<?xml version="1.0" encoding="utf-8" standalone="no"?>
<device schemaVersion="1.1">
  <name>STM32G471VET7</name>
  <version>1.0</version>
  <description>STM32G471CCT6,STM32G471CCU3,STM32G471CCU6,STM32G471CCU7,STM32G471CET3,STM32G471CET6,STM32G471CET7,STM32G471CEU3,STM32G471CEU6,STM32G471CEU7,STM32G471MCT6,STM32G471MET3,STM32G471MET6,STM32G471MET7,STM32G471MEY6,STM32G471QCT6,STM32G471QET6,STM32G471RCT6,STM32G471RET3,STM32G471RET6,STM32G471RET7,STM32G471VCH6,STM32G471VCI6,STM32G471VCT6,STM32G471VEH3,STM32G471VEH6,STM32G471VEH7,STM32G471VEI3,STM32G471VEI6,STM32G471VEI7,STM32G471VET3,STM32G471VET6,STM32G471VET7</description>
  <addressUnitBits>8</addressUnitBits>
  <width>32</width>
  <size>0x20</size>
  <resetValue>0</resetValue>
  <resetMask>0xFFFFFFFF</resetMask>
  <peripherals>
    <peripheral>
      <name>TIM2</name>
      <baseAddress>0x40000000</baseAddress>
      <registers>
        <register>
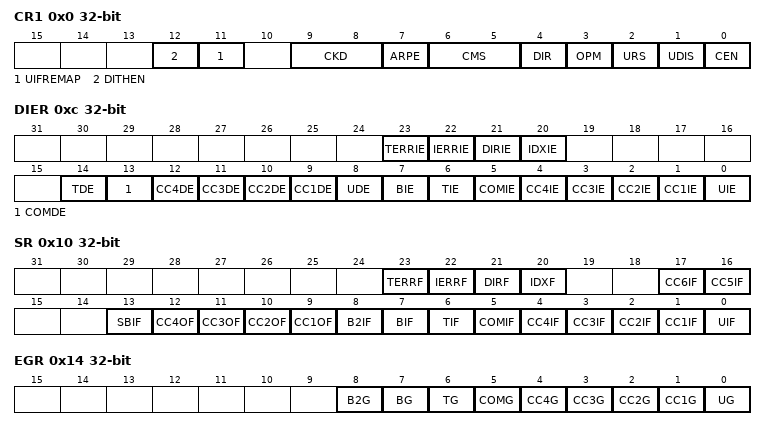
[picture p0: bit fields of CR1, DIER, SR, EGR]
          <name>CR1</name>
          <addressOffset>0x0</addressOffset>
          <size>0x20</size>
          <fields>
            <field>
              <name>CEN</name>
              <bitOffset>0</bitOffset>
              <bitWidth>1</bitWidth>
            </field>
            <field>
              <name>UDIS</name>
              <bitOffset>1</bitOffset>
              <bitWidth>1</bitWidth>
            </field>
            <field>
              <name>URS</name>
              <bitOffset>2</bitOffset>
              <bitWidth>1</bitWidth>
            </field>
            <field>
              <name>OPM</name>
              <bitOffset>3</bitOffset>
              <bitWidth>1</bitWidth>
            </field>
            <field>
              <name>DIR</name>
              <bitOffset>4</bitOffset>
              <bitWidth>1</bitWidth>
            </field>
            <field>
              <name>CMS</name>
              <bitOffset>5</bitOffset>
              <bitWidth>2</bitWidth>
            </field>
            <field>
              <name>ARPE</name>
              <bitOffset>7</bitOffset>
              <bitWidth>1</bitWidth>
            </field>
            <field>
              <name>CKD</name>
              <bitOffset>8</bitOffset>
              <bitWidth>2</bitWidth>
            </field>
            <field>
              <name>UIFREMAP</name>
              <bitOffset>11</bitOffset>
              <bitWidth>1</bitWidth>
            </field>
            <field>
              <name>DITHEN</name>
              <bitOffset>12</bitOffset>
              <bitWidth>1</bitWidth>
            </field>
          </fields>
        </register>
        <register>
          <name>CR2</name>
          <addressOffset>0x4</addressOffset>
          <size>0x20</size>
          <fields>
            <field>
              <name>CCPC</name>
              <bitOffset>0</bitOffset>
              <bitWidth>1</bitWidth>
            </field>
            <field>
              <name>CCUS</name>
              <bitOffset>2</bitOffset>
              <bitWidth>1</bitWidth>
            </field>
            <field>
              <name>CCDS</name>
              <bitOffset>3</bitOffset>
              <bitWidth>1</bitWidth>
            </field>
            <field>
              <name>MMS</name>
              <bitOffset>4</bitOffset>
              <bitWidth>22</bitWidth>
            </field>
            <field>
              <name>TI1S</name>
              <bitOffset>7</bitOffset>
              <bitWidth>1</bitWidth>
            </field>
            <field>
              <name>OIS1</name>
              <bitOffset>8</bitOffset>
              <bitWidth>1</bitWidth>
            </field>
            <field>
              <name>OIS1N</name>
              <bitOffset>9</bitOffset>
              <bitWidth>1</bitWidth>
            </field>
            <field>
              <name>OIS2</name>
              <bitOffset>10</bitOffset>
              <bitWidth>1</bitWidth>
            </field>
            <field>
              <name>OIS2N</name>
              <bitOffset>11</bitOffset>
              <bitWidth>1</bitWidth>
            </field>
            <field>
              <name>OIS3</name>
              <bitOffset>12</bitOffset>
              <bitWidth>1</bitWidth>
            </field>
            <field>
              <name>OIS3N</name>
              <bitOffset>13</bitOffset>
              <bitWidth>1</bitWidth>
            </field>
            <field>
              <name>OIS4</name>
              <bitOffset>14</bitOffset>
              <bitWidth>1</bitWidth>
            </field>
            <field>
              <name>OIS4N</name>
              <bitOffset>15</bitOffset>
              <bitWidth>1</bitWidth>
            </field>
            <field>
              <name>OIS5</name>
              <bitOffset>16</bitOffset>
              <bitWidth>1</bitWidth>
            </field>
            <field>
              <name>OIS6</name>
              <bitOffset>18</bitOffset>
              <bitWidth>1</bitWidth>
            </field>
            <field>
              <name>MMS2</name>
              <bitOffset>20</bitOffset>
              <bitWidth>4</bitWidth>
            </field>
          </fields>
        </register>
        <register>
          <name>SMCR</name>
          <addressOffset>0x8</addressOffset>
          <size>0x20</size>
          <fields>
            <field>
              <name>SMS</name>
              <bitOffset>0</bitOffset>
              <bitWidth>17</bitWidth>
            </field>
            <field>
              <name>OCCS</name>
              <bitOffset>3</bitOffset>
              <bitWidth>1</bitWidth>
            </field>
            <field>
              <name>TS</name>
              <bitOffset>4</bitOffset>
              <bitWidth>18</bitWidth>
            </field>
            <field>
              <name>MSM</name>
              <bitOffset>7</bitOffset>
              <bitWidth>1</bitWidth>
            </field>
            <field>
              <name>ETF</name>
              <bitOffset>8</bitOffset>
              <bitWidth>4</bitWidth>
            </field>
            <field>
              <name>ETPS</name>
              <bitOffset>12</bitOffset>
              <bitWidth>2</bitWidth>
            </field>
            <field>
              <name>ECE</name>
              <bitOffset>14</bitOffset>
              <bitWidth>1</bitWidth>
            </field>
            <field>
              <name>ETP</name>
              <bitOffset>15</bitOffset>
              <bitWidth>1</bitWidth>
            </field>
            <field>
              <name>SMSPE</name>
              <bitOffset>24</bitOffset>
              <bitWidth>1</bitWidth>
            </field>
            <field>
              <name>SMSPS</name>
              <bitOffset>25</bitOffset>
              <bitWidth>1</bitWidth>
            </field>
          </fields>
        </register>
        <register>
          <name>DIER</name>
          <addressOffset>0xc</addressOffset>
          <size>0x20</size>
          <fields>
            <field>
              <name>UIE</name>
              <bitOffset>0</bitOffset>
              <bitWidth>1</bitWidth>
            </field>
            <field>
              <name>CC1IE</name>
              <bitOffset>1</bitOffset>
              <bitWidth>1</bitWidth>
            </field>
            <field>
              <name>CC2IE</name>
              <bitOffset>2</bitOffset>
              <bitWidth>1</bitWidth>
            </field>
            <field>
              <name>CC3IE</name>
              <bitOffset>3</bitOffset>
              <bitWidth>1</bitWidth>
            </field>
            <field>
              <name>CC4IE</name>
              <bitOffset>4</bitOffset>
              <bitWidth>1</bitWidth>
            </field>
            <field>
              <name>COMIE</name>
              <bitOffset>5</bitOffset>
              <bitWidth>1</bitWidth>
            </field>
            <field>
              <name>TIE</name>
              <bitOffset>6</bitOffset>
              <bitWidth>1</bitWidth>
            </field>
            <field>
              <name>BIE</name>
              <bitOffset>7</bitOffset>
              <bitWidth>1</bitWidth>
            </field>
            <field>
              <name>UDE</name>
              <bitOffset>8</bitOffset>
              <bitWidth>1</bitWidth>
            </field>
            <field>
              <name>CC1DE</name>
              <bitOffset>9</bitOffset>
              <bitWidth>1</bitWidth>
            </field>
            <field>
              <name>CC2DE</name>
              <bitOffset>10</bitOffset>
              <bitWidth>1</bitWidth>
            </field>
            <field>
              <name>CC3DE</name>
              <bitOffset>11</bitOffset>
              <bitWidth>1</bitWidth>
            </field>
            <field>
              <name>CC4DE</name>
              <bitOffset>12</bitOffset>
              <bitWidth>1</bitWidth>
            </field>
            <field>
              <name>COMDE</name>
              <bitOffset>13</bitOffset>
              <bitWidth>1</bitWidth>
            </field>
            <field>
              <name>TDE</name>
              <bitOffset>14</bitOffset>
              <bitWidth>1</bitWidth>
            </field>
            <field>
              <name>IDXIE</name>
              <bitOffset>20</bitOffset>
              <bitWidth>1</bitWidth>
            </field>
            <field>
              <name>DIRIE</name>
              <bitOffset>21</bitOffset>
              <bitWidth>1</bitWidth>
            </field>
            <field>
              <name>IERRIE</name>
              <bitOffset>22</bitOffset>
              <bitWidth>1</bitWidth>
            </field>
            <field>
              <name>TERRIE</name>
              <bitOffset>23</bitOffset>
              <bitWidth>1</bitWidth>
            </field>
          </fields>
        </register>
        <register>
          <name>SR</name>
          <addressOffset>0x10</addressOffset>
          <size>0x20</size>
          <fields>
            <field>
              <name>UIF</name>
              <bitOffset>0</bitOffset>
              <bitWidth>1</bitWidth>
            </field>
            <field>
              <name>CC1IF</name>
              <bitOffset>1</bitOffset>
              <bitWidth>1</bitWidth>
            </field>
            <field>
              <name>CC2IF</name>
              <bitOffset>2</bitOffset>
              <bitWidth>1</bitWidth>
            </field>
            <field>
              <name>CC3IF</name>
              <bitOffset>3</bitOffset>
              <bitWidth>1</bitWidth>
            </field>
            <field>
              <name>CC4IF</name>
              <bitOffset>4</bitOffset>
              <bitWidth>1</bitWidth>
            </field>
            <field>
              <name>COMIF</name>
              <bitOffset>5</bitOffset>
              <bitWidth>1</bitWidth>
            </field>
            <field>
              <name>TIF</name>
              <bitOffset>6</bitOffset>
              <bitWidth>1</bitWidth>
            </field>
            <field>
              <name>BIF</name>
              <bitOffset>7</bitOffset>
              <bitWidth>1</bitWidth>
            </field>
            <field>
              <name>B2IF</name>
              <bitOffset>8</bitOffset>
              <bitWidth>1</bitWidth>
            </field>
            <field>
              <name>CC1OF</name>
              <bitOffset>9</bitOffset>
              <bitWidth>1</bitWidth>
            </field>
            <field>
              <name>CC2OF</name>
              <bitOffset>10</bitOffset>
              <bitWidth>1</bitWidth>
            </field>
            <field>
              <name>CC3OF</name>
              <bitOffset>11</bitOffset>
              <bitWidth>1</bitWidth>
            </field>
            <field>
              <name>CC4OF</name>
              <bitOffset>12</bitOffset>
              <bitWidth>1</bitWidth>
            </field>
            <field>
              <name>SBIF</name>
              <bitOffset>13</bitOffset>
              <bitWidth>1</bitWidth>
            </field>
            <field>
              <name>CC5IF</name>
              <bitOffset>16</bitOffset>
              <bitWidth>1</bitWidth>
            </field>
            <field>
              <name>CC6IF</name>
              <bitOffset>17</bitOffset>
              <bitWidth>1</bitWidth>
            </field>
            <field>
              <name>IDXF</name>
              <bitOffset>20</bitOffset>
              <bitWidth>1</bitWidth>
            </field>
            <field>
              <name>DIRF</name>
              <bitOffset>21</bitOffset>
              <bitWidth>1</bitWidth>
            </field>
            <field>
              <name>IERRF</name>
              <bitOffset>22</bitOffset>
              <bitWidth>1</bitWidth>
            </field>
            <field>
              <name>TERRF</name>
              <bitOffset>23</bitOffset>
              <bitWidth>1</bitWidth>
            </field>
          </fields>
        </register>
        <register>
          <name>EGR</name>
          <addressOffset>0x14</addressOffset>
          <size>0x20</size>
          <fields>
            <field>
              <name>UG</name>
              <bitOffset>0</bitOffset>
              <bitWidth>1</bitWidth>
            </field>
            <field>
              <name>CC1G</name>
              <bitOffset>1</bitOffset>
              <bitWidth>1</bitWidth>
            </field>
            <field>
              <name>CC2G</name>
              <bitOffset>2</bitOffset>
              <bitWidth>1</bitWidth>
            </field>
            <field>
              <name>CC3G</name>
              <bitOffset>3</bitOffset>
              <bitWidth>1</bitWidth>
            </field>
            <field>
              <name>CC4G</name>
              <bitOffset>4</bitOffset>
              <bitWidth>1</bitWidth>
            </field>
            <field>
              <name>COMG</name>
              <bitOffset>5</bitOffset>
              <bitWidth>1</bitWidth>
            </field>
            <field>
              <name>TG</name>
              <bitOffset>6</bitOffset>
              <bitWidth>1</bitWidth>
            </field>
            <field>
              <name>BG</name>
              <bitOffset>7</bitOffset>
              <bitWidth>1</bitWidth>
            </field>
            <field>
              <name>B2G</name>
              <bitOffset>8</bitOffset>
              <bitWidth>1</bitWidth>
            </field>
          </fields>
        </register>
        <register>
          <name>CCMR1</name>
          <addressOffset>0x18</addressOffset>
          <size>0x20</size>
          <fields>
            <field>
              <name>CC1S</name>
              <bitOffset>0</bitOffset>
              <bitWidth>2</bitWidth>
            </field>
            <field>
              <name>OC1FE</name>
              <bitOffset>2</bitOffset>
              <bitWidth>1</bitWidth>
            </field>
            <field>
              <name>OC1PE</name>
              <bitOffset>3</bitOffset>
              <bitWidth>1</bitWidth>
            </field>
            <field>
              <name>OC1M</name>
              <bitOffset>4</bitOffset>
              <bitWidth>13</bitWidth>
            </field>
            <field>
              <name>OC1CE</name>
              <bitOffset>7</bitOffset>
              <bitWidth>1</bitWidth>
            </field>
            <field>
              <name>CC2S</name>
              <bitOffset>8</bitOffset>
              <bitWidth>2</bitWidth>
            </field>
            <field>
              <name>OC2FE</name>
              <bitOffset>10</bitOffset>
              <bitWidth>1</bitWidth>
            </field>
            <field>
              <name>OC2PE</name>
              <bitOffset>11</bitOffset>
              <bitWidth>1</bitWidth>
            </field>
            <field>
              <name>OC2M</name>
              <bitOffset>12</bitOffset>
              <bitWidth>13</bitWidth>
            </field>
            <field>
              <name>OC2CE</name>
              <bitOffset>15</bitOffset>
              <bitWidth>1</bitWidth>
            </field>
          </fields>
        </register>
        <register>
          <name>CCMR2</name>
          <addressOffset>0x1c</addressOffset>
          <size>0x20</size>
          <fields>
            <field>
              <name>CC3S</name>
              <bitOffset>0</bitOffset>
              <bitWidth>2</bitWidth>
            </field>
            <field>
              <name>OC3FE</name>
              <bitOffset>2</bitOffset>
              <bitWidth>1</bitWidth>
            </field>
            <field>
              <name>OC3PE</name>
              <bitOffset>3</bitOffset>
              <bitWidth>1</bitWidth>
            </field>
            <field>
              <name>OC3M</name>
              <bitOffset>4</bitOffset>
              <bitWidth>13</bitWidth>
            </field>
            <field>
              <name>OC3CE</name>
              <bitOffset>7</bitOffset>
              <bitWidth>1</bitWidth>
            </field>
            <field>
              <name>CC4S</name>
              <bitOffset>8</bitOffset>
              <bitWidth>2</bitWidth>
            </field>
            <field>
              <name>OC4FE</name>
              <bitOffset>10</bitOffset>
              <bitWidth>1</bitWidth>
            </field>
            <field>
              <name>OC4PE</name>
              <bitOffset>11</bitOffset>
              <bitWidth>1</bitWidth>
            </field>
            <field>
              <name>OC4M</name>
              <bitOffset>12</bitOffset>
              <bitWidth>13</bitWidth>
            </field>
            <field>
              <name>OC4CE</name>
              <bitOffset>15</bitOffset>
              <bitWidth>1</bitWidth>
            </field>
          </fields>
        </register>
        <register>
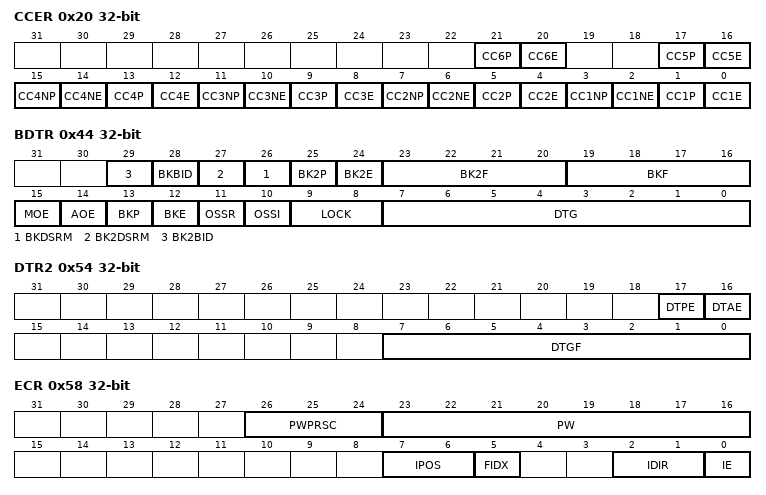
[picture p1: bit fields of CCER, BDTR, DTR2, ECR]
          <name>CCER</name>
          <addressOffset>0x20</addressOffset>
          <size>0x20</size>
          <fields>
            <field>
              <name>CC1E</name>
              <bitOffset>0</bitOffset>
              <bitWidth>1</bitWidth>
            </field>
            <field>
              <name>CC1P</name>
              <bitOffset>1</bitOffset>
              <bitWidth>1</bitWidth>
            </field>
            <field>
              <name>CC1NE</name>
              <bitOffset>2</bitOffset>
              <bitWidth>1</bitWidth>
            </field>
            <field>
              <name>CC1NP</name>
              <bitOffset>3</bitOffset>
              <bitWidth>1</bitWidth>
            </field>
            <field>
              <name>CC2E</name>
              <bitOffset>4</bitOffset>
              <bitWidth>1</bitWidth>
            </field>
            <field>
              <name>CC2P</name>
              <bitOffset>5</bitOffset>
              <bitWidth>1</bitWidth>
            </field>
            <field>
              <name>CC2NE</name>
              <bitOffset>6</bitOffset>
              <bitWidth>1</bitWidth>
            </field>
            <field>
              <name>CC2NP</name>
              <bitOffset>7</bitOffset>
              <bitWidth>1</bitWidth>
            </field>
            <field>
              <name>CC3E</name>
              <bitOffset>8</bitOffset>
              <bitWidth>1</bitWidth>
            </field>
            <field>
              <name>CC3P</name>
              <bitOffset>9</bitOffset>
              <bitWidth>1</bitWidth>
            </field>
            <field>
              <name>CC3NE</name>
              <bitOffset>10</bitOffset>
              <bitWidth>1</bitWidth>
            </field>
            <field>
              <name>CC3NP</name>
              <bitOffset>11</bitOffset>
              <bitWidth>1</bitWidth>
            </field>
            <field>
              <name>CC4E</name>
              <bitOffset>12</bitOffset>
              <bitWidth>1</bitWidth>
            </field>
            <field>
              <name>CC4P</name>
              <bitOffset>13</bitOffset>
              <bitWidth>1</bitWidth>
            </field>
            <field>
              <name>CC4NE</name>
              <bitOffset>14</bitOffset>
              <bitWidth>1</bitWidth>
            </field>
            <field>
              <name>CC4NP</name>
              <bitOffset>15</bitOffset>
              <bitWidth>1</bitWidth>
            </field>
            <field>
              <name>CC5E</name>
              <bitOffset>16</bitOffset>
              <bitWidth>1</bitWidth>
            </field>
            <field>
              <name>CC5P</name>
              <bitOffset>17</bitOffset>
              <bitWidth>1</bitWidth>
            </field>
            <field>
              <name>CC6E</name>
              <bitOffset>20</bitOffset>
              <bitWidth>1</bitWidth>
            </field>
            <field>
              <name>CC6P</name>
              <bitOffset>21</bitOffset>
              <bitWidth>1</bitWidth>
            </field>
          </fields>
        </register>
        <register>
          <name>CNT</name>
          <addressOffset>0x24</addressOffset>
          <size>0x20</size>
          <fields>
            <field>
              <name>CNT</name>
              <bitOffset>0</bitOffset>
              <bitWidth>32</bitWidth>
            </field>
            <field>
              <name>UIFCPY</name>
              <bitOffset>31</bitOffset>
              <bitWidth>1</bitWidth>
            </field>
          </fields>
        </register>
        <register>
          <name>PSC</name>
          <addressOffset>0x28</addressOffset>
          <size>0x20</size>
          <fields>
            <field>
              <name>PSC</name>
              <bitOffset>0</bitOffset>
              <bitWidth>16</bitWidth>
            </field>
          </fields>
        </register>
        <register>
          <name>ARR</name>
          <addressOffset>0x2c</addressOffset>
          <size>0x20</size>
          <fields>
            <field>
              <name>ARR</name>
              <bitOffset>0</bitOffset>
              <bitWidth>32</bitWidth>
            </field>
          </fields>
        </register>
        <register>
          <name>RCR</name>
          <addressOffset>0x30</addressOffset>
          <size>0x20</size>
          <fields>
            <field>
              <name>REP</name>
              <bitOffset>0</bitOffset>
              <bitWidth>16</bitWidth>
            </field>
          </fields>
        </register>
        <register>
          <name>CCR1</name>
          <addressOffset>0x34</addressOffset>
          <size>0x20</size>
          <fields>
            <field>
              <name>CCR1</name>
              <bitOffset>0</bitOffset>
              <bitWidth>16</bitWidth>
            </field>
          </fields>
        </register>
        <register>
          <name>CCR2</name>
          <addressOffset>0x38</addressOffset>
          <size>0x20</size>
          <fields>
            <field>
              <name>CCR2</name>
              <bitOffset>0</bitOffset>
              <bitWidth>16</bitWidth>
            </field>
          </fields>
        </register>
        <register>
          <name>CCR3</name>
          <addressOffset>0x3c</addressOffset>
          <size>0x20</size>
          <fields>
            <field>
              <name>CCR3</name>
              <bitOffset>0</bitOffset>
              <bitWidth>16</bitWidth>
            </field>
          </fields>
        </register>
        <register>
          <name>CCR4</name>
          <addressOffset>0x40</addressOffset>
          <size>0x20</size>
          <fields>
            <field>
              <name>CCR4</name>
              <bitOffset>0</bitOffset>
              <bitWidth>16</bitWidth>
            </field>
          </fields>
        </register>
        <register>
          <name>BDTR</name>
          <addressOffset>0x44</addressOffset>
          <size>0x20</size>
          <fields>
            <field>
              <name>DTG</name>
              <bitOffset>0</bitOffset>
              <bitWidth>8</bitWidth>
            </field>
            <field>
              <name>LOCK</name>
              <bitOffset>8</bitOffset>
              <bitWidth>2</bitWidth>
            </field>
            <field>
              <name>OSSI</name>
              <bitOffset>10</bitOffset>
              <bitWidth>1</bitWidth>
            </field>
            <field>
              <name>OSSR</name>
              <bitOffset>11</bitOffset>
              <bitWidth>1</bitWidth>
            </field>
            <field>
              <name>BKE</name>
              <bitOffset>12</bitOffset>
              <bitWidth>1</bitWidth>
            </field>
            <field>
              <name>BKP</name>
              <bitOffset>13</bitOffset>
              <bitWidth>1</bitWidth>
            </field>
            <field>
              <name>AOE</name>
              <bitOffset>14</bitOffset>
              <bitWidth>1</bitWidth>
            </field>
            <field>
              <name>MOE</name>
              <bitOffset>15</bitOffset>
              <bitWidth>1</bitWidth>
            </field>
            <field>
              <name>BKF</name>
              <bitOffset>16</bitOffset>
              <bitWidth>4</bitWidth>
            </field>
            <field>
              <name>BK2F</name>
              <bitOffset>20</bitOffset>
              <bitWidth>4</bitWidth>
            </field>
            <field>
              <name>BK2E</name>
              <bitOffset>24</bitOffset>
              <bitWidth>1</bitWidth>
            </field>
            <field>
              <name>BK2P</name>
              <bitOffset>25</bitOffset>
              <bitWidth>1</bitWidth>
            </field>
            <field>
              <name>BKDSRM</name>
              <bitOffset>26</bitOffset>
              <bitWidth>1</bitWidth>
            </field>
            <field>
              <name>BK2DSRM</name>
              <bitOffset>27</bitOffset>
              <bitWidth>1</bitWidth>
            </field>
            <field>
              <name>BKBID</name>
              <bitOffset>28</bitOffset>
              <bitWidth>1</bitWidth>
            </field>
            <field>
              <name>BK2BID</name>
              <bitOffset>29</bitOffset>
              <bitWidth>1</bitWidth>
            </field>
          </fields>
        </register>
        <register>
          <name>CCR5</name>
          <addressOffset>0x48</addressOffset>
          <size>0x20</size>
          <fields>
            <field>
              <name>CCR5</name>
              <bitOffset>0</bitOffset>
              <bitWidth>32</bitWidth>
            </field>
            <field>
              <name>GC5C1</name>
              <bitOffset>29</bitOffset>
              <bitWidth>1</bitWidth>
            </field>
            <field>
              <name>GC5C2</name>
              <bitOffset>30</bitOffset>
              <bitWidth>1</bitWidth>
            </field>
            <field>
              <name>GC5C3</name>
              <bitOffset>31</bitOffset>
              <bitWidth>1</bitWidth>
            </field>
          </fields>
        </register>
        <register>
          <name>CCR6</name>
          <addressOffset>0x4c</addressOffset>
          <size>0x20</size>
          <fields>
            <field>
              <name>CCR6</name>
              <bitOffset>0</bitOffset>
              <bitWidth>16</bitWidth>
            </field>
          </fields>
        </register>
        <register>
          <name>CCMR3</name>
          <addressOffset>0x50</addressOffset>
          <size>0x20</size>
          <fields>
            <field>
              <name>OC5FE</name>
              <bitOffset>2</bitOffset>
              <bitWidth>1</bitWidth>
            </field>
            <field>
              <name>OC5PE</name>
              <bitOffset>3</bitOffset>
              <bitWidth>1</bitWidth>
            </field>
            <field>
              <name>OC5M</name>
              <bitOffset>4</bitOffset>
              <bitWidth>13</bitWidth>
            </field>
            <field>
              <name>OC5CE</name>
              <bitOffset>7</bitOffset>
              <bitWidth>1</bitWidth>
            </field>
            <field>
              <name>OC6FE</name>
              <bitOffset>10</bitOffset>
              <bitWidth>1</bitWidth>
            </field>
            <field>
              <name>OC6PE</name>
              <bitOffset>11</bitOffset>
              <bitWidth>1</bitWidth>
            </field>
            <field>
              <name>OC6M</name>
              <bitOffset>12</bitOffset>
              <bitWidth>13</bitWidth>
            </field>
            <field>
              <name>OC6CE</name>
              <bitOffset>15</bitOffset>
              <bitWidth>1</bitWidth>
            </field>
          </fields>
        </register>
        <register>
          <name>DTR2</name>
          <addressOffset>0x54</addressOffset>
          <size>0x20</size>
          <fields>
            <field>
              <name>DTGF</name>
              <bitOffset>0</bitOffset>
              <bitWidth>8</bitWidth>
            </field>
            <field>
              <name>DTAE</name>
              <bitOffset>16</bitOffset>
              <bitWidth>1</bitWidth>
            </field>
            <field>
              <name>DTPE</name>
              <bitOffset>17</bitOffset>
              <bitWidth>1</bitWidth>
            </field>
          </fields>
        </register>
        <register>
          <name>ECR</name>
          <addressOffset>0x58</addressOffset>
          <size>0x20</size>
          <fields>
            <field>
              <name>IE</name>
              <bitOffset>0</bitOffset>
              <bitWidth>1</bitWidth>
            </field>
            <field>
              <name>IDIR</name>
              <bitOffset>1</bitOffset>
              <bitWidth>2</bitWidth>
            </field>
            <field>
              <name>FIDX</name>
              <bitOffset>5</bitOffset>
              <bitWidth>1</bitWidth>
            </field>
            <field>
              <name>IPOS</name>
              <bitOffset>6</bitOffset>
              <bitWidth>2</bitWidth>
            </field>
            <field>
              <name>PW</name>
              <bitOffset>16</bitOffset>
              <bitWidth>8</bitWidth>
            </field>
            <field>
              <name>PWPRSC</name>
              <bitOffset>24</bitOffset>
              <bitWidth>3</bitWidth>
            </field>
          </fields>
        </register>
        <register>
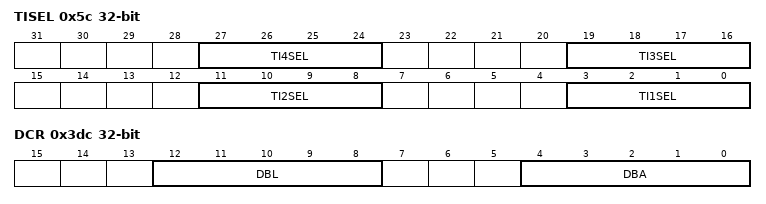
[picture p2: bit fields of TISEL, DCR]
          <name>TISEL</name>
          <addressOffset>0x5c</addressOffset>
          <size>0x20</size>
          <fields>
            <field>
              <name>TI1SEL</name>
              <bitOffset>0</bitOffset>
              <bitWidth>4</bitWidth>
            </field>
            <field>
              <name>TI2SEL</name>
              <bitOffset>8</bitOffset>
              <bitWidth>4</bitWidth>
            </field>
            <field>
              <name>TI3SEL</name>
              <bitOffset>16</bitOffset>
              <bitWidth>4</bitWidth>
            </field>
            <field>
              <name>TI4SEL</name>
              <bitOffset>24</bitOffset>
              <bitWidth>4</bitWidth>
            </field>
          </fields>
        </register>
        <register>
          <name>AF1</name>
          <addressOffset>0x60</addressOffset>
          <size>0x20</size>
        </register>
        <register>
          <name>AF2</name>
          <addressOffset>0x64</addressOffset>
          <size>0x20</size>
        </register>
        <register>
          <name>OR</name>
          <addressOffset>0x68</addressOffset>
          <size>0x20</size>
          <fields>
            <field>
              <name>HSE32EN</name>
              <bitOffset>0</bitOffset>
              <bitWidth>1</bitWidth>
            </field>
          </fields>
        </register>
        <register>
          <name>DCR</name>
          <addressOffset>0x3dc</addressOffset>
          <size>0x20</size>
          <fields>
            <field>
              <name>DBA</name>
              <bitOffset>0</bitOffset>
              <bitWidth>5</bitWidth>
            </field>
            <field>
              <name>DBL</name>
              <bitOffset>8</bitOffset>
              <bitWidth>5</bitWidth>
            </field>
          </fields>
        </register>
        <register>
          <name>DMAR</name>
          <addressOffset>0x3e0</addressOffset>
          <size>0x20</size>
          <fields>
            <field>
              <name>DMAB</name>
              <bitOffset>0</bitOffset>
              <bitWidth>32</bitWidth>
            </field>
          </fields>
        </register>
      </registers>
    </peripheral>
    <peripheral>
      <name>TIM3</name>
      <baseAddress>0x40000400</baseAddress>
      <registers>
        <register>
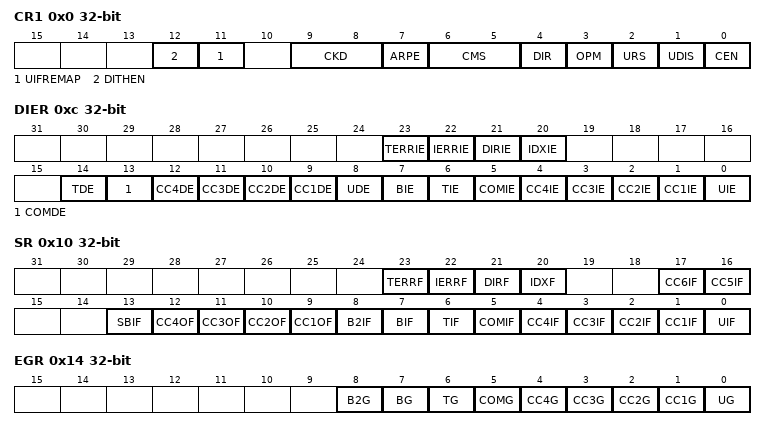
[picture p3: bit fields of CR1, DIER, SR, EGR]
          <name>CR1</name>
          <addressOffset>0x0</addressOffset>
          <size>0x20</size>
          <fields>
            <field>
              <name>CEN</name>
              <bitOffset>0</bitOffset>
              <bitWidth>1</bitWidth>
            </field>
            <field>
              <name>UDIS</name>
              <bitOffset>1</bitOffset>
              <bitWidth>1</bitWidth>
            </field>
            <field>
              <name>URS</name>
              <bitOffset>2</bitOffset>
              <bitWidth>1</bitWidth>
            </field>
            <field>
              <name>OPM</name>
              <bitOffset>3</bitOffset>
              <bitWidth>1</bitWidth>
            </field>
            <field>
              <name>DIR</name>
              <bitOffset>4</bitOffset>
              <bitWidth>1</bitWidth>
            </field>
            <field>
              <name>CMS</name>
              <bitOffset>5</bitOffset>
              <bitWidth>2</bitWidth>
            </field>
            <field>
              <name>ARPE</name>
              <bitOffset>7</bitOffset>
              <bitWidth>1</bitWidth>
            </field>
            <field>
              <name>CKD</name>
              <bitOffset>8</bitOffset>
              <bitWidth>2</bitWidth>
            </field>
            <field>
              <name>UIFREMAP</name>
              <bitOffset>11</bitOffset>
              <bitWidth>1</bitWidth>
            </field>
            <field>
              <name>DITHEN</name>
              <bitOffset>12</bitOffset>
              <bitWidth>1</bitWidth>
            </field>
          </fields>
        </register>
        <register>
          <name>CR2</name>
          <addressOffset>0x4</addressOffset>
          <size>0x20</size>
          <fields>
            <field>
              <name>CCPC</name>
              <bitOffset>0</bitOffset>
              <bitWidth>1</bitWidth>
            </field>
            <field>
              <name>CCUS</name>
              <bitOffset>2</bitOffset>
              <bitWidth>1</bitWidth>
            </field>
            <field>
              <name>CCDS</name>
              <bitOffset>3</bitOffset>
              <bitWidth>1</bitWidth>
            </field>
            <field>
              <name>MMS</name>
              <bitOffset>4</bitOffset>
              <bitWidth>22</bitWidth>
            </field>
            <field>
              <name>TI1S</name>
              <bitOffset>7</bitOffset>
              <bitWidth>1</bitWidth>
            </field>
            <field>
              <name>OIS1</name>
              <bitOffset>8</bitOffset>
              <bitWidth>1</bitWidth>
            </field>
            <field>
              <name>OIS1N</name>
              <bitOffset>9</bitOffset>
              <bitWidth>1</bitWidth>
            </field>
            <field>
              <name>OIS2</name>
              <bitOffset>10</bitOffset>
              <bitWidth>1</bitWidth>
            </field>
            <field>
              <name>OIS2N</name>
              <bitOffset>11</bitOffset>
              <bitWidth>1</bitWidth>
            </field>
            <field>
              <name>OIS3</name>
              <bitOffset>12</bitOffset>
              <bitWidth>1</bitWidth>
            </field>
            <field>
              <name>OIS3N</name>
              <bitOffset>13</bitOffset>
              <bitWidth>1</bitWidth>
            </field>
            <field>
              <name>OIS4</name>
              <bitOffset>14</bitOffset>
              <bitWidth>1</bitWidth>
            </field>
            <field>
              <name>OIS4N</name>
              <bitOffset>15</bitOffset>
              <bitWidth>1</bitWidth>
            </field>
            <field>
              <name>OIS5</name>
              <bitOffset>16</bitOffset>
              <bitWidth>1</bitWidth>
            </field>
            <field>
              <name>OIS6</name>
              <bitOffset>18</bitOffset>
              <bitWidth>1</bitWidth>
            </field>
            <field>
              <name>MMS2</name>
              <bitOffset>20</bitOffset>
              <bitWidth>4</bitWidth>
            </field>
          </fields>
        </register>
        <register>
          <name>SMCR</name>
          <addressOffset>0x8</addressOffset>
          <size>0x20</size>
          <fields>
            <field>
              <name>SMS</name>
              <bitOffset>0</bitOffset>
              <bitWidth>17</bitWidth>
            </field>
            <field>
              <name>OCCS</name>
              <bitOffset>3</bitOffset>
              <bitWidth>1</bitWidth>
            </field>
            <field>
              <name>TS</name>
              <bitOffset>4</bitOffset>
              <bitWidth>18</bitWidth>
            </field>
            <field>
              <name>MSM</name>
              <bitOffset>7</bitOffset>
              <bitWidth>1</bitWidth>
            </field>
            <field>
              <name>ETF</name>
              <bitOffset>8</bitOffset>
              <bitWidth>4</bitWidth>
            </field>
            <field>
              <name>ETPS</name>
              <bitOffset>12</bitOffset>
              <bitWidth>2</bitWidth>
            </field>
            <field>
              <name>ECE</name>
              <bitOffset>14</bitOffset>
              <bitWidth>1</bitWidth>
            </field>
            <field>
              <name>ETP</name>
              <bitOffset>15</bitOffset>
              <bitWidth>1</bitWidth>
            </field>
            <field>
              <name>SMSPE</name>
              <bitOffset>24</bitOffset>
              <bitWidth>1</bitWidth>
            </field>
            <field>
              <name>SMSPS</name>
              <bitOffset>25</bitOffset>
              <bitWidth>1</bitWidth>
            </field>
          </fields>
        </register>
        <register>
          <name>DIER</name>
          <addressOffset>0xc</addressOffset>
          <size>0x20</size>
          <fields>
            <field>
              <name>UIE</name>
              <bitOffset>0</bitOffset>
              <bitWidth>1</bitWidth>
            </field>
            <field>
              <name>CC1IE</name>
              <bitOffset>1</bitOffset>
              <bitWidth>1</bitWidth>
            </field>
            <field>
              <name>CC2IE</name>
              <bitOffset>2</bitOffset>
              <bitWidth>1</bitWidth>
            </field>
            <field>
              <name>CC3IE</name>
              <bitOffset>3</bitOffset>
              <bitWidth>1</bitWidth>
            </field>
            <field>
              <name>CC4IE</name>
              <bitOffset>4</bitOffset>
              <bitWidth>1</bitWidth>
            </field>
            <field>
              <name>COMIE</name>
              <bitOffset>5</bitOffset>
              <bitWidth>1</bitWidth>
            </field>
            <field>
              <name>TIE</name>
              <bitOffset>6</bitOffset>
              <bitWidth>1</bitWidth>
            </field>
            <field>
              <name>BIE</name>
              <bitOffset>7</bitOffset>
              <bitWidth>1</bitWidth>
            </field>
            <field>
              <name>UDE</name>
              <bitOffset>8</bitOffset>
              <bitWidth>1</bitWidth>
            </field>
            <field>
              <name>CC1DE</name>
              <bitOffset>9</bitOffset>
              <bitWidth>1</bitWidth>
            </field>
            <field>
              <name>CC2DE</name>
              <bitOffset>10</bitOffset>
              <bitWidth>1</bitWidth>
            </field>
            <field>
              <name>CC3DE</name>
              <bitOffset>11</bitOffset>
              <bitWidth>1</bitWidth>
            </field>
            <field>
              <name>CC4DE</name>
              <bitOffset>12</bitOffset>
              <bitWidth>1</bitWidth>
            </field>
            <field>
              <name>COMDE</name>
              <bitOffset>13</bitOffset>
              <bitWidth>1</bitWidth>
            </field>
            <field>
              <name>TDE</name>
              <bitOffset>14</bitOffset>
              <bitWidth>1</bitWidth>
            </field>
            <field>
              <name>IDXIE</name>
              <bitOffset>20</bitOffset>
              <bitWidth>1</bitWidth>
            </field>
            <field>
              <name>DIRIE</name>
              <bitOffset>21</bitOffset>
              <bitWidth>1</bitWidth>
            </field>
            <field>
              <name>IERRIE</name>
              <bitOffset>22</bitOffset>
              <bitWidth>1</bitWidth>
            </field>
            <field>
              <name>TERRIE</name>
              <bitOffset>23</bitOffset>
              <bitWidth>1</bitWidth>
            </field>
          </fields>
        </register>
        <register>
          <name>SR</name>
          <addressOffset>0x10</addressOffset>
          <size>0x20</size>
          <fields>
            <field>
              <name>UIF</name>
              <bitOffset>0</bitOffset>
              <bitWidth>1</bitWidth>
            </field>
            <field>
              <name>CC1IF</name>
              <bitOffset>1</bitOffset>
              <bitWidth>1</bitWidth>
            </field>
            <field>
              <name>CC2IF</name>
              <bitOffset>2</bitOffset>
              <bitWidth>1</bitWidth>
            </field>
            <field>
              <name>CC3IF</name>
              <bitOffset>3</bitOffset>
              <bitWidth>1</bitWidth>
            </field>
            <field>
              <name>CC4IF</name>
              <bitOffset>4</bitOffset>
              <bitWidth>1</bitWidth>
            </field>
            <field>
              <name>COMIF</name>
              <bitOffset>5</bitOffset>
              <bitWidth>1</bitWidth>
            </field>
            <field>
              <name>TIF</name>
              <bitOffset>6</bitOffset>
              <bitWidth>1</bitWidth>
            </field>
            <field>
              <name>BIF</name>
              <bitOffset>7</bitOffset>
              <bitWidth>1</bitWidth>
            </field>
            <field>
              <name>B2IF</name>
              <bitOffset>8</bitOffset>
              <bitWidth>1</bitWidth>
            </field>
            <field>
              <name>CC1OF</name>
              <bitOffset>9</bitOffset>
              <bitWidth>1</bitWidth>
            </field>
            <field>
              <name>CC2OF</name>
              <bitOffset>10</bitOffset>
              <bitWidth>1</bitWidth>
            </field>
            <field>
              <name>CC3OF</name>
              <bitOffset>11</bitOffset>
              <bitWidth>1</bitWidth>
            </field>
            <field>
              <name>CC4OF</name>
              <bitOffset>12</bitOffset>
              <bitWidth>1</bitWidth>
            </field>
            <field>
              <name>SBIF</name>
              <bitOffset>13</bitOffset>
              <bitWidth>1</bitWidth>
            </field>
            <field>
              <name>CC5IF</name>
              <bitOffset>16</bitOffset>
              <bitWidth>1</bitWidth>
            </field>
            <field>
              <name>CC6IF</name>
              <bitOffset>17</bitOffset>
              <bitWidth>1</bitWidth>
            </field>
            <field>
              <name>IDXF</name>
              <bitOffset>20</bitOffset>
              <bitWidth>1</bitWidth>
            </field>
            <field>
              <name>DIRF</name>
              <bitOffset>21</bitOffset>
              <bitWidth>1</bitWidth>
            </field>
            <field>
              <name>IERRF</name>
              <bitOffset>22</bitOffset>
              <bitWidth>1</bitWidth>
            </field>
            <field>
              <name>TERRF</name>
              <bitOffset>23</bitOffset>
              <bitWidth>1</bitWidth>
            </field>
          </fields>
        </register>
        <register>
          <name>EGR</name>
          <addressOffset>0x14</addressOffset>
          <size>0x20</size>
          <fields>
            <field>
              <name>UG</name>
              <bitOffset>0</bitOffset>
              <bitWidth>1</bitWidth>
            </field>
            <field>
              <name>CC1G</name>
              <bitOffset>1</bitOffset>
              <bitWidth>1</bitWidth>
            </field>
            <field>
              <name>CC2G</name>
              <bitOffset>2</bitOffset>
              <bitWidth>1</bitWidth>
            </field>
            <field>
              <name>CC3G</name>
              <bitOffset>3</bitOffset>
              <bitWidth>1</bitWidth>
            </field>
            <field>
              <name>CC4G</name>
              <bitOffset>4</bitOffset>
              <bitWidth>1</bitWidth>
            </field>
            <field>
              <name>COMG</name>
              <bitOffset>5</bitOffset>
              <bitWidth>1</bitWidth>
            </field>
            <field>
              <name>TG</name>
              <bitOffset>6</bitOffset>
              <bitWidth>1</bitWidth>
            </field>
            <field>
              <name>BG</name>
              <bitOffset>7</bitOffset>
              <bitWidth>1</bitWidth>
            </field>
            <field>
              <name>B2G</name>
              <bitOffset>8</bitOffset>
              <bitWidth>1</bitWidth>
            </field>
          </fields>
        </register>
        <register>
          <name>CCMR1</name>
          <addressOffset>0x18</addressOffset>
          <size>0x20</size>
          <fields>
            <field>
              <name>CC1S</name>
              <bitOffset>0</bitOffset>
              <bitWidth>2</bitWidth>
            </field>
            <field>
              <name>OC1FE</name>
              <bitOffset>2</bitOffset>
              <bitWidth>1</bitWidth>
            </field>
            <field>
              <name>OC1PE</name>
              <bitOffset>3</bitOffset>
              <bitWidth>1</bitWidth>
            </field>
            <field>
              <name>OC1M</name>
              <bitOffset>4</bitOffset>
              <bitWidth>13</bitWidth>
            </field>
            <field>
              <name>OC1CE</name>
              <bitOffset>7</bitOffset>
              <bitWidth>1</bitWidth>
            </field>
            <field>
              <name>CC2S</name>
              <bitOffset>8</bitOffset>
              <bitWidth>2</bitWidth>
            </field>
            <field>
              <name>OC2FE</name>
              <bitOffset>10</bitOffset>
              <bitWidth>1</bitWidth>
            </field>
            <field>
              <name>OC2PE</name>
              <bitOffset>11</bitOffset>
              <bitWidth>1</bitWidth>
            </field>
            <field>
              <name>OC2M</name>
              <bitOffset>12</bitOffset>
              <bitWidth>13</bitWidth>
            </field>
            <field>
              <name>OC2CE</name>
              <bitOffset>15</bitOffset>
              <bitWidth>1</bitWidth>
            </field>
          </fields>
        </register>
        <register>
          <name>CCMR2</name>
          <addressOffset>0x1c</addressOffset>
          <size>0x20</size>
          <fields>
            <field>
              <name>CC3S</name>
              <bitOffset>0</bitOffset>
              <bitWidth>2</bitWidth>
            </field>
            <field>
              <name>OC3FE</name>
              <bitOffset>2</bitOffset>
              <bitWidth>1</bitWidth>
            </field>
            <field>
              <name>OC3PE</name>
              <bitOffset>3</bitOffset>
              <bitWidth>1</bitWidth>
            </field>
            <field>
              <name>OC3M</name>
              <bitOffset>4</bitOffset>
              <bitWidth>13</bitWidth>
            </field>
            <field>
              <name>OC3CE</name>
              <bitOffset>7</bitOffset>
              <bitWidth>1</bitWidth>
            </field>
            <field>
              <name>CC4S</name>
              <bitOffset>8</bitOffset>
              <bitWidth>2</bitWidth>
            </field>
            <field>
              <name>OC4FE</name>
              <bitOffset>10</bitOffset>
              <bitWidth>1</bitWidth>
            </field>
            <field>
              <name>OC4PE</name>
              <bitOffset>11</bitOffset>
              <bitWidth>1</bitWidth>
            </field>
            <field>
              <name>OC4M</name>
              <bitOffset>12</bitOffset>
              <bitWidth>13</bitWidth>
            </field>
            <field>
              <name>OC4CE</name>
              <bitOffset>15</bitOffset>
              <bitWidth>1</bitWidth>
            </field>
          </fields>
        </register>
        <register>
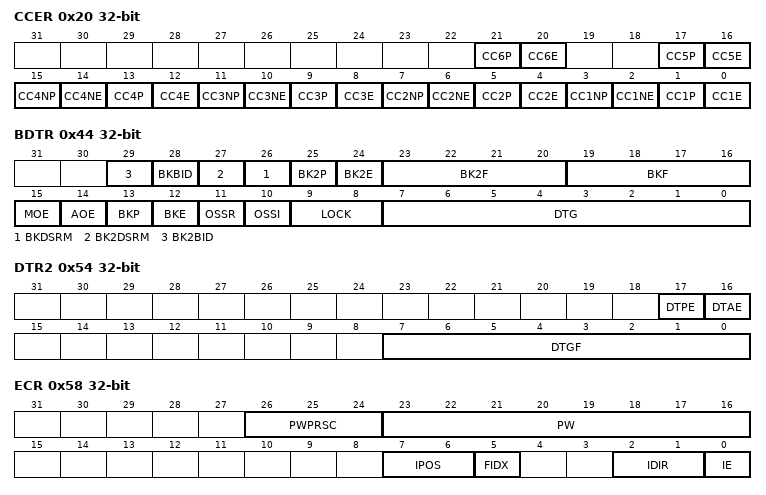
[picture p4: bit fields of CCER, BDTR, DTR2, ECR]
          <name>CCER</name>
          <addressOffset>0x20</addressOffset>
          <size>0x20</size>
          <fields>
            <field>
              <name>CC1E</name>
              <bitOffset>0</bitOffset>
              <bitWidth>1</bitWidth>
            </field>
            <field>
              <name>CC1P</name>
              <bitOffset>1</bitOffset>
              <bitWidth>1</bitWidth>
            </field>
            <field>
              <name>CC1NE</name>
              <bitOffset>2</bitOffset>
              <bitWidth>1</bitWidth>
            </field>
            <field>
              <name>CC1NP</name>
              <bitOffset>3</bitOffset>
              <bitWidth>1</bitWidth>
            </field>
            <field>
              <name>CC2E</name>
              <bitOffset>4</bitOffset>
              <bitWidth>1</bitWidth>
            </field>
            <field>
              <name>CC2P</name>
              <bitOffset>5</bitOffset>
              <bitWidth>1</bitWidth>
            </field>
            <field>
              <name>CC2NE</name>
              <bitOffset>6</bitOffset>
              <bitWidth>1</bitWidth>
            </field>
            <field>
              <name>CC2NP</name>
              <bitOffset>7</bitOffset>
              <bitWidth>1</bitWidth>
            </field>
            <field>
              <name>CC3E</name>
              <bitOffset>8</bitOffset>
              <bitWidth>1</bitWidth>
            </field>
            <field>
              <name>CC3P</name>
              <bitOffset>9</bitOffset>
              <bitWidth>1</bitWidth>
            </field>
            <field>
              <name>CC3NE</name>
              <bitOffset>10</bitOffset>
              <bitWidth>1</bitWidth>
            </field>
            <field>
              <name>CC3NP</name>
              <bitOffset>11</bitOffset>
              <bitWidth>1</bitWidth>
            </field>
            <field>
              <name>CC4E</name>
              <bitOffset>12</bitOffset>
              <bitWidth>1</bitWidth>
            </field>
            <field>
              <name>CC4P</name>
              <bitOffset>13</bitOffset>
              <bitWidth>1</bitWidth>
            </field>
            <field>
              <name>CC4NE</name>
              <bitOffset>14</bitOffset>
              <bitWidth>1</bitWidth>
            </field>
            <field>
              <name>CC4NP</name>
              <bitOffset>15</bitOffset>
              <bitWidth>1</bitWidth>
            </field>
            <field>
              <name>CC5E</name>
              <bitOffset>16</bitOffset>
              <bitWidth>1</bitWidth>
            </field>
            <field>
              <name>CC5P</name>
              <bitOffset>17</bitOffset>
              <bitWidth>1</bitWidth>
            </field>
            <field>
              <name>CC6E</name>
              <bitOffset>20</bitOffset>
              <bitWidth>1</bitWidth>
            </field>
            <field>
              <name>CC6P</name>
              <bitOffset>21</bitOffset>
              <bitWidth>1</bitWidth>
            </field>
          </fields>
        </register>
        <register>
          <name>CNT</name>
          <addressOffset>0x24</addressOffset>
          <size>0x20</size>
          <fields>
            <field>
              <name>CNT</name>
              <bitOffset>0</bitOffset>
              <bitWidth>32</bitWidth>
            </field>
            <field>
              <name>UIFCPY</name>
              <bitOffset>31</bitOffset>
              <bitWidth>1</bitWidth>
            </field>
          </fields>
        </register>
        <register>
          <name>PSC</name>
          <addressOffset>0x28</addressOffset>
          <size>0x20</size>
          <fields>
            <field>
              <name>PSC</name>
              <bitOffset>0</bitOffset>
              <bitWidth>16</bitWidth>
            </field>
          </fields>
        </register>
        <register>
          <name>ARR</name>
          <addressOffset>0x2c</addressOffset>
          <size>0x20</size>
          <fields>
            <field>
              <name>ARR</name>
              <bitOffset>0</bitOffset>
              <bitWidth>32</bitWidth>
            </field>
          </fields>
        </register>
        <register>
          <name>RCR</name>
          <addressOffset>0x30</addressOffset>
          <size>0x20</size>
          <fields>
            <field>
              <name>REP</name>
              <bitOffset>0</bitOffset>
              <bitWidth>16</bitWidth>
            </field>
          </fields>
        </register>
        <register>
          <name>CCR1</name>
          <addressOffset>0x34</addressOffset>
          <size>0x20</size>
          <fields>
            <field>
              <name>CCR1</name>
              <bitOffset>0</bitOffset>
              <bitWidth>16</bitWidth>
            </field>
          </fields>
        </register>
        <register>
          <name>CCR2</name>
          <addressOffset>0x38</addressOffset>
          <size>0x20</size>
          <fields>
            <field>
              <name>CCR2</name>
              <bitOffset>0</bitOffset>
              <bitWidth>16</bitWidth>
            </field>
          </fields>
        </register>
        <register>
          <name>CCR3</name>
          <addressOffset>0x3c</addressOffset>
          <size>0x20</size>
          <fields>
            <field>
              <name>CCR3</name>
              <bitOffset>0</bitOffset>
              <bitWidth>16</bitWidth>
            </field>
          </fields>
        </register>
        <register>
          <name>CCR4</name>
          <addressOffset>0x40</addressOffset>
          <size>0x20</size>
          <fields>
            <field>
              <name>CCR4</name>
              <bitOffset>0</bitOffset>
              <bitWidth>16</bitWidth>
            </field>
          </fields>
        </register>
        <register>
          <name>BDTR</name>
          <addressOffset>0x44</addressOffset>
          <size>0x20</size>
          <fields>
            <field>
              <name>DTG</name>
              <bitOffset>0</bitOffset>
              <bitWidth>8</bitWidth>
            </field>
            <field>
              <name>LOCK</name>
              <bitOffset>8</bitOffset>
              <bitWidth>2</bitWidth>
            </field>
            <field>
              <name>OSSI</name>
              <bitOffset>10</bitOffset>
              <bitWidth>1</bitWidth>
            </field>
            <field>
              <name>OSSR</name>
              <bitOffset>11</bitOffset>
              <bitWidth>1</bitWidth>
            </field>
            <field>
              <name>BKE</name>
              <bitOffset>12</bitOffset>
              <bitWidth>1</bitWidth>
            </field>
            <field>
              <name>BKP</name>
              <bitOffset>13</bitOffset>
              <bitWidth>1</bitWidth>
            </field>
            <field>
              <name>AOE</name>
              <bitOffset>14</bitOffset>
              <bitWidth>1</bitWidth>
            </field>
            <field>
              <name>MOE</name>
              <bitOffset>15</bitOffset>
              <bitWidth>1</bitWidth>
            </field>
            <field>
              <name>BKF</name>
              <bitOffset>16</bitOffset>
              <bitWidth>4</bitWidth>
            </field>
            <field>
              <name>BK2F</name>
              <bitOffset>20</bitOffset>
              <bitWidth>4</bitWidth>
            </field>
            <field>
              <name>BK2E</name>
              <bitOffset>24</bitOffset>
              <bitWidth>1</bitWidth>
            </field>
            <field>
              <name>BK2P</name>
              <bitOffset>25</bitOffset>
              <bitWidth>1</bitWidth>
            </field>
            <field>
              <name>BKDSRM</name>
              <bitOffset>26</bitOffset>
              <bitWidth>1</bitWidth>
            </field>
            <field>
              <name>BK2DSRM</name>
              <bitOffset>27</bitOffset>
              <bitWidth>1</bitWidth>
            </field>
            <field>
              <name>BKBID</name>
              <bitOffset>28</bitOffset>
              <bitWidth>1</bitWidth>
            </field>
            <field>
              <name>BK2BID</name>
              <bitOffset>29</bitOffset>
              <bitWidth>1</bitWidth>
            </field>
          </fields>
        </register>
        <register>
          <name>CCR5</name>
          <addressOffset>0x48</addressOffset>
          <size>0x20</size>
          <fields>
            <field>
              <name>CCR5</name>
              <bitOffset>0</bitOffset>
              <bitWidth>32</bitWidth>
            </field>
            <field>
              <name>GC5C1</name>
              <bitOffset>29</bitOffset>
              <bitWidth>1</bitWidth>
            </field>
            <field>
              <name>GC5C2</name>
              <bitOffset>30</bitOffset>
              <bitWidth>1</bitWidth>
            </field>
            <field>
              <name>GC5C3</name>
              <bitOffset>31</bitOffset>
              <bitWidth>1</bitWidth>
            </field>
          </fields>
        </register>
        <register>
          <name>CCR6</name>
          <addressOffset>0x4c</addressOffset>
          <size>0x20</size>
          <fields>
            <field>
              <name>CCR6</name>
              <bitOffset>0</bitOffset>
              <bitWidth>16</bitWidth>
            </field>
          </fields>
        </register>
        <register>
          <name>CCMR3</name>
          <addressOffset>0x50</addressOffset>
          <size>0x20</size>
          <fields>
            <field>
              <name>OC5FE</name>
              <bitOffset>2</bitOffset>
              <bitWidth>1</bitWidth>
            </field>
            <field>
              <name>OC5PE</name>
              <bitOffset>3</bitOffset>
              <bitWidth>1</bitWidth>
            </field>
            <field>
              <name>OC5M</name>
              <bitOffset>4</bitOffset>
              <bitWidth>13</bitWidth>
            </field>
            <field>
              <name>OC5CE</name>
              <bitOffset>7</bitOffset>
              <bitWidth>1</bitWidth>
            </field>
            <field>
              <name>OC6FE</name>
              <bitOffset>10</bitOffset>
              <bitWidth>1</bitWidth>
            </field>
            <field>
              <name>OC6PE</name>
              <bitOffset>11</bitOffset>
              <bitWidth>1</bitWidth>
            </field>
            <field>
              <name>OC6M</name>
              <bitOffset>12</bitOffset>
              <bitWidth>13</bitWidth>
            </field>
            <field>
              <name>OC6CE</name>
              <bitOffset>15</bitOffset>
              <bitWidth>1</bitWidth>
            </field>
          </fields>
        </register>
        <register>
          <name>DTR2</name>
          <addressOffset>0x54</addressOffset>
          <size>0x20</size>
          <fields>
            <field>
              <name>DTGF</name>
              <bitOffset>0</bitOffset>
              <bitWidth>8</bitWidth>
            </field>
            <field>
              <name>DTAE</name>
              <bitOffset>16</bitOffset>
              <bitWidth>1</bitWidth>
            </field>
            <field>
              <name>DTPE</name>
              <bitOffset>17</bitOffset>
              <bitWidth>1</bitWidth>
            </field>
          </fields>
        </register>
        <register>
          <name>ECR</name>
          <addressOffset>0x58</addressOffset>
          <size>0x20</size>
          <fields>
            <field>
              <name>IE</name>
              <bitOffset>0</bitOffset>
              <bitWidth>1</bitWidth>
            </field>
            <field>
              <name>IDIR</name>
              <bitOffset>1</bitOffset>
              <bitWidth>2</bitWidth>
            </field>
            <field>
              <name>FIDX</name>
              <bitOffset>5</bitOffset>
              <bitWidth>1</bitWidth>
            </field>
            <field>
              <name>IPOS</name>
              <bitOffset>6</bitOffset>
              <bitWidth>2</bitWidth>
            </field>
            <field>
              <name>PW</name>
              <bitOffset>16</bitOffset>
              <bitWidth>8</bitWidth>
            </field>
            <field>
              <name>PWPRSC</name>
              <bitOffset>24</bitOffset>
              <bitWidth>3</bitWidth>
            </field>
          </fields>
        </register>
        <register>
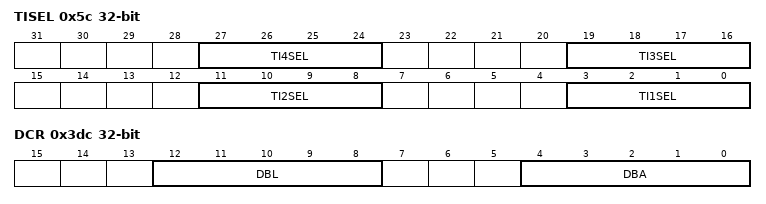
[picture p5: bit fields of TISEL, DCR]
          <name>TISEL</name>
          <addressOffset>0x5c</addressOffset>
          <size>0x20</size>
          <fields>
            <field>
              <name>TI1SEL</name>
              <bitOffset>0</bitOffset>
              <bitWidth>4</bitWidth>
            </field>
            <field>
              <name>TI2SEL</name>
              <bitOffset>8</bitOffset>
              <bitWidth>4</bitWidth>
            </field>
            <field>
              <name>TI3SEL</name>
              <bitOffset>16</bitOffset>
              <bitWidth>4</bitWidth>
            </field>
            <field>
              <name>TI4SEL</name>
              <bitOffset>24</bitOffset>
              <bitWidth>4</bitWidth>
            </field>
          </fields>
        </register>
        <register>
          <name>AF1</name>
          <addressOffset>0x60</addressOffset>
          <size>0x20</size>
        </register>
        <register>
          <name>AF2</name>
          <addressOffset>0x64</addressOffset>
          <size>0x20</size>
        </register>
        <register>
          <name>OR</name>
          <addressOffset>0x68</addressOffset>
          <size>0x20</size>
          <fields>
            <field>
              <name>HSE32EN</name>
              <bitOffset>0</bitOffset>
              <bitWidth>1</bitWidth>
            </field>
          </fields>
        </register>
        <register>
          <name>DCR</name>
          <addressOffset>0x3dc</addressOffset>
          <size>0x20</size>
          <fields>
            <field>
              <name>DBA</name>
              <bitOffset>0</bitOffset>
              <bitWidth>5</bitWidth>
            </field>
            <field>
              <name>DBL</name>
              <bitOffset>8</bitOffset>
              <bitWidth>5</bitWidth>
            </field>
          </fields>
        </register>
        <register>
          <name>DMAR</name>
          <addressOffset>0x3e0</addressOffset>
          <size>0x20</size>
          <fields>
            <field>
              <name>DMAB</name>
              <bitOffset>0</bitOffset>
              <bitWidth>32</bitWidth>
            </field>
          </fields>
        </register>
      </registers>
    </peripheral>
    <peripheral>
      <name>TIM4</name>
      <baseAddress>0x40000800</baseAddress>
      <registers>
        <register>
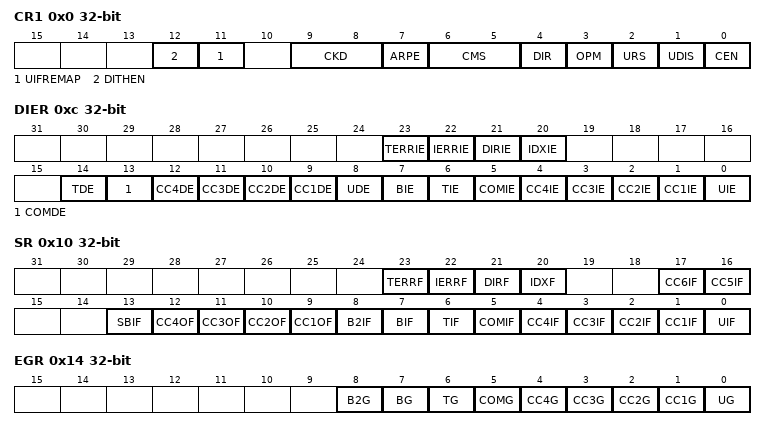
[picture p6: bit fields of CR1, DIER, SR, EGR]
          <name>CR1</name>
          <addressOffset>0x0</addressOffset>
          <size>0x20</size>
          <fields>
            <field>
              <name>CEN</name>
              <bitOffset>0</bitOffset>
              <bitWidth>1</bitWidth>
            </field>
            <field>
              <name>UDIS</name>
              <bitOffset>1</bitOffset>
              <bitWidth>1</bitWidth>
            </field>
            <field>
              <name>URS</name>
              <bitOffset>2</bitOffset>
              <bitWidth>1</bitWidth>
            </field>
            <field>
              <name>OPM</name>
              <bitOffset>3</bitOffset>
              <bitWidth>1</bitWidth>
            </field>
            <field>
              <name>DIR</name>
              <bitOffset>4</bitOffset>
              <bitWidth>1</bitWidth>
            </field>
            <field>
              <name>CMS</name>
              <bitOffset>5</bitOffset>
              <bitWidth>2</bitWidth>
            </field>
            <field>
              <name>ARPE</name>
              <bitOffset>7</bitOffset>
              <bitWidth>1</bitWidth>
            </field>
            <field>
              <name>CKD</name>
              <bitOffset>8</bitOffset>
              <bitWidth>2</bitWidth>
            </field>
            <field>
              <name>UIFREMAP</name>
              <bitOffset>11</bitOffset>
              <bitWidth>1</bitWidth>
            </field>
            <field>
              <name>DITHEN</name>
              <bitOffset>12</bitOffset>
              <bitWidth>1</bitWidth>
            </field>
          </fields>
        </register>
        <register>
          <name>CR2</name>
          <addressOffset>0x4</addressOffset>
          <size>0x20</size>
          <fields>
            <field>
              <name>CCPC</name>
              <bitOffset>0</bitOffset>
              <bitWidth>1</bitWidth>
            </field>
            <field>
              <name>CCUS</name>
              <bitOffset>2</bitOffset>
              <bitWidth>1</bitWidth>
            </field>
            <field>
              <name>CCDS</name>
              <bitOffset>3</bitOffset>
              <bitWidth>1</bitWidth>
            </field>
            <field>
              <name>MMS</name>
              <bitOffset>4</bitOffset>
              <bitWidth>22</bitWidth>
            </field>
            <field>
              <name>TI1S</name>
              <bitOffset>7</bitOffset>
              <bitWidth>1</bitWidth>
            </field>
            <field>
              <name>OIS1</name>
              <bitOffset>8</bitOffset>
              <bitWidth>1</bitWidth>
            </field>
            <field>
              <name>OIS1N</name>
              <bitOffset>9</bitOffset>
              <bitWidth>1</bitWidth>
            </field>
            <field>
              <name>OIS2</name>
              <bitOffset>10</bitOffset>
              <bitWidth>1</bitWidth>
            </field>
            <field>
              <name>OIS2N</name>
              <bitOffset>11</bitOffset>
              <bitWidth>1</bitWidth>
            </field>
            <field>
              <name>OIS3</name>
              <bitOffset>12</bitOffset>
              <bitWidth>1</bitWidth>
            </field>
            <field>
              <name>OIS3N</name>
              <bitOffset>13</bitOffset>
              <bitWidth>1</bitWidth>
            </field>
            <field>
              <name>OIS4</name>
              <bitOffset>14</bitOffset>
              <bitWidth>1</bitWidth>
            </field>
            <field>
              <name>OIS4N</name>
              <bitOffset>15</bitOffset>
              <bitWidth>1</bitWidth>
            </field>
            <field>
              <name>OIS5</name>
              <bitOffset>16</bitOffset>
              <bitWidth>1</bitWidth>
            </field>
            <field>
              <name>OIS6</name>
              <bitOffset>18</bitOffset>
              <bitWidth>1</bitWidth>
            </field>
            <field>
              <name>MMS2</name>
              <bitOffset>20</bitOffset>
              <bitWidth>4</bitWidth>
            </field>
          </fields>
        </register>
        <register>
          <name>SMCR</name>
          <addressOffset>0x8</addressOffset>
          <size>0x20</size>
          <fields>
            <field>
              <name>SMS</name>
              <bitOffset>0</bitOffset>
              <bitWidth>17</bitWidth>
            </field>
            <field>
              <name>OCCS</name>
              <bitOffset>3</bitOffset>
              <bitWidth>1</bitWidth>
            </field>
            <field>
              <name>TS</name>
              <bitOffset>4</bitOffset>
              <bitWidth>18</bitWidth>
            </field>
            <field>
              <name>MSM</name>
              <bitOffset>7</bitOffset>
              <bitWidth>1</bitWidth>
            </field>
            <field>
              <name>ETF</name>
              <bitOffset>8</bitOffset>
              <bitWidth>4</bitWidth>
            </field>
            <field>
              <name>ETPS</name>
              <bitOffset>12</bitOffset>
              <bitWidth>2</bitWidth>
            </field>
            <field>
              <name>ECE</name>
              <bitOffset>14</bitOffset>
              <bitWidth>1</bitWidth>
            </field>
            <field>
              <name>ETP</name>
              <bitOffset>15</bitOffset>
              <bitWidth>1</bitWidth>
            </field>
            <field>
              <name>SMSPE</name>
              <bitOffset>24</bitOffset>
              <bitWidth>1</bitWidth>
            </field>
            <field>
              <name>SMSPS</name>
              <bitOffset>25</bitOffset>
              <bitWidth>1</bitWidth>
            </field>
          </fields>
        </register>
        <register>
          <name>DIER</name>
          <addressOffset>0xc</addressOffset>
          <size>0x20</size>
          <fields>
            <field>
              <name>UIE</name>
              <bitOffset>0</bitOffset>
              <bitWidth>1</bitWidth>
            </field>
            <field>
              <name>CC1IE</name>
              <bitOffset>1</bitOffset>
              <bitWidth>1</bitWidth>
            </field>
            <field>
              <name>CC2IE</name>
              <bitOffset>2</bitOffset>
              <bitWidth>1</bitWidth>
            </field>
            <field>
              <name>CC3IE</name>
              <bitOffset>3</bitOffset>
              <bitWidth>1</bitWidth>
            </field>
            <field>
              <name>CC4IE</name>
              <bitOffset>4</bitOffset>
              <bitWidth>1</bitWidth>
            </field>
            <field>
              <name>COMIE</name>
              <bitOffset>5</bitOffset>
              <bitWidth>1</bitWidth>
            </field>
            <field>
              <name>TIE</name>
              <bitOffset>6</bitOffset>
              <bitWidth>1</bitWidth>
            </field>
            <field>
              <name>BIE</name>
              <bitOffset>7</bitOffset>
              <bitWidth>1</bitWidth>
            </field>
            <field>
              <name>UDE</name>
              <bitOffset>8</bitOffset>
              <bitWidth>1</bitWidth>
            </field>
            <field>
              <name>CC1DE</name>
              <bitOffset>9</bitOffset>
              <bitWidth>1</bitWidth>
            </field>
            <field>
              <name>CC2DE</name>
              <bitOffset>10</bitOffset>
              <bitWidth>1</bitWidth>
            </field>
            <field>
              <name>CC3DE</name>
              <bitOffset>11</bitOffset>
              <bitWidth>1</bitWidth>
            </field>
            <field>
              <name>CC4DE</name>
              <bitOffset>12</bitOffset>
              <bitWidth>1</bitWidth>
            </field>
            <field>
              <name>COMDE</name>
              <bitOffset>13</bitOffset>
              <bitWidth>1</bitWidth>
            </field>
            <field>
              <name>TDE</name>
              <bitOffset>14</bitOffset>
              <bitWidth>1</bitWidth>
            </field>
            <field>
              <name>IDXIE</name>
              <bitOffset>20</bitOffset>
              <bitWidth>1</bitWidth>
            </field>
            <field>
              <name>DIRIE</name>
              <bitOffset>21</bitOffset>
              <bitWidth>1</bitWidth>
            </field>
            <field>
              <name>IERRIE</name>
              <bitOffset>22</bitOffset>
              <bitWidth>1</bitWidth>
            </field>
            <field>
              <name>TERRIE</name>
              <bitOffset>23</bitOffset>
              <bitWidth>1</bitWidth>
            </field>
          </fields>
        </register>
        <register>
          <name>SR</name>
          <addressOffset>0x10</addressOffset>
          <size>0x20</size>
          <fields>
            <field>
              <name>UIF</name>
              <bitOffset>0</bitOffset>
              <bitWidth>1</bitWidth>
            </field>
            <field>
              <name>CC1IF</name>
              <bitOffset>1</bitOffset>
              <bitWidth>1</bitWidth>
            </field>
            <field>
              <name>CC2IF</name>
              <bitOffset>2</bitOffset>
              <bitWidth>1</bitWidth>
            </field>
            <field>
              <name>CC3IF</name>
              <bitOffset>3</bitOffset>
              <bitWidth>1</bitWidth>
            </field>
            <field>
              <name>CC4IF</name>
              <bitOffset>4</bitOffset>
              <bitWidth>1</bitWidth>
            </field>
            <field>
              <name>COMIF</name>
              <bitOffset>5</bitOffset>
              <bitWidth>1</bitWidth>
            </field>
            <field>
              <name>TIF</name>
              <bitOffset>6</bitOffset>
              <bitWidth>1</bitWidth>
            </field>
            <field>
              <name>BIF</name>
              <bitOffset>7</bitOffset>
              <bitWidth>1</bitWidth>
            </field>
            <field>
              <name>B2IF</name>
              <bitOffset>8</bitOffset>
              <bitWidth>1</bitWidth>
            </field>
            <field>
              <name>CC1OF</name>
              <bitOffset>9</bitOffset>
              <bitWidth>1</bitWidth>
            </field>
            <field>
              <name>CC2OF</name>
              <bitOffset>10</bitOffset>
              <bitWidth>1</bitWidth>
            </field>
            <field>
              <name>CC3OF</name>
              <bitOffset>11</bitOffset>
              <bitWidth>1</bitWidth>
            </field>
            <field>
              <name>CC4OF</name>
              <bitOffset>12</bitOffset>
              <bitWidth>1</bitWidth>
            </field>
            <field>
              <name>SBIF</name>
              <bitOffset>13</bitOffset>
              <bitWidth>1</bitWidth>
            </field>
            <field>
              <name>CC5IF</name>
              <bitOffset>16</bitOffset>
              <bitWidth>1</bitWidth>
            </field>
            <field>
              <name>CC6IF</name>
              <bitOffset>17</bitOffset>
              <bitWidth>1</bitWidth>
            </field>
            <field>
              <name>IDXF</name>
              <bitOffset>20</bitOffset>
              <bitWidth>1</bitWidth>
            </field>
            <field>
              <name>DIRF</name>
              <bitOffset>21</bitOffset>
              <bitWidth>1</bitWidth>
            </field>
            <field>
              <name>IERRF</name>
              <bitOffset>22</bitOffset>
              <bitWidth>1</bitWidth>
            </field>
            <field>
              <name>TERRF</name>
              <bitOffset>23</bitOffset>
              <bitWidth>1</bitWidth>
            </field>
          </fields>
        </register>
        <register>
          <name>EGR</name>
          <addressOffset>0x14</addressOffset>
          <size>0x20</size>
          <fields>
            <field>
              <name>UG</name>
              <bitOffset>0</bitOffset>
              <bitWidth>1</bitWidth>
            </field>
            <field>
              <name>CC1G</name>
              <bitOffset>1</bitOffset>
              <bitWidth>1</bitWidth>
            </field>
            <field>
              <name>CC2G</name>
              <bitOffset>2</bitOffset>
              <bitWidth>1</bitWidth>
            </field>
            <field>
              <name>CC3G</name>
              <bitOffset>3</bitOffset>
              <bitWidth>1</bitWidth>
            </field>
            <field>
              <name>CC4G</name>
              <bitOffset>4</bitOffset>
              <bitWidth>1</bitWidth>
            </field>
            <field>
              <name>COMG</name>
              <bitOffset>5</bitOffset>
              <bitWidth>1</bitWidth>
            </field>
            <field>
              <name>TG</name>
              <bitOffset>6</bitOffset>
              <bitWidth>1</bitWidth>
            </field>
            <field>
              <name>BG</name>
              <bitOffset>7</bitOffset>
              <bitWidth>1</bitWidth>
            </field>
            <field>
              <name>B2G</name>
              <bitOffset>8</bitOffset>
              <bitWidth>1</bitWidth>
            </field>
          </fields>
        </register>
        <register>
          <name>CCMR1</name>
          <addressOffset>0x18</addressOffset>
          <size>0x20</size>
          <fields>
            <field>
              <name>CC1S</name>
              <bitOffset>0</bitOffset>
              <bitWidth>2</bitWidth>
            </field>
            <field>
              <name>OC1FE</name>
              <bitOffset>2</bitOffset>
              <bitWidth>1</bitWidth>
            </field>
            <field>
              <name>OC1PE</name>
              <bitOffset>3</bitOffset>
              <bitWidth>1</bitWidth>
            </field>
            <field>
              <name>OC1M</name>
              <bitOffset>4</bitOffset>
              <bitWidth>13</bitWidth>
            </field>
            <field>
              <name>OC1CE</name>
              <bitOffset>7</bitOffset>
              <bitWidth>1</bitWidth>
            </field>
            <field>
              <name>CC2S</name>
              <bitOffset>8</bitOffset>
              <bitWidth>2</bitWidth>
            </field>
            <field>
              <name>OC2FE</name>
              <bitOffset>10</bitOffset>
              <bitWidth>1</bitWidth>
            </field>
            <field>
              <name>OC2PE</name>
              <bitOffset>11</bitOffset>
              <bitWidth>1</bitWidth>
            </field>
            <field>
              <name>OC2M</name>
              <bitOffset>12</bitOffset>
              <bitWidth>13</bitWidth>
            </field>
            <field>
              <name>OC2CE</name>
              <bitOffset>15</bitOffset>
              <bitWidth>1</bitWidth>
            </field>
          </fields>
        </register>
        <register>
          <name>CCMR2</name>
          <addressOffset>0x1c</addressOffset>
          <size>0x20</size>
          <fields>
            <field>
              <name>CC3S</name>
              <bitOffset>0</bitOffset>
              <bitWidth>2</bitWidth>
            </field>
            <field>
              <name>OC3FE</name>
              <bitOffset>2</bitOffset>
              <bitWidth>1</bitWidth>
            </field>
            <field>
              <name>OC3PE</name>
              <bitOffset>3</bitOffset>
              <bitWidth>1</bitWidth>
            </field>
            <field>
              <name>OC3M</name>
              <bitOffset>4</bitOffset>
              <bitWidth>13</bitWidth>
            </field>
            <field>
              <name>OC3CE</name>
              <bitOffset>7</bitOffset>
              <bitWidth>1</bitWidth>
            </field>
            <field>
              <name>CC4S</name>
              <bitOffset>8</bitOffset>
              <bitWidth>2</bitWidth>
            </field>
            <field>
              <name>OC4FE</name>
              <bitOffset>10</bitOffset>
              <bitWidth>1</bitWidth>
            </field>
            <field>
              <name>OC4PE</name>
              <bitOffset>11</bitOffset>
              <bitWidth>1</bitWidth>
            </field>
            <field>
              <name>OC4M</name>
              <bitOffset>12</bitOffset>
              <bitWidth>13</bitWidth>
            </field>
            <field>
              <name>OC4CE</name>
              <bitOffset>15</bitOffset>
              <bitWidth>1</bitWidth>
            </field>
          </fields>
        </register>
        <register>
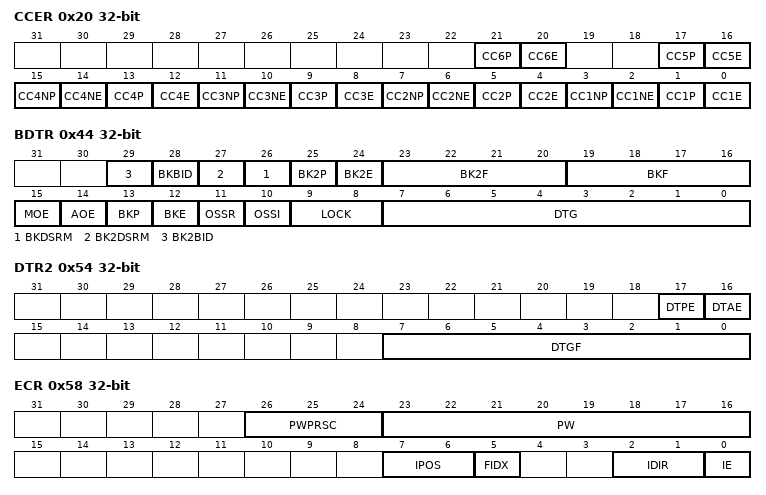
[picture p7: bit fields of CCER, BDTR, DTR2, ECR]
          <name>CCER</name>
          <addressOffset>0x20</addressOffset>
          <size>0x20</size>
          <fields>
            <field>
              <name>CC1E</name>
              <bitOffset>0</bitOffset>
              <bitWidth>1</bitWidth>
            </field>
            <field>
              <name>CC1P</name>
              <bitOffset>1</bitOffset>
              <bitWidth>1</bitWidth>
            </field>
            <field>
              <name>CC1NE</name>
              <bitOffset>2</bitOffset>
              <bitWidth>1</bitWidth>
            </field>
            <field>
              <name>CC1NP</name>
              <bitOffset>3</bitOffset>
              <bitWidth>1</bitWidth>
            </field>
            <field>
              <name>CC2E</name>
              <bitOffset>4</bitOffset>
              <bitWidth>1</bitWidth>
            </field>
            <field>
              <name>CC2P</name>
              <bitOffset>5</bitOffset>
              <bitWidth>1</bitWidth>
            </field>
            <field>
              <name>CC2NE</name>
              <bitOffset>6</bitOffset>
              <bitWidth>1</bitWidth>
            </field>
            <field>
              <name>CC2NP</name>
              <bitOffset>7</bitOffset>
              <bitWidth>1</bitWidth>
            </field>
            <field>
              <name>CC3E</name>
              <bitOffset>8</bitOffset>
              <bitWidth>1</bitWidth>
            </field>
            <field>
              <name>CC3P</name>
              <bitOffset>9</bitOffset>
              <bitWidth>1</bitWidth>
            </field>
            <field>
              <name>CC3NE</name>
              <bitOffset>10</bitOffset>
              <bitWidth>1</bitWidth>
            </field>
            <field>
              <name>CC3NP</name>
              <bitOffset>11</bitOffset>
              <bitWidth>1</bitWidth>
            </field>
            <field>
              <name>CC4E</name>
              <bitOffset>12</bitOffset>
              <bitWidth>1</bitWidth>
            </field>
            <field>
              <name>CC4P</name>
              <bitOffset>13</bitOffset>
              <bitWidth>1</bitWidth>
            </field>
            <field>
              <name>CC4NE</name>
              <bitOffset>14</bitOffset>
              <bitWidth>1</bitWidth>
            </field>
            <field>
              <name>CC4NP</name>
              <bitOffset>15</bitOffset>
              <bitWidth>1</bitWidth>
            </field>
            <field>
              <name>CC5E</name>
              <bitOffset>16</bitOffset>
              <bitWidth>1</bitWidth>
            </field>
            <field>
              <name>CC5P</name>
              <bitOffset>17</bitOffset>
              <bitWidth>1</bitWidth>
            </field>
            <field>
              <name>CC6E</name>
              <bitOffset>20</bitOffset>
              <bitWidth>1</bitWidth>
            </field>
            <field>
              <name>CC6P</name>
              <bitOffset>21</bitOffset>
              <bitWidth>1</bitWidth>
            </field>
          </fields>
        </register>
        <register>
          <name>CNT</name>
          <addressOffset>0x24</addressOffset>
          <size>0x20</size>
          <fields>
            <field>
              <name>CNT</name>
              <bitOffset>0</bitOffset>
              <bitWidth>32</bitWidth>
            </field>
            <field>
              <name>UIFCPY</name>
              <bitOffset>31</bitOffset>
              <bitWidth>1</bitWidth>
            </field>
          </fields>
        </register>
        <register>
          <name>PSC</name>
          <addressOffset>0x28</addressOffset>
          <size>0x20</size>
          <fields>
            <field>
              <name>PSC</name>
              <bitOffset>0</bitOffset>
              <bitWidth>16</bitWidth>
            </field>
          </fields>
        </register>
        <register>
          <name>ARR</name>
          <addressOffset>0x2c</addressOffset>
          <size>0x20</size>
          <fields>
            <field>
              <name>ARR</name>
              <bitOffset>0</bitOffset>
              <bitWidth>32</bitWidth>
            </field>
          </fields>
        </register>
        <register>
          <name>RCR</name>
          <addressOffset>0x30</addressOffset>
          <size>0x20</size>
          <fields>
            <field>
              <name>REP</name>
              <bitOffset>0</bitOffset>
              <bitWidth>16</bitWidth>
            </field>
          </fields>
        </register>
        <register>
          <name>CCR1</name>
          <addressOffset>0x34</addressOffset>
          <size>0x20</size>
          <fields>
            <field>
              <name>CCR1</name>
              <bitOffset>0</bitOffset>
              <bitWidth>16</bitWidth>
            </field>
          </fields>
        </register>
        <register>
          <name>CCR2</name>
          <addressOffset>0x38</addressOffset>
          <size>0x20</size>
          <fields>
            <field>
              <name>CCR2</name>
              <bitOffset>0</bitOffset>
              <bitWidth>16</bitWidth>
            </field>
          </fields>
        </register>
        <register>
          <name>CCR3</name>
          <addressOffset>0x3c</addressOffset>
          <size>0x20</size>
          <fields>
            <field>
              <name>CCR3</name>
              <bitOffset>0</bitOffset>
              <bitWidth>16</bitWidth>
            </field>
          </fields>
        </register>
        <register>
          <name>CCR4</name>
          <addressOffset>0x40</addressOffset>
          <size>0x20</size>
          <fields>
            <field>
              <name>CCR4</name>
              <bitOffset>0</bitOffset>
              <bitWidth>16</bitWidth>
            </field>
          </fields>
        </register>
        <register>
          <name>BDTR</name>
          <addressOffset>0x44</addressOffset>
          <size>0x20</size>
          <fields>
            <field>
              <name>DTG</name>
              <bitOffset>0</bitOffset>
              <bitWidth>8</bitWidth>
            </field>
            <field>
              <name>LOCK</name>
              <bitOffset>8</bitOffset>
              <bitWidth>2</bitWidth>
            </field>
            <field>
              <name>OSSI</name>
              <bitOffset>10</bitOffset>
              <bitWidth>1</bitWidth>
            </field>
            <field>
              <name>OSSR</name>
              <bitOffset>11</bitOffset>
              <bitWidth>1</bitWidth>
            </field>
            <field>
              <name>BKE</name>
              <bitOffset>12</bitOffset>
              <bitWidth>1</bitWidth>
            </field>
            <field>
              <name>BKP</name>
              <bitOffset>13</bitOffset>
              <bitWidth>1</bitWidth>
            </field>
            <field>
              <name>AOE</name>
              <bitOffset>14</bitOffset>
              <bitWidth>1</bitWidth>
            </field>
            <field>
              <name>MOE</name>
              <bitOffset>15</bitOffset>
              <bitWidth>1</bitWidth>
            </field>
            <field>
              <name>BKF</name>
              <bitOffset>16</bitOffset>
              <bitWidth>4</bitWidth>
            </field>
            <field>
              <name>BK2F</name>
              <bitOffset>20</bitOffset>
              <bitWidth>4</bitWidth>
            </field>
            <field>
              <name>BK2E</name>
              <bitOffset>24</bitOffset>
              <bitWidth>1</bitWidth>
            </field>
            <field>
              <name>BK2P</name>
              <bitOffset>25</bitOffset>
              <bitWidth>1</bitWidth>
            </field>
            <field>
              <name>BKDSRM</name>
              <bitOffset>26</bitOffset>
              <bitWidth>1</bitWidth>
            </field>
            <field>
              <name>BK2DSRM</name>
              <bitOffset>27</bitOffset>
              <bitWidth>1</bitWidth>
            </field>
            <field>
              <name>BKBID</name>
              <bitOffset>28</bitOffset>
              <bitWidth>1</bitWidth>
            </field>
            <field>
              <name>BK2BID</name>
              <bitOffset>29</bitOffset>
              <bitWidth>1</bitWidth>
            </field>
          </fields>
        </register>
        <register>
          <name>CCR5</name>
          <addressOffset>0x48</addressOffset>
          <size>0x20</size>
          <fields>
            <field>
              <name>CCR5</name>
              <bitOffset>0</bitOffset>
              <bitWidth>32</bitWidth>
            </field>
            <field>
              <name>GC5C1</name>
              <bitOffset>29</bitOffset>
              <bitWidth>1</bitWidth>
            </field>
            <field>
              <name>GC5C2</name>
              <bitOffset>30</bitOffset>
              <bitWidth>1</bitWidth>
            </field>
            <field>
              <name>GC5C3</name>
              <bitOffset>31</bitOffset>
              <bitWidth>1</bitWidth>
            </field>
          </fields>
        </register>
        <register>
          <name>CCR6</name>
          <addressOffset>0x4c</addressOffset>
          <size>0x20</size>
          <fields>
            <field>
              <name>CCR6</name>
              <bitOffset>0</bitOffset>
              <bitWidth>16</bitWidth>
            </field>
          </fields>
        </register>
        <register>
          <name>CCMR3</name>
          <addressOffset>0x50</addressOffset>
          <size>0x20</size>
          <fields>
            <field>
              <name>OC5FE</name>
              <bitOffset>2</bitOffset>
              <bitWidth>1</bitWidth>
            </field>
            <field>
              <name>OC5PE</name>
              <bitOffset>3</bitOffset>
              <bitWidth>1</bitWidth>
            </field>
            <field>
              <name>OC5M</name>
              <bitOffset>4</bitOffset>
              <bitWidth>13</bitWidth>
            </field>
            <field>
              <name>OC5CE</name>
              <bitOffset>7</bitOffset>
              <bitWidth>1</bitWidth>
            </field>
            <field>
              <name>OC6FE</name>
              <bitOffset>10</bitOffset>
              <bitWidth>1</bitWidth>
            </field>
            <field>
              <name>OC6PE</name>
              <bitOffset>11</bitOffset>
              <bitWidth>1</bitWidth>
            </field>
            <field>
              <name>OC6M</name>
              <bitOffset>12</bitOffset>
              <bitWidth>13</bitWidth>
            </field>
            <field>
              <name>OC6CE</name>
              <bitOffset>15</bitOffset>
              <bitWidth>1</bitWidth>
            </field>
          </fields>
        </register>
        <register>
          <name>DTR2</name>
          <addressOffset>0x54</addressOffset>
          <size>0x20</size>
          <fields>
            <field>
              <name>DTGF</name>
              <bitOffset>0</bitOffset>
              <bitWidth>8</bitWidth>
            </field>
            <field>
              <name>DTAE</name>
              <bitOffset>16</bitOffset>
              <bitWidth>1</bitWidth>
            </field>
            <field>
              <name>DTPE</name>
              <bitOffset>17</bitOffset>
              <bitWidth>1</bitWidth>
            </field>
          </fields>
        </register>
        <register>
          <name>ECR</name>
          <addressOffset>0x58</addressOffset>
          <size>0x20</size>
          <fields>
            <field>
              <name>IE</name>
              <bitOffset>0</bitOffset>
              <bitWidth>1</bitWidth>
            </field>
            <field>
              <name>IDIR</name>
              <bitOffset>1</bitOffset>
              <bitWidth>2</bitWidth>
            </field>
            <field>
              <name>FIDX</name>
              <bitOffset>5</bitOffset>
              <bitWidth>1</bitWidth>
            </field>
            <field>
              <name>IPOS</name>
              <bitOffset>6</bitOffset>
              <bitWidth>2</bitWidth>
            </field>
            <field>
              <name>PW</name>
              <bitOffset>16</bitOffset>
              <bitWidth>8</bitWidth>
            </field>
            <field>
              <name>PWPRSC</name>
              <bitOffset>24</bitOffset>
              <bitWidth>3</bitWidth>
            </field>
          </fields>
        </register>
        <register>
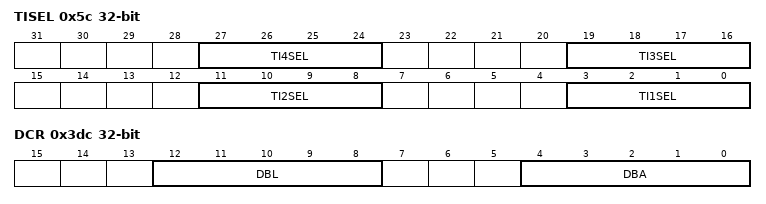
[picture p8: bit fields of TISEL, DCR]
          <name>TISEL</name>
          <addressOffset>0x5c</addressOffset>
          <size>0x20</size>
          <fields>
            <field>
              <name>TI1SEL</name>
              <bitOffset>0</bitOffset>
              <bitWidth>4</bitWidth>
            </field>
            <field>
              <name>TI2SEL</name>
              <bitOffset>8</bitOffset>
              <bitWidth>4</bitWidth>
            </field>
            <field>
              <name>TI3SEL</name>
              <bitOffset>16</bitOffset>
              <bitWidth>4</bitWidth>
            </field>
            <field>
              <name>TI4SEL</name>
              <bitOffset>24</bitOffset>
              <bitWidth>4</bitWidth>
            </field>
          </fields>
        </register>
        <register>
          <name>AF1</name>
          <addressOffset>0x60</addressOffset>
          <size>0x20</size>
        </register>
        <register>
          <name>AF2</name>
          <addressOffset>0x64</addressOffset>
          <size>0x20</size>
        </register>
        <register>
          <name>OR</name>
          <addressOffset>0x68</addressOffset>
          <size>0x20</size>
          <fields>
            <field>
              <name>HSE32EN</name>
              <bitOffset>0</bitOffset>
              <bitWidth>1</bitWidth>
            </field>
          </fields>
        </register>
        <register>
          <name>DCR</name>
          <addressOffset>0x3dc</addressOffset>
          <size>0x20</size>
          <fields>
            <field>
              <name>DBA</name>
              <bitOffset>0</bitOffset>
              <bitWidth>5</bitWidth>
            </field>
            <field>
              <name>DBL</name>
              <bitOffset>8</bitOffset>
              <bitWidth>5</bitWidth>
            </field>
          </fields>
        </register>
        <register>
          <name>DMAR</name>
          <addressOffset>0x3e0</addressOffset>
          <size>0x20</size>
          <fields>
            <field>
              <name>DMAB</name>
              <bitOffset>0</bitOffset>
              <bitWidth>32</bitWidth>
            </field>
          </fields>
        </register>
      </registers>
    </peripheral>
    <peripheral>
      <name>TIM6</name>
      <baseAddress>0x40001000</baseAddress>
      <registers>
        <register>
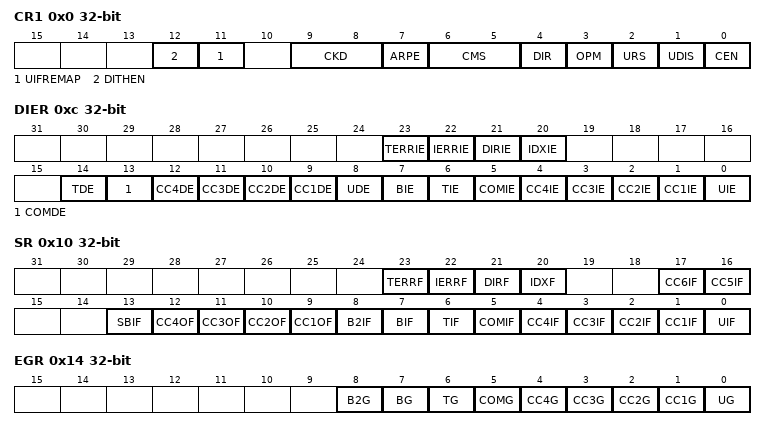
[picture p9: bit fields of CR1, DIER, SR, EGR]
          <name>CR1</name>
          <addressOffset>0x0</addressOffset>
          <size>0x20</size>
          <fields>
            <field>
              <name>CEN</name>
              <bitOffset>0</bitOffset>
              <bitWidth>1</bitWidth>
            </field>
            <field>
              <name>UDIS</name>
              <bitOffset>1</bitOffset>
              <bitWidth>1</bitWidth>
            </field>
            <field>
              <name>URS</name>
              <bitOffset>2</bitOffset>
              <bitWidth>1</bitWidth>
            </field>
            <field>
              <name>OPM</name>
              <bitOffset>3</bitOffset>
              <bitWidth>1</bitWidth>
            </field>
            <field>
              <name>DIR</name>
              <bitOffset>4</bitOffset>
              <bitWidth>1</bitWidth>
            </field>
            <field>
              <name>CMS</name>
              <bitOffset>5</bitOffset>
              <bitWidth>2</bitWidth>
            </field>
            <field>
              <name>ARPE</name>
              <bitOffset>7</bitOffset>
              <bitWidth>1</bitWidth>
            </field>
            <field>
              <name>CKD</name>
              <bitOffset>8</bitOffset>
              <bitWidth>2</bitWidth>
            </field>
            <field>
              <name>UIFREMAP</name>
              <bitOffset>11</bitOffset>
              <bitWidth>1</bitWidth>
            </field>
            <field>
              <name>DITHEN</name>
              <bitOffset>12</bitOffset>
              <bitWidth>1</bitWidth>
            </field>
          </fields>
        </register>
        <register>
          <name>CR2</name>
          <addressOffset>0x4</addressOffset>
          <size>0x20</size>
          <fields>
            <field>
              <name>CCPC</name>
              <bitOffset>0</bitOffset>
              <bitWidth>1</bitWidth>
            </field>
            <field>
              <name>CCUS</name>
              <bitOffset>2</bitOffset>
              <bitWidth>1</bitWidth>
            </field>
            <field>
              <name>CCDS</name>
              <bitOffset>3</bitOffset>
              <bitWidth>1</bitWidth>
            </field>
            <field>
              <name>MMS</name>
              <bitOffset>4</bitOffset>
              <bitWidth>22</bitWidth>
            </field>
            <field>
              <name>TI1S</name>
              <bitOffset>7</bitOffset>
              <bitWidth>1</bitWidth>
            </field>
            <field>
              <name>OIS1</name>
              <bitOffset>8</bitOffset>
              <bitWidth>1</bitWidth>
            </field>
            <field>
              <name>OIS1N</name>
              <bitOffset>9</bitOffset>
              <bitWidth>1</bitWidth>
            </field>
            <field>
              <name>OIS2</name>
              <bitOffset>10</bitOffset>
              <bitWidth>1</bitWidth>
            </field>
            <field>
              <name>OIS2N</name>
              <bitOffset>11</bitOffset>
              <bitWidth>1</bitWidth>
            </field>
            <field>
              <name>OIS3</name>
              <bitOffset>12</bitOffset>
              <bitWidth>1</bitWidth>
            </field>
            <field>
              <name>OIS3N</name>
              <bitOffset>13</bitOffset>
              <bitWidth>1</bitWidth>
            </field>
            <field>
              <name>OIS4</name>
              <bitOffset>14</bitOffset>
              <bitWidth>1</bitWidth>
            </field>
            <field>
              <name>OIS4N</name>
              <bitOffset>15</bitOffset>
              <bitWidth>1</bitWidth>
            </field>
            <field>
              <name>OIS5</name>
              <bitOffset>16</bitOffset>
              <bitWidth>1</bitWidth>
            </field>
            <field>
              <name>OIS6</name>
              <bitOffset>18</bitOffset>
              <bitWidth>1</bitWidth>
            </field>
            <field>
              <name>MMS2</name>
              <bitOffset>20</bitOffset>
              <bitWidth>4</bitWidth>
            </field>
          </fields>
        </register>
        <register>
          <name>SMCR</name>
          <addressOffset>0x8</addressOffset>
          <size>0x20</size>
          <fields>
            <field>
              <name>SMS</name>
              <bitOffset>0</bitOffset>
              <bitWidth>17</bitWidth>
            </field>
            <field>
              <name>OCCS</name>
              <bitOffset>3</bitOffset>
              <bitWidth>1</bitWidth>
            </field>
            <field>
              <name>TS</name>
              <bitOffset>4</bitOffset>
              <bitWidth>18</bitWidth>
            </field>
            <field>
              <name>MSM</name>
              <bitOffset>7</bitOffset>
              <bitWidth>1</bitWidth>
            </field>
            <field>
              <name>ETF</name>
              <bitOffset>8</bitOffset>
              <bitWidth>4</bitWidth>
            </field>
            <field>
              <name>ETPS</name>
              <bitOffset>12</bitOffset>
              <bitWidth>2</bitWidth>
            </field>
            <field>
              <name>ECE</name>
              <bitOffset>14</bitOffset>
              <bitWidth>1</bitWidth>
            </field>
            <field>
              <name>ETP</name>
              <bitOffset>15</bitOffset>
              <bitWidth>1</bitWidth>
            </field>
            <field>
              <name>SMSPE</name>
              <bitOffset>24</bitOffset>
              <bitWidth>1</bitWidth>
            </field>
            <field>
              <name>SMSPS</name>
              <bitOffset>25</bitOffset>
              <bitWidth>1</bitWidth>
            </field>
          </fields>
        </register>
        <register>
          <name>DIER</name>
          <addressOffset>0xc</addressOffset>
          <size>0x20</size>
          <fields>
            <field>
              <name>UIE</name>
              <bitOffset>0</bitOffset>
              <bitWidth>1</bitWidth>
            </field>
            <field>
              <name>CC1IE</name>
              <bitOffset>1</bitOffset>
              <bitWidth>1</bitWidth>
            </field>
            <field>
              <name>CC2IE</name>
              <bitOffset>2</bitOffset>
              <bitWidth>1</bitWidth>
            </field>
            <field>
              <name>CC3IE</name>
              <bitOffset>3</bitOffset>
              <bitWidth>1</bitWidth>
            </field>
            <field>
              <name>CC4IE</name>
              <bitOffset>4</bitOffset>
              <bitWidth>1</bitWidth>
            </field>
            <field>
              <name>COMIE</name>
              <bitOffset>5</bitOffset>
              <bitWidth>1</bitWidth>
            </field>
            <field>
              <name>TIE</name>
              <bitOffset>6</bitOffset>
              <bitWidth>1</bitWidth>
            </field>
            <field>
              <name>BIE</name>
              <bitOffset>7</bitOffset>
              <bitWidth>1</bitWidth>
            </field>
            <field>
              <name>UDE</name>
              <bitOffset>8</bitOffset>
              <bitWidth>1</bitWidth>
            </field>
            <field>
              <name>CC1DE</name>
              <bitOffset>9</bitOffset>
              <bitWidth>1</bitWidth>
            </field>
            <field>
              <name>CC2DE</name>
              <bitOffset>10</bitOffset>
              <bitWidth>1</bitWidth>
            </field>
            <field>
              <name>CC3DE</name>
              <bitOffset>11</bitOffset>
              <bitWidth>1</bitWidth>
            </field>
            <field>
              <name>CC4DE</name>
              <bitOffset>12</bitOffset>
              <bitWidth>1</bitWidth>
            </field>
            <field>
              <name>COMDE</name>
              <bitOffset>13</bitOffset>
              <bitWidth>1</bitWidth>
            </field>
            <field>
              <name>TDE</name>
              <bitOffset>14</bitOffset>
              <bitWidth>1</bitWidth>
            </field>
            <field>
              <name>IDXIE</name>
              <bitOffset>20</bitOffset>
              <bitWidth>1</bitWidth>
            </field>
            <field>
              <name>DIRIE</name>
              <bitOffset>21</bitOffset>
              <bitWidth>1</bitWidth>
            </field>
            <field>
              <name>IERRIE</name>
              <bitOffset>22</bitOffset>
              <bitWidth>1</bitWidth>
            </field>
            <field>
              <name>TERRIE</name>
              <bitOffset>23</bitOffset>
              <bitWidth>1</bitWidth>
            </field>
          </fields>
        </register>
        <register>
          <name>SR</name>
          <addressOffset>0x10</addressOffset>
          <size>0x20</size>
          <fields>
            <field>
              <name>UIF</name>
              <bitOffset>0</bitOffset>
              <bitWidth>1</bitWidth>
            </field>
            <field>
              <name>CC1IF</name>
              <bitOffset>1</bitOffset>
              <bitWidth>1</bitWidth>
            </field>
            <field>
              <name>CC2IF</name>
              <bitOffset>2</bitOffset>
              <bitWidth>1</bitWidth>
            </field>
            <field>
              <name>CC3IF</name>
              <bitOffset>3</bitOffset>
              <bitWidth>1</bitWidth>
            </field>
            <field>
              <name>CC4IF</name>
              <bitOffset>4</bitOffset>
              <bitWidth>1</bitWidth>
            </field>
            <field>
              <name>COMIF</name>
              <bitOffset>5</bitOffset>
              <bitWidth>1</bitWidth>
            </field>
            <field>
              <name>TIF</name>
              <bitOffset>6</bitOffset>
              <bitWidth>1</bitWidth>
            </field>
            <field>
              <name>BIF</name>
              <bitOffset>7</bitOffset>
              <bitWidth>1</bitWidth>
            </field>
            <field>
              <name>B2IF</name>
              <bitOffset>8</bitOffset>
              <bitWidth>1</bitWidth>
            </field>
            <field>
              <name>CC1OF</name>
              <bitOffset>9</bitOffset>
              <bitWidth>1</bitWidth>
            </field>
            <field>
              <name>CC2OF</name>
              <bitOffset>10</bitOffset>
              <bitWidth>1</bitWidth>
            </field>
            <field>
              <name>CC3OF</name>
              <bitOffset>11</bitOffset>
              <bitWidth>1</bitWidth>
            </field>
            <field>
              <name>CC4OF</name>
              <bitOffset>12</bitOffset>
              <bitWidth>1</bitWidth>
            </field>
            <field>
              <name>SBIF</name>
              <bitOffset>13</bitOffset>
              <bitWidth>1</bitWidth>
            </field>
            <field>
              <name>CC5IF</name>
              <bitOffset>16</bitOffset>
              <bitWidth>1</bitWidth>
            </field>
            <field>
              <name>CC6IF</name>
              <bitOffset>17</bitOffset>
              <bitWidth>1</bitWidth>
            </field>
            <field>
              <name>IDXF</name>
              <bitOffset>20</bitOffset>
              <bitWidth>1</bitWidth>
            </field>
            <field>
              <name>DIRF</name>
              <bitOffset>21</bitOffset>
              <bitWidth>1</bitWidth>
            </field>
            <field>
              <name>IERRF</name>
              <bitOffset>22</bitOffset>
              <bitWidth>1</bitWidth>
            </field>
            <field>
              <name>TERRF</name>
              <bitOffset>23</bitOffset>
              <bitWidth>1</bitWidth>
            </field>
          </fields>
        </register>
        <register>
          <name>EGR</name>
          <addressOffset>0x14</addressOffset>
          <size>0x20</size>
          <fields>
            <field>
              <name>UG</name>
              <bitOffset>0</bitOffset>
              <bitWidth>1</bitWidth>
            </field>
            <field>
              <name>CC1G</name>
              <bitOffset>1</bitOffset>
              <bitWidth>1</bitWidth>
            </field>
            <field>
              <name>CC2G</name>
              <bitOffset>2</bitOffset>
              <bitWidth>1</bitWidth>
            </field>
            <field>
              <name>CC3G</name>
              <bitOffset>3</bitOffset>
              <bitWidth>1</bitWidth>
            </field>
            <field>
              <name>CC4G</name>
              <bitOffset>4</bitOffset>
              <bitWidth>1</bitWidth>
            </field>
            <field>
              <name>COMG</name>
              <bitOffset>5</bitOffset>
              <bitWidth>1</bitWidth>
            </field>
            <field>
              <name>TG</name>
              <bitOffset>6</bitOffset>
              <bitWidth>1</bitWidth>
            </field>
            <field>
              <name>BG</name>
              <bitOffset>7</bitOffset>
              <bitWidth>1</bitWidth>
            </field>
            <field>
              <name>B2G</name>
              <bitOffset>8</bitOffset>
              <bitWidth>1</bitWidth>
            </field>
          </fields>
        </register>
        <register>
          <name>CCMR1</name>
          <addressOffset>0x18</addressOffset>
          <size>0x20</size>
          <fields>
            <field>
              <name>CC1S</name>
              <bitOffset>0</bitOffset>
              <bitWidth>2</bitWidth>
            </field>
            <field>
              <name>OC1FE</name>
              <bitOffset>2</bitOffset>
              <bitWidth>1</bitWidth>
            </field>
            <field>
              <name>OC1PE</name>
              <bitOffset>3</bitOffset>
              <bitWidth>1</bitWidth>
            </field>
            <field>
              <name>OC1M</name>
              <bitOffset>4</bitOffset>
              <bitWidth>13</bitWidth>
            </field>
            <field>
              <name>OC1CE</name>
              <bitOffset>7</bitOffset>
              <bitWidth>1</bitWidth>
            </field>
            <field>
              <name>CC2S</name>
              <bitOffset>8</bitOffset>
              <bitWidth>2</bitWidth>
            </field>
            <field>
              <name>OC2FE</name>
              <bitOffset>10</bitOffset>
              <bitWidth>1</bitWidth>
            </field>
            <field>
              <name>OC2PE</name>
              <bitOffset>11</bitOffset>
              <bitWidth>1</bitWidth>
            </field>
            <field>
              <name>OC2M</name>
              <bitOffset>12</bitOffset>
              <bitWidth>13</bitWidth>
            </field>
            <field>
              <name>OC2CE</name>
              <bitOffset>15</bitOffset>
              <bitWidth>1</bitWidth>
            </field>
          </fields>
        </register>
        <register>
          <name>CCMR2</name>
          <addressOffset>0x1c</addressOffset>
          <size>0x20</size>
          <fields>
            <field>
              <name>CC3S</name>
              <bitOffset>0</bitOffset>
              <bitWidth>2</bitWidth>
            </field>
            <field>
              <name>OC3FE</name>
              <bitOffset>2</bitOffset>
              <bitWidth>1</bitWidth>
            </field>
            <field>
              <name>OC3PE</name>
              <bitOffset>3</bitOffset>
              <bitWidth>1</bitWidth>
            </field>
            <field>
              <name>OC3M</name>
              <bitOffset>4</bitOffset>
              <bitWidth>13</bitWidth>
            </field>
            <field>
              <name>OC3CE</name>
              <bitOffset>7</bitOffset>
              <bitWidth>1</bitWidth>
            </field>
            <field>
              <name>CC4S</name>
              <bitOffset>8</bitOffset>
              <bitWidth>2</bitWidth>
            </field>
            <field>
              <name>OC4FE</name>
              <bitOffset>10</bitOffset>
              <bitWidth>1</bitWidth>
            </field>
            <field>
              <name>OC4PE</name>
              <bitOffset>11</bitOffset>
              <bitWidth>1</bitWidth>
            </field>
            <field>
              <name>OC4M</name>
              <bitOffset>12</bitOffset>
              <bitWidth>13</bitWidth>
            </field>
            <field>
              <name>OC4CE</name>
              <bitOffset>15</bitOffset>
              <bitWidth>1</bitWidth>
            </field>
          </fields>
        </register>
        <register>
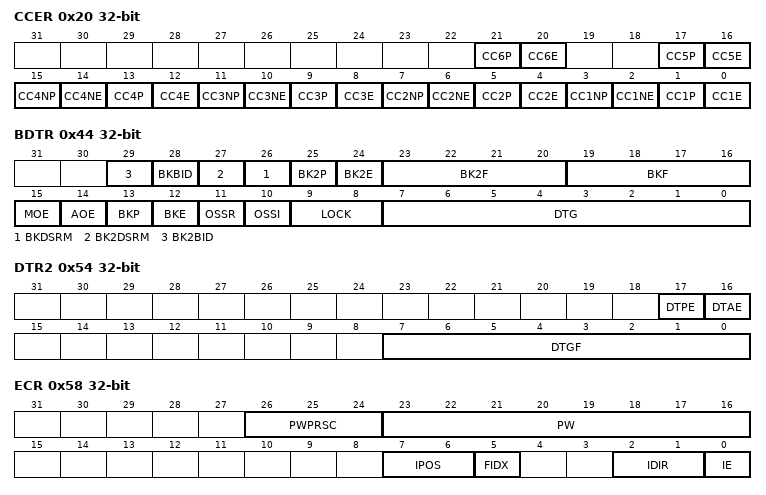
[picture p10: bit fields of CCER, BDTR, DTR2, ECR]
          <name>CCER</name>
          <addressOffset>0x20</addressOffset>
          <size>0x20</size>
          <fields>
            <field>
              <name>CC1E</name>
              <bitOffset>0</bitOffset>
              <bitWidth>1</bitWidth>
            </field>
            <field>
              <name>CC1P</name>
              <bitOffset>1</bitOffset>
              <bitWidth>1</bitWidth>
            </field>
            <field>
              <name>CC1NE</name>
              <bitOffset>2</bitOffset>
              <bitWidth>1</bitWidth>
            </field>
            <field>
              <name>CC1NP</name>
              <bitOffset>3</bitOffset>
              <bitWidth>1</bitWidth>
            </field>
            <field>
              <name>CC2E</name>
              <bitOffset>4</bitOffset>
              <bitWidth>1</bitWidth>
            </field>
            <field>
              <name>CC2P</name>
              <bitOffset>5</bitOffset>
              <bitWidth>1</bitWidth>
            </field>
            <field>
              <name>CC2NE</name>
              <bitOffset>6</bitOffset>
              <bitWidth>1</bitWidth>
            </field>
            <field>
              <name>CC2NP</name>
              <bitOffset>7</bitOffset>
              <bitWidth>1</bitWidth>
            </field>
            <field>
              <name>CC3E</name>
              <bitOffset>8</bitOffset>
              <bitWidth>1</bitWidth>
            </field>
            <field>
              <name>CC3P</name>
              <bitOffset>9</bitOffset>
              <bitWidth>1</bitWidth>
            </field>
            <field>
              <name>CC3NE</name>
              <bitOffset>10</bitOffset>
              <bitWidth>1</bitWidth>
            </field>
            <field>
              <name>CC3NP</name>
              <bitOffset>11</bitOffset>
              <bitWidth>1</bitWidth>
            </field>
            <field>
              <name>CC4E</name>
              <bitOffset>12</bitOffset>
              <bitWidth>1</bitWidth>
            </field>
            <field>
              <name>CC4P</name>
              <bitOffset>13</bitOffset>
              <bitWidth>1</bitWidth>
            </field>
            <field>
              <name>CC4NE</name>
              <bitOffset>14</bitOffset>
              <bitWidth>1</bitWidth>
            </field>
            <field>
              <name>CC4NP</name>
              <bitOffset>15</bitOffset>
              <bitWidth>1</bitWidth>
            </field>
            <field>
              <name>CC5E</name>
              <bitOffset>16</bitOffset>
              <bitWidth>1</bitWidth>
            </field>
            <field>
              <name>CC5P</name>
              <bitOffset>17</bitOffset>
              <bitWidth>1</bitWidth>
            </field>
            <field>
              <name>CC6E</name>
              <bitOffset>20</bitOffset>
              <bitWidth>1</bitWidth>
            </field>
            <field>
              <name>CC6P</name>
              <bitOffset>21</bitOffset>
              <bitWidth>1</bitWidth>
            </field>
          </fields>
        </register>
        <register>
          <name>CNT</name>
          <addressOffset>0x24</addressOffset>
          <size>0x20</size>
          <fields>
            <field>
              <name>CNT</name>
              <bitOffset>0</bitOffset>
              <bitWidth>32</bitWidth>
            </field>
            <field>
              <name>UIFCPY</name>
              <bitOffset>31</bitOffset>
              <bitWidth>1</bitWidth>
            </field>
          </fields>
        </register>
        <register>
          <name>PSC</name>
          <addressOffset>0x28</addressOffset>
          <size>0x20</size>
          <fields>
            <field>
              <name>PSC</name>
              <bitOffset>0</bitOffset>
              <bitWidth>16</bitWidth>
            </field>
          </fields>
        </register>
        <register>
          <name>ARR</name>
          <addressOffset>0x2c</addressOffset>
          <size>0x20</size>
          <fields>
            <field>
              <name>ARR</name>
              <bitOffset>0</bitOffset>
              <bitWidth>32</bitWidth>
            </field>
          </fields>
        </register>
        <register>
          <name>RCR</name>
          <addressOffset>0x30</addressOffset>
          <size>0x20</size>
          <fields>
            <field>
              <name>REP</name>
              <bitOffset>0</bitOffset>
              <bitWidth>16</bitWidth>
            </field>
          </fields>
        </register>
        <register>
          <name>CCR1</name>
          <addressOffset>0x34</addressOffset>
          <size>0x20</size>
          <fields>
            <field>
              <name>CCR1</name>
              <bitOffset>0</bitOffset>
              <bitWidth>16</bitWidth>
            </field>
          </fields>
        </register>
        <register>
          <name>CCR2</name>
          <addressOffset>0x38</addressOffset>
          <size>0x20</size>
          <fields>
            <field>
              <name>CCR2</name>
              <bitOffset>0</bitOffset>
              <bitWidth>16</bitWidth>
            </field>
          </fields>
        </register>
        <register>
          <name>CCR3</name>
          <addressOffset>0x3c</addressOffset>
          <size>0x20</size>
          <fields>
            <field>
              <name>CCR3</name>
              <bitOffset>0</bitOffset>
              <bitWidth>16</bitWidth>
            </field>
          </fields>
        </register>
        <register>
          <name>CCR4</name>
          <addressOffset>0x40</addressOffset>
          <size>0x20</size>
          <fields>
            <field>
              <name>CCR4</name>
              <bitOffset>0</bitOffset>
              <bitWidth>16</bitWidth>
            </field>
          </fields>
        </register>
        <register>
          <name>BDTR</name>
          <addressOffset>0x44</addressOffset>
          <size>0x20</size>
          <fields>
            <field>
              <name>DTG</name>
              <bitOffset>0</bitOffset>
              <bitWidth>8</bitWidth>
            </field>
            <field>
              <name>LOCK</name>
              <bitOffset>8</bitOffset>
              <bitWidth>2</bitWidth>
            </field>
            <field>
              <name>OSSI</name>
              <bitOffset>10</bitOffset>
              <bitWidth>1</bitWidth>
            </field>
            <field>
              <name>OSSR</name>
              <bitOffset>11</bitOffset>
              <bitWidth>1</bitWidth>
            </field>
            <field>
              <name>BKE</name>
              <bitOffset>12</bitOffset>
              <bitWidth>1</bitWidth>
            </field>
            <field>
              <name>BKP</name>
              <bitOffset>13</bitOffset>
              <bitWidth>1</bitWidth>
            </field>
            <field>
              <name>AOE</name>
              <bitOffset>14</bitOffset>
              <bitWidth>1</bitWidth>
            </field>
            <field>
              <name>MOE</name>
              <bitOffset>15</bitOffset>
              <bitWidth>1</bitWidth>
            </field>
            <field>
              <name>BKF</name>
              <bitOffset>16</bitOffset>
              <bitWidth>4</bitWidth>
            </field>
            <field>
              <name>BK2F</name>
              <bitOffset>20</bitOffset>
              <bitWidth>4</bitWidth>
            </field>
            <field>
              <name>BK2E</name>
              <bitOffset>24</bitOffset>
              <bitWidth>1</bitWidth>
            </field>
            <field>
              <name>BK2P</name>
              <bitOffset>25</bitOffset>
              <bitWidth>1</bitWidth>
            </field>
            <field>
              <name>BKDSRM</name>
              <bitOffset>26</bitOffset>
              <bitWidth>1</bitWidth>
            </field>
            <field>
              <name>BK2DSRM</name>
              <bitOffset>27</bitOffset>
              <bitWidth>1</bitWidth>
            </field>
            <field>
              <name>BKBID</name>
              <bitOffset>28</bitOffset>
              <bitWidth>1</bitWidth>
            </field>
            <field>
              <name>BK2BID</name>
              <bitOffset>29</bitOffset>
              <bitWidth>1</bitWidth>
            </field>
          </fields>
        </register>
        <register>
          <name>CCR5</name>
          <addressOffset>0x48</addressOffset>
          <size>0x20</size>
          <fields>
            <field>
              <name>CCR5</name>
              <bitOffset>0</bitOffset>
              <bitWidth>32</bitWidth>
            </field>
            <field>
              <name>GC5C1</name>
              <bitOffset>29</bitOffset>
              <bitWidth>1</bitWidth>
            </field>
            <field>
              <name>GC5C2</name>
              <bitOffset>30</bitOffset>
              <bitWidth>1</bitWidth>
            </field>
            <field>
              <name>GC5C3</name>
              <bitOffset>31</bitOffset>
              <bitWidth>1</bitWidth>
            </field>
          </fields>
        </register>
        <register>
          <name>CCR6</name>
          <addressOffset>0x4c</addressOffset>
          <size>0x20</size>
          <fields>
            <field>
              <name>CCR6</name>
              <bitOffset>0</bitOffset>
              <bitWidth>16</bitWidth>
            </field>
          </fields>
        </register>
        <register>
          <name>CCMR3</name>
          <addressOffset>0x50</addressOffset>
          <size>0x20</size>
          <fields>
            <field>
              <name>OC5FE</name>
              <bitOffset>2</bitOffset>
              <bitWidth>1</bitWidth>
            </field>
            <field>
              <name>OC5PE</name>
              <bitOffset>3</bitOffset>
              <bitWidth>1</bitWidth>
            </field>
            <field>
              <name>OC5M</name>
              <bitOffset>4</bitOffset>
              <bitWidth>13</bitWidth>
            </field>
            <field>
              <name>OC5CE</name>
              <bitOffset>7</bitOffset>
              <bitWidth>1</bitWidth>
            </field>
            <field>
              <name>OC6FE</name>
              <bitOffset>10</bitOffset>
              <bitWidth>1</bitWidth>
            </field>
            <field>
              <name>OC6PE</name>
              <bitOffset>11</bitOffset>
              <bitWidth>1</bitWidth>
            </field>
            <field>
              <name>OC6M</name>
              <bitOffset>12</bitOffset>
              <bitWidth>13</bitWidth>
            </field>
            <field>
              <name>OC6CE</name>
              <bitOffset>15</bitOffset>
              <bitWidth>1</bitWidth>
            </field>
          </fields>
        </register>
        <register>
          <name>DTR2</name>
          <addressOffset>0x54</addressOffset>
          <size>0x20</size>
          <fields>
            <field>
              <name>DTGF</name>
              <bitOffset>0</bitOffset>
              <bitWidth>8</bitWidth>
            </field>
            <field>
              <name>DTAE</name>
              <bitOffset>16</bitOffset>
              <bitWidth>1</bitWidth>
            </field>
            <field>
              <name>DTPE</name>
              <bitOffset>17</bitOffset>
              <bitWidth>1</bitWidth>
            </field>
          </fields>
        </register>
        <register>
          <name>ECR</name>
          <addressOffset>0x58</addressOffset>
          <size>0x20</size>
          <fields>
            <field>
              <name>IE</name>
              <bitOffset>0</bitOffset>
              <bitWidth>1</bitWidth>
            </field>
            <field>
              <name>IDIR</name>
              <bitOffset>1</bitOffset>
              <bitWidth>2</bitWidth>
            </field>
            <field>
              <name>FIDX</name>
              <bitOffset>5</bitOffset>
              <bitWidth>1</bitWidth>
            </field>
            <field>
              <name>IPOS</name>
              <bitOffset>6</bitOffset>
              <bitWidth>2</bitWidth>
            </field>
            <field>
              <name>PW</name>
              <bitOffset>16</bitOffset>
              <bitWidth>8</bitWidth>
            </field>
            <field>
              <name>PWPRSC</name>
              <bitOffset>24</bitOffset>
              <bitWidth>3</bitWidth>
            </field>
          </fields>
        </register>
        <register>
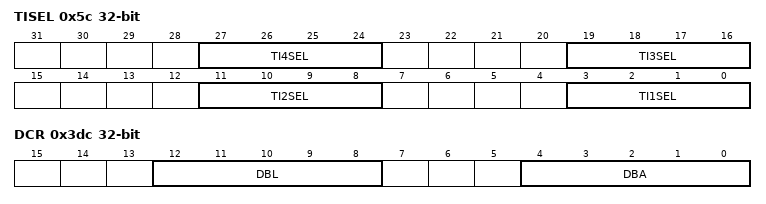
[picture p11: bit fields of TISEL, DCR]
          <name>TISEL</name>
          <addressOffset>0x5c</addressOffset>
          <size>0x20</size>
          <fields>
            <field>
              <name>TI1SEL</name>
              <bitOffset>0</bitOffset>
              <bitWidth>4</bitWidth>
            </field>
            <field>
              <name>TI2SEL</name>
              <bitOffset>8</bitOffset>
              <bitWidth>4</bitWidth>
            </field>
            <field>
              <name>TI3SEL</name>
              <bitOffset>16</bitOffset>
              <bitWidth>4</bitWidth>
            </field>
            <field>
              <name>TI4SEL</name>
              <bitOffset>24</bitOffset>
              <bitWidth>4</bitWidth>
            </field>
          </fields>
        </register>
        <register>
          <name>AF1</name>
          <addressOffset>0x60</addressOffset>
          <size>0x20</size>
        </register>
        <register>
          <name>AF2</name>
          <addressOffset>0x64</addressOffset>
          <size>0x20</size>
        </register>
        <register>
          <name>OR</name>
          <addressOffset>0x68</addressOffset>
          <size>0x20</size>
          <fields>
            <field>
              <name>HSE32EN</name>
              <bitOffset>0</bitOffset>
              <bitWidth>1</bitWidth>
            </field>
          </fields>
        </register>
        <register>
          <name>DCR</name>
          <addressOffset>0x3dc</addressOffset>
          <size>0x20</size>
          <fields>
            <field>
              <name>DBA</name>
              <bitOffset>0</bitOffset>
              <bitWidth>5</bitWidth>
            </field>
            <field>
              <name>DBL</name>
              <bitOffset>8</bitOffset>
              <bitWidth>5</bitWidth>
            </field>
          </fields>
        </register>
        <register>
          <name>DMAR</name>
          <addressOffset>0x3e0</addressOffset>
          <size>0x20</size>
          <fields>
            <field>
              <name>DMAB</name>
              <bitOffset>0</bitOffset>
              <bitWidth>32</bitWidth>
            </field>
          </fields>
        </register>
      </registers>
    </peripheral>
    <peripheral>
      <name>TIM7</name>
      <baseAddress>0x40001400</baseAddress>
      <registers>
        <register>
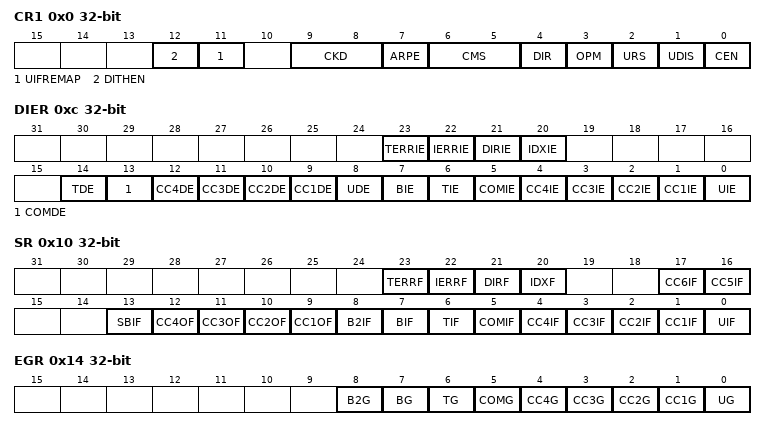
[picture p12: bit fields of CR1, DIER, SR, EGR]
          <name>CR1</name>
          <addressOffset>0x0</addressOffset>
          <size>0x20</size>
          <fields>
            <field>
              <name>CEN</name>
              <bitOffset>0</bitOffset>
              <bitWidth>1</bitWidth>
            </field>
            <field>
              <name>UDIS</name>
              <bitOffset>1</bitOffset>
              <bitWidth>1</bitWidth>
            </field>
            <field>
              <name>URS</name>
              <bitOffset>2</bitOffset>
              <bitWidth>1</bitWidth>
            </field>
            <field>
              <name>OPM</name>
              <bitOffset>3</bitOffset>
              <bitWidth>1</bitWidth>
            </field>
            <field>
              <name>DIR</name>
              <bitOffset>4</bitOffset>
              <bitWidth>1</bitWidth>
            </field>
            <field>
              <name>CMS</name>
              <bitOffset>5</bitOffset>
              <bitWidth>2</bitWidth>
            </field>
            <field>
              <name>ARPE</name>
              <bitOffset>7</bitOffset>
              <bitWidth>1</bitWidth>
            </field>
            <field>
              <name>CKD</name>
              <bitOffset>8</bitOffset>
              <bitWidth>2</bitWidth>
            </field>
            <field>
              <name>UIFREMAP</name>
              <bitOffset>11</bitOffset>
              <bitWidth>1</bitWidth>
            </field>
            <field>
              <name>DITHEN</name>
              <bitOffset>12</bitOffset>
              <bitWidth>1</bitWidth>
            </field>
          </fields>
        </register>
        <register>
          <name>CR2</name>
          <addressOffset>0x4</addressOffset>
          <size>0x20</size>
          <fields>
            <field>
              <name>CCPC</name>
              <bitOffset>0</bitOffset>
              <bitWidth>1</bitWidth>
            </field>
            <field>
              <name>CCUS</name>
              <bitOffset>2</bitOffset>
              <bitWidth>1</bitWidth>
            </field>
            <field>
              <name>CCDS</name>
              <bitOffset>3</bitOffset>
              <bitWidth>1</bitWidth>
            </field>
            <field>
              <name>MMS</name>
              <bitOffset>4</bitOffset>
              <bitWidth>22</bitWidth>
            </field>
            <field>
              <name>TI1S</name>
              <bitOffset>7</bitOffset>
              <bitWidth>1</bitWidth>
            </field>
            <field>
              <name>OIS1</name>
              <bitOffset>8</bitOffset>
              <bitWidth>1</bitWidth>
            </field>
            <field>
              <name>OIS1N</name>
              <bitOffset>9</bitOffset>
              <bitWidth>1</bitWidth>
            </field>
            <field>
              <name>OIS2</name>
              <bitOffset>10</bitOffset>
              <bitWidth>1</bitWidth>
            </field>
            <field>
              <name>OIS2N</name>
              <bitOffset>11</bitOffset>
              <bitWidth>1</bitWidth>
            </field>
            <field>
              <name>OIS3</name>
              <bitOffset>12</bitOffset>
              <bitWidth>1</bitWidth>
            </field>
            <field>
              <name>OIS3N</name>
              <bitOffset>13</bitOffset>
              <bitWidth>1</bitWidth>
            </field>
            <field>
              <name>OIS4</name>
              <bitOffset>14</bitOffset>
              <bitWidth>1</bitWidth>
            </field>
            <field>
              <name>OIS4N</name>
              <bitOffset>15</bitOffset>
              <bitWidth>1</bitWidth>
            </field>
            <field>
              <name>OIS5</name>
              <bitOffset>16</bitOffset>
              <bitWidth>1</bitWidth>
            </field>
            <field>
              <name>OIS6</name>
              <bitOffset>18</bitOffset>
              <bitWidth>1</bitWidth>
            </field>
            <field>
              <name>MMS2</name>
              <bitOffset>20</bitOffset>
              <bitWidth>4</bitWidth>
            </field>
          </fields>
        </register>
        <register>
          <name>SMCR</name>
          <addressOffset>0x8</addressOffset>
          <size>0x20</size>
          <fields>
            <field>
              <name>SMS</name>
              <bitOffset>0</bitOffset>
              <bitWidth>17</bitWidth>
            </field>
            <field>
              <name>OCCS</name>
              <bitOffset>3</bitOffset>
              <bitWidth>1</bitWidth>
            </field>
            <field>
              <name>TS</name>
              <bitOffset>4</bitOffset>
              <bitWidth>18</bitWidth>
            </field>
            <field>
              <name>MSM</name>
              <bitOffset>7</bitOffset>
              <bitWidth>1</bitWidth>
            </field>
            <field>
              <name>ETF</name>
              <bitOffset>8</bitOffset>
              <bitWidth>4</bitWidth>
            </field>
            <field>
              <name>ETPS</name>
              <bitOffset>12</bitOffset>
              <bitWidth>2</bitWidth>
            </field>
            <field>
              <name>ECE</name>
              <bitOffset>14</bitOffset>
              <bitWidth>1</bitWidth>
            </field>
            <field>
              <name>ETP</name>
              <bitOffset>15</bitOffset>
              <bitWidth>1</bitWidth>
            </field>
            <field>
              <name>SMSPE</name>
              <bitOffset>24</bitOffset>
              <bitWidth>1</bitWidth>
            </field>
            <field>
              <name>SMSPS</name>
              <bitOffset>25</bitOffset>
              <bitWidth>1</bitWidth>
            </field>
          </fields>
        </register>
        <register>
          <name>DIER</name>
          <addressOffset>0xc</addressOffset>
          <size>0x20</size>
          <fields>
            <field>
              <name>UIE</name>
              <bitOffset>0</bitOffset>
              <bitWidth>1</bitWidth>
            </field>
            <field>
              <name>CC1IE</name>
              <bitOffset>1</bitOffset>
              <bitWidth>1</bitWidth>
            </field>
            <field>
              <name>CC2IE</name>
              <bitOffset>2</bitOffset>
              <bitWidth>1</bitWidth>
            </field>
            <field>
              <name>CC3IE</name>
              <bitOffset>3</bitOffset>
              <bitWidth>1</bitWidth>
            </field>
            <field>
              <name>CC4IE</name>
              <bitOffset>4</bitOffset>
              <bitWidth>1</bitWidth>
            </field>
            <field>
              <name>COMIE</name>
              <bitOffset>5</bitOffset>
              <bitWidth>1</bitWidth>
            </field>
            <field>
              <name>TIE</name>
              <bitOffset>6</bitOffset>
              <bitWidth>1</bitWidth>
            </field>
            <field>
              <name>BIE</name>
              <bitOffset>7</bitOffset>
              <bitWidth>1</bitWidth>
            </field>
            <field>
              <name>UDE</name>
              <bitOffset>8</bitOffset>
              <bitWidth>1</bitWidth>
            </field>
            <field>
              <name>CC1DE</name>
              <bitOffset>9</bitOffset>
              <bitWidth>1</bitWidth>
            </field>
            <field>
              <name>CC2DE</name>
              <bitOffset>10</bitOffset>
              <bitWidth>1</bitWidth>
            </field>
            <field>
              <name>CC3DE</name>
              <bitOffset>11</bitOffset>
              <bitWidth>1</bitWidth>
            </field>
            <field>
              <name>CC4DE</name>
              <bitOffset>12</bitOffset>
              <bitWidth>1</bitWidth>
            </field>
            <field>
              <name>COMDE</name>
              <bitOffset>13</bitOffset>
              <bitWidth>1</bitWidth>
            </field>
            <field>
              <name>TDE</name>
              <bitOffset>14</bitOffset>
              <bitWidth>1</bitWidth>
            </field>
            <field>
              <name>IDXIE</name>
              <bitOffset>20</bitOffset>
              <bitWidth>1</bitWidth>
            </field>
            <field>
              <name>DIRIE</name>
              <bitOffset>21</bitOffset>
              <bitWidth>1</bitWidth>
            </field>
            <field>
              <name>IERRIE</name>
              <bitOffset>22</bitOffset>
              <bitWidth>1</bitWidth>
            </field>
            <field>
              <name>TERRIE</name>
              <bitOffset>23</bitOffset>
              <bitWidth>1</bitWidth>
            </field>
          </fields>
        </register>
        <register>
          <name>SR</name>
          <addressOffset>0x10</addressOffset>
          <size>0x20</size>
          <fields>
            <field>
              <name>UIF</name>
              <bitOffset>0</bitOffset>
              <bitWidth>1</bitWidth>
            </field>
            <field>
              <name>CC1IF</name>
              <bitOffset>1</bitOffset>
              <bitWidth>1</bitWidth>
            </field>
            <field>
              <name>CC2IF</name>
              <bitOffset>2</bitOffset>
              <bitWidth>1</bitWidth>
            </field>
            <field>
              <name>CC3IF</name>
              <bitOffset>3</bitOffset>
              <bitWidth>1</bitWidth>
            </field>
            <field>
              <name>CC4IF</name>
              <bitOffset>4</bitOffset>
              <bitWidth>1</bitWidth>
            </field>
            <field>
              <name>COMIF</name>
              <bitOffset>5</bitOffset>
              <bitWidth>1</bitWidth>
            </field>
            <field>
              <name>TIF</name>
              <bitOffset>6</bitOffset>
              <bitWidth>1</bitWidth>
            </field>
            <field>
              <name>BIF</name>
              <bitOffset>7</bitOffset>
              <bitWidth>1</bitWidth>
            </field>
            <field>
              <name>B2IF</name>
              <bitOffset>8</bitOffset>
              <bitWidth>1</bitWidth>
            </field>
            <field>
              <name>CC1OF</name>
              <bitOffset>9</bitOffset>
              <bitWidth>1</bitWidth>
            </field>
            <field>
              <name>CC2OF</name>
              <bitOffset>10</bitOffset>
              <bitWidth>1</bitWidth>
            </field>
            <field>
              <name>CC3OF</name>
              <bitOffset>11</bitOffset>
              <bitWidth>1</bitWidth>
            </field>
            <field>
              <name>CC4OF</name>
              <bitOffset>12</bitOffset>
              <bitWidth>1</bitWidth>
            </field>
            <field>
              <name>SBIF</name>
              <bitOffset>13</bitOffset>
              <bitWidth>1</bitWidth>
            </field>
            <field>
              <name>CC5IF</name>
              <bitOffset>16</bitOffset>
              <bitWidth>1</bitWidth>
            </field>
            <field>
              <name>CC6IF</name>
              <bitOffset>17</bitOffset>
              <bitWidth>1</bitWidth>
            </field>
            <field>
              <name>IDXF</name>
              <bitOffset>20</bitOffset>
              <bitWidth>1</bitWidth>
            </field>
            <field>
              <name>DIRF</name>
              <bitOffset>21</bitOffset>
              <bitWidth>1</bitWidth>
            </field>
            <field>
              <name>IERRF</name>
              <bitOffset>22</bitOffset>
              <bitWidth>1</bitWidth>
            </field>
            <field>
              <name>TERRF</name>
              <bitOffset>23</bitOffset>
              <bitWidth>1</bitWidth>
            </field>
          </fields>
        </register>
        <register>
          <name>EGR</name>
          <addressOffset>0x14</addressOffset>
          <size>0x20</size>
          <fields>
            <field>
              <name>UG</name>
              <bitOffset>0</bitOffset>
              <bitWidth>1</bitWidth>
            </field>
            <field>
              <name>CC1G</name>
              <bitOffset>1</bitOffset>
              <bitWidth>1</bitWidth>
            </field>
            <field>
              <name>CC2G</name>
              <bitOffset>2</bitOffset>
              <bitWidth>1</bitWidth>
            </field>
            <field>
              <name>CC3G</name>
              <bitOffset>3</bitOffset>
              <bitWidth>1</bitWidth>
            </field>
            <field>
              <name>CC4G</name>
              <bitOffset>4</bitOffset>
              <bitWidth>1</bitWidth>
            </field>
            <field>
              <name>COMG</name>
              <bitOffset>5</bitOffset>
              <bitWidth>1</bitWidth>
            </field>
            <field>
              <name>TG</name>
              <bitOffset>6</bitOffset>
              <bitWidth>1</bitWidth>
            </field>
            <field>
              <name>BG</name>
              <bitOffset>7</bitOffset>
              <bitWidth>1</bitWidth>
            </field>
            <field>
              <name>B2G</name>
              <bitOffset>8</bitOffset>
              <bitWidth>1</bitWidth>
            </field>
          </fields>
        </register>
        <register>
          <name>CCMR1</name>
          <addressOffset>0x18</addressOffset>
          <size>0x20</size>
          <fields>
            <field>
              <name>CC1S</name>
              <bitOffset>0</bitOffset>
              <bitWidth>2</bitWidth>
            </field>
            <field>
              <name>OC1FE</name>
              <bitOffset>2</bitOffset>
              <bitWidth>1</bitWidth>
            </field>
            <field>
              <name>OC1PE</name>
              <bitOffset>3</bitOffset>
              <bitWidth>1</bitWidth>
            </field>
            <field>
              <name>OC1M</name>
              <bitOffset>4</bitOffset>
              <bitWidth>13</bitWidth>
            </field>
            <field>
              <name>OC1CE</name>
              <bitOffset>7</bitOffset>
              <bitWidth>1</bitWidth>
            </field>
            <field>
              <name>CC2S</name>
              <bitOffset>8</bitOffset>
              <bitWidth>2</bitWidth>
            </field>
            <field>
              <name>OC2FE</name>
              <bitOffset>10</bitOffset>
              <bitWidth>1</bitWidth>
            </field>
            <field>
              <name>OC2PE</name>
              <bitOffset>11</bitOffset>
              <bitWidth>1</bitWidth>
            </field>
            <field>
              <name>OC2M</name>
              <bitOffset>12</bitOffset>
              <bitWidth>13</bitWidth>
            </field>
            <field>
              <name>OC2CE</name>
              <bitOffset>15</bitOffset>
              <bitWidth>1</bitWidth>
            </field>
          </fields>
        </register>
        <register>
          <name>CCMR2</name>
          <addressOffset>0x1c</addressOffset>
          <size>0x20</size>
          <fields>
            <field>
              <name>CC3S</name>
              <bitOffset>0</bitOffset>
              <bitWidth>2</bitWidth>
            </field>
            <field>
              <name>OC3FE</name>
              <bitOffset>2</bitOffset>
              <bitWidth>1</bitWidth>
            </field>
            <field>
              <name>OC3PE</name>
              <bitOffset>3</bitOffset>
              <bitWidth>1</bitWidth>
            </field>
            <field>
              <name>OC3M</name>
              <bitOffset>4</bitOffset>
              <bitWidth>13</bitWidth>
            </field>
            <field>
              <name>OC3CE</name>
              <bitOffset>7</bitOffset>
              <bitWidth>1</bitWidth>
            </field>
            <field>
              <name>CC4S</name>
              <bitOffset>8</bitOffset>
              <bitWidth>2</bitWidth>
            </field>
            <field>
              <name>OC4FE</name>
              <bitOffset>10</bitOffset>
              <bitWidth>1</bitWidth>
            </field>
            <field>
              <name>OC4PE</name>
              <bitOffset>11</bitOffset>
              <bitWidth>1</bitWidth>
            </field>
            <field>
              <name>OC4M</name>
              <bitOffset>12</bitOffset>
              <bitWidth>13</bitWidth>
            </field>
            <field>
              <name>OC4CE</name>
              <bitOffset>15</bitOffset>
              <bitWidth>1</bitWidth>
            </field>
          </fields>
        </register>
        <register>
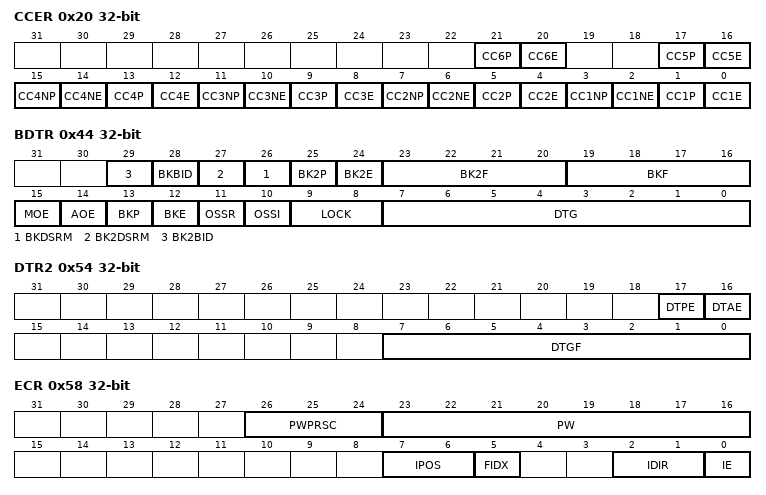
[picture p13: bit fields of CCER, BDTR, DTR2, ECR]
          <name>CCER</name>
          <addressOffset>0x20</addressOffset>
          <size>0x20</size>
          <fields>
            <field>
              <name>CC1E</name>
              <bitOffset>0</bitOffset>
              <bitWidth>1</bitWidth>
            </field>
            <field>
              <name>CC1P</name>
              <bitOffset>1</bitOffset>
              <bitWidth>1</bitWidth>
            </field>
            <field>
              <name>CC1NE</name>
              <bitOffset>2</bitOffset>
              <bitWidth>1</bitWidth>
            </field>
            <field>
              <name>CC1NP</name>
              <bitOffset>3</bitOffset>
              <bitWidth>1</bitWidth>
            </field>
            <field>
              <name>CC2E</name>
              <bitOffset>4</bitOffset>
              <bitWidth>1</bitWidth>
            </field>
            <field>
              <name>CC2P</name>
              <bitOffset>5</bitOffset>
              <bitWidth>1</bitWidth>
            </field>
            <field>
              <name>CC2NE</name>
              <bitOffset>6</bitOffset>
              <bitWidth>1</bitWidth>
            </field>
            <field>
              <name>CC2NP</name>
              <bitOffset>7</bitOffset>
              <bitWidth>1</bitWidth>
            </field>
            <field>
              <name>CC3E</name>
              <bitOffset>8</bitOffset>
              <bitWidth>1</bitWidth>
            </field>
            <field>
              <name>CC3P</name>
              <bitOffset>9</bitOffset>
              <bitWidth>1</bitWidth>
            </field>
            <field>
              <name>CC3NE</name>
              <bitOffset>10</bitOffset>
              <bitWidth>1</bitWidth>
            </field>
            <field>
              <name>CC3NP</name>
              <bitOffset>11</bitOffset>
              <bitWidth>1</bitWidth>
            </field>
            <field>
              <name>CC4E</name>
              <bitOffset>12</bitOffset>
              <bitWidth>1</bitWidth>
            </field>
            <field>
              <name>CC4P</name>
              <bitOffset>13</bitOffset>
              <bitWidth>1</bitWidth>
            </field>
            <field>
              <name>CC4NE</name>
              <bitOffset>14</bitOffset>
              <bitWidth>1</bitWidth>
            </field>
            <field>
              <name>CC4NP</name>
              <bitOffset>15</bitOffset>
              <bitWidth>1</bitWidth>
            </field>
            <field>
              <name>CC5E</name>
              <bitOffset>16</bitOffset>
              <bitWidth>1</bitWidth>
            </field>
            <field>
              <name>CC5P</name>
              <bitOffset>17</bitOffset>
              <bitWidth>1</bitWidth>
            </field>
            <field>
              <name>CC6E</name>
              <bitOffset>20</bitOffset>
              <bitWidth>1</bitWidth>
            </field>
            <field>
              <name>CC6P</name>
              <bitOffset>21</bitOffset>
              <bitWidth>1</bitWidth>
            </field>
          </fields>
        </register>
        <register>
          <name>CNT</name>
          <addressOffset>0x24</addressOffset>
          <size>0x20</size>
          <fields>
            <field>
              <name>CNT</name>
              <bitOffset>0</bitOffset>
              <bitWidth>32</bitWidth>
            </field>
            <field>
              <name>UIFCPY</name>
              <bitOffset>31</bitOffset>
              <bitWidth>1</bitWidth>
            </field>
          </fields>
        </register>
        <register>
          <name>PSC</name>
          <addressOffset>0x28</addressOffset>
          <size>0x20</size>
          <fields>
            <field>
              <name>PSC</name>
              <bitOffset>0</bitOffset>
              <bitWidth>16</bitWidth>
            </field>
          </fields>
        </register>
        <register>
          <name>ARR</name>
          <addressOffset>0x2c</addressOffset>
          <size>0x20</size>
          <fields>
            <field>
              <name>ARR</name>
              <bitOffset>0</bitOffset>
              <bitWidth>32</bitWidth>
            </field>
          </fields>
        </register>
        <register>
          <name>RCR</name>
          <addressOffset>0x30</addressOffset>
          <size>0x20</size>
          <fields>
            <field>
              <name>REP</name>
              <bitOffset>0</bitOffset>
              <bitWidth>16</bitWidth>
            </field>
          </fields>
        </register>
        <register>
          <name>CCR1</name>
          <addressOffset>0x34</addressOffset>
          <size>0x20</size>
          <fields>
            <field>
              <name>CCR1</name>
              <bitOffset>0</bitOffset>
              <bitWidth>16</bitWidth>
            </field>
          </fields>
        </register>
        <register>
          <name>CCR2</name>
          <addressOffset>0x38</addressOffset>
          <size>0x20</size>
          <fields>
            <field>
              <name>CCR2</name>
              <bitOffset>0</bitOffset>
              <bitWidth>16</bitWidth>
            </field>
          </fields>
        </register>
        <register>
          <name>CCR3</name>
          <addressOffset>0x3c</addressOffset>
          <size>0x20</size>
          <fields>
            <field>
              <name>CCR3</name>
              <bitOffset>0</bitOffset>
              <bitWidth>16</bitWidth>
            </field>
          </fields>
        </register>
        <register>
          <name>CCR4</name>
          <addressOffset>0x40</addressOffset>
          <size>0x20</size>
          <fields>
            <field>
              <name>CCR4</name>
              <bitOffset>0</bitOffset>
              <bitWidth>16</bitWidth>
            </field>
          </fields>
        </register>
        <register>
          <name>BDTR</name>
          <addressOffset>0x44</addressOffset>
          <size>0x20</size>
          <fields>
            <field>
              <name>DTG</name>
              <bitOffset>0</bitOffset>
              <bitWidth>8</bitWidth>
            </field>
            <field>
              <name>LOCK</name>
              <bitOffset>8</bitOffset>
              <bitWidth>2</bitWidth>
            </field>
            <field>
              <name>OSSI</name>
              <bitOffset>10</bitOffset>
              <bitWidth>1</bitWidth>
            </field>
            <field>
              <name>OSSR</name>
              <bitOffset>11</bitOffset>
              <bitWidth>1</bitWidth>
            </field>
            <field>
              <name>BKE</name>
              <bitOffset>12</bitOffset>
              <bitWidth>1</bitWidth>
            </field>
            <field>
              <name>BKP</name>
              <bitOffset>13</bitOffset>
              <bitWidth>1</bitWidth>
            </field>
            <field>
              <name>AOE</name>
              <bitOffset>14</bitOffset>
              <bitWidth>1</bitWidth>
            </field>
            <field>
              <name>MOE</name>
              <bitOffset>15</bitOffset>
              <bitWidth>1</bitWidth>
            </field>
            <field>
              <name>BKF</name>
              <bitOffset>16</bitOffset>
              <bitWidth>4</bitWidth>
            </field>
            <field>
              <name>BK2F</name>
              <bitOffset>20</bitOffset>
              <bitWidth>4</bitWidth>
            </field>
            <field>
              <name>BK2E</name>
              <bitOffset>24</bitOffset>
              <bitWidth>1</bitWidth>
            </field>
            <field>
              <name>BK2P</name>
              <bitOffset>25</bitOffset>
              <bitWidth>1</bitWidth>
            </field>
            <field>
              <name>BKDSRM</name>
              <bitOffset>26</bitOffset>
              <bitWidth>1</bitWidth>
            </field>
            <field>
              <name>BK2DSRM</name>
              <bitOffset>27</bitOffset>
              <bitWidth>1</bitWidth>
            </field>
            <field>
              <name>BKBID</name>
              <bitOffset>28</bitOffset>
              <bitWidth>1</bitWidth>
            </field>
            <field>
              <name>BK2BID</name>
              <bitOffset>29</bitOffset>
              <bitWidth>1</bitWidth>
            </field>
          </fields>
        </register>
        <register>
          <name>CCR5</name>
          <addressOffset>0x48</addressOffset>
          <size>0x20</size>
          <fields>
            <field>
              <name>CCR5</name>
              <bitOffset>0</bitOffset>
              <bitWidth>32</bitWidth>
            </field>
            <field>
              <name>GC5C1</name>
              <bitOffset>29</bitOffset>
              <bitWidth>1</bitWidth>
            </field>
            <field>
              <name>GC5C2</name>
              <bitOffset>30</bitOffset>
              <bitWidth>1</bitWidth>
            </field>
            <field>
              <name>GC5C3</name>
              <bitOffset>31</bitOffset>
              <bitWidth>1</bitWidth>
            </field>
          </fields>
        </register>
        <register>
          <name>CCR6</name>
          <addressOffset>0x4c</addressOffset>
          <size>0x20</size>
          <fields>
            <field>
              <name>CCR6</name>
              <bitOffset>0</bitOffset>
              <bitWidth>16</bitWidth>
            </field>
          </fields>
        </register>
        <register>
          <name>CCMR3</name>
          <addressOffset>0x50</addressOffset>
          <size>0x20</size>
          <fields>
            <field>
              <name>OC5FE</name>
              <bitOffset>2</bitOffset>
              <bitWidth>1</bitWidth>
            </field>
            <field>
              <name>OC5PE</name>
              <bitOffset>3</bitOffset>
              <bitWidth>1</bitWidth>
            </field>
            <field>
              <name>OC5M</name>
              <bitOffset>4</bitOffset>
              <bitWidth>13</bitWidth>
            </field>
            <field>
              <name>OC5CE</name>
              <bitOffset>7</bitOffset>
              <bitWidth>1</bitWidth>
            </field>
            <field>
              <name>OC6FE</name>
              <bitOffset>10</bitOffset>
              <bitWidth>1</bitWidth>
            </field>
            <field>
              <name>OC6PE</name>
              <bitOffset>11</bitOffset>
              <bitWidth>1</bitWidth>
            </field>
            <field>
              <name>OC6M</name>
              <bitOffset>12</bitOffset>
              <bitWidth>13</bitWidth>
            </field>
            <field>
              <name>OC6CE</name>
              <bitOffset>15</bitOffset>
              <bitWidth>1</bitWidth>
            </field>
          </fields>
        </register>
        <register>
          <name>DTR2</name>
          <addressOffset>0x54</addressOffset>
          <size>0x20</size>
          <fields>
            <field>
              <name>DTGF</name>
              <bitOffset>0</bitOffset>
              <bitWidth>8</bitWidth>
            </field>
            <field>
              <name>DTAE</name>
              <bitOffset>16</bitOffset>
              <bitWidth>1</bitWidth>
            </field>
            <field>
              <name>DTPE</name>
              <bitOffset>17</bitOffset>
              <bitWidth>1</bitWidth>
            </field>
          </fields>
        </register>
        <register>
          <name>ECR</name>
          <addressOffset>0x58</addressOffset>
          <size>0x20</size>
          <fields>
            <field>
              <name>IE</name>
              <bitOffset>0</bitOffset>
              <bitWidth>1</bitWidth>
            </field>
            <field>
              <name>IDIR</name>
              <bitOffset>1</bitOffset>
              <bitWidth>2</bitWidth>
            </field>
            <field>
              <name>FIDX</name>
              <bitOffset>5</bitOffset>
              <bitWidth>1</bitWidth>
            </field>
            <field>
              <name>IPOS</name>
              <bitOffset>6</bitOffset>
              <bitWidth>2</bitWidth>
            </field>
            <field>
              <name>PW</name>
              <bitOffset>16</bitOffset>
              <bitWidth>8</bitWidth>
            </field>
            <field>
              <name>PWPRSC</name>
              <bitOffset>24</bitOffset>
              <bitWidth>3</bitWidth>
            </field>
          </fields>
        </register>
        <register>
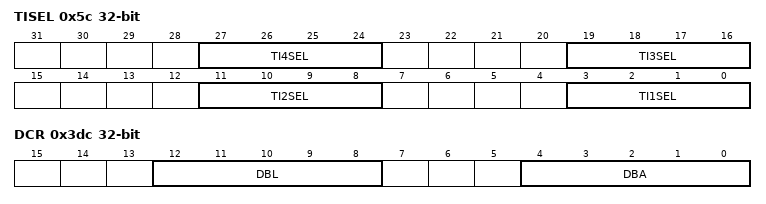
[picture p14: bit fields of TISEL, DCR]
          <name>TISEL</name>
          <addressOffset>0x5c</addressOffset>
          <size>0x20</size>
          <fields>
            <field>
              <name>TI1SEL</name>
              <bitOffset>0</bitOffset>
              <bitWidth>4</bitWidth>
            </field>
            <field>
              <name>TI2SEL</name>
              <bitOffset>8</bitOffset>
              <bitWidth>4</bitWidth>
            </field>
            <field>
              <name>TI3SEL</name>
              <bitOffset>16</bitOffset>
              <bitWidth>4</bitWidth>
            </field>
            <field>
              <name>TI4SEL</name>
              <bitOffset>24</bitOffset>
              <bitWidth>4</bitWidth>
            </field>
          </fields>
        </register>
        <register>
          <name>AF1</name>
          <addressOffset>0x60</addressOffset>
          <size>0x20</size>
        </register>
        <register>
          <name>AF2</name>
          <addressOffset>0x64</addressOffset>
          <size>0x20</size>
        </register>
        <register>
          <name>OR</name>
          <addressOffset>0x68</addressOffset>
          <size>0x20</size>
          <fields>
            <field>
              <name>HSE32EN</name>
              <bitOffset>0</bitOffset>
              <bitWidth>1</bitWidth>
            </field>
          </fields>
        </register>
        <register>
          <name>DCR</name>
          <addressOffset>0x3dc</addressOffset>
          <size>0x20</size>
          <fields>
            <field>
              <name>DBA</name>
              <bitOffset>0</bitOffset>
              <bitWidth>5</bitWidth>
            </field>
            <field>
              <name>DBL</name>
              <bitOffset>8</bitOffset>
              <bitWidth>5</bitWidth>
            </field>
          </fields>
        </register>
        <register>
          <name>DMAR</name>
          <addressOffset>0x3e0</addressOffset>
          <size>0x20</size>
          <fields>
            <field>
              <name>DMAB</name>
              <bitOffset>0</bitOffset>
              <bitWidth>32</bitWidth>
            </field>
          </fields>
        </register>
      </registers>
    </peripheral>
    <peripheral>
      <name>CRS</name>
      <baseAddress>0x40002000</baseAddress>
      <registers>
        <register>
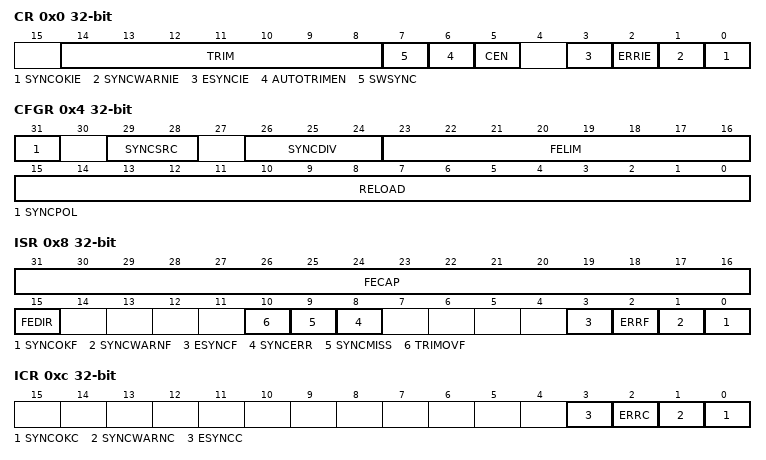
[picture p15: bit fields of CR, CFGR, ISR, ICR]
          <name>CR</name>
          <addressOffset>0x0</addressOffset>
          <size>0x20</size>
          <fields>
            <field>
              <name>SYNCOKIE</name>
              <bitOffset>0</bitOffset>
              <bitWidth>1</bitWidth>
            </field>
            <field>
              <name>SYNCWARNIE</name>
              <bitOffset>1</bitOffset>
              <bitWidth>1</bitWidth>
            </field>
            <field>
              <name>ERRIE</name>
              <bitOffset>2</bitOffset>
              <bitWidth>1</bitWidth>
            </field>
            <field>
              <name>ESYNCIE</name>
              <bitOffset>3</bitOffset>
              <bitWidth>1</bitWidth>
            </field>
            <field>
              <name>CEN</name>
              <bitOffset>5</bitOffset>
              <bitWidth>1</bitWidth>
            </field>
            <field>
              <name>AUTOTRIMEN</name>
              <bitOffset>6</bitOffset>
              <bitWidth>1</bitWidth>
            </field>
            <field>
              <name>SWSYNC</name>
              <bitOffset>7</bitOffset>
              <bitWidth>1</bitWidth>
            </field>
            <field>
              <name>TRIM</name>
              <bitOffset>8</bitOffset>
              <bitWidth>7</bitWidth>
            </field>
          </fields>
        </register>
        <register>
          <name>CFGR</name>
          <addressOffset>0x4</addressOffset>
          <size>0x20</size>
          <fields>
            <field>
              <name>RELOAD</name>
              <bitOffset>0</bitOffset>
              <bitWidth>16</bitWidth>
            </field>
            <field>
              <name>FELIM</name>
              <bitOffset>16</bitOffset>
              <bitWidth>8</bitWidth>
            </field>
            <field>
              <name>SYNCDIV</name>
              <bitOffset>24</bitOffset>
              <bitWidth>3</bitWidth>
            </field>
            <field>
              <name>SYNCSRC</name>
              <bitOffset>28</bitOffset>
              <bitWidth>2</bitWidth>
            </field>
            <field>
              <name>SYNCPOL</name>
              <bitOffset>31</bitOffset>
              <bitWidth>1</bitWidth>
            </field>
          </fields>
        </register>
        <register>
          <name>ISR</name>
          <addressOffset>0x8</addressOffset>
          <size>0x20</size>
          <fields>
            <field>
              <name>SYNCOKF</name>
              <bitOffset>0</bitOffset>
              <bitWidth>1</bitWidth>
            </field>
            <field>
              <name>SYNCWARNF</name>
              <bitOffset>1</bitOffset>
              <bitWidth>1</bitWidth>
            </field>
            <field>
              <name>ERRF</name>
              <bitOffset>2</bitOffset>
              <bitWidth>1</bitWidth>
            </field>
            <field>
              <name>ESYNCF</name>
              <bitOffset>3</bitOffset>
              <bitWidth>1</bitWidth>
            </field>
            <field>
              <name>SYNCERR</name>
              <bitOffset>8</bitOffset>
              <bitWidth>1</bitWidth>
            </field>
            <field>
              <name>SYNCMISS</name>
              <bitOffset>9</bitOffset>
              <bitWidth>1</bitWidth>
            </field>
            <field>
              <name>TRIMOVF</name>
              <bitOffset>10</bitOffset>
              <bitWidth>1</bitWidth>
            </field>
            <field>
              <name>FEDIR</name>
              <bitOffset>15</bitOffset>
              <bitWidth>1</bitWidth>
            </field>
            <field>
              <name>FECAP</name>
              <bitOffset>16</bitOffset>
              <bitWidth>16</bitWidth>
            </field>
          </fields>
        </register>
        <register>
          <name>ICR</name>
          <addressOffset>0xc</addressOffset>
          <size>0x20</size>
          <fields>
            <field>
              <name>SYNCOKC</name>
              <bitOffset>0</bitOffset>
              <bitWidth>1</bitWidth>
            </field>
            <field>
              <name>SYNCWARNC</name>
              <bitOffset>1</bitOffset>
              <bitWidth>1</bitWidth>
            </field>
            <field>
              <name>ERRC</name>
              <bitOffset>2</bitOffset>
              <bitWidth>1</bitWidth>
            </field>
            <field>
              <name>ESYNCC</name>
              <bitOffset>3</bitOffset>
              <bitWidth>1</bitWidth>
            </field>
          </fields>
        </register>
      </registers>
    </peripheral>
    <peripheral>
      <name>TAMP</name>
      <baseAddress>0x40002400</baseAddress>
      <registers>
        <register>
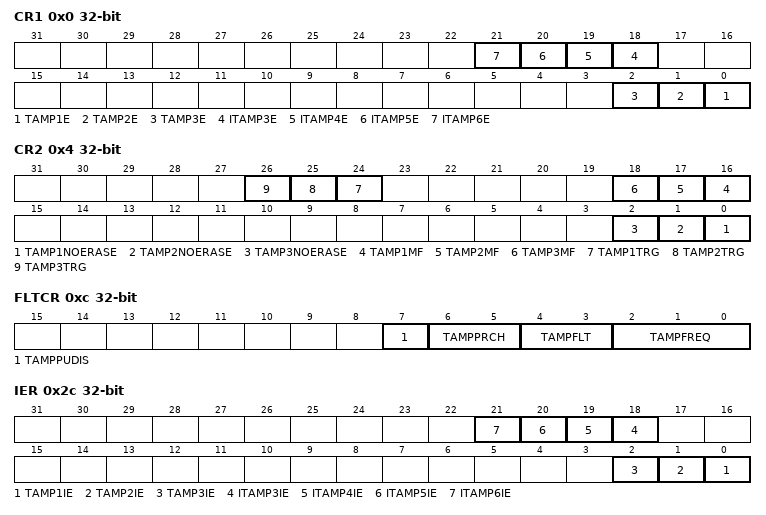
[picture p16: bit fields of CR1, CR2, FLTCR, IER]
          <name>CR1</name>
          <addressOffset>0x0</addressOffset>
          <size>0x20</size>
          <fields>
            <field>
              <name>TAMP1E</name>
              <bitOffset>0</bitOffset>
              <bitWidth>1</bitWidth>
            </field>
            <field>
              <name>TAMP2E</name>
              <bitOffset>1</bitOffset>
              <bitWidth>1</bitWidth>
            </field>
            <field>
              <name>TAMP3E</name>
              <bitOffset>2</bitOffset>
              <bitWidth>1</bitWidth>
            </field>
            <field>
              <name>ITAMP3E</name>
              <bitOffset>18</bitOffset>
              <bitWidth>1</bitWidth>
            </field>
            <field>
              <name>ITAMP4E</name>
              <bitOffset>19</bitOffset>
              <bitWidth>1</bitWidth>
            </field>
            <field>
              <name>ITAMP5E</name>
              <bitOffset>20</bitOffset>
              <bitWidth>1</bitWidth>
            </field>
            <field>
              <name>ITAMP6E</name>
              <bitOffset>21</bitOffset>
              <bitWidth>1</bitWidth>
            </field>
          </fields>
        </register>
        <register>
          <name>CR2</name>
          <addressOffset>0x4</addressOffset>
          <size>0x20</size>
          <fields>
            <field>
              <name>TAMP1NOERASE</name>
              <bitOffset>0</bitOffset>
              <bitWidth>1</bitWidth>
            </field>
            <field>
              <name>TAMP2NOERASE</name>
              <bitOffset>1</bitOffset>
              <bitWidth>1</bitWidth>
            </field>
            <field>
              <name>TAMP3NOERASE</name>
              <bitOffset>2</bitOffset>
              <bitWidth>1</bitWidth>
            </field>
            <field>
              <name>TAMP1MF</name>
              <bitOffset>16</bitOffset>
              <bitWidth>1</bitWidth>
            </field>
            <field>
              <name>TAMP2MF</name>
              <bitOffset>17</bitOffset>
              <bitWidth>1</bitWidth>
            </field>
            <field>
              <name>TAMP3MF</name>
              <bitOffset>18</bitOffset>
              <bitWidth>1</bitWidth>
            </field>
            <field>
              <name>TAMP1TRG</name>
              <bitOffset>24</bitOffset>
              <bitWidth>1</bitWidth>
            </field>
            <field>
              <name>TAMP2TRG</name>
              <bitOffset>25</bitOffset>
              <bitWidth>1</bitWidth>
            </field>
            <field>
              <name>TAMP3TRG</name>
              <bitOffset>26</bitOffset>
              <bitWidth>1</bitWidth>
            </field>
          </fields>
        </register>
        <register>
          <name>FLTCR</name>
          <addressOffset>0xc</addressOffset>
          <size>0x20</size>
          <fields>
            <field>
              <name>TAMPFREQ</name>
              <bitOffset>0</bitOffset>
              <bitWidth>3</bitWidth>
            </field>
            <field>
              <name>TAMPFLT</name>
              <bitOffset>3</bitOffset>
              <bitWidth>2</bitWidth>
            </field>
            <field>
              <name>TAMPPRCH</name>
              <bitOffset>5</bitOffset>
              <bitWidth>2</bitWidth>
            </field>
            <field>
              <name>TAMPPUDIS</name>
              <bitOffset>7</bitOffset>
              <bitWidth>1</bitWidth>
            </field>
          </fields>
        </register>
        <register>
          <name>IER</name>
          <addressOffset>0x2c</addressOffset>
          <size>0x20</size>
          <fields>
            <field>
              <name>TAMP1IE</name>
              <bitOffset>0</bitOffset>
              <bitWidth>1</bitWidth>
            </field>
            <field>
              <name>TAMP2IE</name>
              <bitOffset>1</bitOffset>
              <bitWidth>1</bitWidth>
            </field>
            <field>
              <name>TAMP3IE</name>
              <bitOffset>2</bitOffset>
              <bitWidth>1</bitWidth>
            </field>
            <field>
              <name>ITAMP3IE</name>
              <bitOffset>18</bitOffset>
              <bitWidth>1</bitWidth>
            </field>
            <field>
              <name>ITAMP4IE</name>
              <bitOffset>19</bitOffset>
              <bitWidth>1</bitWidth>
            </field>
            <field>
              <name>ITAMP5IE</name>
              <bitOffset>20</bitOffset>
              <bitWidth>1</bitWidth>
            </field>
            <field>
              <name>ITAMP6IE</name>
              <bitOffset>21</bitOffset>
              <bitWidth>1</bitWidth>
            </field>
          </fields>
        </register>
        <register>
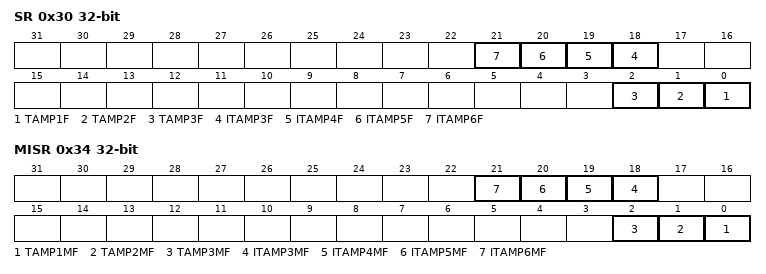
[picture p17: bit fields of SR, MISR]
          <name>SR</name>
          <addressOffset>0x30</addressOffset>
          <size>0x20</size>
          <fields>
            <field>
              <name>TAMP1F</name>
              <bitOffset>0</bitOffset>
              <bitWidth>1</bitWidth>
            </field>
            <field>
              <name>TAMP2F</name>
              <bitOffset>1</bitOffset>
              <bitWidth>1</bitWidth>
            </field>
            <field>
              <name>TAMP3F</name>
              <bitOffset>2</bitOffset>
              <bitWidth>1</bitWidth>
            </field>
            <field>
              <name>ITAMP3F</name>
              <bitOffset>18</bitOffset>
              <bitWidth>1</bitWidth>
            </field>
            <field>
              <name>ITAMP4F</name>
              <bitOffset>19</bitOffset>
              <bitWidth>1</bitWidth>
            </field>
            <field>
              <name>ITAMP5F</name>
              <bitOffset>20</bitOffset>
              <bitWidth>1</bitWidth>
            </field>
            <field>
              <name>ITAMP6F</name>
              <bitOffset>21</bitOffset>
              <bitWidth>1</bitWidth>
            </field>
          </fields>
        </register>
        <register>
          <name>MISR</name>
          <addressOffset>0x34</addressOffset>
          <size>0x20</size>
          <fields>
            <field>
              <name>TAMP1MF</name>
              <bitOffset>0</bitOffset>
              <bitWidth>1</bitWidth>
            </field>
            <field>
              <name>TAMP2MF</name>
              <bitOffset>1</bitOffset>
              <bitWidth>1</bitWidth>
            </field>
            <field>
              <name>TAMP3MF</name>
              <bitOffset>2</bitOffset>
              <bitWidth>1</bitWidth>
            </field>
            <field>
              <name>ITAMP3MF</name>
              <bitOffset>18</bitOffset>
              <bitWidth>1</bitWidth>
            </field>
            <field>
              <name>ITAMP4MF</name>
              <bitOffset>19</bitOffset>
              <bitWidth>1</bitWidth>
            </field>
            <field>
              <name>ITAMP5MF</name>
              <bitOffset>20</bitOffset>
              <bitWidth>1</bitWidth>
            </field>
            <field>
              <name>ITAMP6MF</name>
              <bitOffset>21</bitOffset>
              <bitWidth>1</bitWidth>
            </field>
          </fields>
        </register>
        <register>
          <name>SCR</name>
          <addressOffset>0x3c</addressOffset>
          <size>0x20</size>
          <fields>
            <field>
              <name>CTAMP1F</name>
              <bitOffset>0</bitOffset>
              <bitWidth>1</bitWidth>
            </field>
            <field>
              <name>CTAMP2F</name>
              <bitOffset>1</bitOffset>
              <bitWidth>1</bitWidth>
            </field>
            <field>
              <name>CTAMP3F</name>
              <bitOffset>2</bitOffset>
              <bitWidth>1</bitWidth>
            </field>
            <field>
              <name>CITAMP3F</name>
              <bitOffset>18</bitOffset>
              <bitWidth>1</bitWidth>
            </field>
            <field>
              <name>CITAMP4F</name>
              <bitOffset>19</bitOffset>
              <bitWidth>1</bitWidth>
            </field>
            <field>
              <name>CITAMP5F</name>
              <bitOffset>20</bitOffset>
              <bitWidth>1</bitWidth>
            </field>
            <field>
              <name>CITAMP6F</name>
              <bitOffset>21</bitOffset>
              <bitWidth>1</bitWidth>
            </field>
          </fields>
        </register>
        <register>
          <name>BKP0R</name>
          <addressOffset>0x100</addressOffset>
          <size>0x20</size>
        </register>
        <register>
          <name>BKP1R</name>
          <addressOffset>0x104</addressOffset>
          <size>0x20</size>
        </register>
        <register>
          <name>BKP2R</name>
          <addressOffset>0x108</addressOffset>
          <size>0x20</size>
        </register>
        <register>
          <name>BKP3R</name>
          <addressOffset>0x10c</addressOffset>
          <size>0x20</size>
        </register>
        <register>
          <name>BKP4R</name>
          <addressOffset>0x110</addressOffset>
          <size>0x20</size>
        </register>
        <register>
          <name>BKP5R</name>
          <addressOffset>0x114</addressOffset>
          <size>0x20</size>
        </register>
        <register>
          <name>BKP6R</name>
          <addressOffset>0x118</addressOffset>
          <size>0x20</size>
        </register>
        <register>
          <name>BKP7R</name>
          <addressOffset>0x11c</addressOffset>
          <size>0x20</size>
        </register>
        <register>
          <name>BKP8R</name>
          <addressOffset>0x120</addressOffset>
          <size>0x20</size>
        </register>
        <register>
          <name>BKP9R</name>
          <addressOffset>0x124</addressOffset>
          <size>0x20</size>
        </register>
        <register>
          <name>BKP10R</name>
          <addressOffset>0x128</addressOffset>
          <size>0x20</size>
        </register>
        <register>
          <name>BKP11R</name>
          <addressOffset>0x12c</addressOffset>
          <size>0x20</size>
        </register>
        <register>
          <name>BKP12R</name>
          <addressOffset>0x130</addressOffset>
          <size>0x20</size>
        </register>
        <register>
          <name>BKP13R</name>
          <addressOffset>0x134</addressOffset>
          <size>0x20</size>
        </register>
        <register>
          <name>BKP14R</name>
          <addressOffset>0x138</addressOffset>
          <size>0x20</size>
        </register>
        <register>
          <name>BKP15R</name>
          <addressOffset>0x13c</addressOffset>
          <size>0x20</size>
        </register>
        <register>
          <name>BKP16R</name>
          <addressOffset>0x140</addressOffset>
          <size>0x20</size>
        </register>
        <register>
          <name>BKP17R</name>
          <addressOffset>0x144</addressOffset>
          <size>0x20</size>
        </register>
        <register>
          <name>BKP18R</name>
          <addressOffset>0x148</addressOffset>
          <size>0x20</size>
        </register>
        <register>
          <name>BKP19R</name>
          <addressOffset>0x14c</addressOffset>
          <size>0x20</size>
        </register>
        <register>
          <name>BKP20R</name>
          <addressOffset>0x150</addressOffset>
          <size>0x20</size>
        </register>
        <register>
          <name>BKP21R</name>
          <addressOffset>0x154</addressOffset>
          <size>0x20</size>
        </register>
        <register>
          <name>BKP22R</name>
          <addressOffset>0x158</addressOffset>
          <size>0x20</size>
        </register>
        <register>
          <name>BKP23R</name>
          <addressOffset>0x15c</addressOffset>
          <size>0x20</size>
        </register>
        <register>
          <name>BKP24R</name>
          <addressOffset>0x160</addressOffset>
          <size>0x20</size>
        </register>
        <register>
          <name>BKP25R</name>
          <addressOffset>0x164</addressOffset>
          <size>0x20</size>
        </register>
        <register>
          <name>BKP26R</name>
          <addressOffset>0x168</addressOffset>
          <size>0x20</size>
        </register>
        <register>
          <name>BKP27R</name>
          <addressOffset>0x16c</addressOffset>
          <size>0x20</size>
        </register>
        <register>
          <name>BKP28R</name>
          <addressOffset>0x170</addressOffset>
          <size>0x20</size>
        </register>
        <register>
          <name>BKP29R</name>
          <addressOffset>0x174</addressOffset>
          <size>0x20</size>
        </register>
        <register>
          <name>BKP30R</name>
          <addressOffset>0x178</addressOffset>
          <size>0x20</size>
        </register>
        <register>
          <name>BKP31R</name>
          <addressOffset>0x17c</addressOffset>
          <size>0x20</size>
        </register>
      </registers>
    </peripheral>
    <peripheral>
      <name>RTC</name>
      <baseAddress>0x40002800</baseAddress>
      <registers>
        <register>
          <name>TR</name>
          <addressOffset>0x0</addressOffset>
          <size>0x20</size>
          <fields>
            <field>
              <name>SU</name>
              <bitOffset>0</bitOffset>
              <bitWidth>4</bitWidth>
            </field>
            <field>
              <name>ST</name>
              <bitOffset>4</bitOffset>
              <bitWidth>3</bitWidth>
            </field>
            <field>
              <name>MNU</name>
              <bitOffset>8</bitOffset>
              <bitWidth>4</bitWidth>
            </field>
            <field>
              <name>MNT</name>
              <bitOffset>12</bitOffset>
              <bitWidth>3</bitWidth>
            </field>
            <field>
              <name>HU</name>
              <bitOffset>16</bitOffset>
              <bitWidth>4</bitWidth>
            </field>
            <field>
              <name>HT</name>
              <bitOffset>20</bitOffset>
              <bitWidth>2</bitWidth>
            </field>
            <field>
              <name>PM</name>
              <bitOffset>22</bitOffset>
              <bitWidth>1</bitWidth>
            </field>
          </fields>
        </register>
        <register>
          <name>DR</name>
          <addressOffset>0x4</addressOffset>
          <size>0x20</size>
          <fields>
            <field>
              <name>DU</name>
              <bitOffset>0</bitOffset>
              <bitWidth>4</bitWidth>
            </field>
            <field>
              <name>DT</name>
              <bitOffset>4</bitOffset>
              <bitWidth>2</bitWidth>
            </field>
            <field>
              <name>MU</name>
              <bitOffset>8</bitOffset>
              <bitWidth>4</bitWidth>
            </field>
            <field>
              <name>MT</name>
              <bitOffset>12</bitOffset>
              <bitWidth>1</bitWidth>
            </field>
            <field>
              <name>WDU</name>
              <bitOffset>13</bitOffset>
              <bitWidth>3</bitWidth>
            </field>
            <field>
              <name>YU</name>
              <bitOffset>16</bitOffset>
              <bitWidth>4</bitWidth>
            </field>
            <field>
              <name>YT</name>
              <bitOffset>20</bitOffset>
              <bitWidth>4</bitWidth>
            </field>
          </fields>
        </register>
        <register>
          <name>SSR</name>
          <addressOffset>0x8</addressOffset>
          <size>0x20</size>
          <fields>
            <field>
              <name>SS</name>
              <bitOffset>0</bitOffset>
              <bitWidth>16</bitWidth>
            </field>
          </fields>
        </register>
        <register>
          <name>ICSR</name>
          <addressOffset>0xc</addressOffset>
          <size>0x20</size>
          <fields>
            <field>
              <name>ALRAWF</name>
              <bitOffset>0</bitOffset>
              <bitWidth>1</bitWidth>
            </field>
            <field>
              <name>ALRBWF</name>
              <bitOffset>1</bitOffset>
              <bitWidth>1</bitWidth>
            </field>
            <field>
              <name>WUTWF</name>
              <bitOffset>2</bitOffset>
              <bitWidth>1</bitWidth>
            </field>
            <field>
              <name>SHPF</name>
              <bitOffset>3</bitOffset>
              <bitWidth>1</bitWidth>
            </field>
            <field>
              <name>INITS</name>
              <bitOffset>4</bitOffset>
              <bitWidth>1</bitWidth>
            </field>
            <field>
              <name>RSF</name>
              <bitOffset>5</bitOffset>
              <bitWidth>1</bitWidth>
            </field>
            <field>
              <name>INITF</name>
              <bitOffset>6</bitOffset>
              <bitWidth>1</bitWidth>
            </field>
            <field>
              <name>INIT</name>
              <bitOffset>7</bitOffset>
              <bitWidth>1</bitWidth>
            </field>
            <field>
              <name>RECALPF</name>
              <bitOffset>16</bitOffset>
              <bitWidth>1</bitWidth>
            </field>
          </fields>
        </register>
        <register>
          <name>PRER</name>
          <addressOffset>0x10</addressOffset>
          <size>0x20</size>
          <fields>
            <field>
              <name>PREDIV_S</name>
              <bitOffset>0</bitOffset>
              <bitWidth>15</bitWidth>
            </field>
            <field>
              <name>PREDIV_A</name>
              <bitOffset>16</bitOffset>
              <bitWidth>7</bitWidth>
            </field>
          </fields>
        </register>
        <register>
          <name>WUTR</name>
          <addressOffset>0x14</addressOffset>
          <size>0x20</size>
          <fields>
            <field>
              <name>WUT</name>
              <bitOffset>0</bitOffset>
              <bitWidth>16</bitWidth>
            </field>
          </fields>
        </register>
        <register>
          <name>CR</name>
          <addressOffset>0x18</addressOffset>
          <size>0x20</size>
          <fields>
            <field>
              <name>WUCKSEL</name>
              <bitOffset>0</bitOffset>
              <bitWidth>3</bitWidth>
            </field>
            <field>
              <name>TSEDGE</name>
              <bitOffset>3</bitOffset>
              <bitWidth>1</bitWidth>
            </field>
            <field>
              <name>REFCKON</name>
              <bitOffset>4</bitOffset>
              <bitWidth>1</bitWidth>
            </field>
            <field>
              <name>BYPSHAD</name>
              <bitOffset>5</bitOffset>
              <bitWidth>1</bitWidth>
            </field>
            <field>
              <name>FMT</name>
              <bitOffset>6</bitOffset>
              <bitWidth>1</bitWidth>
            </field>
            <field>
              <name>ALRAE</name>
              <bitOffset>8</bitOffset>
              <bitWidth>1</bitWidth>
            </field>
            <field>
              <name>ALRBE</name>
              <bitOffset>9</bitOffset>
              <bitWidth>1</bitWidth>
            </field>
            <field>
              <name>WUTE</name>
              <bitOffset>10</bitOffset>
              <bitWidth>1</bitWidth>
            </field>
            <field>
              <name>TSE</name>
              <bitOffset>11</bitOffset>
              <bitWidth>1</bitWidth>
            </field>
            <field>
              <name>ALRAIE</name>
              <bitOffset>12</bitOffset>
              <bitWidth>1</bitWidth>
            </field>
            <field>
              <name>ALRBIE</name>
              <bitOffset>13</bitOffset>
              <bitWidth>1</bitWidth>
            </field>
            <field>
              <name>WUTIE</name>
              <bitOffset>14</bitOffset>
              <bitWidth>1</bitWidth>
            </field>
            <field>
              <name>TSIE</name>
              <bitOffset>15</bitOffset>
              <bitWidth>1</bitWidth>
            </field>
            <field>
              <name>ADD1H</name>
              <bitOffset>16</bitOffset>
              <bitWidth>1</bitWidth>
            </field>
            <field>
              <name>SUB1H</name>
              <bitOffset>17</bitOffset>
              <bitWidth>1</bitWidth>
            </field>
            <field>
              <name>BKP</name>
              <bitOffset>18</bitOffset>
              <bitWidth>1</bitWidth>
            </field>
            <field>
              <name>COSEL</name>
              <bitOffset>19</bitOffset>
              <bitWidth>1</bitWidth>
            </field>
            <field>
              <name>POL</name>
              <bitOffset>20</bitOffset>
              <bitWidth>1</bitWidth>
            </field>
            <field>
              <name>OSEL</name>
              <bitOffset>21</bitOffset>
              <bitWidth>2</bitWidth>
            </field>
            <field>
              <name>COE</name>
              <bitOffset>23</bitOffset>
              <bitWidth>1</bitWidth>
            </field>
            <field>
              <name>ITSE</name>
              <bitOffset>24</bitOffset>
              <bitWidth>1</bitWidth>
            </field>
            <field>
              <name>TAMPTS</name>
              <bitOffset>25</bitOffset>
              <bitWidth>1</bitWidth>
            </field>
            <field>
              <name>TAMPOE</name>
              <bitOffset>26</bitOffset>
              <bitWidth>1</bitWidth>
            </field>
            <field>
              <name>TAMPALRM_PU</name>
              <bitOffset>29</bitOffset>
              <bitWidth>1</bitWidth>
            </field>
            <field>
              <name>TAMPALRM_TYPE</name>
              <bitOffset>30</bitOffset>
              <bitWidth>1</bitWidth>
            </field>
            <field>
              <name>OUT2EN</name>
              <bitOffset>31</bitOffset>
              <bitWidth>1</bitWidth>
            </field>
          </fields>
        </register>
        <register>
          <name>WPR</name>
          <addressOffset>0x24</addressOffset>
          <size>0x20</size>
          <fields>
            <field>
              <name>KEY</name>
              <bitOffset>0</bitOffset>
              <bitWidth>8</bitWidth>
            </field>
          </fields>
        </register>
        <register>
          <name>CALR</name>
          <addressOffset>0x28</addressOffset>
          <size>0x20</size>
          <fields>
            <field>
              <name>CALM</name>
              <bitOffset>0</bitOffset>
              <bitWidth>9</bitWidth>
            </field>
            <field>
              <name>CALW16</name>
              <bitOffset>13</bitOffset>
              <bitWidth>1</bitWidth>
            </field>
            <field>
              <name>CALW8</name>
              <bitOffset>14</bitOffset>
              <bitWidth>1</bitWidth>
            </field>
            <field>
              <name>CALP</name>
              <bitOffset>15</bitOffset>
              <bitWidth>1</bitWidth>
            </field>
          </fields>
        </register>
        <register>
          <name>SHIFTR</name>
          <addressOffset>0x2c</addressOffset>
          <size>0x20</size>
          <fields>
            <field>
              <name>SUBFS</name>
              <bitOffset>0</bitOffset>
              <bitWidth>15</bitWidth>
            </field>
            <field>
              <name>ADD1S</name>
              <bitOffset>31</bitOffset>
              <bitWidth>1</bitWidth>
            </field>
          </fields>
        </register>
        <register>
          <name>TSTR</name>
          <addressOffset>0x30</addressOffset>
          <size>0x20</size>
          <fields>
            <field>
              <name>SU</name>
              <bitOffset>0</bitOffset>
              <bitWidth>4</bitWidth>
            </field>
            <field>
              <name>ST</name>
              <bitOffset>4</bitOffset>
              <bitWidth>3</bitWidth>
            </field>
            <field>
              <name>MNU</name>
              <bitOffset>8</bitOffset>
              <bitWidth>4</bitWidth>
            </field>
            <field>
              <name>MNT</name>
              <bitOffset>12</bitOffset>
              <bitWidth>3</bitWidth>
            </field>
            <field>
              <name>HU</name>
              <bitOffset>16</bitOffset>
              <bitWidth>4</bitWidth>
            </field>
            <field>
              <name>HT</name>
              <bitOffset>20</bitOffset>
              <bitWidth>2</bitWidth>
            </field>
            <field>
              <name>PM</name>
              <bitOffset>22</bitOffset>
              <bitWidth>1</bitWidth>
            </field>
          </fields>
        </register>
        <register>
          <name>TSDR</name>
          <addressOffset>0x34</addressOffset>
          <size>0x20</size>
          <fields>
            <field>
              <name>DU</name>
              <bitOffset>0</bitOffset>
              <bitWidth>4</bitWidth>
            </field>
            <field>
              <name>DT</name>
              <bitOffset>4</bitOffset>
              <bitWidth>2</bitWidth>
            </field>
            <field>
              <name>MU</name>
              <bitOffset>8</bitOffset>
              <bitWidth>4</bitWidth>
            </field>
            <field>
              <name>MT</name>
              <bitOffset>12</bitOffset>
              <bitWidth>1</bitWidth>
            </field>
            <field>
              <name>WDU</name>
              <bitOffset>13</bitOffset>
              <bitWidth>3</bitWidth>
            </field>
          </fields>
        </register>
        <register>
          <name>TSSSR</name>
          <addressOffset>0x38</addressOffset>
          <size>0x20</size>
          <fields>
            <field>
              <name>SS</name>
              <bitOffset>0</bitOffset>
              <bitWidth>16</bitWidth>
            </field>
          </fields>
        </register>
        <register>
          <name>ALRMAR</name>
          <addressOffset>0x40</addressOffset>
          <size>0x20</size>
          <fields>
            <field>
              <name>SU</name>
              <bitOffset>0</bitOffset>
              <bitWidth>4</bitWidth>
            </field>
            <field>
              <name>ST</name>
              <bitOffset>4</bitOffset>
              <bitWidth>3</bitWidth>
            </field>
            <field>
              <name>MSK1</name>
              <bitOffset>7</bitOffset>
              <bitWidth>1</bitWidth>
            </field>
            <field>
              <name>MNU</name>
              <bitOffset>8</bitOffset>
              <bitWidth>4</bitWidth>
            </field>
            <field>
              <name>MNT</name>
              <bitOffset>12</bitOffset>
              <bitWidth>3</bitWidth>
            </field>
            <field>
              <name>MSK2</name>
              <bitOffset>15</bitOffset>
              <bitWidth>1</bitWidth>
            </field>
            <field>
              <name>HU</name>
              <bitOffset>16</bitOffset>
              <bitWidth>4</bitWidth>
            </field>
            <field>
              <name>HT</name>
              <bitOffset>20</bitOffset>
              <bitWidth>2</bitWidth>
            </field>
            <field>
              <name>PM</name>
              <bitOffset>22</bitOffset>
              <bitWidth>1</bitWidth>
            </field>
            <field>
              <name>MSK3</name>
              <bitOffset>23</bitOffset>
              <bitWidth>1</bitWidth>
            </field>
            <field>
              <name>DU</name>
              <bitOffset>24</bitOffset>
              <bitWidth>4</bitWidth>
            </field>
            <field>
              <name>DT</name>
              <bitOffset>28</bitOffset>
              <bitWidth>2</bitWidth>
            </field>
            <field>
              <name>WDSEL</name>
              <bitOffset>30</bitOffset>
              <bitWidth>1</bitWidth>
            </field>
            <field>
              <name>MSK4</name>
              <bitOffset>31</bitOffset>
              <bitWidth>1</bitWidth>
            </field>
          </fields>
        </register>
        <register>
          <name>ALRMASSR</name>
          <addressOffset>0x44</addressOffset>
          <size>0x20</size>
          <fields>
            <field>
              <name>SS</name>
              <bitOffset>0</bitOffset>
              <bitWidth>15</bitWidth>
            </field>
            <field>
              <name>MASKSS</name>
              <bitOffset>24</bitOffset>
              <bitWidth>4</bitWidth>
            </field>
          </fields>
        </register>
        <register>
          <name>ALRMBR</name>
          <addressOffset>0x48</addressOffset>
          <size>0x20</size>
          <fields>
            <field>
              <name>SU</name>
              <bitOffset>0</bitOffset>
              <bitWidth>4</bitWidth>
            </field>
            <field>
              <name>ST</name>
              <bitOffset>4</bitOffset>
              <bitWidth>3</bitWidth>
            </field>
            <field>
              <name>MSK1</name>
              <bitOffset>7</bitOffset>
              <bitWidth>1</bitWidth>
            </field>
            <field>
              <name>MNU</name>
              <bitOffset>8</bitOffset>
              <bitWidth>4</bitWidth>
            </field>
            <field>
              <name>MNT</name>
              <bitOffset>12</bitOffset>
              <bitWidth>3</bitWidth>
            </field>
            <field>
              <name>MSK2</name>
              <bitOffset>15</bitOffset>
              <bitWidth>1</bitWidth>
            </field>
            <field>
              <name>HU</name>
              <bitOffset>16</bitOffset>
              <bitWidth>4</bitWidth>
            </field>
            <field>
              <name>HT</name>
              <bitOffset>20</bitOffset>
              <bitWidth>2</bitWidth>
            </field>
            <field>
              <name>PM</name>
              <bitOffset>22</bitOffset>
              <bitWidth>1</bitWidth>
            </field>
            <field>
              <name>MSK3</name>
              <bitOffset>23</bitOffset>
              <bitWidth>1</bitWidth>
            </field>
            <field>
              <name>DU</name>
              <bitOffset>24</bitOffset>
              <bitWidth>4</bitWidth>
            </field>
            <field>
              <name>DT</name>
              <bitOffset>28</bitOffset>
              <bitWidth>2</bitWidth>
            </field>
            <field>
              <name>WDSEL</name>
              <bitOffset>30</bitOffset>
              <bitWidth>1</bitWidth>
            </field>
            <field>
              <name>MSK4</name>
              <bitOffset>31</bitOffset>
              <bitWidth>1</bitWidth>
            </field>
          </fields>
        </register>
        <register>
          <name>ALRMBSSR</name>
          <addressOffset>0x4c</addressOffset>
          <size>0x20</size>
          <fields>
            <field>
              <name>SS</name>
              <bitOffset>0</bitOffset>
              <bitWidth>15</bitWidth>
            </field>
            <field>
              <name>MASKSS</name>
              <bitOffset>24</bitOffset>
              <bitWidth>4</bitWidth>
            </field>
          </fields>
        </register>
        <register>
          <name>SR</name>
          <addressOffset>0x50</addressOffset>
          <size>0x20</size>
          <fields>
            <field>
              <name>ALRAF</name>
              <bitOffset>0</bitOffset>
              <bitWidth>1</bitWidth>
            </field>
            <field>
              <name>ALRBF</name>
              <bitOffset>1</bitOffset>
              <bitWidth>1</bitWidth>
            </field>
            <field>
              <name>WUTF</name>
              <bitOffset>2</bitOffset>
              <bitWidth>1</bitWidth>
            </field>
            <field>
              <name>TSF</name>
              <bitOffset>3</bitOffset>
              <bitWidth>1</bitWidth>
            </field>
            <field>
              <name>TSOVF</name>
              <bitOffset>4</bitOffset>
              <bitWidth>1</bitWidth>
            </field>
            <field>
              <name>ITSF</name>
              <bitOffset>5</bitOffset>
              <bitWidth>1</bitWidth>
            </field>
          </fields>
        </register>
        <register>
          <name>MISR</name>
          <addressOffset>0x54</addressOffset>
          <size>0x20</size>
          <fields>
            <field>
              <name>ALRAMF</name>
              <bitOffset>0</bitOffset>
              <bitWidth>1</bitWidth>
            </field>
            <field>
              <name>ALRBMF</name>
              <bitOffset>1</bitOffset>
              <bitWidth>1</bitWidth>
            </field>
            <field>
              <name>WUTMF</name>
              <bitOffset>2</bitOffset>
              <bitWidth>1</bitWidth>
            </field>
            <field>
              <name>TSMF</name>
              <bitOffset>3</bitOffset>
              <bitWidth>1</bitWidth>
            </field>
            <field>
              <name>TSOVMF</name>
              <bitOffset>4</bitOffset>
              <bitWidth>1</bitWidth>
            </field>
            <field>
              <name>ITSMF</name>
              <bitOffset>5</bitOffset>
              <bitWidth>1</bitWidth>
            </field>
          </fields>
        </register>
        <register>
          <name>SCR</name>
          <addressOffset>0x5c</addressOffset>
          <size>0x20</size>
          <fields>
            <field>
              <name>CALRAF</name>
              <bitOffset>0</bitOffset>
              <bitWidth>1</bitWidth>
            </field>
            <field>
              <name>CALRBF</name>
              <bitOffset>1</bitOffset>
              <bitWidth>1</bitWidth>
            </field>
            <field>
              <name>CWUTF</name>
              <bitOffset>2</bitOffset>
              <bitWidth>1</bitWidth>
            </field>
            <field>
              <name>CTSF</name>
              <bitOffset>3</bitOffset>
              <bitWidth>1</bitWidth>
            </field>
            <field>
              <name>CTSOVF</name>
              <bitOffset>4</bitOffset>
              <bitWidth>1</bitWidth>
            </field>
            <field>
              <name>CITSF</name>
              <bitOffset>5</bitOffset>
              <bitWidth>1</bitWidth>
            </field>
          </fields>
        </register>
      </registers>
    </peripheral>
    <peripheral>
      <name>WWDG</name>
      <baseAddress>0x40002c00</baseAddress>
      <registers>
        <register>
          <name>CR</name>
          <addressOffset>0x0</addressOffset>
          <size>0x20</size>
          <fields>
            <field>
              <name>T</name>
              <bitOffset>0</bitOffset>
              <bitWidth>7</bitWidth>
            </field>
            <field>
              <name>WDGA</name>
              <bitOffset>7</bitOffset>
              <bitWidth>1</bitWidth>
            </field>
          </fields>
        </register>
        <register>
          <name>CFR</name>
          <addressOffset>0x4</addressOffset>
          <size>0x20</size>
          <fields>
            <field>
              <name>W</name>
              <bitOffset>0</bitOffset>
              <bitWidth>7</bitWidth>
            </field>
            <field>
              <name>EWI</name>
              <bitOffset>9</bitOffset>
              <bitWidth>1</bitWidth>
            </field>
            <field>
              <name>WDGTB</name>
              <bitOffset>11</bitOffset>
              <bitWidth>3</bitWidth>
            </field>
          </fields>
        </register>
        <register>
          <name>SR</name>
          <addressOffset>0x8</addressOffset>
          <size>0x20</size>
          <fields>
            <field>
              <name>EWIF</name>
              <bitOffset>0</bitOffset>
              <bitWidth>1</bitWidth>
            </field>
          </fields>
        </register>
      </registers>
    </peripheral>
    <peripheral>
      <name>IWDG</name>
      <baseAddress>0x40003000</baseAddress>
      <registers>
        <register>
          <name>KR</name>
          <addressOffset>0x0</addressOffset>
          <size>0x20</size>
          <fields>
            <field>
              <name>KEY</name>
              <bitOffset>0</bitOffset>
              <bitWidth>16</bitWidth>
            </field>
          </fields>
        </register>
        <register>
          <name>PR</name>
          <addressOffset>0x4</addressOffset>
          <size>0x20</size>
          <fields>
            <field>
              <name>PR</name>
              <bitOffset>0</bitOffset>
              <bitWidth>3</bitWidth>
            </field>
          </fields>
        </register>
        <register>
          <name>RLR</name>
          <addressOffset>0x8</addressOffset>
          <size>0x20</size>
          <fields>
            <field>
              <name>RL</name>
              <bitOffset>0</bitOffset>
              <bitWidth>12</bitWidth>
            </field>
          </fields>
        </register>
        <register>
          <name>SR</name>
          <addressOffset>0xc</addressOffset>
          <size>0x20</size>
          <fields>
            <field>
              <name>PVU</name>
              <bitOffset>0</bitOffset>
              <bitWidth>1</bitWidth>
            </field>
            <field>
              <name>RVU</name>
              <bitOffset>1</bitOffset>
              <bitWidth>1</bitWidth>
            </field>
            <field>
              <name>WVU</name>
              <bitOffset>2</bitOffset>
              <bitWidth>1</bitWidth>
            </field>
          </fields>
        </register>
        <register>
          <name>WINR</name>
          <addressOffset>0x10</addressOffset>
          <size>0x20</size>
          <fields>
            <field>
              <name>WIN</name>
              <bitOffset>0</bitOffset>
              <bitWidth>12</bitWidth>
            </field>
          </fields>
        </register>
      </registers>
    </peripheral>
    <peripheral>
      <name>SPI2</name>
      <baseAddress>0x40003800</baseAddress>
      <registers>
        <register>
          <name>CR1</name>
          <addressOffset>0x0</addressOffset>
          <size>0x20</size>
          <fields>
            <field>
              <name>CPHA</name>
              <bitOffset>0</bitOffset>
              <bitWidth>1</bitWidth>
            </field>
            <field>
              <name>CPOL</name>
              <bitOffset>1</bitOffset>
              <bitWidth>1</bitWidth>
            </field>
            <field>
              <name>MSTR</name>
              <bitOffset>2</bitOffset>
              <bitWidth>1</bitWidth>
            </field>
            <field>
              <name>BR</name>
              <bitOffset>3</bitOffset>
              <bitWidth>3</bitWidth>
            </field>
            <field>
              <name>SPE</name>
              <bitOffset>6</bitOffset>
              <bitWidth>1</bitWidth>
            </field>
            <field>
              <name>LSBFIRST</name>
              <bitOffset>7</bitOffset>
              <bitWidth>1</bitWidth>
            </field>
            <field>
              <name>SSI</name>
              <bitOffset>8</bitOffset>
              <bitWidth>1</bitWidth>
            </field>
            <field>
              <name>SSM</name>
              <bitOffset>9</bitOffset>
              <bitWidth>1</bitWidth>
            </field>
            <field>
              <name>RXONLY</name>
              <bitOffset>10</bitOffset>
              <bitWidth>1</bitWidth>
            </field>
            <field>
              <name>CRCL</name>
              <bitOffset>11</bitOffset>
              <bitWidth>1</bitWidth>
            </field>
            <field>
              <name>CRCNEXT</name>
              <bitOffset>12</bitOffset>
              <bitWidth>1</bitWidth>
            </field>
            <field>
              <name>CRCEN</name>
              <bitOffset>13</bitOffset>
              <bitWidth>1</bitWidth>
            </field>
            <field>
              <name>BIDIOE</name>
              <bitOffset>14</bitOffset>
              <bitWidth>1</bitWidth>
            </field>
            <field>
              <name>BIDIMODE</name>
              <bitOffset>15</bitOffset>
              <bitWidth>1</bitWidth>
            </field>
          </fields>
        </register>
        <register>
          <name>CR2</name>
          <addressOffset>0x4</addressOffset>
          <size>0x20</size>
          <fields>
            <field>
              <name>RXDMAEN</name>
              <bitOffset>0</bitOffset>
              <bitWidth>1</bitWidth>
            </field>
            <field>
              <name>TXDMAEN</name>
              <bitOffset>1</bitOffset>
              <bitWidth>1</bitWidth>
            </field>
            <field>
              <name>SSOE</name>
              <bitOffset>2</bitOffset>
              <bitWidth>1</bitWidth>
            </field>
            <field>
              <name>NSSP</name>
              <bitOffset>3</bitOffset>
              <bitWidth>1</bitWidth>
            </field>
            <field>
              <name>FRF</name>
              <bitOffset>4</bitOffset>
              <bitWidth>1</bitWidth>
            </field>
            <field>
              <name>ERRIE</name>
              <bitOffset>5</bitOffset>
              <bitWidth>1</bitWidth>
            </field>
            <field>
              <name>RXNEIE</name>
              <bitOffset>6</bitOffset>
              <bitWidth>1</bitWidth>
            </field>
            <field>
              <name>TXEIE</name>
              <bitOffset>7</bitOffset>
              <bitWidth>1</bitWidth>
            </field>
            <field>
              <name>DS</name>
              <bitOffset>8</bitOffset>
              <bitWidth>4</bitWidth>
            </field>
            <field>
              <name>FRXTH</name>
              <bitOffset>12</bitOffset>
              <bitWidth>1</bitWidth>
            </field>
            <field>
              <name>LDMARX</name>
              <bitOffset>13</bitOffset>
              <bitWidth>1</bitWidth>
            </field>
            <field>
              <name>LDMATX</name>
              <bitOffset>14</bitOffset>
              <bitWidth>1</bitWidth>
            </field>
          </fields>
        </register>
        <register>
          <name>SR</name>
          <addressOffset>0x8</addressOffset>
          <size>0x20</size>
          <fields>
            <field>
              <name>RXNE</name>
              <bitOffset>0</bitOffset>
              <bitWidth>1</bitWidth>
            </field>
            <field>
              <name>TXE</name>
              <bitOffset>1</bitOffset>
              <bitWidth>1</bitWidth>
            </field>
            <field>
              <name>CHSIDE</name>
              <bitOffset>2</bitOffset>
              <bitWidth>1</bitWidth>
            </field>
            <field>
              <name>UDR</name>
              <bitOffset>3</bitOffset>
              <bitWidth>1</bitWidth>
            </field>
            <field>
              <name>CRCERR</name>
              <bitOffset>4</bitOffset>
              <bitWidth>1</bitWidth>
            </field>
            <field>
              <name>MODF</name>
              <bitOffset>5</bitOffset>
              <bitWidth>1</bitWidth>
            </field>
            <field>
              <name>OVR</name>
              <bitOffset>6</bitOffset>
              <bitWidth>1</bitWidth>
            </field>
            <field>
              <name>BSY</name>
              <bitOffset>7</bitOffset>
              <bitWidth>1</bitWidth>
            </field>
            <field>
              <name>FRE</name>
              <bitOffset>8</bitOffset>
              <bitWidth>1</bitWidth>
            </field>
            <field>
              <name>FRLVL</name>
              <bitOffset>9</bitOffset>
              <bitWidth>2</bitWidth>
            </field>
            <field>
              <name>FTLVL</name>
              <bitOffset>11</bitOffset>
              <bitWidth>2</bitWidth>
            </field>
          </fields>
        </register>
        <register>
          <name>DR</name>
          <addressOffset>0xc</addressOffset>
          <size>0x20</size>
          <fields>
            <field>
              <name>DR</name>
              <bitOffset>0</bitOffset>
              <bitWidth>16</bitWidth>
            </field>
          </fields>
        </register>
        <register>
          <name>CRCPR</name>
          <addressOffset>0x10</addressOffset>
          <size>0x20</size>
          <fields>
            <field>
              <name>CRCPOLY</name>
              <bitOffset>0</bitOffset>
              <bitWidth>16</bitWidth>
            </field>
          </fields>
        </register>
        <register>
          <name>RXCRCR</name>
          <addressOffset>0x14</addressOffset>
          <size>0x20</size>
          <fields>
            <field>
              <name>RXCRC</name>
              <bitOffset>0</bitOffset>
              <bitWidth>16</bitWidth>
            </field>
          </fields>
        </register>
        <register>
          <name>TXCRCR</name>
          <addressOffset>0x18</addressOffset>
          <size>0x20</size>
          <fields>
            <field>
              <name>TXCRC</name>
              <bitOffset>0</bitOffset>
              <bitWidth>16</bitWidth>
            </field>
          </fields>
        </register>
        <register>
          <name>I2SCFGR</name>
          <addressOffset>0x1c</addressOffset>
          <size>0x20</size>
          <fields>
            <field>
              <name>CHLEN</name>
              <bitOffset>0</bitOffset>
              <bitWidth>1</bitWidth>
            </field>
            <field>
              <name>DATLEN</name>
              <bitOffset>1</bitOffset>
              <bitWidth>2</bitWidth>
            </field>
            <field>
              <name>CKPOL</name>
              <bitOffset>3</bitOffset>
              <bitWidth>1</bitWidth>
            </field>
            <field>
              <name>I2SSTD</name>
              <bitOffset>4</bitOffset>
              <bitWidth>2</bitWidth>
            </field>
            <field>
              <name>PCMSYNC</name>
              <bitOffset>7</bitOffset>
              <bitWidth>1</bitWidth>
            </field>
            <field>
              <name>I2SCFG</name>
              <bitOffset>8</bitOffset>
              <bitWidth>2</bitWidth>
            </field>
            <field>
              <name>I2SE</name>
              <bitOffset>10</bitOffset>
              <bitWidth>1</bitWidth>
            </field>
            <field>
              <name>I2SMOD</name>
              <bitOffset>11</bitOffset>
              <bitWidth>1</bitWidth>
            </field>
            <field>
              <name>ASTRTEN</name>
              <bitOffset>12</bitOffset>
              <bitWidth>1</bitWidth>
            </field>
          </fields>
        </register>
        <register>
          <name>I2SPR</name>
          <addressOffset>0x20</addressOffset>
          <size>0x20</size>
          <fields>
            <field>
              <name>I2SDIV</name>
              <bitOffset>0</bitOffset>
              <bitWidth>8</bitWidth>
            </field>
            <field>
              <name>ODD</name>
              <bitOffset>8</bitOffset>
              <bitWidth>1</bitWidth>
            </field>
            <field>
              <name>MCKOE</name>
              <bitOffset>9</bitOffset>
              <bitWidth>1</bitWidth>
            </field>
          </fields>
        </register>
      </registers>
    </peripheral>
    <peripheral>
      <name>SPI3</name>
      <baseAddress>0x40003c00</baseAddress>
      <registers>
        <register>
          <name>CR1</name>
          <addressOffset>0x0</addressOffset>
          <size>0x20</size>
          <fields>
            <field>
              <name>CPHA</name>
              <bitOffset>0</bitOffset>
              <bitWidth>1</bitWidth>
            </field>
            <field>
              <name>CPOL</name>
              <bitOffset>1</bitOffset>
              <bitWidth>1</bitWidth>
            </field>
            <field>
              <name>MSTR</name>
              <bitOffset>2</bitOffset>
              <bitWidth>1</bitWidth>
            </field>
            <field>
              <name>BR</name>
              <bitOffset>3</bitOffset>
              <bitWidth>3</bitWidth>
            </field>
            <field>
              <name>SPE</name>
              <bitOffset>6</bitOffset>
              <bitWidth>1</bitWidth>
            </field>
            <field>
              <name>LSBFIRST</name>
              <bitOffset>7</bitOffset>
              <bitWidth>1</bitWidth>
            </field>
            <field>
              <name>SSI</name>
              <bitOffset>8</bitOffset>
              <bitWidth>1</bitWidth>
            </field>
            <field>
              <name>SSM</name>
              <bitOffset>9</bitOffset>
              <bitWidth>1</bitWidth>
            </field>
            <field>
              <name>RXONLY</name>
              <bitOffset>10</bitOffset>
              <bitWidth>1</bitWidth>
            </field>
            <field>
              <name>CRCL</name>
              <bitOffset>11</bitOffset>
              <bitWidth>1</bitWidth>
            </field>
            <field>
              <name>CRCNEXT</name>
              <bitOffset>12</bitOffset>
              <bitWidth>1</bitWidth>
            </field>
            <field>
              <name>CRCEN</name>
              <bitOffset>13</bitOffset>
              <bitWidth>1</bitWidth>
            </field>
            <field>
              <name>BIDIOE</name>
              <bitOffset>14</bitOffset>
              <bitWidth>1</bitWidth>
            </field>
            <field>
              <name>BIDIMODE</name>
              <bitOffset>15</bitOffset>
              <bitWidth>1</bitWidth>
            </field>
          </fields>
        </register>
        <register>
          <name>CR2</name>
          <addressOffset>0x4</addressOffset>
          <size>0x20</size>
          <fields>
            <field>
              <name>RXDMAEN</name>
              <bitOffset>0</bitOffset>
              <bitWidth>1</bitWidth>
            </field>
            <field>
              <name>TXDMAEN</name>
              <bitOffset>1</bitOffset>
              <bitWidth>1</bitWidth>
            </field>
            <field>
              <name>SSOE</name>
              <bitOffset>2</bitOffset>
              <bitWidth>1</bitWidth>
            </field>
            <field>
              <name>NSSP</name>
              <bitOffset>3</bitOffset>
              <bitWidth>1</bitWidth>
            </field>
            <field>
              <name>FRF</name>
              <bitOffset>4</bitOffset>
              <bitWidth>1</bitWidth>
            </field>
            <field>
              <name>ERRIE</name>
              <bitOffset>5</bitOffset>
              <bitWidth>1</bitWidth>
            </field>
            <field>
              <name>RXNEIE</name>
              <bitOffset>6</bitOffset>
              <bitWidth>1</bitWidth>
            </field>
            <field>
              <name>TXEIE</name>
              <bitOffset>7</bitOffset>
              <bitWidth>1</bitWidth>
            </field>
            <field>
              <name>DS</name>
              <bitOffset>8</bitOffset>
              <bitWidth>4</bitWidth>
            </field>
            <field>
              <name>FRXTH</name>
              <bitOffset>12</bitOffset>
              <bitWidth>1</bitWidth>
            </field>
            <field>
              <name>LDMARX</name>
              <bitOffset>13</bitOffset>
              <bitWidth>1</bitWidth>
            </field>
            <field>
              <name>LDMATX</name>
              <bitOffset>14</bitOffset>
              <bitWidth>1</bitWidth>
            </field>
          </fields>
        </register>
        <register>
          <name>SR</name>
          <addressOffset>0x8</addressOffset>
          <size>0x20</size>
          <fields>
            <field>
              <name>RXNE</name>
              <bitOffset>0</bitOffset>
              <bitWidth>1</bitWidth>
            </field>
            <field>
              <name>TXE</name>
              <bitOffset>1</bitOffset>
              <bitWidth>1</bitWidth>
            </field>
            <field>
              <name>CHSIDE</name>
              <bitOffset>2</bitOffset>
              <bitWidth>1</bitWidth>
            </field>
            <field>
              <name>UDR</name>
              <bitOffset>3</bitOffset>
              <bitWidth>1</bitWidth>
            </field>
            <field>
              <name>CRCERR</name>
              <bitOffset>4</bitOffset>
              <bitWidth>1</bitWidth>
            </field>
            <field>
              <name>MODF</name>
              <bitOffset>5</bitOffset>
              <bitWidth>1</bitWidth>
            </field>
            <field>
              <name>OVR</name>
              <bitOffset>6</bitOffset>
              <bitWidth>1</bitWidth>
            </field>
            <field>
              <name>BSY</name>
              <bitOffset>7</bitOffset>
              <bitWidth>1</bitWidth>
            </field>
            <field>
              <name>FRE</name>
              <bitOffset>8</bitOffset>
              <bitWidth>1</bitWidth>
            </field>
            <field>
              <name>FRLVL</name>
              <bitOffset>9</bitOffset>
              <bitWidth>2</bitWidth>
            </field>
            <field>
              <name>FTLVL</name>
              <bitOffset>11</bitOffset>
              <bitWidth>2</bitWidth>
            </field>
          </fields>
        </register>
        <register>
          <name>DR</name>
          <addressOffset>0xc</addressOffset>
          <size>0x20</size>
          <fields>
            <field>
              <name>DR</name>
              <bitOffset>0</bitOffset>
              <bitWidth>16</bitWidth>
            </field>
          </fields>
        </register>
        <register>
          <name>CRCPR</name>
          <addressOffset>0x10</addressOffset>
          <size>0x20</size>
          <fields>
            <field>
              <name>CRCPOLY</name>
              <bitOffset>0</bitOffset>
              <bitWidth>16</bitWidth>
            </field>
          </fields>
        </register>
        <register>
          <name>RXCRCR</name>
          <addressOffset>0x14</addressOffset>
          <size>0x20</size>
          <fields>
            <field>
              <name>RXCRC</name>
              <bitOffset>0</bitOffset>
              <bitWidth>16</bitWidth>
            </field>
          </fields>
        </register>
        <register>
          <name>TXCRCR</name>
          <addressOffset>0x18</addressOffset>
          <size>0x20</size>
          <fields>
            <field>
              <name>TXCRC</name>
              <bitOffset>0</bitOffset>
              <bitWidth>16</bitWidth>
            </field>
          </fields>
        </register>
        <register>
          <name>I2SCFGR</name>
          <addressOffset>0x1c</addressOffset>
          <size>0x20</size>
          <fields>
            <field>
              <name>CHLEN</name>
              <bitOffset>0</bitOffset>
              <bitWidth>1</bitWidth>
            </field>
            <field>
              <name>DATLEN</name>
              <bitOffset>1</bitOffset>
              <bitWidth>2</bitWidth>
            </field>
            <field>
              <name>CKPOL</name>
              <bitOffset>3</bitOffset>
              <bitWidth>1</bitWidth>
            </field>
            <field>
              <name>I2SSTD</name>
              <bitOffset>4</bitOffset>
              <bitWidth>2</bitWidth>
            </field>
            <field>
              <name>PCMSYNC</name>
              <bitOffset>7</bitOffset>
              <bitWidth>1</bitWidth>
            </field>
            <field>
              <name>I2SCFG</name>
              <bitOffset>8</bitOffset>
              <bitWidth>2</bitWidth>
            </field>
            <field>
              <name>I2SE</name>
              <bitOffset>10</bitOffset>
              <bitWidth>1</bitWidth>
            </field>
            <field>
              <name>I2SMOD</name>
              <bitOffset>11</bitOffset>
              <bitWidth>1</bitWidth>
            </field>
            <field>
              <name>ASTRTEN</name>
              <bitOffset>12</bitOffset>
              <bitWidth>1</bitWidth>
            </field>
          </fields>
        </register>
        <register>
          <name>I2SPR</name>
          <addressOffset>0x20</addressOffset>
          <size>0x20</size>
          <fields>
            <field>
              <name>I2SDIV</name>
              <bitOffset>0</bitOffset>
              <bitWidth>8</bitWidth>
            </field>
            <field>
              <name>ODD</name>
              <bitOffset>8</bitOffset>
              <bitWidth>1</bitWidth>
            </field>
            <field>
              <name>MCKOE</name>
              <bitOffset>9</bitOffset>
              <bitWidth>1</bitWidth>
            </field>
          </fields>
        </register>
      </registers>
    </peripheral>
    <peripheral>
      <name>USART2</name>
      <baseAddress>0x40004400</baseAddress>
      <registers>
        <register>
          <name>CR1</name>
          <addressOffset>0x0</addressOffset>
          <size>0x20</size>
          <fields>
            <field>
              <name>UE</name>
              <bitOffset>0</bitOffset>
              <bitWidth>1</bitWidth>
            </field>
            <field>
              <name>UESM</name>
              <bitOffset>1</bitOffset>
              <bitWidth>1</bitWidth>
            </field>
            <field>
              <name>RE</name>
              <bitOffset>2</bitOffset>
              <bitWidth>1</bitWidth>
            </field>
            <field>
              <name>TE</name>
              <bitOffset>3</bitOffset>
              <bitWidth>1</bitWidth>
            </field>
            <field>
              <name>IDLEIE</name>
              <bitOffset>4</bitOffset>
              <bitWidth>1</bitWidth>
            </field>
            <field>
              <name>RXNEIE_RXFNEIE</name>
              <bitOffset>5</bitOffset>
              <bitWidth>1</bitWidth>
            </field>
            <field>
              <name>TCIE</name>
              <bitOffset>6</bitOffset>
              <bitWidth>1</bitWidth>
            </field>
            <field>
              <name>TXEIE_TXFNFIE</name>
              <bitOffset>7</bitOffset>
              <bitWidth>1</bitWidth>
            </field>
            <field>
              <name>PEIE</name>
              <bitOffset>8</bitOffset>
              <bitWidth>1</bitWidth>
            </field>
            <field>
              <name>PS</name>
              <bitOffset>9</bitOffset>
              <bitWidth>1</bitWidth>
            </field>
            <field>
              <name>PCE</name>
              <bitOffset>10</bitOffset>
              <bitWidth>1</bitWidth>
            </field>
            <field>
              <name>WAKE</name>
              <bitOffset>11</bitOffset>
              <bitWidth>1</bitWidth>
            </field>
            <field>
              <name>M0</name>
              <bitOffset>12</bitOffset>
              <bitWidth>1</bitWidth>
            </field>
            <field>
              <name>MME</name>
              <bitOffset>13</bitOffset>
              <bitWidth>1</bitWidth>
            </field>
            <field>
              <name>CMIE</name>
              <bitOffset>14</bitOffset>
              <bitWidth>1</bitWidth>
            </field>
            <field>
              <name>OVER8</name>
              <bitOffset>15</bitOffset>
              <bitWidth>1</bitWidth>
            </field>
            <field>
              <name>DEDT</name>
              <bitOffset>16</bitOffset>
              <bitWidth>5</bitWidth>
            </field>
            <field>
              <name>DEAT</name>
              <bitOffset>21</bitOffset>
              <bitWidth>5</bitWidth>
            </field>
            <field>
              <name>RTOIE</name>
              <bitOffset>26</bitOffset>
              <bitWidth>1</bitWidth>
            </field>
            <field>
              <name>EOBIE</name>
              <bitOffset>27</bitOffset>
              <bitWidth>1</bitWidth>
            </field>
            <field>
              <name>M1</name>
              <bitOffset>28</bitOffset>
              <bitWidth>1</bitWidth>
            </field>
            <field>
              <name>FIFOEN</name>
              <bitOffset>29</bitOffset>
              <bitWidth>1</bitWidth>
            </field>
            <field>
              <name>TXFEIE</name>
              <bitOffset>30</bitOffset>
              <bitWidth>1</bitWidth>
            </field>
            <field>
              <name>RXFFIE</name>
              <bitOffset>31</bitOffset>
              <bitWidth>1</bitWidth>
            </field>
          </fields>
        </register>
        <register>
          <name>CR2</name>
          <addressOffset>0x4</addressOffset>
          <size>0x20</size>
          <fields>
            <field>
              <name>SLVEN</name>
              <bitOffset>0</bitOffset>
              <bitWidth>1</bitWidth>
            </field>
            <field>
              <name>DIS_NSS</name>
              <bitOffset>3</bitOffset>
              <bitWidth>1</bitWidth>
            </field>
            <field>
              <name>ADDM7</name>
              <bitOffset>4</bitOffset>
              <bitWidth>1</bitWidth>
            </field>
            <field>
              <name>LBDL</name>
              <bitOffset>5</bitOffset>
              <bitWidth>1</bitWidth>
            </field>
            <field>
              <name>LBDIE</name>
              <bitOffset>6</bitOffset>
              <bitWidth>1</bitWidth>
            </field>
            <field>
              <name>LBCL</name>
              <bitOffset>8</bitOffset>
              <bitWidth>1</bitWidth>
            </field>
            <field>
              <name>CPHA</name>
              <bitOffset>9</bitOffset>
              <bitWidth>1</bitWidth>
            </field>
            <field>
              <name>CPOL</name>
              <bitOffset>10</bitOffset>
              <bitWidth>1</bitWidth>
            </field>
            <field>
              <name>CLKEN</name>
              <bitOffset>11</bitOffset>
              <bitWidth>1</bitWidth>
            </field>
            <field>
              <name>STOP</name>
              <bitOffset>12</bitOffset>
              <bitWidth>2</bitWidth>
            </field>
            <field>
              <name>LINEN</name>
              <bitOffset>14</bitOffset>
              <bitWidth>1</bitWidth>
            </field>
            <field>
              <name>SWAP</name>
              <bitOffset>15</bitOffset>
              <bitWidth>1</bitWidth>
            </field>
            <field>
              <name>RXINV</name>
              <bitOffset>16</bitOffset>
              <bitWidth>1</bitWidth>
            </field>
            <field>
              <name>TXINV</name>
              <bitOffset>17</bitOffset>
              <bitWidth>1</bitWidth>
            </field>
            <field>
              <name>DATAINV</name>
              <bitOffset>18</bitOffset>
              <bitWidth>1</bitWidth>
            </field>
            <field>
              <name>MSBFIRST</name>
              <bitOffset>19</bitOffset>
              <bitWidth>1</bitWidth>
            </field>
            <field>
              <name>ABREN</name>
              <bitOffset>20</bitOffset>
              <bitWidth>1</bitWidth>
            </field>
            <field>
              <name>ABRMODE</name>
              <bitOffset>21</bitOffset>
              <bitWidth>2</bitWidth>
            </field>
            <field>
              <name>RTOEN</name>
              <bitOffset>23</bitOffset>
              <bitWidth>1</bitWidth>
            </field>
            <field>
              <name>ADD</name>
              <bitOffset>24</bitOffset>
              <bitWidth>8</bitWidth>
            </field>
          </fields>
        </register>
        <register>
          <name>CR3</name>
          <addressOffset>0x8</addressOffset>
          <size>0x20</size>
          <fields>
            <field>
              <name>EIE</name>
              <bitOffset>0</bitOffset>
              <bitWidth>1</bitWidth>
            </field>
            <field>
              <name>IREN</name>
              <bitOffset>1</bitOffset>
              <bitWidth>1</bitWidth>
            </field>
            <field>
              <name>IRLP</name>
              <bitOffset>2</bitOffset>
              <bitWidth>1</bitWidth>
            </field>
            <field>
              <name>HDSEL</name>
              <bitOffset>3</bitOffset>
              <bitWidth>1</bitWidth>
            </field>
            <field>
              <name>NACK</name>
              <bitOffset>4</bitOffset>
              <bitWidth>1</bitWidth>
            </field>
            <field>
              <name>SCEN</name>
              <bitOffset>5</bitOffset>
              <bitWidth>1</bitWidth>
            </field>
            <field>
              <name>DMAR</name>
              <bitOffset>6</bitOffset>
              <bitWidth>1</bitWidth>
            </field>
            <field>
              <name>DMAT</name>
              <bitOffset>7</bitOffset>
              <bitWidth>1</bitWidth>
            </field>
            <field>
              <name>RTSE</name>
              <bitOffset>8</bitOffset>
              <bitWidth>1</bitWidth>
            </field>
            <field>
              <name>CTSE</name>
              <bitOffset>9</bitOffset>
              <bitWidth>1</bitWidth>
            </field>
            <field>
              <name>CTSIE</name>
              <bitOffset>10</bitOffset>
              <bitWidth>1</bitWidth>
            </field>
            <field>
              <name>ONEBIT</name>
              <bitOffset>11</bitOffset>
              <bitWidth>1</bitWidth>
            </field>
            <field>
              <name>OVRDIS</name>
              <bitOffset>12</bitOffset>
              <bitWidth>1</bitWidth>
            </field>
            <field>
              <name>DDRE</name>
              <bitOffset>13</bitOffset>
              <bitWidth>1</bitWidth>
            </field>
            <field>
              <name>DEM</name>
              <bitOffset>14</bitOffset>
              <bitWidth>1</bitWidth>
            </field>
            <field>
              <name>DEP</name>
              <bitOffset>15</bitOffset>
              <bitWidth>1</bitWidth>
            </field>
            <field>
              <name>SCARCNT</name>
              <bitOffset>17</bitOffset>
              <bitWidth>3</bitWidth>
            </field>
            <field>
              <name>WUS</name>
              <bitOffset>20</bitOffset>
              <bitWidth>2</bitWidth>
            </field>
            <field>
              <name>WUFIE</name>
              <bitOffset>22</bitOffset>
              <bitWidth>1</bitWidth>
            </field>
            <field>
              <name>TXFTIE</name>
              <bitOffset>23</bitOffset>
              <bitWidth>1</bitWidth>
            </field>
            <field>
              <name>TCBGTIE</name>
              <bitOffset>24</bitOffset>
              <bitWidth>1</bitWidth>
            </field>
            <field>
              <name>RXFTCFG</name>
              <bitOffset>25</bitOffset>
              <bitWidth>3</bitWidth>
            </field>
            <field>
              <name>RXFTIE</name>
              <bitOffset>28</bitOffset>
              <bitWidth>1</bitWidth>
            </field>
            <field>
              <name>TXFTCFG</name>
              <bitOffset>29</bitOffset>
              <bitWidth>3</bitWidth>
            </field>
          </fields>
        </register>
        <register>
          <name>BRR</name>
          <addressOffset>0xc</addressOffset>
          <size>0x20</size>
          <fields>
            <field>
              <name>LPUART</name>
              <bitOffset>0</bitOffset>
              <bitWidth>20</bitWidth>
            </field>
          </fields>
        </register>
        <register>
          <name>GTPR</name>
          <addressOffset>0x10</addressOffset>
          <size>0x20</size>
          <fields>
            <field>
              <name>PSC</name>
              <bitOffset>0</bitOffset>
              <bitWidth>8</bitWidth>
            </field>
            <field>
              <name>GT</name>
              <bitOffset>8</bitOffset>
              <bitWidth>8</bitWidth>
            </field>
          </fields>
        </register>
        <register>
          <name>RTOR</name>
          <addressOffset>0x14</addressOffset>
          <size>0x20</size>
          <fields>
            <field>
              <name>RTO</name>
              <bitOffset>0</bitOffset>
              <bitWidth>24</bitWidth>
            </field>
            <field>
              <name>BLEN</name>
              <bitOffset>24</bitOffset>
              <bitWidth>8</bitWidth>
            </field>
          </fields>
        </register>
        <register>
          <name>RQR</name>
          <addressOffset>0x18</addressOffset>
          <size>0x20</size>
          <fields>
            <field>
              <name>ABRRQ</name>
              <bitOffset>0</bitOffset>
              <bitWidth>1</bitWidth>
            </field>
            <field>
              <name>SBKRQ</name>
              <bitOffset>1</bitOffset>
              <bitWidth>1</bitWidth>
            </field>
            <field>
              <name>MMRQ</name>
              <bitOffset>2</bitOffset>
              <bitWidth>1</bitWidth>
            </field>
            <field>
              <name>RXFRQ</name>
              <bitOffset>3</bitOffset>
              <bitWidth>1</bitWidth>
            </field>
            <field>
              <name>TXFRQ</name>
              <bitOffset>4</bitOffset>
              <bitWidth>1</bitWidth>
            </field>
          </fields>
        </register>
        <register>
          <name>ISR</name>
          <addressOffset>0x1c</addressOffset>
          <size>0x20</size>
          <fields>
            <field>
              <name>PE</name>
              <bitOffset>0</bitOffset>
              <bitWidth>1</bitWidth>
            </field>
            <field>
              <name>FE</name>
              <bitOffset>1</bitOffset>
              <bitWidth>1</bitWidth>
            </field>
            <field>
              <name>NE</name>
              <bitOffset>2</bitOffset>
              <bitWidth>1</bitWidth>
            </field>
            <field>
              <name>ORE</name>
              <bitOffset>3</bitOffset>
              <bitWidth>1</bitWidth>
            </field>
            <field>
              <name>IDLE</name>
              <bitOffset>4</bitOffset>
              <bitWidth>1</bitWidth>
            </field>
            <field>
              <name>RXNE_RXFNE</name>
              <bitOffset>5</bitOffset>
              <bitWidth>1</bitWidth>
            </field>
            <field>
              <name>TC</name>
              <bitOffset>6</bitOffset>
              <bitWidth>1</bitWidth>
            </field>
            <field>
              <name>TXE_TXFNF</name>
              <bitOffset>7</bitOffset>
              <bitWidth>1</bitWidth>
            </field>
            <field>
              <name>LBDF</name>
              <bitOffset>8</bitOffset>
              <bitWidth>1</bitWidth>
            </field>
            <field>
              <name>CTSIF</name>
              <bitOffset>9</bitOffset>
              <bitWidth>1</bitWidth>
            </field>
            <field>
              <name>CTS</name>
              <bitOffset>10</bitOffset>
              <bitWidth>1</bitWidth>
            </field>
            <field>
              <name>RTOF</name>
              <bitOffset>11</bitOffset>
              <bitWidth>1</bitWidth>
            </field>
            <field>
              <name>EOBF</name>
              <bitOffset>12</bitOffset>
              <bitWidth>1</bitWidth>
            </field>
            <field>
              <name>UDR</name>
              <bitOffset>13</bitOffset>
              <bitWidth>1</bitWidth>
            </field>
            <field>
              <name>ABRE</name>
              <bitOffset>14</bitOffset>
              <bitWidth>1</bitWidth>
            </field>
            <field>
              <name>ABRF</name>
              <bitOffset>15</bitOffset>
              <bitWidth>1</bitWidth>
            </field>
            <field>
              <name>BUSY</name>
              <bitOffset>16</bitOffset>
              <bitWidth>1</bitWidth>
            </field>
            <field>
              <name>CMF</name>
              <bitOffset>17</bitOffset>
              <bitWidth>1</bitWidth>
            </field>
            <field>
              <name>SBKF</name>
              <bitOffset>18</bitOffset>
              <bitWidth>1</bitWidth>
            </field>
            <field>
              <name>RWU</name>
              <bitOffset>19</bitOffset>
              <bitWidth>1</bitWidth>
            </field>
            <field>
              <name>WUF</name>
              <bitOffset>20</bitOffset>
              <bitWidth>1</bitWidth>
            </field>
            <field>
              <name>TEACK</name>
              <bitOffset>21</bitOffset>
              <bitWidth>1</bitWidth>
            </field>
            <field>
              <name>REACK</name>
              <bitOffset>22</bitOffset>
              <bitWidth>1</bitWidth>
            </field>
            <field>
              <name>TXFE</name>
              <bitOffset>23</bitOffset>
              <bitWidth>1</bitWidth>
            </field>
            <field>
              <name>RXFF</name>
              <bitOffset>24</bitOffset>
              <bitWidth>1</bitWidth>
            </field>
            <field>
              <name>TCBGT</name>
              <bitOffset>25</bitOffset>
              <bitWidth>1</bitWidth>
            </field>
            <field>
              <name>RXFT</name>
              <bitOffset>26</bitOffset>
              <bitWidth>1</bitWidth>
            </field>
            <field>
              <name>TXFT</name>
              <bitOffset>27</bitOffset>
              <bitWidth>1</bitWidth>
            </field>
          </fields>
        </register>
        <register>
          <name>ICR</name>
          <addressOffset>0x20</addressOffset>
          <size>0x20</size>
          <fields>
            <field>
              <name>PECF</name>
              <bitOffset>0</bitOffset>
              <bitWidth>1</bitWidth>
            </field>
            <field>
              <name>FECF</name>
              <bitOffset>1</bitOffset>
              <bitWidth>1</bitWidth>
            </field>
            <field>
              <name>NECF</name>
              <bitOffset>2</bitOffset>
              <bitWidth>1</bitWidth>
            </field>
            <field>
              <name>ORECF</name>
              <bitOffset>3</bitOffset>
              <bitWidth>1</bitWidth>
            </field>
            <field>
              <name>IDLECF</name>
              <bitOffset>4</bitOffset>
              <bitWidth>1</bitWidth>
            </field>
            <field>
              <name>TXFECF</name>
              <bitOffset>5</bitOffset>
              <bitWidth>1</bitWidth>
            </field>
            <field>
              <name>TCCF</name>
              <bitOffset>6</bitOffset>
              <bitWidth>1</bitWidth>
            </field>
            <field>
              <name>TCBGTCF</name>
              <bitOffset>7</bitOffset>
              <bitWidth>1</bitWidth>
            </field>
            <field>
              <name>LBDCF</name>
              <bitOffset>8</bitOffset>
              <bitWidth>1</bitWidth>
            </field>
            <field>
              <name>CTSCF</name>
              <bitOffset>9</bitOffset>
              <bitWidth>1</bitWidth>
            </field>
            <field>
              <name>RTOCF</name>
              <bitOffset>11</bitOffset>
              <bitWidth>1</bitWidth>
            </field>
            <field>
              <name>EOBCF</name>
              <bitOffset>12</bitOffset>
              <bitWidth>1</bitWidth>
            </field>
            <field>
              <name>UDRCF</name>
              <bitOffset>13</bitOffset>
              <bitWidth>1</bitWidth>
            </field>
            <field>
              <name>CMCF</name>
              <bitOffset>17</bitOffset>
              <bitWidth>1</bitWidth>
            </field>
            <field>
              <name>WUCF</name>
              <bitOffset>20</bitOffset>
              <bitWidth>1</bitWidth>
            </field>
          </fields>
        </register>
        <register>
          <name>RDR</name>
          <addressOffset>0x24</addressOffset>
          <size>0x20</size>
          <fields>
            <field>
              <name>RDR</name>
              <bitOffset>0</bitOffset>
              <bitWidth>9</bitWidth>
            </field>
          </fields>
        </register>
        <register>
          <name>TDR</name>
          <addressOffset>0x28</addressOffset>
          <size>0x20</size>
          <fields>
            <field>
              <name>TDR</name>
              <bitOffset>0</bitOffset>
              <bitWidth>9</bitWidth>
            </field>
          </fields>
        </register>
        <register>
          <name>PRESC</name>
          <addressOffset>0x2c</addressOffset>
          <size>0x20</size>
          <fields>
            <field>
              <name>PRESCALER</name>
              <bitOffset>0</bitOffset>
              <bitWidth>4</bitWidth>
            </field>
          </fields>
        </register>
      </registers>
    </peripheral>
    <peripheral>
      <name>USART3</name>
      <baseAddress>0x40004800</baseAddress>
      <registers>
        <register>
          <name>CR1</name>
          <addressOffset>0x0</addressOffset>
          <size>0x20</size>
          <fields>
            <field>
              <name>UE</name>
              <bitOffset>0</bitOffset>
              <bitWidth>1</bitWidth>
            </field>
            <field>
              <name>UESM</name>
              <bitOffset>1</bitOffset>
              <bitWidth>1</bitWidth>
            </field>
            <field>
              <name>RE</name>
              <bitOffset>2</bitOffset>
              <bitWidth>1</bitWidth>
            </field>
            <field>
              <name>TE</name>
              <bitOffset>3</bitOffset>
              <bitWidth>1</bitWidth>
            </field>
            <field>
              <name>IDLEIE</name>
              <bitOffset>4</bitOffset>
              <bitWidth>1</bitWidth>
            </field>
            <field>
              <name>RXNEIE_RXFNEIE</name>
              <bitOffset>5</bitOffset>
              <bitWidth>1</bitWidth>
            </field>
            <field>
              <name>TCIE</name>
              <bitOffset>6</bitOffset>
              <bitWidth>1</bitWidth>
            </field>
            <field>
              <name>TXEIE_TXFNFIE</name>
              <bitOffset>7</bitOffset>
              <bitWidth>1</bitWidth>
            </field>
            <field>
              <name>PEIE</name>
              <bitOffset>8</bitOffset>
              <bitWidth>1</bitWidth>
            </field>
            <field>
              <name>PS</name>
              <bitOffset>9</bitOffset>
              <bitWidth>1</bitWidth>
            </field>
            <field>
              <name>PCE</name>
              <bitOffset>10</bitOffset>
              <bitWidth>1</bitWidth>
            </field>
            <field>
              <name>WAKE</name>
              <bitOffset>11</bitOffset>
              <bitWidth>1</bitWidth>
            </field>
            <field>
              <name>M0</name>
              <bitOffset>12</bitOffset>
              <bitWidth>1</bitWidth>
            </field>
            <field>
              <name>MME</name>
              <bitOffset>13</bitOffset>
              <bitWidth>1</bitWidth>
            </field>
            <field>
              <name>CMIE</name>
              <bitOffset>14</bitOffset>
              <bitWidth>1</bitWidth>
            </field>
            <field>
              <name>OVER8</name>
              <bitOffset>15</bitOffset>
              <bitWidth>1</bitWidth>
            </field>
            <field>
              <name>DEDT</name>
              <bitOffset>16</bitOffset>
              <bitWidth>5</bitWidth>
            </field>
            <field>
              <name>DEAT</name>
              <bitOffset>21</bitOffset>
              <bitWidth>5</bitWidth>
            </field>
            <field>
              <name>RTOIE</name>
              <bitOffset>26</bitOffset>
              <bitWidth>1</bitWidth>
            </field>
            <field>
              <name>EOBIE</name>
              <bitOffset>27</bitOffset>
              <bitWidth>1</bitWidth>
            </field>
            <field>
              <name>M1</name>
              <bitOffset>28</bitOffset>
              <bitWidth>1</bitWidth>
            </field>
            <field>
              <name>FIFOEN</name>
              <bitOffset>29</bitOffset>
              <bitWidth>1</bitWidth>
            </field>
            <field>
              <name>TXFEIE</name>
              <bitOffset>30</bitOffset>
              <bitWidth>1</bitWidth>
            </field>
            <field>
              <name>RXFFIE</name>
              <bitOffset>31</bitOffset>
              <bitWidth>1</bitWidth>
            </field>
          </fields>
        </register>
        <register>
          <name>CR2</name>
          <addressOffset>0x4</addressOffset>
          <size>0x20</size>
          <fields>
            <field>
              <name>SLVEN</name>
              <bitOffset>0</bitOffset>
              <bitWidth>1</bitWidth>
            </field>
            <field>
              <name>DIS_NSS</name>
              <bitOffset>3</bitOffset>
              <bitWidth>1</bitWidth>
            </field>
            <field>
              <name>ADDM7</name>
              <bitOffset>4</bitOffset>
              <bitWidth>1</bitWidth>
            </field>
            <field>
              <name>LBDL</name>
              <bitOffset>5</bitOffset>
              <bitWidth>1</bitWidth>
            </field>
            <field>
              <name>LBDIE</name>
              <bitOffset>6</bitOffset>
              <bitWidth>1</bitWidth>
            </field>
            <field>
              <name>LBCL</name>
              <bitOffset>8</bitOffset>
              <bitWidth>1</bitWidth>
            </field>
            <field>
              <name>CPHA</name>
              <bitOffset>9</bitOffset>
              <bitWidth>1</bitWidth>
            </field>
            <field>
              <name>CPOL</name>
              <bitOffset>10</bitOffset>
              <bitWidth>1</bitWidth>
            </field>
            <field>
              <name>CLKEN</name>
              <bitOffset>11</bitOffset>
              <bitWidth>1</bitWidth>
            </field>
            <field>
              <name>STOP</name>
              <bitOffset>12</bitOffset>
              <bitWidth>2</bitWidth>
            </field>
            <field>
              <name>LINEN</name>
              <bitOffset>14</bitOffset>
              <bitWidth>1</bitWidth>
            </field>
            <field>
              <name>SWAP</name>
              <bitOffset>15</bitOffset>
              <bitWidth>1</bitWidth>
            </field>
            <field>
              <name>RXINV</name>
              <bitOffset>16</bitOffset>
              <bitWidth>1</bitWidth>
            </field>
            <field>
              <name>TXINV</name>
              <bitOffset>17</bitOffset>
              <bitWidth>1</bitWidth>
            </field>
            <field>
              <name>DATAINV</name>
              <bitOffset>18</bitOffset>
              <bitWidth>1</bitWidth>
            </field>
            <field>
              <name>MSBFIRST</name>
              <bitOffset>19</bitOffset>
              <bitWidth>1</bitWidth>
            </field>
            <field>
              <name>ABREN</name>
              <bitOffset>20</bitOffset>
              <bitWidth>1</bitWidth>
            </field>
            <field>
              <name>ABRMODE</name>
              <bitOffset>21</bitOffset>
              <bitWidth>2</bitWidth>
            </field>
            <field>
              <name>RTOEN</name>
              <bitOffset>23</bitOffset>
              <bitWidth>1</bitWidth>
            </field>
            <field>
              <name>ADD</name>
              <bitOffset>24</bitOffset>
              <bitWidth>8</bitWidth>
            </field>
          </fields>
        </register>
        <register>
          <name>CR3</name>
          <addressOffset>0x8</addressOffset>
          <size>0x20</size>
          <fields>
            <field>
              <name>EIE</name>
              <bitOffset>0</bitOffset>
              <bitWidth>1</bitWidth>
            </field>
            <field>
              <name>IREN</name>
              <bitOffset>1</bitOffset>
              <bitWidth>1</bitWidth>
            </field>
            <field>
              <name>IRLP</name>
              <bitOffset>2</bitOffset>
              <bitWidth>1</bitWidth>
            </field>
            <field>
              <name>HDSEL</name>
              <bitOffset>3</bitOffset>
              <bitWidth>1</bitWidth>
            </field>
            <field>
              <name>NACK</name>
              <bitOffset>4</bitOffset>
              <bitWidth>1</bitWidth>
            </field>
            <field>
              <name>SCEN</name>
              <bitOffset>5</bitOffset>
              <bitWidth>1</bitWidth>
            </field>
            <field>
              <name>DMAR</name>
              <bitOffset>6</bitOffset>
              <bitWidth>1</bitWidth>
            </field>
            <field>
              <name>DMAT</name>
              <bitOffset>7</bitOffset>
              <bitWidth>1</bitWidth>
            </field>
            <field>
              <name>RTSE</name>
              <bitOffset>8</bitOffset>
              <bitWidth>1</bitWidth>
            </field>
            <field>
              <name>CTSE</name>
              <bitOffset>9</bitOffset>
              <bitWidth>1</bitWidth>
            </field>
            <field>
              <name>CTSIE</name>
              <bitOffset>10</bitOffset>
              <bitWidth>1</bitWidth>
            </field>
            <field>
              <name>ONEBIT</name>
              <bitOffset>11</bitOffset>
              <bitWidth>1</bitWidth>
            </field>
            <field>
              <name>OVRDIS</name>
              <bitOffset>12</bitOffset>
              <bitWidth>1</bitWidth>
            </field>
            <field>
              <name>DDRE</name>
              <bitOffset>13</bitOffset>
              <bitWidth>1</bitWidth>
            </field>
            <field>
              <name>DEM</name>
              <bitOffset>14</bitOffset>
              <bitWidth>1</bitWidth>
            </field>
            <field>
              <name>DEP</name>
              <bitOffset>15</bitOffset>
              <bitWidth>1</bitWidth>
            </field>
            <field>
              <name>SCARCNT</name>
              <bitOffset>17</bitOffset>
              <bitWidth>3</bitWidth>
            </field>
            <field>
              <name>WUS</name>
              <bitOffset>20</bitOffset>
              <bitWidth>2</bitWidth>
            </field>
            <field>
              <name>WUFIE</name>
              <bitOffset>22</bitOffset>
              <bitWidth>1</bitWidth>
            </field>
            <field>
              <name>TXFTIE</name>
              <bitOffset>23</bitOffset>
              <bitWidth>1</bitWidth>
            </field>
            <field>
              <name>TCBGTIE</name>
              <bitOffset>24</bitOffset>
              <bitWidth>1</bitWidth>
            </field>
            <field>
              <name>RXFTCFG</name>
              <bitOffset>25</bitOffset>
              <bitWidth>3</bitWidth>
            </field>
            <field>
              <name>RXFTIE</name>
              <bitOffset>28</bitOffset>
              <bitWidth>1</bitWidth>
            </field>
            <field>
              <name>TXFTCFG</name>
              <bitOffset>29</bitOffset>
              <bitWidth>3</bitWidth>
            </field>
          </fields>
        </register>
        <register>
          <name>BRR</name>
          <addressOffset>0xc</addressOffset>
          <size>0x20</size>
          <fields>
            <field>
              <name>LPUART</name>
              <bitOffset>0</bitOffset>
              <bitWidth>20</bitWidth>
            </field>
          </fields>
        </register>
        <register>
          <name>GTPR</name>
          <addressOffset>0x10</addressOffset>
          <size>0x20</size>
          <fields>
            <field>
              <name>PSC</name>
              <bitOffset>0</bitOffset>
              <bitWidth>8</bitWidth>
            </field>
            <field>
              <name>GT</name>
              <bitOffset>8</bitOffset>
              <bitWidth>8</bitWidth>
            </field>
          </fields>
        </register>
        <register>
          <name>RTOR</name>
          <addressOffset>0x14</addressOffset>
          <size>0x20</size>
          <fields>
            <field>
              <name>RTO</name>
              <bitOffset>0</bitOffset>
              <bitWidth>24</bitWidth>
            </field>
            <field>
              <name>BLEN</name>
              <bitOffset>24</bitOffset>
              <bitWidth>8</bitWidth>
            </field>
          </fields>
        </register>
        <register>
          <name>RQR</name>
          <addressOffset>0x18</addressOffset>
          <size>0x20</size>
          <fields>
            <field>
              <name>ABRRQ</name>
              <bitOffset>0</bitOffset>
              <bitWidth>1</bitWidth>
            </field>
            <field>
              <name>SBKRQ</name>
              <bitOffset>1</bitOffset>
              <bitWidth>1</bitWidth>
            </field>
            <field>
              <name>MMRQ</name>
              <bitOffset>2</bitOffset>
              <bitWidth>1</bitWidth>
            </field>
            <field>
              <name>RXFRQ</name>
              <bitOffset>3</bitOffset>
              <bitWidth>1</bitWidth>
            </field>
            <field>
              <name>TXFRQ</name>
              <bitOffset>4</bitOffset>
              <bitWidth>1</bitWidth>
            </field>
          </fields>
        </register>
        <register>
          <name>ISR</name>
          <addressOffset>0x1c</addressOffset>
          <size>0x20</size>
          <fields>
            <field>
              <name>PE</name>
              <bitOffset>0</bitOffset>
              <bitWidth>1</bitWidth>
            </field>
            <field>
              <name>FE</name>
              <bitOffset>1</bitOffset>
              <bitWidth>1</bitWidth>
            </field>
            <field>
              <name>NE</name>
              <bitOffset>2</bitOffset>
              <bitWidth>1</bitWidth>
            </field>
            <field>
              <name>ORE</name>
              <bitOffset>3</bitOffset>
              <bitWidth>1</bitWidth>
            </field>
            <field>
              <name>IDLE</name>
              <bitOffset>4</bitOffset>
              <bitWidth>1</bitWidth>
            </field>
            <field>
              <name>RXNE_RXFNE</name>
              <bitOffset>5</bitOffset>
              <bitWidth>1</bitWidth>
            </field>
            <field>
              <name>TC</name>
              <bitOffset>6</bitOffset>
              <bitWidth>1</bitWidth>
            </field>
            <field>
              <name>TXE_TXFNF</name>
              <bitOffset>7</bitOffset>
              <bitWidth>1</bitWidth>
            </field>
            <field>
              <name>LBDF</name>
              <bitOffset>8</bitOffset>
              <bitWidth>1</bitWidth>
            </field>
            <field>
              <name>CTSIF</name>
              <bitOffset>9</bitOffset>
              <bitWidth>1</bitWidth>
            </field>
            <field>
              <name>CTS</name>
              <bitOffset>10</bitOffset>
              <bitWidth>1</bitWidth>
            </field>
            <field>
              <name>RTOF</name>
              <bitOffset>11</bitOffset>
              <bitWidth>1</bitWidth>
            </field>
            <field>
              <name>EOBF</name>
              <bitOffset>12</bitOffset>
              <bitWidth>1</bitWidth>
            </field>
            <field>
              <name>UDR</name>
              <bitOffset>13</bitOffset>
              <bitWidth>1</bitWidth>
            </field>
            <field>
              <name>ABRE</name>
              <bitOffset>14</bitOffset>
              <bitWidth>1</bitWidth>
            </field>
            <field>
              <name>ABRF</name>
              <bitOffset>15</bitOffset>
              <bitWidth>1</bitWidth>
            </field>
            <field>
              <name>BUSY</name>
              <bitOffset>16</bitOffset>
              <bitWidth>1</bitWidth>
            </field>
            <field>
              <name>CMF</name>
              <bitOffset>17</bitOffset>
              <bitWidth>1</bitWidth>
            </field>
            <field>
              <name>SBKF</name>
              <bitOffset>18</bitOffset>
              <bitWidth>1</bitWidth>
            </field>
            <field>
              <name>RWU</name>
              <bitOffset>19</bitOffset>
              <bitWidth>1</bitWidth>
            </field>
            <field>
              <name>WUF</name>
              <bitOffset>20</bitOffset>
              <bitWidth>1</bitWidth>
            </field>
            <field>
              <name>TEACK</name>
              <bitOffset>21</bitOffset>
              <bitWidth>1</bitWidth>
            </field>
            <field>
              <name>REACK</name>
              <bitOffset>22</bitOffset>
              <bitWidth>1</bitWidth>
            </field>
            <field>
              <name>TXFE</name>
              <bitOffset>23</bitOffset>
              <bitWidth>1</bitWidth>
            </field>
            <field>
              <name>RXFF</name>
              <bitOffset>24</bitOffset>
              <bitWidth>1</bitWidth>
            </field>
            <field>
              <name>TCBGT</name>
              <bitOffset>25</bitOffset>
              <bitWidth>1</bitWidth>
            </field>
            <field>
              <name>RXFT</name>
              <bitOffset>26</bitOffset>
              <bitWidth>1</bitWidth>
            </field>
            <field>
              <name>TXFT</name>
              <bitOffset>27</bitOffset>
              <bitWidth>1</bitWidth>
            </field>
          </fields>
        </register>
        <register>
          <name>ICR</name>
          <addressOffset>0x20</addressOffset>
          <size>0x20</size>
          <fields>
            <field>
              <name>PECF</name>
              <bitOffset>0</bitOffset>
              <bitWidth>1</bitWidth>
            </field>
            <field>
              <name>FECF</name>
              <bitOffset>1</bitOffset>
              <bitWidth>1</bitWidth>
            </field>
            <field>
              <name>NECF</name>
              <bitOffset>2</bitOffset>
              <bitWidth>1</bitWidth>
            </field>
            <field>
              <name>ORECF</name>
              <bitOffset>3</bitOffset>
              <bitWidth>1</bitWidth>
            </field>
            <field>
              <name>IDLECF</name>
              <bitOffset>4</bitOffset>
              <bitWidth>1</bitWidth>
            </field>
            <field>
              <name>TXFECF</name>
              <bitOffset>5</bitOffset>
              <bitWidth>1</bitWidth>
            </field>
            <field>
              <name>TCCF</name>
              <bitOffset>6</bitOffset>
              <bitWidth>1</bitWidth>
            </field>
            <field>
              <name>TCBGTCF</name>
              <bitOffset>7</bitOffset>
              <bitWidth>1</bitWidth>
            </field>
            <field>
              <name>LBDCF</name>
              <bitOffset>8</bitOffset>
              <bitWidth>1</bitWidth>
            </field>
            <field>
              <name>CTSCF</name>
              <bitOffset>9</bitOffset>
              <bitWidth>1</bitWidth>
            </field>
            <field>
              <name>RTOCF</name>
              <bitOffset>11</bitOffset>
              <bitWidth>1</bitWidth>
            </field>
            <field>
              <name>EOBCF</name>
              <bitOffset>12</bitOffset>
              <bitWidth>1</bitWidth>
            </field>
            <field>
              <name>UDRCF</name>
              <bitOffset>13</bitOffset>
              <bitWidth>1</bitWidth>
            </field>
            <field>
              <name>CMCF</name>
              <bitOffset>17</bitOffset>
              <bitWidth>1</bitWidth>
            </field>
            <field>
              <name>WUCF</name>
              <bitOffset>20</bitOffset>
              <bitWidth>1</bitWidth>
            </field>
          </fields>
        </register>
        <register>
          <name>RDR</name>
          <addressOffset>0x24</addressOffset>
          <size>0x20</size>
          <fields>
            <field>
              <name>RDR</name>
              <bitOffset>0</bitOffset>
              <bitWidth>9</bitWidth>
            </field>
          </fields>
        </register>
        <register>
          <name>TDR</name>
          <addressOffset>0x28</addressOffset>
          <size>0x20</size>
          <fields>
            <field>
              <name>TDR</name>
              <bitOffset>0</bitOffset>
              <bitWidth>9</bitWidth>
            </field>
          </fields>
        </register>
        <register>
          <name>PRESC</name>
          <addressOffset>0x2c</addressOffset>
          <size>0x20</size>
          <fields>
            <field>
              <name>PRESCALER</name>
              <bitOffset>0</bitOffset>
              <bitWidth>4</bitWidth>
            </field>
          </fields>
        </register>
      </registers>
    </peripheral>
    <peripheral>
      <name>UART4</name>
      <baseAddress>0x40004c00</baseAddress>
      <registers>
        <register>
          <name>CR1</name>
          <addressOffset>0x0</addressOffset>
          <size>0x20</size>
          <fields>
            <field>
              <name>UE</name>
              <bitOffset>0</bitOffset>
              <bitWidth>1</bitWidth>
            </field>
            <field>
              <name>UESM</name>
              <bitOffset>1</bitOffset>
              <bitWidth>1</bitWidth>
            </field>
            <field>
              <name>RE</name>
              <bitOffset>2</bitOffset>
              <bitWidth>1</bitWidth>
            </field>
            <field>
              <name>TE</name>
              <bitOffset>3</bitOffset>
              <bitWidth>1</bitWidth>
            </field>
            <field>
              <name>IDLEIE</name>
              <bitOffset>4</bitOffset>
              <bitWidth>1</bitWidth>
            </field>
            <field>
              <name>RXNEIE_RXFNEIE</name>
              <bitOffset>5</bitOffset>
              <bitWidth>1</bitWidth>
            </field>
            <field>
              <name>TCIE</name>
              <bitOffset>6</bitOffset>
              <bitWidth>1</bitWidth>
            </field>
            <field>
              <name>TXEIE_TXFNFIE</name>
              <bitOffset>7</bitOffset>
              <bitWidth>1</bitWidth>
            </field>
            <field>
              <name>PEIE</name>
              <bitOffset>8</bitOffset>
              <bitWidth>1</bitWidth>
            </field>
            <field>
              <name>PS</name>
              <bitOffset>9</bitOffset>
              <bitWidth>1</bitWidth>
            </field>
            <field>
              <name>PCE</name>
              <bitOffset>10</bitOffset>
              <bitWidth>1</bitWidth>
            </field>
            <field>
              <name>WAKE</name>
              <bitOffset>11</bitOffset>
              <bitWidth>1</bitWidth>
            </field>
            <field>
              <name>M0</name>
              <bitOffset>12</bitOffset>
              <bitWidth>1</bitWidth>
            </field>
            <field>
              <name>MME</name>
              <bitOffset>13</bitOffset>
              <bitWidth>1</bitWidth>
            </field>
            <field>
              <name>CMIE</name>
              <bitOffset>14</bitOffset>
              <bitWidth>1</bitWidth>
            </field>
            <field>
              <name>OVER8</name>
              <bitOffset>15</bitOffset>
              <bitWidth>1</bitWidth>
            </field>
            <field>
              <name>DEDT</name>
              <bitOffset>16</bitOffset>
              <bitWidth>5</bitWidth>
            </field>
            <field>
              <name>DEAT</name>
              <bitOffset>21</bitOffset>
              <bitWidth>5</bitWidth>
            </field>
            <field>
              <name>RTOIE</name>
              <bitOffset>26</bitOffset>
              <bitWidth>1</bitWidth>
            </field>
            <field>
              <name>EOBIE</name>
              <bitOffset>27</bitOffset>
              <bitWidth>1</bitWidth>
            </field>
            <field>
              <name>M1</name>
              <bitOffset>28</bitOffset>
              <bitWidth>1</bitWidth>
            </field>
            <field>
              <name>FIFOEN</name>
              <bitOffset>29</bitOffset>
              <bitWidth>1</bitWidth>
            </field>
            <field>
              <name>TXFEIE</name>
              <bitOffset>30</bitOffset>
              <bitWidth>1</bitWidth>
            </field>
            <field>
              <name>RXFFIE</name>
              <bitOffset>31</bitOffset>
              <bitWidth>1</bitWidth>
            </field>
          </fields>
        </register>
        <register>
          <name>CR2</name>
          <addressOffset>0x4</addressOffset>
          <size>0x20</size>
          <fields>
            <field>
              <name>SLVEN</name>
              <bitOffset>0</bitOffset>
              <bitWidth>1</bitWidth>
            </field>
            <field>
              <name>DIS_NSS</name>
              <bitOffset>3</bitOffset>
              <bitWidth>1</bitWidth>
            </field>
            <field>
              <name>ADDM7</name>
              <bitOffset>4</bitOffset>
              <bitWidth>1</bitWidth>
            </field>
            <field>
              <name>LBDL</name>
              <bitOffset>5</bitOffset>
              <bitWidth>1</bitWidth>
            </field>
            <field>
              <name>LBDIE</name>
              <bitOffset>6</bitOffset>
              <bitWidth>1</bitWidth>
            </field>
            <field>
              <name>LBCL</name>
              <bitOffset>8</bitOffset>
              <bitWidth>1</bitWidth>
            </field>
            <field>
              <name>CPHA</name>
              <bitOffset>9</bitOffset>
              <bitWidth>1</bitWidth>
            </field>
            <field>
              <name>CPOL</name>
              <bitOffset>10</bitOffset>
              <bitWidth>1</bitWidth>
            </field>
            <field>
              <name>CLKEN</name>
              <bitOffset>11</bitOffset>
              <bitWidth>1</bitWidth>
            </field>
            <field>
              <name>STOP</name>
              <bitOffset>12</bitOffset>
              <bitWidth>2</bitWidth>
            </field>
            <field>
              <name>LINEN</name>
              <bitOffset>14</bitOffset>
              <bitWidth>1</bitWidth>
            </field>
            <field>
              <name>SWAP</name>
              <bitOffset>15</bitOffset>
              <bitWidth>1</bitWidth>
            </field>
            <field>
              <name>RXINV</name>
              <bitOffset>16</bitOffset>
              <bitWidth>1</bitWidth>
            </field>
            <field>
              <name>TXINV</name>
              <bitOffset>17</bitOffset>
              <bitWidth>1</bitWidth>
            </field>
            <field>
              <name>DATAINV</name>
              <bitOffset>18</bitOffset>
              <bitWidth>1</bitWidth>
            </field>
            <field>
              <name>MSBFIRST</name>
              <bitOffset>19</bitOffset>
              <bitWidth>1</bitWidth>
            </field>
            <field>
              <name>ABREN</name>
              <bitOffset>20</bitOffset>
              <bitWidth>1</bitWidth>
            </field>
            <field>
              <name>ABRMODE</name>
              <bitOffset>21</bitOffset>
              <bitWidth>2</bitWidth>
            </field>
            <field>
              <name>RTOEN</name>
              <bitOffset>23</bitOffset>
              <bitWidth>1</bitWidth>
            </field>
            <field>
              <name>ADD</name>
              <bitOffset>24</bitOffset>
              <bitWidth>8</bitWidth>
            </field>
          </fields>
        </register>
        <register>
          <name>CR3</name>
          <addressOffset>0x8</addressOffset>
          <size>0x20</size>
          <fields>
            <field>
              <name>EIE</name>
              <bitOffset>0</bitOffset>
              <bitWidth>1</bitWidth>
            </field>
            <field>
              <name>IREN</name>
              <bitOffset>1</bitOffset>
              <bitWidth>1</bitWidth>
            </field>
            <field>
              <name>IRLP</name>
              <bitOffset>2</bitOffset>
              <bitWidth>1</bitWidth>
            </field>
            <field>
              <name>HDSEL</name>
              <bitOffset>3</bitOffset>
              <bitWidth>1</bitWidth>
            </field>
            <field>
              <name>NACK</name>
              <bitOffset>4</bitOffset>
              <bitWidth>1</bitWidth>
            </field>
            <field>
              <name>SCEN</name>
              <bitOffset>5</bitOffset>
              <bitWidth>1</bitWidth>
            </field>
            <field>
              <name>DMAR</name>
              <bitOffset>6</bitOffset>
              <bitWidth>1</bitWidth>
            </field>
            <field>
              <name>DMAT</name>
              <bitOffset>7</bitOffset>
              <bitWidth>1</bitWidth>
            </field>
            <field>
              <name>RTSE</name>
              <bitOffset>8</bitOffset>
              <bitWidth>1</bitWidth>
            </field>
            <field>
              <name>CTSE</name>
              <bitOffset>9</bitOffset>
              <bitWidth>1</bitWidth>
            </field>
            <field>
              <name>CTSIE</name>
              <bitOffset>10</bitOffset>
              <bitWidth>1</bitWidth>
            </field>
            <field>
              <name>ONEBIT</name>
              <bitOffset>11</bitOffset>
              <bitWidth>1</bitWidth>
            </field>
            <field>
              <name>OVRDIS</name>
              <bitOffset>12</bitOffset>
              <bitWidth>1</bitWidth>
            </field>
            <field>
              <name>DDRE</name>
              <bitOffset>13</bitOffset>
              <bitWidth>1</bitWidth>
            </field>
            <field>
              <name>DEM</name>
              <bitOffset>14</bitOffset>
              <bitWidth>1</bitWidth>
            </field>
            <field>
              <name>DEP</name>
              <bitOffset>15</bitOffset>
              <bitWidth>1</bitWidth>
            </field>
            <field>
              <name>SCARCNT</name>
              <bitOffset>17</bitOffset>
              <bitWidth>3</bitWidth>
            </field>
            <field>
              <name>WUS</name>
              <bitOffset>20</bitOffset>
              <bitWidth>2</bitWidth>
            </field>
            <field>
              <name>WUFIE</name>
              <bitOffset>22</bitOffset>
              <bitWidth>1</bitWidth>
            </field>
            <field>
              <name>TXFTIE</name>
              <bitOffset>23</bitOffset>
              <bitWidth>1</bitWidth>
            </field>
            <field>
              <name>TCBGTIE</name>
              <bitOffset>24</bitOffset>
              <bitWidth>1</bitWidth>
            </field>
            <field>
              <name>RXFTCFG</name>
              <bitOffset>25</bitOffset>
              <bitWidth>3</bitWidth>
            </field>
            <field>
              <name>RXFTIE</name>
              <bitOffset>28</bitOffset>
              <bitWidth>1</bitWidth>
            </field>
            <field>
              <name>TXFTCFG</name>
              <bitOffset>29</bitOffset>
              <bitWidth>3</bitWidth>
            </field>
          </fields>
        </register>
        <register>
          <name>BRR</name>
          <addressOffset>0xc</addressOffset>
          <size>0x20</size>
          <fields>
            <field>
              <name>LPUART</name>
              <bitOffset>0</bitOffset>
              <bitWidth>20</bitWidth>
            </field>
          </fields>
        </register>
        <register>
          <name>GTPR</name>
          <addressOffset>0x10</addressOffset>
          <size>0x20</size>
          <fields>
            <field>
              <name>PSC</name>
              <bitOffset>0</bitOffset>
              <bitWidth>8</bitWidth>
            </field>
            <field>
              <name>GT</name>
              <bitOffset>8</bitOffset>
              <bitWidth>8</bitWidth>
            </field>
          </fields>
        </register>
        <register>
          <name>RTOR</name>
          <addressOffset>0x14</addressOffset>
          <size>0x20</size>
          <fields>
            <field>
              <name>RTO</name>
              <bitOffset>0</bitOffset>
              <bitWidth>24</bitWidth>
            </field>
            <field>
              <name>BLEN</name>
              <bitOffset>24</bitOffset>
              <bitWidth>8</bitWidth>
            </field>
          </fields>
        </register>
        <register>
          <name>RQR</name>
          <addressOffset>0x18</addressOffset>
          <size>0x20</size>
          <fields>
            <field>
              <name>ABRRQ</name>
              <bitOffset>0</bitOffset>
              <bitWidth>1</bitWidth>
            </field>
            <field>
              <name>SBKRQ</name>
              <bitOffset>1</bitOffset>
              <bitWidth>1</bitWidth>
            </field>
            <field>
              <name>MMRQ</name>
              <bitOffset>2</bitOffset>
              <bitWidth>1</bitWidth>
            </field>
            <field>
              <name>RXFRQ</name>
              <bitOffset>3</bitOffset>
              <bitWidth>1</bitWidth>
            </field>
            <field>
              <name>TXFRQ</name>
              <bitOffset>4</bitOffset>
              <bitWidth>1</bitWidth>
            </field>
          </fields>
        </register>
        <register>
          <name>ISR</name>
          <addressOffset>0x1c</addressOffset>
          <size>0x20</size>
          <fields>
            <field>
              <name>PE</name>
              <bitOffset>0</bitOffset>
              <bitWidth>1</bitWidth>
            </field>
            <field>
              <name>FE</name>
              <bitOffset>1</bitOffset>
              <bitWidth>1</bitWidth>
            </field>
            <field>
              <name>NE</name>
              <bitOffset>2</bitOffset>
              <bitWidth>1</bitWidth>
            </field>
            <field>
              <name>ORE</name>
              <bitOffset>3</bitOffset>
              <bitWidth>1</bitWidth>
            </field>
            <field>
              <name>IDLE</name>
              <bitOffset>4</bitOffset>
              <bitWidth>1</bitWidth>
            </field>
            <field>
              <name>RXNE_RXFNE</name>
              <bitOffset>5</bitOffset>
              <bitWidth>1</bitWidth>
            </field>
            <field>
              <name>TC</name>
              <bitOffset>6</bitOffset>
              <bitWidth>1</bitWidth>
            </field>
            <field>
              <name>TXE_TXFNF</name>
              <bitOffset>7</bitOffset>
              <bitWidth>1</bitWidth>
            </field>
            <field>
              <name>LBDF</name>
              <bitOffset>8</bitOffset>
              <bitWidth>1</bitWidth>
            </field>
            <field>
              <name>CTSIF</name>
              <bitOffset>9</bitOffset>
              <bitWidth>1</bitWidth>
            </field>
            <field>
              <name>CTS</name>
              <bitOffset>10</bitOffset>
              <bitWidth>1</bitWidth>
            </field>
            <field>
              <name>RTOF</name>
              <bitOffset>11</bitOffset>
              <bitWidth>1</bitWidth>
            </field>
            <field>
              <name>EOBF</name>
              <bitOffset>12</bitOffset>
              <bitWidth>1</bitWidth>
            </field>
            <field>
              <name>UDR</name>
              <bitOffset>13</bitOffset>
              <bitWidth>1</bitWidth>
            </field>
            <field>
              <name>ABRE</name>
              <bitOffset>14</bitOffset>
              <bitWidth>1</bitWidth>
            </field>
            <field>
              <name>ABRF</name>
              <bitOffset>15</bitOffset>
              <bitWidth>1</bitWidth>
            </field>
            <field>
              <name>BUSY</name>
              <bitOffset>16</bitOffset>
              <bitWidth>1</bitWidth>
            </field>
            <field>
              <name>CMF</name>
              <bitOffset>17</bitOffset>
              <bitWidth>1</bitWidth>
            </field>
            <field>
              <name>SBKF</name>
              <bitOffset>18</bitOffset>
              <bitWidth>1</bitWidth>
            </field>
            <field>
              <name>RWU</name>
              <bitOffset>19</bitOffset>
              <bitWidth>1</bitWidth>
            </field>
            <field>
              <name>WUF</name>
              <bitOffset>20</bitOffset>
              <bitWidth>1</bitWidth>
            </field>
            <field>
              <name>TEACK</name>
              <bitOffset>21</bitOffset>
              <bitWidth>1</bitWidth>
            </field>
            <field>
              <name>REACK</name>
              <bitOffset>22</bitOffset>
              <bitWidth>1</bitWidth>
            </field>
            <field>
              <name>TXFE</name>
              <bitOffset>23</bitOffset>
              <bitWidth>1</bitWidth>
            </field>
            <field>
              <name>RXFF</name>
              <bitOffset>24</bitOffset>
              <bitWidth>1</bitWidth>
            </field>
            <field>
              <name>TCBGT</name>
              <bitOffset>25</bitOffset>
              <bitWidth>1</bitWidth>
            </field>
            <field>
              <name>RXFT</name>
              <bitOffset>26</bitOffset>
              <bitWidth>1</bitWidth>
            </field>
            <field>
              <name>TXFT</name>
              <bitOffset>27</bitOffset>
              <bitWidth>1</bitWidth>
            </field>
          </fields>
        </register>
        <register>
          <name>ICR</name>
          <addressOffset>0x20</addressOffset>
          <size>0x20</size>
          <fields>
            <field>
              <name>PECF</name>
              <bitOffset>0</bitOffset>
              <bitWidth>1</bitWidth>
            </field>
            <field>
              <name>FECF</name>
              <bitOffset>1</bitOffset>
              <bitWidth>1</bitWidth>
            </field>
            <field>
              <name>NECF</name>
              <bitOffset>2</bitOffset>
              <bitWidth>1</bitWidth>
            </field>
            <field>
              <name>ORECF</name>
              <bitOffset>3</bitOffset>
              <bitWidth>1</bitWidth>
            </field>
            <field>
              <name>IDLECF</name>
              <bitOffset>4</bitOffset>
              <bitWidth>1</bitWidth>
            </field>
            <field>
              <name>TXFECF</name>
              <bitOffset>5</bitOffset>
              <bitWidth>1</bitWidth>
            </field>
            <field>
              <name>TCCF</name>
              <bitOffset>6</bitOffset>
              <bitWidth>1</bitWidth>
            </field>
            <field>
              <name>TCBGTCF</name>
              <bitOffset>7</bitOffset>
              <bitWidth>1</bitWidth>
            </field>
            <field>
              <name>LBDCF</name>
              <bitOffset>8</bitOffset>
              <bitWidth>1</bitWidth>
            </field>
            <field>
              <name>CTSCF</name>
              <bitOffset>9</bitOffset>
              <bitWidth>1</bitWidth>
            </field>
            <field>
              <name>RTOCF</name>
              <bitOffset>11</bitOffset>
              <bitWidth>1</bitWidth>
            </field>
            <field>
              <name>EOBCF</name>
              <bitOffset>12</bitOffset>
              <bitWidth>1</bitWidth>
            </field>
            <field>
              <name>UDRCF</name>
              <bitOffset>13</bitOffset>
              <bitWidth>1</bitWidth>
            </field>
            <field>
              <name>CMCF</name>
              <bitOffset>17</bitOffset>
              <bitWidth>1</bitWidth>
            </field>
            <field>
              <name>WUCF</name>
              <bitOffset>20</bitOffset>
              <bitWidth>1</bitWidth>
            </field>
          </fields>
        </register>
        <register>
          <name>RDR</name>
          <addressOffset>0x24</addressOffset>
          <size>0x20</size>
          <fields>
            <field>
              <name>RDR</name>
              <bitOffset>0</bitOffset>
              <bitWidth>9</bitWidth>
            </field>
          </fields>
        </register>
        <register>
          <name>TDR</name>
          <addressOffset>0x28</addressOffset>
          <size>0x20</size>
          <fields>
            <field>
              <name>TDR</name>
              <bitOffset>0</bitOffset>
              <bitWidth>9</bitWidth>
            </field>
          </fields>
        </register>
        <register>
          <name>PRESC</name>
          <addressOffset>0x2c</addressOffset>
          <size>0x20</size>
          <fields>
            <field>
              <name>PRESCALER</name>
              <bitOffset>0</bitOffset>
              <bitWidth>4</bitWidth>
            </field>
          </fields>
        </register>
      </registers>
    </peripheral>
    <peripheral>
      <name>UART5</name>
      <baseAddress>0x40005000</baseAddress>
      <registers>
        <register>
          <name>CR1</name>
          <addressOffset>0x0</addressOffset>
          <size>0x20</size>
          <fields>
            <field>
              <name>UE</name>
              <bitOffset>0</bitOffset>
              <bitWidth>1</bitWidth>
            </field>
            <field>
              <name>UESM</name>
              <bitOffset>1</bitOffset>
              <bitWidth>1</bitWidth>
            </field>
            <field>
              <name>RE</name>
              <bitOffset>2</bitOffset>
              <bitWidth>1</bitWidth>
            </field>
            <field>
              <name>TE</name>
              <bitOffset>3</bitOffset>
              <bitWidth>1</bitWidth>
            </field>
            <field>
              <name>IDLEIE</name>
              <bitOffset>4</bitOffset>
              <bitWidth>1</bitWidth>
            </field>
            <field>
              <name>RXNEIE_RXFNEIE</name>
              <bitOffset>5</bitOffset>
              <bitWidth>1</bitWidth>
            </field>
            <field>
              <name>TCIE</name>
              <bitOffset>6</bitOffset>
              <bitWidth>1</bitWidth>
            </field>
            <field>
              <name>TXEIE_TXFNFIE</name>
              <bitOffset>7</bitOffset>
              <bitWidth>1</bitWidth>
            </field>
            <field>
              <name>PEIE</name>
              <bitOffset>8</bitOffset>
              <bitWidth>1</bitWidth>
            </field>
            <field>
              <name>PS</name>
              <bitOffset>9</bitOffset>
              <bitWidth>1</bitWidth>
            </field>
            <field>
              <name>PCE</name>
              <bitOffset>10</bitOffset>
              <bitWidth>1</bitWidth>
            </field>
            <field>
              <name>WAKE</name>
              <bitOffset>11</bitOffset>
              <bitWidth>1</bitWidth>
            </field>
            <field>
              <name>M0</name>
              <bitOffset>12</bitOffset>
              <bitWidth>1</bitWidth>
            </field>
            <field>
              <name>MME</name>
              <bitOffset>13</bitOffset>
              <bitWidth>1</bitWidth>
            </field>
            <field>
              <name>CMIE</name>
              <bitOffset>14</bitOffset>
              <bitWidth>1</bitWidth>
            </field>
            <field>
              <name>OVER8</name>
              <bitOffset>15</bitOffset>
              <bitWidth>1</bitWidth>
            </field>
            <field>
              <name>DEDT</name>
              <bitOffset>16</bitOffset>
              <bitWidth>5</bitWidth>
            </field>
            <field>
              <name>DEAT</name>
              <bitOffset>21</bitOffset>
              <bitWidth>5</bitWidth>
            </field>
            <field>
              <name>RTOIE</name>
              <bitOffset>26</bitOffset>
              <bitWidth>1</bitWidth>
            </field>
            <field>
              <name>EOBIE</name>
              <bitOffset>27</bitOffset>
              <bitWidth>1</bitWidth>
            </field>
            <field>
              <name>M1</name>
              <bitOffset>28</bitOffset>
              <bitWidth>1</bitWidth>
            </field>
            <field>
              <name>FIFOEN</name>
              <bitOffset>29</bitOffset>
              <bitWidth>1</bitWidth>
            </field>
            <field>
              <name>TXFEIE</name>
              <bitOffset>30</bitOffset>
              <bitWidth>1</bitWidth>
            </field>
            <field>
              <name>RXFFIE</name>
              <bitOffset>31</bitOffset>
              <bitWidth>1</bitWidth>
            </field>
          </fields>
        </register>
        <register>
          <name>CR2</name>
          <addressOffset>0x4</addressOffset>
          <size>0x20</size>
          <fields>
            <field>
              <name>SLVEN</name>
              <bitOffset>0</bitOffset>
              <bitWidth>1</bitWidth>
            </field>
            <field>
              <name>DIS_NSS</name>
              <bitOffset>3</bitOffset>
              <bitWidth>1</bitWidth>
            </field>
            <field>
              <name>ADDM7</name>
              <bitOffset>4</bitOffset>
              <bitWidth>1</bitWidth>
            </field>
            <field>
              <name>LBDL</name>
              <bitOffset>5</bitOffset>
              <bitWidth>1</bitWidth>
            </field>
            <field>
              <name>LBDIE</name>
              <bitOffset>6</bitOffset>
              <bitWidth>1</bitWidth>
            </field>
            <field>
              <name>LBCL</name>
              <bitOffset>8</bitOffset>
              <bitWidth>1</bitWidth>
            </field>
            <field>
              <name>CPHA</name>
              <bitOffset>9</bitOffset>
              <bitWidth>1</bitWidth>
            </field>
            <field>
              <name>CPOL</name>
              <bitOffset>10</bitOffset>
              <bitWidth>1</bitWidth>
            </field>
            <field>
              <name>CLKEN</name>
              <bitOffset>11</bitOffset>
              <bitWidth>1</bitWidth>
            </field>
            <field>
              <name>STOP</name>
              <bitOffset>12</bitOffset>
              <bitWidth>2</bitWidth>
            </field>
            <field>
              <name>LINEN</name>
              <bitOffset>14</bitOffset>
              <bitWidth>1</bitWidth>
            </field>
            <field>
              <name>SWAP</name>
              <bitOffset>15</bitOffset>
              <bitWidth>1</bitWidth>
            </field>
            <field>
              <name>RXINV</name>
              <bitOffset>16</bitOffset>
              <bitWidth>1</bitWidth>
            </field>
            <field>
              <name>TXINV</name>
              <bitOffset>17</bitOffset>
              <bitWidth>1</bitWidth>
            </field>
            <field>
              <name>DATAINV</name>
              <bitOffset>18</bitOffset>
              <bitWidth>1</bitWidth>
            </field>
            <field>
              <name>MSBFIRST</name>
              <bitOffset>19</bitOffset>
              <bitWidth>1</bitWidth>
            </field>
            <field>
              <name>ABREN</name>
              <bitOffset>20</bitOffset>
              <bitWidth>1</bitWidth>
            </field>
            <field>
              <name>ABRMODE</name>
              <bitOffset>21</bitOffset>
              <bitWidth>2</bitWidth>
            </field>
            <field>
              <name>RTOEN</name>
              <bitOffset>23</bitOffset>
              <bitWidth>1</bitWidth>
            </field>
            <field>
              <name>ADD</name>
              <bitOffset>24</bitOffset>
              <bitWidth>8</bitWidth>
            </field>
          </fields>
        </register>
        <register>
          <name>CR3</name>
          <addressOffset>0x8</addressOffset>
          <size>0x20</size>
          <fields>
            <field>
              <name>EIE</name>
              <bitOffset>0</bitOffset>
              <bitWidth>1</bitWidth>
            </field>
            <field>
              <name>IREN</name>
              <bitOffset>1</bitOffset>
              <bitWidth>1</bitWidth>
            </field>
            <field>
              <name>IRLP</name>
              <bitOffset>2</bitOffset>
              <bitWidth>1</bitWidth>
            </field>
            <field>
              <name>HDSEL</name>
              <bitOffset>3</bitOffset>
              <bitWidth>1</bitWidth>
            </field>
            <field>
              <name>NACK</name>
              <bitOffset>4</bitOffset>
              <bitWidth>1</bitWidth>
            </field>
            <field>
              <name>SCEN</name>
              <bitOffset>5</bitOffset>
              <bitWidth>1</bitWidth>
            </field>
            <field>
              <name>DMAR</name>
              <bitOffset>6</bitOffset>
              <bitWidth>1</bitWidth>
            </field>
            <field>
              <name>DMAT</name>
              <bitOffset>7</bitOffset>
              <bitWidth>1</bitWidth>
            </field>
            <field>
              <name>RTSE</name>
              <bitOffset>8</bitOffset>
              <bitWidth>1</bitWidth>
            </field>
            <field>
              <name>CTSE</name>
              <bitOffset>9</bitOffset>
              <bitWidth>1</bitWidth>
            </field>
            <field>
              <name>CTSIE</name>
              <bitOffset>10</bitOffset>
              <bitWidth>1</bitWidth>
            </field>
            <field>
              <name>ONEBIT</name>
              <bitOffset>11</bitOffset>
              <bitWidth>1</bitWidth>
            </field>
            <field>
              <name>OVRDIS</name>
              <bitOffset>12</bitOffset>
              <bitWidth>1</bitWidth>
            </field>
            <field>
              <name>DDRE</name>
              <bitOffset>13</bitOffset>
              <bitWidth>1</bitWidth>
            </field>
            <field>
              <name>DEM</name>
              <bitOffset>14</bitOffset>
              <bitWidth>1</bitWidth>
            </field>
            <field>
              <name>DEP</name>
              <bitOffset>15</bitOffset>
              <bitWidth>1</bitWidth>
            </field>
            <field>
              <name>SCARCNT</name>
              <bitOffset>17</bitOffset>
              <bitWidth>3</bitWidth>
            </field>
            <field>
              <name>WUS</name>
              <bitOffset>20</bitOffset>
              <bitWidth>2</bitWidth>
            </field>
            <field>
              <name>WUFIE</name>
              <bitOffset>22</bitOffset>
              <bitWidth>1</bitWidth>
            </field>
            <field>
              <name>TXFTIE</name>
              <bitOffset>23</bitOffset>
              <bitWidth>1</bitWidth>
            </field>
            <field>
              <name>TCBGTIE</name>
              <bitOffset>24</bitOffset>
              <bitWidth>1</bitWidth>
            </field>
            <field>
              <name>RXFTCFG</name>
              <bitOffset>25</bitOffset>
              <bitWidth>3</bitWidth>
            </field>
            <field>
              <name>RXFTIE</name>
              <bitOffset>28</bitOffset>
              <bitWidth>1</bitWidth>
            </field>
            <field>
              <name>TXFTCFG</name>
              <bitOffset>29</bitOffset>
              <bitWidth>3</bitWidth>
            </field>
          </fields>
        </register>
        <register>
          <name>BRR</name>
          <addressOffset>0xc</addressOffset>
          <size>0x20</size>
          <fields>
            <field>
              <name>LPUART</name>
              <bitOffset>0</bitOffset>
              <bitWidth>20</bitWidth>
            </field>
          </fields>
        </register>
        <register>
          <name>GTPR</name>
          <addressOffset>0x10</addressOffset>
          <size>0x20</size>
          <fields>
            <field>
              <name>PSC</name>
              <bitOffset>0</bitOffset>
              <bitWidth>8</bitWidth>
            </field>
            <field>
              <name>GT</name>
              <bitOffset>8</bitOffset>
              <bitWidth>8</bitWidth>
            </field>
          </fields>
        </register>
        <register>
          <name>RTOR</name>
          <addressOffset>0x14</addressOffset>
          <size>0x20</size>
          <fields>
            <field>
              <name>RTO</name>
              <bitOffset>0</bitOffset>
              <bitWidth>24</bitWidth>
            </field>
            <field>
              <name>BLEN</name>
              <bitOffset>24</bitOffset>
              <bitWidth>8</bitWidth>
            </field>
          </fields>
        </register>
        <register>
          <name>RQR</name>
          <addressOffset>0x18</addressOffset>
          <size>0x20</size>
          <fields>
            <field>
              <name>ABRRQ</name>
              <bitOffset>0</bitOffset>
              <bitWidth>1</bitWidth>
            </field>
            <field>
              <name>SBKRQ</name>
              <bitOffset>1</bitOffset>
              <bitWidth>1</bitWidth>
            </field>
            <field>
              <name>MMRQ</name>
              <bitOffset>2</bitOffset>
              <bitWidth>1</bitWidth>
            </field>
            <field>
              <name>RXFRQ</name>
              <bitOffset>3</bitOffset>
              <bitWidth>1</bitWidth>
            </field>
            <field>
              <name>TXFRQ</name>
              <bitOffset>4</bitOffset>
              <bitWidth>1</bitWidth>
            </field>
          </fields>
        </register>
        <register>
          <name>ISR</name>
          <addressOffset>0x1c</addressOffset>
          <size>0x20</size>
          <fields>
            <field>
              <name>PE</name>
              <bitOffset>0</bitOffset>
              <bitWidth>1</bitWidth>
            </field>
            <field>
              <name>FE</name>
              <bitOffset>1</bitOffset>
              <bitWidth>1</bitWidth>
            </field>
            <field>
              <name>NE</name>
              <bitOffset>2</bitOffset>
              <bitWidth>1</bitWidth>
            </field>
            <field>
              <name>ORE</name>
              <bitOffset>3</bitOffset>
              <bitWidth>1</bitWidth>
            </field>
            <field>
              <name>IDLE</name>
              <bitOffset>4</bitOffset>
              <bitWidth>1</bitWidth>
            </field>
            <field>
              <name>RXNE_RXFNE</name>
              <bitOffset>5</bitOffset>
              <bitWidth>1</bitWidth>
            </field>
            <field>
              <name>TC</name>
              <bitOffset>6</bitOffset>
              <bitWidth>1</bitWidth>
            </field>
            <field>
              <name>TXE_TXFNF</name>
              <bitOffset>7</bitOffset>
              <bitWidth>1</bitWidth>
            </field>
            <field>
              <name>LBDF</name>
              <bitOffset>8</bitOffset>
              <bitWidth>1</bitWidth>
            </field>
            <field>
              <name>CTSIF</name>
              <bitOffset>9</bitOffset>
              <bitWidth>1</bitWidth>
            </field>
            <field>
              <name>CTS</name>
              <bitOffset>10</bitOffset>
              <bitWidth>1</bitWidth>
            </field>
            <field>
              <name>RTOF</name>
              <bitOffset>11</bitOffset>
              <bitWidth>1</bitWidth>
            </field>
            <field>
              <name>EOBF</name>
              <bitOffset>12</bitOffset>
              <bitWidth>1</bitWidth>
            </field>
            <field>
              <name>UDR</name>
              <bitOffset>13</bitOffset>
              <bitWidth>1</bitWidth>
            </field>
            <field>
              <name>ABRE</name>
              <bitOffset>14</bitOffset>
              <bitWidth>1</bitWidth>
            </field>
            <field>
              <name>ABRF</name>
              <bitOffset>15</bitOffset>
              <bitWidth>1</bitWidth>
            </field>
            <field>
              <name>BUSY</name>
              <bitOffset>16</bitOffset>
              <bitWidth>1</bitWidth>
            </field>
            <field>
              <name>CMF</name>
              <bitOffset>17</bitOffset>
              <bitWidth>1</bitWidth>
            </field>
            <field>
              <name>SBKF</name>
              <bitOffset>18</bitOffset>
              <bitWidth>1</bitWidth>
            </field>
            <field>
              <name>RWU</name>
              <bitOffset>19</bitOffset>
              <bitWidth>1</bitWidth>
            </field>
            <field>
              <name>WUF</name>
              <bitOffset>20</bitOffset>
              <bitWidth>1</bitWidth>
            </field>
            <field>
              <name>TEACK</name>
              <bitOffset>21</bitOffset>
              <bitWidth>1</bitWidth>
            </field>
            <field>
              <name>REACK</name>
              <bitOffset>22</bitOffset>
              <bitWidth>1</bitWidth>
            </field>
            <field>
              <name>TXFE</name>
              <bitOffset>23</bitOffset>
              <bitWidth>1</bitWidth>
            </field>
            <field>
              <name>RXFF</name>
              <bitOffset>24</bitOffset>
              <bitWidth>1</bitWidth>
            </field>
            <field>
              <name>TCBGT</name>
              <bitOffset>25</bitOffset>
              <bitWidth>1</bitWidth>
            </field>
            <field>
              <name>RXFT</name>
              <bitOffset>26</bitOffset>
              <bitWidth>1</bitWidth>
            </field>
            <field>
              <name>TXFT</name>
              <bitOffset>27</bitOffset>
              <bitWidth>1</bitWidth>
            </field>
          </fields>
        </register>
        <register>
          <name>ICR</name>
          <addressOffset>0x20</addressOffset>
          <size>0x20</size>
          <fields>
            <field>
              <name>PECF</name>
              <bitOffset>0</bitOffset>
              <bitWidth>1</bitWidth>
            </field>
            <field>
              <name>FECF</name>
              <bitOffset>1</bitOffset>
              <bitWidth>1</bitWidth>
            </field>
            <field>
              <name>NECF</name>
              <bitOffset>2</bitOffset>
              <bitWidth>1</bitWidth>
            </field>
            <field>
              <name>ORECF</name>
              <bitOffset>3</bitOffset>
              <bitWidth>1</bitWidth>
            </field>
            <field>
              <name>IDLECF</name>
              <bitOffset>4</bitOffset>
              <bitWidth>1</bitWidth>
            </field>
            <field>
              <name>TXFECF</name>
              <bitOffset>5</bitOffset>
              <bitWidth>1</bitWidth>
            </field>
            <field>
              <name>TCCF</name>
              <bitOffset>6</bitOffset>
              <bitWidth>1</bitWidth>
            </field>
            <field>
              <name>TCBGTCF</name>
              <bitOffset>7</bitOffset>
              <bitWidth>1</bitWidth>
            </field>
            <field>
              <name>LBDCF</name>
              <bitOffset>8</bitOffset>
              <bitWidth>1</bitWidth>
            </field>
            <field>
              <name>CTSCF</name>
              <bitOffset>9</bitOffset>
              <bitWidth>1</bitWidth>
            </field>
            <field>
              <name>RTOCF</name>
              <bitOffset>11</bitOffset>
              <bitWidth>1</bitWidth>
            </field>
            <field>
              <name>EOBCF</name>
              <bitOffset>12</bitOffset>
              <bitWidth>1</bitWidth>
            </field>
            <field>
              <name>UDRCF</name>
              <bitOffset>13</bitOffset>
              <bitWidth>1</bitWidth>
            </field>
            <field>
              <name>CMCF</name>
              <bitOffset>17</bitOffset>
              <bitWidth>1</bitWidth>
            </field>
            <field>
              <name>WUCF</name>
              <bitOffset>20</bitOffset>
              <bitWidth>1</bitWidth>
            </field>
          </fields>
        </register>
        <register>
          <name>RDR</name>
          <addressOffset>0x24</addressOffset>
          <size>0x20</size>
          <fields>
            <field>
              <name>RDR</name>
              <bitOffset>0</bitOffset>
              <bitWidth>9</bitWidth>
            </field>
          </fields>
        </register>
        <register>
          <name>TDR</name>
          <addressOffset>0x28</addressOffset>
          <size>0x20</size>
          <fields>
            <field>
              <name>TDR</name>
              <bitOffset>0</bitOffset>
              <bitWidth>9</bitWidth>
            </field>
          </fields>
        </register>
        <register>
          <name>PRESC</name>
          <addressOffset>0x2c</addressOffset>
          <size>0x20</size>
          <fields>
            <field>
              <name>PRESCALER</name>
              <bitOffset>0</bitOffset>
              <bitWidth>4</bitWidth>
            </field>
          </fields>
        </register>
      </registers>
    </peripheral>
    <peripheral>
      <name>I2C1</name>
      <baseAddress>0x40005400</baseAddress>
      <registers>
        <register>
          <name>CR1</name>
          <addressOffset>0x0</addressOffset>
          <size>0x20</size>
          <fields>
            <field>
              <name>PE</name>
              <bitOffset>0</bitOffset>
              <bitWidth>1</bitWidth>
            </field>
            <field>
              <name>TXIE</name>
              <bitOffset>1</bitOffset>
              <bitWidth>1</bitWidth>
            </field>
            <field>
              <name>RXIE</name>
              <bitOffset>2</bitOffset>
              <bitWidth>1</bitWidth>
            </field>
            <field>
              <name>ADDRIE</name>
              <bitOffset>3</bitOffset>
              <bitWidth>1</bitWidth>
            </field>
            <field>
              <name>NACKIE</name>
              <bitOffset>4</bitOffset>
              <bitWidth>1</bitWidth>
            </field>
            <field>
              <name>STOPIE</name>
              <bitOffset>5</bitOffset>
              <bitWidth>1</bitWidth>
            </field>
            <field>
              <name>TCIE</name>
              <bitOffset>6</bitOffset>
              <bitWidth>1</bitWidth>
            </field>
            <field>
              <name>ERRIE</name>
              <bitOffset>7</bitOffset>
              <bitWidth>1</bitWidth>
            </field>
            <field>
              <name>DNF</name>
              <bitOffset>8</bitOffset>
              <bitWidth>4</bitWidth>
            </field>
            <field>
              <name>ANFOFF</name>
              <bitOffset>12</bitOffset>
              <bitWidth>1</bitWidth>
            </field>
            <field>
              <name>SWRST</name>
              <bitOffset>13</bitOffset>
              <bitWidth>1</bitWidth>
            </field>
            <field>
              <name>TXDMAEN</name>
              <bitOffset>14</bitOffset>
              <bitWidth>1</bitWidth>
            </field>
            <field>
              <name>RXDMAEN</name>
              <bitOffset>15</bitOffset>
              <bitWidth>1</bitWidth>
            </field>
            <field>
              <name>SBC</name>
              <bitOffset>16</bitOffset>
              <bitWidth>1</bitWidth>
            </field>
            <field>
              <name>NOSTRETCH</name>
              <bitOffset>17</bitOffset>
              <bitWidth>1</bitWidth>
            </field>
            <field>
              <name>WUPEN</name>
              <bitOffset>18</bitOffset>
              <bitWidth>1</bitWidth>
            </field>
            <field>
              <name>GCEN</name>
              <bitOffset>19</bitOffset>
              <bitWidth>1</bitWidth>
            </field>
            <field>
              <name>SMBHEN</name>
              <bitOffset>20</bitOffset>
              <bitWidth>1</bitWidth>
            </field>
            <field>
              <name>SMBDEN</name>
              <bitOffset>21</bitOffset>
              <bitWidth>1</bitWidth>
            </field>
            <field>
              <name>ALERTEN</name>
              <bitOffset>22</bitOffset>
              <bitWidth>1</bitWidth>
            </field>
            <field>
              <name>PECEN</name>
              <bitOffset>23</bitOffset>
              <bitWidth>1</bitWidth>
            </field>
          </fields>
        </register>
        <register>
          <name>CR2</name>
          <addressOffset>0x4</addressOffset>
          <size>0x20</size>
          <fields>
            <field>
              <name>SADD</name>
              <bitOffset>0</bitOffset>
              <bitWidth>10</bitWidth>
            </field>
            <field>
              <name>RD_WRN</name>
              <bitOffset>10</bitOffset>
              <bitWidth>1</bitWidth>
            </field>
            <field>
              <name>ADD10</name>
              <bitOffset>11</bitOffset>
              <bitWidth>1</bitWidth>
            </field>
            <field>
              <name>HEAD10R</name>
              <bitOffset>12</bitOffset>
              <bitWidth>1</bitWidth>
            </field>
            <field>
              <name>START</name>
              <bitOffset>13</bitOffset>
              <bitWidth>1</bitWidth>
            </field>
            <field>
              <name>STOP</name>
              <bitOffset>14</bitOffset>
              <bitWidth>1</bitWidth>
            </field>
            <field>
              <name>NACK</name>
              <bitOffset>15</bitOffset>
              <bitWidth>1</bitWidth>
            </field>
            <field>
              <name>NBYTES</name>
              <bitOffset>16</bitOffset>
              <bitWidth>8</bitWidth>
            </field>
            <field>
              <name>RELOAD</name>
              <bitOffset>24</bitOffset>
              <bitWidth>1</bitWidth>
            </field>
            <field>
              <name>AUTOEND</name>
              <bitOffset>25</bitOffset>
              <bitWidth>1</bitWidth>
            </field>
            <field>
              <name>PECBYTE</name>
              <bitOffset>26</bitOffset>
              <bitWidth>1</bitWidth>
            </field>
          </fields>
        </register>
        <register>
          <name>OAR1</name>
          <addressOffset>0x8</addressOffset>
          <size>0x20</size>
          <fields>
            <field>
              <name>OA1</name>
              <bitOffset>0</bitOffset>
              <bitWidth>10</bitWidth>
            </field>
            <field>
              <name>OA1MODE</name>
              <bitOffset>10</bitOffset>
              <bitWidth>1</bitWidth>
            </field>
            <field>
              <name>OA1EN</name>
              <bitOffset>15</bitOffset>
              <bitWidth>1</bitWidth>
            </field>
          </fields>
        </register>
        <register>
          <name>OAR2</name>
          <addressOffset>0xc</addressOffset>
          <size>0x20</size>
          <fields>
            <field>
              <name>OA2</name>
              <bitOffset>1</bitOffset>
              <bitWidth>7</bitWidth>
            </field>
            <field>
              <name>OA2MSK</name>
              <bitOffset>8</bitOffset>
              <bitWidth>3</bitWidth>
            </field>
            <field>
              <name>OA2MASK06</name>
              <bitOffset>9</bitOffset>
              <bitWidth>2</bitWidth>
            </field>
            <field>
              <name>OA2MASK04</name>
              <bitOffset>10</bitOffset>
              <bitWidth>1</bitWidth>
            </field>
            <field>
              <name>OA2EN</name>
              <bitOffset>15</bitOffset>
              <bitWidth>1</bitWidth>
            </field>
          </fields>
        </register>
        <register>
          <name>TIMINGR</name>
          <addressOffset>0x10</addressOffset>
          <size>0x20</size>
          <fields>
            <field>
              <name>SCLL</name>
              <bitOffset>0</bitOffset>
              <bitWidth>8</bitWidth>
            </field>
            <field>
              <name>SCLH</name>
              <bitOffset>8</bitOffset>
              <bitWidth>8</bitWidth>
            </field>
            <field>
              <name>SDADEL</name>
              <bitOffset>16</bitOffset>
              <bitWidth>4</bitWidth>
            </field>
            <field>
              <name>SCLDEL</name>
              <bitOffset>20</bitOffset>
              <bitWidth>4</bitWidth>
            </field>
            <field>
              <name>PRESC</name>
              <bitOffset>28</bitOffset>
              <bitWidth>4</bitWidth>
            </field>
          </fields>
        </register>
        <register>
          <name>TIMEOUTR</name>
          <addressOffset>0x14</addressOffset>
          <size>0x20</size>
          <fields>
            <field>
              <name>TIMEOUTA</name>
              <bitOffset>0</bitOffset>
              <bitWidth>12</bitWidth>
            </field>
            <field>
              <name>TIDLE</name>
              <bitOffset>12</bitOffset>
              <bitWidth>1</bitWidth>
            </field>
            <field>
              <name>TIMOUTEN</name>
              <bitOffset>15</bitOffset>
              <bitWidth>1</bitWidth>
            </field>
            <field>
              <name>TIMEOUTB</name>
              <bitOffset>16</bitOffset>
              <bitWidth>12</bitWidth>
            </field>
            <field>
              <name>TEXTEN</name>
              <bitOffset>31</bitOffset>
              <bitWidth>1</bitWidth>
            </field>
          </fields>
        </register>
        <register>
          <name>ISR</name>
          <addressOffset>0x18</addressOffset>
          <size>0x20</size>
          <fields>
            <field>
              <name>TXE</name>
              <bitOffset>0</bitOffset>
              <bitWidth>1</bitWidth>
            </field>
            <field>
              <name>TXIS</name>
              <bitOffset>1</bitOffset>
              <bitWidth>1</bitWidth>
            </field>
            <field>
              <name>RXNE</name>
              <bitOffset>2</bitOffset>
              <bitWidth>1</bitWidth>
            </field>
            <field>
              <name>ADDR</name>
              <bitOffset>3</bitOffset>
              <bitWidth>1</bitWidth>
            </field>
            <field>
              <name>NACKF</name>
              <bitOffset>4</bitOffset>
              <bitWidth>1</bitWidth>
            </field>
            <field>
              <name>STOPF</name>
              <bitOffset>5</bitOffset>
              <bitWidth>1</bitWidth>
            </field>
            <field>
              <name>TC</name>
              <bitOffset>6</bitOffset>
              <bitWidth>1</bitWidth>
            </field>
            <field>
              <name>TCR</name>
              <bitOffset>7</bitOffset>
              <bitWidth>1</bitWidth>
            </field>
            <field>
              <name>BERR</name>
              <bitOffset>8</bitOffset>
              <bitWidth>1</bitWidth>
            </field>
            <field>
              <name>ARLO</name>
              <bitOffset>9</bitOffset>
              <bitWidth>1</bitWidth>
            </field>
            <field>
              <name>OVR</name>
              <bitOffset>10</bitOffset>
              <bitWidth>1</bitWidth>
            </field>
            <field>
              <name>PECERR</name>
              <bitOffset>11</bitOffset>
              <bitWidth>1</bitWidth>
            </field>
            <field>
              <name>TIMEOUT</name>
              <bitOffset>12</bitOffset>
              <bitWidth>1</bitWidth>
            </field>
            <field>
              <name>ALERT</name>
              <bitOffset>13</bitOffset>
              <bitWidth>1</bitWidth>
            </field>
            <field>
              <name>BUSY</name>
              <bitOffset>15</bitOffset>
              <bitWidth>1</bitWidth>
            </field>
            <field>
              <name>DIR</name>
              <bitOffset>16</bitOffset>
              <bitWidth>1</bitWidth>
            </field>
            <field>
              <name>ADDCODE</name>
              <bitOffset>17</bitOffset>
              <bitWidth>7</bitWidth>
            </field>
          </fields>
        </register>
        <register>
          <name>ICR</name>
          <addressOffset>0x1c</addressOffset>
          <size>0x20</size>
          <fields>
            <field>
              <name>ADDRCF</name>
              <bitOffset>3</bitOffset>
              <bitWidth>1</bitWidth>
            </field>
            <field>
              <name>NACKCF</name>
              <bitOffset>4</bitOffset>
              <bitWidth>1</bitWidth>
            </field>
            <field>
              <name>STOPCF</name>
              <bitOffset>5</bitOffset>
              <bitWidth>1</bitWidth>
            </field>
            <field>
              <name>BERRCF</name>
              <bitOffset>8</bitOffset>
              <bitWidth>1</bitWidth>
            </field>
            <field>
              <name>ARLOCF</name>
              <bitOffset>9</bitOffset>
              <bitWidth>1</bitWidth>
            </field>
            <field>
              <name>OVRCF</name>
              <bitOffset>10</bitOffset>
              <bitWidth>1</bitWidth>
            </field>
            <field>
              <name>PECCF</name>
              <bitOffset>11</bitOffset>
              <bitWidth>1</bitWidth>
            </field>
            <field>
              <name>TIMOUTCF</name>
              <bitOffset>12</bitOffset>
              <bitWidth>1</bitWidth>
            </field>
            <field>
              <name>ALERTCF</name>
              <bitOffset>13</bitOffset>
              <bitWidth>1</bitWidth>
            </field>
          </fields>
        </register>
        <register>
          <name>PECR</name>
          <addressOffset>0x20</addressOffset>
          <size>0x20</size>
          <fields>
            <field>
              <name>PEC</name>
              <bitOffset>0</bitOffset>
              <bitWidth>8</bitWidth>
            </field>
          </fields>
        </register>
        <register>
          <name>RXDR</name>
          <addressOffset>0x24</addressOffset>
          <size>0x20</size>
          <fields>
            <field>
              <name>RXDATA</name>
              <bitOffset>0</bitOffset>
              <bitWidth>8</bitWidth>
            </field>
          </fields>
        </register>
        <register>
          <name>TXDR</name>
          <addressOffset>0x28</addressOffset>
          <size>0x20</size>
          <fields>
            <field>
              <name>TXDATA</name>
              <bitOffset>0</bitOffset>
              <bitWidth>8</bitWidth>
            </field>
          </fields>
        </register>
      </registers>
    </peripheral>
    <peripheral>
      <name>I2C2</name>
      <baseAddress>0x40005800</baseAddress>
      <registers>
        <register>
          <name>CR1</name>
          <addressOffset>0x0</addressOffset>
          <size>0x20</size>
          <fields>
            <field>
              <name>PE</name>
              <bitOffset>0</bitOffset>
              <bitWidth>1</bitWidth>
            </field>
            <field>
              <name>TXIE</name>
              <bitOffset>1</bitOffset>
              <bitWidth>1</bitWidth>
            </field>
            <field>
              <name>RXIE</name>
              <bitOffset>2</bitOffset>
              <bitWidth>1</bitWidth>
            </field>
            <field>
              <name>ADDRIE</name>
              <bitOffset>3</bitOffset>
              <bitWidth>1</bitWidth>
            </field>
            <field>
              <name>NACKIE</name>
              <bitOffset>4</bitOffset>
              <bitWidth>1</bitWidth>
            </field>
            <field>
              <name>STOPIE</name>
              <bitOffset>5</bitOffset>
              <bitWidth>1</bitWidth>
            </field>
            <field>
              <name>TCIE</name>
              <bitOffset>6</bitOffset>
              <bitWidth>1</bitWidth>
            </field>
            <field>
              <name>ERRIE</name>
              <bitOffset>7</bitOffset>
              <bitWidth>1</bitWidth>
            </field>
            <field>
              <name>DNF</name>
              <bitOffset>8</bitOffset>
              <bitWidth>4</bitWidth>
            </field>
            <field>
              <name>ANFOFF</name>
              <bitOffset>12</bitOffset>
              <bitWidth>1</bitWidth>
            </field>
            <field>
              <name>SWRST</name>
              <bitOffset>13</bitOffset>
              <bitWidth>1</bitWidth>
            </field>
            <field>
              <name>TXDMAEN</name>
              <bitOffset>14</bitOffset>
              <bitWidth>1</bitWidth>
            </field>
            <field>
              <name>RXDMAEN</name>
              <bitOffset>15</bitOffset>
              <bitWidth>1</bitWidth>
            </field>
            <field>
              <name>SBC</name>
              <bitOffset>16</bitOffset>
              <bitWidth>1</bitWidth>
            </field>
            <field>
              <name>NOSTRETCH</name>
              <bitOffset>17</bitOffset>
              <bitWidth>1</bitWidth>
            </field>
            <field>
              <name>WUPEN</name>
              <bitOffset>18</bitOffset>
              <bitWidth>1</bitWidth>
            </field>
            <field>
              <name>GCEN</name>
              <bitOffset>19</bitOffset>
              <bitWidth>1</bitWidth>
            </field>
            <field>
              <name>SMBHEN</name>
              <bitOffset>20</bitOffset>
              <bitWidth>1</bitWidth>
            </field>
            <field>
              <name>SMBDEN</name>
              <bitOffset>21</bitOffset>
              <bitWidth>1</bitWidth>
            </field>
            <field>
              <name>ALERTEN</name>
              <bitOffset>22</bitOffset>
              <bitWidth>1</bitWidth>
            </field>
            <field>
              <name>PECEN</name>
              <bitOffset>23</bitOffset>
              <bitWidth>1</bitWidth>
            </field>
          </fields>
        </register>
        <register>
          <name>CR2</name>
          <addressOffset>0x4</addressOffset>
          <size>0x20</size>
          <fields>
            <field>
              <name>SADD</name>
              <bitOffset>0</bitOffset>
              <bitWidth>10</bitWidth>
            </field>
            <field>
              <name>RD_WRN</name>
              <bitOffset>10</bitOffset>
              <bitWidth>1</bitWidth>
            </field>
            <field>
              <name>ADD10</name>
              <bitOffset>11</bitOffset>
              <bitWidth>1</bitWidth>
            </field>
            <field>
              <name>HEAD10R</name>
              <bitOffset>12</bitOffset>
              <bitWidth>1</bitWidth>
            </field>
            <field>
              <name>START</name>
              <bitOffset>13</bitOffset>
              <bitWidth>1</bitWidth>
            </field>
            <field>
              <name>STOP</name>
              <bitOffset>14</bitOffset>
              <bitWidth>1</bitWidth>
            </field>
            <field>
              <name>NACK</name>
              <bitOffset>15</bitOffset>
              <bitWidth>1</bitWidth>
            </field>
            <field>
              <name>NBYTES</name>
              <bitOffset>16</bitOffset>
              <bitWidth>8</bitWidth>
            </field>
            <field>
              <name>RELOAD</name>
              <bitOffset>24</bitOffset>
              <bitWidth>1</bitWidth>
            </field>
            <field>
              <name>AUTOEND</name>
              <bitOffset>25</bitOffset>
              <bitWidth>1</bitWidth>
            </field>
            <field>
              <name>PECBYTE</name>
              <bitOffset>26</bitOffset>
              <bitWidth>1</bitWidth>
            </field>
          </fields>
        </register>
        <register>
          <name>OAR1</name>
          <addressOffset>0x8</addressOffset>
          <size>0x20</size>
          <fields>
            <field>
              <name>OA1</name>
              <bitOffset>0</bitOffset>
              <bitWidth>10</bitWidth>
            </field>
            <field>
              <name>OA1MODE</name>
              <bitOffset>10</bitOffset>
              <bitWidth>1</bitWidth>
            </field>
            <field>
              <name>OA1EN</name>
              <bitOffset>15</bitOffset>
              <bitWidth>1</bitWidth>
            </field>
          </fields>
        </register>
        <register>
          <name>OAR2</name>
          <addressOffset>0xc</addressOffset>
          <size>0x20</size>
          <fields>
            <field>
              <name>OA2</name>
              <bitOffset>1</bitOffset>
              <bitWidth>7</bitWidth>
            </field>
            <field>
              <name>OA2MSK</name>
              <bitOffset>8</bitOffset>
              <bitWidth>3</bitWidth>
            </field>
            <field>
              <name>OA2MASK06</name>
              <bitOffset>9</bitOffset>
              <bitWidth>2</bitWidth>
            </field>
            <field>
              <name>OA2MASK04</name>
              <bitOffset>10</bitOffset>
              <bitWidth>1</bitWidth>
            </field>
            <field>
              <name>OA2EN</name>
              <bitOffset>15</bitOffset>
              <bitWidth>1</bitWidth>
            </field>
          </fields>
        </register>
        <register>
          <name>TIMINGR</name>
          <addressOffset>0x10</addressOffset>
          <size>0x20</size>
          <fields>
            <field>
              <name>SCLL</name>
              <bitOffset>0</bitOffset>
              <bitWidth>8</bitWidth>
            </field>
            <field>
              <name>SCLH</name>
              <bitOffset>8</bitOffset>
              <bitWidth>8</bitWidth>
            </field>
            <field>
              <name>SDADEL</name>
              <bitOffset>16</bitOffset>
              <bitWidth>4</bitWidth>
            </field>
            <field>
              <name>SCLDEL</name>
              <bitOffset>20</bitOffset>
              <bitWidth>4</bitWidth>
            </field>
            <field>
              <name>PRESC</name>
              <bitOffset>28</bitOffset>
              <bitWidth>4</bitWidth>
            </field>
          </fields>
        </register>
        <register>
          <name>TIMEOUTR</name>
          <addressOffset>0x14</addressOffset>
          <size>0x20</size>
          <fields>
            <field>
              <name>TIMEOUTA</name>
              <bitOffset>0</bitOffset>
              <bitWidth>12</bitWidth>
            </field>
            <field>
              <name>TIDLE</name>
              <bitOffset>12</bitOffset>
              <bitWidth>1</bitWidth>
            </field>
            <field>
              <name>TIMOUTEN</name>
              <bitOffset>15</bitOffset>
              <bitWidth>1</bitWidth>
            </field>
            <field>
              <name>TIMEOUTB</name>
              <bitOffset>16</bitOffset>
              <bitWidth>12</bitWidth>
            </field>
            <field>
              <name>TEXTEN</name>
              <bitOffset>31</bitOffset>
              <bitWidth>1</bitWidth>
            </field>
          </fields>
        </register>
        <register>
          <name>ISR</name>
          <addressOffset>0x18</addressOffset>
          <size>0x20</size>
          <fields>
            <field>
              <name>TXE</name>
              <bitOffset>0</bitOffset>
              <bitWidth>1</bitWidth>
            </field>
            <field>
              <name>TXIS</name>
              <bitOffset>1</bitOffset>
              <bitWidth>1</bitWidth>
            </field>
            <field>
              <name>RXNE</name>
              <bitOffset>2</bitOffset>
              <bitWidth>1</bitWidth>
            </field>
            <field>
              <name>ADDR</name>
              <bitOffset>3</bitOffset>
              <bitWidth>1</bitWidth>
            </field>
            <field>
              <name>NACKF</name>
              <bitOffset>4</bitOffset>
              <bitWidth>1</bitWidth>
            </field>
            <field>
              <name>STOPF</name>
              <bitOffset>5</bitOffset>
              <bitWidth>1</bitWidth>
            </field>
            <field>
              <name>TC</name>
              <bitOffset>6</bitOffset>
              <bitWidth>1</bitWidth>
            </field>
            <field>
              <name>TCR</name>
              <bitOffset>7</bitOffset>
              <bitWidth>1</bitWidth>
            </field>
            <field>
              <name>BERR</name>
              <bitOffset>8</bitOffset>
              <bitWidth>1</bitWidth>
            </field>
            <field>
              <name>ARLO</name>
              <bitOffset>9</bitOffset>
              <bitWidth>1</bitWidth>
            </field>
            <field>
              <name>OVR</name>
              <bitOffset>10</bitOffset>
              <bitWidth>1</bitWidth>
            </field>
            <field>
              <name>PECERR</name>
              <bitOffset>11</bitOffset>
              <bitWidth>1</bitWidth>
            </field>
            <field>
              <name>TIMEOUT</name>
              <bitOffset>12</bitOffset>
              <bitWidth>1</bitWidth>
            </field>
            <field>
              <name>ALERT</name>
              <bitOffset>13</bitOffset>
              <bitWidth>1</bitWidth>
            </field>
            <field>
              <name>BUSY</name>
              <bitOffset>15</bitOffset>
              <bitWidth>1</bitWidth>
            </field>
            <field>
              <name>DIR</name>
              <bitOffset>16</bitOffset>
              <bitWidth>1</bitWidth>
            </field>
            <field>
              <name>ADDCODE</name>
              <bitOffset>17</bitOffset>
              <bitWidth>7</bitWidth>
            </field>
          </fields>
        </register>
        <register>
          <name>ICR</name>
          <addressOffset>0x1c</addressOffset>
          <size>0x20</size>
          <fields>
            <field>
              <name>ADDRCF</name>
              <bitOffset>3</bitOffset>
              <bitWidth>1</bitWidth>
            </field>
            <field>
              <name>NACKCF</name>
              <bitOffset>4</bitOffset>
              <bitWidth>1</bitWidth>
            </field>
            <field>
              <name>STOPCF</name>
              <bitOffset>5</bitOffset>
              <bitWidth>1</bitWidth>
            </field>
            <field>
              <name>BERRCF</name>
              <bitOffset>8</bitOffset>
              <bitWidth>1</bitWidth>
            </field>
            <field>
              <name>ARLOCF</name>
              <bitOffset>9</bitOffset>
              <bitWidth>1</bitWidth>
            </field>
            <field>
              <name>OVRCF</name>
              <bitOffset>10</bitOffset>
              <bitWidth>1</bitWidth>
            </field>
            <field>
              <name>PECCF</name>
              <bitOffset>11</bitOffset>
              <bitWidth>1</bitWidth>
            </field>
            <field>
              <name>TIMOUTCF</name>
              <bitOffset>12</bitOffset>
              <bitWidth>1</bitWidth>
            </field>
            <field>
              <name>ALERTCF</name>
              <bitOffset>13</bitOffset>
              <bitWidth>1</bitWidth>
            </field>
          </fields>
        </register>
        <register>
          <name>PECR</name>
          <addressOffset>0x20</addressOffset>
          <size>0x20</size>
          <fields>
            <field>
              <name>PEC</name>
              <bitOffset>0</bitOffset>
              <bitWidth>8</bitWidth>
            </field>
          </fields>
        </register>
        <register>
          <name>RXDR</name>
          <addressOffset>0x24</addressOffset>
          <size>0x20</size>
          <fields>
            <field>
              <name>RXDATA</name>
              <bitOffset>0</bitOffset>
              <bitWidth>8</bitWidth>
            </field>
          </fields>
        </register>
        <register>
          <name>TXDR</name>
          <addressOffset>0x28</addressOffset>
          <size>0x20</size>
          <fields>
            <field>
              <name>TXDATA</name>
              <bitOffset>0</bitOffset>
              <bitWidth>8</bitWidth>
            </field>
          </fields>
        </register>
      </registers>
    </peripheral>
    <peripheral>
      <name>USB</name>
      <baseAddress>0x40005c00</baseAddress>
      <registers>
        <register>
          <name>EP0R</name>
          <addressOffset>0x0</addressOffset>
          <size>0x10</size>
        </register>
        <register>
          <name>EP1R</name>
          <addressOffset>0x4</addressOffset>
          <size>0x10</size>
        </register>
        <register>
          <name>EP2R</name>
          <addressOffset>0x8</addressOffset>
          <size>0x10</size>
        </register>
        <register>
          <name>EP3R</name>
          <addressOffset>0xc</addressOffset>
          <size>0x10</size>
        </register>
        <register>
          <name>EP4R</name>
          <addressOffset>0x10</addressOffset>
          <size>0x10</size>
        </register>
        <register>
          <name>EP5R</name>
          <addressOffset>0x14</addressOffset>
          <size>0x10</size>
        </register>
        <register>
          <name>EP6R</name>
          <addressOffset>0x18</addressOffset>
          <size>0x10</size>
        </register>
        <register>
          <name>EP7R</name>
          <addressOffset>0x1c</addressOffset>
          <size>0x10</size>
        </register>
        <register>
          <name>CNTR</name>
          <addressOffset>0x40</addressOffset>
          <size>0x10</size>
        </register>
        <register>
          <name>ISTR</name>
          <addressOffset>0x44</addressOffset>
          <size>0x10</size>
        </register>
        <register>
          <name>FNR</name>
          <addressOffset>0x48</addressOffset>
          <size>0x10</size>
        </register>
        <register>
          <name>DADDR</name>
          <addressOffset>0x4c</addressOffset>
          <size>0x10</size>
        </register>
        <register>
          <name>BTABLE</name>
          <addressOffset>0x50</addressOffset>
          <size>0x10</size>
        </register>
        <register>
          <name>LPMCSR</name>
          <addressOffset>0x54</addressOffset>
          <size>0x10</size>
        </register>
        <register>
          <name>BCDR</name>
          <addressOffset>0x58</addressOffset>
          <size>0x10</size>
        </register>
      </registers>
    </peripheral>
    <peripheral>
      <name>FDCAN1</name>
      <baseAddress>0x40006400</baseAddress>
      <registers>
        <register>
          <name>CREL</name>
          <addressOffset>0x0</addressOffset>
          <size>0x20</size>
          <fields>
            <field>
              <name>DAY</name>
              <bitOffset>0</bitOffset>
              <bitWidth>8</bitWidth>
            </field>
            <field>
              <name>MON</name>
              <bitOffset>8</bitOffset>
              <bitWidth>8</bitWidth>
            </field>
            <field>
              <name>YEAR</name>
              <bitOffset>16</bitOffset>
              <bitWidth>4</bitWidth>
            </field>
            <field>
              <name>SUBSTEP</name>
              <bitOffset>20</bitOffset>
              <bitWidth>4</bitWidth>
            </field>
            <field>
              <name>STEP</name>
              <bitOffset>24</bitOffset>
              <bitWidth>4</bitWidth>
            </field>
            <field>
              <name>REL</name>
              <bitOffset>28</bitOffset>
              <bitWidth>4</bitWidth>
            </field>
          </fields>
        </register>
        <register>
          <name>ENDN</name>
          <addressOffset>0x4</addressOffset>
          <size>0x20</size>
          <fields>
            <field>
              <name>ETV</name>
              <bitOffset>0</bitOffset>
              <bitWidth>32</bitWidth>
            </field>
          </fields>
        </register>
        <register>
          <name>DBTP</name>
          <addressOffset>0xc</addressOffset>
          <size>0x20</size>
          <fields>
            <field>
              <name>DSJW</name>
              <bitOffset>0</bitOffset>
              <bitWidth>4</bitWidth>
            </field>
            <field>
              <name>DTSEG2</name>
              <bitOffset>4</bitOffset>
              <bitWidth>4</bitWidth>
            </field>
            <field>
              <name>DTSEG1</name>
              <bitOffset>8</bitOffset>
              <bitWidth>5</bitWidth>
            </field>
            <field>
              <name>DBRP</name>
              <bitOffset>16</bitOffset>
              <bitWidth>5</bitWidth>
            </field>
            <field>
              <name>TDC</name>
              <bitOffset>23</bitOffset>
              <bitWidth>1</bitWidth>
            </field>
          </fields>
        </register>
        <register>
          <name>TEST</name>
          <addressOffset>0x10</addressOffset>
          <size>0x20</size>
          <fields>
            <field>
              <name>LBCK</name>
              <bitOffset>4</bitOffset>
              <bitWidth>1</bitWidth>
            </field>
            <field>
              <name>TX</name>
              <bitOffset>5</bitOffset>
              <bitWidth>2</bitWidth>
            </field>
            <field>
              <name>RX</name>
              <bitOffset>7</bitOffset>
              <bitWidth>1</bitWidth>
            </field>
          </fields>
        </register>
        <register>
          <name>RWD</name>
          <addressOffset>0x14</addressOffset>
          <size>0x20</size>
          <fields>
            <field>
              <name>WDC</name>
              <bitOffset>0</bitOffset>
              <bitWidth>8</bitWidth>
            </field>
            <field>
              <name>WDV</name>
              <bitOffset>8</bitOffset>
              <bitWidth>8</bitWidth>
            </field>
          </fields>
        </register>
        <register>
          <name>CCCR</name>
          <addressOffset>0x18</addressOffset>
          <size>0x20</size>
          <fields>
            <field>
              <name>INIT</name>
              <bitOffset>0</bitOffset>
              <bitWidth>1</bitWidth>
            </field>
            <field>
              <name>CCE</name>
              <bitOffset>1</bitOffset>
              <bitWidth>1</bitWidth>
            </field>
            <field>
              <name>ASM</name>
              <bitOffset>2</bitOffset>
              <bitWidth>1</bitWidth>
            </field>
            <field>
              <name>CSA</name>
              <bitOffset>3</bitOffset>
              <bitWidth>1</bitWidth>
            </field>
            <field>
              <name>CSR</name>
              <bitOffset>4</bitOffset>
              <bitWidth>1</bitWidth>
            </field>
            <field>
              <name>MON</name>
              <bitOffset>5</bitOffset>
              <bitWidth>1</bitWidth>
            </field>
            <field>
              <name>DAR</name>
              <bitOffset>6</bitOffset>
              <bitWidth>1</bitWidth>
            </field>
            <field>
              <name>TEST</name>
              <bitOffset>7</bitOffset>
              <bitWidth>1</bitWidth>
            </field>
            <field>
              <name>FDOE</name>
              <bitOffset>8</bitOffset>
              <bitWidth>1</bitWidth>
            </field>
            <field>
              <name>BRSE</name>
              <bitOffset>9</bitOffset>
              <bitWidth>1</bitWidth>
            </field>
            <field>
              <name>PXHD</name>
              <bitOffset>12</bitOffset>
              <bitWidth>1</bitWidth>
            </field>
            <field>
              <name>EFBI</name>
              <bitOffset>13</bitOffset>
              <bitWidth>1</bitWidth>
            </field>
            <field>
              <name>TXP</name>
              <bitOffset>14</bitOffset>
              <bitWidth>1</bitWidth>
            </field>
            <field>
              <name>NISO</name>
              <bitOffset>15</bitOffset>
              <bitWidth>1</bitWidth>
            </field>
          </fields>
        </register>
        <register>
          <name>NBTP</name>
          <addressOffset>0x1c</addressOffset>
          <size>0x20</size>
          <fields>
            <field>
              <name>NTSEG2</name>
              <bitOffset>0</bitOffset>
              <bitWidth>7</bitWidth>
            </field>
            <field>
              <name>NTSEG1</name>
              <bitOffset>8</bitOffset>
              <bitWidth>8</bitWidth>
            </field>
            <field>
              <name>NBRP</name>
              <bitOffset>16</bitOffset>
              <bitWidth>9</bitWidth>
            </field>
            <field>
              <name>NSJW</name>
              <bitOffset>25</bitOffset>
              <bitWidth>7</bitWidth>
            </field>
          </fields>
        </register>
        <register>
          <name>TSCC</name>
          <addressOffset>0x20</addressOffset>
          <size>0x20</size>
          <fields>
            <field>
              <name>TSS</name>
              <bitOffset>0</bitOffset>
              <bitWidth>2</bitWidth>
            </field>
            <field>
              <name>TCP</name>
              <bitOffset>16</bitOffset>
              <bitWidth>4</bitWidth>
            </field>
          </fields>
        </register>
        <register>
          <name>TSCV</name>
          <addressOffset>0x24</addressOffset>
          <size>0x20</size>
          <fields>
            <field>
              <name>TSC</name>
              <bitOffset>0</bitOffset>
              <bitWidth>16</bitWidth>
            </field>
          </fields>
        </register>
        <register>
          <name>TOCC</name>
          <addressOffset>0x28</addressOffset>
          <size>0x20</size>
          <fields>
            <field>
              <name>ETOC</name>
              <bitOffset>0</bitOffset>
              <bitWidth>1</bitWidth>
            </field>
            <field>
              <name>TOS</name>
              <bitOffset>1</bitOffset>
              <bitWidth>2</bitWidth>
            </field>
            <field>
              <name>TOP</name>
              <bitOffset>16</bitOffset>
              <bitWidth>16</bitWidth>
            </field>
          </fields>
        </register>
        <register>
          <name>TOCV</name>
          <addressOffset>0x2c</addressOffset>
          <size>0x20</size>
          <fields>
            <field>
              <name>TOC</name>
              <bitOffset>0</bitOffset>
              <bitWidth>16</bitWidth>
            </field>
          </fields>
        </register>
        <register>
          <name>ECR</name>
          <addressOffset>0x40</addressOffset>
          <size>0x20</size>
          <fields>
            <field>
              <name>TEC</name>
              <bitOffset>0</bitOffset>
              <bitWidth>8</bitWidth>
            </field>
            <field>
              <name>REC</name>
              <bitOffset>8</bitOffset>
              <bitWidth>7</bitWidth>
            </field>
            <field>
              <name>RP</name>
              <bitOffset>15</bitOffset>
              <bitWidth>1</bitWidth>
            </field>
            <field>
              <name>CEL</name>
              <bitOffset>16</bitOffset>
              <bitWidth>8</bitWidth>
            </field>
          </fields>
        </register>
        <register>
          <name>PSR</name>
          <addressOffset>0x44</addressOffset>
          <size>0x20</size>
          <fields>
            <field>
              <name>LEC</name>
              <bitOffset>0</bitOffset>
              <bitWidth>3</bitWidth>
            </field>
            <field>
              <name>ACT</name>
              <bitOffset>3</bitOffset>
              <bitWidth>2</bitWidth>
            </field>
            <field>
              <name>EP</name>
              <bitOffset>5</bitOffset>
              <bitWidth>1</bitWidth>
            </field>
            <field>
              <name>EW</name>
              <bitOffset>6</bitOffset>
              <bitWidth>1</bitWidth>
            </field>
            <field>
              <name>BO</name>
              <bitOffset>7</bitOffset>
              <bitWidth>1</bitWidth>
            </field>
            <field>
              <name>DLEC</name>
              <bitOffset>8</bitOffset>
              <bitWidth>3</bitWidth>
            </field>
            <field>
              <name>RESI</name>
              <bitOffset>11</bitOffset>
              <bitWidth>1</bitWidth>
            </field>
            <field>
              <name>RBRS</name>
              <bitOffset>12</bitOffset>
              <bitWidth>1</bitWidth>
            </field>
            <field>
              <name>REDL</name>
              <bitOffset>13</bitOffset>
              <bitWidth>1</bitWidth>
            </field>
            <field>
              <name>PXE</name>
              <bitOffset>14</bitOffset>
              <bitWidth>1</bitWidth>
            </field>
            <field>
              <name>TDCV</name>
              <bitOffset>16</bitOffset>
              <bitWidth>7</bitWidth>
            </field>
          </fields>
        </register>
        <register>
          <name>TDCR</name>
          <addressOffset>0x48</addressOffset>
          <size>0x20</size>
          <fields>
            <field>
              <name>TDCF</name>
              <bitOffset>0</bitOffset>
              <bitWidth>7</bitWidth>
            </field>
            <field>
              <name>TDCO</name>
              <bitOffset>8</bitOffset>
              <bitWidth>7</bitWidth>
            </field>
          </fields>
        </register>
        <register>
          <name>IR</name>
          <addressOffset>0x50</addressOffset>
          <size>0x20</size>
          <fields>
            <field>
              <name>RF0N</name>
              <bitOffset>0</bitOffset>
              <bitWidth>1</bitWidth>
            </field>
            <field>
              <name>RF0F</name>
              <bitOffset>1</bitOffset>
              <bitWidth>1</bitWidth>
            </field>
            <field>
              <name>RF0L</name>
              <bitOffset>2</bitOffset>
              <bitWidth>1</bitWidth>
            </field>
            <field>
              <name>RF1N</name>
              <bitOffset>3</bitOffset>
              <bitWidth>1</bitWidth>
            </field>
            <field>
              <name>RF1F</name>
              <bitOffset>4</bitOffset>
              <bitWidth>1</bitWidth>
            </field>
            <field>
              <name>RF1L</name>
              <bitOffset>5</bitOffset>
              <bitWidth>1</bitWidth>
            </field>
            <field>
              <name>HPM</name>
              <bitOffset>6</bitOffset>
              <bitWidth>1</bitWidth>
            </field>
            <field>
              <name>TC</name>
              <bitOffset>7</bitOffset>
              <bitWidth>1</bitWidth>
            </field>
            <field>
              <name>TCF</name>
              <bitOffset>8</bitOffset>
              <bitWidth>1</bitWidth>
            </field>
            <field>
              <name>TFE</name>
              <bitOffset>9</bitOffset>
              <bitWidth>1</bitWidth>
            </field>
            <field>
              <name>TEFN</name>
              <bitOffset>10</bitOffset>
              <bitWidth>1</bitWidth>
            </field>
            <field>
              <name>TEFF</name>
              <bitOffset>11</bitOffset>
              <bitWidth>1</bitWidth>
            </field>
            <field>
              <name>TEFL</name>
              <bitOffset>12</bitOffset>
              <bitWidth>1</bitWidth>
            </field>
            <field>
              <name>TSW</name>
              <bitOffset>13</bitOffset>
              <bitWidth>1</bitWidth>
            </field>
            <field>
              <name>MRAF</name>
              <bitOffset>14</bitOffset>
              <bitWidth>1</bitWidth>
            </field>
            <field>
              <name>TOO</name>
              <bitOffset>15</bitOffset>
              <bitWidth>1</bitWidth>
            </field>
            <field>
              <name>ELO</name>
              <bitOffset>16</bitOffset>
              <bitWidth>1</bitWidth>
            </field>
            <field>
              <name>EP</name>
              <bitOffset>17</bitOffset>
              <bitWidth>1</bitWidth>
            </field>
            <field>
              <name>EW</name>
              <bitOffset>18</bitOffset>
              <bitWidth>1</bitWidth>
            </field>
            <field>
              <name>BO</name>
              <bitOffset>19</bitOffset>
              <bitWidth>1</bitWidth>
            </field>
            <field>
              <name>WDI</name>
              <bitOffset>20</bitOffset>
              <bitWidth>1</bitWidth>
            </field>
            <field>
              <name>PEA</name>
              <bitOffset>21</bitOffset>
              <bitWidth>1</bitWidth>
            </field>
            <field>
              <name>PED</name>
              <bitOffset>22</bitOffset>
              <bitWidth>1</bitWidth>
            </field>
            <field>
              <name>ARA</name>
              <bitOffset>23</bitOffset>
              <bitWidth>1</bitWidth>
            </field>
          </fields>
        </register>
        <register>
          <name>IE</name>
          <addressOffset>0x54</addressOffset>
          <size>0x20</size>
          <fields>
            <field>
              <name>RF0NE</name>
              <bitOffset>0</bitOffset>
              <bitWidth>1</bitWidth>
            </field>
            <field>
              <name>RF0FE</name>
              <bitOffset>1</bitOffset>
              <bitWidth>1</bitWidth>
            </field>
            <field>
              <name>RF0LE</name>
              <bitOffset>2</bitOffset>
              <bitWidth>1</bitWidth>
            </field>
            <field>
              <name>RF1NE</name>
              <bitOffset>3</bitOffset>
              <bitWidth>1</bitWidth>
            </field>
            <field>
              <name>RF1FE</name>
              <bitOffset>4</bitOffset>
              <bitWidth>1</bitWidth>
            </field>
            <field>
              <name>RF1LE</name>
              <bitOffset>5</bitOffset>
              <bitWidth>1</bitWidth>
            </field>
            <field>
              <name>HPME</name>
              <bitOffset>6</bitOffset>
              <bitWidth>1</bitWidth>
            </field>
            <field>
              <name>TCE</name>
              <bitOffset>7</bitOffset>
              <bitWidth>1</bitWidth>
            </field>
            <field>
              <name>TCFE</name>
              <bitOffset>8</bitOffset>
              <bitWidth>1</bitWidth>
            </field>
            <field>
              <name>TFEE</name>
              <bitOffset>9</bitOffset>
              <bitWidth>1</bitWidth>
            </field>
            <field>
              <name>TEFNE</name>
              <bitOffset>10</bitOffset>
              <bitWidth>1</bitWidth>
            </field>
            <field>
              <name>TEFFE</name>
              <bitOffset>11</bitOffset>
              <bitWidth>1</bitWidth>
            </field>
            <field>
              <name>TEFLE</name>
              <bitOffset>12</bitOffset>
              <bitWidth>1</bitWidth>
            </field>
            <field>
              <name>TSWE</name>
              <bitOffset>13</bitOffset>
              <bitWidth>1</bitWidth>
            </field>
            <field>
              <name>MRAFE</name>
              <bitOffset>14</bitOffset>
              <bitWidth>1</bitWidth>
            </field>
            <field>
              <name>TOOE</name>
              <bitOffset>15</bitOffset>
              <bitWidth>1</bitWidth>
            </field>
            <field>
              <name>ELOE</name>
              <bitOffset>16</bitOffset>
              <bitWidth>1</bitWidth>
            </field>
            <field>
              <name>EPE</name>
              <bitOffset>17</bitOffset>
              <bitWidth>1</bitWidth>
            </field>
            <field>
              <name>EWE</name>
              <bitOffset>18</bitOffset>
              <bitWidth>1</bitWidth>
            </field>
            <field>
              <name>BOE</name>
              <bitOffset>19</bitOffset>
              <bitWidth>1</bitWidth>
            </field>
            <field>
              <name>WDIE</name>
              <bitOffset>20</bitOffset>
              <bitWidth>1</bitWidth>
            </field>
            <field>
              <name>PEAE</name>
              <bitOffset>21</bitOffset>
              <bitWidth>1</bitWidth>
            </field>
            <field>
              <name>PEDE</name>
              <bitOffset>22</bitOffset>
              <bitWidth>1</bitWidth>
            </field>
            <field>
              <name>ARAE</name>
              <bitOffset>23</bitOffset>
              <bitWidth>1</bitWidth>
            </field>
          </fields>
        </register>
        <register>
          <name>ILS</name>
          <addressOffset>0x58</addressOffset>
          <size>0x20</size>
          <fields>
            <field>
              <name>RXFIFO0</name>
              <bitOffset>0</bitOffset>
              <bitWidth>1</bitWidth>
            </field>
            <field>
              <name>RXFIFO1</name>
              <bitOffset>1</bitOffset>
              <bitWidth>1</bitWidth>
            </field>
            <field>
              <name>SMSG</name>
              <bitOffset>2</bitOffset>
              <bitWidth>1</bitWidth>
            </field>
            <field>
              <name>TFERR</name>
              <bitOffset>3</bitOffset>
              <bitWidth>1</bitWidth>
            </field>
            <field>
              <name>MISC</name>
              <bitOffset>4</bitOffset>
              <bitWidth>1</bitWidth>
            </field>
            <field>
              <name>BERR</name>
              <bitOffset>5</bitOffset>
              <bitWidth>1</bitWidth>
            </field>
            <field>
              <name>PERR</name>
              <bitOffset>6</bitOffset>
              <bitWidth>1</bitWidth>
            </field>
          </fields>
        </register>
        <register>
          <name>ILE</name>
          <addressOffset>0x5c</addressOffset>
          <size>0x20</size>
          <fields>
            <field>
              <name>EINT0</name>
              <bitOffset>0</bitOffset>
              <bitWidth>1</bitWidth>
            </field>
            <field>
              <name>EINT1</name>
              <bitOffset>1</bitOffset>
              <bitWidth>1</bitWidth>
            </field>
          </fields>
        </register>
        <register>
          <name>RXGFC</name>
          <addressOffset>0x80</addressOffset>
          <size>0x20</size>
          <fields>
            <field>
              <name>RRFE</name>
              <bitOffset>0</bitOffset>
              <bitWidth>1</bitWidth>
            </field>
            <field>
              <name>RRFS</name>
              <bitOffset>1</bitOffset>
              <bitWidth>1</bitWidth>
            </field>
            <field>
              <name>ANFE</name>
              <bitOffset>2</bitOffset>
              <bitWidth>2</bitWidth>
            </field>
            <field>
              <name>ANFS</name>
              <bitOffset>4</bitOffset>
              <bitWidth>2</bitWidth>
            </field>
            <field>
              <name>F1OM</name>
              <bitOffset>8</bitOffset>
              <bitWidth>1</bitWidth>
            </field>
            <field>
              <name>F0OM</name>
              <bitOffset>9</bitOffset>
              <bitWidth>1</bitWidth>
            </field>
            <field>
              <name>LSS</name>
              <bitOffset>16</bitOffset>
              <bitWidth>5</bitWidth>
            </field>
            <field>
              <name>LSE</name>
              <bitOffset>24</bitOffset>
              <bitWidth>4</bitWidth>
            </field>
          </fields>
        </register>
        <register>
          <name>XIDAM</name>
          <addressOffset>0x84</addressOffset>
          <size>0x20</size>
          <fields>
            <field>
              <name>EIDM</name>
              <bitOffset>0</bitOffset>
              <bitWidth>29</bitWidth>
            </field>
          </fields>
        </register>
        <register>
          <name>HPMS</name>
          <addressOffset>0x88</addressOffset>
          <size>0x20</size>
          <fields>
            <field>
              <name>BIDX</name>
              <bitOffset>0</bitOffset>
              <bitWidth>3</bitWidth>
            </field>
            <field>
              <name>MSI</name>
              <bitOffset>6</bitOffset>
              <bitWidth>2</bitWidth>
            </field>
            <field>
              <name>FIDX</name>
              <bitOffset>8</bitOffset>
              <bitWidth>5</bitWidth>
            </field>
            <field>
              <name>FLST</name>
              <bitOffset>15</bitOffset>
              <bitWidth>1</bitWidth>
            </field>
          </fields>
        </register>
        <register>
          <name>RXF0S</name>
          <addressOffset>0x90</addressOffset>
          <size>0x20</size>
          <fields>
            <field>
              <name>F0FL</name>
              <bitOffset>0</bitOffset>
              <bitWidth>4</bitWidth>
            </field>
            <field>
              <name>F0GI</name>
              <bitOffset>8</bitOffset>
              <bitWidth>2</bitWidth>
            </field>
            <field>
              <name>F0PI</name>
              <bitOffset>16</bitOffset>
              <bitWidth>2</bitWidth>
            </field>
            <field>
              <name>F0F</name>
              <bitOffset>24</bitOffset>
              <bitWidth>1</bitWidth>
            </field>
            <field>
              <name>RF0L</name>
              <bitOffset>25</bitOffset>
              <bitWidth>1</bitWidth>
            </field>
          </fields>
        </register>
        <register>
          <name>RXF0A</name>
          <addressOffset>0x94</addressOffset>
          <size>0x20</size>
          <fields>
            <field>
              <name>F0AI</name>
              <bitOffset>0</bitOffset>
              <bitWidth>3</bitWidth>
            </field>
          </fields>
        </register>
        <register>
          <name>RXF1S</name>
          <addressOffset>0x98</addressOffset>
          <size>0x20</size>
          <fields>
            <field>
              <name>F1FL</name>
              <bitOffset>0</bitOffset>
              <bitWidth>4</bitWidth>
            </field>
            <field>
              <name>F1GI</name>
              <bitOffset>8</bitOffset>
              <bitWidth>2</bitWidth>
            </field>
            <field>
              <name>F1PI</name>
              <bitOffset>16</bitOffset>
              <bitWidth>2</bitWidth>
            </field>
            <field>
              <name>F1F</name>
              <bitOffset>24</bitOffset>
              <bitWidth>1</bitWidth>
            </field>
            <field>
              <name>RF1L</name>
              <bitOffset>25</bitOffset>
              <bitWidth>1</bitWidth>
            </field>
          </fields>
        </register>
        <register>
          <name>RXF1A</name>
          <addressOffset>0x9c</addressOffset>
          <size>0x20</size>
          <fields>
            <field>
              <name>F1AI</name>
              <bitOffset>0</bitOffset>
              <bitWidth>3</bitWidth>
            </field>
          </fields>
        </register>
        <register>
          <name>TXBC</name>
          <addressOffset>0xc0</addressOffset>
          <size>0x20</size>
          <fields>
            <field>
              <name>TFQM</name>
              <bitOffset>24</bitOffset>
              <bitWidth>1</bitWidth>
            </field>
          </fields>
        </register>
        <register>
          <name>TXFQS</name>
          <addressOffset>0xc4</addressOffset>
          <size>0x20</size>
          <fields>
            <field>
              <name>TFFL</name>
              <bitOffset>0</bitOffset>
              <bitWidth>3</bitWidth>
            </field>
            <field>
              <name>TFGI</name>
              <bitOffset>8</bitOffset>
              <bitWidth>2</bitWidth>
            </field>
            <field>
              <name>TFQPI</name>
              <bitOffset>16</bitOffset>
              <bitWidth>2</bitWidth>
            </field>
            <field>
              <name>TFQF</name>
              <bitOffset>21</bitOffset>
              <bitWidth>1</bitWidth>
            </field>
          </fields>
        </register>
        <register>
          <name>TXBRP</name>
          <addressOffset>0xc8</addressOffset>
          <size>0x20</size>
          <fields>
            <field>
              <name>TRP</name>
              <bitOffset>0</bitOffset>
              <bitWidth>3</bitWidth>
            </field>
          </fields>
        </register>
        <register>
          <name>TXBAR</name>
          <addressOffset>0xcc</addressOffset>
          <size>0x20</size>
          <fields>
            <field>
              <name>AR</name>
              <bitOffset>0</bitOffset>
              <bitWidth>3</bitWidth>
            </field>
          </fields>
        </register>
        <register>
          <name>TXBCR</name>
          <addressOffset>0xd0</addressOffset>
          <size>0x20</size>
          <fields>
            <field>
              <name>CR</name>
              <bitOffset>0</bitOffset>
              <bitWidth>3</bitWidth>
            </field>
          </fields>
        </register>
        <register>
          <name>TXBTO</name>
          <addressOffset>0xd4</addressOffset>
          <size>0x20</size>
          <fields>
            <field>
              <name>TO</name>
              <bitOffset>0</bitOffset>
              <bitWidth>3</bitWidth>
            </field>
          </fields>
        </register>
        <register>
          <name>TXBCF</name>
          <addressOffset>0xd8</addressOffset>
          <size>0x20</size>
          <fields>
            <field>
              <name>CF</name>
              <bitOffset>0</bitOffset>
              <bitWidth>3</bitWidth>
            </field>
          </fields>
        </register>
        <register>
          <name>TXBTIE</name>
          <addressOffset>0xdc</addressOffset>
          <size>0x20</size>
          <fields>
            <field>
              <name>TIE</name>
              <bitOffset>0</bitOffset>
              <bitWidth>3</bitWidth>
            </field>
          </fields>
        </register>
        <register>
          <name>TXBCIE</name>
          <addressOffset>0xe0</addressOffset>
          <size>0x20</size>
          <fields>
            <field>
              <name>CFIE</name>
              <bitOffset>0</bitOffset>
              <bitWidth>3</bitWidth>
            </field>
          </fields>
        </register>
        <register>
          <name>TXEFS</name>
          <addressOffset>0xe4</addressOffset>
          <size>0x20</size>
          <fields>
            <field>
              <name>EFFL</name>
              <bitOffset>0</bitOffset>
              <bitWidth>3</bitWidth>
            </field>
            <field>
              <name>EFGI</name>
              <bitOffset>8</bitOffset>
              <bitWidth>2</bitWidth>
            </field>
            <field>
              <name>EFPI</name>
              <bitOffset>16</bitOffset>
              <bitWidth>2</bitWidth>
            </field>
            <field>
              <name>EFF</name>
              <bitOffset>24</bitOffset>
              <bitWidth>1</bitWidth>
            </field>
            <field>
              <name>TEFL</name>
              <bitOffset>25</bitOffset>
              <bitWidth>1</bitWidth>
            </field>
          </fields>
        </register>
        <register>
          <name>TXEFA</name>
          <addressOffset>0xe8</addressOffset>
          <size>0x20</size>
          <fields>
            <field>
              <name>EFAI</name>
              <bitOffset>0</bitOffset>
              <bitWidth>2</bitWidth>
            </field>
          </fields>
        </register>
      </registers>
    </peripheral>
    <peripheral>
      <name>FDCAN_CONFIG</name>
      <baseAddress>0x40006500</baseAddress>
      <registers>
        <register>
          <name>CKDIV</name>
          <addressOffset>0x0</addressOffset>
          <size>0x20</size>
          <fields>
            <field>
              <name>PDIV</name>
              <bitOffset>0</bitOffset>
              <bitWidth>4</bitWidth>
            </field>
          </fields>
        </register>
      </registers>
    </peripheral>
    <peripheral>
      <name>FDCAN2</name>
      <baseAddress>0x40006800</baseAddress>
      <registers>
        <register>
          <name>CREL</name>
          <addressOffset>0x0</addressOffset>
          <size>0x20</size>
          <fields>
            <field>
              <name>DAY</name>
              <bitOffset>0</bitOffset>
              <bitWidth>8</bitWidth>
            </field>
            <field>
              <name>MON</name>
              <bitOffset>8</bitOffset>
              <bitWidth>8</bitWidth>
            </field>
            <field>
              <name>YEAR</name>
              <bitOffset>16</bitOffset>
              <bitWidth>4</bitWidth>
            </field>
            <field>
              <name>SUBSTEP</name>
              <bitOffset>20</bitOffset>
              <bitWidth>4</bitWidth>
            </field>
            <field>
              <name>STEP</name>
              <bitOffset>24</bitOffset>
              <bitWidth>4</bitWidth>
            </field>
            <field>
              <name>REL</name>
              <bitOffset>28</bitOffset>
              <bitWidth>4</bitWidth>
            </field>
          </fields>
        </register>
        <register>
          <name>ENDN</name>
          <addressOffset>0x4</addressOffset>
          <size>0x20</size>
          <fields>
            <field>
              <name>ETV</name>
              <bitOffset>0</bitOffset>
              <bitWidth>32</bitWidth>
            </field>
          </fields>
        </register>
        <register>
          <name>DBTP</name>
          <addressOffset>0xc</addressOffset>
          <size>0x20</size>
          <fields>
            <field>
              <name>DSJW</name>
              <bitOffset>0</bitOffset>
              <bitWidth>4</bitWidth>
            </field>
            <field>
              <name>DTSEG2</name>
              <bitOffset>4</bitOffset>
              <bitWidth>4</bitWidth>
            </field>
            <field>
              <name>DTSEG1</name>
              <bitOffset>8</bitOffset>
              <bitWidth>5</bitWidth>
            </field>
            <field>
              <name>DBRP</name>
              <bitOffset>16</bitOffset>
              <bitWidth>5</bitWidth>
            </field>
            <field>
              <name>TDC</name>
              <bitOffset>23</bitOffset>
              <bitWidth>1</bitWidth>
            </field>
          </fields>
        </register>
        <register>
          <name>TEST</name>
          <addressOffset>0x10</addressOffset>
          <size>0x20</size>
          <fields>
            <field>
              <name>LBCK</name>
              <bitOffset>4</bitOffset>
              <bitWidth>1</bitWidth>
            </field>
            <field>
              <name>TX</name>
              <bitOffset>5</bitOffset>
              <bitWidth>2</bitWidth>
            </field>
            <field>
              <name>RX</name>
              <bitOffset>7</bitOffset>
              <bitWidth>1</bitWidth>
            </field>
          </fields>
        </register>
        <register>
          <name>RWD</name>
          <addressOffset>0x14</addressOffset>
          <size>0x20</size>
          <fields>
            <field>
              <name>WDC</name>
              <bitOffset>0</bitOffset>
              <bitWidth>8</bitWidth>
            </field>
            <field>
              <name>WDV</name>
              <bitOffset>8</bitOffset>
              <bitWidth>8</bitWidth>
            </field>
          </fields>
        </register>
        <register>
          <name>CCCR</name>
          <addressOffset>0x18</addressOffset>
          <size>0x20</size>
          <fields>
            <field>
              <name>INIT</name>
              <bitOffset>0</bitOffset>
              <bitWidth>1</bitWidth>
            </field>
            <field>
              <name>CCE</name>
              <bitOffset>1</bitOffset>
              <bitWidth>1</bitWidth>
            </field>
            <field>
              <name>ASM</name>
              <bitOffset>2</bitOffset>
              <bitWidth>1</bitWidth>
            </field>
            <field>
              <name>CSA</name>
              <bitOffset>3</bitOffset>
              <bitWidth>1</bitWidth>
            </field>
            <field>
              <name>CSR</name>
              <bitOffset>4</bitOffset>
              <bitWidth>1</bitWidth>
            </field>
            <field>
              <name>MON</name>
              <bitOffset>5</bitOffset>
              <bitWidth>1</bitWidth>
            </field>
            <field>
              <name>DAR</name>
              <bitOffset>6</bitOffset>
              <bitWidth>1</bitWidth>
            </field>
            <field>
              <name>TEST</name>
              <bitOffset>7</bitOffset>
              <bitWidth>1</bitWidth>
            </field>
            <field>
              <name>FDOE</name>
              <bitOffset>8</bitOffset>
              <bitWidth>1</bitWidth>
            </field>
            <field>
              <name>BRSE</name>
              <bitOffset>9</bitOffset>
              <bitWidth>1</bitWidth>
            </field>
            <field>
              <name>PXHD</name>
              <bitOffset>12</bitOffset>
              <bitWidth>1</bitWidth>
            </field>
            <field>
              <name>EFBI</name>
              <bitOffset>13</bitOffset>
              <bitWidth>1</bitWidth>
            </field>
            <field>
              <name>TXP</name>
              <bitOffset>14</bitOffset>
              <bitWidth>1</bitWidth>
            </field>
            <field>
              <name>NISO</name>
              <bitOffset>15</bitOffset>
              <bitWidth>1</bitWidth>
            </field>
          </fields>
        </register>
        <register>
          <name>NBTP</name>
          <addressOffset>0x1c</addressOffset>
          <size>0x20</size>
          <fields>
            <field>
              <name>NTSEG2</name>
              <bitOffset>0</bitOffset>
              <bitWidth>7</bitWidth>
            </field>
            <field>
              <name>NTSEG1</name>
              <bitOffset>8</bitOffset>
              <bitWidth>8</bitWidth>
            </field>
            <field>
              <name>NBRP</name>
              <bitOffset>16</bitOffset>
              <bitWidth>9</bitWidth>
            </field>
            <field>
              <name>NSJW</name>
              <bitOffset>25</bitOffset>
              <bitWidth>7</bitWidth>
            </field>
          </fields>
        </register>
        <register>
          <name>TSCC</name>
          <addressOffset>0x20</addressOffset>
          <size>0x20</size>
          <fields>
            <field>
              <name>TSS</name>
              <bitOffset>0</bitOffset>
              <bitWidth>2</bitWidth>
            </field>
            <field>
              <name>TCP</name>
              <bitOffset>16</bitOffset>
              <bitWidth>4</bitWidth>
            </field>
          </fields>
        </register>
        <register>
          <name>TSCV</name>
          <addressOffset>0x24</addressOffset>
          <size>0x20</size>
          <fields>
            <field>
              <name>TSC</name>
              <bitOffset>0</bitOffset>
              <bitWidth>16</bitWidth>
            </field>
          </fields>
        </register>
        <register>
          <name>TOCC</name>
          <addressOffset>0x28</addressOffset>
          <size>0x20</size>
          <fields>
            <field>
              <name>ETOC</name>
              <bitOffset>0</bitOffset>
              <bitWidth>1</bitWidth>
            </field>
            <field>
              <name>TOS</name>
              <bitOffset>1</bitOffset>
              <bitWidth>2</bitWidth>
            </field>
            <field>
              <name>TOP</name>
              <bitOffset>16</bitOffset>
              <bitWidth>16</bitWidth>
            </field>
          </fields>
        </register>
        <register>
          <name>TOCV</name>
          <addressOffset>0x2c</addressOffset>
          <size>0x20</size>
          <fields>
            <field>
              <name>TOC</name>
              <bitOffset>0</bitOffset>
              <bitWidth>16</bitWidth>
            </field>
          </fields>
        </register>
        <register>
          <name>ECR</name>
          <addressOffset>0x40</addressOffset>
          <size>0x20</size>
          <fields>
            <field>
              <name>TEC</name>
              <bitOffset>0</bitOffset>
              <bitWidth>8</bitWidth>
            </field>
            <field>
              <name>REC</name>
              <bitOffset>8</bitOffset>
              <bitWidth>7</bitWidth>
            </field>
            <field>
              <name>RP</name>
              <bitOffset>15</bitOffset>
              <bitWidth>1</bitWidth>
            </field>
            <field>
              <name>CEL</name>
              <bitOffset>16</bitOffset>
              <bitWidth>8</bitWidth>
            </field>
          </fields>
        </register>
        <register>
          <name>PSR</name>
          <addressOffset>0x44</addressOffset>
          <size>0x20</size>
          <fields>
            <field>
              <name>LEC</name>
              <bitOffset>0</bitOffset>
              <bitWidth>3</bitWidth>
            </field>
            <field>
              <name>ACT</name>
              <bitOffset>3</bitOffset>
              <bitWidth>2</bitWidth>
            </field>
            <field>
              <name>EP</name>
              <bitOffset>5</bitOffset>
              <bitWidth>1</bitWidth>
            </field>
            <field>
              <name>EW</name>
              <bitOffset>6</bitOffset>
              <bitWidth>1</bitWidth>
            </field>
            <field>
              <name>BO</name>
              <bitOffset>7</bitOffset>
              <bitWidth>1</bitWidth>
            </field>
            <field>
              <name>DLEC</name>
              <bitOffset>8</bitOffset>
              <bitWidth>3</bitWidth>
            </field>
            <field>
              <name>RESI</name>
              <bitOffset>11</bitOffset>
              <bitWidth>1</bitWidth>
            </field>
            <field>
              <name>RBRS</name>
              <bitOffset>12</bitOffset>
              <bitWidth>1</bitWidth>
            </field>
            <field>
              <name>REDL</name>
              <bitOffset>13</bitOffset>
              <bitWidth>1</bitWidth>
            </field>
            <field>
              <name>PXE</name>
              <bitOffset>14</bitOffset>
              <bitWidth>1</bitWidth>
            </field>
            <field>
              <name>TDCV</name>
              <bitOffset>16</bitOffset>
              <bitWidth>7</bitWidth>
            </field>
          </fields>
        </register>
        <register>
          <name>TDCR</name>
          <addressOffset>0x48</addressOffset>
          <size>0x20</size>
          <fields>
            <field>
              <name>TDCF</name>
              <bitOffset>0</bitOffset>
              <bitWidth>7</bitWidth>
            </field>
            <field>
              <name>TDCO</name>
              <bitOffset>8</bitOffset>
              <bitWidth>7</bitWidth>
            </field>
          </fields>
        </register>
        <register>
          <name>IR</name>
          <addressOffset>0x50</addressOffset>
          <size>0x20</size>
          <fields>
            <field>
              <name>RF0N</name>
              <bitOffset>0</bitOffset>
              <bitWidth>1</bitWidth>
            </field>
            <field>
              <name>RF0F</name>
              <bitOffset>1</bitOffset>
              <bitWidth>1</bitWidth>
            </field>
            <field>
              <name>RF0L</name>
              <bitOffset>2</bitOffset>
              <bitWidth>1</bitWidth>
            </field>
            <field>
              <name>RF1N</name>
              <bitOffset>3</bitOffset>
              <bitWidth>1</bitWidth>
            </field>
            <field>
              <name>RF1F</name>
              <bitOffset>4</bitOffset>
              <bitWidth>1</bitWidth>
            </field>
            <field>
              <name>RF1L</name>
              <bitOffset>5</bitOffset>
              <bitWidth>1</bitWidth>
            </field>
            <field>
              <name>HPM</name>
              <bitOffset>6</bitOffset>
              <bitWidth>1</bitWidth>
            </field>
            <field>
              <name>TC</name>
              <bitOffset>7</bitOffset>
              <bitWidth>1</bitWidth>
            </field>
            <field>
              <name>TCF</name>
              <bitOffset>8</bitOffset>
              <bitWidth>1</bitWidth>
            </field>
            <field>
              <name>TFE</name>
              <bitOffset>9</bitOffset>
              <bitWidth>1</bitWidth>
            </field>
            <field>
              <name>TEFN</name>
              <bitOffset>10</bitOffset>
              <bitWidth>1</bitWidth>
            </field>
            <field>
              <name>TEFF</name>
              <bitOffset>11</bitOffset>
              <bitWidth>1</bitWidth>
            </field>
            <field>
              <name>TEFL</name>
              <bitOffset>12</bitOffset>
              <bitWidth>1</bitWidth>
            </field>
            <field>
              <name>TSW</name>
              <bitOffset>13</bitOffset>
              <bitWidth>1</bitWidth>
            </field>
            <field>
              <name>MRAF</name>
              <bitOffset>14</bitOffset>
              <bitWidth>1</bitWidth>
            </field>
            <field>
              <name>TOO</name>
              <bitOffset>15</bitOffset>
              <bitWidth>1</bitWidth>
            </field>
            <field>
              <name>ELO</name>
              <bitOffset>16</bitOffset>
              <bitWidth>1</bitWidth>
            </field>
            <field>
              <name>EP</name>
              <bitOffset>17</bitOffset>
              <bitWidth>1</bitWidth>
            </field>
            <field>
              <name>EW</name>
              <bitOffset>18</bitOffset>
              <bitWidth>1</bitWidth>
            </field>
            <field>
              <name>BO</name>
              <bitOffset>19</bitOffset>
              <bitWidth>1</bitWidth>
            </field>
            <field>
              <name>WDI</name>
              <bitOffset>20</bitOffset>
              <bitWidth>1</bitWidth>
            </field>
            <field>
              <name>PEA</name>
              <bitOffset>21</bitOffset>
              <bitWidth>1</bitWidth>
            </field>
            <field>
              <name>PED</name>
              <bitOffset>22</bitOffset>
              <bitWidth>1</bitWidth>
            </field>
            <field>
              <name>ARA</name>
              <bitOffset>23</bitOffset>
              <bitWidth>1</bitWidth>
            </field>
          </fields>
        </register>
        <register>
          <name>IE</name>
          <addressOffset>0x54</addressOffset>
          <size>0x20</size>
          <fields>
            <field>
              <name>RF0NE</name>
              <bitOffset>0</bitOffset>
              <bitWidth>1</bitWidth>
            </field>
            <field>
              <name>RF0FE</name>
              <bitOffset>1</bitOffset>
              <bitWidth>1</bitWidth>
            </field>
            <field>
              <name>RF0LE</name>
              <bitOffset>2</bitOffset>
              <bitWidth>1</bitWidth>
            </field>
            <field>
              <name>RF1NE</name>
              <bitOffset>3</bitOffset>
              <bitWidth>1</bitWidth>
            </field>
            <field>
              <name>RF1FE</name>
              <bitOffset>4</bitOffset>
              <bitWidth>1</bitWidth>
            </field>
            <field>
              <name>RF1LE</name>
              <bitOffset>5</bitOffset>
              <bitWidth>1</bitWidth>
            </field>
            <field>
              <name>HPME</name>
              <bitOffset>6</bitOffset>
              <bitWidth>1</bitWidth>
            </field>
            <field>
              <name>TCE</name>
              <bitOffset>7</bitOffset>
              <bitWidth>1</bitWidth>
            </field>
            <field>
              <name>TCFE</name>
              <bitOffset>8</bitOffset>
              <bitWidth>1</bitWidth>
            </field>
            <field>
              <name>TFEE</name>
              <bitOffset>9</bitOffset>
              <bitWidth>1</bitWidth>
            </field>
            <field>
              <name>TEFNE</name>
              <bitOffset>10</bitOffset>
              <bitWidth>1</bitWidth>
            </field>
            <field>
              <name>TEFFE</name>
              <bitOffset>11</bitOffset>
              <bitWidth>1</bitWidth>
            </field>
            <field>
              <name>TEFLE</name>
              <bitOffset>12</bitOffset>
              <bitWidth>1</bitWidth>
            </field>
            <field>
              <name>TSWE</name>
              <bitOffset>13</bitOffset>
              <bitWidth>1</bitWidth>
            </field>
            <field>
              <name>MRAFE</name>
              <bitOffset>14</bitOffset>
              <bitWidth>1</bitWidth>
            </field>
            <field>
              <name>TOOE</name>
              <bitOffset>15</bitOffset>
              <bitWidth>1</bitWidth>
            </field>
            <field>
              <name>ELOE</name>
              <bitOffset>16</bitOffset>
              <bitWidth>1</bitWidth>
            </field>
            <field>
              <name>EPE</name>
              <bitOffset>17</bitOffset>
              <bitWidth>1</bitWidth>
            </field>
            <field>
              <name>EWE</name>
              <bitOffset>18</bitOffset>
              <bitWidth>1</bitWidth>
            </field>
            <field>
              <name>BOE</name>
              <bitOffset>19</bitOffset>
              <bitWidth>1</bitWidth>
            </field>
            <field>
              <name>WDIE</name>
              <bitOffset>20</bitOffset>
              <bitWidth>1</bitWidth>
            </field>
            <field>
              <name>PEAE</name>
              <bitOffset>21</bitOffset>
              <bitWidth>1</bitWidth>
            </field>
            <field>
              <name>PEDE</name>
              <bitOffset>22</bitOffset>
              <bitWidth>1</bitWidth>
            </field>
            <field>
              <name>ARAE</name>
              <bitOffset>23</bitOffset>
              <bitWidth>1</bitWidth>
            </field>
          </fields>
        </register>
        <register>
          <name>ILS</name>
          <addressOffset>0x58</addressOffset>
          <size>0x20</size>
          <fields>
            <field>
              <name>RXFIFO0</name>
              <bitOffset>0</bitOffset>
              <bitWidth>1</bitWidth>
            </field>
            <field>
              <name>RXFIFO1</name>
              <bitOffset>1</bitOffset>
              <bitWidth>1</bitWidth>
            </field>
            <field>
              <name>SMSG</name>
              <bitOffset>2</bitOffset>
              <bitWidth>1</bitWidth>
            </field>
            <field>
              <name>TFERR</name>
              <bitOffset>3</bitOffset>
              <bitWidth>1</bitWidth>
            </field>
            <field>
              <name>MISC</name>
              <bitOffset>4</bitOffset>
              <bitWidth>1</bitWidth>
            </field>
            <field>
              <name>BERR</name>
              <bitOffset>5</bitOffset>
              <bitWidth>1</bitWidth>
            </field>
            <field>
              <name>PERR</name>
              <bitOffset>6</bitOffset>
              <bitWidth>1</bitWidth>
            </field>
          </fields>
        </register>
        <register>
          <name>ILE</name>
          <addressOffset>0x5c</addressOffset>
          <size>0x20</size>
          <fields>
            <field>
              <name>EINT0</name>
              <bitOffset>0</bitOffset>
              <bitWidth>1</bitWidth>
            </field>
            <field>
              <name>EINT1</name>
              <bitOffset>1</bitOffset>
              <bitWidth>1</bitWidth>
            </field>
          </fields>
        </register>
        <register>
          <name>RXGFC</name>
          <addressOffset>0x80</addressOffset>
          <size>0x20</size>
          <fields>
            <field>
              <name>RRFE</name>
              <bitOffset>0</bitOffset>
              <bitWidth>1</bitWidth>
            </field>
            <field>
              <name>RRFS</name>
              <bitOffset>1</bitOffset>
              <bitWidth>1</bitWidth>
            </field>
            <field>
              <name>ANFE</name>
              <bitOffset>2</bitOffset>
              <bitWidth>2</bitWidth>
            </field>
            <field>
              <name>ANFS</name>
              <bitOffset>4</bitOffset>
              <bitWidth>2</bitWidth>
            </field>
            <field>
              <name>F1OM</name>
              <bitOffset>8</bitOffset>
              <bitWidth>1</bitWidth>
            </field>
            <field>
              <name>F0OM</name>
              <bitOffset>9</bitOffset>
              <bitWidth>1</bitWidth>
            </field>
            <field>
              <name>LSS</name>
              <bitOffset>16</bitOffset>
              <bitWidth>5</bitWidth>
            </field>
            <field>
              <name>LSE</name>
              <bitOffset>24</bitOffset>
              <bitWidth>4</bitWidth>
            </field>
          </fields>
        </register>
        <register>
          <name>XIDAM</name>
          <addressOffset>0x84</addressOffset>
          <size>0x20</size>
          <fields>
            <field>
              <name>EIDM</name>
              <bitOffset>0</bitOffset>
              <bitWidth>29</bitWidth>
            </field>
          </fields>
        </register>
        <register>
          <name>HPMS</name>
          <addressOffset>0x88</addressOffset>
          <size>0x20</size>
          <fields>
            <field>
              <name>BIDX</name>
              <bitOffset>0</bitOffset>
              <bitWidth>3</bitWidth>
            </field>
            <field>
              <name>MSI</name>
              <bitOffset>6</bitOffset>
              <bitWidth>2</bitWidth>
            </field>
            <field>
              <name>FIDX</name>
              <bitOffset>8</bitOffset>
              <bitWidth>5</bitWidth>
            </field>
            <field>
              <name>FLST</name>
              <bitOffset>15</bitOffset>
              <bitWidth>1</bitWidth>
            </field>
          </fields>
        </register>
        <register>
          <name>RXF0S</name>
          <addressOffset>0x90</addressOffset>
          <size>0x20</size>
          <fields>
            <field>
              <name>F0FL</name>
              <bitOffset>0</bitOffset>
              <bitWidth>4</bitWidth>
            </field>
            <field>
              <name>F0GI</name>
              <bitOffset>8</bitOffset>
              <bitWidth>2</bitWidth>
            </field>
            <field>
              <name>F0PI</name>
              <bitOffset>16</bitOffset>
              <bitWidth>2</bitWidth>
            </field>
            <field>
              <name>F0F</name>
              <bitOffset>24</bitOffset>
              <bitWidth>1</bitWidth>
            </field>
            <field>
              <name>RF0L</name>
              <bitOffset>25</bitOffset>
              <bitWidth>1</bitWidth>
            </field>
          </fields>
        </register>
        <register>
          <name>RXF0A</name>
          <addressOffset>0x94</addressOffset>
          <size>0x20</size>
          <fields>
            <field>
              <name>F0AI</name>
              <bitOffset>0</bitOffset>
              <bitWidth>3</bitWidth>
            </field>
          </fields>
        </register>
        <register>
          <name>RXF1S</name>
          <addressOffset>0x98</addressOffset>
          <size>0x20</size>
          <fields>
            <field>
              <name>F1FL</name>
              <bitOffset>0</bitOffset>
              <bitWidth>4</bitWidth>
            </field>
            <field>
              <name>F1GI</name>
              <bitOffset>8</bitOffset>
              <bitWidth>2</bitWidth>
            </field>
            <field>
              <name>F1PI</name>
              <bitOffset>16</bitOffset>
              <bitWidth>2</bitWidth>
            </field>
            <field>
              <name>F1F</name>
              <bitOffset>24</bitOffset>
              <bitWidth>1</bitWidth>
            </field>
            <field>
              <name>RF1L</name>
              <bitOffset>25</bitOffset>
              <bitWidth>1</bitWidth>
            </field>
          </fields>
        </register>
        <register>
          <name>RXF1A</name>
          <addressOffset>0x9c</addressOffset>
          <size>0x20</size>
          <fields>
            <field>
              <name>F1AI</name>
              <bitOffset>0</bitOffset>
              <bitWidth>3</bitWidth>
            </field>
          </fields>
        </register>
        <register>
          <name>TXBC</name>
          <addressOffset>0xc0</addressOffset>
          <size>0x20</size>
          <fields>
            <field>
              <name>TFQM</name>
              <bitOffset>24</bitOffset>
              <bitWidth>1</bitWidth>
            </field>
          </fields>
        </register>
        <register>
          <name>TXFQS</name>
          <addressOffset>0xc4</addressOffset>
          <size>0x20</size>
          <fields>
            <field>
              <name>TFFL</name>
              <bitOffset>0</bitOffset>
              <bitWidth>3</bitWidth>
            </field>
            <field>
              <name>TFGI</name>
              <bitOffset>8</bitOffset>
              <bitWidth>2</bitWidth>
            </field>
            <field>
              <name>TFQPI</name>
              <bitOffset>16</bitOffset>
              <bitWidth>2</bitWidth>
            </field>
            <field>
              <name>TFQF</name>
              <bitOffset>21</bitOffset>
              <bitWidth>1</bitWidth>
            </field>
          </fields>
        </register>
        <register>
          <name>TXBRP</name>
          <addressOffset>0xc8</addressOffset>
          <size>0x20</size>
          <fields>
            <field>
              <name>TRP</name>
              <bitOffset>0</bitOffset>
              <bitWidth>3</bitWidth>
            </field>
          </fields>
        </register>
        <register>
          <name>TXBAR</name>
          <addressOffset>0xcc</addressOffset>
          <size>0x20</size>
          <fields>
            <field>
              <name>AR</name>
              <bitOffset>0</bitOffset>
              <bitWidth>3</bitWidth>
            </field>
          </fields>
        </register>
        <register>
          <name>TXBCR</name>
          <addressOffset>0xd0</addressOffset>
          <size>0x20</size>
          <fields>
            <field>
              <name>CR</name>
              <bitOffset>0</bitOffset>
              <bitWidth>3</bitWidth>
            </field>
          </fields>
        </register>
        <register>
          <name>TXBTO</name>
          <addressOffset>0xd4</addressOffset>
          <size>0x20</size>
          <fields>
            <field>
              <name>TO</name>
              <bitOffset>0</bitOffset>
              <bitWidth>3</bitWidth>
            </field>
          </fields>
        </register>
        <register>
          <name>TXBCF</name>
          <addressOffset>0xd8</addressOffset>
          <size>0x20</size>
          <fields>
            <field>
              <name>CF</name>
              <bitOffset>0</bitOffset>
              <bitWidth>3</bitWidth>
            </field>
          </fields>
        </register>
        <register>
          <name>TXBTIE</name>
          <addressOffset>0xdc</addressOffset>
          <size>0x20</size>
          <fields>
            <field>
              <name>TIE</name>
              <bitOffset>0</bitOffset>
              <bitWidth>3</bitWidth>
            </field>
          </fields>
        </register>
        <register>
          <name>TXBCIE</name>
          <addressOffset>0xe0</addressOffset>
          <size>0x20</size>
          <fields>
            <field>
              <name>CFIE</name>
              <bitOffset>0</bitOffset>
              <bitWidth>3</bitWidth>
            </field>
          </fields>
        </register>
        <register>
          <name>TXEFS</name>
          <addressOffset>0xe4</addressOffset>
          <size>0x20</size>
          <fields>
            <field>
              <name>EFFL</name>
              <bitOffset>0</bitOffset>
              <bitWidth>3</bitWidth>
            </field>
            <field>
              <name>EFGI</name>
              <bitOffset>8</bitOffset>
              <bitWidth>2</bitWidth>
            </field>
            <field>
              <name>EFPI</name>
              <bitOffset>16</bitOffset>
              <bitWidth>2</bitWidth>
            </field>
            <field>
              <name>EFF</name>
              <bitOffset>24</bitOffset>
              <bitWidth>1</bitWidth>
            </field>
            <field>
              <name>TEFL</name>
              <bitOffset>25</bitOffset>
              <bitWidth>1</bitWidth>
            </field>
          </fields>
        </register>
        <register>
          <name>TXEFA</name>
          <addressOffset>0xe8</addressOffset>
          <size>0x20</size>
          <fields>
            <field>
              <name>EFAI</name>
              <bitOffset>0</bitOffset>
              <bitWidth>2</bitWidth>
            </field>
          </fields>
        </register>
      </registers>
    </peripheral>
    <peripheral>
      <name>PWR</name>
      <baseAddress>0x40007000</baseAddress>
      <registers>
        <register>
          <name>CR1</name>
          <addressOffset>0x0</addressOffset>
          <size>0x20</size>
          <fields>
            <field>
              <name>LPMS_STOP1</name>
              <bitOffset>0</bitOffset>
              <bitWidth>1</bitWidth>
            </field>
            <field>
              <name>LPMS_SHUTDOWN</name>
              <bitOffset>2</bitOffset>
              <bitWidth>1</bitWidth>
            </field>
            <field>
              <name>DBP</name>
              <bitOffset>8</bitOffset>
              <bitWidth>1</bitWidth>
            </field>
            <field>
              <name>VOS</name>
              <bitOffset>9</bitOffset>
              <bitWidth>2</bitWidth>
            </field>
            <field>
              <name>LPR</name>
              <bitOffset>14</bitOffset>
              <bitWidth>1</bitWidth>
            </field>
          </fields>
        </register>
        <register>
          <name>CR2</name>
          <addressOffset>0x4</addressOffset>
          <size>0x20</size>
          <fields>
            <field>
              <name>PVDE</name>
              <bitOffset>0</bitOffset>
              <bitWidth>1</bitWidth>
            </field>
            <field>
              <name>PLS_LEV7</name>
              <bitOffset>1</bitOffset>
              <bitWidth>3</bitWidth>
            </field>
            <field>
              <name>PLS_LEV6</name>
              <bitOffset>2</bitOffset>
              <bitWidth>2</bitWidth>
            </field>
            <field>
              <name>PLS_LEV4</name>
              <bitOffset>3</bitOffset>
              <bitWidth>1</bitWidth>
            </field>
            <field>
              <name>PVME1</name>
              <bitOffset>4</bitOffset>
              <bitWidth>1</bitWidth>
            </field>
            <field>
              <name>PVME2</name>
              <bitOffset>5</bitOffset>
              <bitWidth>1</bitWidth>
            </field>
            <field>
              <name>PVME3</name>
              <bitOffset>6</bitOffset>
              <bitWidth>1</bitWidth>
            </field>
            <field>
              <name>PVME4</name>
              <bitOffset>7</bitOffset>
              <bitWidth>1</bitWidth>
            </field>
          </fields>
        </register>
        <register>
          <name>CR3</name>
          <addressOffset>0x8</addressOffset>
          <size>0x20</size>
          <fields>
            <field>
              <name>EWUP1</name>
              <bitOffset>0</bitOffset>
              <bitWidth>1</bitWidth>
            </field>
            <field>
              <name>EWUP2</name>
              <bitOffset>1</bitOffset>
              <bitWidth>1</bitWidth>
            </field>
            <field>
              <name>EWUP3</name>
              <bitOffset>2</bitOffset>
              <bitWidth>1</bitWidth>
            </field>
            <field>
              <name>EWUP4</name>
              <bitOffset>3</bitOffset>
              <bitWidth>1</bitWidth>
            </field>
            <field>
              <name>EWUP5</name>
              <bitOffset>4</bitOffset>
              <bitWidth>1</bitWidth>
            </field>
            <field>
              <name>RRS</name>
              <bitOffset>8</bitOffset>
              <bitWidth>1</bitWidth>
            </field>
            <field>
              <name>APC</name>
              <bitOffset>10</bitOffset>
              <bitWidth>1</bitWidth>
            </field>
            <field>
              <name>UCPD_STDBY</name>
              <bitOffset>13</bitOffset>
              <bitWidth>1</bitWidth>
            </field>
            <field>
              <name>UCPD_DBDIS</name>
              <bitOffset>14</bitOffset>
              <bitWidth>1</bitWidth>
            </field>
            <field>
              <name>EIWF</name>
              <bitOffset>15</bitOffset>
              <bitWidth>1</bitWidth>
            </field>
          </fields>
        </register>
        <register>
          <name>CR4</name>
          <addressOffset>0xc</addressOffset>
          <size>0x20</size>
          <fields>
            <field>
              <name>WP1</name>
              <bitOffset>0</bitOffset>
              <bitWidth>1</bitWidth>
            </field>
            <field>
              <name>WP2</name>
              <bitOffset>1</bitOffset>
              <bitWidth>1</bitWidth>
            </field>
            <field>
              <name>WP3</name>
              <bitOffset>2</bitOffset>
              <bitWidth>1</bitWidth>
            </field>
            <field>
              <name>WP4</name>
              <bitOffset>3</bitOffset>
              <bitWidth>1</bitWidth>
            </field>
            <field>
              <name>WP5</name>
              <bitOffset>4</bitOffset>
              <bitWidth>1</bitWidth>
            </field>
            <field>
              <name>VBE</name>
              <bitOffset>8</bitOffset>
              <bitWidth>1</bitWidth>
            </field>
            <field>
              <name>VBRS</name>
              <bitOffset>9</bitOffset>
              <bitWidth>1</bitWidth>
            </field>
          </fields>
        </register>
        <register>
          <name>SR1</name>
          <addressOffset>0x10</addressOffset>
          <size>0x20</size>
          <fields>
            <field>
              <name>WUF1</name>
              <bitOffset>0</bitOffset>
              <bitWidth>1</bitWidth>
            </field>
            <field>
              <name>WUF2</name>
              <bitOffset>1</bitOffset>
              <bitWidth>1</bitWidth>
            </field>
            <field>
              <name>WUF3</name>
              <bitOffset>2</bitOffset>
              <bitWidth>1</bitWidth>
            </field>
            <field>
              <name>WUF4</name>
              <bitOffset>3</bitOffset>
              <bitWidth>1</bitWidth>
            </field>
            <field>
              <name>WUF5</name>
              <bitOffset>4</bitOffset>
              <bitWidth>1</bitWidth>
            </field>
            <field>
              <name>SBF</name>
              <bitOffset>8</bitOffset>
              <bitWidth>1</bitWidth>
            </field>
            <field>
              <name>WUFI</name>
              <bitOffset>15</bitOffset>
              <bitWidth>1</bitWidth>
            </field>
          </fields>
        </register>
        <register>
          <name>SR2</name>
          <addressOffset>0x14</addressOffset>
          <size>0x20</size>
          <fields>
            <field>
              <name>REGLPS</name>
              <bitOffset>8</bitOffset>
              <bitWidth>1</bitWidth>
            </field>
            <field>
              <name>REGLPF</name>
              <bitOffset>9</bitOffset>
              <bitWidth>1</bitWidth>
            </field>
            <field>
              <name>VOSF</name>
              <bitOffset>10</bitOffset>
              <bitWidth>1</bitWidth>
            </field>
            <field>
              <name>PVDO</name>
              <bitOffset>11</bitOffset>
              <bitWidth>1</bitWidth>
            </field>
            <field>
              <name>PVMO1</name>
              <bitOffset>12</bitOffset>
              <bitWidth>1</bitWidth>
            </field>
            <field>
              <name>PVMO2</name>
              <bitOffset>13</bitOffset>
              <bitWidth>1</bitWidth>
            </field>
            <field>
              <name>PVMO3</name>
              <bitOffset>14</bitOffset>
              <bitWidth>1</bitWidth>
            </field>
            <field>
              <name>PVMO4</name>
              <bitOffset>15</bitOffset>
              <bitWidth>1</bitWidth>
            </field>
          </fields>
        </register>
        <register>
          <name>SCR</name>
          <addressOffset>0x18</addressOffset>
          <size>0x20</size>
          <fields>
            <field>
              <name>CWUF1</name>
              <bitOffset>0</bitOffset>
              <bitWidth>1</bitWidth>
            </field>
            <field>
              <name>CWUF2</name>
              <bitOffset>1</bitOffset>
              <bitWidth>1</bitWidth>
            </field>
            <field>
              <name>CWUF3</name>
              <bitOffset>2</bitOffset>
              <bitWidth>1</bitWidth>
            </field>
            <field>
              <name>CWUF4</name>
              <bitOffset>3</bitOffset>
              <bitWidth>1</bitWidth>
            </field>
            <field>
              <name>CWUF5</name>
              <bitOffset>4</bitOffset>
              <bitWidth>1</bitWidth>
            </field>
            <field>
              <name>CSBF</name>
              <bitOffset>8</bitOffset>
              <bitWidth>1</bitWidth>
            </field>
          </fields>
        </register>
        <register>
          <name>PUCRA</name>
          <addressOffset>0x20</addressOffset>
          <size>0x20</size>
          <fields>
            <field>
              <name>PA0</name>
              <bitOffset>0</bitOffset>
              <bitWidth>1</bitWidth>
            </field>
            <field>
              <name>PA1</name>
              <bitOffset>1</bitOffset>
              <bitWidth>1</bitWidth>
            </field>
            <field>
              <name>PA2</name>
              <bitOffset>2</bitOffset>
              <bitWidth>1</bitWidth>
            </field>
            <field>
              <name>PA3</name>
              <bitOffset>3</bitOffset>
              <bitWidth>1</bitWidth>
            </field>
            <field>
              <name>PA4</name>
              <bitOffset>4</bitOffset>
              <bitWidth>1</bitWidth>
            </field>
            <field>
              <name>PA5</name>
              <bitOffset>5</bitOffset>
              <bitWidth>1</bitWidth>
            </field>
            <field>
              <name>PA6</name>
              <bitOffset>6</bitOffset>
              <bitWidth>1</bitWidth>
            </field>
            <field>
              <name>PA7</name>
              <bitOffset>7</bitOffset>
              <bitWidth>1</bitWidth>
            </field>
            <field>
              <name>PA8</name>
              <bitOffset>8</bitOffset>
              <bitWidth>1</bitWidth>
            </field>
            <field>
              <name>PA9</name>
              <bitOffset>9</bitOffset>
              <bitWidth>1</bitWidth>
            </field>
            <field>
              <name>PA10</name>
              <bitOffset>10</bitOffset>
              <bitWidth>1</bitWidth>
            </field>
            <field>
              <name>PA11</name>
              <bitOffset>11</bitOffset>
              <bitWidth>1</bitWidth>
            </field>
            <field>
              <name>PA12</name>
              <bitOffset>12</bitOffset>
              <bitWidth>1</bitWidth>
            </field>
            <field>
              <name>PA13</name>
              <bitOffset>13</bitOffset>
              <bitWidth>1</bitWidth>
            </field>
            <field>
              <name>PA15</name>
              <bitOffset>15</bitOffset>
              <bitWidth>1</bitWidth>
            </field>
          </fields>
        </register>
        <register>
          <name>PDCRA</name>
          <addressOffset>0x24</addressOffset>
          <size>0x20</size>
          <fields>
            <field>
              <name>PA0</name>
              <bitOffset>0</bitOffset>
              <bitWidth>1</bitWidth>
            </field>
            <field>
              <name>PA1</name>
              <bitOffset>1</bitOffset>
              <bitWidth>1</bitWidth>
            </field>
            <field>
              <name>PA2</name>
              <bitOffset>2</bitOffset>
              <bitWidth>1</bitWidth>
            </field>
            <field>
              <name>PA3</name>
              <bitOffset>3</bitOffset>
              <bitWidth>1</bitWidth>
            </field>
            <field>
              <name>PA4</name>
              <bitOffset>4</bitOffset>
              <bitWidth>1</bitWidth>
            </field>
            <field>
              <name>PA5</name>
              <bitOffset>5</bitOffset>
              <bitWidth>1</bitWidth>
            </field>
            <field>
              <name>PA6</name>
              <bitOffset>6</bitOffset>
              <bitWidth>1</bitWidth>
            </field>
            <field>
              <name>PA7</name>
              <bitOffset>7</bitOffset>
              <bitWidth>1</bitWidth>
            </field>
            <field>
              <name>PA8</name>
              <bitOffset>8</bitOffset>
              <bitWidth>1</bitWidth>
            </field>
            <field>
              <name>PA9</name>
              <bitOffset>9</bitOffset>
              <bitWidth>1</bitWidth>
            </field>
            <field>
              <name>PA10</name>
              <bitOffset>10</bitOffset>
              <bitWidth>1</bitWidth>
            </field>
            <field>
              <name>PA11</name>
              <bitOffset>11</bitOffset>
              <bitWidth>1</bitWidth>
            </field>
            <field>
              <name>PA12</name>
              <bitOffset>12</bitOffset>
              <bitWidth>1</bitWidth>
            </field>
            <field>
              <name>PA14</name>
              <bitOffset>14</bitOffset>
              <bitWidth>1</bitWidth>
            </field>
          </fields>
        </register>
        <register>
          <name>PUCRB</name>
          <addressOffset>0x28</addressOffset>
          <size>0x20</size>
          <fields>
            <field>
              <name>PB0</name>
              <bitOffset>0</bitOffset>
              <bitWidth>1</bitWidth>
            </field>
            <field>
              <name>PB1</name>
              <bitOffset>1</bitOffset>
              <bitWidth>1</bitWidth>
            </field>
            <field>
              <name>PB2</name>
              <bitOffset>2</bitOffset>
              <bitWidth>1</bitWidth>
            </field>
            <field>
              <name>PB3</name>
              <bitOffset>3</bitOffset>
              <bitWidth>1</bitWidth>
            </field>
            <field>
              <name>PB4</name>
              <bitOffset>4</bitOffset>
              <bitWidth>1</bitWidth>
            </field>
            <field>
              <name>PB5</name>
              <bitOffset>5</bitOffset>
              <bitWidth>1</bitWidth>
            </field>
            <field>
              <name>PB6</name>
              <bitOffset>6</bitOffset>
              <bitWidth>1</bitWidth>
            </field>
            <field>
              <name>PB7</name>
              <bitOffset>7</bitOffset>
              <bitWidth>1</bitWidth>
            </field>
            <field>
              <name>PB8</name>
              <bitOffset>8</bitOffset>
              <bitWidth>1</bitWidth>
            </field>
            <field>
              <name>PB9</name>
              <bitOffset>9</bitOffset>
              <bitWidth>1</bitWidth>
            </field>
            <field>
              <name>PB10</name>
              <bitOffset>10</bitOffset>
              <bitWidth>1</bitWidth>
            </field>
            <field>
              <name>PB11</name>
              <bitOffset>11</bitOffset>
              <bitWidth>1</bitWidth>
            </field>
            <field>
              <name>PB12</name>
              <bitOffset>12</bitOffset>
              <bitWidth>1</bitWidth>
            </field>
            <field>
              <name>PB13</name>
              <bitOffset>13</bitOffset>
              <bitWidth>1</bitWidth>
            </field>
            <field>
              <name>PB14</name>
              <bitOffset>14</bitOffset>
              <bitWidth>1</bitWidth>
            </field>
            <field>
              <name>PB15</name>
              <bitOffset>15</bitOffset>
              <bitWidth>1</bitWidth>
            </field>
          </fields>
        </register>
        <register>
          <name>PDCRB</name>
          <addressOffset>0x2c</addressOffset>
          <size>0x20</size>
          <fields>
            <field>
              <name>PB0</name>
              <bitOffset>0</bitOffset>
              <bitWidth>1</bitWidth>
            </field>
            <field>
              <name>PB1</name>
              <bitOffset>1</bitOffset>
              <bitWidth>1</bitWidth>
            </field>
            <field>
              <name>PB2</name>
              <bitOffset>2</bitOffset>
              <bitWidth>1</bitWidth>
            </field>
            <field>
              <name>PB3</name>
              <bitOffset>3</bitOffset>
              <bitWidth>1</bitWidth>
            </field>
            <field>
              <name>PB5</name>
              <bitOffset>5</bitOffset>
              <bitWidth>1</bitWidth>
            </field>
            <field>
              <name>PB6</name>
              <bitOffset>6</bitOffset>
              <bitWidth>1</bitWidth>
            </field>
            <field>
              <name>PB7</name>
              <bitOffset>7</bitOffset>
              <bitWidth>1</bitWidth>
            </field>
            <field>
              <name>PB8</name>
              <bitOffset>8</bitOffset>
              <bitWidth>1</bitWidth>
            </field>
            <field>
              <name>PB9</name>
              <bitOffset>9</bitOffset>
              <bitWidth>1</bitWidth>
            </field>
            <field>
              <name>PB10</name>
              <bitOffset>10</bitOffset>
              <bitWidth>1</bitWidth>
            </field>
            <field>
              <name>PB11</name>
              <bitOffset>11</bitOffset>
              <bitWidth>1</bitWidth>
            </field>
            <field>
              <name>PB12</name>
              <bitOffset>12</bitOffset>
              <bitWidth>1</bitWidth>
            </field>
            <field>
              <name>PB13</name>
              <bitOffset>13</bitOffset>
              <bitWidth>1</bitWidth>
            </field>
            <field>
              <name>PB14</name>
              <bitOffset>14</bitOffset>
              <bitWidth>1</bitWidth>
            </field>
            <field>
              <name>PB15</name>
              <bitOffset>15</bitOffset>
              <bitWidth>1</bitWidth>
            </field>
          </fields>
        </register>
        <register>
          <name>PUCRC</name>
          <addressOffset>0x30</addressOffset>
          <size>0x20</size>
          <fields>
            <field>
              <name>PC0</name>
              <bitOffset>0</bitOffset>
              <bitWidth>1</bitWidth>
            </field>
            <field>
              <name>PC1</name>
              <bitOffset>1</bitOffset>
              <bitWidth>1</bitWidth>
            </field>
            <field>
              <name>PC2</name>
              <bitOffset>2</bitOffset>
              <bitWidth>1</bitWidth>
            </field>
            <field>
              <name>PC3</name>
              <bitOffset>3</bitOffset>
              <bitWidth>1</bitWidth>
            </field>
            <field>
              <name>PC4</name>
              <bitOffset>4</bitOffset>
              <bitWidth>1</bitWidth>
            </field>
            <field>
              <name>PC5</name>
              <bitOffset>5</bitOffset>
              <bitWidth>1</bitWidth>
            </field>
            <field>
              <name>PC6</name>
              <bitOffset>6</bitOffset>
              <bitWidth>1</bitWidth>
            </field>
            <field>
              <name>PC7</name>
              <bitOffset>7</bitOffset>
              <bitWidth>1</bitWidth>
            </field>
            <field>
              <name>PC8</name>
              <bitOffset>8</bitOffset>
              <bitWidth>1</bitWidth>
            </field>
            <field>
              <name>PC9</name>
              <bitOffset>9</bitOffset>
              <bitWidth>1</bitWidth>
            </field>
            <field>
              <name>PC10</name>
              <bitOffset>10</bitOffset>
              <bitWidth>1</bitWidth>
            </field>
            <field>
              <name>PC11</name>
              <bitOffset>11</bitOffset>
              <bitWidth>1</bitWidth>
            </field>
            <field>
              <name>PC12</name>
              <bitOffset>12</bitOffset>
              <bitWidth>1</bitWidth>
            </field>
            <field>
              <name>PC13</name>
              <bitOffset>13</bitOffset>
              <bitWidth>1</bitWidth>
            </field>
            <field>
              <name>PC14</name>
              <bitOffset>14</bitOffset>
              <bitWidth>1</bitWidth>
            </field>
            <field>
              <name>PC15</name>
              <bitOffset>15</bitOffset>
              <bitWidth>1</bitWidth>
            </field>
          </fields>
        </register>
        <register>
          <name>PDCRC</name>
          <addressOffset>0x34</addressOffset>
          <size>0x20</size>
          <fields>
            <field>
              <name>PC0</name>
              <bitOffset>0</bitOffset>
              <bitWidth>1</bitWidth>
            </field>
            <field>
              <name>PC1</name>
              <bitOffset>1</bitOffset>
              <bitWidth>1</bitWidth>
            </field>
            <field>
              <name>PC2</name>
              <bitOffset>2</bitOffset>
              <bitWidth>1</bitWidth>
            </field>
            <field>
              <name>PC3</name>
              <bitOffset>3</bitOffset>
              <bitWidth>1</bitWidth>
            </field>
            <field>
              <name>PC4</name>
              <bitOffset>4</bitOffset>
              <bitWidth>1</bitWidth>
            </field>
            <field>
              <name>PC5</name>
              <bitOffset>5</bitOffset>
              <bitWidth>1</bitWidth>
            </field>
            <field>
              <name>PC6</name>
              <bitOffset>6</bitOffset>
              <bitWidth>1</bitWidth>
            </field>
            <field>
              <name>PC7</name>
              <bitOffset>7</bitOffset>
              <bitWidth>1</bitWidth>
            </field>
            <field>
              <name>PC8</name>
              <bitOffset>8</bitOffset>
              <bitWidth>1</bitWidth>
            </field>
            <field>
              <name>PC9</name>
              <bitOffset>9</bitOffset>
              <bitWidth>1</bitWidth>
            </field>
            <field>
              <name>PC10</name>
              <bitOffset>10</bitOffset>
              <bitWidth>1</bitWidth>
            </field>
            <field>
              <name>PC11</name>
              <bitOffset>11</bitOffset>
              <bitWidth>1</bitWidth>
            </field>
            <field>
              <name>PC12</name>
              <bitOffset>12</bitOffset>
              <bitWidth>1</bitWidth>
            </field>
            <field>
              <name>PC13</name>
              <bitOffset>13</bitOffset>
              <bitWidth>1</bitWidth>
            </field>
            <field>
              <name>PC14</name>
              <bitOffset>14</bitOffset>
              <bitWidth>1</bitWidth>
            </field>
            <field>
              <name>PC15</name>
              <bitOffset>15</bitOffset>
              <bitWidth>1</bitWidth>
            </field>
          </fields>
        </register>
        <register>
          <name>PUCRD</name>
          <addressOffset>0x38</addressOffset>
          <size>0x20</size>
          <fields>
            <field>
              <name>PD0</name>
              <bitOffset>0</bitOffset>
              <bitWidth>1</bitWidth>
            </field>
            <field>
              <name>PD1</name>
              <bitOffset>1</bitOffset>
              <bitWidth>1</bitWidth>
            </field>
            <field>
              <name>PD2</name>
              <bitOffset>2</bitOffset>
              <bitWidth>1</bitWidth>
            </field>
            <field>
              <name>PD3</name>
              <bitOffset>3</bitOffset>
              <bitWidth>1</bitWidth>
            </field>
            <field>
              <name>PD4</name>
              <bitOffset>4</bitOffset>
              <bitWidth>1</bitWidth>
            </field>
            <field>
              <name>PD5</name>
              <bitOffset>5</bitOffset>
              <bitWidth>1</bitWidth>
            </field>
            <field>
              <name>PD6</name>
              <bitOffset>6</bitOffset>
              <bitWidth>1</bitWidth>
            </field>
            <field>
              <name>PD7</name>
              <bitOffset>7</bitOffset>
              <bitWidth>1</bitWidth>
            </field>
            <field>
              <name>PD8</name>
              <bitOffset>8</bitOffset>
              <bitWidth>1</bitWidth>
            </field>
            <field>
              <name>PD9</name>
              <bitOffset>9</bitOffset>
              <bitWidth>1</bitWidth>
            </field>
            <field>
              <name>PD10</name>
              <bitOffset>10</bitOffset>
              <bitWidth>1</bitWidth>
            </field>
            <field>
              <name>PD11</name>
              <bitOffset>11</bitOffset>
              <bitWidth>1</bitWidth>
            </field>
            <field>
              <name>PD12</name>
              <bitOffset>12</bitOffset>
              <bitWidth>1</bitWidth>
            </field>
            <field>
              <name>PD13</name>
              <bitOffset>13</bitOffset>
              <bitWidth>1</bitWidth>
            </field>
            <field>
              <name>PD14</name>
              <bitOffset>14</bitOffset>
              <bitWidth>1</bitWidth>
            </field>
            <field>
              <name>PD15</name>
              <bitOffset>15</bitOffset>
              <bitWidth>1</bitWidth>
            </field>
          </fields>
        </register>
        <register>
          <name>PDCRD</name>
          <addressOffset>0x3c</addressOffset>
          <size>0x20</size>
          <fields>
            <field>
              <name>PD0</name>
              <bitOffset>0</bitOffset>
              <bitWidth>1</bitWidth>
            </field>
            <field>
              <name>PD1</name>
              <bitOffset>1</bitOffset>
              <bitWidth>1</bitWidth>
            </field>
            <field>
              <name>PD2</name>
              <bitOffset>2</bitOffset>
              <bitWidth>1</bitWidth>
            </field>
            <field>
              <name>PD3</name>
              <bitOffset>3</bitOffset>
              <bitWidth>1</bitWidth>
            </field>
            <field>
              <name>PD4</name>
              <bitOffset>4</bitOffset>
              <bitWidth>1</bitWidth>
            </field>
            <field>
              <name>PD5</name>
              <bitOffset>5</bitOffset>
              <bitWidth>1</bitWidth>
            </field>
            <field>
              <name>PD6</name>
              <bitOffset>6</bitOffset>
              <bitWidth>1</bitWidth>
            </field>
            <field>
              <name>PD7</name>
              <bitOffset>7</bitOffset>
              <bitWidth>1</bitWidth>
            </field>
            <field>
              <name>PD8</name>
              <bitOffset>8</bitOffset>
              <bitWidth>1</bitWidth>
            </field>
            <field>
              <name>PD9</name>
              <bitOffset>9</bitOffset>
              <bitWidth>1</bitWidth>
            </field>
            <field>
              <name>PD10</name>
              <bitOffset>10</bitOffset>
              <bitWidth>1</bitWidth>
            </field>
            <field>
              <name>PD11</name>
              <bitOffset>11</bitOffset>
              <bitWidth>1</bitWidth>
            </field>
            <field>
              <name>PD12</name>
              <bitOffset>12</bitOffset>
              <bitWidth>1</bitWidth>
            </field>
            <field>
              <name>PD13</name>
              <bitOffset>13</bitOffset>
              <bitWidth>1</bitWidth>
            </field>
            <field>
              <name>PD14</name>
              <bitOffset>14</bitOffset>
              <bitWidth>1</bitWidth>
            </field>
            <field>
              <name>PD15</name>
              <bitOffset>15</bitOffset>
              <bitWidth>1</bitWidth>
            </field>
          </fields>
        </register>
        <register>
          <name>PUCRE</name>
          <addressOffset>0x40</addressOffset>
          <size>0x20</size>
          <fields>
            <field>
              <name>PE0</name>
              <bitOffset>0</bitOffset>
              <bitWidth>1</bitWidth>
            </field>
            <field>
              <name>PE1</name>
              <bitOffset>1</bitOffset>
              <bitWidth>1</bitWidth>
            </field>
            <field>
              <name>PE2</name>
              <bitOffset>2</bitOffset>
              <bitWidth>1</bitWidth>
            </field>
            <field>
              <name>PE3</name>
              <bitOffset>3</bitOffset>
              <bitWidth>1</bitWidth>
            </field>
            <field>
              <name>PE4</name>
              <bitOffset>4</bitOffset>
              <bitWidth>1</bitWidth>
            </field>
            <field>
              <name>PE5</name>
              <bitOffset>5</bitOffset>
              <bitWidth>1</bitWidth>
            </field>
            <field>
              <name>PE6</name>
              <bitOffset>6</bitOffset>
              <bitWidth>1</bitWidth>
            </field>
            <field>
              <name>PE7</name>
              <bitOffset>7</bitOffset>
              <bitWidth>1</bitWidth>
            </field>
            <field>
              <name>PE8</name>
              <bitOffset>8</bitOffset>
              <bitWidth>1</bitWidth>
            </field>
            <field>
              <name>PE9</name>
              <bitOffset>9</bitOffset>
              <bitWidth>1</bitWidth>
            </field>
            <field>
              <name>PE10</name>
              <bitOffset>10</bitOffset>
              <bitWidth>1</bitWidth>
            </field>
            <field>
              <name>PE11</name>
              <bitOffset>11</bitOffset>
              <bitWidth>1</bitWidth>
            </field>
            <field>
              <name>PE12</name>
              <bitOffset>12</bitOffset>
              <bitWidth>1</bitWidth>
            </field>
            <field>
              <name>PE13</name>
              <bitOffset>13</bitOffset>
              <bitWidth>1</bitWidth>
            </field>
            <field>
              <name>PE14</name>
              <bitOffset>14</bitOffset>
              <bitWidth>1</bitWidth>
            </field>
            <field>
              <name>PE15</name>
              <bitOffset>15</bitOffset>
              <bitWidth>1</bitWidth>
            </field>
          </fields>
        </register>
        <register>
          <name>PDCRE</name>
          <addressOffset>0x44</addressOffset>
          <size>0x20</size>
          <fields>
            <field>
              <name>PE0</name>
              <bitOffset>0</bitOffset>
              <bitWidth>1</bitWidth>
            </field>
            <field>
              <name>PE1</name>
              <bitOffset>1</bitOffset>
              <bitWidth>1</bitWidth>
            </field>
            <field>
              <name>PE2</name>
              <bitOffset>2</bitOffset>
              <bitWidth>1</bitWidth>
            </field>
            <field>
              <name>PE3</name>
              <bitOffset>3</bitOffset>
              <bitWidth>1</bitWidth>
            </field>
            <field>
              <name>PE4</name>
              <bitOffset>4</bitOffset>
              <bitWidth>1</bitWidth>
            </field>
            <field>
              <name>PE5</name>
              <bitOffset>5</bitOffset>
              <bitWidth>1</bitWidth>
            </field>
            <field>
              <name>PE6</name>
              <bitOffset>6</bitOffset>
              <bitWidth>1</bitWidth>
            </field>
            <field>
              <name>PE7</name>
              <bitOffset>7</bitOffset>
              <bitWidth>1</bitWidth>
            </field>
            <field>
              <name>PE8</name>
              <bitOffset>8</bitOffset>
              <bitWidth>1</bitWidth>
            </field>
            <field>
              <name>PE9</name>
              <bitOffset>9</bitOffset>
              <bitWidth>1</bitWidth>
            </field>
            <field>
              <name>PE10</name>
              <bitOffset>10</bitOffset>
              <bitWidth>1</bitWidth>
            </field>
            <field>
              <name>PE11</name>
              <bitOffset>11</bitOffset>
              <bitWidth>1</bitWidth>
            </field>
            <field>
              <name>PE12</name>
              <bitOffset>12</bitOffset>
              <bitWidth>1</bitWidth>
            </field>
            <field>
              <name>PE13</name>
              <bitOffset>13</bitOffset>
              <bitWidth>1</bitWidth>
            </field>
            <field>
              <name>PE14</name>
              <bitOffset>14</bitOffset>
              <bitWidth>1</bitWidth>
            </field>
            <field>
              <name>PE15</name>
              <bitOffset>15</bitOffset>
              <bitWidth>1</bitWidth>
            </field>
          </fields>
        </register>
        <register>
          <name>PUCRF</name>
          <addressOffset>0x48</addressOffset>
          <size>0x20</size>
          <fields>
            <field>
              <name>PF0</name>
              <bitOffset>0</bitOffset>
              <bitWidth>1</bitWidth>
            </field>
            <field>
              <name>PF1</name>
              <bitOffset>1</bitOffset>
              <bitWidth>1</bitWidth>
            </field>
            <field>
              <name>PF2</name>
              <bitOffset>2</bitOffset>
              <bitWidth>1</bitWidth>
            </field>
            <field>
              <name>PF3</name>
              <bitOffset>3</bitOffset>
              <bitWidth>1</bitWidth>
            </field>
            <field>
              <name>PF4</name>
              <bitOffset>4</bitOffset>
              <bitWidth>1</bitWidth>
            </field>
            <field>
              <name>PF5</name>
              <bitOffset>5</bitOffset>
              <bitWidth>1</bitWidth>
            </field>
            <field>
              <name>PF6</name>
              <bitOffset>6</bitOffset>
              <bitWidth>1</bitWidth>
            </field>
            <field>
              <name>PF7</name>
              <bitOffset>7</bitOffset>
              <bitWidth>1</bitWidth>
            </field>
            <field>
              <name>PF8</name>
              <bitOffset>8</bitOffset>
              <bitWidth>1</bitWidth>
            </field>
            <field>
              <name>PF9</name>
              <bitOffset>9</bitOffset>
              <bitWidth>1</bitWidth>
            </field>
            <field>
              <name>PF10</name>
              <bitOffset>10</bitOffset>
              <bitWidth>1</bitWidth>
            </field>
            <field>
              <name>PF11</name>
              <bitOffset>11</bitOffset>
              <bitWidth>1</bitWidth>
            </field>
            <field>
              <name>PF12</name>
              <bitOffset>12</bitOffset>
              <bitWidth>1</bitWidth>
            </field>
            <field>
              <name>PF13</name>
              <bitOffset>13</bitOffset>
              <bitWidth>1</bitWidth>
            </field>
            <field>
              <name>PF14</name>
              <bitOffset>14</bitOffset>
              <bitWidth>1</bitWidth>
            </field>
            <field>
              <name>PF15</name>
              <bitOffset>15</bitOffset>
              <bitWidth>1</bitWidth>
            </field>
          </fields>
        </register>
        <register>
          <name>PDCRF</name>
          <addressOffset>0x4c</addressOffset>
          <size>0x20</size>
          <fields>
            <field>
              <name>PF0</name>
              <bitOffset>0</bitOffset>
              <bitWidth>1</bitWidth>
            </field>
            <field>
              <name>PF1</name>
              <bitOffset>1</bitOffset>
              <bitWidth>1</bitWidth>
            </field>
            <field>
              <name>PF2</name>
              <bitOffset>2</bitOffset>
              <bitWidth>1</bitWidth>
            </field>
            <field>
              <name>PF3</name>
              <bitOffset>3</bitOffset>
              <bitWidth>1</bitWidth>
            </field>
            <field>
              <name>PF4</name>
              <bitOffset>4</bitOffset>
              <bitWidth>1</bitWidth>
            </field>
            <field>
              <name>PF5</name>
              <bitOffset>5</bitOffset>
              <bitWidth>1</bitWidth>
            </field>
            <field>
              <name>PF6</name>
              <bitOffset>6</bitOffset>
              <bitWidth>1</bitWidth>
            </field>
            <field>
              <name>PF7</name>
              <bitOffset>7</bitOffset>
              <bitWidth>1</bitWidth>
            </field>
            <field>
              <name>PF8</name>
              <bitOffset>8</bitOffset>
              <bitWidth>1</bitWidth>
            </field>
            <field>
              <name>PF9</name>
              <bitOffset>9</bitOffset>
              <bitWidth>1</bitWidth>
            </field>
            <field>
              <name>PF10</name>
              <bitOffset>10</bitOffset>
              <bitWidth>1</bitWidth>
            </field>
            <field>
              <name>PF11</name>
              <bitOffset>11</bitOffset>
              <bitWidth>1</bitWidth>
            </field>
            <field>
              <name>PF12</name>
              <bitOffset>12</bitOffset>
              <bitWidth>1</bitWidth>
            </field>
            <field>
              <name>PF13</name>
              <bitOffset>13</bitOffset>
              <bitWidth>1</bitWidth>
            </field>
            <field>
              <name>PF14</name>
              <bitOffset>14</bitOffset>
              <bitWidth>1</bitWidth>
            </field>
            <field>
              <name>PF15</name>
              <bitOffset>15</bitOffset>
              <bitWidth>1</bitWidth>
            </field>
          </fields>
        </register>
        <register>
          <name>PUCRG</name>
          <addressOffset>0x50</addressOffset>
          <size>0x20</size>
          <fields>
            <field>
              <name>PG0</name>
              <bitOffset>0</bitOffset>
              <bitWidth>1</bitWidth>
            </field>
            <field>
              <name>PG1</name>
              <bitOffset>1</bitOffset>
              <bitWidth>1</bitWidth>
            </field>
            <field>
              <name>PG2</name>
              <bitOffset>2</bitOffset>
              <bitWidth>1</bitWidth>
            </field>
            <field>
              <name>PG3</name>
              <bitOffset>3</bitOffset>
              <bitWidth>1</bitWidth>
            </field>
            <field>
              <name>PG4</name>
              <bitOffset>4</bitOffset>
              <bitWidth>1</bitWidth>
            </field>
            <field>
              <name>PG5</name>
              <bitOffset>5</bitOffset>
              <bitWidth>1</bitWidth>
            </field>
            <field>
              <name>PG6</name>
              <bitOffset>6</bitOffset>
              <bitWidth>1</bitWidth>
            </field>
            <field>
              <name>PG7</name>
              <bitOffset>7</bitOffset>
              <bitWidth>1</bitWidth>
            </field>
            <field>
              <name>PG8</name>
              <bitOffset>8</bitOffset>
              <bitWidth>1</bitWidth>
            </field>
            <field>
              <name>PG9</name>
              <bitOffset>9</bitOffset>
              <bitWidth>1</bitWidth>
            </field>
            <field>
              <name>PG10</name>
              <bitOffset>10</bitOffset>
              <bitWidth>1</bitWidth>
            </field>
            <field>
              <name>PG11</name>
              <bitOffset>11</bitOffset>
              <bitWidth>1</bitWidth>
            </field>
            <field>
              <name>PG12</name>
              <bitOffset>12</bitOffset>
              <bitWidth>1</bitWidth>
            </field>
            <field>
              <name>PG13</name>
              <bitOffset>13</bitOffset>
              <bitWidth>1</bitWidth>
            </field>
            <field>
              <name>PG14</name>
              <bitOffset>14</bitOffset>
              <bitWidth>1</bitWidth>
            </field>
            <field>
              <name>PG15</name>
              <bitOffset>15</bitOffset>
              <bitWidth>1</bitWidth>
            </field>
          </fields>
        </register>
        <register>
          <name>PDCRG</name>
          <addressOffset>0x54</addressOffset>
          <size>0x20</size>
          <fields>
            <field>
              <name>PG0</name>
              <bitOffset>0</bitOffset>
              <bitWidth>1</bitWidth>
            </field>
            <field>
              <name>PG1</name>
              <bitOffset>1</bitOffset>
              <bitWidth>1</bitWidth>
            </field>
            <field>
              <name>PG2</name>
              <bitOffset>2</bitOffset>
              <bitWidth>1</bitWidth>
            </field>
            <field>
              <name>PG3</name>
              <bitOffset>3</bitOffset>
              <bitWidth>1</bitWidth>
            </field>
            <field>
              <name>PG4</name>
              <bitOffset>4</bitOffset>
              <bitWidth>1</bitWidth>
            </field>
            <field>
              <name>PG5</name>
              <bitOffset>5</bitOffset>
              <bitWidth>1</bitWidth>
            </field>
            <field>
              <name>PG6</name>
              <bitOffset>6</bitOffset>
              <bitWidth>1</bitWidth>
            </field>
            <field>
              <name>PG7</name>
              <bitOffset>7</bitOffset>
              <bitWidth>1</bitWidth>
            </field>
            <field>
              <name>PG8</name>
              <bitOffset>8</bitOffset>
              <bitWidth>1</bitWidth>
            </field>
            <field>
              <name>PG9</name>
              <bitOffset>9</bitOffset>
              <bitWidth>1</bitWidth>
            </field>
            <field>
              <name>PG10</name>
              <bitOffset>10</bitOffset>
              <bitWidth>1</bitWidth>
            </field>
          </fields>
        </register>
        <register>
          <name>CR5</name>
          <addressOffset>0x80</addressOffset>
          <size>0x20</size>
          <fields>
            <field>
              <name>R1MODE</name>
              <bitOffset>8</bitOffset>
              <bitWidth>1</bitWidth>
            </field>
          </fields>
        </register>
      </registers>
    </peripheral>
    <peripheral>
      <name>I2C3</name>
      <baseAddress>0x40007800</baseAddress>
      <registers>
        <register>
          <name>CR1</name>
          <addressOffset>0x0</addressOffset>
          <size>0x20</size>
          <fields>
            <field>
              <name>PE</name>
              <bitOffset>0</bitOffset>
              <bitWidth>1</bitWidth>
            </field>
            <field>
              <name>TXIE</name>
              <bitOffset>1</bitOffset>
              <bitWidth>1</bitWidth>
            </field>
            <field>
              <name>RXIE</name>
              <bitOffset>2</bitOffset>
              <bitWidth>1</bitWidth>
            </field>
            <field>
              <name>ADDRIE</name>
              <bitOffset>3</bitOffset>
              <bitWidth>1</bitWidth>
            </field>
            <field>
              <name>NACKIE</name>
              <bitOffset>4</bitOffset>
              <bitWidth>1</bitWidth>
            </field>
            <field>
              <name>STOPIE</name>
              <bitOffset>5</bitOffset>
              <bitWidth>1</bitWidth>
            </field>
            <field>
              <name>TCIE</name>
              <bitOffset>6</bitOffset>
              <bitWidth>1</bitWidth>
            </field>
            <field>
              <name>ERRIE</name>
              <bitOffset>7</bitOffset>
              <bitWidth>1</bitWidth>
            </field>
            <field>
              <name>DNF</name>
              <bitOffset>8</bitOffset>
              <bitWidth>4</bitWidth>
            </field>
            <field>
              <name>ANFOFF</name>
              <bitOffset>12</bitOffset>
              <bitWidth>1</bitWidth>
            </field>
            <field>
              <name>SWRST</name>
              <bitOffset>13</bitOffset>
              <bitWidth>1</bitWidth>
            </field>
            <field>
              <name>TXDMAEN</name>
              <bitOffset>14</bitOffset>
              <bitWidth>1</bitWidth>
            </field>
            <field>
              <name>RXDMAEN</name>
              <bitOffset>15</bitOffset>
              <bitWidth>1</bitWidth>
            </field>
            <field>
              <name>SBC</name>
              <bitOffset>16</bitOffset>
              <bitWidth>1</bitWidth>
            </field>
            <field>
              <name>NOSTRETCH</name>
              <bitOffset>17</bitOffset>
              <bitWidth>1</bitWidth>
            </field>
            <field>
              <name>WUPEN</name>
              <bitOffset>18</bitOffset>
              <bitWidth>1</bitWidth>
            </field>
            <field>
              <name>GCEN</name>
              <bitOffset>19</bitOffset>
              <bitWidth>1</bitWidth>
            </field>
            <field>
              <name>SMBHEN</name>
              <bitOffset>20</bitOffset>
              <bitWidth>1</bitWidth>
            </field>
            <field>
              <name>SMBDEN</name>
              <bitOffset>21</bitOffset>
              <bitWidth>1</bitWidth>
            </field>
            <field>
              <name>ALERTEN</name>
              <bitOffset>22</bitOffset>
              <bitWidth>1</bitWidth>
            </field>
            <field>
              <name>PECEN</name>
              <bitOffset>23</bitOffset>
              <bitWidth>1</bitWidth>
            </field>
          </fields>
        </register>
        <register>
          <name>CR2</name>
          <addressOffset>0x4</addressOffset>
          <size>0x20</size>
          <fields>
            <field>
              <name>SADD</name>
              <bitOffset>0</bitOffset>
              <bitWidth>10</bitWidth>
            </field>
            <field>
              <name>RD_WRN</name>
              <bitOffset>10</bitOffset>
              <bitWidth>1</bitWidth>
            </field>
            <field>
              <name>ADD10</name>
              <bitOffset>11</bitOffset>
              <bitWidth>1</bitWidth>
            </field>
            <field>
              <name>HEAD10R</name>
              <bitOffset>12</bitOffset>
              <bitWidth>1</bitWidth>
            </field>
            <field>
              <name>START</name>
              <bitOffset>13</bitOffset>
              <bitWidth>1</bitWidth>
            </field>
            <field>
              <name>STOP</name>
              <bitOffset>14</bitOffset>
              <bitWidth>1</bitWidth>
            </field>
            <field>
              <name>NACK</name>
              <bitOffset>15</bitOffset>
              <bitWidth>1</bitWidth>
            </field>
            <field>
              <name>NBYTES</name>
              <bitOffset>16</bitOffset>
              <bitWidth>8</bitWidth>
            </field>
            <field>
              <name>RELOAD</name>
              <bitOffset>24</bitOffset>
              <bitWidth>1</bitWidth>
            </field>
            <field>
              <name>AUTOEND</name>
              <bitOffset>25</bitOffset>
              <bitWidth>1</bitWidth>
            </field>
            <field>
              <name>PECBYTE</name>
              <bitOffset>26</bitOffset>
              <bitWidth>1</bitWidth>
            </field>
          </fields>
        </register>
        <register>
          <name>OAR1</name>
          <addressOffset>0x8</addressOffset>
          <size>0x20</size>
          <fields>
            <field>
              <name>OA1</name>
              <bitOffset>0</bitOffset>
              <bitWidth>10</bitWidth>
            </field>
            <field>
              <name>OA1MODE</name>
              <bitOffset>10</bitOffset>
              <bitWidth>1</bitWidth>
            </field>
            <field>
              <name>OA1EN</name>
              <bitOffset>15</bitOffset>
              <bitWidth>1</bitWidth>
            </field>
          </fields>
        </register>
        <register>
          <name>OAR2</name>
          <addressOffset>0xc</addressOffset>
          <size>0x20</size>
          <fields>
            <field>
              <name>OA2</name>
              <bitOffset>1</bitOffset>
              <bitWidth>7</bitWidth>
            </field>
            <field>
              <name>OA2MSK</name>
              <bitOffset>8</bitOffset>
              <bitWidth>3</bitWidth>
            </field>
            <field>
              <name>OA2MASK06</name>
              <bitOffset>9</bitOffset>
              <bitWidth>2</bitWidth>
            </field>
            <field>
              <name>OA2MASK04</name>
              <bitOffset>10</bitOffset>
              <bitWidth>1</bitWidth>
            </field>
            <field>
              <name>OA2EN</name>
              <bitOffset>15</bitOffset>
              <bitWidth>1</bitWidth>
            </field>
          </fields>
        </register>
        <register>
          <name>TIMINGR</name>
          <addressOffset>0x10</addressOffset>
          <size>0x20</size>
          <fields>
            <field>
              <name>SCLL</name>
              <bitOffset>0</bitOffset>
              <bitWidth>8</bitWidth>
            </field>
            <field>
              <name>SCLH</name>
              <bitOffset>8</bitOffset>
              <bitWidth>8</bitWidth>
            </field>
            <field>
              <name>SDADEL</name>
              <bitOffset>16</bitOffset>
              <bitWidth>4</bitWidth>
            </field>
            <field>
              <name>SCLDEL</name>
              <bitOffset>20</bitOffset>
              <bitWidth>4</bitWidth>
            </field>
            <field>
              <name>PRESC</name>
              <bitOffset>28</bitOffset>
              <bitWidth>4</bitWidth>
            </field>
          </fields>
        </register>
        <register>
          <name>TIMEOUTR</name>
          <addressOffset>0x14</addressOffset>
          <size>0x20</size>
          <fields>
            <field>
              <name>TIMEOUTA</name>
              <bitOffset>0</bitOffset>
              <bitWidth>12</bitWidth>
            </field>
            <field>
              <name>TIDLE</name>
              <bitOffset>12</bitOffset>
              <bitWidth>1</bitWidth>
            </field>
            <field>
              <name>TIMOUTEN</name>
              <bitOffset>15</bitOffset>
              <bitWidth>1</bitWidth>
            </field>
            <field>
              <name>TIMEOUTB</name>
              <bitOffset>16</bitOffset>
              <bitWidth>12</bitWidth>
            </field>
            <field>
              <name>TEXTEN</name>
              <bitOffset>31</bitOffset>
              <bitWidth>1</bitWidth>
            </field>
          </fields>
        </register>
        <register>
          <name>ISR</name>
          <addressOffset>0x18</addressOffset>
          <size>0x20</size>
          <fields>
            <field>
              <name>TXE</name>
              <bitOffset>0</bitOffset>
              <bitWidth>1</bitWidth>
            </field>
            <field>
              <name>TXIS</name>
              <bitOffset>1</bitOffset>
              <bitWidth>1</bitWidth>
            </field>
            <field>
              <name>RXNE</name>
              <bitOffset>2</bitOffset>
              <bitWidth>1</bitWidth>
            </field>
            <field>
              <name>ADDR</name>
              <bitOffset>3</bitOffset>
              <bitWidth>1</bitWidth>
            </field>
            <field>
              <name>NACKF</name>
              <bitOffset>4</bitOffset>
              <bitWidth>1</bitWidth>
            </field>
            <field>
              <name>STOPF</name>
              <bitOffset>5</bitOffset>
              <bitWidth>1</bitWidth>
            </field>
            <field>
              <name>TC</name>
              <bitOffset>6</bitOffset>
              <bitWidth>1</bitWidth>
            </field>
            <field>
              <name>TCR</name>
              <bitOffset>7</bitOffset>
              <bitWidth>1</bitWidth>
            </field>
            <field>
              <name>BERR</name>
              <bitOffset>8</bitOffset>
              <bitWidth>1</bitWidth>
            </field>
            <field>
              <name>ARLO</name>
              <bitOffset>9</bitOffset>
              <bitWidth>1</bitWidth>
            </field>
            <field>
              <name>OVR</name>
              <bitOffset>10</bitOffset>
              <bitWidth>1</bitWidth>
            </field>
            <field>
              <name>PECERR</name>
              <bitOffset>11</bitOffset>
              <bitWidth>1</bitWidth>
            </field>
            <field>
              <name>TIMEOUT</name>
              <bitOffset>12</bitOffset>
              <bitWidth>1</bitWidth>
            </field>
            <field>
              <name>ALERT</name>
              <bitOffset>13</bitOffset>
              <bitWidth>1</bitWidth>
            </field>
            <field>
              <name>BUSY</name>
              <bitOffset>15</bitOffset>
              <bitWidth>1</bitWidth>
            </field>
            <field>
              <name>DIR</name>
              <bitOffset>16</bitOffset>
              <bitWidth>1</bitWidth>
            </field>
            <field>
              <name>ADDCODE</name>
              <bitOffset>17</bitOffset>
              <bitWidth>7</bitWidth>
            </field>
          </fields>
        </register>
        <register>
          <name>ICR</name>
          <addressOffset>0x1c</addressOffset>
          <size>0x20</size>
          <fields>
            <field>
              <name>ADDRCF</name>
              <bitOffset>3</bitOffset>
              <bitWidth>1</bitWidth>
            </field>
            <field>
              <name>NACKCF</name>
              <bitOffset>4</bitOffset>
              <bitWidth>1</bitWidth>
            </field>
            <field>
              <name>STOPCF</name>
              <bitOffset>5</bitOffset>
              <bitWidth>1</bitWidth>
            </field>
            <field>
              <name>BERRCF</name>
              <bitOffset>8</bitOffset>
              <bitWidth>1</bitWidth>
            </field>
            <field>
              <name>ARLOCF</name>
              <bitOffset>9</bitOffset>
              <bitWidth>1</bitWidth>
            </field>
            <field>
              <name>OVRCF</name>
              <bitOffset>10</bitOffset>
              <bitWidth>1</bitWidth>
            </field>
            <field>
              <name>PECCF</name>
              <bitOffset>11</bitOffset>
              <bitWidth>1</bitWidth>
            </field>
            <field>
              <name>TIMOUTCF</name>
              <bitOffset>12</bitOffset>
              <bitWidth>1</bitWidth>
            </field>
            <field>
              <name>ALERTCF</name>
              <bitOffset>13</bitOffset>
              <bitWidth>1</bitWidth>
            </field>
          </fields>
        </register>
        <register>
          <name>PECR</name>
          <addressOffset>0x20</addressOffset>
          <size>0x20</size>
          <fields>
            <field>
              <name>PEC</name>
              <bitOffset>0</bitOffset>
              <bitWidth>8</bitWidth>
            </field>
          </fields>
        </register>
        <register>
          <name>RXDR</name>
          <addressOffset>0x24</addressOffset>
          <size>0x20</size>
          <fields>
            <field>
              <name>RXDATA</name>
              <bitOffset>0</bitOffset>
              <bitWidth>8</bitWidth>
            </field>
          </fields>
        </register>
        <register>
          <name>TXDR</name>
          <addressOffset>0x28</addressOffset>
          <size>0x20</size>
          <fields>
            <field>
              <name>TXDATA</name>
              <bitOffset>0</bitOffset>
              <bitWidth>8</bitWidth>
            </field>
          </fields>
        </register>
      </registers>
    </peripheral>
    <peripheral>
      <name>LPTIM1</name>
      <baseAddress>0x40007c00</baseAddress>
      <registers>
        <register>
          <name>ISR</name>
          <addressOffset>0x0</addressOffset>
          <size>0x20</size>
          <fields>
            <field>
              <name>CMPM</name>
              <bitOffset>0</bitOffset>
              <bitWidth>1</bitWidth>
            </field>
            <field>
              <name>ARRM</name>
              <bitOffset>1</bitOffset>
              <bitWidth>1</bitWidth>
            </field>
            <field>
              <name>EXTTRIG</name>
              <bitOffset>2</bitOffset>
              <bitWidth>1</bitWidth>
            </field>
            <field>
              <name>CMPOK</name>
              <bitOffset>3</bitOffset>
              <bitWidth>1</bitWidth>
            </field>
            <field>
              <name>ARROK</name>
              <bitOffset>4</bitOffset>
              <bitWidth>1</bitWidth>
            </field>
            <field>
              <name>UP</name>
              <bitOffset>5</bitOffset>
              <bitWidth>1</bitWidth>
            </field>
            <field>
              <name>DOWN</name>
              <bitOffset>6</bitOffset>
              <bitWidth>1</bitWidth>
            </field>
          </fields>
        </register>
        <register>
          <name>ICR</name>
          <addressOffset>0x4</addressOffset>
          <size>0x20</size>
          <fields>
            <field>
              <name>CMPMCF</name>
              <bitOffset>0</bitOffset>
              <bitWidth>1</bitWidth>
            </field>
            <field>
              <name>ARRMCF</name>
              <bitOffset>1</bitOffset>
              <bitWidth>1</bitWidth>
            </field>
            <field>
              <name>EXTTRIGCF</name>
              <bitOffset>2</bitOffset>
              <bitWidth>1</bitWidth>
            </field>
            <field>
              <name>CMPOKCF</name>
              <bitOffset>3</bitOffset>
              <bitWidth>1</bitWidth>
            </field>
            <field>
              <name>ARROKCF</name>
              <bitOffset>4</bitOffset>
              <bitWidth>1</bitWidth>
            </field>
            <field>
              <name>UPCF</name>
              <bitOffset>5</bitOffset>
              <bitWidth>1</bitWidth>
            </field>
            <field>
              <name>DOWNCF</name>
              <bitOffset>6</bitOffset>
              <bitWidth>1</bitWidth>
            </field>
          </fields>
        </register>
        <register>
          <name>IER</name>
          <addressOffset>0x8</addressOffset>
          <size>0x20</size>
          <fields>
            <field>
              <name>CMPMIE</name>
              <bitOffset>0</bitOffset>
              <bitWidth>1</bitWidth>
            </field>
            <field>
              <name>ARRMIE</name>
              <bitOffset>1</bitOffset>
              <bitWidth>1</bitWidth>
            </field>
            <field>
              <name>EXTTRIGIE</name>
              <bitOffset>2</bitOffset>
              <bitWidth>1</bitWidth>
            </field>
            <field>
              <name>CMPOKIE</name>
              <bitOffset>3</bitOffset>
              <bitWidth>1</bitWidth>
            </field>
            <field>
              <name>ARROKIE</name>
              <bitOffset>4</bitOffset>
              <bitWidth>1</bitWidth>
            </field>
            <field>
              <name>UPIE</name>
              <bitOffset>5</bitOffset>
              <bitWidth>1</bitWidth>
            </field>
            <field>
              <name>DOWNIE</name>
              <bitOffset>6</bitOffset>
              <bitWidth>1</bitWidth>
            </field>
          </fields>
        </register>
        <register>
          <name>CFGR</name>
          <addressOffset>0xc</addressOffset>
          <size>0x20</size>
          <fields>
            <field>
              <name>CKSEL</name>
              <bitOffset>0</bitOffset>
              <bitWidth>1</bitWidth>
            </field>
            <field>
              <name>CKPOL</name>
              <bitOffset>1</bitOffset>
              <bitWidth>2</bitWidth>
            </field>
            <field>
              <name>CKFLT</name>
              <bitOffset>3</bitOffset>
              <bitWidth>2</bitWidth>
            </field>
            <field>
              <name>TRGFLT</name>
              <bitOffset>6</bitOffset>
              <bitWidth>2</bitWidth>
            </field>
            <field>
              <name>PRESC</name>
              <bitOffset>9</bitOffset>
              <bitWidth>3</bitWidth>
            </field>
            <field>
              <name>TRIGSEL</name>
              <bitOffset>13</bitOffset>
              <bitWidth>17</bitWidth>
            </field>
            <field>
              <name>TRIGEN</name>
              <bitOffset>17</bitOffset>
              <bitWidth>2</bitWidth>
            </field>
            <field>
              <name>TIMOUT</name>
              <bitOffset>19</bitOffset>
              <bitWidth>1</bitWidth>
            </field>
            <field>
              <name>WAVE</name>
              <bitOffset>20</bitOffset>
              <bitWidth>1</bitWidth>
            </field>
            <field>
              <name>WAVPOL</name>
              <bitOffset>21</bitOffset>
              <bitWidth>1</bitWidth>
            </field>
            <field>
              <name>PRELOAD</name>
              <bitOffset>22</bitOffset>
              <bitWidth>1</bitWidth>
            </field>
            <field>
              <name>COUNTMODE</name>
              <bitOffset>23</bitOffset>
              <bitWidth>1</bitWidth>
            </field>
            <field>
              <name>ENC</name>
              <bitOffset>24</bitOffset>
              <bitWidth>1</bitWidth>
            </field>
          </fields>
        </register>
        <register>
          <name>CR</name>
          <addressOffset>0x10</addressOffset>
          <size>0x20</size>
          <fields>
            <field>
              <name>ENABLE</name>
              <bitOffset>0</bitOffset>
              <bitWidth>1</bitWidth>
            </field>
            <field>
              <name>SNGSTRT</name>
              <bitOffset>1</bitOffset>
              <bitWidth>1</bitWidth>
            </field>
            <field>
              <name>CNTSTRT</name>
              <bitOffset>2</bitOffset>
              <bitWidth>1</bitWidth>
            </field>
            <field>
              <name>COUNTRST</name>
              <bitOffset>3</bitOffset>
              <bitWidth>1</bitWidth>
            </field>
            <field>
              <name>RSTARE</name>
              <bitOffset>4</bitOffset>
              <bitWidth>1</bitWidth>
            </field>
          </fields>
        </register>
        <register>
          <name>CMP</name>
          <addressOffset>0x14</addressOffset>
          <size>0x20</size>
          <fields>
            <field>
              <name>CMP</name>
              <bitOffset>0</bitOffset>
              <bitWidth>16</bitWidth>
            </field>
          </fields>
        </register>
        <register>
          <name>ARR</name>
          <addressOffset>0x18</addressOffset>
          <size>0x20</size>
          <fields>
            <field>
              <name>ARR</name>
              <bitOffset>0</bitOffset>
              <bitWidth>16</bitWidth>
            </field>
          </fields>
        </register>
        <register>
          <name>CNT</name>
          <addressOffset>0x1c</addressOffset>
          <size>0x20</size>
          <fields>
            <field>
              <name>CNT</name>
              <bitOffset>0</bitOffset>
              <bitWidth>16</bitWidth>
            </field>
          </fields>
        </register>
        <register>
          <name>OR</name>
          <addressOffset>0x20</addressOffset>
          <size>0x20</size>
          <fields>
            <field>
              <name>IN1</name>
              <bitOffset>0</bitOffset>
              <bitWidth>4</bitWidth>
            </field>
            <field>
              <name>IN2</name>
              <bitOffset>1</bitOffset>
              <bitWidth>5</bitWidth>
            </field>
          </fields>
        </register>
      </registers>
    </peripheral>
    <peripheral>
      <name>LPUART1</name>
      <baseAddress>0x40008000</baseAddress>
      <registers>
        <register>
          <name>CR1</name>
          <addressOffset>0x0</addressOffset>
          <size>0x20</size>
          <fields>
            <field>
              <name>UE</name>
              <bitOffset>0</bitOffset>
              <bitWidth>1</bitWidth>
            </field>
            <field>
              <name>UESM</name>
              <bitOffset>1</bitOffset>
              <bitWidth>1</bitWidth>
            </field>
            <field>
              <name>RE</name>
              <bitOffset>2</bitOffset>
              <bitWidth>1</bitWidth>
            </field>
            <field>
              <name>TE</name>
              <bitOffset>3</bitOffset>
              <bitWidth>1</bitWidth>
            </field>
            <field>
              <name>IDLEIE</name>
              <bitOffset>4</bitOffset>
              <bitWidth>1</bitWidth>
            </field>
            <field>
              <name>RXNEIE_RXFNEIE</name>
              <bitOffset>5</bitOffset>
              <bitWidth>1</bitWidth>
            </field>
            <field>
              <name>TCIE</name>
              <bitOffset>6</bitOffset>
              <bitWidth>1</bitWidth>
            </field>
            <field>
              <name>TXEIE_TXFNFIE</name>
              <bitOffset>7</bitOffset>
              <bitWidth>1</bitWidth>
            </field>
            <field>
              <name>PEIE</name>
              <bitOffset>8</bitOffset>
              <bitWidth>1</bitWidth>
            </field>
            <field>
              <name>PS</name>
              <bitOffset>9</bitOffset>
              <bitWidth>1</bitWidth>
            </field>
            <field>
              <name>PCE</name>
              <bitOffset>10</bitOffset>
              <bitWidth>1</bitWidth>
            </field>
            <field>
              <name>WAKE</name>
              <bitOffset>11</bitOffset>
              <bitWidth>1</bitWidth>
            </field>
            <field>
              <name>M0</name>
              <bitOffset>12</bitOffset>
              <bitWidth>1</bitWidth>
            </field>
            <field>
              <name>MME</name>
              <bitOffset>13</bitOffset>
              <bitWidth>1</bitWidth>
            </field>
            <field>
              <name>CMIE</name>
              <bitOffset>14</bitOffset>
              <bitWidth>1</bitWidth>
            </field>
            <field>
              <name>OVER8</name>
              <bitOffset>15</bitOffset>
              <bitWidth>1</bitWidth>
            </field>
            <field>
              <name>DEDT</name>
              <bitOffset>16</bitOffset>
              <bitWidth>5</bitWidth>
            </field>
            <field>
              <name>DEAT</name>
              <bitOffset>21</bitOffset>
              <bitWidth>5</bitWidth>
            </field>
            <field>
              <name>RTOIE</name>
              <bitOffset>26</bitOffset>
              <bitWidth>1</bitWidth>
            </field>
            <field>
              <name>EOBIE</name>
              <bitOffset>27</bitOffset>
              <bitWidth>1</bitWidth>
            </field>
            <field>
              <name>M1</name>
              <bitOffset>28</bitOffset>
              <bitWidth>1</bitWidth>
            </field>
            <field>
              <name>FIFOEN</name>
              <bitOffset>29</bitOffset>
              <bitWidth>1</bitWidth>
            </field>
            <field>
              <name>TXFEIE</name>
              <bitOffset>30</bitOffset>
              <bitWidth>1</bitWidth>
            </field>
            <field>
              <name>RXFFIE</name>
              <bitOffset>31</bitOffset>
              <bitWidth>1</bitWidth>
            </field>
          </fields>
        </register>
        <register>
          <name>CR2</name>
          <addressOffset>0x4</addressOffset>
          <size>0x20</size>
          <fields>
            <field>
              <name>SLVEN</name>
              <bitOffset>0</bitOffset>
              <bitWidth>1</bitWidth>
            </field>
            <field>
              <name>DIS_NSS</name>
              <bitOffset>3</bitOffset>
              <bitWidth>1</bitWidth>
            </field>
            <field>
              <name>ADDM7</name>
              <bitOffset>4</bitOffset>
              <bitWidth>1</bitWidth>
            </field>
            <field>
              <name>LBDL</name>
              <bitOffset>5</bitOffset>
              <bitWidth>1</bitWidth>
            </field>
            <field>
              <name>LBDIE</name>
              <bitOffset>6</bitOffset>
              <bitWidth>1</bitWidth>
            </field>
            <field>
              <name>LBCL</name>
              <bitOffset>8</bitOffset>
              <bitWidth>1</bitWidth>
            </field>
            <field>
              <name>CPHA</name>
              <bitOffset>9</bitOffset>
              <bitWidth>1</bitWidth>
            </field>
            <field>
              <name>CPOL</name>
              <bitOffset>10</bitOffset>
              <bitWidth>1</bitWidth>
            </field>
            <field>
              <name>CLKEN</name>
              <bitOffset>11</bitOffset>
              <bitWidth>1</bitWidth>
            </field>
            <field>
              <name>STOP</name>
              <bitOffset>12</bitOffset>
              <bitWidth>2</bitWidth>
            </field>
            <field>
              <name>LINEN</name>
              <bitOffset>14</bitOffset>
              <bitWidth>1</bitWidth>
            </field>
            <field>
              <name>SWAP</name>
              <bitOffset>15</bitOffset>
              <bitWidth>1</bitWidth>
            </field>
            <field>
              <name>RXINV</name>
              <bitOffset>16</bitOffset>
              <bitWidth>1</bitWidth>
            </field>
            <field>
              <name>TXINV</name>
              <bitOffset>17</bitOffset>
              <bitWidth>1</bitWidth>
            </field>
            <field>
              <name>DATAINV</name>
              <bitOffset>18</bitOffset>
              <bitWidth>1</bitWidth>
            </field>
            <field>
              <name>MSBFIRST</name>
              <bitOffset>19</bitOffset>
              <bitWidth>1</bitWidth>
            </field>
            <field>
              <name>ABREN</name>
              <bitOffset>20</bitOffset>
              <bitWidth>1</bitWidth>
            </field>
            <field>
              <name>ABRMODE</name>
              <bitOffset>21</bitOffset>
              <bitWidth>2</bitWidth>
            </field>
            <field>
              <name>RTOEN</name>
              <bitOffset>23</bitOffset>
              <bitWidth>1</bitWidth>
            </field>
            <field>
              <name>ADD</name>
              <bitOffset>24</bitOffset>
              <bitWidth>8</bitWidth>
            </field>
          </fields>
        </register>
        <register>
          <name>CR3</name>
          <addressOffset>0x8</addressOffset>
          <size>0x20</size>
          <fields>
            <field>
              <name>EIE</name>
              <bitOffset>0</bitOffset>
              <bitWidth>1</bitWidth>
            </field>
            <field>
              <name>IREN</name>
              <bitOffset>1</bitOffset>
              <bitWidth>1</bitWidth>
            </field>
            <field>
              <name>IRLP</name>
              <bitOffset>2</bitOffset>
              <bitWidth>1</bitWidth>
            </field>
            <field>
              <name>HDSEL</name>
              <bitOffset>3</bitOffset>
              <bitWidth>1</bitWidth>
            </field>
            <field>
              <name>NACK</name>
              <bitOffset>4</bitOffset>
              <bitWidth>1</bitWidth>
            </field>
            <field>
              <name>SCEN</name>
              <bitOffset>5</bitOffset>
              <bitWidth>1</bitWidth>
            </field>
            <field>
              <name>DMAR</name>
              <bitOffset>6</bitOffset>
              <bitWidth>1</bitWidth>
            </field>
            <field>
              <name>DMAT</name>
              <bitOffset>7</bitOffset>
              <bitWidth>1</bitWidth>
            </field>
            <field>
              <name>RTSE</name>
              <bitOffset>8</bitOffset>
              <bitWidth>1</bitWidth>
            </field>
            <field>
              <name>CTSE</name>
              <bitOffset>9</bitOffset>
              <bitWidth>1</bitWidth>
            </field>
            <field>
              <name>CTSIE</name>
              <bitOffset>10</bitOffset>
              <bitWidth>1</bitWidth>
            </field>
            <field>
              <name>ONEBIT</name>
              <bitOffset>11</bitOffset>
              <bitWidth>1</bitWidth>
            </field>
            <field>
              <name>OVRDIS</name>
              <bitOffset>12</bitOffset>
              <bitWidth>1</bitWidth>
            </field>
            <field>
              <name>DDRE</name>
              <bitOffset>13</bitOffset>
              <bitWidth>1</bitWidth>
            </field>
            <field>
              <name>DEM</name>
              <bitOffset>14</bitOffset>
              <bitWidth>1</bitWidth>
            </field>
            <field>
              <name>DEP</name>
              <bitOffset>15</bitOffset>
              <bitWidth>1</bitWidth>
            </field>
            <field>
              <name>SCARCNT</name>
              <bitOffset>17</bitOffset>
              <bitWidth>3</bitWidth>
            </field>
            <field>
              <name>WUS</name>
              <bitOffset>20</bitOffset>
              <bitWidth>2</bitWidth>
            </field>
            <field>
              <name>WUFIE</name>
              <bitOffset>22</bitOffset>
              <bitWidth>1</bitWidth>
            </field>
            <field>
              <name>TXFTIE</name>
              <bitOffset>23</bitOffset>
              <bitWidth>1</bitWidth>
            </field>
            <field>
              <name>TCBGTIE</name>
              <bitOffset>24</bitOffset>
              <bitWidth>1</bitWidth>
            </field>
            <field>
              <name>RXFTCFG</name>
              <bitOffset>25</bitOffset>
              <bitWidth>3</bitWidth>
            </field>
            <field>
              <name>RXFTIE</name>
              <bitOffset>28</bitOffset>
              <bitWidth>1</bitWidth>
            </field>
            <field>
              <name>TXFTCFG</name>
              <bitOffset>29</bitOffset>
              <bitWidth>3</bitWidth>
            </field>
          </fields>
        </register>
        <register>
          <name>BRR</name>
          <addressOffset>0xc</addressOffset>
          <size>0x20</size>
          <fields>
            <field>
              <name>LPUART</name>
              <bitOffset>0</bitOffset>
              <bitWidth>20</bitWidth>
            </field>
          </fields>
        </register>
        <register>
          <name>GTPR</name>
          <addressOffset>0x10</addressOffset>
          <size>0x20</size>
          <fields>
            <field>
              <name>PSC</name>
              <bitOffset>0</bitOffset>
              <bitWidth>8</bitWidth>
            </field>
            <field>
              <name>GT</name>
              <bitOffset>8</bitOffset>
              <bitWidth>8</bitWidth>
            </field>
          </fields>
        </register>
        <register>
          <name>RTOR</name>
          <addressOffset>0x14</addressOffset>
          <size>0x20</size>
          <fields>
            <field>
              <name>RTO</name>
              <bitOffset>0</bitOffset>
              <bitWidth>24</bitWidth>
            </field>
            <field>
              <name>BLEN</name>
              <bitOffset>24</bitOffset>
              <bitWidth>8</bitWidth>
            </field>
          </fields>
        </register>
        <register>
          <name>RQR</name>
          <addressOffset>0x18</addressOffset>
          <size>0x20</size>
          <fields>
            <field>
              <name>ABRRQ</name>
              <bitOffset>0</bitOffset>
              <bitWidth>1</bitWidth>
            </field>
            <field>
              <name>SBKRQ</name>
              <bitOffset>1</bitOffset>
              <bitWidth>1</bitWidth>
            </field>
            <field>
              <name>MMRQ</name>
              <bitOffset>2</bitOffset>
              <bitWidth>1</bitWidth>
            </field>
            <field>
              <name>RXFRQ</name>
              <bitOffset>3</bitOffset>
              <bitWidth>1</bitWidth>
            </field>
            <field>
              <name>TXFRQ</name>
              <bitOffset>4</bitOffset>
              <bitWidth>1</bitWidth>
            </field>
          </fields>
        </register>
        <register>
          <name>ISR</name>
          <addressOffset>0x1c</addressOffset>
          <size>0x20</size>
          <fields>
            <field>
              <name>PE</name>
              <bitOffset>0</bitOffset>
              <bitWidth>1</bitWidth>
            </field>
            <field>
              <name>FE</name>
              <bitOffset>1</bitOffset>
              <bitWidth>1</bitWidth>
            </field>
            <field>
              <name>NE</name>
              <bitOffset>2</bitOffset>
              <bitWidth>1</bitWidth>
            </field>
            <field>
              <name>ORE</name>
              <bitOffset>3</bitOffset>
              <bitWidth>1</bitWidth>
            </field>
            <field>
              <name>IDLE</name>
              <bitOffset>4</bitOffset>
              <bitWidth>1</bitWidth>
            </field>
            <field>
              <name>RXNE_RXFNE</name>
              <bitOffset>5</bitOffset>
              <bitWidth>1</bitWidth>
            </field>
            <field>
              <name>TC</name>
              <bitOffset>6</bitOffset>
              <bitWidth>1</bitWidth>
            </field>
            <field>
              <name>TXE_TXFNF</name>
              <bitOffset>7</bitOffset>
              <bitWidth>1</bitWidth>
            </field>
            <field>
              <name>LBDF</name>
              <bitOffset>8</bitOffset>
              <bitWidth>1</bitWidth>
            </field>
            <field>
              <name>CTSIF</name>
              <bitOffset>9</bitOffset>
              <bitWidth>1</bitWidth>
            </field>
            <field>
              <name>CTS</name>
              <bitOffset>10</bitOffset>
              <bitWidth>1</bitWidth>
            </field>
            <field>
              <name>RTOF</name>
              <bitOffset>11</bitOffset>
              <bitWidth>1</bitWidth>
            </field>
            <field>
              <name>EOBF</name>
              <bitOffset>12</bitOffset>
              <bitWidth>1</bitWidth>
            </field>
            <field>
              <name>UDR</name>
              <bitOffset>13</bitOffset>
              <bitWidth>1</bitWidth>
            </field>
            <field>
              <name>ABRE</name>
              <bitOffset>14</bitOffset>
              <bitWidth>1</bitWidth>
            </field>
            <field>
              <name>ABRF</name>
              <bitOffset>15</bitOffset>
              <bitWidth>1</bitWidth>
            </field>
            <field>
              <name>BUSY</name>
              <bitOffset>16</bitOffset>
              <bitWidth>1</bitWidth>
            </field>
            <field>
              <name>CMF</name>
              <bitOffset>17</bitOffset>
              <bitWidth>1</bitWidth>
            </field>
            <field>
              <name>SBKF</name>
              <bitOffset>18</bitOffset>
              <bitWidth>1</bitWidth>
            </field>
            <field>
              <name>RWU</name>
              <bitOffset>19</bitOffset>
              <bitWidth>1</bitWidth>
            </field>
            <field>
              <name>WUF</name>
              <bitOffset>20</bitOffset>
              <bitWidth>1</bitWidth>
            </field>
            <field>
              <name>TEACK</name>
              <bitOffset>21</bitOffset>
              <bitWidth>1</bitWidth>
            </field>
            <field>
              <name>REACK</name>
              <bitOffset>22</bitOffset>
              <bitWidth>1</bitWidth>
            </field>
            <field>
              <name>TXFE</name>
              <bitOffset>23</bitOffset>
              <bitWidth>1</bitWidth>
            </field>
            <field>
              <name>RXFF</name>
              <bitOffset>24</bitOffset>
              <bitWidth>1</bitWidth>
            </field>
            <field>
              <name>TCBGT</name>
              <bitOffset>25</bitOffset>
              <bitWidth>1</bitWidth>
            </field>
            <field>
              <name>RXFT</name>
              <bitOffset>26</bitOffset>
              <bitWidth>1</bitWidth>
            </field>
            <field>
              <name>TXFT</name>
              <bitOffset>27</bitOffset>
              <bitWidth>1</bitWidth>
            </field>
          </fields>
        </register>
        <register>
          <name>ICR</name>
          <addressOffset>0x20</addressOffset>
          <size>0x20</size>
          <fields>
            <field>
              <name>PECF</name>
              <bitOffset>0</bitOffset>
              <bitWidth>1</bitWidth>
            </field>
            <field>
              <name>FECF</name>
              <bitOffset>1</bitOffset>
              <bitWidth>1</bitWidth>
            </field>
            <field>
              <name>NECF</name>
              <bitOffset>2</bitOffset>
              <bitWidth>1</bitWidth>
            </field>
            <field>
              <name>ORECF</name>
              <bitOffset>3</bitOffset>
              <bitWidth>1</bitWidth>
            </field>
            <field>
              <name>IDLECF</name>
              <bitOffset>4</bitOffset>
              <bitWidth>1</bitWidth>
            </field>
            <field>
              <name>TXFECF</name>
              <bitOffset>5</bitOffset>
              <bitWidth>1</bitWidth>
            </field>
            <field>
              <name>TCCF</name>
              <bitOffset>6</bitOffset>
              <bitWidth>1</bitWidth>
            </field>
            <field>
              <name>TCBGTCF</name>
              <bitOffset>7</bitOffset>
              <bitWidth>1</bitWidth>
            </field>
            <field>
              <name>LBDCF</name>
              <bitOffset>8</bitOffset>
              <bitWidth>1</bitWidth>
            </field>
            <field>
              <name>CTSCF</name>
              <bitOffset>9</bitOffset>
              <bitWidth>1</bitWidth>
            </field>
            <field>
              <name>RTOCF</name>
              <bitOffset>11</bitOffset>
              <bitWidth>1</bitWidth>
            </field>
            <field>
              <name>EOBCF</name>
              <bitOffset>12</bitOffset>
              <bitWidth>1</bitWidth>
            </field>
            <field>
              <name>UDRCF</name>
              <bitOffset>13</bitOffset>
              <bitWidth>1</bitWidth>
            </field>
            <field>
              <name>CMCF</name>
              <bitOffset>17</bitOffset>
              <bitWidth>1</bitWidth>
            </field>
            <field>
              <name>WUCF</name>
              <bitOffset>20</bitOffset>
              <bitWidth>1</bitWidth>
            </field>
          </fields>
        </register>
        <register>
          <name>RDR</name>
          <addressOffset>0x24</addressOffset>
          <size>0x20</size>
          <fields>
            <field>
              <name>RDR</name>
              <bitOffset>0</bitOffset>
              <bitWidth>9</bitWidth>
            </field>
          </fields>
        </register>
        <register>
          <name>TDR</name>
          <addressOffset>0x28</addressOffset>
          <size>0x20</size>
          <fields>
            <field>
              <name>TDR</name>
              <bitOffset>0</bitOffset>
              <bitWidth>9</bitWidth>
            </field>
          </fields>
        </register>
        <register>
          <name>PRESC</name>
          <addressOffset>0x2c</addressOffset>
          <size>0x20</size>
          <fields>
            <field>
              <name>PRESCALER</name>
              <bitOffset>0</bitOffset>
              <bitWidth>4</bitWidth>
            </field>
          </fields>
        </register>
      </registers>
    </peripheral>
    <peripheral>
      <name>I2C4</name>
      <baseAddress>0x40008400</baseAddress>
      <registers>
        <register>
          <name>CR1</name>
          <addressOffset>0x0</addressOffset>
          <size>0x20</size>
          <fields>
            <field>
              <name>PE</name>
              <bitOffset>0</bitOffset>
              <bitWidth>1</bitWidth>
            </field>
            <field>
              <name>TXIE</name>
              <bitOffset>1</bitOffset>
              <bitWidth>1</bitWidth>
            </field>
            <field>
              <name>RXIE</name>
              <bitOffset>2</bitOffset>
              <bitWidth>1</bitWidth>
            </field>
            <field>
              <name>ADDRIE</name>
              <bitOffset>3</bitOffset>
              <bitWidth>1</bitWidth>
            </field>
            <field>
              <name>NACKIE</name>
              <bitOffset>4</bitOffset>
              <bitWidth>1</bitWidth>
            </field>
            <field>
              <name>STOPIE</name>
              <bitOffset>5</bitOffset>
              <bitWidth>1</bitWidth>
            </field>
            <field>
              <name>TCIE</name>
              <bitOffset>6</bitOffset>
              <bitWidth>1</bitWidth>
            </field>
            <field>
              <name>ERRIE</name>
              <bitOffset>7</bitOffset>
              <bitWidth>1</bitWidth>
            </field>
            <field>
              <name>DNF</name>
              <bitOffset>8</bitOffset>
              <bitWidth>4</bitWidth>
            </field>
            <field>
              <name>ANFOFF</name>
              <bitOffset>12</bitOffset>
              <bitWidth>1</bitWidth>
            </field>
            <field>
              <name>SWRST</name>
              <bitOffset>13</bitOffset>
              <bitWidth>1</bitWidth>
            </field>
            <field>
              <name>TXDMAEN</name>
              <bitOffset>14</bitOffset>
              <bitWidth>1</bitWidth>
            </field>
            <field>
              <name>RXDMAEN</name>
              <bitOffset>15</bitOffset>
              <bitWidth>1</bitWidth>
            </field>
            <field>
              <name>SBC</name>
              <bitOffset>16</bitOffset>
              <bitWidth>1</bitWidth>
            </field>
            <field>
              <name>NOSTRETCH</name>
              <bitOffset>17</bitOffset>
              <bitWidth>1</bitWidth>
            </field>
            <field>
              <name>WUPEN</name>
              <bitOffset>18</bitOffset>
              <bitWidth>1</bitWidth>
            </field>
            <field>
              <name>GCEN</name>
              <bitOffset>19</bitOffset>
              <bitWidth>1</bitWidth>
            </field>
            <field>
              <name>SMBHEN</name>
              <bitOffset>20</bitOffset>
              <bitWidth>1</bitWidth>
            </field>
            <field>
              <name>SMBDEN</name>
              <bitOffset>21</bitOffset>
              <bitWidth>1</bitWidth>
            </field>
            <field>
              <name>ALERTEN</name>
              <bitOffset>22</bitOffset>
              <bitWidth>1</bitWidth>
            </field>
            <field>
              <name>PECEN</name>
              <bitOffset>23</bitOffset>
              <bitWidth>1</bitWidth>
            </field>
          </fields>
        </register>
        <register>
          <name>CR2</name>
          <addressOffset>0x4</addressOffset>
          <size>0x20</size>
          <fields>
            <field>
              <name>SADD</name>
              <bitOffset>0</bitOffset>
              <bitWidth>10</bitWidth>
            </field>
            <field>
              <name>RD_WRN</name>
              <bitOffset>10</bitOffset>
              <bitWidth>1</bitWidth>
            </field>
            <field>
              <name>ADD10</name>
              <bitOffset>11</bitOffset>
              <bitWidth>1</bitWidth>
            </field>
            <field>
              <name>HEAD10R</name>
              <bitOffset>12</bitOffset>
              <bitWidth>1</bitWidth>
            </field>
            <field>
              <name>START</name>
              <bitOffset>13</bitOffset>
              <bitWidth>1</bitWidth>
            </field>
            <field>
              <name>STOP</name>
              <bitOffset>14</bitOffset>
              <bitWidth>1</bitWidth>
            </field>
            <field>
              <name>NACK</name>
              <bitOffset>15</bitOffset>
              <bitWidth>1</bitWidth>
            </field>
            <field>
              <name>NBYTES</name>
              <bitOffset>16</bitOffset>
              <bitWidth>8</bitWidth>
            </field>
            <field>
              <name>RELOAD</name>
              <bitOffset>24</bitOffset>
              <bitWidth>1</bitWidth>
            </field>
            <field>
              <name>AUTOEND</name>
              <bitOffset>25</bitOffset>
              <bitWidth>1</bitWidth>
            </field>
            <field>
              <name>PECBYTE</name>
              <bitOffset>26</bitOffset>
              <bitWidth>1</bitWidth>
            </field>
          </fields>
        </register>
        <register>
          <name>OAR1</name>
          <addressOffset>0x8</addressOffset>
          <size>0x20</size>
          <fields>
            <field>
              <name>OA1</name>
              <bitOffset>0</bitOffset>
              <bitWidth>10</bitWidth>
            </field>
            <field>
              <name>OA1MODE</name>
              <bitOffset>10</bitOffset>
              <bitWidth>1</bitWidth>
            </field>
            <field>
              <name>OA1EN</name>
              <bitOffset>15</bitOffset>
              <bitWidth>1</bitWidth>
            </field>
          </fields>
        </register>
        <register>
          <name>OAR2</name>
          <addressOffset>0xc</addressOffset>
          <size>0x20</size>
          <fields>
            <field>
              <name>OA2</name>
              <bitOffset>1</bitOffset>
              <bitWidth>7</bitWidth>
            </field>
            <field>
              <name>OA2MSK</name>
              <bitOffset>8</bitOffset>
              <bitWidth>3</bitWidth>
            </field>
            <field>
              <name>OA2MASK06</name>
              <bitOffset>9</bitOffset>
              <bitWidth>2</bitWidth>
            </field>
            <field>
              <name>OA2MASK04</name>
              <bitOffset>10</bitOffset>
              <bitWidth>1</bitWidth>
            </field>
            <field>
              <name>OA2EN</name>
              <bitOffset>15</bitOffset>
              <bitWidth>1</bitWidth>
            </field>
          </fields>
        </register>
        <register>
          <name>TIMINGR</name>
          <addressOffset>0x10</addressOffset>
          <size>0x20</size>
          <fields>
            <field>
              <name>SCLL</name>
              <bitOffset>0</bitOffset>
              <bitWidth>8</bitWidth>
            </field>
            <field>
              <name>SCLH</name>
              <bitOffset>8</bitOffset>
              <bitWidth>8</bitWidth>
            </field>
            <field>
              <name>SDADEL</name>
              <bitOffset>16</bitOffset>
              <bitWidth>4</bitWidth>
            </field>
            <field>
              <name>SCLDEL</name>
              <bitOffset>20</bitOffset>
              <bitWidth>4</bitWidth>
            </field>
            <field>
              <name>PRESC</name>
              <bitOffset>28</bitOffset>
              <bitWidth>4</bitWidth>
            </field>
          </fields>
        </register>
        <register>
          <name>TIMEOUTR</name>
          <addressOffset>0x14</addressOffset>
          <size>0x20</size>
          <fields>
            <field>
              <name>TIMEOUTA</name>
              <bitOffset>0</bitOffset>
              <bitWidth>12</bitWidth>
            </field>
            <field>
              <name>TIDLE</name>
              <bitOffset>12</bitOffset>
              <bitWidth>1</bitWidth>
            </field>
            <field>
              <name>TIMOUTEN</name>
              <bitOffset>15</bitOffset>
              <bitWidth>1</bitWidth>
            </field>
            <field>
              <name>TIMEOUTB</name>
              <bitOffset>16</bitOffset>
              <bitWidth>12</bitWidth>
            </field>
            <field>
              <name>TEXTEN</name>
              <bitOffset>31</bitOffset>
              <bitWidth>1</bitWidth>
            </field>
          </fields>
        </register>
        <register>
          <name>ISR</name>
          <addressOffset>0x18</addressOffset>
          <size>0x20</size>
          <fields>
            <field>
              <name>TXE</name>
              <bitOffset>0</bitOffset>
              <bitWidth>1</bitWidth>
            </field>
            <field>
              <name>TXIS</name>
              <bitOffset>1</bitOffset>
              <bitWidth>1</bitWidth>
            </field>
            <field>
              <name>RXNE</name>
              <bitOffset>2</bitOffset>
              <bitWidth>1</bitWidth>
            </field>
            <field>
              <name>ADDR</name>
              <bitOffset>3</bitOffset>
              <bitWidth>1</bitWidth>
            </field>
            <field>
              <name>NACKF</name>
              <bitOffset>4</bitOffset>
              <bitWidth>1</bitWidth>
            </field>
            <field>
              <name>STOPF</name>
              <bitOffset>5</bitOffset>
              <bitWidth>1</bitWidth>
            </field>
            <field>
              <name>TC</name>
              <bitOffset>6</bitOffset>
              <bitWidth>1</bitWidth>
            </field>
            <field>
              <name>TCR</name>
              <bitOffset>7</bitOffset>
              <bitWidth>1</bitWidth>
            </field>
            <field>
              <name>BERR</name>
              <bitOffset>8</bitOffset>
              <bitWidth>1</bitWidth>
            </field>
            <field>
              <name>ARLO</name>
              <bitOffset>9</bitOffset>
              <bitWidth>1</bitWidth>
            </field>
            <field>
              <name>OVR</name>
              <bitOffset>10</bitOffset>
              <bitWidth>1</bitWidth>
            </field>
            <field>
              <name>PECERR</name>
              <bitOffset>11</bitOffset>
              <bitWidth>1</bitWidth>
            </field>
            <field>
              <name>TIMEOUT</name>
              <bitOffset>12</bitOffset>
              <bitWidth>1</bitWidth>
            </field>
            <field>
              <name>ALERT</name>
              <bitOffset>13</bitOffset>
              <bitWidth>1</bitWidth>
            </field>
            <field>
              <name>BUSY</name>
              <bitOffset>15</bitOffset>
              <bitWidth>1</bitWidth>
            </field>
            <field>
              <name>DIR</name>
              <bitOffset>16</bitOffset>
              <bitWidth>1</bitWidth>
            </field>
            <field>
              <name>ADDCODE</name>
              <bitOffset>17</bitOffset>
              <bitWidth>7</bitWidth>
            </field>
          </fields>
        </register>
        <register>
          <name>ICR</name>
          <addressOffset>0x1c</addressOffset>
          <size>0x20</size>
          <fields>
            <field>
              <name>ADDRCF</name>
              <bitOffset>3</bitOffset>
              <bitWidth>1</bitWidth>
            </field>
            <field>
              <name>NACKCF</name>
              <bitOffset>4</bitOffset>
              <bitWidth>1</bitWidth>
            </field>
            <field>
              <name>STOPCF</name>
              <bitOffset>5</bitOffset>
              <bitWidth>1</bitWidth>
            </field>
            <field>
              <name>BERRCF</name>
              <bitOffset>8</bitOffset>
              <bitWidth>1</bitWidth>
            </field>
            <field>
              <name>ARLOCF</name>
              <bitOffset>9</bitOffset>
              <bitWidth>1</bitWidth>
            </field>
            <field>
              <name>OVRCF</name>
              <bitOffset>10</bitOffset>
              <bitWidth>1</bitWidth>
            </field>
            <field>
              <name>PECCF</name>
              <bitOffset>11</bitOffset>
              <bitWidth>1</bitWidth>
            </field>
            <field>
              <name>TIMOUTCF</name>
              <bitOffset>12</bitOffset>
              <bitWidth>1</bitWidth>
            </field>
            <field>
              <name>ALERTCF</name>
              <bitOffset>13</bitOffset>
              <bitWidth>1</bitWidth>
            </field>
          </fields>
        </register>
        <register>
          <name>PECR</name>
          <addressOffset>0x20</addressOffset>
          <size>0x20</size>
          <fields>
            <field>
              <name>PEC</name>
              <bitOffset>0</bitOffset>
              <bitWidth>8</bitWidth>
            </field>
          </fields>
        </register>
        <register>
          <name>RXDR</name>
          <addressOffset>0x24</addressOffset>
          <size>0x20</size>
          <fields>
            <field>
              <name>RXDATA</name>
              <bitOffset>0</bitOffset>
              <bitWidth>8</bitWidth>
            </field>
          </fields>
        </register>
        <register>
          <name>TXDR</name>
          <addressOffset>0x28</addressOffset>
          <size>0x20</size>
          <fields>
            <field>
              <name>TXDATA</name>
              <bitOffset>0</bitOffset>
              <bitWidth>8</bitWidth>
            </field>
          </fields>
        </register>
      </registers>
    </peripheral>
    <peripheral>
      <name>UCPD1</name>
      <baseAddress>0x4000a000</baseAddress>
      <registers>
        <register>
          <name>CFG1</name>
          <addressOffset>0x0</addressOffset>
          <size>0x20</size>
          <fields>
            <field>
              <name>HBITCLKDIV</name>
              <bitOffset>0</bitOffset>
              <bitWidth>6</bitWidth>
            </field>
            <field>
              <name>IFRGAP</name>
              <bitOffset>6</bitOffset>
              <bitWidth>5</bitWidth>
            </field>
            <field>
              <name>TRANSWIN</name>
              <bitOffset>11</bitOffset>
              <bitWidth>5</bitWidth>
            </field>
            <field>
              <name>PSC_UCPDCLK</name>
              <bitOffset>17</bitOffset>
              <bitWidth>3</bitWidth>
            </field>
            <field>
              <name>RXORDSETEN</name>
              <bitOffset>20</bitOffset>
              <bitWidth>9</bitWidth>
            </field>
            <field>
              <name>TXDMAEN</name>
              <bitOffset>29</bitOffset>
              <bitWidth>1</bitWidth>
            </field>
            <field>
              <name>RXDMAEN</name>
              <bitOffset>30</bitOffset>
              <bitWidth>1</bitWidth>
            </field>
            <field>
              <name>UCPDEN</name>
              <bitOffset>31</bitOffset>
              <bitWidth>1</bitWidth>
            </field>
          </fields>
        </register>
        <register>
          <name>CFG2</name>
          <addressOffset>0x4</addressOffset>
          <size>0x20</size>
          <fields>
            <field>
              <name>RXFILTDIS</name>
              <bitOffset>0</bitOffset>
              <bitWidth>1</bitWidth>
            </field>
            <field>
              <name>RXFILT2N3</name>
              <bitOffset>1</bitOffset>
              <bitWidth>1</bitWidth>
            </field>
            <field>
              <name>FORCECLK</name>
              <bitOffset>2</bitOffset>
              <bitWidth>1</bitWidth>
            </field>
            <field>
              <name>WUPEN</name>
              <bitOffset>3</bitOffset>
              <bitWidth>1</bitWidth>
            </field>
          </fields>
        </register>
        <register>
          <name>CR</name>
          <addressOffset>0xc</addressOffset>
          <size>0x20</size>
          <fields>
            <field>
              <name>TXMODE</name>
              <bitOffset>0</bitOffset>
              <bitWidth>2</bitWidth>
            </field>
            <field>
              <name>TXSEND</name>
              <bitOffset>2</bitOffset>
              <bitWidth>1</bitWidth>
            </field>
            <field>
              <name>TXHRST</name>
              <bitOffset>3</bitOffset>
              <bitWidth>1</bitWidth>
            </field>
            <field>
              <name>RXMODE</name>
              <bitOffset>4</bitOffset>
              <bitWidth>1</bitWidth>
            </field>
            <field>
              <name>PHYRXEN</name>
              <bitOffset>5</bitOffset>
              <bitWidth>1</bitWidth>
            </field>
            <field>
              <name>PHYCCSEL</name>
              <bitOffset>6</bitOffset>
              <bitWidth>1</bitWidth>
            </field>
            <field>
              <name>ANASUBMODE</name>
              <bitOffset>7</bitOffset>
              <bitWidth>2</bitWidth>
            </field>
            <field>
              <name>ANAMODE</name>
              <bitOffset>9</bitOffset>
              <bitWidth>1</bitWidth>
            </field>
            <field>
              <name>CCENABLE</name>
              <bitOffset>10</bitOffset>
              <bitWidth>2</bitWidth>
            </field>
            <field>
              <name>FRSRXEN</name>
              <bitOffset>16</bitOffset>
              <bitWidth>1</bitWidth>
            </field>
            <field>
              <name>FRSTX</name>
              <bitOffset>17</bitOffset>
              <bitWidth>1</bitWidth>
            </field>
            <field>
              <name>RDCH</name>
              <bitOffset>18</bitOffset>
              <bitWidth>1</bitWidth>
            </field>
            <field>
              <name>CC1TCDIS</name>
              <bitOffset>20</bitOffset>
              <bitWidth>1</bitWidth>
            </field>
            <field>
              <name>CC2TCDIS</name>
              <bitOffset>21</bitOffset>
              <bitWidth>1</bitWidth>
            </field>
          </fields>
        </register>
        <register>
          <name>IMR</name>
          <addressOffset>0x10</addressOffset>
          <size>0x20</size>
          <fields>
            <field>
              <name>TXISIE</name>
              <bitOffset>0</bitOffset>
              <bitWidth>1</bitWidth>
            </field>
            <field>
              <name>TXMSGDISCIE</name>
              <bitOffset>1</bitOffset>
              <bitWidth>1</bitWidth>
            </field>
            <field>
              <name>TXMSGSENTIE</name>
              <bitOffset>2</bitOffset>
              <bitWidth>1</bitWidth>
            </field>
            <field>
              <name>TXMSGABTIE</name>
              <bitOffset>3</bitOffset>
              <bitWidth>1</bitWidth>
            </field>
            <field>
              <name>HRSTDISCIE</name>
              <bitOffset>4</bitOffset>
              <bitWidth>1</bitWidth>
            </field>
            <field>
              <name>HRSTSENTIE</name>
              <bitOffset>5</bitOffset>
              <bitWidth>1</bitWidth>
            </field>
            <field>
              <name>TXUNDIE</name>
              <bitOffset>6</bitOffset>
              <bitWidth>1</bitWidth>
            </field>
            <field>
              <name>RXNEIE</name>
              <bitOffset>8</bitOffset>
              <bitWidth>1</bitWidth>
            </field>
            <field>
              <name>RXORDDETIE</name>
              <bitOffset>9</bitOffset>
              <bitWidth>1</bitWidth>
            </field>
            <field>
              <name>RXHRSTDETIE</name>
              <bitOffset>10</bitOffset>
              <bitWidth>1</bitWidth>
            </field>
            <field>
              <name>RXOVRIE</name>
              <bitOffset>11</bitOffset>
              <bitWidth>1</bitWidth>
            </field>
            <field>
              <name>RXMSGENDIE</name>
              <bitOffset>12</bitOffset>
              <bitWidth>1</bitWidth>
            </field>
            <field>
              <name>TYPECEVT1IE</name>
              <bitOffset>14</bitOffset>
              <bitWidth>1</bitWidth>
            </field>
            <field>
              <name>TYPECEVT2IE</name>
              <bitOffset>15</bitOffset>
              <bitWidth>1</bitWidth>
            </field>
            <field>
              <name>FRSEVTIE</name>
              <bitOffset>20</bitOffset>
              <bitWidth>1</bitWidth>
            </field>
          </fields>
        </register>
        <register>
          <name>SR</name>
          <addressOffset>0x14</addressOffset>
          <size>0x20</size>
          <fields>
            <field>
              <name>TXIS</name>
              <bitOffset>0</bitOffset>
              <bitWidth>1</bitWidth>
            </field>
            <field>
              <name>TXMSGDISC</name>
              <bitOffset>1</bitOffset>
              <bitWidth>1</bitWidth>
            </field>
            <field>
              <name>TXMSGSENT</name>
              <bitOffset>2</bitOffset>
              <bitWidth>1</bitWidth>
            </field>
            <field>
              <name>TXMSGABT</name>
              <bitOffset>3</bitOffset>
              <bitWidth>1</bitWidth>
            </field>
            <field>
              <name>HRSTDISC</name>
              <bitOffset>4</bitOffset>
              <bitWidth>1</bitWidth>
            </field>
            <field>
              <name>HRSTSENT</name>
              <bitOffset>5</bitOffset>
              <bitWidth>1</bitWidth>
            </field>
            <field>
              <name>TXUND</name>
              <bitOffset>6</bitOffset>
              <bitWidth>1</bitWidth>
            </field>
            <field>
              <name>RXNE</name>
              <bitOffset>8</bitOffset>
              <bitWidth>1</bitWidth>
            </field>
            <field>
              <name>RXORDDET</name>
              <bitOffset>9</bitOffset>
              <bitWidth>1</bitWidth>
            </field>
            <field>
              <name>RXHRSTDET</name>
              <bitOffset>10</bitOffset>
              <bitWidth>1</bitWidth>
            </field>
            <field>
              <name>RXOVR</name>
              <bitOffset>11</bitOffset>
              <bitWidth>1</bitWidth>
            </field>
            <field>
              <name>RXMSGEND</name>
              <bitOffset>12</bitOffset>
              <bitWidth>1</bitWidth>
            </field>
            <field>
              <name>RXERR</name>
              <bitOffset>13</bitOffset>
              <bitWidth>1</bitWidth>
            </field>
            <field>
              <name>TYPECEVT1</name>
              <bitOffset>14</bitOffset>
              <bitWidth>1</bitWidth>
            </field>
            <field>
              <name>TYPECEVT2</name>
              <bitOffset>15</bitOffset>
              <bitWidth>1</bitWidth>
            </field>
            <field>
              <name>TYPEC_VSTATE_CC1</name>
              <bitOffset>16</bitOffset>
              <bitWidth>2</bitWidth>
            </field>
            <field>
              <name>TYPEC_VSTATE_CC2</name>
              <bitOffset>18</bitOffset>
              <bitWidth>2</bitWidth>
            </field>
            <field>
              <name>FRSEVT</name>
              <bitOffset>20</bitOffset>
              <bitWidth>1</bitWidth>
            </field>
          </fields>
        </register>
        <register>
          <name>ICR</name>
          <addressOffset>0x18</addressOffset>
          <size>0x20</size>
          <fields>
            <field>
              <name>TXMSGDISCCF</name>
              <bitOffset>1</bitOffset>
              <bitWidth>1</bitWidth>
            </field>
            <field>
              <name>TXMSGSENTCF</name>
              <bitOffset>2</bitOffset>
              <bitWidth>1</bitWidth>
            </field>
            <field>
              <name>TXMSGABTCF</name>
              <bitOffset>3</bitOffset>
              <bitWidth>1</bitWidth>
            </field>
            <field>
              <name>HRSTDISCCF</name>
              <bitOffset>4</bitOffset>
              <bitWidth>1</bitWidth>
            </field>
            <field>
              <name>HRSTSENTCF</name>
              <bitOffset>5</bitOffset>
              <bitWidth>1</bitWidth>
            </field>
            <field>
              <name>TXUNDCF</name>
              <bitOffset>6</bitOffset>
              <bitWidth>1</bitWidth>
            </field>
            <field>
              <name>RXORDDETCF</name>
              <bitOffset>9</bitOffset>
              <bitWidth>1</bitWidth>
            </field>
            <field>
              <name>RXHRSTDETCF</name>
              <bitOffset>10</bitOffset>
              <bitWidth>1</bitWidth>
            </field>
            <field>
              <name>RXOVRCF</name>
              <bitOffset>11</bitOffset>
              <bitWidth>1</bitWidth>
            </field>
            <field>
              <name>RXMSGENDCF</name>
              <bitOffset>12</bitOffset>
              <bitWidth>1</bitWidth>
            </field>
            <field>
              <name>TYPECEVT1CF</name>
              <bitOffset>14</bitOffset>
              <bitWidth>1</bitWidth>
            </field>
            <field>
              <name>TYPECEVT2CF</name>
              <bitOffset>15</bitOffset>
              <bitWidth>1</bitWidth>
            </field>
            <field>
              <name>FRSEVTCF</name>
              <bitOffset>20</bitOffset>
              <bitWidth>1</bitWidth>
            </field>
          </fields>
        </register>
        <register>
          <name>TX_ORDSET</name>
          <addressOffset>0x1c</addressOffset>
          <size>0x20</size>
          <fields>
            <field>
              <name>TXORDSET</name>
              <bitOffset>0</bitOffset>
              <bitWidth>20</bitWidth>
            </field>
          </fields>
        </register>
        <register>
          <name>TX_PAYSZ</name>
          <addressOffset>0x20</addressOffset>
          <size>0x20</size>
          <fields>
            <field>
              <name>TXPAYSZ</name>
              <bitOffset>0</bitOffset>
              <bitWidth>10</bitWidth>
            </field>
          </fields>
        </register>
        <register>
          <name>TXDR</name>
          <addressOffset>0x24</addressOffset>
          <size>0x20</size>
          <fields>
            <field>
              <name>TXDATA</name>
              <bitOffset>0</bitOffset>
              <bitWidth>8</bitWidth>
            </field>
          </fields>
        </register>
        <register>
          <name>RX_ORDSET</name>
          <addressOffset>0x28</addressOffset>
          <size>0x20</size>
          <fields>
            <field>
              <name>RXORDSET</name>
              <bitOffset>0</bitOffset>
              <bitWidth>3</bitWidth>
            </field>
            <field>
              <name>RXSOP3OF4</name>
              <bitOffset>3</bitOffset>
              <bitWidth>1</bitWidth>
            </field>
            <field>
              <name>RXSOPKINVALID</name>
              <bitOffset>4</bitOffset>
              <bitWidth>3</bitWidth>
            </field>
          </fields>
        </register>
        <register>
          <name>RX_PAYSZ</name>
          <addressOffset>0x2c</addressOffset>
          <size>0x20</size>
          <fields>
            <field>
              <name>RXPAYSZ</name>
              <bitOffset>0</bitOffset>
              <bitWidth>10</bitWidth>
            </field>
          </fields>
        </register>
        <register>
          <name>RXDR</name>
          <addressOffset>0x30</addressOffset>
          <size>0x20</size>
          <fields>
            <field>
              <name>RXDATA</name>
              <bitOffset>0</bitOffset>
              <bitWidth>8</bitWidth>
            </field>
          </fields>
        </register>
        <register>
          <name>RX_ORDEXT1</name>
          <addressOffset>0x34</addressOffset>
          <size>0x20</size>
          <fields>
            <field>
              <name>RXSOPX1</name>
              <bitOffset>0</bitOffset>
              <bitWidth>20</bitWidth>
            </field>
          </fields>
        </register>
        <register>
          <name>RX_ORDEXT2</name>
          <addressOffset>0x38</addressOffset>
          <size>0x20</size>
          <fields>
            <field>
              <name>RXSOPX2</name>
              <bitOffset>0</bitOffset>
              <bitWidth>20</bitWidth>
            </field>
          </fields>
        </register>
      </registers>
    </peripheral>
    <peripheral>
      <name>SYSCFG</name>
      <baseAddress>0x40010000</baseAddress>
      <registers>
        <register>
          <name>MEMRMP</name>
          <addressOffset>0x0</addressOffset>
          <size>0x20</size>
          <fields>
            <field>
              <name>MEM_MODE</name>
              <bitOffset>0</bitOffset>
              <bitWidth>3</bitWidth>
            </field>
            <field>
              <name>FB_MODE</name>
              <bitOffset>8</bitOffset>
              <bitWidth>1</bitWidth>
            </field>
          </fields>
        </register>
        <register>
          <name>CFGR1</name>
          <addressOffset>0x4</addressOffset>
          <size>0x20</size>
          <fields>
            <field>
              <name>BOOSTEN</name>
              <bitOffset>8</bitOffset>
              <bitWidth>1</bitWidth>
            </field>
            <field>
              <name>ANASWVDD</name>
              <bitOffset>9</bitOffset>
              <bitWidth>1</bitWidth>
            </field>
            <field>
              <name>I2C_PB6_FMP</name>
              <bitOffset>16</bitOffset>
              <bitWidth>1</bitWidth>
            </field>
            <field>
              <name>I2C_PB7_FMP</name>
              <bitOffset>17</bitOffset>
              <bitWidth>1</bitWidth>
            </field>
            <field>
              <name>I2C_PB8_FMP</name>
              <bitOffset>18</bitOffset>
              <bitWidth>1</bitWidth>
            </field>
            <field>
              <name>I2C_PB9_FMP</name>
              <bitOffset>19</bitOffset>
              <bitWidth>1</bitWidth>
            </field>
            <field>
              <name>I2C1_FMP</name>
              <bitOffset>20</bitOffset>
              <bitWidth>1</bitWidth>
            </field>
            <field>
              <name>I2C2_FMP</name>
              <bitOffset>21</bitOffset>
              <bitWidth>1</bitWidth>
            </field>
            <field>
              <name>I2C3_FMP</name>
              <bitOffset>22</bitOffset>
              <bitWidth>1</bitWidth>
            </field>
            <field>
              <name>I2C4_FMP</name>
              <bitOffset>23</bitOffset>
              <bitWidth>1</bitWidth>
            </field>
          </fields>
        </register>
        <register>
          <name>EXTICR.0</name>
          <addressOffset>0x8</addressOffset>
          <size>0x20</size>
          <fields>
            <field>
              <name>EXTI0</name>
              <bitOffset>0</bitOffset>
              <bitWidth>3</bitWidth>
            </field>
            <field>
              <name>EXTI1</name>
              <bitOffset>4</bitOffset>
              <bitWidth>3</bitWidth>
            </field>
            <field>
              <name>EXTI2</name>
              <bitOffset>8</bitOffset>
              <bitWidth>3</bitWidth>
            </field>
            <field>
              <name>EXTI3</name>
              <bitOffset>12</bitOffset>
              <bitWidth>3</bitWidth>
            </field>
          </fields>
        </register>
        <register>
          <name>EXTICR.1</name>
          <addressOffset>0xc</addressOffset>
          <size>0x20</size>
          <fields>
            <field>
              <name>EXTI4</name>
              <bitOffset>0</bitOffset>
              <bitWidth>3</bitWidth>
            </field>
            <field>
              <name>EXTI5</name>
              <bitOffset>4</bitOffset>
              <bitWidth>3</bitWidth>
            </field>
            <field>
              <name>EXTI6</name>
              <bitOffset>8</bitOffset>
              <bitWidth>3</bitWidth>
            </field>
            <field>
              <name>EXTI7</name>
              <bitOffset>12</bitOffset>
              <bitWidth>3</bitWidth>
            </field>
          </fields>
        </register>
        <register>
          <name>EXTICR.2</name>
          <addressOffset>0x10</addressOffset>
          <size>0x20</size>
          <fields>
            <field>
              <name>EXTI8</name>
              <bitOffset>0</bitOffset>
              <bitWidth>3</bitWidth>
            </field>
            <field>
              <name>EXTI9</name>
              <bitOffset>4</bitOffset>
              <bitWidth>3</bitWidth>
            </field>
            <field>
              <name>EXTI10</name>
              <bitOffset>8</bitOffset>
              <bitWidth>3</bitWidth>
            </field>
            <field>
              <name>EXTI11</name>
              <bitOffset>12</bitOffset>
              <bitWidth>3</bitWidth>
            </field>
          </fields>
        </register>
        <register>
          <name>EXTICR.3</name>
          <addressOffset>0x14</addressOffset>
          <size>0x20</size>
          <fields>
            <field>
              <name>EXTI12</name>
              <bitOffset>0</bitOffset>
              <bitWidth>3</bitWidth>
            </field>
            <field>
              <name>EXTI13</name>
              <bitOffset>4</bitOffset>
              <bitWidth>3</bitWidth>
            </field>
            <field>
              <name>EXTI14</name>
              <bitOffset>8</bitOffset>
              <bitWidth>3</bitWidth>
            </field>
            <field>
              <name>EXTI15</name>
              <bitOffset>12</bitOffset>
              <bitWidth>3</bitWidth>
            </field>
          </fields>
        </register>
        <register>
          <name>SCSR</name>
          <addressOffset>0x18</addressOffset>
          <size>0x20</size>
          <fields>
            <field>
              <name>CCMER</name>
              <bitOffset>0</bitOffset>
              <bitWidth>1</bitWidth>
            </field>
            <field>
              <name>CCMBSY</name>
              <bitOffset>1</bitOffset>
              <bitWidth>1</bitWidth>
            </field>
          </fields>
        </register>
        <register>
          <name>CFGR2</name>
          <addressOffset>0x1c</addressOffset>
          <size>0x20</size>
          <fields>
            <field>
              <name>CLL</name>
              <bitOffset>0</bitOffset>
              <bitWidth>1</bitWidth>
            </field>
            <field>
              <name>SPL</name>
              <bitOffset>1</bitOffset>
              <bitWidth>1</bitWidth>
            </field>
            <field>
              <name>PVDL</name>
              <bitOffset>2</bitOffset>
              <bitWidth>1</bitWidth>
            </field>
            <field>
              <name>ECCL</name>
              <bitOffset>3</bitOffset>
              <bitWidth>1</bitWidth>
            </field>
            <field>
              <name>SPF</name>
              <bitOffset>8</bitOffset>
              <bitWidth>1</bitWidth>
            </field>
          </fields>
        </register>
        <register>
          <name>SWPR</name>
          <addressOffset>0x20</addressOffset>
          <size>0x20</size>
          <fields>
            <field>
              <name>PAGE0</name>
              <bitOffset>0</bitOffset>
              <bitWidth>1</bitWidth>
            </field>
            <field>
              <name>PAGE1</name>
              <bitOffset>1</bitOffset>
              <bitWidth>1</bitWidth>
            </field>
            <field>
              <name>PAGE2</name>
              <bitOffset>2</bitOffset>
              <bitWidth>1</bitWidth>
            </field>
            <field>
              <name>PAGE3</name>
              <bitOffset>3</bitOffset>
              <bitWidth>1</bitWidth>
            </field>
            <field>
              <name>PAGE4</name>
              <bitOffset>4</bitOffset>
              <bitWidth>1</bitWidth>
            </field>
            <field>
              <name>PAGE5</name>
              <bitOffset>5</bitOffset>
              <bitWidth>1</bitWidth>
            </field>
            <field>
              <name>PAGE6</name>
              <bitOffset>6</bitOffset>
              <bitWidth>1</bitWidth>
            </field>
            <field>
              <name>PAGE7</name>
              <bitOffset>7</bitOffset>
              <bitWidth>1</bitWidth>
            </field>
            <field>
              <name>PAGE8</name>
              <bitOffset>8</bitOffset>
              <bitWidth>1</bitWidth>
            </field>
            <field>
              <name>PAGE9</name>
              <bitOffset>9</bitOffset>
              <bitWidth>1</bitWidth>
            </field>
            <field>
              <name>PAGE10</name>
              <bitOffset>10</bitOffset>
              <bitWidth>1</bitWidth>
            </field>
            <field>
              <name>PAGE11</name>
              <bitOffset>11</bitOffset>
              <bitWidth>1</bitWidth>
            </field>
            <field>
              <name>PAGE12</name>
              <bitOffset>12</bitOffset>
              <bitWidth>1</bitWidth>
            </field>
            <field>
              <name>PAGE13</name>
              <bitOffset>13</bitOffset>
              <bitWidth>1</bitWidth>
            </field>
            <field>
              <name>PAGE14</name>
              <bitOffset>14</bitOffset>
              <bitWidth>1</bitWidth>
            </field>
            <field>
              <name>PAGE15</name>
              <bitOffset>15</bitOffset>
              <bitWidth>1</bitWidth>
            </field>
            <field>
              <name>PAGE16</name>
              <bitOffset>16</bitOffset>
              <bitWidth>1</bitWidth>
            </field>
            <field>
              <name>PAGE17</name>
              <bitOffset>17</bitOffset>
              <bitWidth>1</bitWidth>
            </field>
            <field>
              <name>PAGE18</name>
              <bitOffset>18</bitOffset>
              <bitWidth>1</bitWidth>
            </field>
            <field>
              <name>PAGE19</name>
              <bitOffset>19</bitOffset>
              <bitWidth>1</bitWidth>
            </field>
            <field>
              <name>PAGE20</name>
              <bitOffset>20</bitOffset>
              <bitWidth>1</bitWidth>
            </field>
            <field>
              <name>PAGE21</name>
              <bitOffset>21</bitOffset>
              <bitWidth>1</bitWidth>
            </field>
            <field>
              <name>PAGE22</name>
              <bitOffset>22</bitOffset>
              <bitWidth>1</bitWidth>
            </field>
            <field>
              <name>PAGE23</name>
              <bitOffset>23</bitOffset>
              <bitWidth>1</bitWidth>
            </field>
            <field>
              <name>PAGE24</name>
              <bitOffset>24</bitOffset>
              <bitWidth>1</bitWidth>
            </field>
            <field>
              <name>PAGE25</name>
              <bitOffset>25</bitOffset>
              <bitWidth>1</bitWidth>
            </field>
            <field>
              <name>PAGE26</name>
              <bitOffset>26</bitOffset>
              <bitWidth>1</bitWidth>
            </field>
            <field>
              <name>PAGE27</name>
              <bitOffset>27</bitOffset>
              <bitWidth>1</bitWidth>
            </field>
            <field>
              <name>PAGE28</name>
              <bitOffset>28</bitOffset>
              <bitWidth>1</bitWidth>
            </field>
            <field>
              <name>PAGE29</name>
              <bitOffset>29</bitOffset>
              <bitWidth>1</bitWidth>
            </field>
            <field>
              <name>PAGE30</name>
              <bitOffset>30</bitOffset>
              <bitWidth>1</bitWidth>
            </field>
            <field>
              <name>PAGE31</name>
              <bitOffset>31</bitOffset>
              <bitWidth>1</bitWidth>
            </field>
          </fields>
        </register>
        <register>
          <name>SKR</name>
          <addressOffset>0x24</addressOffset>
          <size>0x20</size>
          <fields>
            <field>
              <name>KEY</name>
              <bitOffset>0</bitOffset>
              <bitWidth>8</bitWidth>
            </field>
          </fields>
        </register>
      </registers>
    </peripheral>
    <peripheral>
      <name>VREFBUF</name>
      <baseAddress>0x40010030</baseAddress>
      <registers>
        <register>
          <name>CSR</name>
          <addressOffset>0x0</addressOffset>
          <size>0x20</size>
          <fields>
            <field>
              <name>ENVR</name>
              <bitOffset>0</bitOffset>
              <bitWidth>1</bitWidth>
            </field>
            <field>
              <name>HIZ</name>
              <bitOffset>1</bitOffset>
              <bitWidth>1</bitWidth>
            </field>
            <field>
              <name>VRR</name>
              <bitOffset>3</bitOffset>
              <bitWidth>1</bitWidth>
            </field>
            <field>
              <name>VRS</name>
              <bitOffset>4</bitOffset>
              <bitWidth>2</bitWidth>
            </field>
          </fields>
        </register>
        <register>
          <name>CCR</name>
          <addressOffset>0x4</addressOffset>
          <size>0x20</size>
          <fields>
            <field>
              <name>TRIM</name>
              <bitOffset>0</bitOffset>
              <bitWidth>6</bitWidth>
            </field>
          </fields>
        </register>
      </registers>
    </peripheral>
    <peripheral>
      <name>COMP1</name>
      <baseAddress>0x40010200</baseAddress>
      <registers>
        <register>
          <name>CSR</name>
          <addressOffset>0x0</addressOffset>
          <size>0x20</size>
          <fields>
            <field>
              <name>EN</name>
              <bitOffset>0</bitOffset>
              <bitWidth>1</bitWidth>
            </field>
            <field>
              <name>INMSEL</name>
              <bitOffset>4</bitOffset>
              <bitWidth>4</bitWidth>
            </field>
            <field>
              <name>INPSEL</name>
              <bitOffset>8</bitOffset>
              <bitWidth>1</bitWidth>
            </field>
            <field>
              <name>POLARITY</name>
              <bitOffset>15</bitOffset>
              <bitWidth>1</bitWidth>
            </field>
            <field>
              <name>HYST</name>
              <bitOffset>16</bitOffset>
              <bitWidth>3</bitWidth>
            </field>
            <field>
              <name>BLANKING</name>
              <bitOffset>19</bitOffset>
              <bitWidth>3</bitWidth>
            </field>
            <field>
              <name>BRGEN</name>
              <bitOffset>22</bitOffset>
              <bitWidth>1</bitWidth>
            </field>
            <field>
              <name>SCALEN</name>
              <bitOffset>23</bitOffset>
              <bitWidth>1</bitWidth>
            </field>
            <field>
              <name>VALUE</name>
              <bitOffset>30</bitOffset>
              <bitWidth>1</bitWidth>
            </field>
            <field>
              <name>LOCK</name>
              <bitOffset>31</bitOffset>
              <bitWidth>1</bitWidth>
            </field>
          </fields>
        </register>
      </registers>
    </peripheral>
    <peripheral>
      <name>COMP2</name>
      <baseAddress>0x40010204</baseAddress>
      <registers>
        <register>
          <name>CSR</name>
          <addressOffset>0x0</addressOffset>
          <size>0x20</size>
          <fields>
            <field>
              <name>EN</name>
              <bitOffset>0</bitOffset>
              <bitWidth>1</bitWidth>
            </field>
            <field>
              <name>INMSEL</name>
              <bitOffset>4</bitOffset>
              <bitWidth>4</bitWidth>
            </field>
            <field>
              <name>INPSEL</name>
              <bitOffset>8</bitOffset>
              <bitWidth>1</bitWidth>
            </field>
            <field>
              <name>POLARITY</name>
              <bitOffset>15</bitOffset>
              <bitWidth>1</bitWidth>
            </field>
            <field>
              <name>HYST</name>
              <bitOffset>16</bitOffset>
              <bitWidth>3</bitWidth>
            </field>
            <field>
              <name>BLANKING</name>
              <bitOffset>19</bitOffset>
              <bitWidth>3</bitWidth>
            </field>
            <field>
              <name>BRGEN</name>
              <bitOffset>22</bitOffset>
              <bitWidth>1</bitWidth>
            </field>
            <field>
              <name>SCALEN</name>
              <bitOffset>23</bitOffset>
              <bitWidth>1</bitWidth>
            </field>
            <field>
              <name>VALUE</name>
              <bitOffset>30</bitOffset>
              <bitWidth>1</bitWidth>
            </field>
            <field>
              <name>LOCK</name>
              <bitOffset>31</bitOffset>
              <bitWidth>1</bitWidth>
            </field>
          </fields>
        </register>
      </registers>
    </peripheral>
    <peripheral>
      <name>COMP3</name>
      <baseAddress>0x40010208</baseAddress>
      <registers>
        <register>
          <name>CSR</name>
          <addressOffset>0x0</addressOffset>
          <size>0x20</size>
          <fields>
            <field>
              <name>EN</name>
              <bitOffset>0</bitOffset>
              <bitWidth>1</bitWidth>
            </field>
            <field>
              <name>INMSEL</name>
              <bitOffset>4</bitOffset>
              <bitWidth>4</bitWidth>
            </field>
            <field>
              <name>INPSEL</name>
              <bitOffset>8</bitOffset>
              <bitWidth>1</bitWidth>
            </field>
            <field>
              <name>POLARITY</name>
              <bitOffset>15</bitOffset>
              <bitWidth>1</bitWidth>
            </field>
            <field>
              <name>HYST</name>
              <bitOffset>16</bitOffset>
              <bitWidth>3</bitWidth>
            </field>
            <field>
              <name>BLANKING</name>
              <bitOffset>19</bitOffset>
              <bitWidth>3</bitWidth>
            </field>
            <field>
              <name>BRGEN</name>
              <bitOffset>22</bitOffset>
              <bitWidth>1</bitWidth>
            </field>
            <field>
              <name>SCALEN</name>
              <bitOffset>23</bitOffset>
              <bitWidth>1</bitWidth>
            </field>
            <field>
              <name>VALUE</name>
              <bitOffset>30</bitOffset>
              <bitWidth>1</bitWidth>
            </field>
            <field>
              <name>LOCK</name>
              <bitOffset>31</bitOffset>
              <bitWidth>1</bitWidth>
            </field>
          </fields>
        </register>
      </registers>
    </peripheral>
    <peripheral>
      <name>COMP4</name>
      <baseAddress>0x4001020c</baseAddress>
      <registers>
        <register>
          <name>CSR</name>
          <addressOffset>0x0</addressOffset>
          <size>0x20</size>
          <fields>
            <field>
              <name>EN</name>
              <bitOffset>0</bitOffset>
              <bitWidth>1</bitWidth>
            </field>
            <field>
              <name>INMSEL</name>
              <bitOffset>4</bitOffset>
              <bitWidth>4</bitWidth>
            </field>
            <field>
              <name>INPSEL</name>
              <bitOffset>8</bitOffset>
              <bitWidth>1</bitWidth>
            </field>
            <field>
              <name>POLARITY</name>
              <bitOffset>15</bitOffset>
              <bitWidth>1</bitWidth>
            </field>
            <field>
              <name>HYST</name>
              <bitOffset>16</bitOffset>
              <bitWidth>3</bitWidth>
            </field>
            <field>
              <name>BLANKING</name>
              <bitOffset>19</bitOffset>
              <bitWidth>3</bitWidth>
            </field>
            <field>
              <name>BRGEN</name>
              <bitOffset>22</bitOffset>
              <bitWidth>1</bitWidth>
            </field>
            <field>
              <name>SCALEN</name>
              <bitOffset>23</bitOffset>
              <bitWidth>1</bitWidth>
            </field>
            <field>
              <name>VALUE</name>
              <bitOffset>30</bitOffset>
              <bitWidth>1</bitWidth>
            </field>
            <field>
              <name>LOCK</name>
              <bitOffset>31</bitOffset>
              <bitWidth>1</bitWidth>
            </field>
          </fields>
        </register>
      </registers>
    </peripheral>
    <peripheral>
      <name>OPAMP</name>
      <baseAddress>0x40010300</baseAddress>
      <registers>
        <register>
          <name>CSR</name>
          <addressOffset>0x0</addressOffset>
          <size>0x20</size>
          <fields>
            <field>
              <name>OPAMPxEN</name>
              <bitOffset>0</bitOffset>
              <bitWidth>1</bitWidth>
            </field>
            <field>
              <name>FORCEVP</name>
              <bitOffset>1</bitOffset>
              <bitWidth>1</bitWidth>
            </field>
            <field>
              <name>VPSEL</name>
              <bitOffset>2</bitOffset>
              <bitWidth>2</bitWidth>
            </field>
            <field>
              <name>USERTRIM</name>
              <bitOffset>4</bitOffset>
              <bitWidth>1</bitWidth>
            </field>
            <field>
              <name>VMSEL</name>
              <bitOffset>5</bitOffset>
              <bitWidth>2</bitWidth>
            </field>
            <field>
              <name>HIGHSPEEDEN</name>
              <bitOffset>7</bitOffset>
              <bitWidth>1</bitWidth>
            </field>
            <field>
              <name>OPAMPINTEN</name>
              <bitOffset>8</bitOffset>
              <bitWidth>1</bitWidth>
            </field>
            <field>
              <name>CALON</name>
              <bitOffset>11</bitOffset>
              <bitWidth>1</bitWidth>
            </field>
            <field>
              <name>CALSEL</name>
              <bitOffset>12</bitOffset>
              <bitWidth>2</bitWidth>
            </field>
            <field>
              <name>PGGAIN</name>
              <bitOffset>14</bitOffset>
              <bitWidth>5</bitWidth>
            </field>
            <field>
              <name>TRIMOFFSETP</name>
              <bitOffset>19</bitOffset>
              <bitWidth>5</bitWidth>
            </field>
            <field>
              <name>TRIMOFFSETN</name>
              <bitOffset>24</bitOffset>
              <bitWidth>5</bitWidth>
            </field>
            <field>
              <name>OUTCAL</name>
              <bitOffset>30</bitOffset>
              <bitWidth>1</bitWidth>
            </field>
            <field>
              <name>LOCK</name>
              <bitOffset>31</bitOffset>
              <bitWidth>1</bitWidth>
            </field>
          </fields>
        </register>
        <register>
          <name>TCMR</name>
          <addressOffset>0x18</addressOffset>
          <size>0x20</size>
          <fields>
            <field>
              <name>VMSSEL</name>
              <bitOffset>0</bitOffset>
              <bitWidth>1</bitWidth>
            </field>
            <field>
              <name>VPSSEL</name>
              <bitOffset>1</bitOffset>
              <bitWidth>2</bitWidth>
            </field>
            <field>
              <name>T1CMEN</name>
              <bitOffset>3</bitOffset>
              <bitWidth>1</bitWidth>
            </field>
            <field>
              <name>T8CMEN</name>
              <bitOffset>4</bitOffset>
              <bitWidth>1</bitWidth>
            </field>
            <field>
              <name>T20CMEN</name>
              <bitOffset>5</bitOffset>
              <bitWidth>1</bitWidth>
            </field>
            <field>
              <name>LOCK</name>
              <bitOffset>31</bitOffset>
              <bitWidth>1</bitWidth>
            </field>
          </fields>
        </register>
      </registers>
    </peripheral>
    <peripheral>
      <name>OPAMP1</name>
      <baseAddress>0x40010300</baseAddress>
      <registers>
        <register>
          <name>CSR</name>
          <addressOffset>0x0</addressOffset>
          <size>0x20</size>
          <fields>
            <field>
              <name>OPAMPxEN</name>
              <bitOffset>0</bitOffset>
              <bitWidth>1</bitWidth>
            </field>
            <field>
              <name>FORCEVP</name>
              <bitOffset>1</bitOffset>
              <bitWidth>1</bitWidth>
            </field>
            <field>
              <name>VPSEL</name>
              <bitOffset>2</bitOffset>
              <bitWidth>2</bitWidth>
            </field>
            <field>
              <name>USERTRIM</name>
              <bitOffset>4</bitOffset>
              <bitWidth>1</bitWidth>
            </field>
            <field>
              <name>VMSEL</name>
              <bitOffset>5</bitOffset>
              <bitWidth>2</bitWidth>
            </field>
            <field>
              <name>HIGHSPEEDEN</name>
              <bitOffset>7</bitOffset>
              <bitWidth>1</bitWidth>
            </field>
            <field>
              <name>OPAMPINTEN</name>
              <bitOffset>8</bitOffset>
              <bitWidth>1</bitWidth>
            </field>
            <field>
              <name>CALON</name>
              <bitOffset>11</bitOffset>
              <bitWidth>1</bitWidth>
            </field>
            <field>
              <name>CALSEL</name>
              <bitOffset>12</bitOffset>
              <bitWidth>2</bitWidth>
            </field>
            <field>
              <name>PGGAIN</name>
              <bitOffset>14</bitOffset>
              <bitWidth>5</bitWidth>
            </field>
            <field>
              <name>TRIMOFFSETP</name>
              <bitOffset>19</bitOffset>
              <bitWidth>5</bitWidth>
            </field>
            <field>
              <name>TRIMOFFSETN</name>
              <bitOffset>24</bitOffset>
              <bitWidth>5</bitWidth>
            </field>
            <field>
              <name>OUTCAL</name>
              <bitOffset>30</bitOffset>
              <bitWidth>1</bitWidth>
            </field>
            <field>
              <name>LOCK</name>
              <bitOffset>31</bitOffset>
              <bitWidth>1</bitWidth>
            </field>
          </fields>
        </register>
        <register>
          <name>TCMR</name>
          <addressOffset>0x18</addressOffset>
          <size>0x20</size>
          <fields>
            <field>
              <name>VMSSEL</name>
              <bitOffset>0</bitOffset>
              <bitWidth>1</bitWidth>
            </field>
            <field>
              <name>VPSSEL</name>
              <bitOffset>1</bitOffset>
              <bitWidth>2</bitWidth>
            </field>
            <field>
              <name>T1CMEN</name>
              <bitOffset>3</bitOffset>
              <bitWidth>1</bitWidth>
            </field>
            <field>
              <name>T8CMEN</name>
              <bitOffset>4</bitOffset>
              <bitWidth>1</bitWidth>
            </field>
            <field>
              <name>T20CMEN</name>
              <bitOffset>5</bitOffset>
              <bitWidth>1</bitWidth>
            </field>
            <field>
              <name>LOCK</name>
              <bitOffset>31</bitOffset>
              <bitWidth>1</bitWidth>
            </field>
          </fields>
        </register>
      </registers>
    </peripheral>
    <peripheral>
      <name>OPAMP2</name>
      <baseAddress>0x40010304</baseAddress>
      <registers>
        <register>
          <name>CSR</name>
          <addressOffset>0x0</addressOffset>
          <size>0x20</size>
          <fields>
            <field>
              <name>OPAMPxEN</name>
              <bitOffset>0</bitOffset>
              <bitWidth>1</bitWidth>
            </field>
            <field>
              <name>FORCEVP</name>
              <bitOffset>1</bitOffset>
              <bitWidth>1</bitWidth>
            </field>
            <field>
              <name>VPSEL</name>
              <bitOffset>2</bitOffset>
              <bitWidth>2</bitWidth>
            </field>
            <field>
              <name>USERTRIM</name>
              <bitOffset>4</bitOffset>
              <bitWidth>1</bitWidth>
            </field>
            <field>
              <name>VMSEL</name>
              <bitOffset>5</bitOffset>
              <bitWidth>2</bitWidth>
            </field>
            <field>
              <name>HIGHSPEEDEN</name>
              <bitOffset>7</bitOffset>
              <bitWidth>1</bitWidth>
            </field>
            <field>
              <name>OPAMPINTEN</name>
              <bitOffset>8</bitOffset>
              <bitWidth>1</bitWidth>
            </field>
            <field>
              <name>CALON</name>
              <bitOffset>11</bitOffset>
              <bitWidth>1</bitWidth>
            </field>
            <field>
              <name>CALSEL</name>
              <bitOffset>12</bitOffset>
              <bitWidth>2</bitWidth>
            </field>
            <field>
              <name>PGGAIN</name>
              <bitOffset>14</bitOffset>
              <bitWidth>5</bitWidth>
            </field>
            <field>
              <name>TRIMOFFSETP</name>
              <bitOffset>19</bitOffset>
              <bitWidth>5</bitWidth>
            </field>
            <field>
              <name>TRIMOFFSETN</name>
              <bitOffset>24</bitOffset>
              <bitWidth>5</bitWidth>
            </field>
            <field>
              <name>OUTCAL</name>
              <bitOffset>30</bitOffset>
              <bitWidth>1</bitWidth>
            </field>
            <field>
              <name>LOCK</name>
              <bitOffset>31</bitOffset>
              <bitWidth>1</bitWidth>
            </field>
          </fields>
        </register>
        <register>
          <name>TCMR</name>
          <addressOffset>0x18</addressOffset>
          <size>0x20</size>
          <fields>
            <field>
              <name>VMSSEL</name>
              <bitOffset>0</bitOffset>
              <bitWidth>1</bitWidth>
            </field>
            <field>
              <name>VPSSEL</name>
              <bitOffset>1</bitOffset>
              <bitWidth>2</bitWidth>
            </field>
            <field>
              <name>T1CMEN</name>
              <bitOffset>3</bitOffset>
              <bitWidth>1</bitWidth>
            </field>
            <field>
              <name>T8CMEN</name>
              <bitOffset>4</bitOffset>
              <bitWidth>1</bitWidth>
            </field>
            <field>
              <name>T20CMEN</name>
              <bitOffset>5</bitOffset>
              <bitWidth>1</bitWidth>
            </field>
            <field>
              <name>LOCK</name>
              <bitOffset>31</bitOffset>
              <bitWidth>1</bitWidth>
            </field>
          </fields>
        </register>
      </registers>
    </peripheral>
    <peripheral>
      <name>OPAMP3</name>
      <baseAddress>0x40010308</baseAddress>
      <registers>
        <register>
          <name>CSR</name>
          <addressOffset>0x0</addressOffset>
          <size>0x20</size>
          <fields>
            <field>
              <name>OPAMPxEN</name>
              <bitOffset>0</bitOffset>
              <bitWidth>1</bitWidth>
            </field>
            <field>
              <name>FORCEVP</name>
              <bitOffset>1</bitOffset>
              <bitWidth>1</bitWidth>
            </field>
            <field>
              <name>VPSEL</name>
              <bitOffset>2</bitOffset>
              <bitWidth>2</bitWidth>
            </field>
            <field>
              <name>USERTRIM</name>
              <bitOffset>4</bitOffset>
              <bitWidth>1</bitWidth>
            </field>
            <field>
              <name>VMSEL</name>
              <bitOffset>5</bitOffset>
              <bitWidth>2</bitWidth>
            </field>
            <field>
              <name>HIGHSPEEDEN</name>
              <bitOffset>7</bitOffset>
              <bitWidth>1</bitWidth>
            </field>
            <field>
              <name>OPAMPINTEN</name>
              <bitOffset>8</bitOffset>
              <bitWidth>1</bitWidth>
            </field>
            <field>
              <name>CALON</name>
              <bitOffset>11</bitOffset>
              <bitWidth>1</bitWidth>
            </field>
            <field>
              <name>CALSEL</name>
              <bitOffset>12</bitOffset>
              <bitWidth>2</bitWidth>
            </field>
            <field>
              <name>PGGAIN</name>
              <bitOffset>14</bitOffset>
              <bitWidth>5</bitWidth>
            </field>
            <field>
              <name>TRIMOFFSETP</name>
              <bitOffset>19</bitOffset>
              <bitWidth>5</bitWidth>
            </field>
            <field>
              <name>TRIMOFFSETN</name>
              <bitOffset>24</bitOffset>
              <bitWidth>5</bitWidth>
            </field>
            <field>
              <name>OUTCAL</name>
              <bitOffset>30</bitOffset>
              <bitWidth>1</bitWidth>
            </field>
            <field>
              <name>LOCK</name>
              <bitOffset>31</bitOffset>
              <bitWidth>1</bitWidth>
            </field>
          </fields>
        </register>
        <register>
          <name>TCMR</name>
          <addressOffset>0x18</addressOffset>
          <size>0x20</size>
          <fields>
            <field>
              <name>VMSSEL</name>
              <bitOffset>0</bitOffset>
              <bitWidth>1</bitWidth>
            </field>
            <field>
              <name>VPSSEL</name>
              <bitOffset>1</bitOffset>
              <bitWidth>2</bitWidth>
            </field>
            <field>
              <name>T1CMEN</name>
              <bitOffset>3</bitOffset>
              <bitWidth>1</bitWidth>
            </field>
            <field>
              <name>T8CMEN</name>
              <bitOffset>4</bitOffset>
              <bitWidth>1</bitWidth>
            </field>
            <field>
              <name>T20CMEN</name>
              <bitOffset>5</bitOffset>
              <bitWidth>1</bitWidth>
            </field>
            <field>
              <name>LOCK</name>
              <bitOffset>31</bitOffset>
              <bitWidth>1</bitWidth>
            </field>
          </fields>
        </register>
      </registers>
    </peripheral>
    <peripheral>
      <name>EXTI</name>
      <baseAddress>0x40010400</baseAddress>
      <registers>
        <register>
          <name>IMR1</name>
          <addressOffset>0x0</addressOffset>
          <size>0x20</size>
          <fields>
            <field>
              <name>IM0</name>
              <bitOffset>0</bitOffset>
              <bitWidth>1</bitWidth>
            </field>
            <field>
              <name>IM1</name>
              <bitOffset>1</bitOffset>
              <bitWidth>1</bitWidth>
            </field>
            <field>
              <name>IM2</name>
              <bitOffset>2</bitOffset>
              <bitWidth>1</bitWidth>
            </field>
            <field>
              <name>IM3</name>
              <bitOffset>3</bitOffset>
              <bitWidth>1</bitWidth>
            </field>
            <field>
              <name>IM4</name>
              <bitOffset>4</bitOffset>
              <bitWidth>1</bitWidth>
            </field>
            <field>
              <name>IM5</name>
              <bitOffset>5</bitOffset>
              <bitWidth>1</bitWidth>
            </field>
            <field>
              <name>IM6</name>
              <bitOffset>6</bitOffset>
              <bitWidth>1</bitWidth>
            </field>
            <field>
              <name>IM7</name>
              <bitOffset>7</bitOffset>
              <bitWidth>1</bitWidth>
            </field>
            <field>
              <name>IM8</name>
              <bitOffset>8</bitOffset>
              <bitWidth>1</bitWidth>
            </field>
            <field>
              <name>IM9</name>
              <bitOffset>9</bitOffset>
              <bitWidth>1</bitWidth>
            </field>
            <field>
              <name>IM10</name>
              <bitOffset>10</bitOffset>
              <bitWidth>1</bitWidth>
            </field>
            <field>
              <name>IM11</name>
              <bitOffset>11</bitOffset>
              <bitWidth>1</bitWidth>
            </field>
            <field>
              <name>IM12</name>
              <bitOffset>12</bitOffset>
              <bitWidth>1</bitWidth>
            </field>
            <field>
              <name>IM13</name>
              <bitOffset>13</bitOffset>
              <bitWidth>1</bitWidth>
            </field>
            <field>
              <name>IM14</name>
              <bitOffset>14</bitOffset>
              <bitWidth>1</bitWidth>
            </field>
            <field>
              <name>IM15</name>
              <bitOffset>15</bitOffset>
              <bitWidth>1</bitWidth>
            </field>
            <field>
              <name>IM16</name>
              <bitOffset>16</bitOffset>
              <bitWidth>1</bitWidth>
            </field>
            <field>
              <name>IM17</name>
              <bitOffset>17</bitOffset>
              <bitWidth>1</bitWidth>
            </field>
            <field>
              <name>IM18</name>
              <bitOffset>18</bitOffset>
              <bitWidth>1</bitWidth>
            </field>
            <field>
              <name>IM19</name>
              <bitOffset>19</bitOffset>
              <bitWidth>1</bitWidth>
            </field>
            <field>
              <name>IM20</name>
              <bitOffset>20</bitOffset>
              <bitWidth>1</bitWidth>
            </field>
            <field>
              <name>IM21</name>
              <bitOffset>21</bitOffset>
              <bitWidth>1</bitWidth>
            </field>
            <field>
              <name>IM22</name>
              <bitOffset>22</bitOffset>
              <bitWidth>1</bitWidth>
            </field>
            <field>
              <name>IM23</name>
              <bitOffset>23</bitOffset>
              <bitWidth>1</bitWidth>
            </field>
            <field>
              <name>IM24</name>
              <bitOffset>24</bitOffset>
              <bitWidth>1</bitWidth>
            </field>
            <field>
              <name>IM25</name>
              <bitOffset>25</bitOffset>
              <bitWidth>1</bitWidth>
            </field>
            <field>
              <name>IM26</name>
              <bitOffset>26</bitOffset>
              <bitWidth>1</bitWidth>
            </field>
            <field>
              <name>IM27</name>
              <bitOffset>27</bitOffset>
              <bitWidth>1</bitWidth>
            </field>
            <field>
              <name>IM28</name>
              <bitOffset>28</bitOffset>
              <bitWidth>1</bitWidth>
            </field>
            <field>
              <name>IM29</name>
              <bitOffset>29</bitOffset>
              <bitWidth>1</bitWidth>
            </field>
            <field>
              <name>IM30</name>
              <bitOffset>30</bitOffset>
              <bitWidth>1</bitWidth>
            </field>
          </fields>
        </register>
        <register>
          <name>EMR1</name>
          <addressOffset>0x4</addressOffset>
          <size>0x20</size>
          <fields>
            <field>
              <name>EM0</name>
              <bitOffset>0</bitOffset>
              <bitWidth>1</bitWidth>
            </field>
            <field>
              <name>EM1</name>
              <bitOffset>1</bitOffset>
              <bitWidth>1</bitWidth>
            </field>
            <field>
              <name>EM2</name>
              <bitOffset>2</bitOffset>
              <bitWidth>1</bitWidth>
            </field>
            <field>
              <name>EM3</name>
              <bitOffset>3</bitOffset>
              <bitWidth>1</bitWidth>
            </field>
            <field>
              <name>EM4</name>
              <bitOffset>4</bitOffset>
              <bitWidth>1</bitWidth>
            </field>
            <field>
              <name>EM5</name>
              <bitOffset>5</bitOffset>
              <bitWidth>1</bitWidth>
            </field>
            <field>
              <name>EM6</name>
              <bitOffset>6</bitOffset>
              <bitWidth>1</bitWidth>
            </field>
            <field>
              <name>EM7</name>
              <bitOffset>7</bitOffset>
              <bitWidth>1</bitWidth>
            </field>
            <field>
              <name>EM8</name>
              <bitOffset>8</bitOffset>
              <bitWidth>1</bitWidth>
            </field>
            <field>
              <name>EM9</name>
              <bitOffset>9</bitOffset>
              <bitWidth>1</bitWidth>
            </field>
            <field>
              <name>EM10</name>
              <bitOffset>10</bitOffset>
              <bitWidth>1</bitWidth>
            </field>
            <field>
              <name>EM11</name>
              <bitOffset>11</bitOffset>
              <bitWidth>1</bitWidth>
            </field>
            <field>
              <name>EM12</name>
              <bitOffset>12</bitOffset>
              <bitWidth>1</bitWidth>
            </field>
            <field>
              <name>EM13</name>
              <bitOffset>13</bitOffset>
              <bitWidth>1</bitWidth>
            </field>
            <field>
              <name>EM14</name>
              <bitOffset>14</bitOffset>
              <bitWidth>1</bitWidth>
            </field>
            <field>
              <name>EM15</name>
              <bitOffset>15</bitOffset>
              <bitWidth>1</bitWidth>
            </field>
            <field>
              <name>EM16</name>
              <bitOffset>16</bitOffset>
              <bitWidth>1</bitWidth>
            </field>
            <field>
              <name>EM17</name>
              <bitOffset>17</bitOffset>
              <bitWidth>1</bitWidth>
            </field>
            <field>
              <name>EM18</name>
              <bitOffset>18</bitOffset>
              <bitWidth>1</bitWidth>
            </field>
            <field>
              <name>EM19</name>
              <bitOffset>19</bitOffset>
              <bitWidth>1</bitWidth>
            </field>
            <field>
              <name>EM20</name>
              <bitOffset>20</bitOffset>
              <bitWidth>1</bitWidth>
            </field>
            <field>
              <name>EM21</name>
              <bitOffset>21</bitOffset>
              <bitWidth>1</bitWidth>
            </field>
            <field>
              <name>EM22</name>
              <bitOffset>22</bitOffset>
              <bitWidth>1</bitWidth>
            </field>
            <field>
              <name>EM23</name>
              <bitOffset>23</bitOffset>
              <bitWidth>1</bitWidth>
            </field>
            <field>
              <name>EM24</name>
              <bitOffset>24</bitOffset>
              <bitWidth>1</bitWidth>
            </field>
            <field>
              <name>EM25</name>
              <bitOffset>25</bitOffset>
              <bitWidth>1</bitWidth>
            </field>
            <field>
              <name>EM26</name>
              <bitOffset>26</bitOffset>
              <bitWidth>1</bitWidth>
            </field>
            <field>
              <name>EM27</name>
              <bitOffset>27</bitOffset>
              <bitWidth>1</bitWidth>
            </field>
            <field>
              <name>EM28</name>
              <bitOffset>28</bitOffset>
              <bitWidth>1</bitWidth>
            </field>
            <field>
              <name>EM29</name>
              <bitOffset>29</bitOffset>
              <bitWidth>1</bitWidth>
            </field>
            <field>
              <name>EM30</name>
              <bitOffset>30</bitOffset>
              <bitWidth>1</bitWidth>
            </field>
          </fields>
        </register>
        <register>
          <name>RTSR1</name>
          <addressOffset>0x8</addressOffset>
          <size>0x20</size>
          <fields>
            <field>
              <name>RT0</name>
              <bitOffset>0</bitOffset>
              <bitWidth>1</bitWidth>
            </field>
            <field>
              <name>RT1</name>
              <bitOffset>1</bitOffset>
              <bitWidth>1</bitWidth>
            </field>
            <field>
              <name>RT2</name>
              <bitOffset>2</bitOffset>
              <bitWidth>1</bitWidth>
            </field>
            <field>
              <name>RT3</name>
              <bitOffset>3</bitOffset>
              <bitWidth>1</bitWidth>
            </field>
            <field>
              <name>RT4</name>
              <bitOffset>4</bitOffset>
              <bitWidth>1</bitWidth>
            </field>
            <field>
              <name>RT5</name>
              <bitOffset>5</bitOffset>
              <bitWidth>1</bitWidth>
            </field>
            <field>
              <name>RT6</name>
              <bitOffset>6</bitOffset>
              <bitWidth>1</bitWidth>
            </field>
            <field>
              <name>RT7</name>
              <bitOffset>7</bitOffset>
              <bitWidth>1</bitWidth>
            </field>
            <field>
              <name>RT8</name>
              <bitOffset>8</bitOffset>
              <bitWidth>1</bitWidth>
            </field>
            <field>
              <name>RT9</name>
              <bitOffset>9</bitOffset>
              <bitWidth>1</bitWidth>
            </field>
            <field>
              <name>RT10</name>
              <bitOffset>10</bitOffset>
              <bitWidth>1</bitWidth>
            </field>
            <field>
              <name>RT11</name>
              <bitOffset>11</bitOffset>
              <bitWidth>1</bitWidth>
            </field>
            <field>
              <name>RT12</name>
              <bitOffset>12</bitOffset>
              <bitWidth>1</bitWidth>
            </field>
            <field>
              <name>RT13</name>
              <bitOffset>13</bitOffset>
              <bitWidth>1</bitWidth>
            </field>
            <field>
              <name>RT14</name>
              <bitOffset>14</bitOffset>
              <bitWidth>1</bitWidth>
            </field>
            <field>
              <name>RT15</name>
              <bitOffset>15</bitOffset>
              <bitWidth>1</bitWidth>
            </field>
            <field>
              <name>RT16</name>
              <bitOffset>16</bitOffset>
              <bitWidth>1</bitWidth>
            </field>
            <field>
              <name>RT17</name>
              <bitOffset>17</bitOffset>
              <bitWidth>1</bitWidth>
            </field>
            <field>
              <name>RT19</name>
              <bitOffset>19</bitOffset>
              <bitWidth>1</bitWidth>
            </field>
            <field>
              <name>RT20</name>
              <bitOffset>20</bitOffset>
              <bitWidth>1</bitWidth>
            </field>
            <field>
              <name>RT21</name>
              <bitOffset>21</bitOffset>
              <bitWidth>1</bitWidth>
            </field>
            <field>
              <name>RT22</name>
              <bitOffset>22</bitOffset>
              <bitWidth>1</bitWidth>
            </field>
            <field>
              <name>RT29</name>
              <bitOffset>29</bitOffset>
              <bitWidth>1</bitWidth>
            </field>
            <field>
              <name>RT30</name>
              <bitOffset>30</bitOffset>
              <bitWidth>1</bitWidth>
            </field>
          </fields>
        </register>
        <register>
          <name>FTSR1</name>
          <addressOffset>0xc</addressOffset>
          <size>0x20</size>
          <fields>
            <field>
              <name>FT0</name>
              <bitOffset>0</bitOffset>
              <bitWidth>1</bitWidth>
            </field>
            <field>
              <name>FT1</name>
              <bitOffset>1</bitOffset>
              <bitWidth>1</bitWidth>
            </field>
            <field>
              <name>FT2</name>
              <bitOffset>2</bitOffset>
              <bitWidth>1</bitWidth>
            </field>
            <field>
              <name>FT3</name>
              <bitOffset>3</bitOffset>
              <bitWidth>1</bitWidth>
            </field>
            <field>
              <name>FT4</name>
              <bitOffset>4</bitOffset>
              <bitWidth>1</bitWidth>
            </field>
            <field>
              <name>FT5</name>
              <bitOffset>5</bitOffset>
              <bitWidth>1</bitWidth>
            </field>
            <field>
              <name>FT6</name>
              <bitOffset>6</bitOffset>
              <bitWidth>1</bitWidth>
            </field>
            <field>
              <name>FT7</name>
              <bitOffset>7</bitOffset>
              <bitWidth>1</bitWidth>
            </field>
            <field>
              <name>FT8</name>
              <bitOffset>8</bitOffset>
              <bitWidth>1</bitWidth>
            </field>
            <field>
              <name>FT9</name>
              <bitOffset>9</bitOffset>
              <bitWidth>1</bitWidth>
            </field>
            <field>
              <name>FT10</name>
              <bitOffset>10</bitOffset>
              <bitWidth>1</bitWidth>
            </field>
            <field>
              <name>FT11</name>
              <bitOffset>11</bitOffset>
              <bitWidth>1</bitWidth>
            </field>
            <field>
              <name>FT12</name>
              <bitOffset>12</bitOffset>
              <bitWidth>1</bitWidth>
            </field>
            <field>
              <name>FT13</name>
              <bitOffset>13</bitOffset>
              <bitWidth>1</bitWidth>
            </field>
            <field>
              <name>FT14</name>
              <bitOffset>14</bitOffset>
              <bitWidth>1</bitWidth>
            </field>
            <field>
              <name>FT15</name>
              <bitOffset>15</bitOffset>
              <bitWidth>1</bitWidth>
            </field>
            <field>
              <name>FT16</name>
              <bitOffset>16</bitOffset>
              <bitWidth>1</bitWidth>
            </field>
            <field>
              <name>FT17</name>
              <bitOffset>17</bitOffset>
              <bitWidth>1</bitWidth>
            </field>
            <field>
              <name>FT19</name>
              <bitOffset>19</bitOffset>
              <bitWidth>1</bitWidth>
            </field>
            <field>
              <name>FT20</name>
              <bitOffset>20</bitOffset>
              <bitWidth>1</bitWidth>
            </field>
            <field>
              <name>FT21</name>
              <bitOffset>21</bitOffset>
              <bitWidth>1</bitWidth>
            </field>
            <field>
              <name>FT22</name>
              <bitOffset>22</bitOffset>
              <bitWidth>1</bitWidth>
            </field>
            <field>
              <name>FT29</name>
              <bitOffset>29</bitOffset>
              <bitWidth>1</bitWidth>
            </field>
            <field>
              <name>FT30</name>
              <bitOffset>30</bitOffset>
              <bitWidth>1</bitWidth>
            </field>
          </fields>
        </register>
        <register>
          <name>SWIER1</name>
          <addressOffset>0x10</addressOffset>
          <size>0x20</size>
          <fields>
            <field>
              <name>SWI0</name>
              <bitOffset>0</bitOffset>
              <bitWidth>1</bitWidth>
            </field>
            <field>
              <name>SWI1</name>
              <bitOffset>1</bitOffset>
              <bitWidth>1</bitWidth>
            </field>
            <field>
              <name>SWI2</name>
              <bitOffset>2</bitOffset>
              <bitWidth>1</bitWidth>
            </field>
            <field>
              <name>SWI3</name>
              <bitOffset>3</bitOffset>
              <bitWidth>1</bitWidth>
            </field>
            <field>
              <name>SWI4</name>
              <bitOffset>4</bitOffset>
              <bitWidth>1</bitWidth>
            </field>
            <field>
              <name>SWI5</name>
              <bitOffset>5</bitOffset>
              <bitWidth>1</bitWidth>
            </field>
            <field>
              <name>SWI6</name>
              <bitOffset>6</bitOffset>
              <bitWidth>1</bitWidth>
            </field>
            <field>
              <name>SWI7</name>
              <bitOffset>7</bitOffset>
              <bitWidth>1</bitWidth>
            </field>
            <field>
              <name>SWI8</name>
              <bitOffset>8</bitOffset>
              <bitWidth>1</bitWidth>
            </field>
            <field>
              <name>SWI9</name>
              <bitOffset>9</bitOffset>
              <bitWidth>1</bitWidth>
            </field>
            <field>
              <name>SWI10</name>
              <bitOffset>10</bitOffset>
              <bitWidth>1</bitWidth>
            </field>
            <field>
              <name>SWI11</name>
              <bitOffset>11</bitOffset>
              <bitWidth>1</bitWidth>
            </field>
            <field>
              <name>SWI12</name>
              <bitOffset>12</bitOffset>
              <bitWidth>1</bitWidth>
            </field>
            <field>
              <name>SWI13</name>
              <bitOffset>13</bitOffset>
              <bitWidth>1</bitWidth>
            </field>
            <field>
              <name>SWI14</name>
              <bitOffset>14</bitOffset>
              <bitWidth>1</bitWidth>
            </field>
            <field>
              <name>SWI15</name>
              <bitOffset>15</bitOffset>
              <bitWidth>1</bitWidth>
            </field>
            <field>
              <name>SWI16</name>
              <bitOffset>16</bitOffset>
              <bitWidth>1</bitWidth>
            </field>
            <field>
              <name>SWI17</name>
              <bitOffset>17</bitOffset>
              <bitWidth>1</bitWidth>
            </field>
            <field>
              <name>SWI19</name>
              <bitOffset>19</bitOffset>
              <bitWidth>1</bitWidth>
            </field>
            <field>
              <name>SWI20</name>
              <bitOffset>20</bitOffset>
              <bitWidth>1</bitWidth>
            </field>
            <field>
              <name>SWI21</name>
              <bitOffset>21</bitOffset>
              <bitWidth>1</bitWidth>
            </field>
            <field>
              <name>SWI22</name>
              <bitOffset>22</bitOffset>
              <bitWidth>1</bitWidth>
            </field>
            <field>
              <name>SWI29</name>
              <bitOffset>29</bitOffset>
              <bitWidth>1</bitWidth>
            </field>
            <field>
              <name>SWI30</name>
              <bitOffset>30</bitOffset>
              <bitWidth>1</bitWidth>
            </field>
          </fields>
        </register>
        <register>
          <name>PR1</name>
          <addressOffset>0x14</addressOffset>
          <size>0x20</size>
          <fields>
            <field>
              <name>PIF0</name>
              <bitOffset>0</bitOffset>
              <bitWidth>1</bitWidth>
            </field>
            <field>
              <name>PIF1</name>
              <bitOffset>1</bitOffset>
              <bitWidth>1</bitWidth>
            </field>
            <field>
              <name>PIF2</name>
              <bitOffset>2</bitOffset>
              <bitWidth>1</bitWidth>
            </field>
            <field>
              <name>PIF3</name>
              <bitOffset>3</bitOffset>
              <bitWidth>1</bitWidth>
            </field>
            <field>
              <name>PIF4</name>
              <bitOffset>4</bitOffset>
              <bitWidth>1</bitWidth>
            </field>
            <field>
              <name>PIF5</name>
              <bitOffset>5</bitOffset>
              <bitWidth>1</bitWidth>
            </field>
            <field>
              <name>PIF6</name>
              <bitOffset>6</bitOffset>
              <bitWidth>1</bitWidth>
            </field>
            <field>
              <name>PIF7</name>
              <bitOffset>7</bitOffset>
              <bitWidth>1</bitWidth>
            </field>
            <field>
              <name>PIF8</name>
              <bitOffset>8</bitOffset>
              <bitWidth>1</bitWidth>
            </field>
            <field>
              <name>PIF9</name>
              <bitOffset>9</bitOffset>
              <bitWidth>1</bitWidth>
            </field>
            <field>
              <name>PIF10</name>
              <bitOffset>10</bitOffset>
              <bitWidth>1</bitWidth>
            </field>
            <field>
              <name>PIF11</name>
              <bitOffset>11</bitOffset>
              <bitWidth>1</bitWidth>
            </field>
            <field>
              <name>PIF12</name>
              <bitOffset>12</bitOffset>
              <bitWidth>1</bitWidth>
            </field>
            <field>
              <name>PIF13</name>
              <bitOffset>13</bitOffset>
              <bitWidth>1</bitWidth>
            </field>
            <field>
              <name>PIF14</name>
              <bitOffset>14</bitOffset>
              <bitWidth>1</bitWidth>
            </field>
            <field>
              <name>PIF15</name>
              <bitOffset>15</bitOffset>
              <bitWidth>1</bitWidth>
            </field>
            <field>
              <name>PIF16</name>
              <bitOffset>16</bitOffset>
              <bitWidth>1</bitWidth>
            </field>
            <field>
              <name>PIF17</name>
              <bitOffset>17</bitOffset>
              <bitWidth>1</bitWidth>
            </field>
            <field>
              <name>PIF19</name>
              <bitOffset>19</bitOffset>
              <bitWidth>1</bitWidth>
            </field>
            <field>
              <name>PIF20</name>
              <bitOffset>20</bitOffset>
              <bitWidth>1</bitWidth>
            </field>
            <field>
              <name>PIF21</name>
              <bitOffset>21</bitOffset>
              <bitWidth>1</bitWidth>
            </field>
            <field>
              <name>PIF22</name>
              <bitOffset>22</bitOffset>
              <bitWidth>1</bitWidth>
            </field>
            <field>
              <name>PIF29</name>
              <bitOffset>29</bitOffset>
              <bitWidth>1</bitWidth>
            </field>
            <field>
              <name>PIF30</name>
              <bitOffset>30</bitOffset>
              <bitWidth>1</bitWidth>
            </field>
          </fields>
        </register>
        <register>
          <name>IMR2</name>
          <addressOffset>0x20</addressOffset>
          <size>0x20</size>
          <fields>
            <field>
              <name>IM</name>
              <bitOffset>0</bitOffset>
              <bitWidth>11</bitWidth>
            </field>
            <field>
              <name>IM34</name>
              <bitOffset>2</bitOffset>
              <bitWidth>1</bitWidth>
            </field>
            <field>
              <name>IM35</name>
              <bitOffset>3</bitOffset>
              <bitWidth>1</bitWidth>
            </field>
            <field>
              <name>IM36</name>
              <bitOffset>4</bitOffset>
              <bitWidth>1</bitWidth>
            </field>
            <field>
              <name>IM37</name>
              <bitOffset>5</bitOffset>
              <bitWidth>1</bitWidth>
            </field>
            <field>
              <name>IM38</name>
              <bitOffset>6</bitOffset>
              <bitWidth>1</bitWidth>
            </field>
            <field>
              <name>IM39</name>
              <bitOffset>7</bitOffset>
              <bitWidth>1</bitWidth>
            </field>
            <field>
              <name>IM40</name>
              <bitOffset>8</bitOffset>
              <bitWidth>1</bitWidth>
            </field>
            <field>
              <name>IM41</name>
              <bitOffset>9</bitOffset>
              <bitWidth>1</bitWidth>
            </field>
            <field>
              <name>IM42</name>
              <bitOffset>10</bitOffset>
              <bitWidth>1</bitWidth>
            </field>
          </fields>
        </register>
        <register>
          <name>EMR2</name>
          <addressOffset>0x24</addressOffset>
          <size>0x20</size>
          <fields>
            <field>
              <name>EM</name>
              <bitOffset>0</bitOffset>
              <bitWidth>11</bitWidth>
            </field>
            <field>
              <name>EM34</name>
              <bitOffset>2</bitOffset>
              <bitWidth>1</bitWidth>
            </field>
            <field>
              <name>EM35</name>
              <bitOffset>3</bitOffset>
              <bitWidth>1</bitWidth>
            </field>
            <field>
              <name>EM36</name>
              <bitOffset>4</bitOffset>
              <bitWidth>1</bitWidth>
            </field>
            <field>
              <name>EM37</name>
              <bitOffset>5</bitOffset>
              <bitWidth>1</bitWidth>
            </field>
            <field>
              <name>EM38</name>
              <bitOffset>6</bitOffset>
              <bitWidth>1</bitWidth>
            </field>
            <field>
              <name>EM39</name>
              <bitOffset>7</bitOffset>
              <bitWidth>1</bitWidth>
            </field>
            <field>
              <name>EM40</name>
              <bitOffset>8</bitOffset>
              <bitWidth>1</bitWidth>
            </field>
            <field>
              <name>EM41</name>
              <bitOffset>9</bitOffset>
              <bitWidth>1</bitWidth>
            </field>
            <field>
              <name>EM42</name>
              <bitOffset>10</bitOffset>
              <bitWidth>1</bitWidth>
            </field>
          </fields>
        </register>
        <register>
          <name>RTSR2</name>
          <addressOffset>0x28</addressOffset>
          <size>0x20</size>
          <fields>
            <field>
              <name>RT38</name>
              <bitOffset>6</bitOffset>
              <bitWidth>1</bitWidth>
            </field>
            <field>
              <name>RT39</name>
              <bitOffset>7</bitOffset>
              <bitWidth>1</bitWidth>
            </field>
            <field>
              <name>RT40</name>
              <bitOffset>8</bitOffset>
              <bitWidth>1</bitWidth>
            </field>
            <field>
              <name>RT41</name>
              <bitOffset>9</bitOffset>
              <bitWidth>1</bitWidth>
            </field>
          </fields>
        </register>
        <register>
          <name>FTSR2</name>
          <addressOffset>0x2c</addressOffset>
          <size>0x20</size>
          <fields>
            <field>
              <name>FT38</name>
              <bitOffset>6</bitOffset>
              <bitWidth>1</bitWidth>
            </field>
            <field>
              <name>FT39</name>
              <bitOffset>7</bitOffset>
              <bitWidth>1</bitWidth>
            </field>
            <field>
              <name>FT40</name>
              <bitOffset>8</bitOffset>
              <bitWidth>1</bitWidth>
            </field>
            <field>
              <name>FT41</name>
              <bitOffset>9</bitOffset>
              <bitWidth>1</bitWidth>
            </field>
          </fields>
        </register>
        <register>
          <name>SWIER2</name>
          <addressOffset>0x30</addressOffset>
          <size>0x20</size>
          <fields>
            <field>
              <name>SWI38</name>
              <bitOffset>6</bitOffset>
              <bitWidth>1</bitWidth>
            </field>
            <field>
              <name>SWI39</name>
              <bitOffset>7</bitOffset>
              <bitWidth>1</bitWidth>
            </field>
            <field>
              <name>SWI40</name>
              <bitOffset>8</bitOffset>
              <bitWidth>1</bitWidth>
            </field>
            <field>
              <name>SWI41</name>
              <bitOffset>9</bitOffset>
              <bitWidth>1</bitWidth>
            </field>
          </fields>
        </register>
        <register>
          <name>PR2</name>
          <addressOffset>0x34</addressOffset>
          <size>0x20</size>
          <fields>
            <field>
              <name>PIF38</name>
              <bitOffset>6</bitOffset>
              <bitWidth>1</bitWidth>
            </field>
            <field>
              <name>PIF39</name>
              <bitOffset>7</bitOffset>
              <bitWidth>1</bitWidth>
            </field>
            <field>
              <name>PIF40</name>
              <bitOffset>8</bitOffset>
              <bitWidth>1</bitWidth>
            </field>
            <field>
              <name>PIF41</name>
              <bitOffset>9</bitOffset>
              <bitWidth>1</bitWidth>
            </field>
          </fields>
        </register>
      </registers>
    </peripheral>
    <peripheral>
      <name>TIM1</name>
      <baseAddress>0x40012c00</baseAddress>
      <registers>
        <register>
          <name>CR1</name>
          <addressOffset>0x0</addressOffset>
          <size>0x20</size>
          <fields>
            <field>
              <name>CEN</name>
              <bitOffset>0</bitOffset>
              <bitWidth>1</bitWidth>
            </field>
            <field>
              <name>UDIS</name>
              <bitOffset>1</bitOffset>
              <bitWidth>1</bitWidth>
            </field>
            <field>
              <name>URS</name>
              <bitOffset>2</bitOffset>
              <bitWidth>1</bitWidth>
            </field>
            <field>
              <name>OPM</name>
              <bitOffset>3</bitOffset>
              <bitWidth>1</bitWidth>
            </field>
            <field>
              <name>DIR</name>
              <bitOffset>4</bitOffset>
              <bitWidth>1</bitWidth>
            </field>
            <field>
              <name>CMS</name>
              <bitOffset>5</bitOffset>
              <bitWidth>2</bitWidth>
            </field>
            <field>
              <name>ARPE</name>
              <bitOffset>7</bitOffset>
              <bitWidth>1</bitWidth>
            </field>
            <field>
              <name>CKD</name>
              <bitOffset>8</bitOffset>
              <bitWidth>2</bitWidth>
            </field>
            <field>
              <name>UIFREMAP</name>
              <bitOffset>11</bitOffset>
              <bitWidth>1</bitWidth>
            </field>
            <field>
              <name>DITHEN</name>
              <bitOffset>12</bitOffset>
              <bitWidth>1</bitWidth>
            </field>
          </fields>
        </register>
        <register>
          <name>CR2</name>
          <addressOffset>0x4</addressOffset>
          <size>0x20</size>
          <fields>
            <field>
              <name>CCPC</name>
              <bitOffset>0</bitOffset>
              <bitWidth>1</bitWidth>
            </field>
            <field>
              <name>CCUS</name>
              <bitOffset>2</bitOffset>
              <bitWidth>1</bitWidth>
            </field>
            <field>
              <name>CCDS</name>
              <bitOffset>3</bitOffset>
              <bitWidth>1</bitWidth>
            </field>
            <field>
              <name>MMS</name>
              <bitOffset>4</bitOffset>
              <bitWidth>22</bitWidth>
            </field>
            <field>
              <name>TI1S</name>
              <bitOffset>7</bitOffset>
              <bitWidth>1</bitWidth>
            </field>
            <field>
              <name>OIS1</name>
              <bitOffset>8</bitOffset>
              <bitWidth>1</bitWidth>
            </field>
            <field>
              <name>OIS1N</name>
              <bitOffset>9</bitOffset>
              <bitWidth>1</bitWidth>
            </field>
            <field>
              <name>OIS2</name>
              <bitOffset>10</bitOffset>
              <bitWidth>1</bitWidth>
            </field>
            <field>
              <name>OIS2N</name>
              <bitOffset>11</bitOffset>
              <bitWidth>1</bitWidth>
            </field>
            <field>
              <name>OIS3</name>
              <bitOffset>12</bitOffset>
              <bitWidth>1</bitWidth>
            </field>
            <field>
              <name>OIS3N</name>
              <bitOffset>13</bitOffset>
              <bitWidth>1</bitWidth>
            </field>
            <field>
              <name>OIS4</name>
              <bitOffset>14</bitOffset>
              <bitWidth>1</bitWidth>
            </field>
            <field>
              <name>OIS4N</name>
              <bitOffset>15</bitOffset>
              <bitWidth>1</bitWidth>
            </field>
            <field>
              <name>OIS5</name>
              <bitOffset>16</bitOffset>
              <bitWidth>1</bitWidth>
            </field>
            <field>
              <name>OIS6</name>
              <bitOffset>18</bitOffset>
              <bitWidth>1</bitWidth>
            </field>
            <field>
              <name>MMS2</name>
              <bitOffset>20</bitOffset>
              <bitWidth>4</bitWidth>
            </field>
          </fields>
        </register>
        <register>
          <name>SMCR</name>
          <addressOffset>0x8</addressOffset>
          <size>0x20</size>
          <fields>
            <field>
              <name>SMS</name>
              <bitOffset>0</bitOffset>
              <bitWidth>17</bitWidth>
            </field>
            <field>
              <name>OCCS</name>
              <bitOffset>3</bitOffset>
              <bitWidth>1</bitWidth>
            </field>
            <field>
              <name>TS</name>
              <bitOffset>4</bitOffset>
              <bitWidth>18</bitWidth>
            </field>
            <field>
              <name>MSM</name>
              <bitOffset>7</bitOffset>
              <bitWidth>1</bitWidth>
            </field>
            <field>
              <name>ETF</name>
              <bitOffset>8</bitOffset>
              <bitWidth>4</bitWidth>
            </field>
            <field>
              <name>ETPS</name>
              <bitOffset>12</bitOffset>
              <bitWidth>2</bitWidth>
            </field>
            <field>
              <name>ECE</name>
              <bitOffset>14</bitOffset>
              <bitWidth>1</bitWidth>
            </field>
            <field>
              <name>ETP</name>
              <bitOffset>15</bitOffset>
              <bitWidth>1</bitWidth>
            </field>
            <field>
              <name>SMSPE</name>
              <bitOffset>24</bitOffset>
              <bitWidth>1</bitWidth>
            </field>
            <field>
              <name>SMSPS</name>
              <bitOffset>25</bitOffset>
              <bitWidth>1</bitWidth>
            </field>
          </fields>
        </register>
        <register>
          <name>DIER</name>
          <addressOffset>0xc</addressOffset>
          <size>0x20</size>
          <fields>
            <field>
              <name>UIE</name>
              <bitOffset>0</bitOffset>
              <bitWidth>1</bitWidth>
            </field>
            <field>
              <name>CC1IE</name>
              <bitOffset>1</bitOffset>
              <bitWidth>1</bitWidth>
            </field>
            <field>
              <name>CC2IE</name>
              <bitOffset>2</bitOffset>
              <bitWidth>1</bitWidth>
            </field>
            <field>
              <name>CC3IE</name>
              <bitOffset>3</bitOffset>
              <bitWidth>1</bitWidth>
            </field>
            <field>
              <name>CC4IE</name>
              <bitOffset>4</bitOffset>
              <bitWidth>1</bitWidth>
            </field>
            <field>
              <name>COMIE</name>
              <bitOffset>5</bitOffset>
              <bitWidth>1</bitWidth>
            </field>
            <field>
              <name>TIE</name>
              <bitOffset>6</bitOffset>
              <bitWidth>1</bitWidth>
            </field>
            <field>
              <name>BIE</name>
              <bitOffset>7</bitOffset>
              <bitWidth>1</bitWidth>
            </field>
            <field>
              <name>UDE</name>
              <bitOffset>8</bitOffset>
              <bitWidth>1</bitWidth>
            </field>
            <field>
              <name>CC1DE</name>
              <bitOffset>9</bitOffset>
              <bitWidth>1</bitWidth>
            </field>
            <field>
              <name>CC2DE</name>
              <bitOffset>10</bitOffset>
              <bitWidth>1</bitWidth>
            </field>
            <field>
              <name>CC3DE</name>
              <bitOffset>11</bitOffset>
              <bitWidth>1</bitWidth>
            </field>
            <field>
              <name>CC4DE</name>
              <bitOffset>12</bitOffset>
              <bitWidth>1</bitWidth>
            </field>
            <field>
              <name>COMDE</name>
              <bitOffset>13</bitOffset>
              <bitWidth>1</bitWidth>
            </field>
            <field>
              <name>TDE</name>
              <bitOffset>14</bitOffset>
              <bitWidth>1</bitWidth>
            </field>
            <field>
              <name>IDXIE</name>
              <bitOffset>20</bitOffset>
              <bitWidth>1</bitWidth>
            </field>
            <field>
              <name>DIRIE</name>
              <bitOffset>21</bitOffset>
              <bitWidth>1</bitWidth>
            </field>
            <field>
              <name>IERRIE</name>
              <bitOffset>22</bitOffset>
              <bitWidth>1</bitWidth>
            </field>
            <field>
              <name>TERRIE</name>
              <bitOffset>23</bitOffset>
              <bitWidth>1</bitWidth>
            </field>
          </fields>
        </register>
        <register>
          <name>SR</name>
          <addressOffset>0x10</addressOffset>
          <size>0x20</size>
          <fields>
            <field>
              <name>UIF</name>
              <bitOffset>0</bitOffset>
              <bitWidth>1</bitWidth>
            </field>
            <field>
              <name>CC1IF</name>
              <bitOffset>1</bitOffset>
              <bitWidth>1</bitWidth>
            </field>
            <field>
              <name>CC2IF</name>
              <bitOffset>2</bitOffset>
              <bitWidth>1</bitWidth>
            </field>
            <field>
              <name>CC3IF</name>
              <bitOffset>3</bitOffset>
              <bitWidth>1</bitWidth>
            </field>
            <field>
              <name>CC4IF</name>
              <bitOffset>4</bitOffset>
              <bitWidth>1</bitWidth>
            </field>
            <field>
              <name>COMIF</name>
              <bitOffset>5</bitOffset>
              <bitWidth>1</bitWidth>
            </field>
            <field>
              <name>TIF</name>
              <bitOffset>6</bitOffset>
              <bitWidth>1</bitWidth>
            </field>
            <field>
              <name>BIF</name>
              <bitOffset>7</bitOffset>
              <bitWidth>1</bitWidth>
            </field>
            <field>
              <name>B2IF</name>
              <bitOffset>8</bitOffset>
              <bitWidth>1</bitWidth>
            </field>
            <field>
              <name>CC1OF</name>
              <bitOffset>9</bitOffset>
              <bitWidth>1</bitWidth>
            </field>
            <field>
              <name>CC2OF</name>
              <bitOffset>10</bitOffset>
              <bitWidth>1</bitWidth>
            </field>
            <field>
              <name>CC3OF</name>
              <bitOffset>11</bitOffset>
              <bitWidth>1</bitWidth>
            </field>
            <field>
              <name>CC4OF</name>
              <bitOffset>12</bitOffset>
              <bitWidth>1</bitWidth>
            </field>
            <field>
              <name>SBIF</name>
              <bitOffset>13</bitOffset>
              <bitWidth>1</bitWidth>
            </field>
            <field>
              <name>CC5IF</name>
              <bitOffset>16</bitOffset>
              <bitWidth>1</bitWidth>
            </field>
            <field>
              <name>CC6IF</name>
              <bitOffset>17</bitOffset>
              <bitWidth>1</bitWidth>
            </field>
            <field>
              <name>IDXF</name>
              <bitOffset>20</bitOffset>
              <bitWidth>1</bitWidth>
            </field>
            <field>
              <name>DIRF</name>
              <bitOffset>21</bitOffset>
              <bitWidth>1</bitWidth>
            </field>
            <field>
              <name>IERRF</name>
              <bitOffset>22</bitOffset>
              <bitWidth>1</bitWidth>
            </field>
            <field>
              <name>TERRF</name>
              <bitOffset>23</bitOffset>
              <bitWidth>1</bitWidth>
            </field>
          </fields>
        </register>
        <register>
          <name>EGR</name>
          <addressOffset>0x14</addressOffset>
          <size>0x20</size>
          <fields>
            <field>
              <name>UG</name>
              <bitOffset>0</bitOffset>
              <bitWidth>1</bitWidth>
            </field>
            <field>
              <name>CC1G</name>
              <bitOffset>1</bitOffset>
              <bitWidth>1</bitWidth>
            </field>
            <field>
              <name>CC2G</name>
              <bitOffset>2</bitOffset>
              <bitWidth>1</bitWidth>
            </field>
            <field>
              <name>CC3G</name>
              <bitOffset>3</bitOffset>
              <bitWidth>1</bitWidth>
            </field>
            <field>
              <name>CC4G</name>
              <bitOffset>4</bitOffset>
              <bitWidth>1</bitWidth>
            </field>
            <field>
              <name>COMG</name>
              <bitOffset>5</bitOffset>
              <bitWidth>1</bitWidth>
            </field>
            <field>
              <name>TG</name>
              <bitOffset>6</bitOffset>
              <bitWidth>1</bitWidth>
            </field>
            <field>
              <name>BG</name>
              <bitOffset>7</bitOffset>
              <bitWidth>1</bitWidth>
            </field>
            <field>
              <name>B2G</name>
              <bitOffset>8</bitOffset>
              <bitWidth>1</bitWidth>
            </field>
          </fields>
        </register>
        <register>
          <name>CCMR1</name>
          <addressOffset>0x18</addressOffset>
          <size>0x20</size>
          <fields>
            <field>
              <name>CC1S</name>
              <bitOffset>0</bitOffset>
              <bitWidth>2</bitWidth>
            </field>
            <field>
              <name>OC1FE</name>
              <bitOffset>2</bitOffset>
              <bitWidth>1</bitWidth>
            </field>
            <field>
              <name>OC1PE</name>
              <bitOffset>3</bitOffset>
              <bitWidth>1</bitWidth>
            </field>
            <field>
              <name>OC1M</name>
              <bitOffset>4</bitOffset>
              <bitWidth>13</bitWidth>
            </field>
            <field>
              <name>OC1CE</name>
              <bitOffset>7</bitOffset>
              <bitWidth>1</bitWidth>
            </field>
            <field>
              <name>CC2S</name>
              <bitOffset>8</bitOffset>
              <bitWidth>2</bitWidth>
            </field>
            <field>
              <name>OC2FE</name>
              <bitOffset>10</bitOffset>
              <bitWidth>1</bitWidth>
            </field>
            <field>
              <name>OC2PE</name>
              <bitOffset>11</bitOffset>
              <bitWidth>1</bitWidth>
            </field>
            <field>
              <name>OC2M</name>
              <bitOffset>12</bitOffset>
              <bitWidth>13</bitWidth>
            </field>
            <field>
              <name>OC2CE</name>
              <bitOffset>15</bitOffset>
              <bitWidth>1</bitWidth>
            </field>
          </fields>
        </register>
        <register>
          <name>CCMR2</name>
          <addressOffset>0x1c</addressOffset>
          <size>0x20</size>
          <fields>
            <field>
              <name>CC3S</name>
              <bitOffset>0</bitOffset>
              <bitWidth>2</bitWidth>
            </field>
            <field>
              <name>OC3FE</name>
              <bitOffset>2</bitOffset>
              <bitWidth>1</bitWidth>
            </field>
            <field>
              <name>OC3PE</name>
              <bitOffset>3</bitOffset>
              <bitWidth>1</bitWidth>
            </field>
            <field>
              <name>OC3M</name>
              <bitOffset>4</bitOffset>
              <bitWidth>13</bitWidth>
            </field>
            <field>
              <name>OC3CE</name>
              <bitOffset>7</bitOffset>
              <bitWidth>1</bitWidth>
            </field>
            <field>
              <name>CC4S</name>
              <bitOffset>8</bitOffset>
              <bitWidth>2</bitWidth>
            </field>
            <field>
              <name>OC4FE</name>
              <bitOffset>10</bitOffset>
              <bitWidth>1</bitWidth>
            </field>
            <field>
              <name>OC4PE</name>
              <bitOffset>11</bitOffset>
              <bitWidth>1</bitWidth>
            </field>
            <field>
              <name>OC4M</name>
              <bitOffset>12</bitOffset>
              <bitWidth>13</bitWidth>
            </field>
            <field>
              <name>OC4CE</name>
              <bitOffset>15</bitOffset>
              <bitWidth>1</bitWidth>
            </field>
          </fields>
        </register>
        <register>
          <name>CCER</name>
          <addressOffset>0x20</addressOffset>
          <size>0x20</size>
          <fields>
            <field>
              <name>CC1E</name>
              <bitOffset>0</bitOffset>
              <bitWidth>1</bitWidth>
            </field>
            <field>
              <name>CC1P</name>
              <bitOffset>1</bitOffset>
              <bitWidth>1</bitWidth>
            </field>
            <field>
              <name>CC1NE</name>
              <bitOffset>2</bitOffset>
              <bitWidth>1</bitWidth>
            </field>
            <field>
              <name>CC1NP</name>
              <bitOffset>3</bitOffset>
              <bitWidth>1</bitWidth>
            </field>
            <field>
              <name>CC2E</name>
              <bitOffset>4</bitOffset>
              <bitWidth>1</bitWidth>
            </field>
            <field>
              <name>CC2P</name>
              <bitOffset>5</bitOffset>
              <bitWidth>1</bitWidth>
            </field>
            <field>
              <name>CC2NE</name>
              <bitOffset>6</bitOffset>
              <bitWidth>1</bitWidth>
            </field>
            <field>
              <name>CC2NP</name>
              <bitOffset>7</bitOffset>
              <bitWidth>1</bitWidth>
            </field>
            <field>
              <name>CC3E</name>
              <bitOffset>8</bitOffset>
              <bitWidth>1</bitWidth>
            </field>
            <field>
              <name>CC3P</name>
              <bitOffset>9</bitOffset>
              <bitWidth>1</bitWidth>
            </field>
            <field>
              <name>CC3NE</name>
              <bitOffset>10</bitOffset>
              <bitWidth>1</bitWidth>
            </field>
            <field>
              <name>CC3NP</name>
              <bitOffset>11</bitOffset>
              <bitWidth>1</bitWidth>
            </field>
            <field>
              <name>CC4E</name>
              <bitOffset>12</bitOffset>
              <bitWidth>1</bitWidth>
            </field>
            <field>
              <name>CC4P</name>
              <bitOffset>13</bitOffset>
              <bitWidth>1</bitWidth>
            </field>
            <field>
              <name>CC4NE</name>
              <bitOffset>14</bitOffset>
              <bitWidth>1</bitWidth>
            </field>
            <field>
              <name>CC4NP</name>
              <bitOffset>15</bitOffset>
              <bitWidth>1</bitWidth>
            </field>
            <field>
              <name>CC5E</name>
              <bitOffset>16</bitOffset>
              <bitWidth>1</bitWidth>
            </field>
            <field>
              <name>CC5P</name>
              <bitOffset>17</bitOffset>
              <bitWidth>1</bitWidth>
            </field>
            <field>
              <name>CC6E</name>
              <bitOffset>20</bitOffset>
              <bitWidth>1</bitWidth>
            </field>
            <field>
              <name>CC6P</name>
              <bitOffset>21</bitOffset>
              <bitWidth>1</bitWidth>
            </field>
          </fields>
        </register>
        <register>
          <name>CNT</name>
          <addressOffset>0x24</addressOffset>
          <size>0x20</size>
          <fields>
            <field>
              <name>CNT</name>
              <bitOffset>0</bitOffset>
              <bitWidth>32</bitWidth>
            </field>
            <field>
              <name>UIFCPY</name>
              <bitOffset>31</bitOffset>
              <bitWidth>1</bitWidth>
            </field>
          </fields>
        </register>
        <register>
          <name>PSC</name>
          <addressOffset>0x28</addressOffset>
          <size>0x20</size>
          <fields>
            <field>
              <name>PSC</name>
              <bitOffset>0</bitOffset>
              <bitWidth>16</bitWidth>
            </field>
          </fields>
        </register>
        <register>
          <name>ARR</name>
          <addressOffset>0x2c</addressOffset>
          <size>0x20</size>
          <fields>
            <field>
              <name>ARR</name>
              <bitOffset>0</bitOffset>
              <bitWidth>32</bitWidth>
            </field>
          </fields>
        </register>
        <register>
          <name>RCR</name>
          <addressOffset>0x30</addressOffset>
          <size>0x20</size>
          <fields>
            <field>
              <name>REP</name>
              <bitOffset>0</bitOffset>
              <bitWidth>16</bitWidth>
            </field>
          </fields>
        </register>
        <register>
          <name>CCR1</name>
          <addressOffset>0x34</addressOffset>
          <size>0x20</size>
          <fields>
            <field>
              <name>CCR1</name>
              <bitOffset>0</bitOffset>
              <bitWidth>16</bitWidth>
            </field>
          </fields>
        </register>
        <register>
          <name>CCR2</name>
          <addressOffset>0x38</addressOffset>
          <size>0x20</size>
          <fields>
            <field>
              <name>CCR2</name>
              <bitOffset>0</bitOffset>
              <bitWidth>16</bitWidth>
            </field>
          </fields>
        </register>
        <register>
          <name>CCR3</name>
          <addressOffset>0x3c</addressOffset>
          <size>0x20</size>
          <fields>
            <field>
              <name>CCR3</name>
              <bitOffset>0</bitOffset>
              <bitWidth>16</bitWidth>
            </field>
          </fields>
        </register>
        <register>
          <name>CCR4</name>
          <addressOffset>0x40</addressOffset>
          <size>0x20</size>
          <fields>
            <field>
              <name>CCR4</name>
              <bitOffset>0</bitOffset>
              <bitWidth>16</bitWidth>
            </field>
          </fields>
        </register>
        <register>
          <name>BDTR</name>
          <addressOffset>0x44</addressOffset>
          <size>0x20</size>
          <fields>
            <field>
              <name>DTG</name>
              <bitOffset>0</bitOffset>
              <bitWidth>8</bitWidth>
            </field>
            <field>
              <name>LOCK</name>
              <bitOffset>8</bitOffset>
              <bitWidth>2</bitWidth>
            </field>
            <field>
              <name>OSSI</name>
              <bitOffset>10</bitOffset>
              <bitWidth>1</bitWidth>
            </field>
            <field>
              <name>OSSR</name>
              <bitOffset>11</bitOffset>
              <bitWidth>1</bitWidth>
            </field>
            <field>
              <name>BKE</name>
              <bitOffset>12</bitOffset>
              <bitWidth>1</bitWidth>
            </field>
            <field>
              <name>BKP</name>
              <bitOffset>13</bitOffset>
              <bitWidth>1</bitWidth>
            </field>
            <field>
              <name>AOE</name>
              <bitOffset>14</bitOffset>
              <bitWidth>1</bitWidth>
            </field>
            <field>
              <name>MOE</name>
              <bitOffset>15</bitOffset>
              <bitWidth>1</bitWidth>
            </field>
            <field>
              <name>BKF</name>
              <bitOffset>16</bitOffset>
              <bitWidth>4</bitWidth>
            </field>
            <field>
              <name>BK2F</name>
              <bitOffset>20</bitOffset>
              <bitWidth>4</bitWidth>
            </field>
            <field>
              <name>BK2E</name>
              <bitOffset>24</bitOffset>
              <bitWidth>1</bitWidth>
            </field>
            <field>
              <name>BK2P</name>
              <bitOffset>25</bitOffset>
              <bitWidth>1</bitWidth>
            </field>
            <field>
              <name>BKDSRM</name>
              <bitOffset>26</bitOffset>
              <bitWidth>1</bitWidth>
            </field>
            <field>
              <name>BK2DSRM</name>
              <bitOffset>27</bitOffset>
              <bitWidth>1</bitWidth>
            </field>
            <field>
              <name>BKBID</name>
              <bitOffset>28</bitOffset>
              <bitWidth>1</bitWidth>
            </field>
            <field>
              <name>BK2BID</name>
              <bitOffset>29</bitOffset>
              <bitWidth>1</bitWidth>
            </field>
          </fields>
        </register>
        <register>
          <name>CCR5</name>
          <addressOffset>0x48</addressOffset>
          <size>0x20</size>
          <fields>
            <field>
              <name>CCR5</name>
              <bitOffset>0</bitOffset>
              <bitWidth>32</bitWidth>
            </field>
            <field>
              <name>GC5C1</name>
              <bitOffset>29</bitOffset>
              <bitWidth>1</bitWidth>
            </field>
            <field>
              <name>GC5C2</name>
              <bitOffset>30</bitOffset>
              <bitWidth>1</bitWidth>
            </field>
            <field>
              <name>GC5C3</name>
              <bitOffset>31</bitOffset>
              <bitWidth>1</bitWidth>
            </field>
          </fields>
        </register>
        <register>
          <name>CCR6</name>
          <addressOffset>0x4c</addressOffset>
          <size>0x20</size>
          <fields>
            <field>
              <name>CCR6</name>
              <bitOffset>0</bitOffset>
              <bitWidth>16</bitWidth>
            </field>
          </fields>
        </register>
        <register>
          <name>CCMR3</name>
          <addressOffset>0x50</addressOffset>
          <size>0x20</size>
          <fields>
            <field>
              <name>OC5FE</name>
              <bitOffset>2</bitOffset>
              <bitWidth>1</bitWidth>
            </field>
            <field>
              <name>OC5PE</name>
              <bitOffset>3</bitOffset>
              <bitWidth>1</bitWidth>
            </field>
            <field>
              <name>OC5M</name>
              <bitOffset>4</bitOffset>
              <bitWidth>13</bitWidth>
            </field>
            <field>
              <name>OC5CE</name>
              <bitOffset>7</bitOffset>
              <bitWidth>1</bitWidth>
            </field>
            <field>
              <name>OC6FE</name>
              <bitOffset>10</bitOffset>
              <bitWidth>1</bitWidth>
            </field>
            <field>
              <name>OC6PE</name>
              <bitOffset>11</bitOffset>
              <bitWidth>1</bitWidth>
            </field>
            <field>
              <name>OC6M</name>
              <bitOffset>12</bitOffset>
              <bitWidth>13</bitWidth>
            </field>
            <field>
              <name>OC6CE</name>
              <bitOffset>15</bitOffset>
              <bitWidth>1</bitWidth>
            </field>
          </fields>
        </register>
        <register>
          <name>DTR2</name>
          <addressOffset>0x54</addressOffset>
          <size>0x20</size>
          <fields>
            <field>
              <name>DTGF</name>
              <bitOffset>0</bitOffset>
              <bitWidth>8</bitWidth>
            </field>
            <field>
              <name>DTAE</name>
              <bitOffset>16</bitOffset>
              <bitWidth>1</bitWidth>
            </field>
            <field>
              <name>DTPE</name>
              <bitOffset>17</bitOffset>
              <bitWidth>1</bitWidth>
            </field>
          </fields>
        </register>
        <register>
          <name>ECR</name>
          <addressOffset>0x58</addressOffset>
          <size>0x20</size>
          <fields>
            <field>
              <name>IE</name>
              <bitOffset>0</bitOffset>
              <bitWidth>1</bitWidth>
            </field>
            <field>
              <name>IDIR</name>
              <bitOffset>1</bitOffset>
              <bitWidth>2</bitWidth>
            </field>
            <field>
              <name>FIDX</name>
              <bitOffset>5</bitOffset>
              <bitWidth>1</bitWidth>
            </field>
            <field>
              <name>IPOS</name>
              <bitOffset>6</bitOffset>
              <bitWidth>2</bitWidth>
            </field>
            <field>
              <name>PW</name>
              <bitOffset>16</bitOffset>
              <bitWidth>8</bitWidth>
            </field>
            <field>
              <name>PWPRSC</name>
              <bitOffset>24</bitOffset>
              <bitWidth>3</bitWidth>
            </field>
          </fields>
        </register>
        <register>
          <name>TISEL</name>
          <addressOffset>0x5c</addressOffset>
          <size>0x20</size>
          <fields>
            <field>
              <name>TI1SEL</name>
              <bitOffset>0</bitOffset>
              <bitWidth>4</bitWidth>
            </field>
            <field>
              <name>TI2SEL</name>
              <bitOffset>8</bitOffset>
              <bitWidth>4</bitWidth>
            </field>
            <field>
              <name>TI3SEL</name>
              <bitOffset>16</bitOffset>
              <bitWidth>4</bitWidth>
            </field>
            <field>
              <name>TI4SEL</name>
              <bitOffset>24</bitOffset>
              <bitWidth>4</bitWidth>
            </field>
          </fields>
        </register>
        <register>
          <name>AF1</name>
          <addressOffset>0x60</addressOffset>
          <size>0x20</size>
        </register>
        <register>
          <name>AF2</name>
          <addressOffset>0x64</addressOffset>
          <size>0x20</size>
        </register>
        <register>
          <name>OR</name>
          <addressOffset>0x68</addressOffset>
          <size>0x20</size>
          <fields>
            <field>
              <name>HSE32EN</name>
              <bitOffset>0</bitOffset>
              <bitWidth>1</bitWidth>
            </field>
          </fields>
        </register>
        <register>
          <name>DCR</name>
          <addressOffset>0x3dc</addressOffset>
          <size>0x20</size>
          <fields>
            <field>
              <name>DBA</name>
              <bitOffset>0</bitOffset>
              <bitWidth>5</bitWidth>
            </field>
            <field>
              <name>DBL</name>
              <bitOffset>8</bitOffset>
              <bitWidth>5</bitWidth>
            </field>
          </fields>
        </register>
        <register>
          <name>DMAR</name>
          <addressOffset>0x3e0</addressOffset>
          <size>0x20</size>
          <fields>
            <field>
              <name>DMAB</name>
              <bitOffset>0</bitOffset>
              <bitWidth>32</bitWidth>
            </field>
          </fields>
        </register>
      </registers>
    </peripheral>
    <peripheral>
      <name>SPI1</name>
      <baseAddress>0x40013000</baseAddress>
      <registers>
        <register>
          <name>CR1</name>
          <addressOffset>0x0</addressOffset>
          <size>0x20</size>
          <fields>
            <field>
              <name>CPHA</name>
              <bitOffset>0</bitOffset>
              <bitWidth>1</bitWidth>
            </field>
            <field>
              <name>CPOL</name>
              <bitOffset>1</bitOffset>
              <bitWidth>1</bitWidth>
            </field>
            <field>
              <name>MSTR</name>
              <bitOffset>2</bitOffset>
              <bitWidth>1</bitWidth>
            </field>
            <field>
              <name>BR</name>
              <bitOffset>3</bitOffset>
              <bitWidth>3</bitWidth>
            </field>
            <field>
              <name>SPE</name>
              <bitOffset>6</bitOffset>
              <bitWidth>1</bitWidth>
            </field>
            <field>
              <name>LSBFIRST</name>
              <bitOffset>7</bitOffset>
              <bitWidth>1</bitWidth>
            </field>
            <field>
              <name>SSI</name>
              <bitOffset>8</bitOffset>
              <bitWidth>1</bitWidth>
            </field>
            <field>
              <name>SSM</name>
              <bitOffset>9</bitOffset>
              <bitWidth>1</bitWidth>
            </field>
            <field>
              <name>RXONLY</name>
              <bitOffset>10</bitOffset>
              <bitWidth>1</bitWidth>
            </field>
            <field>
              <name>CRCL</name>
              <bitOffset>11</bitOffset>
              <bitWidth>1</bitWidth>
            </field>
            <field>
              <name>CRCNEXT</name>
              <bitOffset>12</bitOffset>
              <bitWidth>1</bitWidth>
            </field>
            <field>
              <name>CRCEN</name>
              <bitOffset>13</bitOffset>
              <bitWidth>1</bitWidth>
            </field>
            <field>
              <name>BIDIOE</name>
              <bitOffset>14</bitOffset>
              <bitWidth>1</bitWidth>
            </field>
            <field>
              <name>BIDIMODE</name>
              <bitOffset>15</bitOffset>
              <bitWidth>1</bitWidth>
            </field>
          </fields>
        </register>
        <register>
          <name>CR2</name>
          <addressOffset>0x4</addressOffset>
          <size>0x20</size>
          <fields>
            <field>
              <name>RXDMAEN</name>
              <bitOffset>0</bitOffset>
              <bitWidth>1</bitWidth>
            </field>
            <field>
              <name>TXDMAEN</name>
              <bitOffset>1</bitOffset>
              <bitWidth>1</bitWidth>
            </field>
            <field>
              <name>SSOE</name>
              <bitOffset>2</bitOffset>
              <bitWidth>1</bitWidth>
            </field>
            <field>
              <name>NSSP</name>
              <bitOffset>3</bitOffset>
              <bitWidth>1</bitWidth>
            </field>
            <field>
              <name>FRF</name>
              <bitOffset>4</bitOffset>
              <bitWidth>1</bitWidth>
            </field>
            <field>
              <name>ERRIE</name>
              <bitOffset>5</bitOffset>
              <bitWidth>1</bitWidth>
            </field>
            <field>
              <name>RXNEIE</name>
              <bitOffset>6</bitOffset>
              <bitWidth>1</bitWidth>
            </field>
            <field>
              <name>TXEIE</name>
              <bitOffset>7</bitOffset>
              <bitWidth>1</bitWidth>
            </field>
            <field>
              <name>DS</name>
              <bitOffset>8</bitOffset>
              <bitWidth>4</bitWidth>
            </field>
            <field>
              <name>FRXTH</name>
              <bitOffset>12</bitOffset>
              <bitWidth>1</bitWidth>
            </field>
            <field>
              <name>LDMARX</name>
              <bitOffset>13</bitOffset>
              <bitWidth>1</bitWidth>
            </field>
            <field>
              <name>LDMATX</name>
              <bitOffset>14</bitOffset>
              <bitWidth>1</bitWidth>
            </field>
          </fields>
        </register>
        <register>
          <name>SR</name>
          <addressOffset>0x8</addressOffset>
          <size>0x20</size>
          <fields>
            <field>
              <name>RXNE</name>
              <bitOffset>0</bitOffset>
              <bitWidth>1</bitWidth>
            </field>
            <field>
              <name>TXE</name>
              <bitOffset>1</bitOffset>
              <bitWidth>1</bitWidth>
            </field>
            <field>
              <name>CHSIDE</name>
              <bitOffset>2</bitOffset>
              <bitWidth>1</bitWidth>
            </field>
            <field>
              <name>UDR</name>
              <bitOffset>3</bitOffset>
              <bitWidth>1</bitWidth>
            </field>
            <field>
              <name>CRCERR</name>
              <bitOffset>4</bitOffset>
              <bitWidth>1</bitWidth>
            </field>
            <field>
              <name>MODF</name>
              <bitOffset>5</bitOffset>
              <bitWidth>1</bitWidth>
            </field>
            <field>
              <name>OVR</name>
              <bitOffset>6</bitOffset>
              <bitWidth>1</bitWidth>
            </field>
            <field>
              <name>BSY</name>
              <bitOffset>7</bitOffset>
              <bitWidth>1</bitWidth>
            </field>
            <field>
              <name>FRE</name>
              <bitOffset>8</bitOffset>
              <bitWidth>1</bitWidth>
            </field>
            <field>
              <name>FRLVL</name>
              <bitOffset>9</bitOffset>
              <bitWidth>2</bitWidth>
            </field>
            <field>
              <name>FTLVL</name>
              <bitOffset>11</bitOffset>
              <bitWidth>2</bitWidth>
            </field>
          </fields>
        </register>
        <register>
          <name>DR</name>
          <addressOffset>0xc</addressOffset>
          <size>0x20</size>
          <fields>
            <field>
              <name>DR</name>
              <bitOffset>0</bitOffset>
              <bitWidth>16</bitWidth>
            </field>
          </fields>
        </register>
        <register>
          <name>CRCPR</name>
          <addressOffset>0x10</addressOffset>
          <size>0x20</size>
          <fields>
            <field>
              <name>CRCPOLY</name>
              <bitOffset>0</bitOffset>
              <bitWidth>16</bitWidth>
            </field>
          </fields>
        </register>
        <register>
          <name>RXCRCR</name>
          <addressOffset>0x14</addressOffset>
          <size>0x20</size>
          <fields>
            <field>
              <name>RXCRC</name>
              <bitOffset>0</bitOffset>
              <bitWidth>16</bitWidth>
            </field>
          </fields>
        </register>
        <register>
          <name>TXCRCR</name>
          <addressOffset>0x18</addressOffset>
          <size>0x20</size>
          <fields>
            <field>
              <name>TXCRC</name>
              <bitOffset>0</bitOffset>
              <bitWidth>16</bitWidth>
            </field>
          </fields>
        </register>
        <register>
          <name>I2SCFGR</name>
          <addressOffset>0x1c</addressOffset>
          <size>0x20</size>
          <fields>
            <field>
              <name>CHLEN</name>
              <bitOffset>0</bitOffset>
              <bitWidth>1</bitWidth>
            </field>
            <field>
              <name>DATLEN</name>
              <bitOffset>1</bitOffset>
              <bitWidth>2</bitWidth>
            </field>
            <field>
              <name>CKPOL</name>
              <bitOffset>3</bitOffset>
              <bitWidth>1</bitWidth>
            </field>
            <field>
              <name>I2SSTD</name>
              <bitOffset>4</bitOffset>
              <bitWidth>2</bitWidth>
            </field>
            <field>
              <name>PCMSYNC</name>
              <bitOffset>7</bitOffset>
              <bitWidth>1</bitWidth>
            </field>
            <field>
              <name>I2SCFG</name>
              <bitOffset>8</bitOffset>
              <bitWidth>2</bitWidth>
            </field>
            <field>
              <name>I2SE</name>
              <bitOffset>10</bitOffset>
              <bitWidth>1</bitWidth>
            </field>
            <field>
              <name>I2SMOD</name>
              <bitOffset>11</bitOffset>
              <bitWidth>1</bitWidth>
            </field>
            <field>
              <name>ASTRTEN</name>
              <bitOffset>12</bitOffset>
              <bitWidth>1</bitWidth>
            </field>
          </fields>
        </register>
        <register>
          <name>I2SPR</name>
          <addressOffset>0x20</addressOffset>
          <size>0x20</size>
          <fields>
            <field>
              <name>I2SDIV</name>
              <bitOffset>0</bitOffset>
              <bitWidth>8</bitWidth>
            </field>
            <field>
              <name>ODD</name>
              <bitOffset>8</bitOffset>
              <bitWidth>1</bitWidth>
            </field>
            <field>
              <name>MCKOE</name>
              <bitOffset>9</bitOffset>
              <bitWidth>1</bitWidth>
            </field>
          </fields>
        </register>
      </registers>
    </peripheral>
    <peripheral>
      <name>TIM8</name>
      <baseAddress>0x40013400</baseAddress>
      <registers>
        <register>
          <name>CR1</name>
          <addressOffset>0x0</addressOffset>
          <size>0x20</size>
          <fields>
            <field>
              <name>CEN</name>
              <bitOffset>0</bitOffset>
              <bitWidth>1</bitWidth>
            </field>
            <field>
              <name>UDIS</name>
              <bitOffset>1</bitOffset>
              <bitWidth>1</bitWidth>
            </field>
            <field>
              <name>URS</name>
              <bitOffset>2</bitOffset>
              <bitWidth>1</bitWidth>
            </field>
            <field>
              <name>OPM</name>
              <bitOffset>3</bitOffset>
              <bitWidth>1</bitWidth>
            </field>
            <field>
              <name>DIR</name>
              <bitOffset>4</bitOffset>
              <bitWidth>1</bitWidth>
            </field>
            <field>
              <name>CMS</name>
              <bitOffset>5</bitOffset>
              <bitWidth>2</bitWidth>
            </field>
            <field>
              <name>ARPE</name>
              <bitOffset>7</bitOffset>
              <bitWidth>1</bitWidth>
            </field>
            <field>
              <name>CKD</name>
              <bitOffset>8</bitOffset>
              <bitWidth>2</bitWidth>
            </field>
            <field>
              <name>UIFREMAP</name>
              <bitOffset>11</bitOffset>
              <bitWidth>1</bitWidth>
            </field>
            <field>
              <name>DITHEN</name>
              <bitOffset>12</bitOffset>
              <bitWidth>1</bitWidth>
            </field>
          </fields>
        </register>
        <register>
          <name>CR2</name>
          <addressOffset>0x4</addressOffset>
          <size>0x20</size>
          <fields>
            <field>
              <name>CCPC</name>
              <bitOffset>0</bitOffset>
              <bitWidth>1</bitWidth>
            </field>
            <field>
              <name>CCUS</name>
              <bitOffset>2</bitOffset>
              <bitWidth>1</bitWidth>
            </field>
            <field>
              <name>CCDS</name>
              <bitOffset>3</bitOffset>
              <bitWidth>1</bitWidth>
            </field>
            <field>
              <name>MMS</name>
              <bitOffset>4</bitOffset>
              <bitWidth>22</bitWidth>
            </field>
            <field>
              <name>TI1S</name>
              <bitOffset>7</bitOffset>
              <bitWidth>1</bitWidth>
            </field>
            <field>
              <name>OIS1</name>
              <bitOffset>8</bitOffset>
              <bitWidth>1</bitWidth>
            </field>
            <field>
              <name>OIS1N</name>
              <bitOffset>9</bitOffset>
              <bitWidth>1</bitWidth>
            </field>
            <field>
              <name>OIS2</name>
              <bitOffset>10</bitOffset>
              <bitWidth>1</bitWidth>
            </field>
            <field>
              <name>OIS2N</name>
              <bitOffset>11</bitOffset>
              <bitWidth>1</bitWidth>
            </field>
            <field>
              <name>OIS3</name>
              <bitOffset>12</bitOffset>
              <bitWidth>1</bitWidth>
            </field>
            <field>
              <name>OIS3N</name>
              <bitOffset>13</bitOffset>
              <bitWidth>1</bitWidth>
            </field>
            <field>
              <name>OIS4</name>
              <bitOffset>14</bitOffset>
              <bitWidth>1</bitWidth>
            </field>
            <field>
              <name>OIS4N</name>
              <bitOffset>15</bitOffset>
              <bitWidth>1</bitWidth>
            </field>
            <field>
              <name>OIS5</name>
              <bitOffset>16</bitOffset>
              <bitWidth>1</bitWidth>
            </field>
            <field>
              <name>OIS6</name>
              <bitOffset>18</bitOffset>
              <bitWidth>1</bitWidth>
            </field>
            <field>
              <name>MMS2</name>
              <bitOffset>20</bitOffset>
              <bitWidth>4</bitWidth>
            </field>
          </fields>
        </register>
        <register>
          <name>SMCR</name>
          <addressOffset>0x8</addressOffset>
          <size>0x20</size>
          <fields>
            <field>
              <name>SMS</name>
              <bitOffset>0</bitOffset>
              <bitWidth>17</bitWidth>
            </field>
            <field>
              <name>OCCS</name>
              <bitOffset>3</bitOffset>
              <bitWidth>1</bitWidth>
            </field>
            <field>
              <name>TS</name>
              <bitOffset>4</bitOffset>
              <bitWidth>18</bitWidth>
            </field>
            <field>
              <name>MSM</name>
              <bitOffset>7</bitOffset>
              <bitWidth>1</bitWidth>
            </field>
            <field>
              <name>ETF</name>
              <bitOffset>8</bitOffset>
              <bitWidth>4</bitWidth>
            </field>
            <field>
              <name>ETPS</name>
              <bitOffset>12</bitOffset>
              <bitWidth>2</bitWidth>
            </field>
            <field>
              <name>ECE</name>
              <bitOffset>14</bitOffset>
              <bitWidth>1</bitWidth>
            </field>
            <field>
              <name>ETP</name>
              <bitOffset>15</bitOffset>
              <bitWidth>1</bitWidth>
            </field>
            <field>
              <name>SMSPE</name>
              <bitOffset>24</bitOffset>
              <bitWidth>1</bitWidth>
            </field>
            <field>
              <name>SMSPS</name>
              <bitOffset>25</bitOffset>
              <bitWidth>1</bitWidth>
            </field>
          </fields>
        </register>
        <register>
          <name>DIER</name>
          <addressOffset>0xc</addressOffset>
          <size>0x20</size>
          <fields>
            <field>
              <name>UIE</name>
              <bitOffset>0</bitOffset>
              <bitWidth>1</bitWidth>
            </field>
            <field>
              <name>CC1IE</name>
              <bitOffset>1</bitOffset>
              <bitWidth>1</bitWidth>
            </field>
            <field>
              <name>CC2IE</name>
              <bitOffset>2</bitOffset>
              <bitWidth>1</bitWidth>
            </field>
            <field>
              <name>CC3IE</name>
              <bitOffset>3</bitOffset>
              <bitWidth>1</bitWidth>
            </field>
            <field>
              <name>CC4IE</name>
              <bitOffset>4</bitOffset>
              <bitWidth>1</bitWidth>
            </field>
            <field>
              <name>COMIE</name>
              <bitOffset>5</bitOffset>
              <bitWidth>1</bitWidth>
            </field>
            <field>
              <name>TIE</name>
              <bitOffset>6</bitOffset>
              <bitWidth>1</bitWidth>
            </field>
            <field>
              <name>BIE</name>
              <bitOffset>7</bitOffset>
              <bitWidth>1</bitWidth>
            </field>
            <field>
              <name>UDE</name>
              <bitOffset>8</bitOffset>
              <bitWidth>1</bitWidth>
            </field>
            <field>
              <name>CC1DE</name>
              <bitOffset>9</bitOffset>
              <bitWidth>1</bitWidth>
            </field>
            <field>
              <name>CC2DE</name>
              <bitOffset>10</bitOffset>
              <bitWidth>1</bitWidth>
            </field>
            <field>
              <name>CC3DE</name>
              <bitOffset>11</bitOffset>
              <bitWidth>1</bitWidth>
            </field>
            <field>
              <name>CC4DE</name>
              <bitOffset>12</bitOffset>
              <bitWidth>1</bitWidth>
            </field>
            <field>
              <name>COMDE</name>
              <bitOffset>13</bitOffset>
              <bitWidth>1</bitWidth>
            </field>
            <field>
              <name>TDE</name>
              <bitOffset>14</bitOffset>
              <bitWidth>1</bitWidth>
            </field>
            <field>
              <name>IDXIE</name>
              <bitOffset>20</bitOffset>
              <bitWidth>1</bitWidth>
            </field>
            <field>
              <name>DIRIE</name>
              <bitOffset>21</bitOffset>
              <bitWidth>1</bitWidth>
            </field>
            <field>
              <name>IERRIE</name>
              <bitOffset>22</bitOffset>
              <bitWidth>1</bitWidth>
            </field>
            <field>
              <name>TERRIE</name>
              <bitOffset>23</bitOffset>
              <bitWidth>1</bitWidth>
            </field>
          </fields>
        </register>
        <register>
          <name>SR</name>
          <addressOffset>0x10</addressOffset>
          <size>0x20</size>
          <fields>
            <field>
              <name>UIF</name>
              <bitOffset>0</bitOffset>
              <bitWidth>1</bitWidth>
            </field>
            <field>
              <name>CC1IF</name>
              <bitOffset>1</bitOffset>
              <bitWidth>1</bitWidth>
            </field>
            <field>
              <name>CC2IF</name>
              <bitOffset>2</bitOffset>
              <bitWidth>1</bitWidth>
            </field>
            <field>
              <name>CC3IF</name>
              <bitOffset>3</bitOffset>
              <bitWidth>1</bitWidth>
            </field>
            <field>
              <name>CC4IF</name>
              <bitOffset>4</bitOffset>
              <bitWidth>1</bitWidth>
            </field>
            <field>
              <name>COMIF</name>
              <bitOffset>5</bitOffset>
              <bitWidth>1</bitWidth>
            </field>
            <field>
              <name>TIF</name>
              <bitOffset>6</bitOffset>
              <bitWidth>1</bitWidth>
            </field>
            <field>
              <name>BIF</name>
              <bitOffset>7</bitOffset>
              <bitWidth>1</bitWidth>
            </field>
            <field>
              <name>B2IF</name>
              <bitOffset>8</bitOffset>
              <bitWidth>1</bitWidth>
            </field>
            <field>
              <name>CC1OF</name>
              <bitOffset>9</bitOffset>
              <bitWidth>1</bitWidth>
            </field>
            <field>
              <name>CC2OF</name>
              <bitOffset>10</bitOffset>
              <bitWidth>1</bitWidth>
            </field>
            <field>
              <name>CC3OF</name>
              <bitOffset>11</bitOffset>
              <bitWidth>1</bitWidth>
            </field>
            <field>
              <name>CC4OF</name>
              <bitOffset>12</bitOffset>
              <bitWidth>1</bitWidth>
            </field>
            <field>
              <name>SBIF</name>
              <bitOffset>13</bitOffset>
              <bitWidth>1</bitWidth>
            </field>
            <field>
              <name>CC5IF</name>
              <bitOffset>16</bitOffset>
              <bitWidth>1</bitWidth>
            </field>
            <field>
              <name>CC6IF</name>
              <bitOffset>17</bitOffset>
              <bitWidth>1</bitWidth>
            </field>
            <field>
              <name>IDXF</name>
              <bitOffset>20</bitOffset>
              <bitWidth>1</bitWidth>
            </field>
            <field>
              <name>DIRF</name>
              <bitOffset>21</bitOffset>
              <bitWidth>1</bitWidth>
            </field>
            <field>
              <name>IERRF</name>
              <bitOffset>22</bitOffset>
              <bitWidth>1</bitWidth>
            </field>
            <field>
              <name>TERRF</name>
              <bitOffset>23</bitOffset>
              <bitWidth>1</bitWidth>
            </field>
          </fields>
        </register>
        <register>
          <name>EGR</name>
          <addressOffset>0x14</addressOffset>
          <size>0x20</size>
          <fields>
            <field>
              <name>UG</name>
              <bitOffset>0</bitOffset>
              <bitWidth>1</bitWidth>
            </field>
            <field>
              <name>CC1G</name>
              <bitOffset>1</bitOffset>
              <bitWidth>1</bitWidth>
            </field>
            <field>
              <name>CC2G</name>
              <bitOffset>2</bitOffset>
              <bitWidth>1</bitWidth>
            </field>
            <field>
              <name>CC3G</name>
              <bitOffset>3</bitOffset>
              <bitWidth>1</bitWidth>
            </field>
            <field>
              <name>CC4G</name>
              <bitOffset>4</bitOffset>
              <bitWidth>1</bitWidth>
            </field>
            <field>
              <name>COMG</name>
              <bitOffset>5</bitOffset>
              <bitWidth>1</bitWidth>
            </field>
            <field>
              <name>TG</name>
              <bitOffset>6</bitOffset>
              <bitWidth>1</bitWidth>
            </field>
            <field>
              <name>BG</name>
              <bitOffset>7</bitOffset>
              <bitWidth>1</bitWidth>
            </field>
            <field>
              <name>B2G</name>
              <bitOffset>8</bitOffset>
              <bitWidth>1</bitWidth>
            </field>
          </fields>
        </register>
        <register>
          <name>CCMR1</name>
          <addressOffset>0x18</addressOffset>
          <size>0x20</size>
          <fields>
            <field>
              <name>CC1S</name>
              <bitOffset>0</bitOffset>
              <bitWidth>2</bitWidth>
            </field>
            <field>
              <name>OC1FE</name>
              <bitOffset>2</bitOffset>
              <bitWidth>1</bitWidth>
            </field>
            <field>
              <name>OC1PE</name>
              <bitOffset>3</bitOffset>
              <bitWidth>1</bitWidth>
            </field>
            <field>
              <name>OC1M</name>
              <bitOffset>4</bitOffset>
              <bitWidth>13</bitWidth>
            </field>
            <field>
              <name>OC1CE</name>
              <bitOffset>7</bitOffset>
              <bitWidth>1</bitWidth>
            </field>
            <field>
              <name>CC2S</name>
              <bitOffset>8</bitOffset>
              <bitWidth>2</bitWidth>
            </field>
            <field>
              <name>OC2FE</name>
              <bitOffset>10</bitOffset>
              <bitWidth>1</bitWidth>
            </field>
            <field>
              <name>OC2PE</name>
              <bitOffset>11</bitOffset>
              <bitWidth>1</bitWidth>
            </field>
            <field>
              <name>OC2M</name>
              <bitOffset>12</bitOffset>
              <bitWidth>13</bitWidth>
            </field>
            <field>
              <name>OC2CE</name>
              <bitOffset>15</bitOffset>
              <bitWidth>1</bitWidth>
            </field>
          </fields>
        </register>
        <register>
          <name>CCMR2</name>
          <addressOffset>0x1c</addressOffset>
          <size>0x20</size>
          <fields>
            <field>
              <name>CC3S</name>
              <bitOffset>0</bitOffset>
              <bitWidth>2</bitWidth>
            </field>
            <field>
              <name>OC3FE</name>
              <bitOffset>2</bitOffset>
              <bitWidth>1</bitWidth>
            </field>
            <field>
              <name>OC3PE</name>
              <bitOffset>3</bitOffset>
              <bitWidth>1</bitWidth>
            </field>
            <field>
              <name>OC3M</name>
              <bitOffset>4</bitOffset>
              <bitWidth>13</bitWidth>
            </field>
            <field>
              <name>OC3CE</name>
              <bitOffset>7</bitOffset>
              <bitWidth>1</bitWidth>
            </field>
            <field>
              <name>CC4S</name>
              <bitOffset>8</bitOffset>
              <bitWidth>2</bitWidth>
            </field>
            <field>
              <name>OC4FE</name>
              <bitOffset>10</bitOffset>
              <bitWidth>1</bitWidth>
            </field>
            <field>
              <name>OC4PE</name>
              <bitOffset>11</bitOffset>
              <bitWidth>1</bitWidth>
            </field>
            <field>
              <name>OC4M</name>
              <bitOffset>12</bitOffset>
              <bitWidth>13</bitWidth>
            </field>
            <field>
              <name>OC4CE</name>
              <bitOffset>15</bitOffset>
              <bitWidth>1</bitWidth>
            </field>
          </fields>
        </register>
        <register>
          <name>CCER</name>
          <addressOffset>0x20</addressOffset>
          <size>0x20</size>
          <fields>
            <field>
              <name>CC1E</name>
              <bitOffset>0</bitOffset>
              <bitWidth>1</bitWidth>
            </field>
            <field>
              <name>CC1P</name>
              <bitOffset>1</bitOffset>
              <bitWidth>1</bitWidth>
            </field>
            <field>
              <name>CC1NE</name>
              <bitOffset>2</bitOffset>
              <bitWidth>1</bitWidth>
            </field>
            <field>
              <name>CC1NP</name>
              <bitOffset>3</bitOffset>
              <bitWidth>1</bitWidth>
            </field>
            <field>
              <name>CC2E</name>
              <bitOffset>4</bitOffset>
              <bitWidth>1</bitWidth>
            </field>
            <field>
              <name>CC2P</name>
              <bitOffset>5</bitOffset>
              <bitWidth>1</bitWidth>
            </field>
            <field>
              <name>CC2NE</name>
              <bitOffset>6</bitOffset>
              <bitWidth>1</bitWidth>
            </field>
            <field>
              <name>CC2NP</name>
              <bitOffset>7</bitOffset>
              <bitWidth>1</bitWidth>
            </field>
            <field>
              <name>CC3E</name>
              <bitOffset>8</bitOffset>
              <bitWidth>1</bitWidth>
            </field>
            <field>
              <name>CC3P</name>
              <bitOffset>9</bitOffset>
              <bitWidth>1</bitWidth>
            </field>
            <field>
              <name>CC3NE</name>
              <bitOffset>10</bitOffset>
              <bitWidth>1</bitWidth>
            </field>
            <field>
              <name>CC3NP</name>
              <bitOffset>11</bitOffset>
              <bitWidth>1</bitWidth>
            </field>
            <field>
              <name>CC4E</name>
              <bitOffset>12</bitOffset>
              <bitWidth>1</bitWidth>
            </field>
            <field>
              <name>CC4P</name>
              <bitOffset>13</bitOffset>
              <bitWidth>1</bitWidth>
            </field>
            <field>
              <name>CC4NE</name>
              <bitOffset>14</bitOffset>
              <bitWidth>1</bitWidth>
            </field>
            <field>
              <name>CC4NP</name>
              <bitOffset>15</bitOffset>
              <bitWidth>1</bitWidth>
            </field>
            <field>
              <name>CC5E</name>
              <bitOffset>16</bitOffset>
              <bitWidth>1</bitWidth>
            </field>
            <field>
              <name>CC5P</name>
              <bitOffset>17</bitOffset>
              <bitWidth>1</bitWidth>
            </field>
            <field>
              <name>CC6E</name>
              <bitOffset>20</bitOffset>
              <bitWidth>1</bitWidth>
            </field>
            <field>
              <name>CC6P</name>
              <bitOffset>21</bitOffset>
              <bitWidth>1</bitWidth>
            </field>
          </fields>
        </register>
        <register>
          <name>CNT</name>
          <addressOffset>0x24</addressOffset>
          <size>0x20</size>
          <fields>
            <field>
              <name>CNT</name>
              <bitOffset>0</bitOffset>
              <bitWidth>32</bitWidth>
            </field>
            <field>
              <name>UIFCPY</name>
              <bitOffset>31</bitOffset>
              <bitWidth>1</bitWidth>
            </field>
          </fields>
        </register>
        <register>
          <name>PSC</name>
          <addressOffset>0x28</addressOffset>
          <size>0x20</size>
          <fields>
            <field>
              <name>PSC</name>
              <bitOffset>0</bitOffset>
              <bitWidth>16</bitWidth>
            </field>
          </fields>
        </register>
        <register>
          <name>ARR</name>
          <addressOffset>0x2c</addressOffset>
          <size>0x20</size>
          <fields>
            <field>
              <name>ARR</name>
              <bitOffset>0</bitOffset>
              <bitWidth>32</bitWidth>
            </field>
          </fields>
        </register>
        <register>
          <name>RCR</name>
          <addressOffset>0x30</addressOffset>
          <size>0x20</size>
          <fields>
            <field>
              <name>REP</name>
              <bitOffset>0</bitOffset>
              <bitWidth>16</bitWidth>
            </field>
          </fields>
        </register>
        <register>
          <name>CCR1</name>
          <addressOffset>0x34</addressOffset>
          <size>0x20</size>
          <fields>
            <field>
              <name>CCR1</name>
              <bitOffset>0</bitOffset>
              <bitWidth>16</bitWidth>
            </field>
          </fields>
        </register>
        <register>
          <name>CCR2</name>
          <addressOffset>0x38</addressOffset>
          <size>0x20</size>
          <fields>
            <field>
              <name>CCR2</name>
              <bitOffset>0</bitOffset>
              <bitWidth>16</bitWidth>
            </field>
          </fields>
        </register>
        <register>
          <name>CCR3</name>
          <addressOffset>0x3c</addressOffset>
          <size>0x20</size>
          <fields>
            <field>
              <name>CCR3</name>
              <bitOffset>0</bitOffset>
              <bitWidth>16</bitWidth>
            </field>
          </fields>
        </register>
        <register>
          <name>CCR4</name>
          <addressOffset>0x40</addressOffset>
          <size>0x20</size>
          <fields>
            <field>
              <name>CCR4</name>
              <bitOffset>0</bitOffset>
              <bitWidth>16</bitWidth>
            </field>
          </fields>
        </register>
        <register>
          <name>BDTR</name>
          <addressOffset>0x44</addressOffset>
          <size>0x20</size>
          <fields>
            <field>
              <name>DTG</name>
              <bitOffset>0</bitOffset>
              <bitWidth>8</bitWidth>
            </field>
            <field>
              <name>LOCK</name>
              <bitOffset>8</bitOffset>
              <bitWidth>2</bitWidth>
            </field>
            <field>
              <name>OSSI</name>
              <bitOffset>10</bitOffset>
              <bitWidth>1</bitWidth>
            </field>
            <field>
              <name>OSSR</name>
              <bitOffset>11</bitOffset>
              <bitWidth>1</bitWidth>
            </field>
            <field>
              <name>BKE</name>
              <bitOffset>12</bitOffset>
              <bitWidth>1</bitWidth>
            </field>
            <field>
              <name>BKP</name>
              <bitOffset>13</bitOffset>
              <bitWidth>1</bitWidth>
            </field>
            <field>
              <name>AOE</name>
              <bitOffset>14</bitOffset>
              <bitWidth>1</bitWidth>
            </field>
            <field>
              <name>MOE</name>
              <bitOffset>15</bitOffset>
              <bitWidth>1</bitWidth>
            </field>
            <field>
              <name>BKF</name>
              <bitOffset>16</bitOffset>
              <bitWidth>4</bitWidth>
            </field>
            <field>
              <name>BK2F</name>
              <bitOffset>20</bitOffset>
              <bitWidth>4</bitWidth>
            </field>
            <field>
              <name>BK2E</name>
              <bitOffset>24</bitOffset>
              <bitWidth>1</bitWidth>
            </field>
            <field>
              <name>BK2P</name>
              <bitOffset>25</bitOffset>
              <bitWidth>1</bitWidth>
            </field>
            <field>
              <name>BKDSRM</name>
              <bitOffset>26</bitOffset>
              <bitWidth>1</bitWidth>
            </field>
            <field>
              <name>BK2DSRM</name>
              <bitOffset>27</bitOffset>
              <bitWidth>1</bitWidth>
            </field>
            <field>
              <name>BKBID</name>
              <bitOffset>28</bitOffset>
              <bitWidth>1</bitWidth>
            </field>
            <field>
              <name>BK2BID</name>
              <bitOffset>29</bitOffset>
              <bitWidth>1</bitWidth>
            </field>
          </fields>
        </register>
        <register>
          <name>CCR5</name>
          <addressOffset>0x48</addressOffset>
          <size>0x20</size>
          <fields>
            <field>
              <name>CCR5</name>
              <bitOffset>0</bitOffset>
              <bitWidth>32</bitWidth>
            </field>
            <field>
              <name>GC5C1</name>
              <bitOffset>29</bitOffset>
              <bitWidth>1</bitWidth>
            </field>
            <field>
              <name>GC5C2</name>
              <bitOffset>30</bitOffset>
              <bitWidth>1</bitWidth>
            </field>
            <field>
              <name>GC5C3</name>
              <bitOffset>31</bitOffset>
              <bitWidth>1</bitWidth>
            </field>
          </fields>
        </register>
        <register>
          <name>CCR6</name>
          <addressOffset>0x4c</addressOffset>
          <size>0x20</size>
          <fields>
            <field>
              <name>CCR6</name>
              <bitOffset>0</bitOffset>
              <bitWidth>16</bitWidth>
            </field>
          </fields>
        </register>
        <register>
          <name>CCMR3</name>
          <addressOffset>0x50</addressOffset>
          <size>0x20</size>
          <fields>
            <field>
              <name>OC5FE</name>
              <bitOffset>2</bitOffset>
              <bitWidth>1</bitWidth>
            </field>
            <field>
              <name>OC5PE</name>
              <bitOffset>3</bitOffset>
              <bitWidth>1</bitWidth>
            </field>
            <field>
              <name>OC5M</name>
              <bitOffset>4</bitOffset>
              <bitWidth>13</bitWidth>
            </field>
            <field>
              <name>OC5CE</name>
              <bitOffset>7</bitOffset>
              <bitWidth>1</bitWidth>
            </field>
            <field>
              <name>OC6FE</name>
              <bitOffset>10</bitOffset>
              <bitWidth>1</bitWidth>
            </field>
            <field>
              <name>OC6PE</name>
              <bitOffset>11</bitOffset>
              <bitWidth>1</bitWidth>
            </field>
            <field>
              <name>OC6M</name>
              <bitOffset>12</bitOffset>
              <bitWidth>13</bitWidth>
            </field>
            <field>
              <name>OC6CE</name>
              <bitOffset>15</bitOffset>
              <bitWidth>1</bitWidth>
            </field>
          </fields>
        </register>
        <register>
          <name>DTR2</name>
          <addressOffset>0x54</addressOffset>
          <size>0x20</size>
          <fields>
            <field>
              <name>DTGF</name>
              <bitOffset>0</bitOffset>
              <bitWidth>8</bitWidth>
            </field>
            <field>
              <name>DTAE</name>
              <bitOffset>16</bitOffset>
              <bitWidth>1</bitWidth>
            </field>
            <field>
              <name>DTPE</name>
              <bitOffset>17</bitOffset>
              <bitWidth>1</bitWidth>
            </field>
          </fields>
        </register>
        <register>
          <name>ECR</name>
          <addressOffset>0x58</addressOffset>
          <size>0x20</size>
          <fields>
            <field>
              <name>IE</name>
              <bitOffset>0</bitOffset>
              <bitWidth>1</bitWidth>
            </field>
            <field>
              <name>IDIR</name>
              <bitOffset>1</bitOffset>
              <bitWidth>2</bitWidth>
            </field>
            <field>
              <name>FIDX</name>
              <bitOffset>5</bitOffset>
              <bitWidth>1</bitWidth>
            </field>
            <field>
              <name>IPOS</name>
              <bitOffset>6</bitOffset>
              <bitWidth>2</bitWidth>
            </field>
            <field>
              <name>PW</name>
              <bitOffset>16</bitOffset>
              <bitWidth>8</bitWidth>
            </field>
            <field>
              <name>PWPRSC</name>
              <bitOffset>24</bitOffset>
              <bitWidth>3</bitWidth>
            </field>
          </fields>
        </register>
        <register>
          <name>TISEL</name>
          <addressOffset>0x5c</addressOffset>
          <size>0x20</size>
          <fields>
            <field>
              <name>TI1SEL</name>
              <bitOffset>0</bitOffset>
              <bitWidth>4</bitWidth>
            </field>
            <field>
              <name>TI2SEL</name>
              <bitOffset>8</bitOffset>
              <bitWidth>4</bitWidth>
            </field>
            <field>
              <name>TI3SEL</name>
              <bitOffset>16</bitOffset>
              <bitWidth>4</bitWidth>
            </field>
            <field>
              <name>TI4SEL</name>
              <bitOffset>24</bitOffset>
              <bitWidth>4</bitWidth>
            </field>
          </fields>
        </register>
        <register>
          <name>AF1</name>
          <addressOffset>0x60</addressOffset>
          <size>0x20</size>
        </register>
        <register>
          <name>AF2</name>
          <addressOffset>0x64</addressOffset>
          <size>0x20</size>
        </register>
        <register>
          <name>OR</name>
          <addressOffset>0x68</addressOffset>
          <size>0x20</size>
          <fields>
            <field>
              <name>HSE32EN</name>
              <bitOffset>0</bitOffset>
              <bitWidth>1</bitWidth>
            </field>
          </fields>
        </register>
        <register>
          <name>DCR</name>
          <addressOffset>0x3dc</addressOffset>
          <size>0x20</size>
          <fields>
            <field>
              <name>DBA</name>
              <bitOffset>0</bitOffset>
              <bitWidth>5</bitWidth>
            </field>
            <field>
              <name>DBL</name>
              <bitOffset>8</bitOffset>
              <bitWidth>5</bitWidth>
            </field>
          </fields>
        </register>
        <register>
          <name>DMAR</name>
          <addressOffset>0x3e0</addressOffset>
          <size>0x20</size>
          <fields>
            <field>
              <name>DMAB</name>
              <bitOffset>0</bitOffset>
              <bitWidth>32</bitWidth>
            </field>
          </fields>
        </register>
      </registers>
    </peripheral>
    <peripheral>
      <name>USART1</name>
      <baseAddress>0x40013800</baseAddress>
      <registers>
        <register>
          <name>CR1</name>
          <addressOffset>0x0</addressOffset>
          <size>0x20</size>
          <fields>
            <field>
              <name>UE</name>
              <bitOffset>0</bitOffset>
              <bitWidth>1</bitWidth>
            </field>
            <field>
              <name>UESM</name>
              <bitOffset>1</bitOffset>
              <bitWidth>1</bitWidth>
            </field>
            <field>
              <name>RE</name>
              <bitOffset>2</bitOffset>
              <bitWidth>1</bitWidth>
            </field>
            <field>
              <name>TE</name>
              <bitOffset>3</bitOffset>
              <bitWidth>1</bitWidth>
            </field>
            <field>
              <name>IDLEIE</name>
              <bitOffset>4</bitOffset>
              <bitWidth>1</bitWidth>
            </field>
            <field>
              <name>RXNEIE_RXFNEIE</name>
              <bitOffset>5</bitOffset>
              <bitWidth>1</bitWidth>
            </field>
            <field>
              <name>TCIE</name>
              <bitOffset>6</bitOffset>
              <bitWidth>1</bitWidth>
            </field>
            <field>
              <name>TXEIE_TXFNFIE</name>
              <bitOffset>7</bitOffset>
              <bitWidth>1</bitWidth>
            </field>
            <field>
              <name>PEIE</name>
              <bitOffset>8</bitOffset>
              <bitWidth>1</bitWidth>
            </field>
            <field>
              <name>PS</name>
              <bitOffset>9</bitOffset>
              <bitWidth>1</bitWidth>
            </field>
            <field>
              <name>PCE</name>
              <bitOffset>10</bitOffset>
              <bitWidth>1</bitWidth>
            </field>
            <field>
              <name>WAKE</name>
              <bitOffset>11</bitOffset>
              <bitWidth>1</bitWidth>
            </field>
            <field>
              <name>M0</name>
              <bitOffset>12</bitOffset>
              <bitWidth>1</bitWidth>
            </field>
            <field>
              <name>MME</name>
              <bitOffset>13</bitOffset>
              <bitWidth>1</bitWidth>
            </field>
            <field>
              <name>CMIE</name>
              <bitOffset>14</bitOffset>
              <bitWidth>1</bitWidth>
            </field>
            <field>
              <name>OVER8</name>
              <bitOffset>15</bitOffset>
              <bitWidth>1</bitWidth>
            </field>
            <field>
              <name>DEDT</name>
              <bitOffset>16</bitOffset>
              <bitWidth>5</bitWidth>
            </field>
            <field>
              <name>DEAT</name>
              <bitOffset>21</bitOffset>
              <bitWidth>5</bitWidth>
            </field>
            <field>
              <name>RTOIE</name>
              <bitOffset>26</bitOffset>
              <bitWidth>1</bitWidth>
            </field>
            <field>
              <name>EOBIE</name>
              <bitOffset>27</bitOffset>
              <bitWidth>1</bitWidth>
            </field>
            <field>
              <name>M1</name>
              <bitOffset>28</bitOffset>
              <bitWidth>1</bitWidth>
            </field>
            <field>
              <name>FIFOEN</name>
              <bitOffset>29</bitOffset>
              <bitWidth>1</bitWidth>
            </field>
            <field>
              <name>TXFEIE</name>
              <bitOffset>30</bitOffset>
              <bitWidth>1</bitWidth>
            </field>
            <field>
              <name>RXFFIE</name>
              <bitOffset>31</bitOffset>
              <bitWidth>1</bitWidth>
            </field>
          </fields>
        </register>
        <register>
          <name>CR2</name>
          <addressOffset>0x4</addressOffset>
          <size>0x20</size>
          <fields>
            <field>
              <name>SLVEN</name>
              <bitOffset>0</bitOffset>
              <bitWidth>1</bitWidth>
            </field>
            <field>
              <name>DIS_NSS</name>
              <bitOffset>3</bitOffset>
              <bitWidth>1</bitWidth>
            </field>
            <field>
              <name>ADDM7</name>
              <bitOffset>4</bitOffset>
              <bitWidth>1</bitWidth>
            </field>
            <field>
              <name>LBDL</name>
              <bitOffset>5</bitOffset>
              <bitWidth>1</bitWidth>
            </field>
            <field>
              <name>LBDIE</name>
              <bitOffset>6</bitOffset>
              <bitWidth>1</bitWidth>
            </field>
            <field>
              <name>LBCL</name>
              <bitOffset>8</bitOffset>
              <bitWidth>1</bitWidth>
            </field>
            <field>
              <name>CPHA</name>
              <bitOffset>9</bitOffset>
              <bitWidth>1</bitWidth>
            </field>
            <field>
              <name>CPOL</name>
              <bitOffset>10</bitOffset>
              <bitWidth>1</bitWidth>
            </field>
            <field>
              <name>CLKEN</name>
              <bitOffset>11</bitOffset>
              <bitWidth>1</bitWidth>
            </field>
            <field>
              <name>STOP</name>
              <bitOffset>12</bitOffset>
              <bitWidth>2</bitWidth>
            </field>
            <field>
              <name>LINEN</name>
              <bitOffset>14</bitOffset>
              <bitWidth>1</bitWidth>
            </field>
            <field>
              <name>SWAP</name>
              <bitOffset>15</bitOffset>
              <bitWidth>1</bitWidth>
            </field>
            <field>
              <name>RXINV</name>
              <bitOffset>16</bitOffset>
              <bitWidth>1</bitWidth>
            </field>
            <field>
              <name>TXINV</name>
              <bitOffset>17</bitOffset>
              <bitWidth>1</bitWidth>
            </field>
            <field>
              <name>DATAINV</name>
              <bitOffset>18</bitOffset>
              <bitWidth>1</bitWidth>
            </field>
            <field>
              <name>MSBFIRST</name>
              <bitOffset>19</bitOffset>
              <bitWidth>1</bitWidth>
            </field>
            <field>
              <name>ABREN</name>
              <bitOffset>20</bitOffset>
              <bitWidth>1</bitWidth>
            </field>
            <field>
              <name>ABRMODE</name>
              <bitOffset>21</bitOffset>
              <bitWidth>2</bitWidth>
            </field>
            <field>
              <name>RTOEN</name>
              <bitOffset>23</bitOffset>
              <bitWidth>1</bitWidth>
            </field>
            <field>
              <name>ADD</name>
              <bitOffset>24</bitOffset>
              <bitWidth>8</bitWidth>
            </field>
          </fields>
        </register>
        <register>
          <name>CR3</name>
          <addressOffset>0x8</addressOffset>
          <size>0x20</size>
          <fields>
            <field>
              <name>EIE</name>
              <bitOffset>0</bitOffset>
              <bitWidth>1</bitWidth>
            </field>
            <field>
              <name>IREN</name>
              <bitOffset>1</bitOffset>
              <bitWidth>1</bitWidth>
            </field>
            <field>
              <name>IRLP</name>
              <bitOffset>2</bitOffset>
              <bitWidth>1</bitWidth>
            </field>
            <field>
              <name>HDSEL</name>
              <bitOffset>3</bitOffset>
              <bitWidth>1</bitWidth>
            </field>
            <field>
              <name>NACK</name>
              <bitOffset>4</bitOffset>
              <bitWidth>1</bitWidth>
            </field>
            <field>
              <name>SCEN</name>
              <bitOffset>5</bitOffset>
              <bitWidth>1</bitWidth>
            </field>
            <field>
              <name>DMAR</name>
              <bitOffset>6</bitOffset>
              <bitWidth>1</bitWidth>
            </field>
            <field>
              <name>DMAT</name>
              <bitOffset>7</bitOffset>
              <bitWidth>1</bitWidth>
            </field>
            <field>
              <name>RTSE</name>
              <bitOffset>8</bitOffset>
              <bitWidth>1</bitWidth>
            </field>
            <field>
              <name>CTSE</name>
              <bitOffset>9</bitOffset>
              <bitWidth>1</bitWidth>
            </field>
            <field>
              <name>CTSIE</name>
              <bitOffset>10</bitOffset>
              <bitWidth>1</bitWidth>
            </field>
            <field>
              <name>ONEBIT</name>
              <bitOffset>11</bitOffset>
              <bitWidth>1</bitWidth>
            </field>
            <field>
              <name>OVRDIS</name>
              <bitOffset>12</bitOffset>
              <bitWidth>1</bitWidth>
            </field>
            <field>
              <name>DDRE</name>
              <bitOffset>13</bitOffset>
              <bitWidth>1</bitWidth>
            </field>
            <field>
              <name>DEM</name>
              <bitOffset>14</bitOffset>
              <bitWidth>1</bitWidth>
            </field>
            <field>
              <name>DEP</name>
              <bitOffset>15</bitOffset>
              <bitWidth>1</bitWidth>
            </field>
            <field>
              <name>SCARCNT</name>
              <bitOffset>17</bitOffset>
              <bitWidth>3</bitWidth>
            </field>
            <field>
              <name>WUS</name>
              <bitOffset>20</bitOffset>
              <bitWidth>2</bitWidth>
            </field>
            <field>
              <name>WUFIE</name>
              <bitOffset>22</bitOffset>
              <bitWidth>1</bitWidth>
            </field>
            <field>
              <name>TXFTIE</name>
              <bitOffset>23</bitOffset>
              <bitWidth>1</bitWidth>
            </field>
            <field>
              <name>TCBGTIE</name>
              <bitOffset>24</bitOffset>
              <bitWidth>1</bitWidth>
            </field>
            <field>
              <name>RXFTCFG</name>
              <bitOffset>25</bitOffset>
              <bitWidth>3</bitWidth>
            </field>
            <field>
              <name>RXFTIE</name>
              <bitOffset>28</bitOffset>
              <bitWidth>1</bitWidth>
            </field>
            <field>
              <name>TXFTCFG</name>
              <bitOffset>29</bitOffset>
              <bitWidth>3</bitWidth>
            </field>
          </fields>
        </register>
        <register>
          <name>BRR</name>
          <addressOffset>0xc</addressOffset>
          <size>0x20</size>
          <fields>
            <field>
              <name>LPUART</name>
              <bitOffset>0</bitOffset>
              <bitWidth>20</bitWidth>
            </field>
          </fields>
        </register>
        <register>
          <name>GTPR</name>
          <addressOffset>0x10</addressOffset>
          <size>0x20</size>
          <fields>
            <field>
              <name>PSC</name>
              <bitOffset>0</bitOffset>
              <bitWidth>8</bitWidth>
            </field>
            <field>
              <name>GT</name>
              <bitOffset>8</bitOffset>
              <bitWidth>8</bitWidth>
            </field>
          </fields>
        </register>
        <register>
          <name>RTOR</name>
          <addressOffset>0x14</addressOffset>
          <size>0x20</size>
          <fields>
            <field>
              <name>RTO</name>
              <bitOffset>0</bitOffset>
              <bitWidth>24</bitWidth>
            </field>
            <field>
              <name>BLEN</name>
              <bitOffset>24</bitOffset>
              <bitWidth>8</bitWidth>
            </field>
          </fields>
        </register>
        <register>
          <name>RQR</name>
          <addressOffset>0x18</addressOffset>
          <size>0x20</size>
          <fields>
            <field>
              <name>ABRRQ</name>
              <bitOffset>0</bitOffset>
              <bitWidth>1</bitWidth>
            </field>
            <field>
              <name>SBKRQ</name>
              <bitOffset>1</bitOffset>
              <bitWidth>1</bitWidth>
            </field>
            <field>
              <name>MMRQ</name>
              <bitOffset>2</bitOffset>
              <bitWidth>1</bitWidth>
            </field>
            <field>
              <name>RXFRQ</name>
              <bitOffset>3</bitOffset>
              <bitWidth>1</bitWidth>
            </field>
            <field>
              <name>TXFRQ</name>
              <bitOffset>4</bitOffset>
              <bitWidth>1</bitWidth>
            </field>
          </fields>
        </register>
        <register>
          <name>ISR</name>
          <addressOffset>0x1c</addressOffset>
          <size>0x20</size>
          <fields>
            <field>
              <name>PE</name>
              <bitOffset>0</bitOffset>
              <bitWidth>1</bitWidth>
            </field>
            <field>
              <name>FE</name>
              <bitOffset>1</bitOffset>
              <bitWidth>1</bitWidth>
            </field>
            <field>
              <name>NE</name>
              <bitOffset>2</bitOffset>
              <bitWidth>1</bitWidth>
            </field>
            <field>
              <name>ORE</name>
              <bitOffset>3</bitOffset>
              <bitWidth>1</bitWidth>
            </field>
            <field>
              <name>IDLE</name>
              <bitOffset>4</bitOffset>
              <bitWidth>1</bitWidth>
            </field>
            <field>
              <name>RXNE_RXFNE</name>
              <bitOffset>5</bitOffset>
              <bitWidth>1</bitWidth>
            </field>
            <field>
              <name>TC</name>
              <bitOffset>6</bitOffset>
              <bitWidth>1</bitWidth>
            </field>
            <field>
              <name>TXE_TXFNF</name>
              <bitOffset>7</bitOffset>
              <bitWidth>1</bitWidth>
            </field>
            <field>
              <name>LBDF</name>
              <bitOffset>8</bitOffset>
              <bitWidth>1</bitWidth>
            </field>
            <field>
              <name>CTSIF</name>
              <bitOffset>9</bitOffset>
              <bitWidth>1</bitWidth>
            </field>
            <field>
              <name>CTS</name>
              <bitOffset>10</bitOffset>
              <bitWidth>1</bitWidth>
            </field>
            <field>
              <name>RTOF</name>
              <bitOffset>11</bitOffset>
              <bitWidth>1</bitWidth>
            </field>
            <field>
              <name>EOBF</name>
              <bitOffset>12</bitOffset>
              <bitWidth>1</bitWidth>
            </field>
            <field>
              <name>UDR</name>
              <bitOffset>13</bitOffset>
              <bitWidth>1</bitWidth>
            </field>
            <field>
              <name>ABRE</name>
              <bitOffset>14</bitOffset>
              <bitWidth>1</bitWidth>
            </field>
            <field>
              <name>ABRF</name>
              <bitOffset>15</bitOffset>
              <bitWidth>1</bitWidth>
            </field>
            <field>
              <name>BUSY</name>
              <bitOffset>16</bitOffset>
              <bitWidth>1</bitWidth>
            </field>
            <field>
              <name>CMF</name>
              <bitOffset>17</bitOffset>
              <bitWidth>1</bitWidth>
            </field>
            <field>
              <name>SBKF</name>
              <bitOffset>18</bitOffset>
              <bitWidth>1</bitWidth>
            </field>
            <field>
              <name>RWU</name>
              <bitOffset>19</bitOffset>
              <bitWidth>1</bitWidth>
            </field>
            <field>
              <name>WUF</name>
              <bitOffset>20</bitOffset>
              <bitWidth>1</bitWidth>
            </field>
            <field>
              <name>TEACK</name>
              <bitOffset>21</bitOffset>
              <bitWidth>1</bitWidth>
            </field>
            <field>
              <name>REACK</name>
              <bitOffset>22</bitOffset>
              <bitWidth>1</bitWidth>
            </field>
            <field>
              <name>TXFE</name>
              <bitOffset>23</bitOffset>
              <bitWidth>1</bitWidth>
            </field>
            <field>
              <name>RXFF</name>
              <bitOffset>24</bitOffset>
              <bitWidth>1</bitWidth>
            </field>
            <field>
              <name>TCBGT</name>
              <bitOffset>25</bitOffset>
              <bitWidth>1</bitWidth>
            </field>
            <field>
              <name>RXFT</name>
              <bitOffset>26</bitOffset>
              <bitWidth>1</bitWidth>
            </field>
            <field>
              <name>TXFT</name>
              <bitOffset>27</bitOffset>
              <bitWidth>1</bitWidth>
            </field>
          </fields>
        </register>
        <register>
          <name>ICR</name>
          <addressOffset>0x20</addressOffset>
          <size>0x20</size>
          <fields>
            <field>
              <name>PECF</name>
              <bitOffset>0</bitOffset>
              <bitWidth>1</bitWidth>
            </field>
            <field>
              <name>FECF</name>
              <bitOffset>1</bitOffset>
              <bitWidth>1</bitWidth>
            </field>
            <field>
              <name>NECF</name>
              <bitOffset>2</bitOffset>
              <bitWidth>1</bitWidth>
            </field>
            <field>
              <name>ORECF</name>
              <bitOffset>3</bitOffset>
              <bitWidth>1</bitWidth>
            </field>
            <field>
              <name>IDLECF</name>
              <bitOffset>4</bitOffset>
              <bitWidth>1</bitWidth>
            </field>
            <field>
              <name>TXFECF</name>
              <bitOffset>5</bitOffset>
              <bitWidth>1</bitWidth>
            </field>
            <field>
              <name>TCCF</name>
              <bitOffset>6</bitOffset>
              <bitWidth>1</bitWidth>
            </field>
            <field>
              <name>TCBGTCF</name>
              <bitOffset>7</bitOffset>
              <bitWidth>1</bitWidth>
            </field>
            <field>
              <name>LBDCF</name>
              <bitOffset>8</bitOffset>
              <bitWidth>1</bitWidth>
            </field>
            <field>
              <name>CTSCF</name>
              <bitOffset>9</bitOffset>
              <bitWidth>1</bitWidth>
            </field>
            <field>
              <name>RTOCF</name>
              <bitOffset>11</bitOffset>
              <bitWidth>1</bitWidth>
            </field>
            <field>
              <name>EOBCF</name>
              <bitOffset>12</bitOffset>
              <bitWidth>1</bitWidth>
            </field>
            <field>
              <name>UDRCF</name>
              <bitOffset>13</bitOffset>
              <bitWidth>1</bitWidth>
            </field>
            <field>
              <name>CMCF</name>
              <bitOffset>17</bitOffset>
              <bitWidth>1</bitWidth>
            </field>
            <field>
              <name>WUCF</name>
              <bitOffset>20</bitOffset>
              <bitWidth>1</bitWidth>
            </field>
          </fields>
        </register>
        <register>
          <name>RDR</name>
          <addressOffset>0x24</addressOffset>
          <size>0x20</size>
          <fields>
            <field>
              <name>RDR</name>
              <bitOffset>0</bitOffset>
              <bitWidth>9</bitWidth>
            </field>
          </fields>
        </register>
        <register>
          <name>TDR</name>
          <addressOffset>0x28</addressOffset>
          <size>0x20</size>
          <fields>
            <field>
              <name>TDR</name>
              <bitOffset>0</bitOffset>
              <bitWidth>9</bitWidth>
            </field>
          </fields>
        </register>
        <register>
          <name>PRESC</name>
          <addressOffset>0x2c</addressOffset>
          <size>0x20</size>
          <fields>
            <field>
              <name>PRESCALER</name>
              <bitOffset>0</bitOffset>
              <bitWidth>4</bitWidth>
            </field>
          </fields>
        </register>
      </registers>
    </peripheral>
    <peripheral>
      <name>SPI4</name>
      <baseAddress>0x40013c00</baseAddress>
      <registers>
        <register>
          <name>CR1</name>
          <addressOffset>0x0</addressOffset>
          <size>0x20</size>
          <fields>
            <field>
              <name>CPHA</name>
              <bitOffset>0</bitOffset>
              <bitWidth>1</bitWidth>
            </field>
            <field>
              <name>CPOL</name>
              <bitOffset>1</bitOffset>
              <bitWidth>1</bitWidth>
            </field>
            <field>
              <name>MSTR</name>
              <bitOffset>2</bitOffset>
              <bitWidth>1</bitWidth>
            </field>
            <field>
              <name>BR</name>
              <bitOffset>3</bitOffset>
              <bitWidth>3</bitWidth>
            </field>
            <field>
              <name>SPE</name>
              <bitOffset>6</bitOffset>
              <bitWidth>1</bitWidth>
            </field>
            <field>
              <name>LSBFIRST</name>
              <bitOffset>7</bitOffset>
              <bitWidth>1</bitWidth>
            </field>
            <field>
              <name>SSI</name>
              <bitOffset>8</bitOffset>
              <bitWidth>1</bitWidth>
            </field>
            <field>
              <name>SSM</name>
              <bitOffset>9</bitOffset>
              <bitWidth>1</bitWidth>
            </field>
            <field>
              <name>RXONLY</name>
              <bitOffset>10</bitOffset>
              <bitWidth>1</bitWidth>
            </field>
            <field>
              <name>CRCL</name>
              <bitOffset>11</bitOffset>
              <bitWidth>1</bitWidth>
            </field>
            <field>
              <name>CRCNEXT</name>
              <bitOffset>12</bitOffset>
              <bitWidth>1</bitWidth>
            </field>
            <field>
              <name>CRCEN</name>
              <bitOffset>13</bitOffset>
              <bitWidth>1</bitWidth>
            </field>
            <field>
              <name>BIDIOE</name>
              <bitOffset>14</bitOffset>
              <bitWidth>1</bitWidth>
            </field>
            <field>
              <name>BIDIMODE</name>
              <bitOffset>15</bitOffset>
              <bitWidth>1</bitWidth>
            </field>
          </fields>
        </register>
        <register>
          <name>CR2</name>
          <addressOffset>0x4</addressOffset>
          <size>0x20</size>
          <fields>
            <field>
              <name>RXDMAEN</name>
              <bitOffset>0</bitOffset>
              <bitWidth>1</bitWidth>
            </field>
            <field>
              <name>TXDMAEN</name>
              <bitOffset>1</bitOffset>
              <bitWidth>1</bitWidth>
            </field>
            <field>
              <name>SSOE</name>
              <bitOffset>2</bitOffset>
              <bitWidth>1</bitWidth>
            </field>
            <field>
              <name>NSSP</name>
              <bitOffset>3</bitOffset>
              <bitWidth>1</bitWidth>
            </field>
            <field>
              <name>FRF</name>
              <bitOffset>4</bitOffset>
              <bitWidth>1</bitWidth>
            </field>
            <field>
              <name>ERRIE</name>
              <bitOffset>5</bitOffset>
              <bitWidth>1</bitWidth>
            </field>
            <field>
              <name>RXNEIE</name>
              <bitOffset>6</bitOffset>
              <bitWidth>1</bitWidth>
            </field>
            <field>
              <name>TXEIE</name>
              <bitOffset>7</bitOffset>
              <bitWidth>1</bitWidth>
            </field>
            <field>
              <name>DS</name>
              <bitOffset>8</bitOffset>
              <bitWidth>4</bitWidth>
            </field>
            <field>
              <name>FRXTH</name>
              <bitOffset>12</bitOffset>
              <bitWidth>1</bitWidth>
            </field>
            <field>
              <name>LDMARX</name>
              <bitOffset>13</bitOffset>
              <bitWidth>1</bitWidth>
            </field>
            <field>
              <name>LDMATX</name>
              <bitOffset>14</bitOffset>
              <bitWidth>1</bitWidth>
            </field>
          </fields>
        </register>
        <register>
          <name>SR</name>
          <addressOffset>0x8</addressOffset>
          <size>0x20</size>
          <fields>
            <field>
              <name>RXNE</name>
              <bitOffset>0</bitOffset>
              <bitWidth>1</bitWidth>
            </field>
            <field>
              <name>TXE</name>
              <bitOffset>1</bitOffset>
              <bitWidth>1</bitWidth>
            </field>
            <field>
              <name>CHSIDE</name>
              <bitOffset>2</bitOffset>
              <bitWidth>1</bitWidth>
            </field>
            <field>
              <name>UDR</name>
              <bitOffset>3</bitOffset>
              <bitWidth>1</bitWidth>
            </field>
            <field>
              <name>CRCERR</name>
              <bitOffset>4</bitOffset>
              <bitWidth>1</bitWidth>
            </field>
            <field>
              <name>MODF</name>
              <bitOffset>5</bitOffset>
              <bitWidth>1</bitWidth>
            </field>
            <field>
              <name>OVR</name>
              <bitOffset>6</bitOffset>
              <bitWidth>1</bitWidth>
            </field>
            <field>
              <name>BSY</name>
              <bitOffset>7</bitOffset>
              <bitWidth>1</bitWidth>
            </field>
            <field>
              <name>FRE</name>
              <bitOffset>8</bitOffset>
              <bitWidth>1</bitWidth>
            </field>
            <field>
              <name>FRLVL</name>
              <bitOffset>9</bitOffset>
              <bitWidth>2</bitWidth>
            </field>
            <field>
              <name>FTLVL</name>
              <bitOffset>11</bitOffset>
              <bitWidth>2</bitWidth>
            </field>
          </fields>
        </register>
        <register>
          <name>DR</name>
          <addressOffset>0xc</addressOffset>
          <size>0x20</size>
          <fields>
            <field>
              <name>DR</name>
              <bitOffset>0</bitOffset>
              <bitWidth>16</bitWidth>
            </field>
          </fields>
        </register>
        <register>
          <name>CRCPR</name>
          <addressOffset>0x10</addressOffset>
          <size>0x20</size>
          <fields>
            <field>
              <name>CRCPOLY</name>
              <bitOffset>0</bitOffset>
              <bitWidth>16</bitWidth>
            </field>
          </fields>
        </register>
        <register>
          <name>RXCRCR</name>
          <addressOffset>0x14</addressOffset>
          <size>0x20</size>
          <fields>
            <field>
              <name>RXCRC</name>
              <bitOffset>0</bitOffset>
              <bitWidth>16</bitWidth>
            </field>
          </fields>
        </register>
        <register>
          <name>TXCRCR</name>
          <addressOffset>0x18</addressOffset>
          <size>0x20</size>
          <fields>
            <field>
              <name>TXCRC</name>
              <bitOffset>0</bitOffset>
              <bitWidth>16</bitWidth>
            </field>
          </fields>
        </register>
        <register>
          <name>I2SCFGR</name>
          <addressOffset>0x1c</addressOffset>
          <size>0x20</size>
          <fields>
            <field>
              <name>CHLEN</name>
              <bitOffset>0</bitOffset>
              <bitWidth>1</bitWidth>
            </field>
            <field>
              <name>DATLEN</name>
              <bitOffset>1</bitOffset>
              <bitWidth>2</bitWidth>
            </field>
            <field>
              <name>CKPOL</name>
              <bitOffset>3</bitOffset>
              <bitWidth>1</bitWidth>
            </field>
            <field>
              <name>I2SSTD</name>
              <bitOffset>4</bitOffset>
              <bitWidth>2</bitWidth>
            </field>
            <field>
              <name>PCMSYNC</name>
              <bitOffset>7</bitOffset>
              <bitWidth>1</bitWidth>
            </field>
            <field>
              <name>I2SCFG</name>
              <bitOffset>8</bitOffset>
              <bitWidth>2</bitWidth>
            </field>
            <field>
              <name>I2SE</name>
              <bitOffset>10</bitOffset>
              <bitWidth>1</bitWidth>
            </field>
            <field>
              <name>I2SMOD</name>
              <bitOffset>11</bitOffset>
              <bitWidth>1</bitWidth>
            </field>
            <field>
              <name>ASTRTEN</name>
              <bitOffset>12</bitOffset>
              <bitWidth>1</bitWidth>
            </field>
          </fields>
        </register>
        <register>
          <name>I2SPR</name>
          <addressOffset>0x20</addressOffset>
          <size>0x20</size>
          <fields>
            <field>
              <name>I2SDIV</name>
              <bitOffset>0</bitOffset>
              <bitWidth>8</bitWidth>
            </field>
            <field>
              <name>ODD</name>
              <bitOffset>8</bitOffset>
              <bitWidth>1</bitWidth>
            </field>
            <field>
              <name>MCKOE</name>
              <bitOffset>9</bitOffset>
              <bitWidth>1</bitWidth>
            </field>
          </fields>
        </register>
      </registers>
    </peripheral>
    <peripheral>
      <name>TIM15</name>
      <baseAddress>0x40014000</baseAddress>
      <registers>
        <register>
          <name>CR1</name>
          <addressOffset>0x0</addressOffset>
          <size>0x20</size>
          <fields>
            <field>
              <name>CEN</name>
              <bitOffset>0</bitOffset>
              <bitWidth>1</bitWidth>
            </field>
            <field>
              <name>UDIS</name>
              <bitOffset>1</bitOffset>
              <bitWidth>1</bitWidth>
            </field>
            <field>
              <name>URS</name>
              <bitOffset>2</bitOffset>
              <bitWidth>1</bitWidth>
            </field>
            <field>
              <name>OPM</name>
              <bitOffset>3</bitOffset>
              <bitWidth>1</bitWidth>
            </field>
            <field>
              <name>DIR</name>
              <bitOffset>4</bitOffset>
              <bitWidth>1</bitWidth>
            </field>
            <field>
              <name>CMS</name>
              <bitOffset>5</bitOffset>
              <bitWidth>2</bitWidth>
            </field>
            <field>
              <name>ARPE</name>
              <bitOffset>7</bitOffset>
              <bitWidth>1</bitWidth>
            </field>
            <field>
              <name>CKD</name>
              <bitOffset>8</bitOffset>
              <bitWidth>2</bitWidth>
            </field>
            <field>
              <name>UIFREMAP</name>
              <bitOffset>11</bitOffset>
              <bitWidth>1</bitWidth>
            </field>
            <field>
              <name>DITHEN</name>
              <bitOffset>12</bitOffset>
              <bitWidth>1</bitWidth>
            </field>
          </fields>
        </register>
        <register>
          <name>CR2</name>
          <addressOffset>0x4</addressOffset>
          <size>0x20</size>
          <fields>
            <field>
              <name>CCPC</name>
              <bitOffset>0</bitOffset>
              <bitWidth>1</bitWidth>
            </field>
            <field>
              <name>CCUS</name>
              <bitOffset>2</bitOffset>
              <bitWidth>1</bitWidth>
            </field>
            <field>
              <name>CCDS</name>
              <bitOffset>3</bitOffset>
              <bitWidth>1</bitWidth>
            </field>
            <field>
              <name>MMS</name>
              <bitOffset>4</bitOffset>
              <bitWidth>22</bitWidth>
            </field>
            <field>
              <name>TI1S</name>
              <bitOffset>7</bitOffset>
              <bitWidth>1</bitWidth>
            </field>
            <field>
              <name>OIS1</name>
              <bitOffset>8</bitOffset>
              <bitWidth>1</bitWidth>
            </field>
            <field>
              <name>OIS1N</name>
              <bitOffset>9</bitOffset>
              <bitWidth>1</bitWidth>
            </field>
            <field>
              <name>OIS2</name>
              <bitOffset>10</bitOffset>
              <bitWidth>1</bitWidth>
            </field>
            <field>
              <name>OIS2N</name>
              <bitOffset>11</bitOffset>
              <bitWidth>1</bitWidth>
            </field>
            <field>
              <name>OIS3</name>
              <bitOffset>12</bitOffset>
              <bitWidth>1</bitWidth>
            </field>
            <field>
              <name>OIS3N</name>
              <bitOffset>13</bitOffset>
              <bitWidth>1</bitWidth>
            </field>
            <field>
              <name>OIS4</name>
              <bitOffset>14</bitOffset>
              <bitWidth>1</bitWidth>
            </field>
            <field>
              <name>OIS4N</name>
              <bitOffset>15</bitOffset>
              <bitWidth>1</bitWidth>
            </field>
            <field>
              <name>OIS5</name>
              <bitOffset>16</bitOffset>
              <bitWidth>1</bitWidth>
            </field>
            <field>
              <name>OIS6</name>
              <bitOffset>18</bitOffset>
              <bitWidth>1</bitWidth>
            </field>
            <field>
              <name>MMS2</name>
              <bitOffset>20</bitOffset>
              <bitWidth>4</bitWidth>
            </field>
          </fields>
        </register>
        <register>
          <name>SMCR</name>
          <addressOffset>0x8</addressOffset>
          <size>0x20</size>
          <fields>
            <field>
              <name>SMS</name>
              <bitOffset>0</bitOffset>
              <bitWidth>17</bitWidth>
            </field>
            <field>
              <name>OCCS</name>
              <bitOffset>3</bitOffset>
              <bitWidth>1</bitWidth>
            </field>
            <field>
              <name>TS</name>
              <bitOffset>4</bitOffset>
              <bitWidth>18</bitWidth>
            </field>
            <field>
              <name>MSM</name>
              <bitOffset>7</bitOffset>
              <bitWidth>1</bitWidth>
            </field>
            <field>
              <name>ETF</name>
              <bitOffset>8</bitOffset>
              <bitWidth>4</bitWidth>
            </field>
            <field>
              <name>ETPS</name>
              <bitOffset>12</bitOffset>
              <bitWidth>2</bitWidth>
            </field>
            <field>
              <name>ECE</name>
              <bitOffset>14</bitOffset>
              <bitWidth>1</bitWidth>
            </field>
            <field>
              <name>ETP</name>
              <bitOffset>15</bitOffset>
              <bitWidth>1</bitWidth>
            </field>
            <field>
              <name>SMSPE</name>
              <bitOffset>24</bitOffset>
              <bitWidth>1</bitWidth>
            </field>
            <field>
              <name>SMSPS</name>
              <bitOffset>25</bitOffset>
              <bitWidth>1</bitWidth>
            </field>
          </fields>
        </register>
        <register>
          <name>DIER</name>
          <addressOffset>0xc</addressOffset>
          <size>0x20</size>
          <fields>
            <field>
              <name>UIE</name>
              <bitOffset>0</bitOffset>
              <bitWidth>1</bitWidth>
            </field>
            <field>
              <name>CC1IE</name>
              <bitOffset>1</bitOffset>
              <bitWidth>1</bitWidth>
            </field>
            <field>
              <name>CC2IE</name>
              <bitOffset>2</bitOffset>
              <bitWidth>1</bitWidth>
            </field>
            <field>
              <name>CC3IE</name>
              <bitOffset>3</bitOffset>
              <bitWidth>1</bitWidth>
            </field>
            <field>
              <name>CC4IE</name>
              <bitOffset>4</bitOffset>
              <bitWidth>1</bitWidth>
            </field>
            <field>
              <name>COMIE</name>
              <bitOffset>5</bitOffset>
              <bitWidth>1</bitWidth>
            </field>
            <field>
              <name>TIE</name>
              <bitOffset>6</bitOffset>
              <bitWidth>1</bitWidth>
            </field>
            <field>
              <name>BIE</name>
              <bitOffset>7</bitOffset>
              <bitWidth>1</bitWidth>
            </field>
            <field>
              <name>UDE</name>
              <bitOffset>8</bitOffset>
              <bitWidth>1</bitWidth>
            </field>
            <field>
              <name>CC1DE</name>
              <bitOffset>9</bitOffset>
              <bitWidth>1</bitWidth>
            </field>
            <field>
              <name>CC2DE</name>
              <bitOffset>10</bitOffset>
              <bitWidth>1</bitWidth>
            </field>
            <field>
              <name>CC3DE</name>
              <bitOffset>11</bitOffset>
              <bitWidth>1</bitWidth>
            </field>
            <field>
              <name>CC4DE</name>
              <bitOffset>12</bitOffset>
              <bitWidth>1</bitWidth>
            </field>
            <field>
              <name>COMDE</name>
              <bitOffset>13</bitOffset>
              <bitWidth>1</bitWidth>
            </field>
            <field>
              <name>TDE</name>
              <bitOffset>14</bitOffset>
              <bitWidth>1</bitWidth>
            </field>
            <field>
              <name>IDXIE</name>
              <bitOffset>20</bitOffset>
              <bitWidth>1</bitWidth>
            </field>
            <field>
              <name>DIRIE</name>
              <bitOffset>21</bitOffset>
              <bitWidth>1</bitWidth>
            </field>
            <field>
              <name>IERRIE</name>
              <bitOffset>22</bitOffset>
              <bitWidth>1</bitWidth>
            </field>
            <field>
              <name>TERRIE</name>
              <bitOffset>23</bitOffset>
              <bitWidth>1</bitWidth>
            </field>
          </fields>
        </register>
        <register>
          <name>SR</name>
          <addressOffset>0x10</addressOffset>
          <size>0x20</size>
          <fields>
            <field>
              <name>UIF</name>
              <bitOffset>0</bitOffset>
              <bitWidth>1</bitWidth>
            </field>
            <field>
              <name>CC1IF</name>
              <bitOffset>1</bitOffset>
              <bitWidth>1</bitWidth>
            </field>
            <field>
              <name>CC2IF</name>
              <bitOffset>2</bitOffset>
              <bitWidth>1</bitWidth>
            </field>
            <field>
              <name>CC3IF</name>
              <bitOffset>3</bitOffset>
              <bitWidth>1</bitWidth>
            </field>
            <field>
              <name>CC4IF</name>
              <bitOffset>4</bitOffset>
              <bitWidth>1</bitWidth>
            </field>
            <field>
              <name>COMIF</name>
              <bitOffset>5</bitOffset>
              <bitWidth>1</bitWidth>
            </field>
            <field>
              <name>TIF</name>
              <bitOffset>6</bitOffset>
              <bitWidth>1</bitWidth>
            </field>
            <field>
              <name>BIF</name>
              <bitOffset>7</bitOffset>
              <bitWidth>1</bitWidth>
            </field>
            <field>
              <name>B2IF</name>
              <bitOffset>8</bitOffset>
              <bitWidth>1</bitWidth>
            </field>
            <field>
              <name>CC1OF</name>
              <bitOffset>9</bitOffset>
              <bitWidth>1</bitWidth>
            </field>
            <field>
              <name>CC2OF</name>
              <bitOffset>10</bitOffset>
              <bitWidth>1</bitWidth>
            </field>
            <field>
              <name>CC3OF</name>
              <bitOffset>11</bitOffset>
              <bitWidth>1</bitWidth>
            </field>
            <field>
              <name>CC4OF</name>
              <bitOffset>12</bitOffset>
              <bitWidth>1</bitWidth>
            </field>
            <field>
              <name>SBIF</name>
              <bitOffset>13</bitOffset>
              <bitWidth>1</bitWidth>
            </field>
            <field>
              <name>CC5IF</name>
              <bitOffset>16</bitOffset>
              <bitWidth>1</bitWidth>
            </field>
            <field>
              <name>CC6IF</name>
              <bitOffset>17</bitOffset>
              <bitWidth>1</bitWidth>
            </field>
            <field>
              <name>IDXF</name>
              <bitOffset>20</bitOffset>
              <bitWidth>1</bitWidth>
            </field>
            <field>
              <name>DIRF</name>
              <bitOffset>21</bitOffset>
              <bitWidth>1</bitWidth>
            </field>
            <field>
              <name>IERRF</name>
              <bitOffset>22</bitOffset>
              <bitWidth>1</bitWidth>
            </field>
            <field>
              <name>TERRF</name>
              <bitOffset>23</bitOffset>
              <bitWidth>1</bitWidth>
            </field>
          </fields>
        </register>
        <register>
          <name>EGR</name>
          <addressOffset>0x14</addressOffset>
          <size>0x20</size>
          <fields>
            <field>
              <name>UG</name>
              <bitOffset>0</bitOffset>
              <bitWidth>1</bitWidth>
            </field>
            <field>
              <name>CC1G</name>
              <bitOffset>1</bitOffset>
              <bitWidth>1</bitWidth>
            </field>
            <field>
              <name>CC2G</name>
              <bitOffset>2</bitOffset>
              <bitWidth>1</bitWidth>
            </field>
            <field>
              <name>CC3G</name>
              <bitOffset>3</bitOffset>
              <bitWidth>1</bitWidth>
            </field>
            <field>
              <name>CC4G</name>
              <bitOffset>4</bitOffset>
              <bitWidth>1</bitWidth>
            </field>
            <field>
              <name>COMG</name>
              <bitOffset>5</bitOffset>
              <bitWidth>1</bitWidth>
            </field>
            <field>
              <name>TG</name>
              <bitOffset>6</bitOffset>
              <bitWidth>1</bitWidth>
            </field>
            <field>
              <name>BG</name>
              <bitOffset>7</bitOffset>
              <bitWidth>1</bitWidth>
            </field>
            <field>
              <name>B2G</name>
              <bitOffset>8</bitOffset>
              <bitWidth>1</bitWidth>
            </field>
          </fields>
        </register>
        <register>
          <name>CCMR1</name>
          <addressOffset>0x18</addressOffset>
          <size>0x20</size>
          <fields>
            <field>
              <name>CC1S</name>
              <bitOffset>0</bitOffset>
              <bitWidth>2</bitWidth>
            </field>
            <field>
              <name>OC1FE</name>
              <bitOffset>2</bitOffset>
              <bitWidth>1</bitWidth>
            </field>
            <field>
              <name>OC1PE</name>
              <bitOffset>3</bitOffset>
              <bitWidth>1</bitWidth>
            </field>
            <field>
              <name>OC1M</name>
              <bitOffset>4</bitOffset>
              <bitWidth>13</bitWidth>
            </field>
            <field>
              <name>OC1CE</name>
              <bitOffset>7</bitOffset>
              <bitWidth>1</bitWidth>
            </field>
            <field>
              <name>CC2S</name>
              <bitOffset>8</bitOffset>
              <bitWidth>2</bitWidth>
            </field>
            <field>
              <name>OC2FE</name>
              <bitOffset>10</bitOffset>
              <bitWidth>1</bitWidth>
            </field>
            <field>
              <name>OC2PE</name>
              <bitOffset>11</bitOffset>
              <bitWidth>1</bitWidth>
            </field>
            <field>
              <name>OC2M</name>
              <bitOffset>12</bitOffset>
              <bitWidth>13</bitWidth>
            </field>
            <field>
              <name>OC2CE</name>
              <bitOffset>15</bitOffset>
              <bitWidth>1</bitWidth>
            </field>
          </fields>
        </register>
        <register>
          <name>CCMR2</name>
          <addressOffset>0x1c</addressOffset>
          <size>0x20</size>
          <fields>
            <field>
              <name>CC3S</name>
              <bitOffset>0</bitOffset>
              <bitWidth>2</bitWidth>
            </field>
            <field>
              <name>OC3FE</name>
              <bitOffset>2</bitOffset>
              <bitWidth>1</bitWidth>
            </field>
            <field>
              <name>OC3PE</name>
              <bitOffset>3</bitOffset>
              <bitWidth>1</bitWidth>
            </field>
            <field>
              <name>OC3M</name>
              <bitOffset>4</bitOffset>
              <bitWidth>13</bitWidth>
            </field>
            <field>
              <name>OC3CE</name>
              <bitOffset>7</bitOffset>
              <bitWidth>1</bitWidth>
            </field>
            <field>
              <name>CC4S</name>
              <bitOffset>8</bitOffset>
              <bitWidth>2</bitWidth>
            </field>
            <field>
              <name>OC4FE</name>
              <bitOffset>10</bitOffset>
              <bitWidth>1</bitWidth>
            </field>
            <field>
              <name>OC4PE</name>
              <bitOffset>11</bitOffset>
              <bitWidth>1</bitWidth>
            </field>
            <field>
              <name>OC4M</name>
              <bitOffset>12</bitOffset>
              <bitWidth>13</bitWidth>
            </field>
            <field>
              <name>OC4CE</name>
              <bitOffset>15</bitOffset>
              <bitWidth>1</bitWidth>
            </field>
          </fields>
        </register>
        <register>
          <name>CCER</name>
          <addressOffset>0x20</addressOffset>
          <size>0x20</size>
          <fields>
            <field>
              <name>CC1E</name>
              <bitOffset>0</bitOffset>
              <bitWidth>1</bitWidth>
            </field>
            <field>
              <name>CC1P</name>
              <bitOffset>1</bitOffset>
              <bitWidth>1</bitWidth>
            </field>
            <field>
              <name>CC1NE</name>
              <bitOffset>2</bitOffset>
              <bitWidth>1</bitWidth>
            </field>
            <field>
              <name>CC1NP</name>
              <bitOffset>3</bitOffset>
              <bitWidth>1</bitWidth>
            </field>
            <field>
              <name>CC2E</name>
              <bitOffset>4</bitOffset>
              <bitWidth>1</bitWidth>
            </field>
            <field>
              <name>CC2P</name>
              <bitOffset>5</bitOffset>
              <bitWidth>1</bitWidth>
            </field>
            <field>
              <name>CC2NE</name>
              <bitOffset>6</bitOffset>
              <bitWidth>1</bitWidth>
            </field>
            <field>
              <name>CC2NP</name>
              <bitOffset>7</bitOffset>
              <bitWidth>1</bitWidth>
            </field>
            <field>
              <name>CC3E</name>
              <bitOffset>8</bitOffset>
              <bitWidth>1</bitWidth>
            </field>
            <field>
              <name>CC3P</name>
              <bitOffset>9</bitOffset>
              <bitWidth>1</bitWidth>
            </field>
            <field>
              <name>CC3NE</name>
              <bitOffset>10</bitOffset>
              <bitWidth>1</bitWidth>
            </field>
            <field>
              <name>CC3NP</name>
              <bitOffset>11</bitOffset>
              <bitWidth>1</bitWidth>
            </field>
            <field>
              <name>CC4E</name>
              <bitOffset>12</bitOffset>
              <bitWidth>1</bitWidth>
            </field>
            <field>
              <name>CC4P</name>
              <bitOffset>13</bitOffset>
              <bitWidth>1</bitWidth>
            </field>
            <field>
              <name>CC4NE</name>
              <bitOffset>14</bitOffset>
              <bitWidth>1</bitWidth>
            </field>
            <field>
              <name>CC4NP</name>
              <bitOffset>15</bitOffset>
              <bitWidth>1</bitWidth>
            </field>
            <field>
              <name>CC5E</name>
              <bitOffset>16</bitOffset>
              <bitWidth>1</bitWidth>
            </field>
            <field>
              <name>CC5P</name>
              <bitOffset>17</bitOffset>
              <bitWidth>1</bitWidth>
            </field>
            <field>
              <name>CC6E</name>
              <bitOffset>20</bitOffset>
              <bitWidth>1</bitWidth>
            </field>
            <field>
              <name>CC6P</name>
              <bitOffset>21</bitOffset>
              <bitWidth>1</bitWidth>
            </field>
          </fields>
        </register>
        <register>
          <name>CNT</name>
          <addressOffset>0x24</addressOffset>
          <size>0x20</size>
          <fields>
            <field>
              <name>CNT</name>
              <bitOffset>0</bitOffset>
              <bitWidth>32</bitWidth>
            </field>
            <field>
              <name>UIFCPY</name>
              <bitOffset>31</bitOffset>
              <bitWidth>1</bitWidth>
            </field>
          </fields>
        </register>
        <register>
          <name>PSC</name>
          <addressOffset>0x28</addressOffset>
          <size>0x20</size>
          <fields>
            <field>
              <name>PSC</name>
              <bitOffset>0</bitOffset>
              <bitWidth>16</bitWidth>
            </field>
          </fields>
        </register>
        <register>
          <name>ARR</name>
          <addressOffset>0x2c</addressOffset>
          <size>0x20</size>
          <fields>
            <field>
              <name>ARR</name>
              <bitOffset>0</bitOffset>
              <bitWidth>32</bitWidth>
            </field>
          </fields>
        </register>
        <register>
          <name>RCR</name>
          <addressOffset>0x30</addressOffset>
          <size>0x20</size>
          <fields>
            <field>
              <name>REP</name>
              <bitOffset>0</bitOffset>
              <bitWidth>16</bitWidth>
            </field>
          </fields>
        </register>
        <register>
          <name>CCR1</name>
          <addressOffset>0x34</addressOffset>
          <size>0x20</size>
          <fields>
            <field>
              <name>CCR1</name>
              <bitOffset>0</bitOffset>
              <bitWidth>16</bitWidth>
            </field>
          </fields>
        </register>
        <register>
          <name>CCR2</name>
          <addressOffset>0x38</addressOffset>
          <size>0x20</size>
          <fields>
            <field>
              <name>CCR2</name>
              <bitOffset>0</bitOffset>
              <bitWidth>16</bitWidth>
            </field>
          </fields>
        </register>
        <register>
          <name>CCR3</name>
          <addressOffset>0x3c</addressOffset>
          <size>0x20</size>
          <fields>
            <field>
              <name>CCR3</name>
              <bitOffset>0</bitOffset>
              <bitWidth>16</bitWidth>
            </field>
          </fields>
        </register>
        <register>
          <name>CCR4</name>
          <addressOffset>0x40</addressOffset>
          <size>0x20</size>
          <fields>
            <field>
              <name>CCR4</name>
              <bitOffset>0</bitOffset>
              <bitWidth>16</bitWidth>
            </field>
          </fields>
        </register>
        <register>
          <name>BDTR</name>
          <addressOffset>0x44</addressOffset>
          <size>0x20</size>
          <fields>
            <field>
              <name>DTG</name>
              <bitOffset>0</bitOffset>
              <bitWidth>8</bitWidth>
            </field>
            <field>
              <name>LOCK</name>
              <bitOffset>8</bitOffset>
              <bitWidth>2</bitWidth>
            </field>
            <field>
              <name>OSSI</name>
              <bitOffset>10</bitOffset>
              <bitWidth>1</bitWidth>
            </field>
            <field>
              <name>OSSR</name>
              <bitOffset>11</bitOffset>
              <bitWidth>1</bitWidth>
            </field>
            <field>
              <name>BKE</name>
              <bitOffset>12</bitOffset>
              <bitWidth>1</bitWidth>
            </field>
            <field>
              <name>BKP</name>
              <bitOffset>13</bitOffset>
              <bitWidth>1</bitWidth>
            </field>
            <field>
              <name>AOE</name>
              <bitOffset>14</bitOffset>
              <bitWidth>1</bitWidth>
            </field>
            <field>
              <name>MOE</name>
              <bitOffset>15</bitOffset>
              <bitWidth>1</bitWidth>
            </field>
            <field>
              <name>BKF</name>
              <bitOffset>16</bitOffset>
              <bitWidth>4</bitWidth>
            </field>
            <field>
              <name>BK2F</name>
              <bitOffset>20</bitOffset>
              <bitWidth>4</bitWidth>
            </field>
            <field>
              <name>BK2E</name>
              <bitOffset>24</bitOffset>
              <bitWidth>1</bitWidth>
            </field>
            <field>
              <name>BK2P</name>
              <bitOffset>25</bitOffset>
              <bitWidth>1</bitWidth>
            </field>
            <field>
              <name>BKDSRM</name>
              <bitOffset>26</bitOffset>
              <bitWidth>1</bitWidth>
            </field>
            <field>
              <name>BK2DSRM</name>
              <bitOffset>27</bitOffset>
              <bitWidth>1</bitWidth>
            </field>
            <field>
              <name>BKBID</name>
              <bitOffset>28</bitOffset>
              <bitWidth>1</bitWidth>
            </field>
            <field>
              <name>BK2BID</name>
              <bitOffset>29</bitOffset>
              <bitWidth>1</bitWidth>
            </field>
          </fields>
        </register>
        <register>
          <name>CCR5</name>
          <addressOffset>0x48</addressOffset>
          <size>0x20</size>
          <fields>
            <field>
              <name>CCR5</name>
              <bitOffset>0</bitOffset>
              <bitWidth>32</bitWidth>
            </field>
            <field>
              <name>GC5C1</name>
              <bitOffset>29</bitOffset>
              <bitWidth>1</bitWidth>
            </field>
            <field>
              <name>GC5C2</name>
              <bitOffset>30</bitOffset>
              <bitWidth>1</bitWidth>
            </field>
            <field>
              <name>GC5C3</name>
              <bitOffset>31</bitOffset>
              <bitWidth>1</bitWidth>
            </field>
          </fields>
        </register>
        <register>
          <name>CCR6</name>
          <addressOffset>0x4c</addressOffset>
          <size>0x20</size>
          <fields>
            <field>
              <name>CCR6</name>
              <bitOffset>0</bitOffset>
              <bitWidth>16</bitWidth>
            </field>
          </fields>
        </register>
        <register>
          <name>CCMR3</name>
          <addressOffset>0x50</addressOffset>
          <size>0x20</size>
          <fields>
            <field>
              <name>OC5FE</name>
              <bitOffset>2</bitOffset>
              <bitWidth>1</bitWidth>
            </field>
            <field>
              <name>OC5PE</name>
              <bitOffset>3</bitOffset>
              <bitWidth>1</bitWidth>
            </field>
            <field>
              <name>OC5M</name>
              <bitOffset>4</bitOffset>
              <bitWidth>13</bitWidth>
            </field>
            <field>
              <name>OC5CE</name>
              <bitOffset>7</bitOffset>
              <bitWidth>1</bitWidth>
            </field>
            <field>
              <name>OC6FE</name>
              <bitOffset>10</bitOffset>
              <bitWidth>1</bitWidth>
            </field>
            <field>
              <name>OC6PE</name>
              <bitOffset>11</bitOffset>
              <bitWidth>1</bitWidth>
            </field>
            <field>
              <name>OC6M</name>
              <bitOffset>12</bitOffset>
              <bitWidth>13</bitWidth>
            </field>
            <field>
              <name>OC6CE</name>
              <bitOffset>15</bitOffset>
              <bitWidth>1</bitWidth>
            </field>
          </fields>
        </register>
        <register>
          <name>DTR2</name>
          <addressOffset>0x54</addressOffset>
          <size>0x20</size>
          <fields>
            <field>
              <name>DTGF</name>
              <bitOffset>0</bitOffset>
              <bitWidth>8</bitWidth>
            </field>
            <field>
              <name>DTAE</name>
              <bitOffset>16</bitOffset>
              <bitWidth>1</bitWidth>
            </field>
            <field>
              <name>DTPE</name>
              <bitOffset>17</bitOffset>
              <bitWidth>1</bitWidth>
            </field>
          </fields>
        </register>
        <register>
          <name>ECR</name>
          <addressOffset>0x58</addressOffset>
          <size>0x20</size>
          <fields>
            <field>
              <name>IE</name>
              <bitOffset>0</bitOffset>
              <bitWidth>1</bitWidth>
            </field>
            <field>
              <name>IDIR</name>
              <bitOffset>1</bitOffset>
              <bitWidth>2</bitWidth>
            </field>
            <field>
              <name>FIDX</name>
              <bitOffset>5</bitOffset>
              <bitWidth>1</bitWidth>
            </field>
            <field>
              <name>IPOS</name>
              <bitOffset>6</bitOffset>
              <bitWidth>2</bitWidth>
            </field>
            <field>
              <name>PW</name>
              <bitOffset>16</bitOffset>
              <bitWidth>8</bitWidth>
            </field>
            <field>
              <name>PWPRSC</name>
              <bitOffset>24</bitOffset>
              <bitWidth>3</bitWidth>
            </field>
          </fields>
        </register>
        <register>
          <name>TISEL</name>
          <addressOffset>0x5c</addressOffset>
          <size>0x20</size>
          <fields>
            <field>
              <name>TI1SEL</name>
              <bitOffset>0</bitOffset>
              <bitWidth>4</bitWidth>
            </field>
            <field>
              <name>TI2SEL</name>
              <bitOffset>8</bitOffset>
              <bitWidth>4</bitWidth>
            </field>
            <field>
              <name>TI3SEL</name>
              <bitOffset>16</bitOffset>
              <bitWidth>4</bitWidth>
            </field>
            <field>
              <name>TI4SEL</name>
              <bitOffset>24</bitOffset>
              <bitWidth>4</bitWidth>
            </field>
          </fields>
        </register>
        <register>
          <name>AF1</name>
          <addressOffset>0x60</addressOffset>
          <size>0x20</size>
        </register>
        <register>
          <name>AF2</name>
          <addressOffset>0x64</addressOffset>
          <size>0x20</size>
        </register>
        <register>
          <name>OR</name>
          <addressOffset>0x68</addressOffset>
          <size>0x20</size>
          <fields>
            <field>
              <name>HSE32EN</name>
              <bitOffset>0</bitOffset>
              <bitWidth>1</bitWidth>
            </field>
          </fields>
        </register>
        <register>
          <name>DCR</name>
          <addressOffset>0x3dc</addressOffset>
          <size>0x20</size>
          <fields>
            <field>
              <name>DBA</name>
              <bitOffset>0</bitOffset>
              <bitWidth>5</bitWidth>
            </field>
            <field>
              <name>DBL</name>
              <bitOffset>8</bitOffset>
              <bitWidth>5</bitWidth>
            </field>
          </fields>
        </register>
        <register>
          <name>DMAR</name>
          <addressOffset>0x3e0</addressOffset>
          <size>0x20</size>
          <fields>
            <field>
              <name>DMAB</name>
              <bitOffset>0</bitOffset>
              <bitWidth>32</bitWidth>
            </field>
          </fields>
        </register>
      </registers>
    </peripheral>
    <peripheral>
      <name>TIM16</name>
      <baseAddress>0x40014400</baseAddress>
      <registers>
        <register>
          <name>CR1</name>
          <addressOffset>0x0</addressOffset>
          <size>0x20</size>
          <fields>
            <field>
              <name>CEN</name>
              <bitOffset>0</bitOffset>
              <bitWidth>1</bitWidth>
            </field>
            <field>
              <name>UDIS</name>
              <bitOffset>1</bitOffset>
              <bitWidth>1</bitWidth>
            </field>
            <field>
              <name>URS</name>
              <bitOffset>2</bitOffset>
              <bitWidth>1</bitWidth>
            </field>
            <field>
              <name>OPM</name>
              <bitOffset>3</bitOffset>
              <bitWidth>1</bitWidth>
            </field>
            <field>
              <name>DIR</name>
              <bitOffset>4</bitOffset>
              <bitWidth>1</bitWidth>
            </field>
            <field>
              <name>CMS</name>
              <bitOffset>5</bitOffset>
              <bitWidth>2</bitWidth>
            </field>
            <field>
              <name>ARPE</name>
              <bitOffset>7</bitOffset>
              <bitWidth>1</bitWidth>
            </field>
            <field>
              <name>CKD</name>
              <bitOffset>8</bitOffset>
              <bitWidth>2</bitWidth>
            </field>
            <field>
              <name>UIFREMAP</name>
              <bitOffset>11</bitOffset>
              <bitWidth>1</bitWidth>
            </field>
            <field>
              <name>DITHEN</name>
              <bitOffset>12</bitOffset>
              <bitWidth>1</bitWidth>
            </field>
          </fields>
        </register>
        <register>
          <name>CR2</name>
          <addressOffset>0x4</addressOffset>
          <size>0x20</size>
          <fields>
            <field>
              <name>CCPC</name>
              <bitOffset>0</bitOffset>
              <bitWidth>1</bitWidth>
            </field>
            <field>
              <name>CCUS</name>
              <bitOffset>2</bitOffset>
              <bitWidth>1</bitWidth>
            </field>
            <field>
              <name>CCDS</name>
              <bitOffset>3</bitOffset>
              <bitWidth>1</bitWidth>
            </field>
            <field>
              <name>MMS</name>
              <bitOffset>4</bitOffset>
              <bitWidth>22</bitWidth>
            </field>
            <field>
              <name>TI1S</name>
              <bitOffset>7</bitOffset>
              <bitWidth>1</bitWidth>
            </field>
            <field>
              <name>OIS1</name>
              <bitOffset>8</bitOffset>
              <bitWidth>1</bitWidth>
            </field>
            <field>
              <name>OIS1N</name>
              <bitOffset>9</bitOffset>
              <bitWidth>1</bitWidth>
            </field>
            <field>
              <name>OIS2</name>
              <bitOffset>10</bitOffset>
              <bitWidth>1</bitWidth>
            </field>
            <field>
              <name>OIS2N</name>
              <bitOffset>11</bitOffset>
              <bitWidth>1</bitWidth>
            </field>
            <field>
              <name>OIS3</name>
              <bitOffset>12</bitOffset>
              <bitWidth>1</bitWidth>
            </field>
            <field>
              <name>OIS3N</name>
              <bitOffset>13</bitOffset>
              <bitWidth>1</bitWidth>
            </field>
            <field>
              <name>OIS4</name>
              <bitOffset>14</bitOffset>
              <bitWidth>1</bitWidth>
            </field>
            <field>
              <name>OIS4N</name>
              <bitOffset>15</bitOffset>
              <bitWidth>1</bitWidth>
            </field>
            <field>
              <name>OIS5</name>
              <bitOffset>16</bitOffset>
              <bitWidth>1</bitWidth>
            </field>
            <field>
              <name>OIS6</name>
              <bitOffset>18</bitOffset>
              <bitWidth>1</bitWidth>
            </field>
            <field>
              <name>MMS2</name>
              <bitOffset>20</bitOffset>
              <bitWidth>4</bitWidth>
            </field>
          </fields>
        </register>
        <register>
          <name>SMCR</name>
          <addressOffset>0x8</addressOffset>
          <size>0x20</size>
          <fields>
            <field>
              <name>SMS</name>
              <bitOffset>0</bitOffset>
              <bitWidth>17</bitWidth>
            </field>
            <field>
              <name>OCCS</name>
              <bitOffset>3</bitOffset>
              <bitWidth>1</bitWidth>
            </field>
            <field>
              <name>TS</name>
              <bitOffset>4</bitOffset>
              <bitWidth>18</bitWidth>
            </field>
            <field>
              <name>MSM</name>
              <bitOffset>7</bitOffset>
              <bitWidth>1</bitWidth>
            </field>
            <field>
              <name>ETF</name>
              <bitOffset>8</bitOffset>
              <bitWidth>4</bitWidth>
            </field>
            <field>
              <name>ETPS</name>
              <bitOffset>12</bitOffset>
              <bitWidth>2</bitWidth>
            </field>
            <field>
              <name>ECE</name>
              <bitOffset>14</bitOffset>
              <bitWidth>1</bitWidth>
            </field>
            <field>
              <name>ETP</name>
              <bitOffset>15</bitOffset>
              <bitWidth>1</bitWidth>
            </field>
            <field>
              <name>SMSPE</name>
              <bitOffset>24</bitOffset>
              <bitWidth>1</bitWidth>
            </field>
            <field>
              <name>SMSPS</name>
              <bitOffset>25</bitOffset>
              <bitWidth>1</bitWidth>
            </field>
          </fields>
        </register>
        <register>
          <name>DIER</name>
          <addressOffset>0xc</addressOffset>
          <size>0x20</size>
          <fields>
            <field>
              <name>UIE</name>
              <bitOffset>0</bitOffset>
              <bitWidth>1</bitWidth>
            </field>
            <field>
              <name>CC1IE</name>
              <bitOffset>1</bitOffset>
              <bitWidth>1</bitWidth>
            </field>
            <field>
              <name>CC2IE</name>
              <bitOffset>2</bitOffset>
              <bitWidth>1</bitWidth>
            </field>
            <field>
              <name>CC3IE</name>
              <bitOffset>3</bitOffset>
              <bitWidth>1</bitWidth>
            </field>
            <field>
              <name>CC4IE</name>
              <bitOffset>4</bitOffset>
              <bitWidth>1</bitWidth>
            </field>
            <field>
              <name>COMIE</name>
              <bitOffset>5</bitOffset>
              <bitWidth>1</bitWidth>
            </field>
            <field>
              <name>TIE</name>
              <bitOffset>6</bitOffset>
              <bitWidth>1</bitWidth>
            </field>
            <field>
              <name>BIE</name>
              <bitOffset>7</bitOffset>
              <bitWidth>1</bitWidth>
            </field>
            <field>
              <name>UDE</name>
              <bitOffset>8</bitOffset>
              <bitWidth>1</bitWidth>
            </field>
            <field>
              <name>CC1DE</name>
              <bitOffset>9</bitOffset>
              <bitWidth>1</bitWidth>
            </field>
            <field>
              <name>CC2DE</name>
              <bitOffset>10</bitOffset>
              <bitWidth>1</bitWidth>
            </field>
            <field>
              <name>CC3DE</name>
              <bitOffset>11</bitOffset>
              <bitWidth>1</bitWidth>
            </field>
            <field>
              <name>CC4DE</name>
              <bitOffset>12</bitOffset>
              <bitWidth>1</bitWidth>
            </field>
            <field>
              <name>COMDE</name>
              <bitOffset>13</bitOffset>
              <bitWidth>1</bitWidth>
            </field>
            <field>
              <name>TDE</name>
              <bitOffset>14</bitOffset>
              <bitWidth>1</bitWidth>
            </field>
            <field>
              <name>IDXIE</name>
              <bitOffset>20</bitOffset>
              <bitWidth>1</bitWidth>
            </field>
            <field>
              <name>DIRIE</name>
              <bitOffset>21</bitOffset>
              <bitWidth>1</bitWidth>
            </field>
            <field>
              <name>IERRIE</name>
              <bitOffset>22</bitOffset>
              <bitWidth>1</bitWidth>
            </field>
            <field>
              <name>TERRIE</name>
              <bitOffset>23</bitOffset>
              <bitWidth>1</bitWidth>
            </field>
          </fields>
        </register>
        <register>
          <name>SR</name>
          <addressOffset>0x10</addressOffset>
          <size>0x20</size>
          <fields>
            <field>
              <name>UIF</name>
              <bitOffset>0</bitOffset>
              <bitWidth>1</bitWidth>
            </field>
            <field>
              <name>CC1IF</name>
              <bitOffset>1</bitOffset>
              <bitWidth>1</bitWidth>
            </field>
            <field>
              <name>CC2IF</name>
              <bitOffset>2</bitOffset>
              <bitWidth>1</bitWidth>
            </field>
            <field>
              <name>CC3IF</name>
              <bitOffset>3</bitOffset>
              <bitWidth>1</bitWidth>
            </field>
            <field>
              <name>CC4IF</name>
              <bitOffset>4</bitOffset>
              <bitWidth>1</bitWidth>
            </field>
            <field>
              <name>COMIF</name>
              <bitOffset>5</bitOffset>
              <bitWidth>1</bitWidth>
            </field>
            <field>
              <name>TIF</name>
              <bitOffset>6</bitOffset>
              <bitWidth>1</bitWidth>
            </field>
            <field>
              <name>BIF</name>
              <bitOffset>7</bitOffset>
              <bitWidth>1</bitWidth>
            </field>
            <field>
              <name>B2IF</name>
              <bitOffset>8</bitOffset>
              <bitWidth>1</bitWidth>
            </field>
            <field>
              <name>CC1OF</name>
              <bitOffset>9</bitOffset>
              <bitWidth>1</bitWidth>
            </field>
            <field>
              <name>CC2OF</name>
              <bitOffset>10</bitOffset>
              <bitWidth>1</bitWidth>
            </field>
            <field>
              <name>CC3OF</name>
              <bitOffset>11</bitOffset>
              <bitWidth>1</bitWidth>
            </field>
            <field>
              <name>CC4OF</name>
              <bitOffset>12</bitOffset>
              <bitWidth>1</bitWidth>
            </field>
            <field>
              <name>SBIF</name>
              <bitOffset>13</bitOffset>
              <bitWidth>1</bitWidth>
            </field>
            <field>
              <name>CC5IF</name>
              <bitOffset>16</bitOffset>
              <bitWidth>1</bitWidth>
            </field>
            <field>
              <name>CC6IF</name>
              <bitOffset>17</bitOffset>
              <bitWidth>1</bitWidth>
            </field>
            <field>
              <name>IDXF</name>
              <bitOffset>20</bitOffset>
              <bitWidth>1</bitWidth>
            </field>
            <field>
              <name>DIRF</name>
              <bitOffset>21</bitOffset>
              <bitWidth>1</bitWidth>
            </field>
            <field>
              <name>IERRF</name>
              <bitOffset>22</bitOffset>
              <bitWidth>1</bitWidth>
            </field>
            <field>
              <name>TERRF</name>
              <bitOffset>23</bitOffset>
              <bitWidth>1</bitWidth>
            </field>
          </fields>
        </register>
        <register>
          <name>EGR</name>
          <addressOffset>0x14</addressOffset>
          <size>0x20</size>
          <fields>
            <field>
              <name>UG</name>
              <bitOffset>0</bitOffset>
              <bitWidth>1</bitWidth>
            </field>
            <field>
              <name>CC1G</name>
              <bitOffset>1</bitOffset>
              <bitWidth>1</bitWidth>
            </field>
            <field>
              <name>CC2G</name>
              <bitOffset>2</bitOffset>
              <bitWidth>1</bitWidth>
            </field>
            <field>
              <name>CC3G</name>
              <bitOffset>3</bitOffset>
              <bitWidth>1</bitWidth>
            </field>
            <field>
              <name>CC4G</name>
              <bitOffset>4</bitOffset>
              <bitWidth>1</bitWidth>
            </field>
            <field>
              <name>COMG</name>
              <bitOffset>5</bitOffset>
              <bitWidth>1</bitWidth>
            </field>
            <field>
              <name>TG</name>
              <bitOffset>6</bitOffset>
              <bitWidth>1</bitWidth>
            </field>
            <field>
              <name>BG</name>
              <bitOffset>7</bitOffset>
              <bitWidth>1</bitWidth>
            </field>
            <field>
              <name>B2G</name>
              <bitOffset>8</bitOffset>
              <bitWidth>1</bitWidth>
            </field>
          </fields>
        </register>
        <register>
          <name>CCMR1</name>
          <addressOffset>0x18</addressOffset>
          <size>0x20</size>
          <fields>
            <field>
              <name>CC1S</name>
              <bitOffset>0</bitOffset>
              <bitWidth>2</bitWidth>
            </field>
            <field>
              <name>OC1FE</name>
              <bitOffset>2</bitOffset>
              <bitWidth>1</bitWidth>
            </field>
            <field>
              <name>OC1PE</name>
              <bitOffset>3</bitOffset>
              <bitWidth>1</bitWidth>
            </field>
            <field>
              <name>OC1M</name>
              <bitOffset>4</bitOffset>
              <bitWidth>13</bitWidth>
            </field>
            <field>
              <name>OC1CE</name>
              <bitOffset>7</bitOffset>
              <bitWidth>1</bitWidth>
            </field>
            <field>
              <name>CC2S</name>
              <bitOffset>8</bitOffset>
              <bitWidth>2</bitWidth>
            </field>
            <field>
              <name>OC2FE</name>
              <bitOffset>10</bitOffset>
              <bitWidth>1</bitWidth>
            </field>
            <field>
              <name>OC2PE</name>
              <bitOffset>11</bitOffset>
              <bitWidth>1</bitWidth>
            </field>
            <field>
              <name>OC2M</name>
              <bitOffset>12</bitOffset>
              <bitWidth>13</bitWidth>
            </field>
            <field>
              <name>OC2CE</name>
              <bitOffset>15</bitOffset>
              <bitWidth>1</bitWidth>
            </field>
          </fields>
        </register>
        <register>
          <name>CCMR2</name>
          <addressOffset>0x1c</addressOffset>
          <size>0x20</size>
          <fields>
            <field>
              <name>CC3S</name>
              <bitOffset>0</bitOffset>
              <bitWidth>2</bitWidth>
            </field>
            <field>
              <name>OC3FE</name>
              <bitOffset>2</bitOffset>
              <bitWidth>1</bitWidth>
            </field>
            <field>
              <name>OC3PE</name>
              <bitOffset>3</bitOffset>
              <bitWidth>1</bitWidth>
            </field>
            <field>
              <name>OC3M</name>
              <bitOffset>4</bitOffset>
              <bitWidth>13</bitWidth>
            </field>
            <field>
              <name>OC3CE</name>
              <bitOffset>7</bitOffset>
              <bitWidth>1</bitWidth>
            </field>
            <field>
              <name>CC4S</name>
              <bitOffset>8</bitOffset>
              <bitWidth>2</bitWidth>
            </field>
            <field>
              <name>OC4FE</name>
              <bitOffset>10</bitOffset>
              <bitWidth>1</bitWidth>
            </field>
            <field>
              <name>OC4PE</name>
              <bitOffset>11</bitOffset>
              <bitWidth>1</bitWidth>
            </field>
            <field>
              <name>OC4M</name>
              <bitOffset>12</bitOffset>
              <bitWidth>13</bitWidth>
            </field>
            <field>
              <name>OC4CE</name>
              <bitOffset>15</bitOffset>
              <bitWidth>1</bitWidth>
            </field>
          </fields>
        </register>
        <register>
          <name>CCER</name>
          <addressOffset>0x20</addressOffset>
          <size>0x20</size>
          <fields>
            <field>
              <name>CC1E</name>
              <bitOffset>0</bitOffset>
              <bitWidth>1</bitWidth>
            </field>
            <field>
              <name>CC1P</name>
              <bitOffset>1</bitOffset>
              <bitWidth>1</bitWidth>
            </field>
            <field>
              <name>CC1NE</name>
              <bitOffset>2</bitOffset>
              <bitWidth>1</bitWidth>
            </field>
            <field>
              <name>CC1NP</name>
              <bitOffset>3</bitOffset>
              <bitWidth>1</bitWidth>
            </field>
            <field>
              <name>CC2E</name>
              <bitOffset>4</bitOffset>
              <bitWidth>1</bitWidth>
            </field>
            <field>
              <name>CC2P</name>
              <bitOffset>5</bitOffset>
              <bitWidth>1</bitWidth>
            </field>
            <field>
              <name>CC2NE</name>
              <bitOffset>6</bitOffset>
              <bitWidth>1</bitWidth>
            </field>
            <field>
              <name>CC2NP</name>
              <bitOffset>7</bitOffset>
              <bitWidth>1</bitWidth>
            </field>
            <field>
              <name>CC3E</name>
              <bitOffset>8</bitOffset>
              <bitWidth>1</bitWidth>
            </field>
            <field>
              <name>CC3P</name>
              <bitOffset>9</bitOffset>
              <bitWidth>1</bitWidth>
            </field>
            <field>
              <name>CC3NE</name>
              <bitOffset>10</bitOffset>
              <bitWidth>1</bitWidth>
            </field>
            <field>
              <name>CC3NP</name>
              <bitOffset>11</bitOffset>
              <bitWidth>1</bitWidth>
            </field>
            <field>
              <name>CC4E</name>
              <bitOffset>12</bitOffset>
              <bitWidth>1</bitWidth>
            </field>
            <field>
              <name>CC4P</name>
              <bitOffset>13</bitOffset>
              <bitWidth>1</bitWidth>
            </field>
            <field>
              <name>CC4NE</name>
              <bitOffset>14</bitOffset>
              <bitWidth>1</bitWidth>
            </field>
            <field>
              <name>CC4NP</name>
              <bitOffset>15</bitOffset>
              <bitWidth>1</bitWidth>
            </field>
            <field>
              <name>CC5E</name>
              <bitOffset>16</bitOffset>
              <bitWidth>1</bitWidth>
            </field>
            <field>
              <name>CC5P</name>
              <bitOffset>17</bitOffset>
              <bitWidth>1</bitWidth>
            </field>
            <field>
              <name>CC6E</name>
              <bitOffset>20</bitOffset>
              <bitWidth>1</bitWidth>
            </field>
            <field>
              <name>CC6P</name>
              <bitOffset>21</bitOffset>
              <bitWidth>1</bitWidth>
            </field>
          </fields>
        </register>
        <register>
          <name>CNT</name>
          <addressOffset>0x24</addressOffset>
          <size>0x20</size>
          <fields>
            <field>
              <name>CNT</name>
              <bitOffset>0</bitOffset>
              <bitWidth>32</bitWidth>
            </field>
            <field>
              <name>UIFCPY</name>
              <bitOffset>31</bitOffset>
              <bitWidth>1</bitWidth>
            </field>
          </fields>
        </register>
        <register>
          <name>PSC</name>
          <addressOffset>0x28</addressOffset>
          <size>0x20</size>
          <fields>
            <field>
              <name>PSC</name>
              <bitOffset>0</bitOffset>
              <bitWidth>16</bitWidth>
            </field>
          </fields>
        </register>
        <register>
          <name>ARR</name>
          <addressOffset>0x2c</addressOffset>
          <size>0x20</size>
          <fields>
            <field>
              <name>ARR</name>
              <bitOffset>0</bitOffset>
              <bitWidth>32</bitWidth>
            </field>
          </fields>
        </register>
        <register>
          <name>RCR</name>
          <addressOffset>0x30</addressOffset>
          <size>0x20</size>
          <fields>
            <field>
              <name>REP</name>
              <bitOffset>0</bitOffset>
              <bitWidth>16</bitWidth>
            </field>
          </fields>
        </register>
        <register>
          <name>CCR1</name>
          <addressOffset>0x34</addressOffset>
          <size>0x20</size>
          <fields>
            <field>
              <name>CCR1</name>
              <bitOffset>0</bitOffset>
              <bitWidth>16</bitWidth>
            </field>
          </fields>
        </register>
        <register>
          <name>CCR2</name>
          <addressOffset>0x38</addressOffset>
          <size>0x20</size>
          <fields>
            <field>
              <name>CCR2</name>
              <bitOffset>0</bitOffset>
              <bitWidth>16</bitWidth>
            </field>
          </fields>
        </register>
        <register>
          <name>CCR3</name>
          <addressOffset>0x3c</addressOffset>
          <size>0x20</size>
          <fields>
            <field>
              <name>CCR3</name>
              <bitOffset>0</bitOffset>
              <bitWidth>16</bitWidth>
            </field>
          </fields>
        </register>
        <register>
          <name>CCR4</name>
          <addressOffset>0x40</addressOffset>
          <size>0x20</size>
          <fields>
            <field>
              <name>CCR4</name>
              <bitOffset>0</bitOffset>
              <bitWidth>16</bitWidth>
            </field>
          </fields>
        </register>
        <register>
          <name>BDTR</name>
          <addressOffset>0x44</addressOffset>
          <size>0x20</size>
          <fields>
            <field>
              <name>DTG</name>
              <bitOffset>0</bitOffset>
              <bitWidth>8</bitWidth>
            </field>
            <field>
              <name>LOCK</name>
              <bitOffset>8</bitOffset>
              <bitWidth>2</bitWidth>
            </field>
            <field>
              <name>OSSI</name>
              <bitOffset>10</bitOffset>
              <bitWidth>1</bitWidth>
            </field>
            <field>
              <name>OSSR</name>
              <bitOffset>11</bitOffset>
              <bitWidth>1</bitWidth>
            </field>
            <field>
              <name>BKE</name>
              <bitOffset>12</bitOffset>
              <bitWidth>1</bitWidth>
            </field>
            <field>
              <name>BKP</name>
              <bitOffset>13</bitOffset>
              <bitWidth>1</bitWidth>
            </field>
            <field>
              <name>AOE</name>
              <bitOffset>14</bitOffset>
              <bitWidth>1</bitWidth>
            </field>
            <field>
              <name>MOE</name>
              <bitOffset>15</bitOffset>
              <bitWidth>1</bitWidth>
            </field>
            <field>
              <name>BKF</name>
              <bitOffset>16</bitOffset>
              <bitWidth>4</bitWidth>
            </field>
            <field>
              <name>BK2F</name>
              <bitOffset>20</bitOffset>
              <bitWidth>4</bitWidth>
            </field>
            <field>
              <name>BK2E</name>
              <bitOffset>24</bitOffset>
              <bitWidth>1</bitWidth>
            </field>
            <field>
              <name>BK2P</name>
              <bitOffset>25</bitOffset>
              <bitWidth>1</bitWidth>
            </field>
            <field>
              <name>BKDSRM</name>
              <bitOffset>26</bitOffset>
              <bitWidth>1</bitWidth>
            </field>
            <field>
              <name>BK2DSRM</name>
              <bitOffset>27</bitOffset>
              <bitWidth>1</bitWidth>
            </field>
            <field>
              <name>BKBID</name>
              <bitOffset>28</bitOffset>
              <bitWidth>1</bitWidth>
            </field>
            <field>
              <name>BK2BID</name>
              <bitOffset>29</bitOffset>
              <bitWidth>1</bitWidth>
            </field>
          </fields>
        </register>
        <register>
          <name>CCR5</name>
          <addressOffset>0x48</addressOffset>
          <size>0x20</size>
          <fields>
            <field>
              <name>CCR5</name>
              <bitOffset>0</bitOffset>
              <bitWidth>32</bitWidth>
            </field>
            <field>
              <name>GC5C1</name>
              <bitOffset>29</bitOffset>
              <bitWidth>1</bitWidth>
            </field>
            <field>
              <name>GC5C2</name>
              <bitOffset>30</bitOffset>
              <bitWidth>1</bitWidth>
            </field>
            <field>
              <name>GC5C3</name>
              <bitOffset>31</bitOffset>
              <bitWidth>1</bitWidth>
            </field>
          </fields>
        </register>
        <register>
          <name>CCR6</name>
          <addressOffset>0x4c</addressOffset>
          <size>0x20</size>
          <fields>
            <field>
              <name>CCR6</name>
              <bitOffset>0</bitOffset>
              <bitWidth>16</bitWidth>
            </field>
          </fields>
        </register>
        <register>
          <name>CCMR3</name>
          <addressOffset>0x50</addressOffset>
          <size>0x20</size>
          <fields>
            <field>
              <name>OC5FE</name>
              <bitOffset>2</bitOffset>
              <bitWidth>1</bitWidth>
            </field>
            <field>
              <name>OC5PE</name>
              <bitOffset>3</bitOffset>
              <bitWidth>1</bitWidth>
            </field>
            <field>
              <name>OC5M</name>
              <bitOffset>4</bitOffset>
              <bitWidth>13</bitWidth>
            </field>
            <field>
              <name>OC5CE</name>
              <bitOffset>7</bitOffset>
              <bitWidth>1</bitWidth>
            </field>
            <field>
              <name>OC6FE</name>
              <bitOffset>10</bitOffset>
              <bitWidth>1</bitWidth>
            </field>
            <field>
              <name>OC6PE</name>
              <bitOffset>11</bitOffset>
              <bitWidth>1</bitWidth>
            </field>
            <field>
              <name>OC6M</name>
              <bitOffset>12</bitOffset>
              <bitWidth>13</bitWidth>
            </field>
            <field>
              <name>OC6CE</name>
              <bitOffset>15</bitOffset>
              <bitWidth>1</bitWidth>
            </field>
          </fields>
        </register>
        <register>
          <name>DTR2</name>
          <addressOffset>0x54</addressOffset>
          <size>0x20</size>
          <fields>
            <field>
              <name>DTGF</name>
              <bitOffset>0</bitOffset>
              <bitWidth>8</bitWidth>
            </field>
            <field>
              <name>DTAE</name>
              <bitOffset>16</bitOffset>
              <bitWidth>1</bitWidth>
            </field>
            <field>
              <name>DTPE</name>
              <bitOffset>17</bitOffset>
              <bitWidth>1</bitWidth>
            </field>
          </fields>
        </register>
        <register>
          <name>ECR</name>
          <addressOffset>0x58</addressOffset>
          <size>0x20</size>
          <fields>
            <field>
              <name>IE</name>
              <bitOffset>0</bitOffset>
              <bitWidth>1</bitWidth>
            </field>
            <field>
              <name>IDIR</name>
              <bitOffset>1</bitOffset>
              <bitWidth>2</bitWidth>
            </field>
            <field>
              <name>FIDX</name>
              <bitOffset>5</bitOffset>
              <bitWidth>1</bitWidth>
            </field>
            <field>
              <name>IPOS</name>
              <bitOffset>6</bitOffset>
              <bitWidth>2</bitWidth>
            </field>
            <field>
              <name>PW</name>
              <bitOffset>16</bitOffset>
              <bitWidth>8</bitWidth>
            </field>
            <field>
              <name>PWPRSC</name>
              <bitOffset>24</bitOffset>
              <bitWidth>3</bitWidth>
            </field>
          </fields>
        </register>
        <register>
          <name>TISEL</name>
          <addressOffset>0x5c</addressOffset>
          <size>0x20</size>
          <fields>
            <field>
              <name>TI1SEL</name>
              <bitOffset>0</bitOffset>
              <bitWidth>4</bitWidth>
            </field>
            <field>
              <name>TI2SEL</name>
              <bitOffset>8</bitOffset>
              <bitWidth>4</bitWidth>
            </field>
            <field>
              <name>TI3SEL</name>
              <bitOffset>16</bitOffset>
              <bitWidth>4</bitWidth>
            </field>
            <field>
              <name>TI4SEL</name>
              <bitOffset>24</bitOffset>
              <bitWidth>4</bitWidth>
            </field>
          </fields>
        </register>
        <register>
          <name>AF1</name>
          <addressOffset>0x60</addressOffset>
          <size>0x20</size>
        </register>
        <register>
          <name>AF2</name>
          <addressOffset>0x64</addressOffset>
          <size>0x20</size>
        </register>
        <register>
          <name>OR</name>
          <addressOffset>0x68</addressOffset>
          <size>0x20</size>
          <fields>
            <field>
              <name>HSE32EN</name>
              <bitOffset>0</bitOffset>
              <bitWidth>1</bitWidth>
            </field>
          </fields>
        </register>
        <register>
          <name>DCR</name>
          <addressOffset>0x3dc</addressOffset>
          <size>0x20</size>
          <fields>
            <field>
              <name>DBA</name>
              <bitOffset>0</bitOffset>
              <bitWidth>5</bitWidth>
            </field>
            <field>
              <name>DBL</name>
              <bitOffset>8</bitOffset>
              <bitWidth>5</bitWidth>
            </field>
          </fields>
        </register>
        <register>
          <name>DMAR</name>
          <addressOffset>0x3e0</addressOffset>
          <size>0x20</size>
          <fields>
            <field>
              <name>DMAB</name>
              <bitOffset>0</bitOffset>
              <bitWidth>32</bitWidth>
            </field>
          </fields>
        </register>
      </registers>
    </peripheral>
    <peripheral>
      <name>TIM17</name>
      <baseAddress>0x40014800</baseAddress>
      <registers>
        <register>
          <name>CR1</name>
          <addressOffset>0x0</addressOffset>
          <size>0x20</size>
          <fields>
            <field>
              <name>CEN</name>
              <bitOffset>0</bitOffset>
              <bitWidth>1</bitWidth>
            </field>
            <field>
              <name>UDIS</name>
              <bitOffset>1</bitOffset>
              <bitWidth>1</bitWidth>
            </field>
            <field>
              <name>URS</name>
              <bitOffset>2</bitOffset>
              <bitWidth>1</bitWidth>
            </field>
            <field>
              <name>OPM</name>
              <bitOffset>3</bitOffset>
              <bitWidth>1</bitWidth>
            </field>
            <field>
              <name>DIR</name>
              <bitOffset>4</bitOffset>
              <bitWidth>1</bitWidth>
            </field>
            <field>
              <name>CMS</name>
              <bitOffset>5</bitOffset>
              <bitWidth>2</bitWidth>
            </field>
            <field>
              <name>ARPE</name>
              <bitOffset>7</bitOffset>
              <bitWidth>1</bitWidth>
            </field>
            <field>
              <name>CKD</name>
              <bitOffset>8</bitOffset>
              <bitWidth>2</bitWidth>
            </field>
            <field>
              <name>UIFREMAP</name>
              <bitOffset>11</bitOffset>
              <bitWidth>1</bitWidth>
            </field>
            <field>
              <name>DITHEN</name>
              <bitOffset>12</bitOffset>
              <bitWidth>1</bitWidth>
            </field>
          </fields>
        </register>
        <register>
          <name>CR2</name>
          <addressOffset>0x4</addressOffset>
          <size>0x20</size>
          <fields>
            <field>
              <name>CCPC</name>
              <bitOffset>0</bitOffset>
              <bitWidth>1</bitWidth>
            </field>
            <field>
              <name>CCUS</name>
              <bitOffset>2</bitOffset>
              <bitWidth>1</bitWidth>
            </field>
            <field>
              <name>CCDS</name>
              <bitOffset>3</bitOffset>
              <bitWidth>1</bitWidth>
            </field>
            <field>
              <name>MMS</name>
              <bitOffset>4</bitOffset>
              <bitWidth>22</bitWidth>
            </field>
            <field>
              <name>TI1S</name>
              <bitOffset>7</bitOffset>
              <bitWidth>1</bitWidth>
            </field>
            <field>
              <name>OIS1</name>
              <bitOffset>8</bitOffset>
              <bitWidth>1</bitWidth>
            </field>
            <field>
              <name>OIS1N</name>
              <bitOffset>9</bitOffset>
              <bitWidth>1</bitWidth>
            </field>
            <field>
              <name>OIS2</name>
              <bitOffset>10</bitOffset>
              <bitWidth>1</bitWidth>
            </field>
            <field>
              <name>OIS2N</name>
              <bitOffset>11</bitOffset>
              <bitWidth>1</bitWidth>
            </field>
            <field>
              <name>OIS3</name>
              <bitOffset>12</bitOffset>
              <bitWidth>1</bitWidth>
            </field>
            <field>
              <name>OIS3N</name>
              <bitOffset>13</bitOffset>
              <bitWidth>1</bitWidth>
            </field>
            <field>
              <name>OIS4</name>
              <bitOffset>14</bitOffset>
              <bitWidth>1</bitWidth>
            </field>
            <field>
              <name>OIS4N</name>
              <bitOffset>15</bitOffset>
              <bitWidth>1</bitWidth>
            </field>
            <field>
              <name>OIS5</name>
              <bitOffset>16</bitOffset>
              <bitWidth>1</bitWidth>
            </field>
            <field>
              <name>OIS6</name>
              <bitOffset>18</bitOffset>
              <bitWidth>1</bitWidth>
            </field>
            <field>
              <name>MMS2</name>
              <bitOffset>20</bitOffset>
              <bitWidth>4</bitWidth>
            </field>
          </fields>
        </register>
        <register>
          <name>SMCR</name>
          <addressOffset>0x8</addressOffset>
          <size>0x20</size>
          <fields>
            <field>
              <name>SMS</name>
              <bitOffset>0</bitOffset>
              <bitWidth>17</bitWidth>
            </field>
            <field>
              <name>OCCS</name>
              <bitOffset>3</bitOffset>
              <bitWidth>1</bitWidth>
            </field>
            <field>
              <name>TS</name>
              <bitOffset>4</bitOffset>
              <bitWidth>18</bitWidth>
            </field>
            <field>
              <name>MSM</name>
              <bitOffset>7</bitOffset>
              <bitWidth>1</bitWidth>
            </field>
            <field>
              <name>ETF</name>
              <bitOffset>8</bitOffset>
              <bitWidth>4</bitWidth>
            </field>
            <field>
              <name>ETPS</name>
              <bitOffset>12</bitOffset>
              <bitWidth>2</bitWidth>
            </field>
            <field>
              <name>ECE</name>
              <bitOffset>14</bitOffset>
              <bitWidth>1</bitWidth>
            </field>
            <field>
              <name>ETP</name>
              <bitOffset>15</bitOffset>
              <bitWidth>1</bitWidth>
            </field>
            <field>
              <name>SMSPE</name>
              <bitOffset>24</bitOffset>
              <bitWidth>1</bitWidth>
            </field>
            <field>
              <name>SMSPS</name>
              <bitOffset>25</bitOffset>
              <bitWidth>1</bitWidth>
            </field>
          </fields>
        </register>
        <register>
          <name>DIER</name>
          <addressOffset>0xc</addressOffset>
          <size>0x20</size>
          <fields>
            <field>
              <name>UIE</name>
              <bitOffset>0</bitOffset>
              <bitWidth>1</bitWidth>
            </field>
            <field>
              <name>CC1IE</name>
              <bitOffset>1</bitOffset>
              <bitWidth>1</bitWidth>
            </field>
            <field>
              <name>CC2IE</name>
              <bitOffset>2</bitOffset>
              <bitWidth>1</bitWidth>
            </field>
            <field>
              <name>CC3IE</name>
              <bitOffset>3</bitOffset>
              <bitWidth>1</bitWidth>
            </field>
            <field>
              <name>CC4IE</name>
              <bitOffset>4</bitOffset>
              <bitWidth>1</bitWidth>
            </field>
            <field>
              <name>COMIE</name>
              <bitOffset>5</bitOffset>
              <bitWidth>1</bitWidth>
            </field>
            <field>
              <name>TIE</name>
              <bitOffset>6</bitOffset>
              <bitWidth>1</bitWidth>
            </field>
            <field>
              <name>BIE</name>
              <bitOffset>7</bitOffset>
              <bitWidth>1</bitWidth>
            </field>
            <field>
              <name>UDE</name>
              <bitOffset>8</bitOffset>
              <bitWidth>1</bitWidth>
            </field>
            <field>
              <name>CC1DE</name>
              <bitOffset>9</bitOffset>
              <bitWidth>1</bitWidth>
            </field>
            <field>
              <name>CC2DE</name>
              <bitOffset>10</bitOffset>
              <bitWidth>1</bitWidth>
            </field>
            <field>
              <name>CC3DE</name>
              <bitOffset>11</bitOffset>
              <bitWidth>1</bitWidth>
            </field>
            <field>
              <name>CC4DE</name>
              <bitOffset>12</bitOffset>
              <bitWidth>1</bitWidth>
            </field>
            <field>
              <name>COMDE</name>
              <bitOffset>13</bitOffset>
              <bitWidth>1</bitWidth>
            </field>
            <field>
              <name>TDE</name>
              <bitOffset>14</bitOffset>
              <bitWidth>1</bitWidth>
            </field>
            <field>
              <name>IDXIE</name>
              <bitOffset>20</bitOffset>
              <bitWidth>1</bitWidth>
            </field>
            <field>
              <name>DIRIE</name>
              <bitOffset>21</bitOffset>
              <bitWidth>1</bitWidth>
            </field>
            <field>
              <name>IERRIE</name>
              <bitOffset>22</bitOffset>
              <bitWidth>1</bitWidth>
            </field>
            <field>
              <name>TERRIE</name>
              <bitOffset>23</bitOffset>
              <bitWidth>1</bitWidth>
            </field>
          </fields>
        </register>
        <register>
          <name>SR</name>
          <addressOffset>0x10</addressOffset>
          <size>0x20</size>
          <fields>
            <field>
              <name>UIF</name>
              <bitOffset>0</bitOffset>
              <bitWidth>1</bitWidth>
            </field>
            <field>
              <name>CC1IF</name>
              <bitOffset>1</bitOffset>
              <bitWidth>1</bitWidth>
            </field>
            <field>
              <name>CC2IF</name>
              <bitOffset>2</bitOffset>
              <bitWidth>1</bitWidth>
            </field>
            <field>
              <name>CC3IF</name>
              <bitOffset>3</bitOffset>
              <bitWidth>1</bitWidth>
            </field>
            <field>
              <name>CC4IF</name>
              <bitOffset>4</bitOffset>
              <bitWidth>1</bitWidth>
            </field>
            <field>
              <name>COMIF</name>
              <bitOffset>5</bitOffset>
              <bitWidth>1</bitWidth>
            </field>
            <field>
              <name>TIF</name>
              <bitOffset>6</bitOffset>
              <bitWidth>1</bitWidth>
            </field>
            <field>
              <name>BIF</name>
              <bitOffset>7</bitOffset>
              <bitWidth>1</bitWidth>
            </field>
            <field>
              <name>B2IF</name>
              <bitOffset>8</bitOffset>
              <bitWidth>1</bitWidth>
            </field>
            <field>
              <name>CC1OF</name>
              <bitOffset>9</bitOffset>
              <bitWidth>1</bitWidth>
            </field>
            <field>
              <name>CC2OF</name>
              <bitOffset>10</bitOffset>
              <bitWidth>1</bitWidth>
            </field>
            <field>
              <name>CC3OF</name>
              <bitOffset>11</bitOffset>
              <bitWidth>1</bitWidth>
            </field>
            <field>
              <name>CC4OF</name>
              <bitOffset>12</bitOffset>
              <bitWidth>1</bitWidth>
            </field>
            <field>
              <name>SBIF</name>
              <bitOffset>13</bitOffset>
              <bitWidth>1</bitWidth>
            </field>
            <field>
              <name>CC5IF</name>
              <bitOffset>16</bitOffset>
              <bitWidth>1</bitWidth>
            </field>
            <field>
              <name>CC6IF</name>
              <bitOffset>17</bitOffset>
              <bitWidth>1</bitWidth>
            </field>
            <field>
              <name>IDXF</name>
              <bitOffset>20</bitOffset>
              <bitWidth>1</bitWidth>
            </field>
            <field>
              <name>DIRF</name>
              <bitOffset>21</bitOffset>
              <bitWidth>1</bitWidth>
            </field>
            <field>
              <name>IERRF</name>
              <bitOffset>22</bitOffset>
              <bitWidth>1</bitWidth>
            </field>
            <field>
              <name>TERRF</name>
              <bitOffset>23</bitOffset>
              <bitWidth>1</bitWidth>
            </field>
          </fields>
        </register>
        <register>
          <name>EGR</name>
          <addressOffset>0x14</addressOffset>
          <size>0x20</size>
          <fields>
            <field>
              <name>UG</name>
              <bitOffset>0</bitOffset>
              <bitWidth>1</bitWidth>
            </field>
            <field>
              <name>CC1G</name>
              <bitOffset>1</bitOffset>
              <bitWidth>1</bitWidth>
            </field>
            <field>
              <name>CC2G</name>
              <bitOffset>2</bitOffset>
              <bitWidth>1</bitWidth>
            </field>
            <field>
              <name>CC3G</name>
              <bitOffset>3</bitOffset>
              <bitWidth>1</bitWidth>
            </field>
            <field>
              <name>CC4G</name>
              <bitOffset>4</bitOffset>
              <bitWidth>1</bitWidth>
            </field>
            <field>
              <name>COMG</name>
              <bitOffset>5</bitOffset>
              <bitWidth>1</bitWidth>
            </field>
            <field>
              <name>TG</name>
              <bitOffset>6</bitOffset>
              <bitWidth>1</bitWidth>
            </field>
            <field>
              <name>BG</name>
              <bitOffset>7</bitOffset>
              <bitWidth>1</bitWidth>
            </field>
            <field>
              <name>B2G</name>
              <bitOffset>8</bitOffset>
              <bitWidth>1</bitWidth>
            </field>
          </fields>
        </register>
        <register>
          <name>CCMR1</name>
          <addressOffset>0x18</addressOffset>
          <size>0x20</size>
          <fields>
            <field>
              <name>CC1S</name>
              <bitOffset>0</bitOffset>
              <bitWidth>2</bitWidth>
            </field>
            <field>
              <name>OC1FE</name>
              <bitOffset>2</bitOffset>
              <bitWidth>1</bitWidth>
            </field>
            <field>
              <name>OC1PE</name>
              <bitOffset>3</bitOffset>
              <bitWidth>1</bitWidth>
            </field>
            <field>
              <name>OC1M</name>
              <bitOffset>4</bitOffset>
              <bitWidth>13</bitWidth>
            </field>
            <field>
              <name>OC1CE</name>
              <bitOffset>7</bitOffset>
              <bitWidth>1</bitWidth>
            </field>
            <field>
              <name>CC2S</name>
              <bitOffset>8</bitOffset>
              <bitWidth>2</bitWidth>
            </field>
            <field>
              <name>OC2FE</name>
              <bitOffset>10</bitOffset>
              <bitWidth>1</bitWidth>
            </field>
            <field>
              <name>OC2PE</name>
              <bitOffset>11</bitOffset>
              <bitWidth>1</bitWidth>
            </field>
            <field>
              <name>OC2M</name>
              <bitOffset>12</bitOffset>
              <bitWidth>13</bitWidth>
            </field>
            <field>
              <name>OC2CE</name>
              <bitOffset>15</bitOffset>
              <bitWidth>1</bitWidth>
            </field>
          </fields>
        </register>
        <register>
          <name>CCMR2</name>
          <addressOffset>0x1c</addressOffset>
          <size>0x20</size>
          <fields>
            <field>
              <name>CC3S</name>
              <bitOffset>0</bitOffset>
              <bitWidth>2</bitWidth>
            </field>
            <field>
              <name>OC3FE</name>
              <bitOffset>2</bitOffset>
              <bitWidth>1</bitWidth>
            </field>
            <field>
              <name>OC3PE</name>
              <bitOffset>3</bitOffset>
              <bitWidth>1</bitWidth>
            </field>
            <field>
              <name>OC3M</name>
              <bitOffset>4</bitOffset>
              <bitWidth>13</bitWidth>
            </field>
            <field>
              <name>OC3CE</name>
              <bitOffset>7</bitOffset>
              <bitWidth>1</bitWidth>
            </field>
            <field>
              <name>CC4S</name>
              <bitOffset>8</bitOffset>
              <bitWidth>2</bitWidth>
            </field>
            <field>
              <name>OC4FE</name>
              <bitOffset>10</bitOffset>
              <bitWidth>1</bitWidth>
            </field>
            <field>
              <name>OC4PE</name>
              <bitOffset>11</bitOffset>
              <bitWidth>1</bitWidth>
            </field>
            <field>
              <name>OC4M</name>
              <bitOffset>12</bitOffset>
              <bitWidth>13</bitWidth>
            </field>
            <field>
              <name>OC4CE</name>
              <bitOffset>15</bitOffset>
              <bitWidth>1</bitWidth>
            </field>
          </fields>
        </register>
        <register>
          <name>CCER</name>
          <addressOffset>0x20</addressOffset>
          <size>0x20</size>
          <fields>
            <field>
              <name>CC1E</name>
              <bitOffset>0</bitOffset>
              <bitWidth>1</bitWidth>
            </field>
            <field>
              <name>CC1P</name>
              <bitOffset>1</bitOffset>
              <bitWidth>1</bitWidth>
            </field>
            <field>
              <name>CC1NE</name>
              <bitOffset>2</bitOffset>
              <bitWidth>1</bitWidth>
            </field>
            <field>
              <name>CC1NP</name>
              <bitOffset>3</bitOffset>
              <bitWidth>1</bitWidth>
            </field>
            <field>
              <name>CC2E</name>
              <bitOffset>4</bitOffset>
              <bitWidth>1</bitWidth>
            </field>
            <field>
              <name>CC2P</name>
              <bitOffset>5</bitOffset>
              <bitWidth>1</bitWidth>
            </field>
            <field>
              <name>CC2NE</name>
              <bitOffset>6</bitOffset>
              <bitWidth>1</bitWidth>
            </field>
            <field>
              <name>CC2NP</name>
              <bitOffset>7</bitOffset>
              <bitWidth>1</bitWidth>
            </field>
            <field>
              <name>CC3E</name>
              <bitOffset>8</bitOffset>
              <bitWidth>1</bitWidth>
            </field>
            <field>
              <name>CC3P</name>
              <bitOffset>9</bitOffset>
              <bitWidth>1</bitWidth>
            </field>
            <field>
              <name>CC3NE</name>
              <bitOffset>10</bitOffset>
              <bitWidth>1</bitWidth>
            </field>
            <field>
              <name>CC3NP</name>
              <bitOffset>11</bitOffset>
              <bitWidth>1</bitWidth>
            </field>
            <field>
              <name>CC4E</name>
              <bitOffset>12</bitOffset>
              <bitWidth>1</bitWidth>
            </field>
            <field>
              <name>CC4P</name>
              <bitOffset>13</bitOffset>
              <bitWidth>1</bitWidth>
            </field>
            <field>
              <name>CC4NE</name>
              <bitOffset>14</bitOffset>
              <bitWidth>1</bitWidth>
            </field>
            <field>
              <name>CC4NP</name>
              <bitOffset>15</bitOffset>
              <bitWidth>1</bitWidth>
            </field>
            <field>
              <name>CC5E</name>
              <bitOffset>16</bitOffset>
              <bitWidth>1</bitWidth>
            </field>
            <field>
              <name>CC5P</name>
              <bitOffset>17</bitOffset>
              <bitWidth>1</bitWidth>
            </field>
            <field>
              <name>CC6E</name>
              <bitOffset>20</bitOffset>
              <bitWidth>1</bitWidth>
            </field>
            <field>
              <name>CC6P</name>
              <bitOffset>21</bitOffset>
              <bitWidth>1</bitWidth>
            </field>
          </fields>
        </register>
        <register>
          <name>CNT</name>
          <addressOffset>0x24</addressOffset>
          <size>0x20</size>
          <fields>
            <field>
              <name>CNT</name>
              <bitOffset>0</bitOffset>
              <bitWidth>32</bitWidth>
            </field>
            <field>
              <name>UIFCPY</name>
              <bitOffset>31</bitOffset>
              <bitWidth>1</bitWidth>
            </field>
          </fields>
        </register>
        <register>
          <name>PSC</name>
          <addressOffset>0x28</addressOffset>
          <size>0x20</size>
          <fields>
            <field>
              <name>PSC</name>
              <bitOffset>0</bitOffset>
              <bitWidth>16</bitWidth>
            </field>
          </fields>
        </register>
        <register>
          <name>ARR</name>
          <addressOffset>0x2c</addressOffset>
          <size>0x20</size>
          <fields>
            <field>
              <name>ARR</name>
              <bitOffset>0</bitOffset>
              <bitWidth>32</bitWidth>
            </field>
          </fields>
        </register>
        <register>
          <name>RCR</name>
          <addressOffset>0x30</addressOffset>
          <size>0x20</size>
          <fields>
            <field>
              <name>REP</name>
              <bitOffset>0</bitOffset>
              <bitWidth>16</bitWidth>
            </field>
          </fields>
        </register>
        <register>
          <name>CCR1</name>
          <addressOffset>0x34</addressOffset>
          <size>0x20</size>
          <fields>
            <field>
              <name>CCR1</name>
              <bitOffset>0</bitOffset>
              <bitWidth>16</bitWidth>
            </field>
          </fields>
        </register>
        <register>
          <name>CCR2</name>
          <addressOffset>0x38</addressOffset>
          <size>0x20</size>
          <fields>
            <field>
              <name>CCR2</name>
              <bitOffset>0</bitOffset>
              <bitWidth>16</bitWidth>
            </field>
          </fields>
        </register>
        <register>
          <name>CCR3</name>
          <addressOffset>0x3c</addressOffset>
          <size>0x20</size>
          <fields>
            <field>
              <name>CCR3</name>
              <bitOffset>0</bitOffset>
              <bitWidth>16</bitWidth>
            </field>
          </fields>
        </register>
        <register>
          <name>CCR4</name>
          <addressOffset>0x40</addressOffset>
          <size>0x20</size>
          <fields>
            <field>
              <name>CCR4</name>
              <bitOffset>0</bitOffset>
              <bitWidth>16</bitWidth>
            </field>
          </fields>
        </register>
        <register>
          <name>BDTR</name>
          <addressOffset>0x44</addressOffset>
          <size>0x20</size>
          <fields>
            <field>
              <name>DTG</name>
              <bitOffset>0</bitOffset>
              <bitWidth>8</bitWidth>
            </field>
            <field>
              <name>LOCK</name>
              <bitOffset>8</bitOffset>
              <bitWidth>2</bitWidth>
            </field>
            <field>
              <name>OSSI</name>
              <bitOffset>10</bitOffset>
              <bitWidth>1</bitWidth>
            </field>
            <field>
              <name>OSSR</name>
              <bitOffset>11</bitOffset>
              <bitWidth>1</bitWidth>
            </field>
            <field>
              <name>BKE</name>
              <bitOffset>12</bitOffset>
              <bitWidth>1</bitWidth>
            </field>
            <field>
              <name>BKP</name>
              <bitOffset>13</bitOffset>
              <bitWidth>1</bitWidth>
            </field>
            <field>
              <name>AOE</name>
              <bitOffset>14</bitOffset>
              <bitWidth>1</bitWidth>
            </field>
            <field>
              <name>MOE</name>
              <bitOffset>15</bitOffset>
              <bitWidth>1</bitWidth>
            </field>
            <field>
              <name>BKF</name>
              <bitOffset>16</bitOffset>
              <bitWidth>4</bitWidth>
            </field>
            <field>
              <name>BK2F</name>
              <bitOffset>20</bitOffset>
              <bitWidth>4</bitWidth>
            </field>
            <field>
              <name>BK2E</name>
              <bitOffset>24</bitOffset>
              <bitWidth>1</bitWidth>
            </field>
            <field>
              <name>BK2P</name>
              <bitOffset>25</bitOffset>
              <bitWidth>1</bitWidth>
            </field>
            <field>
              <name>BKDSRM</name>
              <bitOffset>26</bitOffset>
              <bitWidth>1</bitWidth>
            </field>
            <field>
              <name>BK2DSRM</name>
              <bitOffset>27</bitOffset>
              <bitWidth>1</bitWidth>
            </field>
            <field>
              <name>BKBID</name>
              <bitOffset>28</bitOffset>
              <bitWidth>1</bitWidth>
            </field>
            <field>
              <name>BK2BID</name>
              <bitOffset>29</bitOffset>
              <bitWidth>1</bitWidth>
            </field>
          </fields>
        </register>
        <register>
          <name>CCR5</name>
          <addressOffset>0x48</addressOffset>
          <size>0x20</size>
          <fields>
            <field>
              <name>CCR5</name>
              <bitOffset>0</bitOffset>
              <bitWidth>32</bitWidth>
            </field>
            <field>
              <name>GC5C1</name>
              <bitOffset>29</bitOffset>
              <bitWidth>1</bitWidth>
            </field>
            <field>
              <name>GC5C2</name>
              <bitOffset>30</bitOffset>
              <bitWidth>1</bitWidth>
            </field>
            <field>
              <name>GC5C3</name>
              <bitOffset>31</bitOffset>
              <bitWidth>1</bitWidth>
            </field>
          </fields>
        </register>
        <register>
          <name>CCR6</name>
          <addressOffset>0x4c</addressOffset>
          <size>0x20</size>
          <fields>
            <field>
              <name>CCR6</name>
              <bitOffset>0</bitOffset>
              <bitWidth>16</bitWidth>
            </field>
          </fields>
        </register>
        <register>
          <name>CCMR3</name>
          <addressOffset>0x50</addressOffset>
          <size>0x20</size>
          <fields>
            <field>
              <name>OC5FE</name>
              <bitOffset>2</bitOffset>
              <bitWidth>1</bitWidth>
            </field>
            <field>
              <name>OC5PE</name>
              <bitOffset>3</bitOffset>
              <bitWidth>1</bitWidth>
            </field>
            <field>
              <name>OC5M</name>
              <bitOffset>4</bitOffset>
              <bitWidth>13</bitWidth>
            </field>
            <field>
              <name>OC5CE</name>
              <bitOffset>7</bitOffset>
              <bitWidth>1</bitWidth>
            </field>
            <field>
              <name>OC6FE</name>
              <bitOffset>10</bitOffset>
              <bitWidth>1</bitWidth>
            </field>
            <field>
              <name>OC6PE</name>
              <bitOffset>11</bitOffset>
              <bitWidth>1</bitWidth>
            </field>
            <field>
              <name>OC6M</name>
              <bitOffset>12</bitOffset>
              <bitWidth>13</bitWidth>
            </field>
            <field>
              <name>OC6CE</name>
              <bitOffset>15</bitOffset>
              <bitWidth>1</bitWidth>
            </field>
          </fields>
        </register>
        <register>
          <name>DTR2</name>
          <addressOffset>0x54</addressOffset>
          <size>0x20</size>
          <fields>
            <field>
              <name>DTGF</name>
              <bitOffset>0</bitOffset>
              <bitWidth>8</bitWidth>
            </field>
            <field>
              <name>DTAE</name>
              <bitOffset>16</bitOffset>
              <bitWidth>1</bitWidth>
            </field>
            <field>
              <name>DTPE</name>
              <bitOffset>17</bitOffset>
              <bitWidth>1</bitWidth>
            </field>
          </fields>
        </register>
        <register>
          <name>ECR</name>
          <addressOffset>0x58</addressOffset>
          <size>0x20</size>
          <fields>
            <field>
              <name>IE</name>
              <bitOffset>0</bitOffset>
              <bitWidth>1</bitWidth>
            </field>
            <field>
              <name>IDIR</name>
              <bitOffset>1</bitOffset>
              <bitWidth>2</bitWidth>
            </field>
            <field>
              <name>FIDX</name>
              <bitOffset>5</bitOffset>
              <bitWidth>1</bitWidth>
            </field>
            <field>
              <name>IPOS</name>
              <bitOffset>6</bitOffset>
              <bitWidth>2</bitWidth>
            </field>
            <field>
              <name>PW</name>
              <bitOffset>16</bitOffset>
              <bitWidth>8</bitWidth>
            </field>
            <field>
              <name>PWPRSC</name>
              <bitOffset>24</bitOffset>
              <bitWidth>3</bitWidth>
            </field>
          </fields>
        </register>
        <register>
          <name>TISEL</name>
          <addressOffset>0x5c</addressOffset>
          <size>0x20</size>
          <fields>
            <field>
              <name>TI1SEL</name>
              <bitOffset>0</bitOffset>
              <bitWidth>4</bitWidth>
            </field>
            <field>
              <name>TI2SEL</name>
              <bitOffset>8</bitOffset>
              <bitWidth>4</bitWidth>
            </field>
            <field>
              <name>TI3SEL</name>
              <bitOffset>16</bitOffset>
              <bitWidth>4</bitWidth>
            </field>
            <field>
              <name>TI4SEL</name>
              <bitOffset>24</bitOffset>
              <bitWidth>4</bitWidth>
            </field>
          </fields>
        </register>
        <register>
          <name>AF1</name>
          <addressOffset>0x60</addressOffset>
          <size>0x20</size>
        </register>
        <register>
          <name>AF2</name>
          <addressOffset>0x64</addressOffset>
          <size>0x20</size>
        </register>
        <register>
          <name>OR</name>
          <addressOffset>0x68</addressOffset>
          <size>0x20</size>
          <fields>
            <field>
              <name>HSE32EN</name>
              <bitOffset>0</bitOffset>
              <bitWidth>1</bitWidth>
            </field>
          </fields>
        </register>
        <register>
          <name>DCR</name>
          <addressOffset>0x3dc</addressOffset>
          <size>0x20</size>
          <fields>
            <field>
              <name>DBA</name>
              <bitOffset>0</bitOffset>
              <bitWidth>5</bitWidth>
            </field>
            <field>
              <name>DBL</name>
              <bitOffset>8</bitOffset>
              <bitWidth>5</bitWidth>
            </field>
          </fields>
        </register>
        <register>
          <name>DMAR</name>
          <addressOffset>0x3e0</addressOffset>
          <size>0x20</size>
          <fields>
            <field>
              <name>DMAB</name>
              <bitOffset>0</bitOffset>
              <bitWidth>32</bitWidth>
            </field>
          </fields>
        </register>
      </registers>
    </peripheral>
    <peripheral>
      <name>TIM20</name>
      <baseAddress>0x40015000</baseAddress>
      <registers>
        <register>
          <name>CR1</name>
          <addressOffset>0x0</addressOffset>
          <size>0x20</size>
          <fields>
            <field>
              <name>CEN</name>
              <bitOffset>0</bitOffset>
              <bitWidth>1</bitWidth>
            </field>
            <field>
              <name>UDIS</name>
              <bitOffset>1</bitOffset>
              <bitWidth>1</bitWidth>
            </field>
            <field>
              <name>URS</name>
              <bitOffset>2</bitOffset>
              <bitWidth>1</bitWidth>
            </field>
            <field>
              <name>OPM</name>
              <bitOffset>3</bitOffset>
              <bitWidth>1</bitWidth>
            </field>
            <field>
              <name>DIR</name>
              <bitOffset>4</bitOffset>
              <bitWidth>1</bitWidth>
            </field>
            <field>
              <name>CMS</name>
              <bitOffset>5</bitOffset>
              <bitWidth>2</bitWidth>
            </field>
            <field>
              <name>ARPE</name>
              <bitOffset>7</bitOffset>
              <bitWidth>1</bitWidth>
            </field>
            <field>
              <name>CKD</name>
              <bitOffset>8</bitOffset>
              <bitWidth>2</bitWidth>
            </field>
            <field>
              <name>UIFREMAP</name>
              <bitOffset>11</bitOffset>
              <bitWidth>1</bitWidth>
            </field>
            <field>
              <name>DITHEN</name>
              <bitOffset>12</bitOffset>
              <bitWidth>1</bitWidth>
            </field>
          </fields>
        </register>
        <register>
          <name>CR2</name>
          <addressOffset>0x4</addressOffset>
          <size>0x20</size>
          <fields>
            <field>
              <name>CCPC</name>
              <bitOffset>0</bitOffset>
              <bitWidth>1</bitWidth>
            </field>
            <field>
              <name>CCUS</name>
              <bitOffset>2</bitOffset>
              <bitWidth>1</bitWidth>
            </field>
            <field>
              <name>CCDS</name>
              <bitOffset>3</bitOffset>
              <bitWidth>1</bitWidth>
            </field>
            <field>
              <name>MMS</name>
              <bitOffset>4</bitOffset>
              <bitWidth>22</bitWidth>
            </field>
            <field>
              <name>TI1S</name>
              <bitOffset>7</bitOffset>
              <bitWidth>1</bitWidth>
            </field>
            <field>
              <name>OIS1</name>
              <bitOffset>8</bitOffset>
              <bitWidth>1</bitWidth>
            </field>
            <field>
              <name>OIS1N</name>
              <bitOffset>9</bitOffset>
              <bitWidth>1</bitWidth>
            </field>
            <field>
              <name>OIS2</name>
              <bitOffset>10</bitOffset>
              <bitWidth>1</bitWidth>
            </field>
            <field>
              <name>OIS2N</name>
              <bitOffset>11</bitOffset>
              <bitWidth>1</bitWidth>
            </field>
            <field>
              <name>OIS3</name>
              <bitOffset>12</bitOffset>
              <bitWidth>1</bitWidth>
            </field>
            <field>
              <name>OIS3N</name>
              <bitOffset>13</bitOffset>
              <bitWidth>1</bitWidth>
            </field>
            <field>
              <name>OIS4</name>
              <bitOffset>14</bitOffset>
              <bitWidth>1</bitWidth>
            </field>
            <field>
              <name>OIS4N</name>
              <bitOffset>15</bitOffset>
              <bitWidth>1</bitWidth>
            </field>
            <field>
              <name>OIS5</name>
              <bitOffset>16</bitOffset>
              <bitWidth>1</bitWidth>
            </field>
            <field>
              <name>OIS6</name>
              <bitOffset>18</bitOffset>
              <bitWidth>1</bitWidth>
            </field>
            <field>
              <name>MMS2</name>
              <bitOffset>20</bitOffset>
              <bitWidth>4</bitWidth>
            </field>
          </fields>
        </register>
        <register>
          <name>SMCR</name>
          <addressOffset>0x8</addressOffset>
          <size>0x20</size>
          <fields>
            <field>
              <name>SMS</name>
              <bitOffset>0</bitOffset>
              <bitWidth>17</bitWidth>
            </field>
            <field>
              <name>OCCS</name>
              <bitOffset>3</bitOffset>
              <bitWidth>1</bitWidth>
            </field>
            <field>
              <name>TS</name>
              <bitOffset>4</bitOffset>
              <bitWidth>18</bitWidth>
            </field>
            <field>
              <name>MSM</name>
              <bitOffset>7</bitOffset>
              <bitWidth>1</bitWidth>
            </field>
            <field>
              <name>ETF</name>
              <bitOffset>8</bitOffset>
              <bitWidth>4</bitWidth>
            </field>
            <field>
              <name>ETPS</name>
              <bitOffset>12</bitOffset>
              <bitWidth>2</bitWidth>
            </field>
            <field>
              <name>ECE</name>
              <bitOffset>14</bitOffset>
              <bitWidth>1</bitWidth>
            </field>
            <field>
              <name>ETP</name>
              <bitOffset>15</bitOffset>
              <bitWidth>1</bitWidth>
            </field>
            <field>
              <name>SMSPE</name>
              <bitOffset>24</bitOffset>
              <bitWidth>1</bitWidth>
            </field>
            <field>
              <name>SMSPS</name>
              <bitOffset>25</bitOffset>
              <bitWidth>1</bitWidth>
            </field>
          </fields>
        </register>
        <register>
          <name>DIER</name>
          <addressOffset>0xc</addressOffset>
          <size>0x20</size>
          <fields>
            <field>
              <name>UIE</name>
              <bitOffset>0</bitOffset>
              <bitWidth>1</bitWidth>
            </field>
            <field>
              <name>CC1IE</name>
              <bitOffset>1</bitOffset>
              <bitWidth>1</bitWidth>
            </field>
            <field>
              <name>CC2IE</name>
              <bitOffset>2</bitOffset>
              <bitWidth>1</bitWidth>
            </field>
            <field>
              <name>CC3IE</name>
              <bitOffset>3</bitOffset>
              <bitWidth>1</bitWidth>
            </field>
            <field>
              <name>CC4IE</name>
              <bitOffset>4</bitOffset>
              <bitWidth>1</bitWidth>
            </field>
            <field>
              <name>COMIE</name>
              <bitOffset>5</bitOffset>
              <bitWidth>1</bitWidth>
            </field>
            <field>
              <name>TIE</name>
              <bitOffset>6</bitOffset>
              <bitWidth>1</bitWidth>
            </field>
            <field>
              <name>BIE</name>
              <bitOffset>7</bitOffset>
              <bitWidth>1</bitWidth>
            </field>
            <field>
              <name>UDE</name>
              <bitOffset>8</bitOffset>
              <bitWidth>1</bitWidth>
            </field>
            <field>
              <name>CC1DE</name>
              <bitOffset>9</bitOffset>
              <bitWidth>1</bitWidth>
            </field>
            <field>
              <name>CC2DE</name>
              <bitOffset>10</bitOffset>
              <bitWidth>1</bitWidth>
            </field>
            <field>
              <name>CC3DE</name>
              <bitOffset>11</bitOffset>
              <bitWidth>1</bitWidth>
            </field>
            <field>
              <name>CC4DE</name>
              <bitOffset>12</bitOffset>
              <bitWidth>1</bitWidth>
            </field>
            <field>
              <name>COMDE</name>
              <bitOffset>13</bitOffset>
              <bitWidth>1</bitWidth>
            </field>
            <field>
              <name>TDE</name>
              <bitOffset>14</bitOffset>
              <bitWidth>1</bitWidth>
            </field>
            <field>
              <name>IDXIE</name>
              <bitOffset>20</bitOffset>
              <bitWidth>1</bitWidth>
            </field>
            <field>
              <name>DIRIE</name>
              <bitOffset>21</bitOffset>
              <bitWidth>1</bitWidth>
            </field>
            <field>
              <name>IERRIE</name>
              <bitOffset>22</bitOffset>
              <bitWidth>1</bitWidth>
            </field>
            <field>
              <name>TERRIE</name>
              <bitOffset>23</bitOffset>
              <bitWidth>1</bitWidth>
            </field>
          </fields>
        </register>
        <register>
          <name>SR</name>
          <addressOffset>0x10</addressOffset>
          <size>0x20</size>
          <fields>
            <field>
              <name>UIF</name>
              <bitOffset>0</bitOffset>
              <bitWidth>1</bitWidth>
            </field>
            <field>
              <name>CC1IF</name>
              <bitOffset>1</bitOffset>
              <bitWidth>1</bitWidth>
            </field>
            <field>
              <name>CC2IF</name>
              <bitOffset>2</bitOffset>
              <bitWidth>1</bitWidth>
            </field>
            <field>
              <name>CC3IF</name>
              <bitOffset>3</bitOffset>
              <bitWidth>1</bitWidth>
            </field>
            <field>
              <name>CC4IF</name>
              <bitOffset>4</bitOffset>
              <bitWidth>1</bitWidth>
            </field>
            <field>
              <name>COMIF</name>
              <bitOffset>5</bitOffset>
              <bitWidth>1</bitWidth>
            </field>
            <field>
              <name>TIF</name>
              <bitOffset>6</bitOffset>
              <bitWidth>1</bitWidth>
            </field>
            <field>
              <name>BIF</name>
              <bitOffset>7</bitOffset>
              <bitWidth>1</bitWidth>
            </field>
            <field>
              <name>B2IF</name>
              <bitOffset>8</bitOffset>
              <bitWidth>1</bitWidth>
            </field>
            <field>
              <name>CC1OF</name>
              <bitOffset>9</bitOffset>
              <bitWidth>1</bitWidth>
            </field>
            <field>
              <name>CC2OF</name>
              <bitOffset>10</bitOffset>
              <bitWidth>1</bitWidth>
            </field>
            <field>
              <name>CC3OF</name>
              <bitOffset>11</bitOffset>
              <bitWidth>1</bitWidth>
            </field>
            <field>
              <name>CC4OF</name>
              <bitOffset>12</bitOffset>
              <bitWidth>1</bitWidth>
            </field>
            <field>
              <name>SBIF</name>
              <bitOffset>13</bitOffset>
              <bitWidth>1</bitWidth>
            </field>
            <field>
              <name>CC5IF</name>
              <bitOffset>16</bitOffset>
              <bitWidth>1</bitWidth>
            </field>
            <field>
              <name>CC6IF</name>
              <bitOffset>17</bitOffset>
              <bitWidth>1</bitWidth>
            </field>
            <field>
              <name>IDXF</name>
              <bitOffset>20</bitOffset>
              <bitWidth>1</bitWidth>
            </field>
            <field>
              <name>DIRF</name>
              <bitOffset>21</bitOffset>
              <bitWidth>1</bitWidth>
            </field>
            <field>
              <name>IERRF</name>
              <bitOffset>22</bitOffset>
              <bitWidth>1</bitWidth>
            </field>
            <field>
              <name>TERRF</name>
              <bitOffset>23</bitOffset>
              <bitWidth>1</bitWidth>
            </field>
          </fields>
        </register>
        <register>
          <name>EGR</name>
          <addressOffset>0x14</addressOffset>
          <size>0x20</size>
          <fields>
            <field>
              <name>UG</name>
              <bitOffset>0</bitOffset>
              <bitWidth>1</bitWidth>
            </field>
            <field>
              <name>CC1G</name>
              <bitOffset>1</bitOffset>
              <bitWidth>1</bitWidth>
            </field>
            <field>
              <name>CC2G</name>
              <bitOffset>2</bitOffset>
              <bitWidth>1</bitWidth>
            </field>
            <field>
              <name>CC3G</name>
              <bitOffset>3</bitOffset>
              <bitWidth>1</bitWidth>
            </field>
            <field>
              <name>CC4G</name>
              <bitOffset>4</bitOffset>
              <bitWidth>1</bitWidth>
            </field>
            <field>
              <name>COMG</name>
              <bitOffset>5</bitOffset>
              <bitWidth>1</bitWidth>
            </field>
            <field>
              <name>TG</name>
              <bitOffset>6</bitOffset>
              <bitWidth>1</bitWidth>
            </field>
            <field>
              <name>BG</name>
              <bitOffset>7</bitOffset>
              <bitWidth>1</bitWidth>
            </field>
            <field>
              <name>B2G</name>
              <bitOffset>8</bitOffset>
              <bitWidth>1</bitWidth>
            </field>
          </fields>
        </register>
        <register>
          <name>CCMR1</name>
          <addressOffset>0x18</addressOffset>
          <size>0x20</size>
          <fields>
            <field>
              <name>CC1S</name>
              <bitOffset>0</bitOffset>
              <bitWidth>2</bitWidth>
            </field>
            <field>
              <name>OC1FE</name>
              <bitOffset>2</bitOffset>
              <bitWidth>1</bitWidth>
            </field>
            <field>
              <name>OC1PE</name>
              <bitOffset>3</bitOffset>
              <bitWidth>1</bitWidth>
            </field>
            <field>
              <name>OC1M</name>
              <bitOffset>4</bitOffset>
              <bitWidth>13</bitWidth>
            </field>
            <field>
              <name>OC1CE</name>
              <bitOffset>7</bitOffset>
              <bitWidth>1</bitWidth>
            </field>
            <field>
              <name>CC2S</name>
              <bitOffset>8</bitOffset>
              <bitWidth>2</bitWidth>
            </field>
            <field>
              <name>OC2FE</name>
              <bitOffset>10</bitOffset>
              <bitWidth>1</bitWidth>
            </field>
            <field>
              <name>OC2PE</name>
              <bitOffset>11</bitOffset>
              <bitWidth>1</bitWidth>
            </field>
            <field>
              <name>OC2M</name>
              <bitOffset>12</bitOffset>
              <bitWidth>13</bitWidth>
            </field>
            <field>
              <name>OC2CE</name>
              <bitOffset>15</bitOffset>
              <bitWidth>1</bitWidth>
            </field>
          </fields>
        </register>
        <register>
          <name>CCMR2</name>
          <addressOffset>0x1c</addressOffset>
          <size>0x20</size>
          <fields>
            <field>
              <name>CC3S</name>
              <bitOffset>0</bitOffset>
              <bitWidth>2</bitWidth>
            </field>
            <field>
              <name>OC3FE</name>
              <bitOffset>2</bitOffset>
              <bitWidth>1</bitWidth>
            </field>
            <field>
              <name>OC3PE</name>
              <bitOffset>3</bitOffset>
              <bitWidth>1</bitWidth>
            </field>
            <field>
              <name>OC3M</name>
              <bitOffset>4</bitOffset>
              <bitWidth>13</bitWidth>
            </field>
            <field>
              <name>OC3CE</name>
              <bitOffset>7</bitOffset>
              <bitWidth>1</bitWidth>
            </field>
            <field>
              <name>CC4S</name>
              <bitOffset>8</bitOffset>
              <bitWidth>2</bitWidth>
            </field>
            <field>
              <name>OC4FE</name>
              <bitOffset>10</bitOffset>
              <bitWidth>1</bitWidth>
            </field>
            <field>
              <name>OC4PE</name>
              <bitOffset>11</bitOffset>
              <bitWidth>1</bitWidth>
            </field>
            <field>
              <name>OC4M</name>
              <bitOffset>12</bitOffset>
              <bitWidth>13</bitWidth>
            </field>
            <field>
              <name>OC4CE</name>
              <bitOffset>15</bitOffset>
              <bitWidth>1</bitWidth>
            </field>
          </fields>
        </register>
        <register>
          <name>CCER</name>
          <addressOffset>0x20</addressOffset>
          <size>0x20</size>
          <fields>
            <field>
              <name>CC1E</name>
              <bitOffset>0</bitOffset>
              <bitWidth>1</bitWidth>
            </field>
            <field>
              <name>CC1P</name>
              <bitOffset>1</bitOffset>
              <bitWidth>1</bitWidth>
            </field>
            <field>
              <name>CC1NE</name>
              <bitOffset>2</bitOffset>
              <bitWidth>1</bitWidth>
            </field>
            <field>
              <name>CC1NP</name>
              <bitOffset>3</bitOffset>
              <bitWidth>1</bitWidth>
            </field>
            <field>
              <name>CC2E</name>
              <bitOffset>4</bitOffset>
              <bitWidth>1</bitWidth>
            </field>
            <field>
              <name>CC2P</name>
              <bitOffset>5</bitOffset>
              <bitWidth>1</bitWidth>
            </field>
            <field>
              <name>CC2NE</name>
              <bitOffset>6</bitOffset>
              <bitWidth>1</bitWidth>
            </field>
            <field>
              <name>CC2NP</name>
              <bitOffset>7</bitOffset>
              <bitWidth>1</bitWidth>
            </field>
            <field>
              <name>CC3E</name>
              <bitOffset>8</bitOffset>
              <bitWidth>1</bitWidth>
            </field>
            <field>
              <name>CC3P</name>
              <bitOffset>9</bitOffset>
              <bitWidth>1</bitWidth>
            </field>
            <field>
              <name>CC3NE</name>
              <bitOffset>10</bitOffset>
              <bitWidth>1</bitWidth>
            </field>
            <field>
              <name>CC3NP</name>
              <bitOffset>11</bitOffset>
              <bitWidth>1</bitWidth>
            </field>
            <field>
              <name>CC4E</name>
              <bitOffset>12</bitOffset>
              <bitWidth>1</bitWidth>
            </field>
            <field>
              <name>CC4P</name>
              <bitOffset>13</bitOffset>
              <bitWidth>1</bitWidth>
            </field>
            <field>
              <name>CC4NE</name>
              <bitOffset>14</bitOffset>
              <bitWidth>1</bitWidth>
            </field>
            <field>
              <name>CC4NP</name>
              <bitOffset>15</bitOffset>
              <bitWidth>1</bitWidth>
            </field>
            <field>
              <name>CC5E</name>
              <bitOffset>16</bitOffset>
              <bitWidth>1</bitWidth>
            </field>
            <field>
              <name>CC5P</name>
              <bitOffset>17</bitOffset>
              <bitWidth>1</bitWidth>
            </field>
            <field>
              <name>CC6E</name>
              <bitOffset>20</bitOffset>
              <bitWidth>1</bitWidth>
            </field>
            <field>
              <name>CC6P</name>
              <bitOffset>21</bitOffset>
              <bitWidth>1</bitWidth>
            </field>
          </fields>
        </register>
        <register>
          <name>CNT</name>
          <addressOffset>0x24</addressOffset>
          <size>0x20</size>
          <fields>
            <field>
              <name>CNT</name>
              <bitOffset>0</bitOffset>
              <bitWidth>32</bitWidth>
            </field>
            <field>
              <name>UIFCPY</name>
              <bitOffset>31</bitOffset>
              <bitWidth>1</bitWidth>
            </field>
          </fields>
        </register>
        <register>
          <name>PSC</name>
          <addressOffset>0x28</addressOffset>
          <size>0x20</size>
          <fields>
            <field>
              <name>PSC</name>
              <bitOffset>0</bitOffset>
              <bitWidth>16</bitWidth>
            </field>
          </fields>
        </register>
        <register>
          <name>ARR</name>
          <addressOffset>0x2c</addressOffset>
          <size>0x20</size>
          <fields>
            <field>
              <name>ARR</name>
              <bitOffset>0</bitOffset>
              <bitWidth>32</bitWidth>
            </field>
          </fields>
        </register>
        <register>
          <name>RCR</name>
          <addressOffset>0x30</addressOffset>
          <size>0x20</size>
          <fields>
            <field>
              <name>REP</name>
              <bitOffset>0</bitOffset>
              <bitWidth>16</bitWidth>
            </field>
          </fields>
        </register>
        <register>
          <name>CCR1</name>
          <addressOffset>0x34</addressOffset>
          <size>0x20</size>
          <fields>
            <field>
              <name>CCR1</name>
              <bitOffset>0</bitOffset>
              <bitWidth>16</bitWidth>
            </field>
          </fields>
        </register>
        <register>
          <name>CCR2</name>
          <addressOffset>0x38</addressOffset>
          <size>0x20</size>
          <fields>
            <field>
              <name>CCR2</name>
              <bitOffset>0</bitOffset>
              <bitWidth>16</bitWidth>
            </field>
          </fields>
        </register>
        <register>
          <name>CCR3</name>
          <addressOffset>0x3c</addressOffset>
          <size>0x20</size>
          <fields>
            <field>
              <name>CCR3</name>
              <bitOffset>0</bitOffset>
              <bitWidth>16</bitWidth>
            </field>
          </fields>
        </register>
        <register>
          <name>CCR4</name>
          <addressOffset>0x40</addressOffset>
          <size>0x20</size>
          <fields>
            <field>
              <name>CCR4</name>
              <bitOffset>0</bitOffset>
              <bitWidth>16</bitWidth>
            </field>
          </fields>
        </register>
        <register>
          <name>BDTR</name>
          <addressOffset>0x44</addressOffset>
          <size>0x20</size>
          <fields>
            <field>
              <name>DTG</name>
              <bitOffset>0</bitOffset>
              <bitWidth>8</bitWidth>
            </field>
            <field>
              <name>LOCK</name>
              <bitOffset>8</bitOffset>
              <bitWidth>2</bitWidth>
            </field>
            <field>
              <name>OSSI</name>
              <bitOffset>10</bitOffset>
              <bitWidth>1</bitWidth>
            </field>
            <field>
              <name>OSSR</name>
              <bitOffset>11</bitOffset>
              <bitWidth>1</bitWidth>
            </field>
            <field>
              <name>BKE</name>
              <bitOffset>12</bitOffset>
              <bitWidth>1</bitWidth>
            </field>
            <field>
              <name>BKP</name>
              <bitOffset>13</bitOffset>
              <bitWidth>1</bitWidth>
            </field>
            <field>
              <name>AOE</name>
              <bitOffset>14</bitOffset>
              <bitWidth>1</bitWidth>
            </field>
            <field>
              <name>MOE</name>
              <bitOffset>15</bitOffset>
              <bitWidth>1</bitWidth>
            </field>
            <field>
              <name>BKF</name>
              <bitOffset>16</bitOffset>
              <bitWidth>4</bitWidth>
            </field>
            <field>
              <name>BK2F</name>
              <bitOffset>20</bitOffset>
              <bitWidth>4</bitWidth>
            </field>
            <field>
              <name>BK2E</name>
              <bitOffset>24</bitOffset>
              <bitWidth>1</bitWidth>
            </field>
            <field>
              <name>BK2P</name>
              <bitOffset>25</bitOffset>
              <bitWidth>1</bitWidth>
            </field>
            <field>
              <name>BKDSRM</name>
              <bitOffset>26</bitOffset>
              <bitWidth>1</bitWidth>
            </field>
            <field>
              <name>BK2DSRM</name>
              <bitOffset>27</bitOffset>
              <bitWidth>1</bitWidth>
            </field>
            <field>
              <name>BKBID</name>
              <bitOffset>28</bitOffset>
              <bitWidth>1</bitWidth>
            </field>
            <field>
              <name>BK2BID</name>
              <bitOffset>29</bitOffset>
              <bitWidth>1</bitWidth>
            </field>
          </fields>
        </register>
        <register>
          <name>CCR5</name>
          <addressOffset>0x48</addressOffset>
          <size>0x20</size>
          <fields>
            <field>
              <name>CCR5</name>
              <bitOffset>0</bitOffset>
              <bitWidth>32</bitWidth>
            </field>
            <field>
              <name>GC5C1</name>
              <bitOffset>29</bitOffset>
              <bitWidth>1</bitWidth>
            </field>
            <field>
              <name>GC5C2</name>
              <bitOffset>30</bitOffset>
              <bitWidth>1</bitWidth>
            </field>
            <field>
              <name>GC5C3</name>
              <bitOffset>31</bitOffset>
              <bitWidth>1</bitWidth>
            </field>
          </fields>
        </register>
        <register>
          <name>CCR6</name>
          <addressOffset>0x4c</addressOffset>
          <size>0x20</size>
          <fields>
            <field>
              <name>CCR6</name>
              <bitOffset>0</bitOffset>
              <bitWidth>16</bitWidth>
            </field>
          </fields>
        </register>
        <register>
          <name>CCMR3</name>
          <addressOffset>0x50</addressOffset>
          <size>0x20</size>
          <fields>
            <field>
              <name>OC5FE</name>
              <bitOffset>2</bitOffset>
              <bitWidth>1</bitWidth>
            </field>
            <field>
              <name>OC5PE</name>
              <bitOffset>3</bitOffset>
              <bitWidth>1</bitWidth>
            </field>
            <field>
              <name>OC5M</name>
              <bitOffset>4</bitOffset>
              <bitWidth>13</bitWidth>
            </field>
            <field>
              <name>OC5CE</name>
              <bitOffset>7</bitOffset>
              <bitWidth>1</bitWidth>
            </field>
            <field>
              <name>OC6FE</name>
              <bitOffset>10</bitOffset>
              <bitWidth>1</bitWidth>
            </field>
            <field>
              <name>OC6PE</name>
              <bitOffset>11</bitOffset>
              <bitWidth>1</bitWidth>
            </field>
            <field>
              <name>OC6M</name>
              <bitOffset>12</bitOffset>
              <bitWidth>13</bitWidth>
            </field>
            <field>
              <name>OC6CE</name>
              <bitOffset>15</bitOffset>
              <bitWidth>1</bitWidth>
            </field>
          </fields>
        </register>
        <register>
          <name>DTR2</name>
          <addressOffset>0x54</addressOffset>
          <size>0x20</size>
          <fields>
            <field>
              <name>DTGF</name>
              <bitOffset>0</bitOffset>
              <bitWidth>8</bitWidth>
            </field>
            <field>
              <name>DTAE</name>
              <bitOffset>16</bitOffset>
              <bitWidth>1</bitWidth>
            </field>
            <field>
              <name>DTPE</name>
              <bitOffset>17</bitOffset>
              <bitWidth>1</bitWidth>
            </field>
          </fields>
        </register>
        <register>
          <name>ECR</name>
          <addressOffset>0x58</addressOffset>
          <size>0x20</size>
          <fields>
            <field>
              <name>IE</name>
              <bitOffset>0</bitOffset>
              <bitWidth>1</bitWidth>
            </field>
            <field>
              <name>IDIR</name>
              <bitOffset>1</bitOffset>
              <bitWidth>2</bitWidth>
            </field>
            <field>
              <name>FIDX</name>
              <bitOffset>5</bitOffset>
              <bitWidth>1</bitWidth>
            </field>
            <field>
              <name>IPOS</name>
              <bitOffset>6</bitOffset>
              <bitWidth>2</bitWidth>
            </field>
            <field>
              <name>PW</name>
              <bitOffset>16</bitOffset>
              <bitWidth>8</bitWidth>
            </field>
            <field>
              <name>PWPRSC</name>
              <bitOffset>24</bitOffset>
              <bitWidth>3</bitWidth>
            </field>
          </fields>
        </register>
        <register>
          <name>TISEL</name>
          <addressOffset>0x5c</addressOffset>
          <size>0x20</size>
          <fields>
            <field>
              <name>TI1SEL</name>
              <bitOffset>0</bitOffset>
              <bitWidth>4</bitWidth>
            </field>
            <field>
              <name>TI2SEL</name>
              <bitOffset>8</bitOffset>
              <bitWidth>4</bitWidth>
            </field>
            <field>
              <name>TI3SEL</name>
              <bitOffset>16</bitOffset>
              <bitWidth>4</bitWidth>
            </field>
            <field>
              <name>TI4SEL</name>
              <bitOffset>24</bitOffset>
              <bitWidth>4</bitWidth>
            </field>
          </fields>
        </register>
        <register>
          <name>AF1</name>
          <addressOffset>0x60</addressOffset>
          <size>0x20</size>
        </register>
        <register>
          <name>AF2</name>
          <addressOffset>0x64</addressOffset>
          <size>0x20</size>
        </register>
        <register>
          <name>OR</name>
          <addressOffset>0x68</addressOffset>
          <size>0x20</size>
          <fields>
            <field>
              <name>HSE32EN</name>
              <bitOffset>0</bitOffset>
              <bitWidth>1</bitWidth>
            </field>
          </fields>
        </register>
        <register>
          <name>DCR</name>
          <addressOffset>0x3dc</addressOffset>
          <size>0x20</size>
          <fields>
            <field>
              <name>DBA</name>
              <bitOffset>0</bitOffset>
              <bitWidth>5</bitWidth>
            </field>
            <field>
              <name>DBL</name>
              <bitOffset>8</bitOffset>
              <bitWidth>5</bitWidth>
            </field>
          </fields>
        </register>
        <register>
          <name>DMAR</name>
          <addressOffset>0x3e0</addressOffset>
          <size>0x20</size>
          <fields>
            <field>
              <name>DMAB</name>
              <bitOffset>0</bitOffset>
              <bitWidth>32</bitWidth>
            </field>
          </fields>
        </register>
      </registers>
    </peripheral>
    <peripheral>
      <name>SAI1</name>
      <baseAddress>0x40015400</baseAddress>
      <registers>
        <register>
          <name>GCR</name>
          <addressOffset>0x0</addressOffset>
          <size>0x20</size>
          <fields>
            <field>
              <name>SYNCIN</name>
              <bitOffset>0</bitOffset>
              <bitWidth>2</bitWidth>
            </field>
            <field>
              <name>SYNCOUT</name>
              <bitOffset>4</bitOffset>
              <bitWidth>2</bitWidth>
            </field>
          </fields>
        </register>
        <register>
          <name>CR1A</name>
          <addressOffset>0x4</addressOffset>
          <size>0x20</size>
          <fields>
            <field>
              <name>MODE</name>
              <bitOffset>0</bitOffset>
              <bitWidth>2</bitWidth>
            </field>
            <field>
              <name>PRTCFG</name>
              <bitOffset>2</bitOffset>
              <bitWidth>2</bitWidth>
            </field>
            <field>
              <name>DS</name>
              <bitOffset>5</bitOffset>
              <bitWidth>3</bitWidth>
            </field>
            <field>
              <name>LSBFIRST</name>
              <bitOffset>8</bitOffset>
              <bitWidth>1</bitWidth>
            </field>
            <field>
              <name>CKSTR</name>
              <bitOffset>9</bitOffset>
              <bitWidth>1</bitWidth>
            </field>
            <field>
              <name>SYNCEN</name>
              <bitOffset>10</bitOffset>
              <bitWidth>2</bitWidth>
            </field>
            <field>
              <name>MONO</name>
              <bitOffset>12</bitOffset>
              <bitWidth>1</bitWidth>
            </field>
            <field>
              <name>OUTDRIV</name>
              <bitOffset>13</bitOffset>
              <bitWidth>1</bitWidth>
            </field>
            <field>
              <name>SAIEN</name>
              <bitOffset>16</bitOffset>
              <bitWidth>1</bitWidth>
            </field>
            <field>
              <name>DMAEN</name>
              <bitOffset>17</bitOffset>
              <bitWidth>1</bitWidth>
            </field>
            <field>
              <name>NODIV</name>
              <bitOffset>19</bitOffset>
              <bitWidth>1</bitWidth>
            </field>
            <field>
              <name>MCKDIV</name>
              <bitOffset>20</bitOffset>
              <bitWidth>6</bitWidth>
            </field>
            <field>
              <name>OSR</name>
              <bitOffset>26</bitOffset>
              <bitWidth>1</bitWidth>
            </field>
            <field>
              <name>MCKEN</name>
              <bitOffset>27</bitOffset>
              <bitWidth>1</bitWidth>
            </field>
          </fields>
        </register>
        <register>
          <name>CR2A</name>
          <addressOffset>0x8</addressOffset>
          <size>0x20</size>
          <fields>
            <field>
              <name>FTH</name>
              <bitOffset>0</bitOffset>
              <bitWidth>3</bitWidth>
            </field>
            <field>
              <name>FFLUSH</name>
              <bitOffset>3</bitOffset>
              <bitWidth>1</bitWidth>
            </field>
            <field>
              <name>TRIS</name>
              <bitOffset>4</bitOffset>
              <bitWidth>1</bitWidth>
            </field>
            <field>
              <name>MUTE</name>
              <bitOffset>5</bitOffset>
              <bitWidth>1</bitWidth>
            </field>
            <field>
              <name>MUTEVAL</name>
              <bitOffset>6</bitOffset>
              <bitWidth>1</bitWidth>
            </field>
            <field>
              <name>MUTECNT</name>
              <bitOffset>7</bitOffset>
              <bitWidth>6</bitWidth>
            </field>
            <field>
              <name>CPL</name>
              <bitOffset>13</bitOffset>
              <bitWidth>1</bitWidth>
            </field>
            <field>
              <name>COMP</name>
              <bitOffset>14</bitOffset>
              <bitWidth>2</bitWidth>
            </field>
          </fields>
        </register>
        <register>
          <name>FRCRA</name>
          <addressOffset>0xc</addressOffset>
          <size>0x20</size>
          <fields>
            <field>
              <name>FRL</name>
              <bitOffset>0</bitOffset>
              <bitWidth>8</bitWidth>
            </field>
            <field>
              <name>FSALL</name>
              <bitOffset>8</bitOffset>
              <bitWidth>7</bitWidth>
            </field>
            <field>
              <name>FSDEF</name>
              <bitOffset>16</bitOffset>
              <bitWidth>1</bitWidth>
            </field>
            <field>
              <name>FSPOL</name>
              <bitOffset>17</bitOffset>
              <bitWidth>1</bitWidth>
            </field>
            <field>
              <name>FSOFF</name>
              <bitOffset>18</bitOffset>
              <bitWidth>1</bitWidth>
            </field>
          </fields>
        </register>
        <register>
          <name>SLOTRA</name>
          <addressOffset>0x10</addressOffset>
          <size>0x20</size>
          <fields>
            <field>
              <name>FBOFF</name>
              <bitOffset>0</bitOffset>
              <bitWidth>5</bitWidth>
            </field>
            <field>
              <name>SLOTSZ</name>
              <bitOffset>6</bitOffset>
              <bitWidth>2</bitWidth>
            </field>
            <field>
              <name>NBSLOT</name>
              <bitOffset>8</bitOffset>
              <bitWidth>4</bitWidth>
            </field>
            <field>
              <name>SLOTEN</name>
              <bitOffset>16</bitOffset>
              <bitWidth>16</bitWidth>
            </field>
          </fields>
        </register>
        <register>
          <name>IMRA</name>
          <addressOffset>0x14</addressOffset>
          <size>0x20</size>
          <fields>
            <field>
              <name>OVRUDRIE</name>
              <bitOffset>0</bitOffset>
              <bitWidth>1</bitWidth>
            </field>
            <field>
              <name>MUTEDETIE</name>
              <bitOffset>1</bitOffset>
              <bitWidth>1</bitWidth>
            </field>
            <field>
              <name>WCKCFGIE</name>
              <bitOffset>2</bitOffset>
              <bitWidth>1</bitWidth>
            </field>
            <field>
              <name>FREQIE</name>
              <bitOffset>3</bitOffset>
              <bitWidth>1</bitWidth>
            </field>
            <field>
              <name>CNRDYIE</name>
              <bitOffset>4</bitOffset>
              <bitWidth>1</bitWidth>
            </field>
            <field>
              <name>AFSDETIE</name>
              <bitOffset>5</bitOffset>
              <bitWidth>1</bitWidth>
            </field>
            <field>
              <name>LFSDETIE</name>
              <bitOffset>6</bitOffset>
              <bitWidth>1</bitWidth>
            </field>
          </fields>
        </register>
        <register>
          <name>SRA</name>
          <addressOffset>0x18</addressOffset>
          <size>0x20</size>
          <fields>
            <field>
              <name>OVRUDR</name>
              <bitOffset>0</bitOffset>
              <bitWidth>1</bitWidth>
            </field>
            <field>
              <name>MUTEDET</name>
              <bitOffset>1</bitOffset>
              <bitWidth>1</bitWidth>
            </field>
            <field>
              <name>WCKCFG</name>
              <bitOffset>2</bitOffset>
              <bitWidth>1</bitWidth>
            </field>
            <field>
              <name>FREQ</name>
              <bitOffset>3</bitOffset>
              <bitWidth>1</bitWidth>
            </field>
            <field>
              <name>CNRDY</name>
              <bitOffset>4</bitOffset>
              <bitWidth>1</bitWidth>
            </field>
            <field>
              <name>AFSDET</name>
              <bitOffset>5</bitOffset>
              <bitWidth>1</bitWidth>
            </field>
            <field>
              <name>LFSDET</name>
              <bitOffset>6</bitOffset>
              <bitWidth>1</bitWidth>
            </field>
            <field>
              <name>FLVL</name>
              <bitOffset>16</bitOffset>
              <bitWidth>3</bitWidth>
            </field>
          </fields>
        </register>
        <register>
          <name>CLRFRA</name>
          <addressOffset>0x1c</addressOffset>
          <size>0x20</size>
          <fields>
            <field>
              <name>COVRUDR</name>
              <bitOffset>0</bitOffset>
              <bitWidth>1</bitWidth>
            </field>
            <field>
              <name>CMUTEDET</name>
              <bitOffset>1</bitOffset>
              <bitWidth>1</bitWidth>
            </field>
            <field>
              <name>CWCKCFG</name>
              <bitOffset>2</bitOffset>
              <bitWidth>1</bitWidth>
            </field>
            <field>
              <name>CFREQ</name>
              <bitOffset>3</bitOffset>
              <bitWidth>1</bitWidth>
            </field>
            <field>
              <name>CCNRDY</name>
              <bitOffset>4</bitOffset>
              <bitWidth>1</bitWidth>
            </field>
            <field>
              <name>CAFSDET</name>
              <bitOffset>5</bitOffset>
              <bitWidth>1</bitWidth>
            </field>
            <field>
              <name>CLFSDET</name>
              <bitOffset>6</bitOffset>
              <bitWidth>1</bitWidth>
            </field>
          </fields>
        </register>
        <register>
          <name>DRA</name>
          <addressOffset>0x20</addressOffset>
          <size>0x20</size>
          <fields>
            <field>
              <name>DATA</name>
              <bitOffset>0</bitOffset>
              <bitWidth>32</bitWidth>
            </field>
          </fields>
        </register>
        <register>
          <name>CR1B</name>
          <addressOffset>0x24</addressOffset>
          <size>0x20</size>
          <fields>
            <field>
              <name>MODE</name>
              <bitOffset>0</bitOffset>
              <bitWidth>2</bitWidth>
            </field>
            <field>
              <name>PRTCFG</name>
              <bitOffset>2</bitOffset>
              <bitWidth>2</bitWidth>
            </field>
            <field>
              <name>DS</name>
              <bitOffset>5</bitOffset>
              <bitWidth>3</bitWidth>
            </field>
            <field>
              <name>LSBFIRST</name>
              <bitOffset>8</bitOffset>
              <bitWidth>1</bitWidth>
            </field>
            <field>
              <name>CKSTR</name>
              <bitOffset>9</bitOffset>
              <bitWidth>1</bitWidth>
            </field>
            <field>
              <name>SYNCEN</name>
              <bitOffset>10</bitOffset>
              <bitWidth>2</bitWidth>
            </field>
            <field>
              <name>MONO</name>
              <bitOffset>12</bitOffset>
              <bitWidth>1</bitWidth>
            </field>
            <field>
              <name>OUTDRIV</name>
              <bitOffset>13</bitOffset>
              <bitWidth>1</bitWidth>
            </field>
            <field>
              <name>SAIEN</name>
              <bitOffset>16</bitOffset>
              <bitWidth>1</bitWidth>
            </field>
            <field>
              <name>DMAEN</name>
              <bitOffset>17</bitOffset>
              <bitWidth>1</bitWidth>
            </field>
            <field>
              <name>NODIV</name>
              <bitOffset>19</bitOffset>
              <bitWidth>1</bitWidth>
            </field>
            <field>
              <name>MCKDIV</name>
              <bitOffset>20</bitOffset>
              <bitWidth>6</bitWidth>
            </field>
            <field>
              <name>OSR</name>
              <bitOffset>26</bitOffset>
              <bitWidth>1</bitWidth>
            </field>
            <field>
              <name>MCKEN</name>
              <bitOffset>27</bitOffset>
              <bitWidth>1</bitWidth>
            </field>
          </fields>
        </register>
        <register>
          <name>CR2B</name>
          <addressOffset>0x28</addressOffset>
          <size>0x20</size>
          <fields>
            <field>
              <name>FTH</name>
              <bitOffset>0</bitOffset>
              <bitWidth>3</bitWidth>
            </field>
            <field>
              <name>FFLUSH</name>
              <bitOffset>3</bitOffset>
              <bitWidth>1</bitWidth>
            </field>
            <field>
              <name>TRIS</name>
              <bitOffset>4</bitOffset>
              <bitWidth>1</bitWidth>
            </field>
            <field>
              <name>MUTE</name>
              <bitOffset>5</bitOffset>
              <bitWidth>1</bitWidth>
            </field>
            <field>
              <name>MUTEVAL</name>
              <bitOffset>6</bitOffset>
              <bitWidth>1</bitWidth>
            </field>
            <field>
              <name>MUTECNT</name>
              <bitOffset>7</bitOffset>
              <bitWidth>6</bitWidth>
            </field>
            <field>
              <name>CPL</name>
              <bitOffset>13</bitOffset>
              <bitWidth>1</bitWidth>
            </field>
            <field>
              <name>COMP</name>
              <bitOffset>14</bitOffset>
              <bitWidth>2</bitWidth>
            </field>
          </fields>
        </register>
        <register>
          <name>FRCRB</name>
          <addressOffset>0x2c</addressOffset>
          <size>0x20</size>
          <fields>
            <field>
              <name>FRL</name>
              <bitOffset>0</bitOffset>
              <bitWidth>8</bitWidth>
            </field>
            <field>
              <name>FSALL</name>
              <bitOffset>8</bitOffset>
              <bitWidth>7</bitWidth>
            </field>
            <field>
              <name>FSDEF</name>
              <bitOffset>16</bitOffset>
              <bitWidth>1</bitWidth>
            </field>
            <field>
              <name>FSPOL</name>
              <bitOffset>17</bitOffset>
              <bitWidth>1</bitWidth>
            </field>
            <field>
              <name>FSOFF</name>
              <bitOffset>18</bitOffset>
              <bitWidth>1</bitWidth>
            </field>
          </fields>
        </register>
        <register>
          <name>SLOTRB</name>
          <addressOffset>0x30</addressOffset>
          <size>0x20</size>
          <fields>
            <field>
              <name>FBOFF</name>
              <bitOffset>0</bitOffset>
              <bitWidth>5</bitWidth>
            </field>
            <field>
              <name>SLOTSZ</name>
              <bitOffset>6</bitOffset>
              <bitWidth>2</bitWidth>
            </field>
            <field>
              <name>NBSLOT</name>
              <bitOffset>8</bitOffset>
              <bitWidth>4</bitWidth>
            </field>
            <field>
              <name>SLOTEN</name>
              <bitOffset>16</bitOffset>
              <bitWidth>16</bitWidth>
            </field>
          </fields>
        </register>
        <register>
          <name>IMRB</name>
          <addressOffset>0x34</addressOffset>
          <size>0x20</size>
          <fields>
            <field>
              <name>OVRUDRIE</name>
              <bitOffset>0</bitOffset>
              <bitWidth>1</bitWidth>
            </field>
            <field>
              <name>MUTEDETIE</name>
              <bitOffset>1</bitOffset>
              <bitWidth>1</bitWidth>
            </field>
            <field>
              <name>WCKCFGIE</name>
              <bitOffset>2</bitOffset>
              <bitWidth>1</bitWidth>
            </field>
            <field>
              <name>FREQIE</name>
              <bitOffset>3</bitOffset>
              <bitWidth>1</bitWidth>
            </field>
            <field>
              <name>CNRDYIE</name>
              <bitOffset>4</bitOffset>
              <bitWidth>1</bitWidth>
            </field>
            <field>
              <name>AFSDETIE</name>
              <bitOffset>5</bitOffset>
              <bitWidth>1</bitWidth>
            </field>
            <field>
              <name>LFSDETIE</name>
              <bitOffset>6</bitOffset>
              <bitWidth>1</bitWidth>
            </field>
          </fields>
        </register>
        <register>
          <name>SRB</name>
          <addressOffset>0x38</addressOffset>
          <size>0x20</size>
          <fields>
            <field>
              <name>OVRUDR</name>
              <bitOffset>0</bitOffset>
              <bitWidth>1</bitWidth>
            </field>
            <field>
              <name>MUTEDET</name>
              <bitOffset>1</bitOffset>
              <bitWidth>1</bitWidth>
            </field>
            <field>
              <name>WCKCFG</name>
              <bitOffset>2</bitOffset>
              <bitWidth>1</bitWidth>
            </field>
            <field>
              <name>FREQ</name>
              <bitOffset>3</bitOffset>
              <bitWidth>1</bitWidth>
            </field>
            <field>
              <name>CNRDY</name>
              <bitOffset>4</bitOffset>
              <bitWidth>1</bitWidth>
            </field>
            <field>
              <name>AFSDET</name>
              <bitOffset>5</bitOffset>
              <bitWidth>1</bitWidth>
            </field>
            <field>
              <name>LFSDET</name>
              <bitOffset>6</bitOffset>
              <bitWidth>1</bitWidth>
            </field>
            <field>
              <name>FLVL</name>
              <bitOffset>16</bitOffset>
              <bitWidth>3</bitWidth>
            </field>
          </fields>
        </register>
        <register>
          <name>CLRFRB</name>
          <addressOffset>0x3c</addressOffset>
          <size>0x20</size>
          <fields>
            <field>
              <name>COVRUDR</name>
              <bitOffset>0</bitOffset>
              <bitWidth>1</bitWidth>
            </field>
            <field>
              <name>CMUTEDET</name>
              <bitOffset>1</bitOffset>
              <bitWidth>1</bitWidth>
            </field>
            <field>
              <name>CWCKCFG</name>
              <bitOffset>2</bitOffset>
              <bitWidth>1</bitWidth>
            </field>
            <field>
              <name>CFREQ</name>
              <bitOffset>3</bitOffset>
              <bitWidth>1</bitWidth>
            </field>
            <field>
              <name>CCNRDY</name>
              <bitOffset>4</bitOffset>
              <bitWidth>1</bitWidth>
            </field>
            <field>
              <name>CAFSDET</name>
              <bitOffset>5</bitOffset>
              <bitWidth>1</bitWidth>
            </field>
            <field>
              <name>CLFSDET</name>
              <bitOffset>6</bitOffset>
              <bitWidth>1</bitWidth>
            </field>
          </fields>
        </register>
        <register>
          <name>DRB</name>
          <addressOffset>0x40</addressOffset>
          <size>0x20</size>
          <fields>
            <field>
              <name>DATA</name>
              <bitOffset>0</bitOffset>
              <bitWidth>32</bitWidth>
            </field>
          </fields>
        </register>
        <register>
          <name>PDMCR</name>
          <addressOffset>0x44</addressOffset>
          <size>0x20</size>
          <fields>
            <field>
              <name>PDMEN</name>
              <bitOffset>0</bitOffset>
              <bitWidth>1</bitWidth>
            </field>
            <field>
              <name>MICNBR</name>
              <bitOffset>4</bitOffset>
              <bitWidth>2</bitWidth>
            </field>
            <field>
              <name>CKEN1</name>
              <bitOffset>8</bitOffset>
              <bitWidth>1</bitWidth>
            </field>
            <field>
              <name>CKEN2</name>
              <bitOffset>9</bitOffset>
              <bitWidth>1</bitWidth>
            </field>
            <field>
              <name>CKEN3</name>
              <bitOffset>10</bitOffset>
              <bitWidth>1</bitWidth>
            </field>
            <field>
              <name>CKEN4</name>
              <bitOffset>11</bitOffset>
              <bitWidth>1</bitWidth>
            </field>
          </fields>
        </register>
        <register>
          <name>PDMDLY</name>
          <addressOffset>0x48</addressOffset>
          <size>0x20</size>
          <fields>
            <field>
              <name>DLYM1L</name>
              <bitOffset>0</bitOffset>
              <bitWidth>3</bitWidth>
            </field>
            <field>
              <name>DLYM1R</name>
              <bitOffset>4</bitOffset>
              <bitWidth>3</bitWidth>
            </field>
            <field>
              <name>DLYM2L</name>
              <bitOffset>8</bitOffset>
              <bitWidth>3</bitWidth>
            </field>
            <field>
              <name>DLYM2R</name>
              <bitOffset>12</bitOffset>
              <bitWidth>3</bitWidth>
            </field>
            <field>
              <name>DLYM3L</name>
              <bitOffset>16</bitOffset>
              <bitWidth>3</bitWidth>
            </field>
            <field>
              <name>DLYM3R</name>
              <bitOffset>20</bitOffset>
              <bitWidth>3</bitWidth>
            </field>
            <field>
              <name>DLYM4L</name>
              <bitOffset>24</bitOffset>
              <bitWidth>3</bitWidth>
            </field>
            <field>
              <name>DLYM4R</name>
              <bitOffset>28</bitOffset>
              <bitWidth>3</bitWidth>
            </field>
          </fields>
        </register>
      </registers>
    </peripheral>
    <peripheral>
      <name>DMA1</name>
      <baseAddress>0x40020000</baseAddress>
      <registers>
        <register>
          <name>ISR</name>
          <addressOffset>0x0</addressOffset>
          <size>0x20</size>
          <fields>
            <field>
              <name>GIF1</name>
              <bitOffset>0</bitOffset>
              <bitWidth>1</bitWidth>
            </field>
            <field>
              <name>TCIF1</name>
              <bitOffset>1</bitOffset>
              <bitWidth>1</bitWidth>
            </field>
            <field>
              <name>HTIF1</name>
              <bitOffset>2</bitOffset>
              <bitWidth>1</bitWidth>
            </field>
            <field>
              <name>TEIF1</name>
              <bitOffset>3</bitOffset>
              <bitWidth>1</bitWidth>
            </field>
            <field>
              <name>GIF2</name>
              <bitOffset>4</bitOffset>
              <bitWidth>1</bitWidth>
            </field>
            <field>
              <name>TCIF2</name>
              <bitOffset>5</bitOffset>
              <bitWidth>1</bitWidth>
            </field>
            <field>
              <name>HTIF2</name>
              <bitOffset>6</bitOffset>
              <bitWidth>1</bitWidth>
            </field>
            <field>
              <name>TEIF2</name>
              <bitOffset>7</bitOffset>
              <bitWidth>1</bitWidth>
            </field>
            <field>
              <name>GIF3</name>
              <bitOffset>8</bitOffset>
              <bitWidth>1</bitWidth>
            </field>
            <field>
              <name>TCIF3</name>
              <bitOffset>9</bitOffset>
              <bitWidth>1</bitWidth>
            </field>
            <field>
              <name>HTIF3</name>
              <bitOffset>10</bitOffset>
              <bitWidth>1</bitWidth>
            </field>
            <field>
              <name>TEIF3</name>
              <bitOffset>11</bitOffset>
              <bitWidth>1</bitWidth>
            </field>
            <field>
              <name>GIF4</name>
              <bitOffset>12</bitOffset>
              <bitWidth>1</bitWidth>
            </field>
            <field>
              <name>TCIF4</name>
              <bitOffset>13</bitOffset>
              <bitWidth>1</bitWidth>
            </field>
            <field>
              <name>HTIF4</name>
              <bitOffset>14</bitOffset>
              <bitWidth>1</bitWidth>
            </field>
            <field>
              <name>TEIF4</name>
              <bitOffset>15</bitOffset>
              <bitWidth>1</bitWidth>
            </field>
            <field>
              <name>GIF5</name>
              <bitOffset>16</bitOffset>
              <bitWidth>1</bitWidth>
            </field>
            <field>
              <name>TCIF5</name>
              <bitOffset>17</bitOffset>
              <bitWidth>1</bitWidth>
            </field>
            <field>
              <name>HTIF5</name>
              <bitOffset>18</bitOffset>
              <bitWidth>1</bitWidth>
            </field>
            <field>
              <name>TEIF5</name>
              <bitOffset>19</bitOffset>
              <bitWidth>1</bitWidth>
            </field>
            <field>
              <name>GIF6</name>
              <bitOffset>20</bitOffset>
              <bitWidth>1</bitWidth>
            </field>
            <field>
              <name>TCIF6</name>
              <bitOffset>21</bitOffset>
              <bitWidth>1</bitWidth>
            </field>
            <field>
              <name>HTIF6</name>
              <bitOffset>22</bitOffset>
              <bitWidth>1</bitWidth>
            </field>
            <field>
              <name>TEIF6</name>
              <bitOffset>23</bitOffset>
              <bitWidth>1</bitWidth>
            </field>
            <field>
              <name>GIF7</name>
              <bitOffset>24</bitOffset>
              <bitWidth>1</bitWidth>
            </field>
            <field>
              <name>TCIF7</name>
              <bitOffset>25</bitOffset>
              <bitWidth>1</bitWidth>
            </field>
            <field>
              <name>HTIF7</name>
              <bitOffset>26</bitOffset>
              <bitWidth>1</bitWidth>
            </field>
            <field>
              <name>TEIF7</name>
              <bitOffset>27</bitOffset>
              <bitWidth>1</bitWidth>
            </field>
            <field>
              <name>GIF8</name>
              <bitOffset>28</bitOffset>
              <bitWidth>1</bitWidth>
            </field>
            <field>
              <name>TCIF8</name>
              <bitOffset>29</bitOffset>
              <bitWidth>1</bitWidth>
            </field>
            <field>
              <name>HTIF8</name>
              <bitOffset>30</bitOffset>
              <bitWidth>1</bitWidth>
            </field>
            <field>
              <name>TEIF8</name>
              <bitOffset>31</bitOffset>
              <bitWidth>1</bitWidth>
            </field>
          </fields>
        </register>
        <register>
          <name>IFCR</name>
          <addressOffset>0x4</addressOffset>
          <size>0x20</size>
          <fields>
            <field>
              <name>CGIF1</name>
              <bitOffset>0</bitOffset>
              <bitWidth>1</bitWidth>
            </field>
            <field>
              <name>CTCIF1</name>
              <bitOffset>1</bitOffset>
              <bitWidth>1</bitWidth>
            </field>
            <field>
              <name>CHTIF1</name>
              <bitOffset>2</bitOffset>
              <bitWidth>1</bitWidth>
            </field>
            <field>
              <name>CTEIF1</name>
              <bitOffset>3</bitOffset>
              <bitWidth>1</bitWidth>
            </field>
            <field>
              <name>CGIF2</name>
              <bitOffset>4</bitOffset>
              <bitWidth>1</bitWidth>
            </field>
            <field>
              <name>CTCIF2</name>
              <bitOffset>5</bitOffset>
              <bitWidth>1</bitWidth>
            </field>
            <field>
              <name>CHTIF2</name>
              <bitOffset>6</bitOffset>
              <bitWidth>1</bitWidth>
            </field>
            <field>
              <name>CTEIF2</name>
              <bitOffset>7</bitOffset>
              <bitWidth>1</bitWidth>
            </field>
            <field>
              <name>CGIF3</name>
              <bitOffset>8</bitOffset>
              <bitWidth>1</bitWidth>
            </field>
            <field>
              <name>CTCIF3</name>
              <bitOffset>9</bitOffset>
              <bitWidth>1</bitWidth>
            </field>
            <field>
              <name>CHTIF3</name>
              <bitOffset>10</bitOffset>
              <bitWidth>1</bitWidth>
            </field>
            <field>
              <name>CTEIF3</name>
              <bitOffset>11</bitOffset>
              <bitWidth>1</bitWidth>
            </field>
            <field>
              <name>CGIF4</name>
              <bitOffset>12</bitOffset>
              <bitWidth>1</bitWidth>
            </field>
            <field>
              <name>CTCIF4</name>
              <bitOffset>13</bitOffset>
              <bitWidth>1</bitWidth>
            </field>
            <field>
              <name>CHTIF4</name>
              <bitOffset>14</bitOffset>
              <bitWidth>1</bitWidth>
            </field>
            <field>
              <name>CTEIF4</name>
              <bitOffset>15</bitOffset>
              <bitWidth>1</bitWidth>
            </field>
            <field>
              <name>CGIF5</name>
              <bitOffset>16</bitOffset>
              <bitWidth>1</bitWidth>
            </field>
            <field>
              <name>CTCIF5</name>
              <bitOffset>17</bitOffset>
              <bitWidth>1</bitWidth>
            </field>
            <field>
              <name>CHTIF5</name>
              <bitOffset>18</bitOffset>
              <bitWidth>1</bitWidth>
            </field>
            <field>
              <name>CTEIF5</name>
              <bitOffset>19</bitOffset>
              <bitWidth>1</bitWidth>
            </field>
            <field>
              <name>CGIF6</name>
              <bitOffset>20</bitOffset>
              <bitWidth>1</bitWidth>
            </field>
            <field>
              <name>CTCIF6</name>
              <bitOffset>21</bitOffset>
              <bitWidth>1</bitWidth>
            </field>
            <field>
              <name>CHTIF6</name>
              <bitOffset>22</bitOffset>
              <bitWidth>1</bitWidth>
            </field>
            <field>
              <name>CTEIF6</name>
              <bitOffset>23</bitOffset>
              <bitWidth>1</bitWidth>
            </field>
            <field>
              <name>CGIF7</name>
              <bitOffset>24</bitOffset>
              <bitWidth>1</bitWidth>
            </field>
            <field>
              <name>CTCIF7</name>
              <bitOffset>25</bitOffset>
              <bitWidth>1</bitWidth>
            </field>
            <field>
              <name>CHTIF7</name>
              <bitOffset>26</bitOffset>
              <bitWidth>1</bitWidth>
            </field>
            <field>
              <name>CTEIF7</name>
              <bitOffset>27</bitOffset>
              <bitWidth>1</bitWidth>
            </field>
            <field>
              <name>CGIF8</name>
              <bitOffset>28</bitOffset>
              <bitWidth>1</bitWidth>
            </field>
            <field>
              <name>CTCIF8</name>
              <bitOffset>29</bitOffset>
              <bitWidth>1</bitWidth>
            </field>
            <field>
              <name>CHTIF8</name>
              <bitOffset>30</bitOffset>
              <bitWidth>1</bitWidth>
            </field>
            <field>
              <name>CTEIF8</name>
              <bitOffset>31</bitOffset>
              <bitWidth>1</bitWidth>
            </field>
          </fields>
        </register>
        <register>
          <name>CCR1</name>
          <addressOffset>0x8</addressOffset>
          <size>0x20</size>
          <fields>
            <field>
              <name>EN</name>
              <bitOffset>0</bitOffset>
              <bitWidth>1</bitWidth>
            </field>
            <field>
              <name>TCIE</name>
              <bitOffset>1</bitOffset>
              <bitWidth>1</bitWidth>
            </field>
            <field>
              <name>HTIE</name>
              <bitOffset>2</bitOffset>
              <bitWidth>1</bitWidth>
            </field>
            <field>
              <name>TEIE</name>
              <bitOffset>3</bitOffset>
              <bitWidth>1</bitWidth>
            </field>
            <field>
              <name>DIR</name>
              <bitOffset>4</bitOffset>
              <bitWidth>1</bitWidth>
            </field>
            <field>
              <name>CIRC</name>
              <bitOffset>5</bitOffset>
              <bitWidth>1</bitWidth>
            </field>
            <field>
              <name>PINC</name>
              <bitOffset>6</bitOffset>
              <bitWidth>1</bitWidth>
            </field>
            <field>
              <name>MINC</name>
              <bitOffset>7</bitOffset>
              <bitWidth>1</bitWidth>
            </field>
            <field>
              <name>PSIZE</name>
              <bitOffset>8</bitOffset>
              <bitWidth>2</bitWidth>
            </field>
            <field>
              <name>MSIZE</name>
              <bitOffset>10</bitOffset>
              <bitWidth>2</bitWidth>
            </field>
            <field>
              <name>PL</name>
              <bitOffset>12</bitOffset>
              <bitWidth>2</bitWidth>
            </field>
            <field>
              <name>MEM2MEM</name>
              <bitOffset>14</bitOffset>
              <bitWidth>1</bitWidth>
            </field>
          </fields>
        </register>
        <register>
          <name>CCR1</name>
          <addressOffset>0x8</addressOffset>
          <size>0x20</size>
          <fields>
            <field>
              <name>EN</name>
              <bitOffset>0</bitOffset>
              <bitWidth>1</bitWidth>
            </field>
            <field>
              <name>TCIE</name>
              <bitOffset>1</bitOffset>
              <bitWidth>1</bitWidth>
            </field>
            <field>
              <name>HTIE</name>
              <bitOffset>2</bitOffset>
              <bitWidth>1</bitWidth>
            </field>
            <field>
              <name>TEIE</name>
              <bitOffset>3</bitOffset>
              <bitWidth>1</bitWidth>
            </field>
            <field>
              <name>DIR</name>
              <bitOffset>4</bitOffset>
              <bitWidth>1</bitWidth>
            </field>
            <field>
              <name>CIRC</name>
              <bitOffset>5</bitOffset>
              <bitWidth>1</bitWidth>
            </field>
            <field>
              <name>PINC</name>
              <bitOffset>6</bitOffset>
              <bitWidth>1</bitWidth>
            </field>
            <field>
              <name>MINC</name>
              <bitOffset>7</bitOffset>
              <bitWidth>1</bitWidth>
            </field>
            <field>
              <name>PSIZE</name>
              <bitOffset>8</bitOffset>
              <bitWidth>2</bitWidth>
            </field>
            <field>
              <name>MSIZE</name>
              <bitOffset>10</bitOffset>
              <bitWidth>2</bitWidth>
            </field>
            <field>
              <name>PL</name>
              <bitOffset>12</bitOffset>
              <bitWidth>2</bitWidth>
            </field>
            <field>
              <name>MEM2MEM</name>
              <bitOffset>14</bitOffset>
              <bitWidth>1</bitWidth>
            </field>
          </fields>
        </register>
        <register>
          <name>CNDTR1</name>
          <addressOffset>0xc</addressOffset>
          <size>0x20</size>
          <fields>
            <field>
              <name>NDT</name>
              <bitOffset>0</bitOffset>
              <bitWidth>16</bitWidth>
            </field>
          </fields>
        </register>
        <register>
          <name>CNDTR1</name>
          <addressOffset>0xc</addressOffset>
          <size>0x20</size>
          <fields>
            <field>
              <name>NDT</name>
              <bitOffset>0</bitOffset>
              <bitWidth>16</bitWidth>
            </field>
          </fields>
        </register>
        <register>
          <name>CPAR1</name>
          <addressOffset>0x10</addressOffset>
          <size>0x20</size>
          <fields>
            <field>
              <name>PA</name>
              <bitOffset>0</bitOffset>
              <bitWidth>32</bitWidth>
            </field>
          </fields>
        </register>
        <register>
          <name>CPAR1</name>
          <addressOffset>0x10</addressOffset>
          <size>0x20</size>
          <fields>
            <field>
              <name>PA</name>
              <bitOffset>0</bitOffset>
              <bitWidth>32</bitWidth>
            </field>
          </fields>
        </register>
        <register>
          <name>CMAR1</name>
          <addressOffset>0x14</addressOffset>
          <size>0x20</size>
          <fields>
            <field>
              <name>MA</name>
              <bitOffset>0</bitOffset>
              <bitWidth>32</bitWidth>
            </field>
          </fields>
        </register>
        <register>
          <name>CMAR1</name>
          <addressOffset>0x14</addressOffset>
          <size>0x20</size>
          <fields>
            <field>
              <name>MA</name>
              <bitOffset>0</bitOffset>
              <bitWidth>32</bitWidth>
            </field>
          </fields>
        </register>
        <register>
          <name>CCR2</name>
          <addressOffset>0x1c</addressOffset>
          <size>0x20</size>
          <fields>
            <field>
              <name>EN</name>
              <bitOffset>0</bitOffset>
              <bitWidth>1</bitWidth>
            </field>
            <field>
              <name>TCIE</name>
              <bitOffset>1</bitOffset>
              <bitWidth>1</bitWidth>
            </field>
            <field>
              <name>HTIE</name>
              <bitOffset>2</bitOffset>
              <bitWidth>1</bitWidth>
            </field>
            <field>
              <name>TEIE</name>
              <bitOffset>3</bitOffset>
              <bitWidth>1</bitWidth>
            </field>
            <field>
              <name>DIR</name>
              <bitOffset>4</bitOffset>
              <bitWidth>1</bitWidth>
            </field>
            <field>
              <name>CIRC</name>
              <bitOffset>5</bitOffset>
              <bitWidth>1</bitWidth>
            </field>
            <field>
              <name>PINC</name>
              <bitOffset>6</bitOffset>
              <bitWidth>1</bitWidth>
            </field>
            <field>
              <name>MINC</name>
              <bitOffset>7</bitOffset>
              <bitWidth>1</bitWidth>
            </field>
            <field>
              <name>PSIZE</name>
              <bitOffset>8</bitOffset>
              <bitWidth>2</bitWidth>
            </field>
            <field>
              <name>MSIZE</name>
              <bitOffset>10</bitOffset>
              <bitWidth>2</bitWidth>
            </field>
            <field>
              <name>PL</name>
              <bitOffset>12</bitOffset>
              <bitWidth>2</bitWidth>
            </field>
            <field>
              <name>MEM2MEM</name>
              <bitOffset>14</bitOffset>
              <bitWidth>1</bitWidth>
            </field>
          </fields>
        </register>
        <register>
          <name>CCR2</name>
          <addressOffset>0x1c</addressOffset>
          <size>0x20</size>
          <fields>
            <field>
              <name>EN</name>
              <bitOffset>0</bitOffset>
              <bitWidth>1</bitWidth>
            </field>
            <field>
              <name>TCIE</name>
              <bitOffset>1</bitOffset>
              <bitWidth>1</bitWidth>
            </field>
            <field>
              <name>HTIE</name>
              <bitOffset>2</bitOffset>
              <bitWidth>1</bitWidth>
            </field>
            <field>
              <name>TEIE</name>
              <bitOffset>3</bitOffset>
              <bitWidth>1</bitWidth>
            </field>
            <field>
              <name>DIR</name>
              <bitOffset>4</bitOffset>
              <bitWidth>1</bitWidth>
            </field>
            <field>
              <name>CIRC</name>
              <bitOffset>5</bitOffset>
              <bitWidth>1</bitWidth>
            </field>
            <field>
              <name>PINC</name>
              <bitOffset>6</bitOffset>
              <bitWidth>1</bitWidth>
            </field>
            <field>
              <name>MINC</name>
              <bitOffset>7</bitOffset>
              <bitWidth>1</bitWidth>
            </field>
            <field>
              <name>PSIZE</name>
              <bitOffset>8</bitOffset>
              <bitWidth>2</bitWidth>
            </field>
            <field>
              <name>MSIZE</name>
              <bitOffset>10</bitOffset>
              <bitWidth>2</bitWidth>
            </field>
            <field>
              <name>PL</name>
              <bitOffset>12</bitOffset>
              <bitWidth>2</bitWidth>
            </field>
            <field>
              <name>MEM2MEM</name>
              <bitOffset>14</bitOffset>
              <bitWidth>1</bitWidth>
            </field>
          </fields>
        </register>
        <register>
          <name>CNDTR2</name>
          <addressOffset>0x20</addressOffset>
          <size>0x20</size>
          <fields>
            <field>
              <name>NDT</name>
              <bitOffset>0</bitOffset>
              <bitWidth>16</bitWidth>
            </field>
          </fields>
        </register>
        <register>
          <name>CNDTR2</name>
          <addressOffset>0x20</addressOffset>
          <size>0x20</size>
          <fields>
            <field>
              <name>NDT</name>
              <bitOffset>0</bitOffset>
              <bitWidth>16</bitWidth>
            </field>
          </fields>
        </register>
        <register>
          <name>CPAR2</name>
          <addressOffset>0x24</addressOffset>
          <size>0x20</size>
          <fields>
            <field>
              <name>PA</name>
              <bitOffset>0</bitOffset>
              <bitWidth>32</bitWidth>
            </field>
          </fields>
        </register>
        <register>
          <name>CPAR2</name>
          <addressOffset>0x24</addressOffset>
          <size>0x20</size>
          <fields>
            <field>
              <name>PA</name>
              <bitOffset>0</bitOffset>
              <bitWidth>32</bitWidth>
            </field>
          </fields>
        </register>
        <register>
          <name>CMAR2</name>
          <addressOffset>0x28</addressOffset>
          <size>0x20</size>
          <fields>
            <field>
              <name>MA</name>
              <bitOffset>0</bitOffset>
              <bitWidth>32</bitWidth>
            </field>
          </fields>
        </register>
        <register>
          <name>CMAR2</name>
          <addressOffset>0x28</addressOffset>
          <size>0x20</size>
          <fields>
            <field>
              <name>MA</name>
              <bitOffset>0</bitOffset>
              <bitWidth>32</bitWidth>
            </field>
          </fields>
        </register>
        <register>
          <name>CCR3</name>
          <addressOffset>0x30</addressOffset>
          <size>0x20</size>
          <fields>
            <field>
              <name>EN</name>
              <bitOffset>0</bitOffset>
              <bitWidth>1</bitWidth>
            </field>
            <field>
              <name>TCIE</name>
              <bitOffset>1</bitOffset>
              <bitWidth>1</bitWidth>
            </field>
            <field>
              <name>HTIE</name>
              <bitOffset>2</bitOffset>
              <bitWidth>1</bitWidth>
            </field>
            <field>
              <name>TEIE</name>
              <bitOffset>3</bitOffset>
              <bitWidth>1</bitWidth>
            </field>
            <field>
              <name>DIR</name>
              <bitOffset>4</bitOffset>
              <bitWidth>1</bitWidth>
            </field>
            <field>
              <name>CIRC</name>
              <bitOffset>5</bitOffset>
              <bitWidth>1</bitWidth>
            </field>
            <field>
              <name>PINC</name>
              <bitOffset>6</bitOffset>
              <bitWidth>1</bitWidth>
            </field>
            <field>
              <name>MINC</name>
              <bitOffset>7</bitOffset>
              <bitWidth>1</bitWidth>
            </field>
            <field>
              <name>PSIZE</name>
              <bitOffset>8</bitOffset>
              <bitWidth>2</bitWidth>
            </field>
            <field>
              <name>MSIZE</name>
              <bitOffset>10</bitOffset>
              <bitWidth>2</bitWidth>
            </field>
            <field>
              <name>PL</name>
              <bitOffset>12</bitOffset>
              <bitWidth>2</bitWidth>
            </field>
            <field>
              <name>MEM2MEM</name>
              <bitOffset>14</bitOffset>
              <bitWidth>1</bitWidth>
            </field>
          </fields>
        </register>
        <register>
          <name>CCR3</name>
          <addressOffset>0x30</addressOffset>
          <size>0x20</size>
          <fields>
            <field>
              <name>EN</name>
              <bitOffset>0</bitOffset>
              <bitWidth>1</bitWidth>
            </field>
            <field>
              <name>TCIE</name>
              <bitOffset>1</bitOffset>
              <bitWidth>1</bitWidth>
            </field>
            <field>
              <name>HTIE</name>
              <bitOffset>2</bitOffset>
              <bitWidth>1</bitWidth>
            </field>
            <field>
              <name>TEIE</name>
              <bitOffset>3</bitOffset>
              <bitWidth>1</bitWidth>
            </field>
            <field>
              <name>DIR</name>
              <bitOffset>4</bitOffset>
              <bitWidth>1</bitWidth>
            </field>
            <field>
              <name>CIRC</name>
              <bitOffset>5</bitOffset>
              <bitWidth>1</bitWidth>
            </field>
            <field>
              <name>PINC</name>
              <bitOffset>6</bitOffset>
              <bitWidth>1</bitWidth>
            </field>
            <field>
              <name>MINC</name>
              <bitOffset>7</bitOffset>
              <bitWidth>1</bitWidth>
            </field>
            <field>
              <name>PSIZE</name>
              <bitOffset>8</bitOffset>
              <bitWidth>2</bitWidth>
            </field>
            <field>
              <name>MSIZE</name>
              <bitOffset>10</bitOffset>
              <bitWidth>2</bitWidth>
            </field>
            <field>
              <name>PL</name>
              <bitOffset>12</bitOffset>
              <bitWidth>2</bitWidth>
            </field>
            <field>
              <name>MEM2MEM</name>
              <bitOffset>14</bitOffset>
              <bitWidth>1</bitWidth>
            </field>
          </fields>
        </register>
        <register>
          <name>CNDTR3</name>
          <addressOffset>0x34</addressOffset>
          <size>0x20</size>
          <fields>
            <field>
              <name>NDT</name>
              <bitOffset>0</bitOffset>
              <bitWidth>16</bitWidth>
            </field>
          </fields>
        </register>
        <register>
          <name>CNDTR3</name>
          <addressOffset>0x34</addressOffset>
          <size>0x20</size>
          <fields>
            <field>
              <name>NDT</name>
              <bitOffset>0</bitOffset>
              <bitWidth>16</bitWidth>
            </field>
          </fields>
        </register>
        <register>
          <name>CPAR3</name>
          <addressOffset>0x38</addressOffset>
          <size>0x20</size>
          <fields>
            <field>
              <name>PA</name>
              <bitOffset>0</bitOffset>
              <bitWidth>32</bitWidth>
            </field>
          </fields>
        </register>
        <register>
          <name>CPAR3</name>
          <addressOffset>0x38</addressOffset>
          <size>0x20</size>
          <fields>
            <field>
              <name>PA</name>
              <bitOffset>0</bitOffset>
              <bitWidth>32</bitWidth>
            </field>
          </fields>
        </register>
        <register>
          <name>CMAR3</name>
          <addressOffset>0x3c</addressOffset>
          <size>0x20</size>
          <fields>
            <field>
              <name>MA</name>
              <bitOffset>0</bitOffset>
              <bitWidth>32</bitWidth>
            </field>
          </fields>
        </register>
        <register>
          <name>CMAR3</name>
          <addressOffset>0x3c</addressOffset>
          <size>0x20</size>
          <fields>
            <field>
              <name>MA</name>
              <bitOffset>0</bitOffset>
              <bitWidth>32</bitWidth>
            </field>
          </fields>
        </register>
        <register>
          <name>CCR4</name>
          <addressOffset>0x44</addressOffset>
          <size>0x20</size>
          <fields>
            <field>
              <name>EN</name>
              <bitOffset>0</bitOffset>
              <bitWidth>1</bitWidth>
            </field>
            <field>
              <name>TCIE</name>
              <bitOffset>1</bitOffset>
              <bitWidth>1</bitWidth>
            </field>
            <field>
              <name>HTIE</name>
              <bitOffset>2</bitOffset>
              <bitWidth>1</bitWidth>
            </field>
            <field>
              <name>TEIE</name>
              <bitOffset>3</bitOffset>
              <bitWidth>1</bitWidth>
            </field>
            <field>
              <name>DIR</name>
              <bitOffset>4</bitOffset>
              <bitWidth>1</bitWidth>
            </field>
            <field>
              <name>CIRC</name>
              <bitOffset>5</bitOffset>
              <bitWidth>1</bitWidth>
            </field>
            <field>
              <name>PINC</name>
              <bitOffset>6</bitOffset>
              <bitWidth>1</bitWidth>
            </field>
            <field>
              <name>MINC</name>
              <bitOffset>7</bitOffset>
              <bitWidth>1</bitWidth>
            </field>
            <field>
              <name>PSIZE</name>
              <bitOffset>8</bitOffset>
              <bitWidth>2</bitWidth>
            </field>
            <field>
              <name>MSIZE</name>
              <bitOffset>10</bitOffset>
              <bitWidth>2</bitWidth>
            </field>
            <field>
              <name>PL</name>
              <bitOffset>12</bitOffset>
              <bitWidth>2</bitWidth>
            </field>
            <field>
              <name>MEM2MEM</name>
              <bitOffset>14</bitOffset>
              <bitWidth>1</bitWidth>
            </field>
          </fields>
        </register>
        <register>
          <name>CCR4</name>
          <addressOffset>0x44</addressOffset>
          <size>0x20</size>
          <fields>
            <field>
              <name>EN</name>
              <bitOffset>0</bitOffset>
              <bitWidth>1</bitWidth>
            </field>
            <field>
              <name>TCIE</name>
              <bitOffset>1</bitOffset>
              <bitWidth>1</bitWidth>
            </field>
            <field>
              <name>HTIE</name>
              <bitOffset>2</bitOffset>
              <bitWidth>1</bitWidth>
            </field>
            <field>
              <name>TEIE</name>
              <bitOffset>3</bitOffset>
              <bitWidth>1</bitWidth>
            </field>
            <field>
              <name>DIR</name>
              <bitOffset>4</bitOffset>
              <bitWidth>1</bitWidth>
            </field>
            <field>
              <name>CIRC</name>
              <bitOffset>5</bitOffset>
              <bitWidth>1</bitWidth>
            </field>
            <field>
              <name>PINC</name>
              <bitOffset>6</bitOffset>
              <bitWidth>1</bitWidth>
            </field>
            <field>
              <name>MINC</name>
              <bitOffset>7</bitOffset>
              <bitWidth>1</bitWidth>
            </field>
            <field>
              <name>PSIZE</name>
              <bitOffset>8</bitOffset>
              <bitWidth>2</bitWidth>
            </field>
            <field>
              <name>MSIZE</name>
              <bitOffset>10</bitOffset>
              <bitWidth>2</bitWidth>
            </field>
            <field>
              <name>PL</name>
              <bitOffset>12</bitOffset>
              <bitWidth>2</bitWidth>
            </field>
            <field>
              <name>MEM2MEM</name>
              <bitOffset>14</bitOffset>
              <bitWidth>1</bitWidth>
            </field>
          </fields>
        </register>
        <register>
          <name>CNDTR4</name>
          <addressOffset>0x48</addressOffset>
          <size>0x20</size>
          <fields>
            <field>
              <name>NDT</name>
              <bitOffset>0</bitOffset>
              <bitWidth>16</bitWidth>
            </field>
          </fields>
        </register>
        <register>
          <name>CNDTR4</name>
          <addressOffset>0x48</addressOffset>
          <size>0x20</size>
          <fields>
            <field>
              <name>NDT</name>
              <bitOffset>0</bitOffset>
              <bitWidth>16</bitWidth>
            </field>
          </fields>
        </register>
        <register>
          <name>CPAR4</name>
          <addressOffset>0x4c</addressOffset>
          <size>0x20</size>
          <fields>
            <field>
              <name>PA</name>
              <bitOffset>0</bitOffset>
              <bitWidth>32</bitWidth>
            </field>
          </fields>
        </register>
        <register>
          <name>CPAR4</name>
          <addressOffset>0x4c</addressOffset>
          <size>0x20</size>
          <fields>
            <field>
              <name>PA</name>
              <bitOffset>0</bitOffset>
              <bitWidth>32</bitWidth>
            </field>
          </fields>
        </register>
        <register>
          <name>CMAR4</name>
          <addressOffset>0x50</addressOffset>
          <size>0x20</size>
          <fields>
            <field>
              <name>MA</name>
              <bitOffset>0</bitOffset>
              <bitWidth>32</bitWidth>
            </field>
          </fields>
        </register>
        <register>
          <name>CMAR4</name>
          <addressOffset>0x50</addressOffset>
          <size>0x20</size>
          <fields>
            <field>
              <name>MA</name>
              <bitOffset>0</bitOffset>
              <bitWidth>32</bitWidth>
            </field>
          </fields>
        </register>
        <register>
          <name>CCR5</name>
          <addressOffset>0x58</addressOffset>
          <size>0x20</size>
          <fields>
            <field>
              <name>EN</name>
              <bitOffset>0</bitOffset>
              <bitWidth>1</bitWidth>
            </field>
            <field>
              <name>TCIE</name>
              <bitOffset>1</bitOffset>
              <bitWidth>1</bitWidth>
            </field>
            <field>
              <name>HTIE</name>
              <bitOffset>2</bitOffset>
              <bitWidth>1</bitWidth>
            </field>
            <field>
              <name>TEIE</name>
              <bitOffset>3</bitOffset>
              <bitWidth>1</bitWidth>
            </field>
            <field>
              <name>DIR</name>
              <bitOffset>4</bitOffset>
              <bitWidth>1</bitWidth>
            </field>
            <field>
              <name>CIRC</name>
              <bitOffset>5</bitOffset>
              <bitWidth>1</bitWidth>
            </field>
            <field>
              <name>PINC</name>
              <bitOffset>6</bitOffset>
              <bitWidth>1</bitWidth>
            </field>
            <field>
              <name>MINC</name>
              <bitOffset>7</bitOffset>
              <bitWidth>1</bitWidth>
            </field>
            <field>
              <name>PSIZE</name>
              <bitOffset>8</bitOffset>
              <bitWidth>2</bitWidth>
            </field>
            <field>
              <name>MSIZE</name>
              <bitOffset>10</bitOffset>
              <bitWidth>2</bitWidth>
            </field>
            <field>
              <name>PL</name>
              <bitOffset>12</bitOffset>
              <bitWidth>2</bitWidth>
            </field>
            <field>
              <name>MEM2MEM</name>
              <bitOffset>14</bitOffset>
              <bitWidth>1</bitWidth>
            </field>
          </fields>
        </register>
        <register>
          <name>CCR5</name>
          <addressOffset>0x58</addressOffset>
          <size>0x20</size>
          <fields>
            <field>
              <name>EN</name>
              <bitOffset>0</bitOffset>
              <bitWidth>1</bitWidth>
            </field>
            <field>
              <name>TCIE</name>
              <bitOffset>1</bitOffset>
              <bitWidth>1</bitWidth>
            </field>
            <field>
              <name>HTIE</name>
              <bitOffset>2</bitOffset>
              <bitWidth>1</bitWidth>
            </field>
            <field>
              <name>TEIE</name>
              <bitOffset>3</bitOffset>
              <bitWidth>1</bitWidth>
            </field>
            <field>
              <name>DIR</name>
              <bitOffset>4</bitOffset>
              <bitWidth>1</bitWidth>
            </field>
            <field>
              <name>CIRC</name>
              <bitOffset>5</bitOffset>
              <bitWidth>1</bitWidth>
            </field>
            <field>
              <name>PINC</name>
              <bitOffset>6</bitOffset>
              <bitWidth>1</bitWidth>
            </field>
            <field>
              <name>MINC</name>
              <bitOffset>7</bitOffset>
              <bitWidth>1</bitWidth>
            </field>
            <field>
              <name>PSIZE</name>
              <bitOffset>8</bitOffset>
              <bitWidth>2</bitWidth>
            </field>
            <field>
              <name>MSIZE</name>
              <bitOffset>10</bitOffset>
              <bitWidth>2</bitWidth>
            </field>
            <field>
              <name>PL</name>
              <bitOffset>12</bitOffset>
              <bitWidth>2</bitWidth>
            </field>
            <field>
              <name>MEM2MEM</name>
              <bitOffset>14</bitOffset>
              <bitWidth>1</bitWidth>
            </field>
          </fields>
        </register>
        <register>
          <name>CNDTR5</name>
          <addressOffset>0x5c</addressOffset>
          <size>0x20</size>
          <fields>
            <field>
              <name>NDT</name>
              <bitOffset>0</bitOffset>
              <bitWidth>16</bitWidth>
            </field>
          </fields>
        </register>
        <register>
          <name>CNDTR5</name>
          <addressOffset>0x5c</addressOffset>
          <size>0x20</size>
          <fields>
            <field>
              <name>NDT</name>
              <bitOffset>0</bitOffset>
              <bitWidth>16</bitWidth>
            </field>
          </fields>
        </register>
        <register>
          <name>CPAR5</name>
          <addressOffset>0x60</addressOffset>
          <size>0x20</size>
          <fields>
            <field>
              <name>PA</name>
              <bitOffset>0</bitOffset>
              <bitWidth>32</bitWidth>
            </field>
          </fields>
        </register>
        <register>
          <name>CPAR5</name>
          <addressOffset>0x60</addressOffset>
          <size>0x20</size>
          <fields>
            <field>
              <name>PA</name>
              <bitOffset>0</bitOffset>
              <bitWidth>32</bitWidth>
            </field>
          </fields>
        </register>
        <register>
          <name>CMAR5</name>
          <addressOffset>0x64</addressOffset>
          <size>0x20</size>
          <fields>
            <field>
              <name>MA</name>
              <bitOffset>0</bitOffset>
              <bitWidth>32</bitWidth>
            </field>
          </fields>
        </register>
        <register>
          <name>CMAR5</name>
          <addressOffset>0x64</addressOffset>
          <size>0x20</size>
          <fields>
            <field>
              <name>MA</name>
              <bitOffset>0</bitOffset>
              <bitWidth>32</bitWidth>
            </field>
          </fields>
        </register>
        <register>
          <name>CCR6</name>
          <addressOffset>0x6c</addressOffset>
          <size>0x20</size>
          <fields>
            <field>
              <name>EN</name>
              <bitOffset>0</bitOffset>
              <bitWidth>1</bitWidth>
            </field>
            <field>
              <name>TCIE</name>
              <bitOffset>1</bitOffset>
              <bitWidth>1</bitWidth>
            </field>
            <field>
              <name>HTIE</name>
              <bitOffset>2</bitOffset>
              <bitWidth>1</bitWidth>
            </field>
            <field>
              <name>TEIE</name>
              <bitOffset>3</bitOffset>
              <bitWidth>1</bitWidth>
            </field>
            <field>
              <name>DIR</name>
              <bitOffset>4</bitOffset>
              <bitWidth>1</bitWidth>
            </field>
            <field>
              <name>CIRC</name>
              <bitOffset>5</bitOffset>
              <bitWidth>1</bitWidth>
            </field>
            <field>
              <name>PINC</name>
              <bitOffset>6</bitOffset>
              <bitWidth>1</bitWidth>
            </field>
            <field>
              <name>MINC</name>
              <bitOffset>7</bitOffset>
              <bitWidth>1</bitWidth>
            </field>
            <field>
              <name>PSIZE</name>
              <bitOffset>8</bitOffset>
              <bitWidth>2</bitWidth>
            </field>
            <field>
              <name>MSIZE</name>
              <bitOffset>10</bitOffset>
              <bitWidth>2</bitWidth>
            </field>
            <field>
              <name>PL</name>
              <bitOffset>12</bitOffset>
              <bitWidth>2</bitWidth>
            </field>
            <field>
              <name>MEM2MEM</name>
              <bitOffset>14</bitOffset>
              <bitWidth>1</bitWidth>
            </field>
          </fields>
        </register>
        <register>
          <name>CCR6</name>
          <addressOffset>0x6c</addressOffset>
          <size>0x20</size>
          <fields>
            <field>
              <name>EN</name>
              <bitOffset>0</bitOffset>
              <bitWidth>1</bitWidth>
            </field>
            <field>
              <name>TCIE</name>
              <bitOffset>1</bitOffset>
              <bitWidth>1</bitWidth>
            </field>
            <field>
              <name>HTIE</name>
              <bitOffset>2</bitOffset>
              <bitWidth>1</bitWidth>
            </field>
            <field>
              <name>TEIE</name>
              <bitOffset>3</bitOffset>
              <bitWidth>1</bitWidth>
            </field>
            <field>
              <name>DIR</name>
              <bitOffset>4</bitOffset>
              <bitWidth>1</bitWidth>
            </field>
            <field>
              <name>CIRC</name>
              <bitOffset>5</bitOffset>
              <bitWidth>1</bitWidth>
            </field>
            <field>
              <name>PINC</name>
              <bitOffset>6</bitOffset>
              <bitWidth>1</bitWidth>
            </field>
            <field>
              <name>MINC</name>
              <bitOffset>7</bitOffset>
              <bitWidth>1</bitWidth>
            </field>
            <field>
              <name>PSIZE</name>
              <bitOffset>8</bitOffset>
              <bitWidth>2</bitWidth>
            </field>
            <field>
              <name>MSIZE</name>
              <bitOffset>10</bitOffset>
              <bitWidth>2</bitWidth>
            </field>
            <field>
              <name>PL</name>
              <bitOffset>12</bitOffset>
              <bitWidth>2</bitWidth>
            </field>
            <field>
              <name>MEM2MEM</name>
              <bitOffset>14</bitOffset>
              <bitWidth>1</bitWidth>
            </field>
          </fields>
        </register>
        <register>
          <name>CNDTR6</name>
          <addressOffset>0x70</addressOffset>
          <size>0x20</size>
          <fields>
            <field>
              <name>NDT</name>
              <bitOffset>0</bitOffset>
              <bitWidth>16</bitWidth>
            </field>
          </fields>
        </register>
        <register>
          <name>CNDTR6</name>
          <addressOffset>0x70</addressOffset>
          <size>0x20</size>
          <fields>
            <field>
              <name>NDT</name>
              <bitOffset>0</bitOffset>
              <bitWidth>16</bitWidth>
            </field>
          </fields>
        </register>
        <register>
          <name>CPAR6</name>
          <addressOffset>0x74</addressOffset>
          <size>0x20</size>
          <fields>
            <field>
              <name>PA</name>
              <bitOffset>0</bitOffset>
              <bitWidth>32</bitWidth>
            </field>
          </fields>
        </register>
        <register>
          <name>CPAR6</name>
          <addressOffset>0x74</addressOffset>
          <size>0x20</size>
          <fields>
            <field>
              <name>PA</name>
              <bitOffset>0</bitOffset>
              <bitWidth>32</bitWidth>
            </field>
          </fields>
        </register>
        <register>
          <name>CMAR6</name>
          <addressOffset>0x78</addressOffset>
          <size>0x20</size>
          <fields>
            <field>
              <name>MA</name>
              <bitOffset>0</bitOffset>
              <bitWidth>32</bitWidth>
            </field>
          </fields>
        </register>
        <register>
          <name>CMAR6</name>
          <addressOffset>0x78</addressOffset>
          <size>0x20</size>
          <fields>
            <field>
              <name>MA</name>
              <bitOffset>0</bitOffset>
              <bitWidth>32</bitWidth>
            </field>
          </fields>
        </register>
        <register>
          <name>CCR7</name>
          <addressOffset>0x80</addressOffset>
          <size>0x20</size>
          <fields>
            <field>
              <name>EN</name>
              <bitOffset>0</bitOffset>
              <bitWidth>1</bitWidth>
            </field>
            <field>
              <name>TCIE</name>
              <bitOffset>1</bitOffset>
              <bitWidth>1</bitWidth>
            </field>
            <field>
              <name>HTIE</name>
              <bitOffset>2</bitOffset>
              <bitWidth>1</bitWidth>
            </field>
            <field>
              <name>TEIE</name>
              <bitOffset>3</bitOffset>
              <bitWidth>1</bitWidth>
            </field>
            <field>
              <name>DIR</name>
              <bitOffset>4</bitOffset>
              <bitWidth>1</bitWidth>
            </field>
            <field>
              <name>CIRC</name>
              <bitOffset>5</bitOffset>
              <bitWidth>1</bitWidth>
            </field>
            <field>
              <name>PINC</name>
              <bitOffset>6</bitOffset>
              <bitWidth>1</bitWidth>
            </field>
            <field>
              <name>MINC</name>
              <bitOffset>7</bitOffset>
              <bitWidth>1</bitWidth>
            </field>
            <field>
              <name>PSIZE</name>
              <bitOffset>8</bitOffset>
              <bitWidth>2</bitWidth>
            </field>
            <field>
              <name>MSIZE</name>
              <bitOffset>10</bitOffset>
              <bitWidth>2</bitWidth>
            </field>
            <field>
              <name>PL</name>
              <bitOffset>12</bitOffset>
              <bitWidth>2</bitWidth>
            </field>
            <field>
              <name>MEM2MEM</name>
              <bitOffset>14</bitOffset>
              <bitWidth>1</bitWidth>
            </field>
          </fields>
        </register>
        <register>
          <name>CCR7</name>
          <addressOffset>0x80</addressOffset>
          <size>0x20</size>
          <fields>
            <field>
              <name>EN</name>
              <bitOffset>0</bitOffset>
              <bitWidth>1</bitWidth>
            </field>
            <field>
              <name>TCIE</name>
              <bitOffset>1</bitOffset>
              <bitWidth>1</bitWidth>
            </field>
            <field>
              <name>HTIE</name>
              <bitOffset>2</bitOffset>
              <bitWidth>1</bitWidth>
            </field>
            <field>
              <name>TEIE</name>
              <bitOffset>3</bitOffset>
              <bitWidth>1</bitWidth>
            </field>
            <field>
              <name>DIR</name>
              <bitOffset>4</bitOffset>
              <bitWidth>1</bitWidth>
            </field>
            <field>
              <name>CIRC</name>
              <bitOffset>5</bitOffset>
              <bitWidth>1</bitWidth>
            </field>
            <field>
              <name>PINC</name>
              <bitOffset>6</bitOffset>
              <bitWidth>1</bitWidth>
            </field>
            <field>
              <name>MINC</name>
              <bitOffset>7</bitOffset>
              <bitWidth>1</bitWidth>
            </field>
            <field>
              <name>PSIZE</name>
              <bitOffset>8</bitOffset>
              <bitWidth>2</bitWidth>
            </field>
            <field>
              <name>MSIZE</name>
              <bitOffset>10</bitOffset>
              <bitWidth>2</bitWidth>
            </field>
            <field>
              <name>PL</name>
              <bitOffset>12</bitOffset>
              <bitWidth>2</bitWidth>
            </field>
            <field>
              <name>MEM2MEM</name>
              <bitOffset>14</bitOffset>
              <bitWidth>1</bitWidth>
            </field>
          </fields>
        </register>
        <register>
          <name>CNDTR7</name>
          <addressOffset>0x84</addressOffset>
          <size>0x20</size>
          <fields>
            <field>
              <name>NDT</name>
              <bitOffset>0</bitOffset>
              <bitWidth>16</bitWidth>
            </field>
          </fields>
        </register>
        <register>
          <name>CNDTR7</name>
          <addressOffset>0x84</addressOffset>
          <size>0x20</size>
          <fields>
            <field>
              <name>NDT</name>
              <bitOffset>0</bitOffset>
              <bitWidth>16</bitWidth>
            </field>
          </fields>
        </register>
        <register>
          <name>CPAR7</name>
          <addressOffset>0x88</addressOffset>
          <size>0x20</size>
          <fields>
            <field>
              <name>PA</name>
              <bitOffset>0</bitOffset>
              <bitWidth>32</bitWidth>
            </field>
          </fields>
        </register>
        <register>
          <name>CPAR7</name>
          <addressOffset>0x88</addressOffset>
          <size>0x20</size>
          <fields>
            <field>
              <name>PA</name>
              <bitOffset>0</bitOffset>
              <bitWidth>32</bitWidth>
            </field>
          </fields>
        </register>
        <register>
          <name>CMAR7</name>
          <addressOffset>0x8c</addressOffset>
          <size>0x20</size>
          <fields>
            <field>
              <name>MA</name>
              <bitOffset>0</bitOffset>
              <bitWidth>32</bitWidth>
            </field>
          </fields>
        </register>
        <register>
          <name>CMAR7</name>
          <addressOffset>0x8c</addressOffset>
          <size>0x20</size>
          <fields>
            <field>
              <name>MA</name>
              <bitOffset>0</bitOffset>
              <bitWidth>32</bitWidth>
            </field>
          </fields>
        </register>
        <register>
          <name>CCR8</name>
          <addressOffset>0x94</addressOffset>
          <size>0x20</size>
          <fields>
            <field>
              <name>EN</name>
              <bitOffset>0</bitOffset>
              <bitWidth>1</bitWidth>
            </field>
            <field>
              <name>TCIE</name>
              <bitOffset>1</bitOffset>
              <bitWidth>1</bitWidth>
            </field>
            <field>
              <name>HTIE</name>
              <bitOffset>2</bitOffset>
              <bitWidth>1</bitWidth>
            </field>
            <field>
              <name>TEIE</name>
              <bitOffset>3</bitOffset>
              <bitWidth>1</bitWidth>
            </field>
            <field>
              <name>DIR</name>
              <bitOffset>4</bitOffset>
              <bitWidth>1</bitWidth>
            </field>
            <field>
              <name>CIRC</name>
              <bitOffset>5</bitOffset>
              <bitWidth>1</bitWidth>
            </field>
            <field>
              <name>PINC</name>
              <bitOffset>6</bitOffset>
              <bitWidth>1</bitWidth>
            </field>
            <field>
              <name>MINC</name>
              <bitOffset>7</bitOffset>
              <bitWidth>1</bitWidth>
            </field>
            <field>
              <name>PSIZE</name>
              <bitOffset>8</bitOffset>
              <bitWidth>2</bitWidth>
            </field>
            <field>
              <name>MSIZE</name>
              <bitOffset>10</bitOffset>
              <bitWidth>2</bitWidth>
            </field>
            <field>
              <name>PL</name>
              <bitOffset>12</bitOffset>
              <bitWidth>2</bitWidth>
            </field>
            <field>
              <name>MEM2MEM</name>
              <bitOffset>14</bitOffset>
              <bitWidth>1</bitWidth>
            </field>
          </fields>
        </register>
        <register>
          <name>CCR8</name>
          <addressOffset>0x94</addressOffset>
          <size>0x20</size>
          <fields>
            <field>
              <name>EN</name>
              <bitOffset>0</bitOffset>
              <bitWidth>1</bitWidth>
            </field>
            <field>
              <name>TCIE</name>
              <bitOffset>1</bitOffset>
              <bitWidth>1</bitWidth>
            </field>
            <field>
              <name>HTIE</name>
              <bitOffset>2</bitOffset>
              <bitWidth>1</bitWidth>
            </field>
            <field>
              <name>TEIE</name>
              <bitOffset>3</bitOffset>
              <bitWidth>1</bitWidth>
            </field>
            <field>
              <name>DIR</name>
              <bitOffset>4</bitOffset>
              <bitWidth>1</bitWidth>
            </field>
            <field>
              <name>CIRC</name>
              <bitOffset>5</bitOffset>
              <bitWidth>1</bitWidth>
            </field>
            <field>
              <name>PINC</name>
              <bitOffset>6</bitOffset>
              <bitWidth>1</bitWidth>
            </field>
            <field>
              <name>MINC</name>
              <bitOffset>7</bitOffset>
              <bitWidth>1</bitWidth>
            </field>
            <field>
              <name>PSIZE</name>
              <bitOffset>8</bitOffset>
              <bitWidth>2</bitWidth>
            </field>
            <field>
              <name>MSIZE</name>
              <bitOffset>10</bitOffset>
              <bitWidth>2</bitWidth>
            </field>
            <field>
              <name>PL</name>
              <bitOffset>12</bitOffset>
              <bitWidth>2</bitWidth>
            </field>
            <field>
              <name>MEM2MEM</name>
              <bitOffset>14</bitOffset>
              <bitWidth>1</bitWidth>
            </field>
          </fields>
        </register>
        <register>
          <name>CNDTR8</name>
          <addressOffset>0x98</addressOffset>
          <size>0x20</size>
          <fields>
            <field>
              <name>NDT</name>
              <bitOffset>0</bitOffset>
              <bitWidth>16</bitWidth>
            </field>
          </fields>
        </register>
        <register>
          <name>CNDTR8</name>
          <addressOffset>0x98</addressOffset>
          <size>0x20</size>
          <fields>
            <field>
              <name>NDT</name>
              <bitOffset>0</bitOffset>
              <bitWidth>16</bitWidth>
            </field>
          </fields>
        </register>
        <register>
          <name>CPAR8</name>
          <addressOffset>0x9c</addressOffset>
          <size>0x20</size>
          <fields>
            <field>
              <name>PA</name>
              <bitOffset>0</bitOffset>
              <bitWidth>32</bitWidth>
            </field>
          </fields>
        </register>
        <register>
          <name>CPAR8</name>
          <addressOffset>0x9c</addressOffset>
          <size>0x20</size>
          <fields>
            <field>
              <name>PA</name>
              <bitOffset>0</bitOffset>
              <bitWidth>32</bitWidth>
            </field>
          </fields>
        </register>
        <register>
          <name>CMAR8</name>
          <addressOffset>0xa0</addressOffset>
          <size>0x20</size>
          <fields>
            <field>
              <name>MA</name>
              <bitOffset>0</bitOffset>
              <bitWidth>32</bitWidth>
            </field>
          </fields>
        </register>
        <register>
          <name>CMAR8</name>
          <addressOffset>0xa0</addressOffset>
          <size>0x20</size>
          <fields>
            <field>
              <name>MA</name>
              <bitOffset>0</bitOffset>
              <bitWidth>32</bitWidth>
            </field>
          </fields>
        </register>
      </registers>
    </peripheral>
    <peripheral>
      <name>DMA2</name>
      <baseAddress>0x40020400</baseAddress>
      <registers>
        <register>
          <name>ISR</name>
          <addressOffset>0x0</addressOffset>
          <size>0x20</size>
          <fields>
            <field>
              <name>GIF1</name>
              <bitOffset>0</bitOffset>
              <bitWidth>1</bitWidth>
            </field>
            <field>
              <name>TCIF1</name>
              <bitOffset>1</bitOffset>
              <bitWidth>1</bitWidth>
            </field>
            <field>
              <name>HTIF1</name>
              <bitOffset>2</bitOffset>
              <bitWidth>1</bitWidth>
            </field>
            <field>
              <name>TEIF1</name>
              <bitOffset>3</bitOffset>
              <bitWidth>1</bitWidth>
            </field>
            <field>
              <name>GIF2</name>
              <bitOffset>4</bitOffset>
              <bitWidth>1</bitWidth>
            </field>
            <field>
              <name>TCIF2</name>
              <bitOffset>5</bitOffset>
              <bitWidth>1</bitWidth>
            </field>
            <field>
              <name>HTIF2</name>
              <bitOffset>6</bitOffset>
              <bitWidth>1</bitWidth>
            </field>
            <field>
              <name>TEIF2</name>
              <bitOffset>7</bitOffset>
              <bitWidth>1</bitWidth>
            </field>
            <field>
              <name>GIF3</name>
              <bitOffset>8</bitOffset>
              <bitWidth>1</bitWidth>
            </field>
            <field>
              <name>TCIF3</name>
              <bitOffset>9</bitOffset>
              <bitWidth>1</bitWidth>
            </field>
            <field>
              <name>HTIF3</name>
              <bitOffset>10</bitOffset>
              <bitWidth>1</bitWidth>
            </field>
            <field>
              <name>TEIF3</name>
              <bitOffset>11</bitOffset>
              <bitWidth>1</bitWidth>
            </field>
            <field>
              <name>GIF4</name>
              <bitOffset>12</bitOffset>
              <bitWidth>1</bitWidth>
            </field>
            <field>
              <name>TCIF4</name>
              <bitOffset>13</bitOffset>
              <bitWidth>1</bitWidth>
            </field>
            <field>
              <name>HTIF4</name>
              <bitOffset>14</bitOffset>
              <bitWidth>1</bitWidth>
            </field>
            <field>
              <name>TEIF4</name>
              <bitOffset>15</bitOffset>
              <bitWidth>1</bitWidth>
            </field>
            <field>
              <name>GIF5</name>
              <bitOffset>16</bitOffset>
              <bitWidth>1</bitWidth>
            </field>
            <field>
              <name>TCIF5</name>
              <bitOffset>17</bitOffset>
              <bitWidth>1</bitWidth>
            </field>
            <field>
              <name>HTIF5</name>
              <bitOffset>18</bitOffset>
              <bitWidth>1</bitWidth>
            </field>
            <field>
              <name>TEIF5</name>
              <bitOffset>19</bitOffset>
              <bitWidth>1</bitWidth>
            </field>
            <field>
              <name>GIF6</name>
              <bitOffset>20</bitOffset>
              <bitWidth>1</bitWidth>
            </field>
            <field>
              <name>TCIF6</name>
              <bitOffset>21</bitOffset>
              <bitWidth>1</bitWidth>
            </field>
            <field>
              <name>HTIF6</name>
              <bitOffset>22</bitOffset>
              <bitWidth>1</bitWidth>
            </field>
            <field>
              <name>TEIF6</name>
              <bitOffset>23</bitOffset>
              <bitWidth>1</bitWidth>
            </field>
            <field>
              <name>GIF7</name>
              <bitOffset>24</bitOffset>
              <bitWidth>1</bitWidth>
            </field>
            <field>
              <name>TCIF7</name>
              <bitOffset>25</bitOffset>
              <bitWidth>1</bitWidth>
            </field>
            <field>
              <name>HTIF7</name>
              <bitOffset>26</bitOffset>
              <bitWidth>1</bitWidth>
            </field>
            <field>
              <name>TEIF7</name>
              <bitOffset>27</bitOffset>
              <bitWidth>1</bitWidth>
            </field>
            <field>
              <name>GIF8</name>
              <bitOffset>28</bitOffset>
              <bitWidth>1</bitWidth>
            </field>
            <field>
              <name>TCIF8</name>
              <bitOffset>29</bitOffset>
              <bitWidth>1</bitWidth>
            </field>
            <field>
              <name>HTIF8</name>
              <bitOffset>30</bitOffset>
              <bitWidth>1</bitWidth>
            </field>
            <field>
              <name>TEIF8</name>
              <bitOffset>31</bitOffset>
              <bitWidth>1</bitWidth>
            </field>
          </fields>
        </register>
        <register>
          <name>IFCR</name>
          <addressOffset>0x4</addressOffset>
          <size>0x20</size>
          <fields>
            <field>
              <name>CGIF1</name>
              <bitOffset>0</bitOffset>
              <bitWidth>1</bitWidth>
            </field>
            <field>
              <name>CTCIF1</name>
              <bitOffset>1</bitOffset>
              <bitWidth>1</bitWidth>
            </field>
            <field>
              <name>CHTIF1</name>
              <bitOffset>2</bitOffset>
              <bitWidth>1</bitWidth>
            </field>
            <field>
              <name>CTEIF1</name>
              <bitOffset>3</bitOffset>
              <bitWidth>1</bitWidth>
            </field>
            <field>
              <name>CGIF2</name>
              <bitOffset>4</bitOffset>
              <bitWidth>1</bitWidth>
            </field>
            <field>
              <name>CTCIF2</name>
              <bitOffset>5</bitOffset>
              <bitWidth>1</bitWidth>
            </field>
            <field>
              <name>CHTIF2</name>
              <bitOffset>6</bitOffset>
              <bitWidth>1</bitWidth>
            </field>
            <field>
              <name>CTEIF2</name>
              <bitOffset>7</bitOffset>
              <bitWidth>1</bitWidth>
            </field>
            <field>
              <name>CGIF3</name>
              <bitOffset>8</bitOffset>
              <bitWidth>1</bitWidth>
            </field>
            <field>
              <name>CTCIF3</name>
              <bitOffset>9</bitOffset>
              <bitWidth>1</bitWidth>
            </field>
            <field>
              <name>CHTIF3</name>
              <bitOffset>10</bitOffset>
              <bitWidth>1</bitWidth>
            </field>
            <field>
              <name>CTEIF3</name>
              <bitOffset>11</bitOffset>
              <bitWidth>1</bitWidth>
            </field>
            <field>
              <name>CGIF4</name>
              <bitOffset>12</bitOffset>
              <bitWidth>1</bitWidth>
            </field>
            <field>
              <name>CTCIF4</name>
              <bitOffset>13</bitOffset>
              <bitWidth>1</bitWidth>
            </field>
            <field>
              <name>CHTIF4</name>
              <bitOffset>14</bitOffset>
              <bitWidth>1</bitWidth>
            </field>
            <field>
              <name>CTEIF4</name>
              <bitOffset>15</bitOffset>
              <bitWidth>1</bitWidth>
            </field>
            <field>
              <name>CGIF5</name>
              <bitOffset>16</bitOffset>
              <bitWidth>1</bitWidth>
            </field>
            <field>
              <name>CTCIF5</name>
              <bitOffset>17</bitOffset>
              <bitWidth>1</bitWidth>
            </field>
            <field>
              <name>CHTIF5</name>
              <bitOffset>18</bitOffset>
              <bitWidth>1</bitWidth>
            </field>
            <field>
              <name>CTEIF5</name>
              <bitOffset>19</bitOffset>
              <bitWidth>1</bitWidth>
            </field>
            <field>
              <name>CGIF6</name>
              <bitOffset>20</bitOffset>
              <bitWidth>1</bitWidth>
            </field>
            <field>
              <name>CTCIF6</name>
              <bitOffset>21</bitOffset>
              <bitWidth>1</bitWidth>
            </field>
            <field>
              <name>CHTIF6</name>
              <bitOffset>22</bitOffset>
              <bitWidth>1</bitWidth>
            </field>
            <field>
              <name>CTEIF6</name>
              <bitOffset>23</bitOffset>
              <bitWidth>1</bitWidth>
            </field>
            <field>
              <name>CGIF7</name>
              <bitOffset>24</bitOffset>
              <bitWidth>1</bitWidth>
            </field>
            <field>
              <name>CTCIF7</name>
              <bitOffset>25</bitOffset>
              <bitWidth>1</bitWidth>
            </field>
            <field>
              <name>CHTIF7</name>
              <bitOffset>26</bitOffset>
              <bitWidth>1</bitWidth>
            </field>
            <field>
              <name>CTEIF7</name>
              <bitOffset>27</bitOffset>
              <bitWidth>1</bitWidth>
            </field>
            <field>
              <name>CGIF8</name>
              <bitOffset>28</bitOffset>
              <bitWidth>1</bitWidth>
            </field>
            <field>
              <name>CTCIF8</name>
              <bitOffset>29</bitOffset>
              <bitWidth>1</bitWidth>
            </field>
            <field>
              <name>CHTIF8</name>
              <bitOffset>30</bitOffset>
              <bitWidth>1</bitWidth>
            </field>
            <field>
              <name>CTEIF8</name>
              <bitOffset>31</bitOffset>
              <bitWidth>1</bitWidth>
            </field>
          </fields>
        </register>
        <register>
          <name>CCR1</name>
          <addressOffset>0x8</addressOffset>
          <size>0x20</size>
          <fields>
            <field>
              <name>EN</name>
              <bitOffset>0</bitOffset>
              <bitWidth>1</bitWidth>
            </field>
            <field>
              <name>TCIE</name>
              <bitOffset>1</bitOffset>
              <bitWidth>1</bitWidth>
            </field>
            <field>
              <name>HTIE</name>
              <bitOffset>2</bitOffset>
              <bitWidth>1</bitWidth>
            </field>
            <field>
              <name>TEIE</name>
              <bitOffset>3</bitOffset>
              <bitWidth>1</bitWidth>
            </field>
            <field>
              <name>DIR</name>
              <bitOffset>4</bitOffset>
              <bitWidth>1</bitWidth>
            </field>
            <field>
              <name>CIRC</name>
              <bitOffset>5</bitOffset>
              <bitWidth>1</bitWidth>
            </field>
            <field>
              <name>PINC</name>
              <bitOffset>6</bitOffset>
              <bitWidth>1</bitWidth>
            </field>
            <field>
              <name>MINC</name>
              <bitOffset>7</bitOffset>
              <bitWidth>1</bitWidth>
            </field>
            <field>
              <name>PSIZE</name>
              <bitOffset>8</bitOffset>
              <bitWidth>2</bitWidth>
            </field>
            <field>
              <name>MSIZE</name>
              <bitOffset>10</bitOffset>
              <bitWidth>2</bitWidth>
            </field>
            <field>
              <name>PL</name>
              <bitOffset>12</bitOffset>
              <bitWidth>2</bitWidth>
            </field>
            <field>
              <name>MEM2MEM</name>
              <bitOffset>14</bitOffset>
              <bitWidth>1</bitWidth>
            </field>
          </fields>
        </register>
        <register>
          <name>CCR1</name>
          <addressOffset>0x8</addressOffset>
          <size>0x20</size>
          <fields>
            <field>
              <name>EN</name>
              <bitOffset>0</bitOffset>
              <bitWidth>1</bitWidth>
            </field>
            <field>
              <name>TCIE</name>
              <bitOffset>1</bitOffset>
              <bitWidth>1</bitWidth>
            </field>
            <field>
              <name>HTIE</name>
              <bitOffset>2</bitOffset>
              <bitWidth>1</bitWidth>
            </field>
            <field>
              <name>TEIE</name>
              <bitOffset>3</bitOffset>
              <bitWidth>1</bitWidth>
            </field>
            <field>
              <name>DIR</name>
              <bitOffset>4</bitOffset>
              <bitWidth>1</bitWidth>
            </field>
            <field>
              <name>CIRC</name>
              <bitOffset>5</bitOffset>
              <bitWidth>1</bitWidth>
            </field>
            <field>
              <name>PINC</name>
              <bitOffset>6</bitOffset>
              <bitWidth>1</bitWidth>
            </field>
            <field>
              <name>MINC</name>
              <bitOffset>7</bitOffset>
              <bitWidth>1</bitWidth>
            </field>
            <field>
              <name>PSIZE</name>
              <bitOffset>8</bitOffset>
              <bitWidth>2</bitWidth>
            </field>
            <field>
              <name>MSIZE</name>
              <bitOffset>10</bitOffset>
              <bitWidth>2</bitWidth>
            </field>
            <field>
              <name>PL</name>
              <bitOffset>12</bitOffset>
              <bitWidth>2</bitWidth>
            </field>
            <field>
              <name>MEM2MEM</name>
              <bitOffset>14</bitOffset>
              <bitWidth>1</bitWidth>
            </field>
          </fields>
        </register>
        <register>
          <name>CNDTR1</name>
          <addressOffset>0xc</addressOffset>
          <size>0x20</size>
          <fields>
            <field>
              <name>NDT</name>
              <bitOffset>0</bitOffset>
              <bitWidth>16</bitWidth>
            </field>
          </fields>
        </register>
        <register>
          <name>CNDTR1</name>
          <addressOffset>0xc</addressOffset>
          <size>0x20</size>
          <fields>
            <field>
              <name>NDT</name>
              <bitOffset>0</bitOffset>
              <bitWidth>16</bitWidth>
            </field>
          </fields>
        </register>
        <register>
          <name>CPAR1</name>
          <addressOffset>0x10</addressOffset>
          <size>0x20</size>
          <fields>
            <field>
              <name>PA</name>
              <bitOffset>0</bitOffset>
              <bitWidth>32</bitWidth>
            </field>
          </fields>
        </register>
        <register>
          <name>CPAR1</name>
          <addressOffset>0x10</addressOffset>
          <size>0x20</size>
          <fields>
            <field>
              <name>PA</name>
              <bitOffset>0</bitOffset>
              <bitWidth>32</bitWidth>
            </field>
          </fields>
        </register>
        <register>
          <name>CMAR1</name>
          <addressOffset>0x14</addressOffset>
          <size>0x20</size>
          <fields>
            <field>
              <name>MA</name>
              <bitOffset>0</bitOffset>
              <bitWidth>32</bitWidth>
            </field>
          </fields>
        </register>
        <register>
          <name>CMAR1</name>
          <addressOffset>0x14</addressOffset>
          <size>0x20</size>
          <fields>
            <field>
              <name>MA</name>
              <bitOffset>0</bitOffset>
              <bitWidth>32</bitWidth>
            </field>
          </fields>
        </register>
        <register>
          <name>CCR2</name>
          <addressOffset>0x1c</addressOffset>
          <size>0x20</size>
          <fields>
            <field>
              <name>EN</name>
              <bitOffset>0</bitOffset>
              <bitWidth>1</bitWidth>
            </field>
            <field>
              <name>TCIE</name>
              <bitOffset>1</bitOffset>
              <bitWidth>1</bitWidth>
            </field>
            <field>
              <name>HTIE</name>
              <bitOffset>2</bitOffset>
              <bitWidth>1</bitWidth>
            </field>
            <field>
              <name>TEIE</name>
              <bitOffset>3</bitOffset>
              <bitWidth>1</bitWidth>
            </field>
            <field>
              <name>DIR</name>
              <bitOffset>4</bitOffset>
              <bitWidth>1</bitWidth>
            </field>
            <field>
              <name>CIRC</name>
              <bitOffset>5</bitOffset>
              <bitWidth>1</bitWidth>
            </field>
            <field>
              <name>PINC</name>
              <bitOffset>6</bitOffset>
              <bitWidth>1</bitWidth>
            </field>
            <field>
              <name>MINC</name>
              <bitOffset>7</bitOffset>
              <bitWidth>1</bitWidth>
            </field>
            <field>
              <name>PSIZE</name>
              <bitOffset>8</bitOffset>
              <bitWidth>2</bitWidth>
            </field>
            <field>
              <name>MSIZE</name>
              <bitOffset>10</bitOffset>
              <bitWidth>2</bitWidth>
            </field>
            <field>
              <name>PL</name>
              <bitOffset>12</bitOffset>
              <bitWidth>2</bitWidth>
            </field>
            <field>
              <name>MEM2MEM</name>
              <bitOffset>14</bitOffset>
              <bitWidth>1</bitWidth>
            </field>
          </fields>
        </register>
        <register>
          <name>CCR2</name>
          <addressOffset>0x1c</addressOffset>
          <size>0x20</size>
          <fields>
            <field>
              <name>EN</name>
              <bitOffset>0</bitOffset>
              <bitWidth>1</bitWidth>
            </field>
            <field>
              <name>TCIE</name>
              <bitOffset>1</bitOffset>
              <bitWidth>1</bitWidth>
            </field>
            <field>
              <name>HTIE</name>
              <bitOffset>2</bitOffset>
              <bitWidth>1</bitWidth>
            </field>
            <field>
              <name>TEIE</name>
              <bitOffset>3</bitOffset>
              <bitWidth>1</bitWidth>
            </field>
            <field>
              <name>DIR</name>
              <bitOffset>4</bitOffset>
              <bitWidth>1</bitWidth>
            </field>
            <field>
              <name>CIRC</name>
              <bitOffset>5</bitOffset>
              <bitWidth>1</bitWidth>
            </field>
            <field>
              <name>PINC</name>
              <bitOffset>6</bitOffset>
              <bitWidth>1</bitWidth>
            </field>
            <field>
              <name>MINC</name>
              <bitOffset>7</bitOffset>
              <bitWidth>1</bitWidth>
            </field>
            <field>
              <name>PSIZE</name>
              <bitOffset>8</bitOffset>
              <bitWidth>2</bitWidth>
            </field>
            <field>
              <name>MSIZE</name>
              <bitOffset>10</bitOffset>
              <bitWidth>2</bitWidth>
            </field>
            <field>
              <name>PL</name>
              <bitOffset>12</bitOffset>
              <bitWidth>2</bitWidth>
            </field>
            <field>
              <name>MEM2MEM</name>
              <bitOffset>14</bitOffset>
              <bitWidth>1</bitWidth>
            </field>
          </fields>
        </register>
        <register>
          <name>CNDTR2</name>
          <addressOffset>0x20</addressOffset>
          <size>0x20</size>
          <fields>
            <field>
              <name>NDT</name>
              <bitOffset>0</bitOffset>
              <bitWidth>16</bitWidth>
            </field>
          </fields>
        </register>
        <register>
          <name>CNDTR2</name>
          <addressOffset>0x20</addressOffset>
          <size>0x20</size>
          <fields>
            <field>
              <name>NDT</name>
              <bitOffset>0</bitOffset>
              <bitWidth>16</bitWidth>
            </field>
          </fields>
        </register>
        <register>
          <name>CPAR2</name>
          <addressOffset>0x24</addressOffset>
          <size>0x20</size>
          <fields>
            <field>
              <name>PA</name>
              <bitOffset>0</bitOffset>
              <bitWidth>32</bitWidth>
            </field>
          </fields>
        </register>
        <register>
          <name>CPAR2</name>
          <addressOffset>0x24</addressOffset>
          <size>0x20</size>
          <fields>
            <field>
              <name>PA</name>
              <bitOffset>0</bitOffset>
              <bitWidth>32</bitWidth>
            </field>
          </fields>
        </register>
        <register>
          <name>CMAR2</name>
          <addressOffset>0x28</addressOffset>
          <size>0x20</size>
          <fields>
            <field>
              <name>MA</name>
              <bitOffset>0</bitOffset>
              <bitWidth>32</bitWidth>
            </field>
          </fields>
        </register>
        <register>
          <name>CMAR2</name>
          <addressOffset>0x28</addressOffset>
          <size>0x20</size>
          <fields>
            <field>
              <name>MA</name>
              <bitOffset>0</bitOffset>
              <bitWidth>32</bitWidth>
            </field>
          </fields>
        </register>
        <register>
          <name>CCR3</name>
          <addressOffset>0x30</addressOffset>
          <size>0x20</size>
          <fields>
            <field>
              <name>EN</name>
              <bitOffset>0</bitOffset>
              <bitWidth>1</bitWidth>
            </field>
            <field>
              <name>TCIE</name>
              <bitOffset>1</bitOffset>
              <bitWidth>1</bitWidth>
            </field>
            <field>
              <name>HTIE</name>
              <bitOffset>2</bitOffset>
              <bitWidth>1</bitWidth>
            </field>
            <field>
              <name>TEIE</name>
              <bitOffset>3</bitOffset>
              <bitWidth>1</bitWidth>
            </field>
            <field>
              <name>DIR</name>
              <bitOffset>4</bitOffset>
              <bitWidth>1</bitWidth>
            </field>
            <field>
              <name>CIRC</name>
              <bitOffset>5</bitOffset>
              <bitWidth>1</bitWidth>
            </field>
            <field>
              <name>PINC</name>
              <bitOffset>6</bitOffset>
              <bitWidth>1</bitWidth>
            </field>
            <field>
              <name>MINC</name>
              <bitOffset>7</bitOffset>
              <bitWidth>1</bitWidth>
            </field>
            <field>
              <name>PSIZE</name>
              <bitOffset>8</bitOffset>
              <bitWidth>2</bitWidth>
            </field>
            <field>
              <name>MSIZE</name>
              <bitOffset>10</bitOffset>
              <bitWidth>2</bitWidth>
            </field>
            <field>
              <name>PL</name>
              <bitOffset>12</bitOffset>
              <bitWidth>2</bitWidth>
            </field>
            <field>
              <name>MEM2MEM</name>
              <bitOffset>14</bitOffset>
              <bitWidth>1</bitWidth>
            </field>
          </fields>
        </register>
        <register>
          <name>CCR3</name>
          <addressOffset>0x30</addressOffset>
          <size>0x20</size>
          <fields>
            <field>
              <name>EN</name>
              <bitOffset>0</bitOffset>
              <bitWidth>1</bitWidth>
            </field>
            <field>
              <name>TCIE</name>
              <bitOffset>1</bitOffset>
              <bitWidth>1</bitWidth>
            </field>
            <field>
              <name>HTIE</name>
              <bitOffset>2</bitOffset>
              <bitWidth>1</bitWidth>
            </field>
            <field>
              <name>TEIE</name>
              <bitOffset>3</bitOffset>
              <bitWidth>1</bitWidth>
            </field>
            <field>
              <name>DIR</name>
              <bitOffset>4</bitOffset>
              <bitWidth>1</bitWidth>
            </field>
            <field>
              <name>CIRC</name>
              <bitOffset>5</bitOffset>
              <bitWidth>1</bitWidth>
            </field>
            <field>
              <name>PINC</name>
              <bitOffset>6</bitOffset>
              <bitWidth>1</bitWidth>
            </field>
            <field>
              <name>MINC</name>
              <bitOffset>7</bitOffset>
              <bitWidth>1</bitWidth>
            </field>
            <field>
              <name>PSIZE</name>
              <bitOffset>8</bitOffset>
              <bitWidth>2</bitWidth>
            </field>
            <field>
              <name>MSIZE</name>
              <bitOffset>10</bitOffset>
              <bitWidth>2</bitWidth>
            </field>
            <field>
              <name>PL</name>
              <bitOffset>12</bitOffset>
              <bitWidth>2</bitWidth>
            </field>
            <field>
              <name>MEM2MEM</name>
              <bitOffset>14</bitOffset>
              <bitWidth>1</bitWidth>
            </field>
          </fields>
        </register>
        <register>
          <name>CNDTR3</name>
          <addressOffset>0x34</addressOffset>
          <size>0x20</size>
          <fields>
            <field>
              <name>NDT</name>
              <bitOffset>0</bitOffset>
              <bitWidth>16</bitWidth>
            </field>
          </fields>
        </register>
        <register>
          <name>CNDTR3</name>
          <addressOffset>0x34</addressOffset>
          <size>0x20</size>
          <fields>
            <field>
              <name>NDT</name>
              <bitOffset>0</bitOffset>
              <bitWidth>16</bitWidth>
            </field>
          </fields>
        </register>
        <register>
          <name>CPAR3</name>
          <addressOffset>0x38</addressOffset>
          <size>0x20</size>
          <fields>
            <field>
              <name>PA</name>
              <bitOffset>0</bitOffset>
              <bitWidth>32</bitWidth>
            </field>
          </fields>
        </register>
        <register>
          <name>CPAR3</name>
          <addressOffset>0x38</addressOffset>
          <size>0x20</size>
          <fields>
            <field>
              <name>PA</name>
              <bitOffset>0</bitOffset>
              <bitWidth>32</bitWidth>
            </field>
          </fields>
        </register>
        <register>
          <name>CMAR3</name>
          <addressOffset>0x3c</addressOffset>
          <size>0x20</size>
          <fields>
            <field>
              <name>MA</name>
              <bitOffset>0</bitOffset>
              <bitWidth>32</bitWidth>
            </field>
          </fields>
        </register>
        <register>
          <name>CMAR3</name>
          <addressOffset>0x3c</addressOffset>
          <size>0x20</size>
          <fields>
            <field>
              <name>MA</name>
              <bitOffset>0</bitOffset>
              <bitWidth>32</bitWidth>
            </field>
          </fields>
        </register>
        <register>
          <name>CCR4</name>
          <addressOffset>0x44</addressOffset>
          <size>0x20</size>
          <fields>
            <field>
              <name>EN</name>
              <bitOffset>0</bitOffset>
              <bitWidth>1</bitWidth>
            </field>
            <field>
              <name>TCIE</name>
              <bitOffset>1</bitOffset>
              <bitWidth>1</bitWidth>
            </field>
            <field>
              <name>HTIE</name>
              <bitOffset>2</bitOffset>
              <bitWidth>1</bitWidth>
            </field>
            <field>
              <name>TEIE</name>
              <bitOffset>3</bitOffset>
              <bitWidth>1</bitWidth>
            </field>
            <field>
              <name>DIR</name>
              <bitOffset>4</bitOffset>
              <bitWidth>1</bitWidth>
            </field>
            <field>
              <name>CIRC</name>
              <bitOffset>5</bitOffset>
              <bitWidth>1</bitWidth>
            </field>
            <field>
              <name>PINC</name>
              <bitOffset>6</bitOffset>
              <bitWidth>1</bitWidth>
            </field>
            <field>
              <name>MINC</name>
              <bitOffset>7</bitOffset>
              <bitWidth>1</bitWidth>
            </field>
            <field>
              <name>PSIZE</name>
              <bitOffset>8</bitOffset>
              <bitWidth>2</bitWidth>
            </field>
            <field>
              <name>MSIZE</name>
              <bitOffset>10</bitOffset>
              <bitWidth>2</bitWidth>
            </field>
            <field>
              <name>PL</name>
              <bitOffset>12</bitOffset>
              <bitWidth>2</bitWidth>
            </field>
            <field>
              <name>MEM2MEM</name>
              <bitOffset>14</bitOffset>
              <bitWidth>1</bitWidth>
            </field>
          </fields>
        </register>
        <register>
          <name>CCR4</name>
          <addressOffset>0x44</addressOffset>
          <size>0x20</size>
          <fields>
            <field>
              <name>EN</name>
              <bitOffset>0</bitOffset>
              <bitWidth>1</bitWidth>
            </field>
            <field>
              <name>TCIE</name>
              <bitOffset>1</bitOffset>
              <bitWidth>1</bitWidth>
            </field>
            <field>
              <name>HTIE</name>
              <bitOffset>2</bitOffset>
              <bitWidth>1</bitWidth>
            </field>
            <field>
              <name>TEIE</name>
              <bitOffset>3</bitOffset>
              <bitWidth>1</bitWidth>
            </field>
            <field>
              <name>DIR</name>
              <bitOffset>4</bitOffset>
              <bitWidth>1</bitWidth>
            </field>
            <field>
              <name>CIRC</name>
              <bitOffset>5</bitOffset>
              <bitWidth>1</bitWidth>
            </field>
            <field>
              <name>PINC</name>
              <bitOffset>6</bitOffset>
              <bitWidth>1</bitWidth>
            </field>
            <field>
              <name>MINC</name>
              <bitOffset>7</bitOffset>
              <bitWidth>1</bitWidth>
            </field>
            <field>
              <name>PSIZE</name>
              <bitOffset>8</bitOffset>
              <bitWidth>2</bitWidth>
            </field>
            <field>
              <name>MSIZE</name>
              <bitOffset>10</bitOffset>
              <bitWidth>2</bitWidth>
            </field>
            <field>
              <name>PL</name>
              <bitOffset>12</bitOffset>
              <bitWidth>2</bitWidth>
            </field>
            <field>
              <name>MEM2MEM</name>
              <bitOffset>14</bitOffset>
              <bitWidth>1</bitWidth>
            </field>
          </fields>
        </register>
        <register>
          <name>CNDTR4</name>
          <addressOffset>0x48</addressOffset>
          <size>0x20</size>
          <fields>
            <field>
              <name>NDT</name>
              <bitOffset>0</bitOffset>
              <bitWidth>16</bitWidth>
            </field>
          </fields>
        </register>
        <register>
          <name>CNDTR4</name>
          <addressOffset>0x48</addressOffset>
          <size>0x20</size>
          <fields>
            <field>
              <name>NDT</name>
              <bitOffset>0</bitOffset>
              <bitWidth>16</bitWidth>
            </field>
          </fields>
        </register>
        <register>
          <name>CPAR4</name>
          <addressOffset>0x4c</addressOffset>
          <size>0x20</size>
          <fields>
            <field>
              <name>PA</name>
              <bitOffset>0</bitOffset>
              <bitWidth>32</bitWidth>
            </field>
          </fields>
        </register>
        <register>
          <name>CPAR4</name>
          <addressOffset>0x4c</addressOffset>
          <size>0x20</size>
          <fields>
            <field>
              <name>PA</name>
              <bitOffset>0</bitOffset>
              <bitWidth>32</bitWidth>
            </field>
          </fields>
        </register>
        <register>
          <name>CMAR4</name>
          <addressOffset>0x50</addressOffset>
          <size>0x20</size>
          <fields>
            <field>
              <name>MA</name>
              <bitOffset>0</bitOffset>
              <bitWidth>32</bitWidth>
            </field>
          </fields>
        </register>
        <register>
          <name>CMAR4</name>
          <addressOffset>0x50</addressOffset>
          <size>0x20</size>
          <fields>
            <field>
              <name>MA</name>
              <bitOffset>0</bitOffset>
              <bitWidth>32</bitWidth>
            </field>
          </fields>
        </register>
        <register>
          <name>CCR5</name>
          <addressOffset>0x58</addressOffset>
          <size>0x20</size>
          <fields>
            <field>
              <name>EN</name>
              <bitOffset>0</bitOffset>
              <bitWidth>1</bitWidth>
            </field>
            <field>
              <name>TCIE</name>
              <bitOffset>1</bitOffset>
              <bitWidth>1</bitWidth>
            </field>
            <field>
              <name>HTIE</name>
              <bitOffset>2</bitOffset>
              <bitWidth>1</bitWidth>
            </field>
            <field>
              <name>TEIE</name>
              <bitOffset>3</bitOffset>
              <bitWidth>1</bitWidth>
            </field>
            <field>
              <name>DIR</name>
              <bitOffset>4</bitOffset>
              <bitWidth>1</bitWidth>
            </field>
            <field>
              <name>CIRC</name>
              <bitOffset>5</bitOffset>
              <bitWidth>1</bitWidth>
            </field>
            <field>
              <name>PINC</name>
              <bitOffset>6</bitOffset>
              <bitWidth>1</bitWidth>
            </field>
            <field>
              <name>MINC</name>
              <bitOffset>7</bitOffset>
              <bitWidth>1</bitWidth>
            </field>
            <field>
              <name>PSIZE</name>
              <bitOffset>8</bitOffset>
              <bitWidth>2</bitWidth>
            </field>
            <field>
              <name>MSIZE</name>
              <bitOffset>10</bitOffset>
              <bitWidth>2</bitWidth>
            </field>
            <field>
              <name>PL</name>
              <bitOffset>12</bitOffset>
              <bitWidth>2</bitWidth>
            </field>
            <field>
              <name>MEM2MEM</name>
              <bitOffset>14</bitOffset>
              <bitWidth>1</bitWidth>
            </field>
          </fields>
        </register>
        <register>
          <name>CCR5</name>
          <addressOffset>0x58</addressOffset>
          <size>0x20</size>
          <fields>
            <field>
              <name>EN</name>
              <bitOffset>0</bitOffset>
              <bitWidth>1</bitWidth>
            </field>
            <field>
              <name>TCIE</name>
              <bitOffset>1</bitOffset>
              <bitWidth>1</bitWidth>
            </field>
            <field>
              <name>HTIE</name>
              <bitOffset>2</bitOffset>
              <bitWidth>1</bitWidth>
            </field>
            <field>
              <name>TEIE</name>
              <bitOffset>3</bitOffset>
              <bitWidth>1</bitWidth>
            </field>
            <field>
              <name>DIR</name>
              <bitOffset>4</bitOffset>
              <bitWidth>1</bitWidth>
            </field>
            <field>
              <name>CIRC</name>
              <bitOffset>5</bitOffset>
              <bitWidth>1</bitWidth>
            </field>
            <field>
              <name>PINC</name>
              <bitOffset>6</bitOffset>
              <bitWidth>1</bitWidth>
            </field>
            <field>
              <name>MINC</name>
              <bitOffset>7</bitOffset>
              <bitWidth>1</bitWidth>
            </field>
            <field>
              <name>PSIZE</name>
              <bitOffset>8</bitOffset>
              <bitWidth>2</bitWidth>
            </field>
            <field>
              <name>MSIZE</name>
              <bitOffset>10</bitOffset>
              <bitWidth>2</bitWidth>
            </field>
            <field>
              <name>PL</name>
              <bitOffset>12</bitOffset>
              <bitWidth>2</bitWidth>
            </field>
            <field>
              <name>MEM2MEM</name>
              <bitOffset>14</bitOffset>
              <bitWidth>1</bitWidth>
            </field>
          </fields>
        </register>
        <register>
          <name>CNDTR5</name>
          <addressOffset>0x5c</addressOffset>
          <size>0x20</size>
          <fields>
            <field>
              <name>NDT</name>
              <bitOffset>0</bitOffset>
              <bitWidth>16</bitWidth>
            </field>
          </fields>
        </register>
        <register>
          <name>CNDTR5</name>
          <addressOffset>0x5c</addressOffset>
          <size>0x20</size>
          <fields>
            <field>
              <name>NDT</name>
              <bitOffset>0</bitOffset>
              <bitWidth>16</bitWidth>
            </field>
          </fields>
        </register>
        <register>
          <name>CPAR5</name>
          <addressOffset>0x60</addressOffset>
          <size>0x20</size>
          <fields>
            <field>
              <name>PA</name>
              <bitOffset>0</bitOffset>
              <bitWidth>32</bitWidth>
            </field>
          </fields>
        </register>
        <register>
          <name>CPAR5</name>
          <addressOffset>0x60</addressOffset>
          <size>0x20</size>
          <fields>
            <field>
              <name>PA</name>
              <bitOffset>0</bitOffset>
              <bitWidth>32</bitWidth>
            </field>
          </fields>
        </register>
        <register>
          <name>CMAR5</name>
          <addressOffset>0x64</addressOffset>
          <size>0x20</size>
          <fields>
            <field>
              <name>MA</name>
              <bitOffset>0</bitOffset>
              <bitWidth>32</bitWidth>
            </field>
          </fields>
        </register>
        <register>
          <name>CMAR5</name>
          <addressOffset>0x64</addressOffset>
          <size>0x20</size>
          <fields>
            <field>
              <name>MA</name>
              <bitOffset>0</bitOffset>
              <bitWidth>32</bitWidth>
            </field>
          </fields>
        </register>
        <register>
          <name>CCR6</name>
          <addressOffset>0x6c</addressOffset>
          <size>0x20</size>
          <fields>
            <field>
              <name>EN</name>
              <bitOffset>0</bitOffset>
              <bitWidth>1</bitWidth>
            </field>
            <field>
              <name>TCIE</name>
              <bitOffset>1</bitOffset>
              <bitWidth>1</bitWidth>
            </field>
            <field>
              <name>HTIE</name>
              <bitOffset>2</bitOffset>
              <bitWidth>1</bitWidth>
            </field>
            <field>
              <name>TEIE</name>
              <bitOffset>3</bitOffset>
              <bitWidth>1</bitWidth>
            </field>
            <field>
              <name>DIR</name>
              <bitOffset>4</bitOffset>
              <bitWidth>1</bitWidth>
            </field>
            <field>
              <name>CIRC</name>
              <bitOffset>5</bitOffset>
              <bitWidth>1</bitWidth>
            </field>
            <field>
              <name>PINC</name>
              <bitOffset>6</bitOffset>
              <bitWidth>1</bitWidth>
            </field>
            <field>
              <name>MINC</name>
              <bitOffset>7</bitOffset>
              <bitWidth>1</bitWidth>
            </field>
            <field>
              <name>PSIZE</name>
              <bitOffset>8</bitOffset>
              <bitWidth>2</bitWidth>
            </field>
            <field>
              <name>MSIZE</name>
              <bitOffset>10</bitOffset>
              <bitWidth>2</bitWidth>
            </field>
            <field>
              <name>PL</name>
              <bitOffset>12</bitOffset>
              <bitWidth>2</bitWidth>
            </field>
            <field>
              <name>MEM2MEM</name>
              <bitOffset>14</bitOffset>
              <bitWidth>1</bitWidth>
            </field>
          </fields>
        </register>
        <register>
          <name>CCR6</name>
          <addressOffset>0x6c</addressOffset>
          <size>0x20</size>
          <fields>
            <field>
              <name>EN</name>
              <bitOffset>0</bitOffset>
              <bitWidth>1</bitWidth>
            </field>
            <field>
              <name>TCIE</name>
              <bitOffset>1</bitOffset>
              <bitWidth>1</bitWidth>
            </field>
            <field>
              <name>HTIE</name>
              <bitOffset>2</bitOffset>
              <bitWidth>1</bitWidth>
            </field>
            <field>
              <name>TEIE</name>
              <bitOffset>3</bitOffset>
              <bitWidth>1</bitWidth>
            </field>
            <field>
              <name>DIR</name>
              <bitOffset>4</bitOffset>
              <bitWidth>1</bitWidth>
            </field>
            <field>
              <name>CIRC</name>
              <bitOffset>5</bitOffset>
              <bitWidth>1</bitWidth>
            </field>
            <field>
              <name>PINC</name>
              <bitOffset>6</bitOffset>
              <bitWidth>1</bitWidth>
            </field>
            <field>
              <name>MINC</name>
              <bitOffset>7</bitOffset>
              <bitWidth>1</bitWidth>
            </field>
            <field>
              <name>PSIZE</name>
              <bitOffset>8</bitOffset>
              <bitWidth>2</bitWidth>
            </field>
            <field>
              <name>MSIZE</name>
              <bitOffset>10</bitOffset>
              <bitWidth>2</bitWidth>
            </field>
            <field>
              <name>PL</name>
              <bitOffset>12</bitOffset>
              <bitWidth>2</bitWidth>
            </field>
            <field>
              <name>MEM2MEM</name>
              <bitOffset>14</bitOffset>
              <bitWidth>1</bitWidth>
            </field>
          </fields>
        </register>
        <register>
          <name>CNDTR6</name>
          <addressOffset>0x70</addressOffset>
          <size>0x20</size>
          <fields>
            <field>
              <name>NDT</name>
              <bitOffset>0</bitOffset>
              <bitWidth>16</bitWidth>
            </field>
          </fields>
        </register>
        <register>
          <name>CNDTR6</name>
          <addressOffset>0x70</addressOffset>
          <size>0x20</size>
          <fields>
            <field>
              <name>NDT</name>
              <bitOffset>0</bitOffset>
              <bitWidth>16</bitWidth>
            </field>
          </fields>
        </register>
        <register>
          <name>CPAR6</name>
          <addressOffset>0x74</addressOffset>
          <size>0x20</size>
          <fields>
            <field>
              <name>PA</name>
              <bitOffset>0</bitOffset>
              <bitWidth>32</bitWidth>
            </field>
          </fields>
        </register>
        <register>
          <name>CPAR6</name>
          <addressOffset>0x74</addressOffset>
          <size>0x20</size>
          <fields>
            <field>
              <name>PA</name>
              <bitOffset>0</bitOffset>
              <bitWidth>32</bitWidth>
            </field>
          </fields>
        </register>
        <register>
          <name>CMAR6</name>
          <addressOffset>0x78</addressOffset>
          <size>0x20</size>
          <fields>
            <field>
              <name>MA</name>
              <bitOffset>0</bitOffset>
              <bitWidth>32</bitWidth>
            </field>
          </fields>
        </register>
        <register>
          <name>CMAR6</name>
          <addressOffset>0x78</addressOffset>
          <size>0x20</size>
          <fields>
            <field>
              <name>MA</name>
              <bitOffset>0</bitOffset>
              <bitWidth>32</bitWidth>
            </field>
          </fields>
        </register>
        <register>
          <name>CCR7</name>
          <addressOffset>0x80</addressOffset>
          <size>0x20</size>
          <fields>
            <field>
              <name>EN</name>
              <bitOffset>0</bitOffset>
              <bitWidth>1</bitWidth>
            </field>
            <field>
              <name>TCIE</name>
              <bitOffset>1</bitOffset>
              <bitWidth>1</bitWidth>
            </field>
            <field>
              <name>HTIE</name>
              <bitOffset>2</bitOffset>
              <bitWidth>1</bitWidth>
            </field>
            <field>
              <name>TEIE</name>
              <bitOffset>3</bitOffset>
              <bitWidth>1</bitWidth>
            </field>
            <field>
              <name>DIR</name>
              <bitOffset>4</bitOffset>
              <bitWidth>1</bitWidth>
            </field>
            <field>
              <name>CIRC</name>
              <bitOffset>5</bitOffset>
              <bitWidth>1</bitWidth>
            </field>
            <field>
              <name>PINC</name>
              <bitOffset>6</bitOffset>
              <bitWidth>1</bitWidth>
            </field>
            <field>
              <name>MINC</name>
              <bitOffset>7</bitOffset>
              <bitWidth>1</bitWidth>
            </field>
            <field>
              <name>PSIZE</name>
              <bitOffset>8</bitOffset>
              <bitWidth>2</bitWidth>
            </field>
            <field>
              <name>MSIZE</name>
              <bitOffset>10</bitOffset>
              <bitWidth>2</bitWidth>
            </field>
            <field>
              <name>PL</name>
              <bitOffset>12</bitOffset>
              <bitWidth>2</bitWidth>
            </field>
            <field>
              <name>MEM2MEM</name>
              <bitOffset>14</bitOffset>
              <bitWidth>1</bitWidth>
            </field>
          </fields>
        </register>
        <register>
          <name>CCR7</name>
          <addressOffset>0x80</addressOffset>
          <size>0x20</size>
          <fields>
            <field>
              <name>EN</name>
              <bitOffset>0</bitOffset>
              <bitWidth>1</bitWidth>
            </field>
            <field>
              <name>TCIE</name>
              <bitOffset>1</bitOffset>
              <bitWidth>1</bitWidth>
            </field>
            <field>
              <name>HTIE</name>
              <bitOffset>2</bitOffset>
              <bitWidth>1</bitWidth>
            </field>
            <field>
              <name>TEIE</name>
              <bitOffset>3</bitOffset>
              <bitWidth>1</bitWidth>
            </field>
            <field>
              <name>DIR</name>
              <bitOffset>4</bitOffset>
              <bitWidth>1</bitWidth>
            </field>
            <field>
              <name>CIRC</name>
              <bitOffset>5</bitOffset>
              <bitWidth>1</bitWidth>
            </field>
            <field>
              <name>PINC</name>
              <bitOffset>6</bitOffset>
              <bitWidth>1</bitWidth>
            </field>
            <field>
              <name>MINC</name>
              <bitOffset>7</bitOffset>
              <bitWidth>1</bitWidth>
            </field>
            <field>
              <name>PSIZE</name>
              <bitOffset>8</bitOffset>
              <bitWidth>2</bitWidth>
            </field>
            <field>
              <name>MSIZE</name>
              <bitOffset>10</bitOffset>
              <bitWidth>2</bitWidth>
            </field>
            <field>
              <name>PL</name>
              <bitOffset>12</bitOffset>
              <bitWidth>2</bitWidth>
            </field>
            <field>
              <name>MEM2MEM</name>
              <bitOffset>14</bitOffset>
              <bitWidth>1</bitWidth>
            </field>
          </fields>
        </register>
        <register>
          <name>CNDTR7</name>
          <addressOffset>0x84</addressOffset>
          <size>0x20</size>
          <fields>
            <field>
              <name>NDT</name>
              <bitOffset>0</bitOffset>
              <bitWidth>16</bitWidth>
            </field>
          </fields>
        </register>
        <register>
          <name>CNDTR7</name>
          <addressOffset>0x84</addressOffset>
          <size>0x20</size>
          <fields>
            <field>
              <name>NDT</name>
              <bitOffset>0</bitOffset>
              <bitWidth>16</bitWidth>
            </field>
          </fields>
        </register>
        <register>
          <name>CPAR7</name>
          <addressOffset>0x88</addressOffset>
          <size>0x20</size>
          <fields>
            <field>
              <name>PA</name>
              <bitOffset>0</bitOffset>
              <bitWidth>32</bitWidth>
            </field>
          </fields>
        </register>
        <register>
          <name>CPAR7</name>
          <addressOffset>0x88</addressOffset>
          <size>0x20</size>
          <fields>
            <field>
              <name>PA</name>
              <bitOffset>0</bitOffset>
              <bitWidth>32</bitWidth>
            </field>
          </fields>
        </register>
        <register>
          <name>CMAR7</name>
          <addressOffset>0x8c</addressOffset>
          <size>0x20</size>
          <fields>
            <field>
              <name>MA</name>
              <bitOffset>0</bitOffset>
              <bitWidth>32</bitWidth>
            </field>
          </fields>
        </register>
        <register>
          <name>CMAR7</name>
          <addressOffset>0x8c</addressOffset>
          <size>0x20</size>
          <fields>
            <field>
              <name>MA</name>
              <bitOffset>0</bitOffset>
              <bitWidth>32</bitWidth>
            </field>
          </fields>
        </register>
        <register>
          <name>CCR8</name>
          <addressOffset>0x94</addressOffset>
          <size>0x20</size>
          <fields>
            <field>
              <name>EN</name>
              <bitOffset>0</bitOffset>
              <bitWidth>1</bitWidth>
            </field>
            <field>
              <name>TCIE</name>
              <bitOffset>1</bitOffset>
              <bitWidth>1</bitWidth>
            </field>
            <field>
              <name>HTIE</name>
              <bitOffset>2</bitOffset>
              <bitWidth>1</bitWidth>
            </field>
            <field>
              <name>TEIE</name>
              <bitOffset>3</bitOffset>
              <bitWidth>1</bitWidth>
            </field>
            <field>
              <name>DIR</name>
              <bitOffset>4</bitOffset>
              <bitWidth>1</bitWidth>
            </field>
            <field>
              <name>CIRC</name>
              <bitOffset>5</bitOffset>
              <bitWidth>1</bitWidth>
            </field>
            <field>
              <name>PINC</name>
              <bitOffset>6</bitOffset>
              <bitWidth>1</bitWidth>
            </field>
            <field>
              <name>MINC</name>
              <bitOffset>7</bitOffset>
              <bitWidth>1</bitWidth>
            </field>
            <field>
              <name>PSIZE</name>
              <bitOffset>8</bitOffset>
              <bitWidth>2</bitWidth>
            </field>
            <field>
              <name>MSIZE</name>
              <bitOffset>10</bitOffset>
              <bitWidth>2</bitWidth>
            </field>
            <field>
              <name>PL</name>
              <bitOffset>12</bitOffset>
              <bitWidth>2</bitWidth>
            </field>
            <field>
              <name>MEM2MEM</name>
              <bitOffset>14</bitOffset>
              <bitWidth>1</bitWidth>
            </field>
          </fields>
        </register>
        <register>
          <name>CCR8</name>
          <addressOffset>0x94</addressOffset>
          <size>0x20</size>
          <fields>
            <field>
              <name>EN</name>
              <bitOffset>0</bitOffset>
              <bitWidth>1</bitWidth>
            </field>
            <field>
              <name>TCIE</name>
              <bitOffset>1</bitOffset>
              <bitWidth>1</bitWidth>
            </field>
            <field>
              <name>HTIE</name>
              <bitOffset>2</bitOffset>
              <bitWidth>1</bitWidth>
            </field>
            <field>
              <name>TEIE</name>
              <bitOffset>3</bitOffset>
              <bitWidth>1</bitWidth>
            </field>
            <field>
              <name>DIR</name>
              <bitOffset>4</bitOffset>
              <bitWidth>1</bitWidth>
            </field>
            <field>
              <name>CIRC</name>
              <bitOffset>5</bitOffset>
              <bitWidth>1</bitWidth>
            </field>
            <field>
              <name>PINC</name>
              <bitOffset>6</bitOffset>
              <bitWidth>1</bitWidth>
            </field>
            <field>
              <name>MINC</name>
              <bitOffset>7</bitOffset>
              <bitWidth>1</bitWidth>
            </field>
            <field>
              <name>PSIZE</name>
              <bitOffset>8</bitOffset>
              <bitWidth>2</bitWidth>
            </field>
            <field>
              <name>MSIZE</name>
              <bitOffset>10</bitOffset>
              <bitWidth>2</bitWidth>
            </field>
            <field>
              <name>PL</name>
              <bitOffset>12</bitOffset>
              <bitWidth>2</bitWidth>
            </field>
            <field>
              <name>MEM2MEM</name>
              <bitOffset>14</bitOffset>
              <bitWidth>1</bitWidth>
            </field>
          </fields>
        </register>
        <register>
          <name>CNDTR8</name>
          <addressOffset>0x98</addressOffset>
          <size>0x20</size>
          <fields>
            <field>
              <name>NDT</name>
              <bitOffset>0</bitOffset>
              <bitWidth>16</bitWidth>
            </field>
          </fields>
        </register>
        <register>
          <name>CNDTR8</name>
          <addressOffset>0x98</addressOffset>
          <size>0x20</size>
          <fields>
            <field>
              <name>NDT</name>
              <bitOffset>0</bitOffset>
              <bitWidth>16</bitWidth>
            </field>
          </fields>
        </register>
        <register>
          <name>CPAR8</name>
          <addressOffset>0x9c</addressOffset>
          <size>0x20</size>
          <fields>
            <field>
              <name>PA</name>
              <bitOffset>0</bitOffset>
              <bitWidth>32</bitWidth>
            </field>
          </fields>
        </register>
        <register>
          <name>CPAR8</name>
          <addressOffset>0x9c</addressOffset>
          <size>0x20</size>
          <fields>
            <field>
              <name>PA</name>
              <bitOffset>0</bitOffset>
              <bitWidth>32</bitWidth>
            </field>
          </fields>
        </register>
        <register>
          <name>CMAR8</name>
          <addressOffset>0xa0</addressOffset>
          <size>0x20</size>
          <fields>
            <field>
              <name>MA</name>
              <bitOffset>0</bitOffset>
              <bitWidth>32</bitWidth>
            </field>
          </fields>
        </register>
        <register>
          <name>CMAR8</name>
          <addressOffset>0xa0</addressOffset>
          <size>0x20</size>
          <fields>
            <field>
              <name>MA</name>
              <bitOffset>0</bitOffset>
              <bitWidth>32</bitWidth>
            </field>
          </fields>
        </register>
      </registers>
    </peripheral>
    <peripheral>
      <name>DMAMUX1</name>
      <baseAddress>0x40020800</baseAddress>
      <registers>
        <register>
          <name>CCR0</name>
          <addressOffset>0x0</addressOffset>
          <size>0x20</size>
        </register>
        <register>
          <name>CCR1</name>
          <addressOffset>0x4</addressOffset>
          <size>0x20</size>
        </register>
        <register>
          <name>CCR2</name>
          <addressOffset>0x8</addressOffset>
          <size>0x20</size>
        </register>
        <register>
          <name>CCR3</name>
          <addressOffset>0xc</addressOffset>
          <size>0x20</size>
        </register>
        <register>
          <name>CCR4</name>
          <addressOffset>0x10</addressOffset>
          <size>0x20</size>
        </register>
        <register>
          <name>CCR5</name>
          <addressOffset>0x14</addressOffset>
          <size>0x20</size>
        </register>
        <register>
          <name>CCR6</name>
          <addressOffset>0x18</addressOffset>
          <size>0x20</size>
        </register>
        <register>
          <name>CCR7</name>
          <addressOffset>0x1c</addressOffset>
          <size>0x20</size>
        </register>
        <register>
          <name>CCR8</name>
          <addressOffset>0x20</addressOffset>
          <size>0x20</size>
        </register>
        <register>
          <name>CCR9</name>
          <addressOffset>0x24</addressOffset>
          <size>0x20</size>
        </register>
        <register>
          <name>CCR0</name>
          <addressOffset>0x28</addressOffset>
          <size>0x20</size>
        </register>
        <register>
          <name>CCR1</name>
          <addressOffset>0x2c</addressOffset>
          <size>0x20</size>
        </register>
        <register>
          <name>CCR2</name>
          <addressOffset>0x30</addressOffset>
          <size>0x20</size>
        </register>
        <register>
          <name>CCR3</name>
          <addressOffset>0x34</addressOffset>
          <size>0x20</size>
        </register>
        <register>
          <name>CCR4</name>
          <addressOffset>0x38</addressOffset>
          <size>0x20</size>
        </register>
        <register>
          <name>CCR5</name>
          <addressOffset>0x3c</addressOffset>
          <size>0x20</size>
        </register>
        <register>
          <name>CCRs</name>
          <addressOffset>0x80</addressOffset>
          <size>0x20</size>
        </register>
        <register>
          <name>CCR0</name>
          <addressOffset>0x100</addressOffset>
          <size>0x20</size>
        </register>
        <register>
          <name>CCR1</name>
          <addressOffset>0x104</addressOffset>
          <size>0x20</size>
        </register>
        <register>
          <name>CCR2</name>
          <addressOffset>0x108</addressOffset>
          <size>0x20</size>
        </register>
        <register>
          <name>CCR3</name>
          <addressOffset>0x10c</addressOffset>
          <size>0x20</size>
        </register>
        <register>
          <name>CCRs</name>
          <addressOffset>0x140</addressOffset>
          <size>0x20</size>
        </register>
      </registers>
    </peripheral>
    <peripheral>
      <name>CORDIC</name>
      <baseAddress>0x40020c00</baseAddress>
      <registers>
        <register>
          <name>CSR</name>
          <addressOffset>0x0</addressOffset>
          <size>0x20</size>
          <fields>
            <field>
              <name>FUNC</name>
              <bitOffset>0</bitOffset>
              <bitWidth>4</bitWidth>
            </field>
            <field>
              <name>PRECISION</name>
              <bitOffset>4</bitOffset>
              <bitWidth>4</bitWidth>
            </field>
            <field>
              <name>SCALE</name>
              <bitOffset>8</bitOffset>
              <bitWidth>3</bitWidth>
            </field>
            <field>
              <name>IEN</name>
              <bitOffset>16</bitOffset>
              <bitWidth>1</bitWidth>
            </field>
            <field>
              <name>DMAREN</name>
              <bitOffset>17</bitOffset>
              <bitWidth>1</bitWidth>
            </field>
            <field>
              <name>DMAWEN</name>
              <bitOffset>18</bitOffset>
              <bitWidth>1</bitWidth>
            </field>
            <field>
              <name>NRES</name>
              <bitOffset>19</bitOffset>
              <bitWidth>1</bitWidth>
            </field>
            <field>
              <name>NARGS</name>
              <bitOffset>20</bitOffset>
              <bitWidth>1</bitWidth>
            </field>
            <field>
              <name>RESSIZE</name>
              <bitOffset>21</bitOffset>
              <bitWidth>1</bitWidth>
            </field>
            <field>
              <name>ARGSIZE</name>
              <bitOffset>22</bitOffset>
              <bitWidth>1</bitWidth>
            </field>
            <field>
              <name>RRDY</name>
              <bitOffset>31</bitOffset>
              <bitWidth>1</bitWidth>
            </field>
          </fields>
        </register>
        <register>
          <name>WDATA</name>
          <addressOffset>0x4</addressOffset>
          <size>0x20</size>
          <fields>
            <field>
              <name>ARG</name>
              <bitOffset>0</bitOffset>
              <bitWidth>32</bitWidth>
            </field>
          </fields>
        </register>
        <register>
          <name>RDATA</name>
          <addressOffset>0x8</addressOffset>
          <size>0x20</size>
          <fields>
            <field>
              <name>RES</name>
              <bitOffset>0</bitOffset>
              <bitWidth>32</bitWidth>
            </field>
          </fields>
        </register>
      </registers>
    </peripheral>
    <peripheral>
      <name>RCC</name>
      <baseAddress>0x40021000</baseAddress>
      <registers>
        <register>
          <name>CR</name>
          <addressOffset>0x0</addressOffset>
          <size>0x20</size>
          <fields>
            <field>
              <name>HSION</name>
              <bitOffset>8</bitOffset>
              <bitWidth>1</bitWidth>
            </field>
            <field>
              <name>HSIKERON</name>
              <bitOffset>9</bitOffset>
              <bitWidth>1</bitWidth>
            </field>
            <field>
              <name>HSIRDY</name>
              <bitOffset>10</bitOffset>
              <bitWidth>1</bitWidth>
            </field>
            <field>
              <name>HSEON</name>
              <bitOffset>16</bitOffset>
              <bitWidth>1</bitWidth>
            </field>
            <field>
              <name>HSERDY</name>
              <bitOffset>17</bitOffset>
              <bitWidth>1</bitWidth>
            </field>
            <field>
              <name>HSEBYP</name>
              <bitOffset>18</bitOffset>
              <bitWidth>1</bitWidth>
            </field>
            <field>
              <name>CSSON</name>
              <bitOffset>19</bitOffset>
              <bitWidth>1</bitWidth>
            </field>
            <field>
              <name>PLLON</name>
              <bitOffset>24</bitOffset>
              <bitWidth>1</bitWidth>
            </field>
            <field>
              <name>PLLRDY</name>
              <bitOffset>25</bitOffset>
              <bitWidth>1</bitWidth>
            </field>
          </fields>
        </register>
        <register>
          <name>ICSCR</name>
          <addressOffset>0x4</addressOffset>
          <size>0x20</size>
          <fields>
            <field>
              <name>HSICAL</name>
              <bitOffset>16</bitOffset>
              <bitWidth>8</bitWidth>
            </field>
            <field>
              <name>HSITRIM</name>
              <bitOffset>24</bitOffset>
              <bitWidth>7</bitWidth>
            </field>
          </fields>
        </register>
        <register>
          <name>CFGR</name>
          <addressOffset>0x8</addressOffset>
          <size>0x20</size>
          <fields>
            <field>
              <name>SW</name>
              <bitOffset>0</bitOffset>
              <bitWidth>2</bitWidth>
            </field>
            <field>
              <name>SWS</name>
              <bitOffset>2</bitOffset>
              <bitWidth>2</bitWidth>
            </field>
            <field>
              <name>HPRE</name>
              <bitOffset>4</bitOffset>
              <bitWidth>4</bitWidth>
            </field>
            <field>
              <name>PPRE1</name>
              <bitOffset>8</bitOffset>
              <bitWidth>3</bitWidth>
            </field>
            <field>
              <name>PPRE2</name>
              <bitOffset>11</bitOffset>
              <bitWidth>3</bitWidth>
            </field>
            <field>
              <name>MCOSEL</name>
              <bitOffset>24</bitOffset>
              <bitWidth>4</bitWidth>
            </field>
            <field>
              <name>MCOPRE</name>
              <bitOffset>28</bitOffset>
              <bitWidth>3</bitWidth>
            </field>
          </fields>
        </register>
        <register>
          <name>PLLCFGR</name>
          <addressOffset>0xc</addressOffset>
          <size>0x20</size>
          <fields>
            <field>
              <name>PLLSRC_HSE</name>
              <bitOffset>0</bitOffset>
              <bitWidth>2</bitWidth>
            </field>
            <field>
              <name>PLLSRC_HSI</name>
              <bitOffset>1</bitOffset>
              <bitWidth>1</bitWidth>
            </field>
            <field>
              <name>PLLM</name>
              <bitOffset>4</bitOffset>
              <bitWidth>4</bitWidth>
            </field>
            <field>
              <name>PLLN</name>
              <bitOffset>8</bitOffset>
              <bitWidth>7</bitWidth>
            </field>
            <field>
              <name>PLLPEN</name>
              <bitOffset>16</bitOffset>
              <bitWidth>1</bitWidth>
            </field>
            <field>
              <name>PLLP</name>
              <bitOffset>17</bitOffset>
              <bitWidth>1</bitWidth>
            </field>
            <field>
              <name>PLLQEN</name>
              <bitOffset>20</bitOffset>
              <bitWidth>1</bitWidth>
            </field>
            <field>
              <name>PLLQ</name>
              <bitOffset>21</bitOffset>
              <bitWidth>2</bitWidth>
            </field>
            <field>
              <name>PLLREN</name>
              <bitOffset>24</bitOffset>
              <bitWidth>1</bitWidth>
            </field>
            <field>
              <name>PLLR</name>
              <bitOffset>25</bitOffset>
              <bitWidth>2</bitWidth>
            </field>
            <field>
              <name>PLLPDIV</name>
              <bitOffset>27</bitOffset>
              <bitWidth>5</bitWidth>
            </field>
          </fields>
        </register>
        <register>
          <name>CIER</name>
          <addressOffset>0x18</addressOffset>
          <size>0x20</size>
          <fields>
            <field>
              <name>LSIRDYIE</name>
              <bitOffset>0</bitOffset>
              <bitWidth>1</bitWidth>
            </field>
            <field>
              <name>LSERDYIE</name>
              <bitOffset>1</bitOffset>
              <bitWidth>1</bitWidth>
            </field>
            <field>
              <name>HSIRDYIE</name>
              <bitOffset>3</bitOffset>
              <bitWidth>1</bitWidth>
            </field>
            <field>
              <name>HSERDYIE</name>
              <bitOffset>4</bitOffset>
              <bitWidth>1</bitWidth>
            </field>
            <field>
              <name>PLLRDYIE</name>
              <bitOffset>5</bitOffset>
              <bitWidth>1</bitWidth>
            </field>
            <field>
              <name>LSECSSIE</name>
              <bitOffset>9</bitOffset>
              <bitWidth>1</bitWidth>
            </field>
            <field>
              <name>HSI48RDYIE</name>
              <bitOffset>10</bitOffset>
              <bitWidth>1</bitWidth>
            </field>
          </fields>
        </register>
        <register>
          <name>CIFR</name>
          <addressOffset>0x1c</addressOffset>
          <size>0x20</size>
          <fields>
            <field>
              <name>LSIRDYF</name>
              <bitOffset>0</bitOffset>
              <bitWidth>1</bitWidth>
            </field>
            <field>
              <name>LSERDYF</name>
              <bitOffset>1</bitOffset>
              <bitWidth>1</bitWidth>
            </field>
            <field>
              <name>HSIRDYF</name>
              <bitOffset>3</bitOffset>
              <bitWidth>1</bitWidth>
            </field>
            <field>
              <name>HSERDYF</name>
              <bitOffset>4</bitOffset>
              <bitWidth>1</bitWidth>
            </field>
            <field>
              <name>PLLRDYF</name>
              <bitOffset>5</bitOffset>
              <bitWidth>1</bitWidth>
            </field>
            <field>
              <name>CSSF</name>
              <bitOffset>8</bitOffset>
              <bitWidth>1</bitWidth>
            </field>
            <field>
              <name>LSECSSF</name>
              <bitOffset>9</bitOffset>
              <bitWidth>1</bitWidth>
            </field>
            <field>
              <name>HSI48RDYF</name>
              <bitOffset>10</bitOffset>
              <bitWidth>1</bitWidth>
            </field>
          </fields>
        </register>
        <register>
          <name>CICR</name>
          <addressOffset>0x20</addressOffset>
          <size>0x20</size>
          <fields>
            <field>
              <name>LSIRDYC</name>
              <bitOffset>0</bitOffset>
              <bitWidth>1</bitWidth>
            </field>
            <field>
              <name>LSERDYC</name>
              <bitOffset>1</bitOffset>
              <bitWidth>1</bitWidth>
            </field>
            <field>
              <name>HSIRDYC</name>
              <bitOffset>3</bitOffset>
              <bitWidth>1</bitWidth>
            </field>
            <field>
              <name>HSERDYC</name>
              <bitOffset>4</bitOffset>
              <bitWidth>1</bitWidth>
            </field>
            <field>
              <name>PLLRDYC</name>
              <bitOffset>5</bitOffset>
              <bitWidth>1</bitWidth>
            </field>
            <field>
              <name>CSSC</name>
              <bitOffset>8</bitOffset>
              <bitWidth>1</bitWidth>
            </field>
            <field>
              <name>LSECSSC</name>
              <bitOffset>9</bitOffset>
              <bitWidth>1</bitWidth>
            </field>
            <field>
              <name>HSI48RDYC</name>
              <bitOffset>10</bitOffset>
              <bitWidth>1</bitWidth>
            </field>
          </fields>
        </register>
        <register>
          <name>AHB1RSTR</name>
          <addressOffset>0x28</addressOffset>
          <size>0x20</size>
          <fields>
            <field>
              <name>DMA1RST</name>
              <bitOffset>0</bitOffset>
              <bitWidth>1</bitWidth>
            </field>
            <field>
              <name>DMA2RST</name>
              <bitOffset>1</bitOffset>
              <bitWidth>1</bitWidth>
            </field>
            <field>
              <name>DMAMUX1RST</name>
              <bitOffset>2</bitOffset>
              <bitWidth>1</bitWidth>
            </field>
            <field>
              <name>CORDICRST</name>
              <bitOffset>3</bitOffset>
              <bitWidth>1</bitWidth>
            </field>
            <field>
              <name>FMACRST</name>
              <bitOffset>4</bitOffset>
              <bitWidth>1</bitWidth>
            </field>
            <field>
              <name>FLASHRST</name>
              <bitOffset>8</bitOffset>
              <bitWidth>1</bitWidth>
            </field>
            <field>
              <name>CRCRST</name>
              <bitOffset>12</bitOffset>
              <bitWidth>1</bitWidth>
            </field>
          </fields>
        </register>
        <register>
          <name>AHB2RSTR</name>
          <addressOffset>0x2c</addressOffset>
          <size>0x20</size>
          <fields>
            <field>
              <name>GPIOARST</name>
              <bitOffset>0</bitOffset>
              <bitWidth>1</bitWidth>
            </field>
            <field>
              <name>GPIOBRST</name>
              <bitOffset>1</bitOffset>
              <bitWidth>1</bitWidth>
            </field>
            <field>
              <name>GPIOCRST</name>
              <bitOffset>2</bitOffset>
              <bitWidth>1</bitWidth>
            </field>
            <field>
              <name>GPIODRST</name>
              <bitOffset>3</bitOffset>
              <bitWidth>1</bitWidth>
            </field>
            <field>
              <name>GPIOERST</name>
              <bitOffset>4</bitOffset>
              <bitWidth>1</bitWidth>
            </field>
            <field>
              <name>GPIOFRST</name>
              <bitOffset>5</bitOffset>
              <bitWidth>1</bitWidth>
            </field>
            <field>
              <name>GPIOGRST</name>
              <bitOffset>6</bitOffset>
              <bitWidth>1</bitWidth>
            </field>
            <field>
              <name>ADC12RST</name>
              <bitOffset>13</bitOffset>
              <bitWidth>1</bitWidth>
            </field>
            <field>
              <name>ADC345RST</name>
              <bitOffset>14</bitOffset>
              <bitWidth>1</bitWidth>
            </field>
            <field>
              <name>DAC1RST</name>
              <bitOffset>16</bitOffset>
              <bitWidth>1</bitWidth>
            </field>
            <field>
              <name>DAC3RST</name>
              <bitOffset>18</bitOffset>
              <bitWidth>1</bitWidth>
            </field>
            <field>
              <name>RNGRST</name>
              <bitOffset>26</bitOffset>
              <bitWidth>1</bitWidth>
            </field>
          </fields>
        </register>
        <register>
          <name>AHB3RSTR</name>
          <addressOffset>0x30</addressOffset>
          <size>0x20</size>
          <fields>
            <field>
              <name>QSPIRST</name>
              <bitOffset>8</bitOffset>
              <bitWidth>1</bitWidth>
            </field>
          </fields>
        </register>
        <register>
          <name>APB1RSTR1</name>
          <addressOffset>0x38</addressOffset>
          <size>0x20</size>
          <fields>
            <field>
              <name>TIM2RST</name>
              <bitOffset>0</bitOffset>
              <bitWidth>1</bitWidth>
            </field>
            <field>
              <name>TIM3RST</name>
              <bitOffset>1</bitOffset>
              <bitWidth>1</bitWidth>
            </field>
            <field>
              <name>TIM4RST</name>
              <bitOffset>2</bitOffset>
              <bitWidth>1</bitWidth>
            </field>
            <field>
              <name>TIM6RST</name>
              <bitOffset>4</bitOffset>
              <bitWidth>1</bitWidth>
            </field>
            <field>
              <name>TIM7RST</name>
              <bitOffset>5</bitOffset>
              <bitWidth>1</bitWidth>
            </field>
            <field>
              <name>CRSRST</name>
              <bitOffset>8</bitOffset>
              <bitWidth>1</bitWidth>
            </field>
            <field>
              <name>SPI2RST</name>
              <bitOffset>14</bitOffset>
              <bitWidth>1</bitWidth>
            </field>
            <field>
              <name>SPI3RST</name>
              <bitOffset>15</bitOffset>
              <bitWidth>1</bitWidth>
            </field>
            <field>
              <name>USART2RST</name>
              <bitOffset>17</bitOffset>
              <bitWidth>1</bitWidth>
            </field>
            <field>
              <name>USART3RST</name>
              <bitOffset>18</bitOffset>
              <bitWidth>1</bitWidth>
            </field>
            <field>
              <name>UART4RST</name>
              <bitOffset>19</bitOffset>
              <bitWidth>1</bitWidth>
            </field>
            <field>
              <name>UART5RST</name>
              <bitOffset>20</bitOffset>
              <bitWidth>1</bitWidth>
            </field>
            <field>
              <name>I2C1RST</name>
              <bitOffset>21</bitOffset>
              <bitWidth>1</bitWidth>
            </field>
            <field>
              <name>I2C2RST</name>
              <bitOffset>22</bitOffset>
              <bitWidth>1</bitWidth>
            </field>
            <field>
              <name>USBRST</name>
              <bitOffset>23</bitOffset>
              <bitWidth>1</bitWidth>
            </field>
            <field>
              <name>FDCANRST</name>
              <bitOffset>25</bitOffset>
              <bitWidth>1</bitWidth>
            </field>
            <field>
              <name>PWRRST</name>
              <bitOffset>28</bitOffset>
              <bitWidth>1</bitWidth>
            </field>
            <field>
              <name>I2C3RST</name>
              <bitOffset>30</bitOffset>
              <bitWidth>1</bitWidth>
            </field>
            <field>
              <name>LPTIM1RST</name>
              <bitOffset>31</bitOffset>
              <bitWidth>1</bitWidth>
            </field>
          </fields>
        </register>
        <register>
          <name>APB1RSTR2</name>
          <addressOffset>0x3c</addressOffset>
          <size>0x20</size>
          <fields>
            <field>
              <name>LPUART1RST</name>
              <bitOffset>0</bitOffset>
              <bitWidth>1</bitWidth>
            </field>
            <field>
              <name>I2C4RST</name>
              <bitOffset>1</bitOffset>
              <bitWidth>1</bitWidth>
            </field>
            <field>
              <name>UCPD1RST</name>
              <bitOffset>8</bitOffset>
              <bitWidth>1</bitWidth>
            </field>
          </fields>
        </register>
        <register>
          <name>APB2RSTR</name>
          <addressOffset>0x40</addressOffset>
          <size>0x20</size>
          <fields>
            <field>
              <name>SYSCFGRST</name>
              <bitOffset>0</bitOffset>
              <bitWidth>1</bitWidth>
            </field>
            <field>
              <name>TIM1RST</name>
              <bitOffset>11</bitOffset>
              <bitWidth>1</bitWidth>
            </field>
            <field>
              <name>SPI1RST</name>
              <bitOffset>12</bitOffset>
              <bitWidth>1</bitWidth>
            </field>
            <field>
              <name>TIM8RST</name>
              <bitOffset>13</bitOffset>
              <bitWidth>1</bitWidth>
            </field>
            <field>
              <name>USART1RST</name>
              <bitOffset>14</bitOffset>
              <bitWidth>1</bitWidth>
            </field>
            <field>
              <name>SPI4RST</name>
              <bitOffset>15</bitOffset>
              <bitWidth>1</bitWidth>
            </field>
            <field>
              <name>TIM15RST</name>
              <bitOffset>16</bitOffset>
              <bitWidth>1</bitWidth>
            </field>
            <field>
              <name>TIM16RST</name>
              <bitOffset>17</bitOffset>
              <bitWidth>1</bitWidth>
            </field>
            <field>
              <name>TIM17RST</name>
              <bitOffset>18</bitOffset>
              <bitWidth>1</bitWidth>
            </field>
            <field>
              <name>TIM20RST</name>
              <bitOffset>20</bitOffset>
              <bitWidth>1</bitWidth>
            </field>
            <field>
              <name>SAI1RST</name>
              <bitOffset>21</bitOffset>
              <bitWidth>1</bitWidth>
            </field>
          </fields>
        </register>
        <register>
          <name>AHB1ENR</name>
          <addressOffset>0x48</addressOffset>
          <size>0x20</size>
          <fields>
            <field>
              <name>DMA1EN</name>
              <bitOffset>0</bitOffset>
              <bitWidth>1</bitWidth>
            </field>
            <field>
              <name>DMA2EN</name>
              <bitOffset>1</bitOffset>
              <bitWidth>1</bitWidth>
            </field>
            <field>
              <name>DMAMUX1EN</name>
              <bitOffset>2</bitOffset>
              <bitWidth>1</bitWidth>
            </field>
            <field>
              <name>CORDICEN</name>
              <bitOffset>3</bitOffset>
              <bitWidth>1</bitWidth>
            </field>
            <field>
              <name>FMACEN</name>
              <bitOffset>4</bitOffset>
              <bitWidth>1</bitWidth>
            </field>
            <field>
              <name>FLASHEN</name>
              <bitOffset>8</bitOffset>
              <bitWidth>1</bitWidth>
            </field>
            <field>
              <name>CRCEN</name>
              <bitOffset>12</bitOffset>
              <bitWidth>1</bitWidth>
            </field>
          </fields>
        </register>
        <register>
          <name>AHB2ENR</name>
          <addressOffset>0x4c</addressOffset>
          <size>0x20</size>
          <fields>
            <field>
              <name>GPIOAEN</name>
              <bitOffset>0</bitOffset>
              <bitWidth>1</bitWidth>
            </field>
            <field>
              <name>GPIOBEN</name>
              <bitOffset>1</bitOffset>
              <bitWidth>1</bitWidth>
            </field>
            <field>
              <name>GPIOCEN</name>
              <bitOffset>2</bitOffset>
              <bitWidth>1</bitWidth>
            </field>
            <field>
              <name>GPIODEN</name>
              <bitOffset>3</bitOffset>
              <bitWidth>1</bitWidth>
            </field>
            <field>
              <name>GPIOEEN</name>
              <bitOffset>4</bitOffset>
              <bitWidth>1</bitWidth>
            </field>
            <field>
              <name>GPIOFEN</name>
              <bitOffset>5</bitOffset>
              <bitWidth>1</bitWidth>
            </field>
            <field>
              <name>GPIOGEN</name>
              <bitOffset>6</bitOffset>
              <bitWidth>1</bitWidth>
            </field>
            <field>
              <name>ADC12EN</name>
              <bitOffset>13</bitOffset>
              <bitWidth>1</bitWidth>
            </field>
            <field>
              <name>ADC345EN</name>
              <bitOffset>14</bitOffset>
              <bitWidth>1</bitWidth>
            </field>
            <field>
              <name>DAC1EN</name>
              <bitOffset>16</bitOffset>
              <bitWidth>1</bitWidth>
            </field>
            <field>
              <name>DAC3EN</name>
              <bitOffset>18</bitOffset>
              <bitWidth>1</bitWidth>
            </field>
            <field>
              <name>RNGEN</name>
              <bitOffset>26</bitOffset>
              <bitWidth>1</bitWidth>
            </field>
          </fields>
        </register>
        <register>
          <name>AHB3ENR</name>
          <addressOffset>0x50</addressOffset>
          <size>0x20</size>
          <fields>
            <field>
              <name>QSPIEN</name>
              <bitOffset>8</bitOffset>
              <bitWidth>1</bitWidth>
            </field>
          </fields>
        </register>
        <register>
          <name>APB1ENR1</name>
          <addressOffset>0x58</addressOffset>
          <size>0x20</size>
          <fields>
            <field>
              <name>TIM2EN</name>
              <bitOffset>0</bitOffset>
              <bitWidth>1</bitWidth>
            </field>
            <field>
              <name>TIM3EN</name>
              <bitOffset>1</bitOffset>
              <bitWidth>1</bitWidth>
            </field>
            <field>
              <name>TIM4EN</name>
              <bitOffset>2</bitOffset>
              <bitWidth>1</bitWidth>
            </field>
            <field>
              <name>TIM6EN</name>
              <bitOffset>4</bitOffset>
              <bitWidth>1</bitWidth>
            </field>
            <field>
              <name>TIM7EN</name>
              <bitOffset>5</bitOffset>
              <bitWidth>1</bitWidth>
            </field>
            <field>
              <name>CRSEN</name>
              <bitOffset>8</bitOffset>
              <bitWidth>1</bitWidth>
            </field>
            <field>
              <name>RTCAPBEN</name>
              <bitOffset>10</bitOffset>
              <bitWidth>1</bitWidth>
            </field>
            <field>
              <name>WWDGEN</name>
              <bitOffset>11</bitOffset>
              <bitWidth>1</bitWidth>
            </field>
            <field>
              <name>SPI2EN</name>
              <bitOffset>14</bitOffset>
              <bitWidth>1</bitWidth>
            </field>
            <field>
              <name>SPI3EN</name>
              <bitOffset>15</bitOffset>
              <bitWidth>1</bitWidth>
            </field>
            <field>
              <name>USART2EN</name>
              <bitOffset>17</bitOffset>
              <bitWidth>1</bitWidth>
            </field>
            <field>
              <name>USART3EN</name>
              <bitOffset>18</bitOffset>
              <bitWidth>1</bitWidth>
            </field>
            <field>
              <name>UART4EN</name>
              <bitOffset>19</bitOffset>
              <bitWidth>1</bitWidth>
            </field>
            <field>
              <name>UART5EN</name>
              <bitOffset>20</bitOffset>
              <bitWidth>1</bitWidth>
            </field>
            <field>
              <name>I2C1EN</name>
              <bitOffset>21</bitOffset>
              <bitWidth>1</bitWidth>
            </field>
            <field>
              <name>I2C2EN</name>
              <bitOffset>22</bitOffset>
              <bitWidth>1</bitWidth>
            </field>
            <field>
              <name>USBEN</name>
              <bitOffset>23</bitOffset>
              <bitWidth>1</bitWidth>
            </field>
            <field>
              <name>FDCANEN</name>
              <bitOffset>25</bitOffset>
              <bitWidth>1</bitWidth>
            </field>
            <field>
              <name>PWREN</name>
              <bitOffset>28</bitOffset>
              <bitWidth>1</bitWidth>
            </field>
            <field>
              <name>I2C3EN</name>
              <bitOffset>30</bitOffset>
              <bitWidth>1</bitWidth>
            </field>
            <field>
              <name>LPTIM1EN</name>
              <bitOffset>31</bitOffset>
              <bitWidth>1</bitWidth>
            </field>
          </fields>
        </register>
        <register>
          <name>APB1ENR2</name>
          <addressOffset>0x5c</addressOffset>
          <size>0x20</size>
          <fields>
            <field>
              <name>LPUART1EN</name>
              <bitOffset>0</bitOffset>
              <bitWidth>1</bitWidth>
            </field>
            <field>
              <name>I2C4EN</name>
              <bitOffset>1</bitOffset>
              <bitWidth>1</bitWidth>
            </field>
            <field>
              <name>UCPD1EN</name>
              <bitOffset>8</bitOffset>
              <bitWidth>1</bitWidth>
            </field>
          </fields>
        </register>
        <register>
          <name>APB2ENR</name>
          <addressOffset>0x60</addressOffset>
          <size>0x20</size>
          <fields>
            <field>
              <name>SYSCFGEN</name>
              <bitOffset>0</bitOffset>
              <bitWidth>1</bitWidth>
            </field>
            <field>
              <name>TIM1EN</name>
              <bitOffset>11</bitOffset>
              <bitWidth>1</bitWidth>
            </field>
            <field>
              <name>SPI1EN</name>
              <bitOffset>12</bitOffset>
              <bitWidth>1</bitWidth>
            </field>
            <field>
              <name>TIM8EN</name>
              <bitOffset>13</bitOffset>
              <bitWidth>1</bitWidth>
            </field>
            <field>
              <name>USART1EN</name>
              <bitOffset>14</bitOffset>
              <bitWidth>1</bitWidth>
            </field>
            <field>
              <name>SPI4EN</name>
              <bitOffset>15</bitOffset>
              <bitWidth>1</bitWidth>
            </field>
            <field>
              <name>TIM15EN</name>
              <bitOffset>16</bitOffset>
              <bitWidth>1</bitWidth>
            </field>
            <field>
              <name>TIM16EN</name>
              <bitOffset>17</bitOffset>
              <bitWidth>1</bitWidth>
            </field>
            <field>
              <name>TIM17EN</name>
              <bitOffset>18</bitOffset>
              <bitWidth>1</bitWidth>
            </field>
            <field>
              <name>TIM20EN</name>
              <bitOffset>20</bitOffset>
              <bitWidth>1</bitWidth>
            </field>
            <field>
              <name>SAI1EN</name>
              <bitOffset>21</bitOffset>
              <bitWidth>1</bitWidth>
            </field>
          </fields>
        </register>
        <register>
          <name>AHB1SMENR</name>
          <addressOffset>0x68</addressOffset>
          <size>0x20</size>
          <fields>
            <field>
              <name>DMA1SMEN</name>
              <bitOffset>0</bitOffset>
              <bitWidth>1</bitWidth>
            </field>
            <field>
              <name>DMA2SMEN</name>
              <bitOffset>1</bitOffset>
              <bitWidth>1</bitWidth>
            </field>
            <field>
              <name>DMAMUX1SMEN</name>
              <bitOffset>2</bitOffset>
              <bitWidth>1</bitWidth>
            </field>
            <field>
              <name>CORDICSMEN</name>
              <bitOffset>3</bitOffset>
              <bitWidth>1</bitWidth>
            </field>
            <field>
              <name>FMACSMEN</name>
              <bitOffset>4</bitOffset>
              <bitWidth>1</bitWidth>
            </field>
            <field>
              <name>FLASHSMEN</name>
              <bitOffset>8</bitOffset>
              <bitWidth>1</bitWidth>
            </field>
            <field>
              <name>SRAM1SMEN</name>
              <bitOffset>9</bitOffset>
              <bitWidth>1</bitWidth>
            </field>
            <field>
              <name>CRCSMEN</name>
              <bitOffset>12</bitOffset>
              <bitWidth>1</bitWidth>
            </field>
          </fields>
        </register>
        <register>
          <name>AHB2SMENR</name>
          <addressOffset>0x6c</addressOffset>
          <size>0x20</size>
          <fields>
            <field>
              <name>GPIOASMEN</name>
              <bitOffset>0</bitOffset>
              <bitWidth>1</bitWidth>
            </field>
            <field>
              <name>GPIOBSMEN</name>
              <bitOffset>1</bitOffset>
              <bitWidth>1</bitWidth>
            </field>
            <field>
              <name>GPIOCSMEN</name>
              <bitOffset>2</bitOffset>
              <bitWidth>1</bitWidth>
            </field>
            <field>
              <name>GPIODSMEN</name>
              <bitOffset>3</bitOffset>
              <bitWidth>1</bitWidth>
            </field>
            <field>
              <name>GPIOESMEN</name>
              <bitOffset>4</bitOffset>
              <bitWidth>1</bitWidth>
            </field>
            <field>
              <name>GPIOFSMEN</name>
              <bitOffset>5</bitOffset>
              <bitWidth>1</bitWidth>
            </field>
            <field>
              <name>GPIOGSMEN</name>
              <bitOffset>6</bitOffset>
              <bitWidth>1</bitWidth>
            </field>
            <field>
              <name>CCMSRAMSMEN</name>
              <bitOffset>9</bitOffset>
              <bitWidth>1</bitWidth>
            </field>
            <field>
              <name>SRAM2SMEN</name>
              <bitOffset>10</bitOffset>
              <bitWidth>1</bitWidth>
            </field>
            <field>
              <name>ADC12SMEN</name>
              <bitOffset>13</bitOffset>
              <bitWidth>1</bitWidth>
            </field>
            <field>
              <name>ADC345SMEN</name>
              <bitOffset>14</bitOffset>
              <bitWidth>1</bitWidth>
            </field>
            <field>
              <name>DAC1SMEN</name>
              <bitOffset>16</bitOffset>
              <bitWidth>1</bitWidth>
            </field>
            <field>
              <name>DAC3SMEN</name>
              <bitOffset>18</bitOffset>
              <bitWidth>1</bitWidth>
            </field>
            <field>
              <name>RNGSMEN</name>
              <bitOffset>26</bitOffset>
              <bitWidth>1</bitWidth>
            </field>
          </fields>
        </register>
        <register>
          <name>AHB3SMENR</name>
          <addressOffset>0x70</addressOffset>
          <size>0x20</size>
          <fields>
            <field>
              <name>QSPISMEN</name>
              <bitOffset>8</bitOffset>
              <bitWidth>1</bitWidth>
            </field>
          </fields>
        </register>
        <register>
          <name>APB1SMENR1</name>
          <addressOffset>0x78</addressOffset>
          <size>0x20</size>
          <fields>
            <field>
              <name>TIM2SMEN</name>
              <bitOffset>0</bitOffset>
              <bitWidth>1</bitWidth>
            </field>
            <field>
              <name>TIM3SMEN</name>
              <bitOffset>1</bitOffset>
              <bitWidth>1</bitWidth>
            </field>
            <field>
              <name>TIM4SMEN</name>
              <bitOffset>2</bitOffset>
              <bitWidth>1</bitWidth>
            </field>
            <field>
              <name>TIM6SMEN</name>
              <bitOffset>4</bitOffset>
              <bitWidth>1</bitWidth>
            </field>
            <field>
              <name>TIM7SMEN</name>
              <bitOffset>5</bitOffset>
              <bitWidth>1</bitWidth>
            </field>
            <field>
              <name>CRSSMEN</name>
              <bitOffset>8</bitOffset>
              <bitWidth>1</bitWidth>
            </field>
            <field>
              <name>RTCAPBSMEN</name>
              <bitOffset>10</bitOffset>
              <bitWidth>1</bitWidth>
            </field>
            <field>
              <name>WWDGSMEN</name>
              <bitOffset>11</bitOffset>
              <bitWidth>1</bitWidth>
            </field>
            <field>
              <name>SPI2SMEN</name>
              <bitOffset>14</bitOffset>
              <bitWidth>1</bitWidth>
            </field>
            <field>
              <name>SPI3SMEN</name>
              <bitOffset>15</bitOffset>
              <bitWidth>1</bitWidth>
            </field>
            <field>
              <name>USART2SMEN</name>
              <bitOffset>17</bitOffset>
              <bitWidth>1</bitWidth>
            </field>
            <field>
              <name>USART3SMEN</name>
              <bitOffset>18</bitOffset>
              <bitWidth>1</bitWidth>
            </field>
            <field>
              <name>UART4SMEN</name>
              <bitOffset>19</bitOffset>
              <bitWidth>1</bitWidth>
            </field>
            <field>
              <name>UART5SMEN</name>
              <bitOffset>20</bitOffset>
              <bitWidth>1</bitWidth>
            </field>
            <field>
              <name>I2C1SMEN</name>
              <bitOffset>21</bitOffset>
              <bitWidth>1</bitWidth>
            </field>
            <field>
              <name>I2C2SMEN</name>
              <bitOffset>22</bitOffset>
              <bitWidth>1</bitWidth>
            </field>
            <field>
              <name>USBSMEN</name>
              <bitOffset>23</bitOffset>
              <bitWidth>1</bitWidth>
            </field>
            <field>
              <name>FDCANSMEN</name>
              <bitOffset>25</bitOffset>
              <bitWidth>1</bitWidth>
            </field>
            <field>
              <name>PWRSMEN</name>
              <bitOffset>28</bitOffset>
              <bitWidth>1</bitWidth>
            </field>
            <field>
              <name>I2C3SMEN</name>
              <bitOffset>30</bitOffset>
              <bitWidth>1</bitWidth>
            </field>
            <field>
              <name>LPTIM1SMEN</name>
              <bitOffset>31</bitOffset>
              <bitWidth>1</bitWidth>
            </field>
          </fields>
        </register>
        <register>
          <name>APB1SMENR2</name>
          <addressOffset>0x7c</addressOffset>
          <size>0x20</size>
          <fields>
            <field>
              <name>LPUART1SMEN</name>
              <bitOffset>0</bitOffset>
              <bitWidth>1</bitWidth>
            </field>
            <field>
              <name>I2C4SMEN</name>
              <bitOffset>1</bitOffset>
              <bitWidth>1</bitWidth>
            </field>
            <field>
              <name>UCPD1SMEN</name>
              <bitOffset>8</bitOffset>
              <bitWidth>1</bitWidth>
            </field>
          </fields>
        </register>
        <register>
          <name>APB2SMENR</name>
          <addressOffset>0x80</addressOffset>
          <size>0x20</size>
          <fields>
            <field>
              <name>SYSCFGSMEN</name>
              <bitOffset>0</bitOffset>
              <bitWidth>1</bitWidth>
            </field>
            <field>
              <name>TIM1SMEN</name>
              <bitOffset>11</bitOffset>
              <bitWidth>1</bitWidth>
            </field>
            <field>
              <name>SPI1SMEN</name>
              <bitOffset>12</bitOffset>
              <bitWidth>1</bitWidth>
            </field>
            <field>
              <name>TIM8SMEN</name>
              <bitOffset>13</bitOffset>
              <bitWidth>1</bitWidth>
            </field>
            <field>
              <name>USART1SMEN</name>
              <bitOffset>14</bitOffset>
              <bitWidth>1</bitWidth>
            </field>
            <field>
              <name>SPI4SMEN</name>
              <bitOffset>15</bitOffset>
              <bitWidth>1</bitWidth>
            </field>
            <field>
              <name>TIM15SMEN</name>
              <bitOffset>16</bitOffset>
              <bitWidth>1</bitWidth>
            </field>
            <field>
              <name>TIM16SMEN</name>
              <bitOffset>17</bitOffset>
              <bitWidth>1</bitWidth>
            </field>
            <field>
              <name>TIM17SMEN</name>
              <bitOffset>18</bitOffset>
              <bitWidth>1</bitWidth>
            </field>
            <field>
              <name>TIM20SMEN</name>
              <bitOffset>20</bitOffset>
              <bitWidth>1</bitWidth>
            </field>
            <field>
              <name>SAI1SMEN</name>
              <bitOffset>21</bitOffset>
              <bitWidth>1</bitWidth>
            </field>
          </fields>
        </register>
        <register>
          <name>CCIPR</name>
          <addressOffset>0x88</addressOffset>
          <size>0x20</size>
          <fields>
            <field>
              <name>USART1SEL</name>
              <bitOffset>0</bitOffset>
              <bitWidth>2</bitWidth>
            </field>
            <field>
              <name>USART2SEL</name>
              <bitOffset>2</bitOffset>
              <bitWidth>2</bitWidth>
            </field>
            <field>
              <name>USART3SEL</name>
              <bitOffset>4</bitOffset>
              <bitWidth>2</bitWidth>
            </field>
            <field>
              <name>UART4SEL</name>
              <bitOffset>6</bitOffset>
              <bitWidth>2</bitWidth>
            </field>
            <field>
              <name>UART5SEL</name>
              <bitOffset>8</bitOffset>
              <bitWidth>2</bitWidth>
            </field>
            <field>
              <name>LPUART1SEL</name>
              <bitOffset>10</bitOffset>
              <bitWidth>2</bitWidth>
            </field>
            <field>
              <name>I2C1SEL</name>
              <bitOffset>12</bitOffset>
              <bitWidth>2</bitWidth>
            </field>
            <field>
              <name>I2C2SEL</name>
              <bitOffset>14</bitOffset>
              <bitWidth>2</bitWidth>
            </field>
            <field>
              <name>I2C3SEL</name>
              <bitOffset>16</bitOffset>
              <bitWidth>2</bitWidth>
            </field>
            <field>
              <name>LPTIM1SEL</name>
              <bitOffset>18</bitOffset>
              <bitWidth>2</bitWidth>
            </field>
            <field>
              <name>SAI1SEL</name>
              <bitOffset>20</bitOffset>
              <bitWidth>2</bitWidth>
            </field>
            <field>
              <name>I2S23SEL</name>
              <bitOffset>22</bitOffset>
              <bitWidth>2</bitWidth>
            </field>
            <field>
              <name>FDCANSEL</name>
              <bitOffset>24</bitOffset>
              <bitWidth>2</bitWidth>
            </field>
            <field>
              <name>CLK48SEL</name>
              <bitOffset>26</bitOffset>
              <bitWidth>2</bitWidth>
            </field>
            <field>
              <name>ADC12SEL</name>
              <bitOffset>28</bitOffset>
              <bitWidth>2</bitWidth>
            </field>
            <field>
              <name>ADC345SEL</name>
              <bitOffset>30</bitOffset>
              <bitWidth>2</bitWidth>
            </field>
          </fields>
        </register>
        <register>
          <name>BDCR</name>
          <addressOffset>0x90</addressOffset>
          <size>0x20</size>
          <fields>
            <field>
              <name>LSEON</name>
              <bitOffset>0</bitOffset>
              <bitWidth>1</bitWidth>
            </field>
            <field>
              <name>LSERDY</name>
              <bitOffset>1</bitOffset>
              <bitWidth>1</bitWidth>
            </field>
            <field>
              <name>LSEBYP</name>
              <bitOffset>2</bitOffset>
              <bitWidth>1</bitWidth>
            </field>
            <field>
              <name>LSEDRV</name>
              <bitOffset>3</bitOffset>
              <bitWidth>2</bitWidth>
            </field>
            <field>
              <name>LSECSSON</name>
              <bitOffset>5</bitOffset>
              <bitWidth>1</bitWidth>
            </field>
            <field>
              <name>LSECSSD</name>
              <bitOffset>6</bitOffset>
              <bitWidth>1</bitWidth>
            </field>
            <field>
              <name>RTCSEL</name>
              <bitOffset>8</bitOffset>
              <bitWidth>2</bitWidth>
            </field>
            <field>
              <name>RTCEN</name>
              <bitOffset>15</bitOffset>
              <bitWidth>1</bitWidth>
            </field>
            <field>
              <name>BDRST</name>
              <bitOffset>16</bitOffset>
              <bitWidth>1</bitWidth>
            </field>
            <field>
              <name>LSCOEN</name>
              <bitOffset>24</bitOffset>
              <bitWidth>1</bitWidth>
            </field>
            <field>
              <name>LSCOSEL</name>
              <bitOffset>25</bitOffset>
              <bitWidth>1</bitWidth>
            </field>
          </fields>
        </register>
        <register>
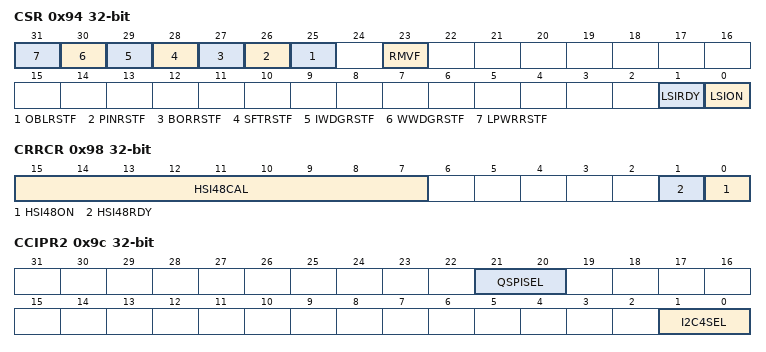
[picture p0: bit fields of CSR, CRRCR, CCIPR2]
          <name>CSR</name>
          <addressOffset>0x94</addressOffset>
          <size>0x20</size>
          <fields>
            <field>
              <name>LSION</name>
              <bitOffset>0</bitOffset>
              <bitWidth>1</bitWidth>
            </field>
            <field>
              <name>LSIRDY</name>
              <bitOffset>1</bitOffset>
              <bitWidth>1</bitWidth>
            </field>
            <field>
              <name>RMVF</name>
              <bitOffset>23</bitOffset>
              <bitWidth>1</bitWidth>
            </field>
            <field>
              <name>OBLRSTF</name>
              <bitOffset>25</bitOffset>
              <bitWidth>1</bitWidth>
            </field>
            <field>
              <name>PINRSTF</name>
              <bitOffset>26</bitOffset>
              <bitWidth>1</bitWidth>
            </field>
            <field>
              <name>BORRSTF</name>
              <bitOffset>27</bitOffset>
              <bitWidth>1</bitWidth>
            </field>
            <field>
              <name>SFTRSTF</name>
              <bitOffset>28</bitOffset>
              <bitWidth>1</bitWidth>
            </field>
            <field>
              <name>IWDGRSTF</name>
              <bitOffset>29</bitOffset>
              <bitWidth>1</bitWidth>
            </field>
            <field>
              <name>WWDGRSTF</name>
              <bitOffset>30</bitOffset>
              <bitWidth>1</bitWidth>
            </field>
            <field>
              <name>LPWRRSTF</name>
              <bitOffset>31</bitOffset>
              <bitWidth>1</bitWidth>
            </field>
          </fields>
        </register>
        <register>
          <name>CRRCR</name>
          <addressOffset>0x98</addressOffset>
          <size>0x20</size>
          <fields>
            <field>
              <name>HSI48ON</name>
              <bitOffset>0</bitOffset>
              <bitWidth>1</bitWidth>
            </field>
            <field>
              <name>HSI48RDY</name>
              <bitOffset>1</bitOffset>
              <bitWidth>1</bitWidth>
            </field>
            <field>
              <name>HSI48CAL</name>
              <bitOffset>7</bitOffset>
              <bitWidth>9</bitWidth>
            </field>
          </fields>
        </register>
        <register>
          <name>CCIPR2</name>
          <addressOffset>0x9c</addressOffset>
          <size>0x20</size>
          <fields>
            <field>
              <name>I2C4SEL</name>
              <bitOffset>0</bitOffset>
              <bitWidth>2</bitWidth>
            </field>
            <field>
              <name>QSPISEL</name>
              <bitOffset>20</bitOffset>
              <bitWidth>2</bitWidth>
            </field>
          </fields>
        </register>
      </registers>
    </peripheral>
    <peripheral>
      <name>FMAC</name>
      <baseAddress>0x40021400</baseAddress>
      <registers>
        <register>
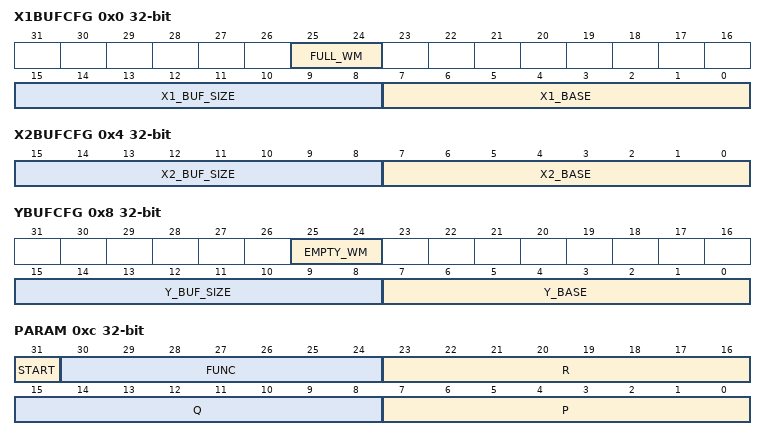
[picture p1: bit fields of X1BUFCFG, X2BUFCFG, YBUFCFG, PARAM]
          <name>X1BUFCFG</name>
          <addressOffset>0x0</addressOffset>
          <size>0x20</size>
          <fields>
            <field>
              <name>X1_BASE</name>
              <bitOffset>0</bitOffset>
              <bitWidth>8</bitWidth>
            </field>
            <field>
              <name>X1_BUF_SIZE</name>
              <bitOffset>8</bitOffset>
              <bitWidth>8</bitWidth>
            </field>
            <field>
              <name>FULL_WM</name>
              <bitOffset>24</bitOffset>
              <bitWidth>2</bitWidth>
            </field>
          </fields>
        </register>
        <register>
          <name>X2BUFCFG</name>
          <addressOffset>0x4</addressOffset>
          <size>0x20</size>
          <fields>
            <field>
              <name>X2_BASE</name>
              <bitOffset>0</bitOffset>
              <bitWidth>8</bitWidth>
            </field>
            <field>
              <name>X2_BUF_SIZE</name>
              <bitOffset>8</bitOffset>
              <bitWidth>8</bitWidth>
            </field>
          </fields>
        </register>
        <register>
          <name>YBUFCFG</name>
          <addressOffset>0x8</addressOffset>
          <size>0x20</size>
          <fields>
            <field>
              <name>Y_BASE</name>
              <bitOffset>0</bitOffset>
              <bitWidth>8</bitWidth>
            </field>
            <field>
              <name>Y_BUF_SIZE</name>
              <bitOffset>8</bitOffset>
              <bitWidth>8</bitWidth>
            </field>
            <field>
              <name>EMPTY_WM</name>
              <bitOffset>24</bitOffset>
              <bitWidth>2</bitWidth>
            </field>
          </fields>
        </register>
        <register>
          <name>PARAM</name>
          <addressOffset>0xc</addressOffset>
          <size>0x20</size>
          <fields>
            <field>
              <name>P</name>
              <bitOffset>0</bitOffset>
              <bitWidth>8</bitWidth>
            </field>
            <field>
              <name>Q</name>
              <bitOffset>8</bitOffset>
              <bitWidth>8</bitWidth>
            </field>
            <field>
              <name>R</name>
              <bitOffset>16</bitOffset>
              <bitWidth>8</bitWidth>
            </field>
            <field>
              <name>FUNC</name>
              <bitOffset>24</bitOffset>
              <bitWidth>7</bitWidth>
            </field>
            <field>
              <name>START</name>
              <bitOffset>31</bitOffset>
              <bitWidth>1</bitWidth>
            </field>
          </fields>
        </register>
        <register>
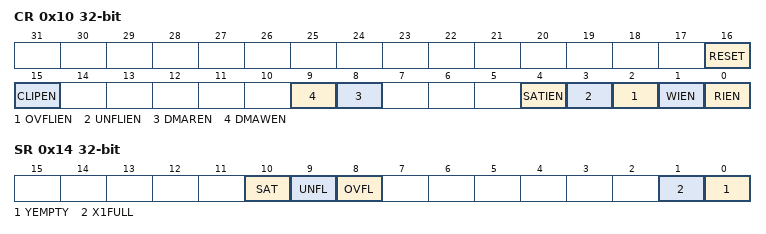
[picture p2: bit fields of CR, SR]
          <name>CR</name>
          <addressOffset>0x10</addressOffset>
          <size>0x20</size>
          <fields>
            <field>
              <name>RIEN</name>
              <bitOffset>0</bitOffset>
              <bitWidth>1</bitWidth>
            </field>
            <field>
              <name>WIEN</name>
              <bitOffset>1</bitOffset>
              <bitWidth>1</bitWidth>
            </field>
            <field>
              <name>OVFLIEN</name>
              <bitOffset>2</bitOffset>
              <bitWidth>1</bitWidth>
            </field>
            <field>
              <name>UNFLIEN</name>
              <bitOffset>3</bitOffset>
              <bitWidth>1</bitWidth>
            </field>
            <field>
              <name>SATIEN</name>
              <bitOffset>4</bitOffset>
              <bitWidth>1</bitWidth>
            </field>
            <field>
              <name>DMAREN</name>
              <bitOffset>8</bitOffset>
              <bitWidth>1</bitWidth>
            </field>
            <field>
              <name>DMAWEN</name>
              <bitOffset>9</bitOffset>
              <bitWidth>1</bitWidth>
            </field>
            <field>
              <name>CLIPEN</name>
              <bitOffset>15</bitOffset>
              <bitWidth>1</bitWidth>
            </field>
            <field>
              <name>RESET</name>
              <bitOffset>16</bitOffset>
              <bitWidth>1</bitWidth>
            </field>
          </fields>
        </register>
        <register>
          <name>SR</name>
          <addressOffset>0x14</addressOffset>
          <size>0x20</size>
          <fields>
            <field>
              <name>YEMPTY</name>
              <bitOffset>0</bitOffset>
              <bitWidth>1</bitWidth>
            </field>
            <field>
              <name>X1FULL</name>
              <bitOffset>1</bitOffset>
              <bitWidth>1</bitWidth>
            </field>
            <field>
              <name>OVFL</name>
              <bitOffset>8</bitOffset>
              <bitWidth>1</bitWidth>
            </field>
            <field>
              <name>UNFL</name>
              <bitOffset>9</bitOffset>
              <bitWidth>1</bitWidth>
            </field>
            <field>
              <name>SAT</name>
              <bitOffset>10</bitOffset>
              <bitWidth>1</bitWidth>
            </field>
          </fields>
        </register>
        <register>
          <name>WDATA</name>
          <addressOffset>0x18</addressOffset>
          <size>0x20</size>
          <fields>
            <field>
              <name>WDATA</name>
              <bitOffset>0</bitOffset>
              <bitWidth>16</bitWidth>
            </field>
          </fields>
        </register>
        <register>
          <name>RDATA</name>
          <addressOffset>0x1c</addressOffset>
          <size>0x20</size>
          <fields>
            <field>
              <name>RDATA</name>
              <bitOffset>0</bitOffset>
              <bitWidth>16</bitWidth>
            </field>
          </fields>
        </register>
      </registers>
    </peripheral>
    <peripheral>
      <name>FLASH</name>
      <baseAddress>0x40022000</baseAddress>
      <registers>
        <register>
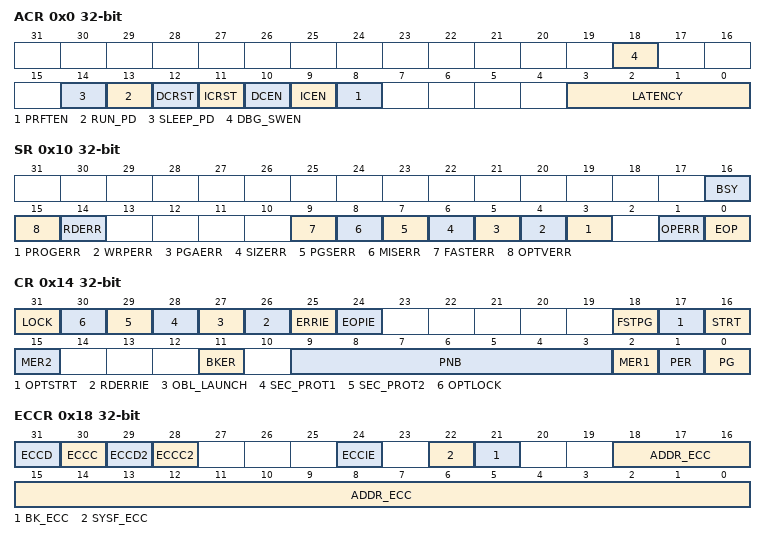
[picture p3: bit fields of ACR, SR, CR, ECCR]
          <name>ACR</name>
          <addressOffset>0x0</addressOffset>
          <size>0x20</size>
          <fields>
            <field>
              <name>LATENCY</name>
              <bitOffset>0</bitOffset>
              <bitWidth>4</bitWidth>
            </field>
            <field>
              <name>PRFTEN</name>
              <bitOffset>8</bitOffset>
              <bitWidth>1</bitWidth>
            </field>
            <field>
              <name>ICEN</name>
              <bitOffset>9</bitOffset>
              <bitWidth>1</bitWidth>
            </field>
            <field>
              <name>DCEN</name>
              <bitOffset>10</bitOffset>
              <bitWidth>1</bitWidth>
            </field>
            <field>
              <name>ICRST</name>
              <bitOffset>11</bitOffset>
              <bitWidth>1</bitWidth>
            </field>
            <field>
              <name>DCRST</name>
              <bitOffset>12</bitOffset>
              <bitWidth>1</bitWidth>
            </field>
            <field>
              <name>RUN_PD</name>
              <bitOffset>13</bitOffset>
              <bitWidth>1</bitWidth>
            </field>
            <field>
              <name>SLEEP_PD</name>
              <bitOffset>14</bitOffset>
              <bitWidth>1</bitWidth>
            </field>
            <field>
              <name>DBG_SWEN</name>
              <bitOffset>18</bitOffset>
              <bitWidth>1</bitWidth>
            </field>
          </fields>
        </register>
        <register>
          <name>PDKEYR</name>
          <addressOffset>0x4</addressOffset>
          <size>0x20</size>
        </register>
        <register>
          <name>KEYR</name>
          <addressOffset>0x8</addressOffset>
          <size>0x20</size>
        </register>
        <register>
          <name>OPTKEYR</name>
          <addressOffset>0xc</addressOffset>
          <size>0x20</size>
        </register>
        <register>
          <name>SR</name>
          <addressOffset>0x10</addressOffset>
          <size>0x20</size>
          <fields>
            <field>
              <name>EOP</name>
              <bitOffset>0</bitOffset>
              <bitWidth>1</bitWidth>
            </field>
            <field>
              <name>OPERR</name>
              <bitOffset>1</bitOffset>
              <bitWidth>1</bitWidth>
            </field>
            <field>
              <name>PROGERR</name>
              <bitOffset>3</bitOffset>
              <bitWidth>1</bitWidth>
            </field>
            <field>
              <name>WRPERR</name>
              <bitOffset>4</bitOffset>
              <bitWidth>1</bitWidth>
            </field>
            <field>
              <name>PGAERR</name>
              <bitOffset>5</bitOffset>
              <bitWidth>1</bitWidth>
            </field>
            <field>
              <name>SIZERR</name>
              <bitOffset>6</bitOffset>
              <bitWidth>1</bitWidth>
            </field>
            <field>
              <name>PGSERR</name>
              <bitOffset>7</bitOffset>
              <bitWidth>1</bitWidth>
            </field>
            <field>
              <name>MISERR</name>
              <bitOffset>8</bitOffset>
              <bitWidth>1</bitWidth>
            </field>
            <field>
              <name>FASTERR</name>
              <bitOffset>9</bitOffset>
              <bitWidth>1</bitWidth>
            </field>
            <field>
              <name>RDERR</name>
              <bitOffset>14</bitOffset>
              <bitWidth>1</bitWidth>
            </field>
            <field>
              <name>OPTVERR</name>
              <bitOffset>15</bitOffset>
              <bitWidth>1</bitWidth>
            </field>
            <field>
              <name>BSY</name>
              <bitOffset>16</bitOffset>
              <bitWidth>1</bitWidth>
            </field>
          </fields>
        </register>
        <register>
          <name>CR</name>
          <addressOffset>0x14</addressOffset>
          <size>0x20</size>
          <fields>
            <field>
              <name>PG</name>
              <bitOffset>0</bitOffset>
              <bitWidth>1</bitWidth>
            </field>
            <field>
              <name>PER</name>
              <bitOffset>1</bitOffset>
              <bitWidth>1</bitWidth>
            </field>
            <field>
              <name>MER1</name>
              <bitOffset>2</bitOffset>
              <bitWidth>1</bitWidth>
            </field>
            <field>
              <name>PNB</name>
              <bitOffset>3</bitOffset>
              <bitWidth>7</bitWidth>
            </field>
            <field>
              <name>BKER</name>
              <bitOffset>11</bitOffset>
              <bitWidth>1</bitWidth>
            </field>
            <field>
              <name>MER2</name>
              <bitOffset>15</bitOffset>
              <bitWidth>1</bitWidth>
            </field>
            <field>
              <name>STRT</name>
              <bitOffset>16</bitOffset>
              <bitWidth>1</bitWidth>
            </field>
            <field>
              <name>OPTSTRT</name>
              <bitOffset>17</bitOffset>
              <bitWidth>1</bitWidth>
            </field>
            <field>
              <name>FSTPG</name>
              <bitOffset>18</bitOffset>
              <bitWidth>1</bitWidth>
            </field>
            <field>
              <name>EOPIE</name>
              <bitOffset>24</bitOffset>
              <bitWidth>1</bitWidth>
            </field>
            <field>
              <name>ERRIE</name>
              <bitOffset>25</bitOffset>
              <bitWidth>1</bitWidth>
            </field>
            <field>
              <name>RDERRIE</name>
              <bitOffset>26</bitOffset>
              <bitWidth>1</bitWidth>
            </field>
            <field>
              <name>OBL_LAUNCH</name>
              <bitOffset>27</bitOffset>
              <bitWidth>1</bitWidth>
            </field>
            <field>
              <name>SEC_PROT1</name>
              <bitOffset>28</bitOffset>
              <bitWidth>1</bitWidth>
            </field>
            <field>
              <name>SEC_PROT2</name>
              <bitOffset>29</bitOffset>
              <bitWidth>1</bitWidth>
            </field>
            <field>
              <name>OPTLOCK</name>
              <bitOffset>30</bitOffset>
              <bitWidth>1</bitWidth>
            </field>
            <field>
              <name>LOCK</name>
              <bitOffset>31</bitOffset>
              <bitWidth>1</bitWidth>
            </field>
          </fields>
        </register>
        <register>
          <name>ECCR</name>
          <addressOffset>0x18</addressOffset>
          <size>0x20</size>
          <fields>
            <field>
              <name>ADDR_ECC</name>
              <bitOffset>0</bitOffset>
              <bitWidth>19</bitWidth>
            </field>
            <field>
              <name>BK_ECC</name>
              <bitOffset>21</bitOffset>
              <bitWidth>1</bitWidth>
            </field>
            <field>
              <name>SYSF_ECC</name>
              <bitOffset>22</bitOffset>
              <bitWidth>1</bitWidth>
            </field>
            <field>
              <name>ECCIE</name>
              <bitOffset>24</bitOffset>
              <bitWidth>1</bitWidth>
            </field>
            <field>
              <name>ECCC2</name>
              <bitOffset>28</bitOffset>
              <bitWidth>1</bitWidth>
            </field>
            <field>
              <name>ECCD2</name>
              <bitOffset>29</bitOffset>
              <bitWidth>1</bitWidth>
            </field>
            <field>
              <name>ECCC</name>
              <bitOffset>30</bitOffset>
              <bitWidth>1</bitWidth>
            </field>
            <field>
              <name>ECCD</name>
              <bitOffset>31</bitOffset>
              <bitWidth>1</bitWidth>
            </field>
          </fields>
        </register>
        <register>
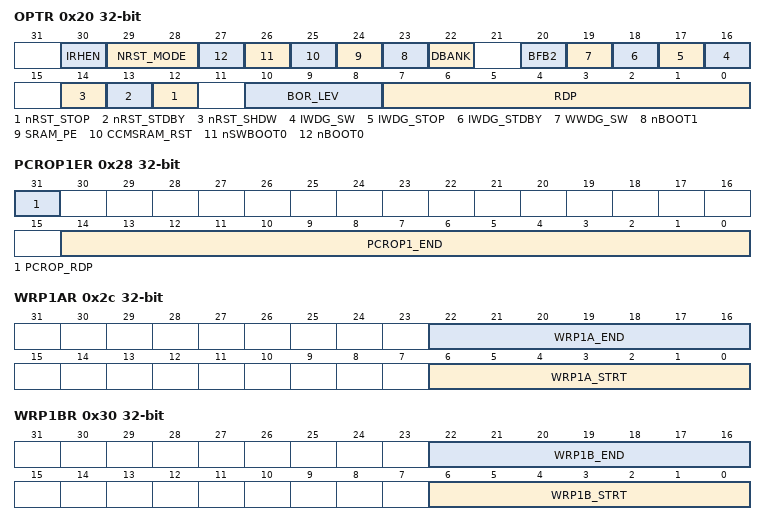
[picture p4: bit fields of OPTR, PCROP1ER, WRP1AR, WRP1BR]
          <name>OPTR</name>
          <addressOffset>0x20</addressOffset>
          <size>0x20</size>
          <fields>
            <field>
              <name>RDP</name>
              <bitOffset>0</bitOffset>
              <bitWidth>8</bitWidth>
            </field>
            <field>
              <name>BOR_LEV</name>
              <bitOffset>8</bitOffset>
              <bitWidth>3</bitWidth>
            </field>
            <field>
              <name>nRST_STOP</name>
              <bitOffset>12</bitOffset>
              <bitWidth>1</bitWidth>
            </field>
            <field>
              <name>nRST_STDBY</name>
              <bitOffset>13</bitOffset>
              <bitWidth>1</bitWidth>
            </field>
            <field>
              <name>nRST_SHDW</name>
              <bitOffset>14</bitOffset>
              <bitWidth>1</bitWidth>
            </field>
            <field>
              <name>IWDG_SW</name>
              <bitOffset>16</bitOffset>
              <bitWidth>1</bitWidth>
            </field>
            <field>
              <name>IWDG_STOP</name>
              <bitOffset>17</bitOffset>
              <bitWidth>1</bitWidth>
            </field>
            <field>
              <name>IWDG_STDBY</name>
              <bitOffset>18</bitOffset>
              <bitWidth>1</bitWidth>
            </field>
            <field>
              <name>WWDG_SW</name>
              <bitOffset>19</bitOffset>
              <bitWidth>1</bitWidth>
            </field>
            <field>
              <name>BFB2</name>
              <bitOffset>20</bitOffset>
              <bitWidth>1</bitWidth>
            </field>
            <field>
              <name>DBANK</name>
              <bitOffset>22</bitOffset>
              <bitWidth>1</bitWidth>
            </field>
            <field>
              <name>nBOOT1</name>
              <bitOffset>23</bitOffset>
              <bitWidth>1</bitWidth>
            </field>
            <field>
              <name>SRAM_PE</name>
              <bitOffset>24</bitOffset>
              <bitWidth>1</bitWidth>
            </field>
            <field>
              <name>CCMSRAM_RST</name>
              <bitOffset>25</bitOffset>
              <bitWidth>1</bitWidth>
            </field>
            <field>
              <name>nSWBOOT0</name>
              <bitOffset>26</bitOffset>
              <bitWidth>1</bitWidth>
            </field>
            <field>
              <name>nBOOT0</name>
              <bitOffset>27</bitOffset>
              <bitWidth>1</bitWidth>
            </field>
            <field>
              <name>NRST_MODE</name>
              <bitOffset>28</bitOffset>
              <bitWidth>2</bitWidth>
            </field>
            <field>
              <name>IRHEN</name>
              <bitOffset>30</bitOffset>
              <bitWidth>1</bitWidth>
            </field>
          </fields>
        </register>
        <register>
          <name>PCROP1SR</name>
          <addressOffset>0x24</addressOffset>
          <size>0x20</size>
          <fields>
            <field>
              <name>PCROP1_STRT</name>
              <bitOffset>0</bitOffset>
              <bitWidth>15</bitWidth>
            </field>
          </fields>
        </register>
        <register>
          <name>PCROP1ER</name>
          <addressOffset>0x28</addressOffset>
          <size>0x20</size>
          <fields>
            <field>
              <name>PCROP1_END</name>
              <bitOffset>0</bitOffset>
              <bitWidth>15</bitWidth>
            </field>
            <field>
              <name>PCROP_RDP</name>
              <bitOffset>31</bitOffset>
              <bitWidth>1</bitWidth>
            </field>
          </fields>
        </register>
        <register>
          <name>WRP1AR</name>
          <addressOffset>0x2c</addressOffset>
          <size>0x20</size>
          <fields>
            <field>
              <name>WRP1A_STRT</name>
              <bitOffset>0</bitOffset>
              <bitWidth>7</bitWidth>
            </field>
            <field>
              <name>WRP1A_END</name>
              <bitOffset>16</bitOffset>
              <bitWidth>7</bitWidth>
            </field>
          </fields>
        </register>
        <register>
          <name>WRP1BR</name>
          <addressOffset>0x30</addressOffset>
          <size>0x20</size>
          <fields>
            <field>
              <name>WRP1B_STRT</name>
              <bitOffset>0</bitOffset>
              <bitWidth>7</bitWidth>
            </field>
            <field>
              <name>WRP1B_END</name>
              <bitOffset>16</bitOffset>
              <bitWidth>7</bitWidth>
            </field>
          </fields>
        </register>
        <register>
          <name>PCROP2SR</name>
          <addressOffset>0x44</addressOffset>
          <size>0x20</size>
          <fields>
            <field>
              <name>PCROP2_STRT</name>
              <bitOffset>0</bitOffset>
              <bitWidth>15</bitWidth>
            </field>
          </fields>
        </register>
        <register>
          <name>PCROP2ER</name>
          <addressOffset>0x48</addressOffset>
          <size>0x20</size>
          <fields>
            <field>
              <name>PCROP2_END</name>
              <bitOffset>0</bitOffset>
              <bitWidth>15</bitWidth>
            </field>
          </fields>
        </register>
        <register>
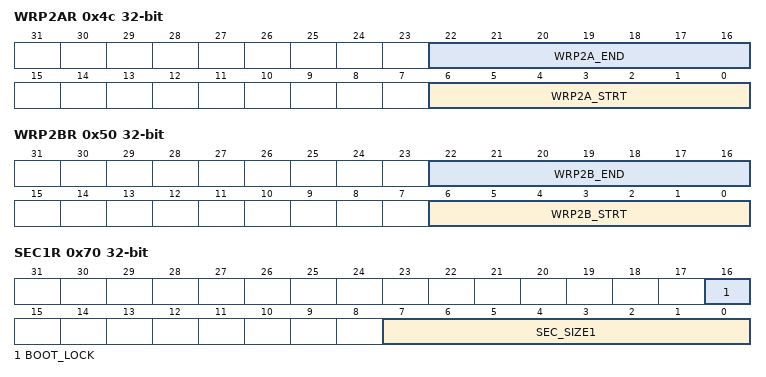
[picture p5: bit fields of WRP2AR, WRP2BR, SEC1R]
          <name>WRP2AR</name>
          <addressOffset>0x4c</addressOffset>
          <size>0x20</size>
          <fields>
            <field>
              <name>WRP2A_STRT</name>
              <bitOffset>0</bitOffset>
              <bitWidth>7</bitWidth>
            </field>
            <field>
              <name>WRP2A_END</name>
              <bitOffset>16</bitOffset>
              <bitWidth>7</bitWidth>
            </field>
          </fields>
        </register>
        <register>
          <name>WRP2BR</name>
          <addressOffset>0x50</addressOffset>
          <size>0x20</size>
          <fields>
            <field>
              <name>WRP2B_STRT</name>
              <bitOffset>0</bitOffset>
              <bitWidth>7</bitWidth>
            </field>
            <field>
              <name>WRP2B_END</name>
              <bitOffset>16</bitOffset>
              <bitWidth>7</bitWidth>
            </field>
          </fields>
        </register>
        <register>
          <name>SEC1R</name>
          <addressOffset>0x70</addressOffset>
          <size>0x20</size>
          <fields>
            <field>
              <name>SEC_SIZE1</name>
              <bitOffset>0</bitOffset>
              <bitWidth>8</bitWidth>
            </field>
            <field>
              <name>BOOT_LOCK</name>
              <bitOffset>16</bitOffset>
              <bitWidth>1</bitWidth>
            </field>
          </fields>
        </register>
        <register>
          <name>SEC2R</name>
          <addressOffset>0x74</addressOffset>
          <size>0x20</size>
          <fields>
            <field>
              <name>SEC_SIZE2</name>
              <bitOffset>0</bitOffset>
              <bitWidth>8</bitWidth>
            </field>
          </fields>
        </register>
      </registers>
    </peripheral>
    <peripheral>
      <name>CRC</name>
      <baseAddress>0x40023000</baseAddress>
      <registers>
        <register>
          <name>DR</name>
          <addressOffset>0x0</addressOffset>
          <size>0x20</size>
          <fields>
            <field>
              <name>DR</name>
              <bitOffset>0</bitOffset>
              <bitWidth>32</bitWidth>
            </field>
          </fields>
        </register>
        <register>
          <name>IDR</name>
          <addressOffset>0x4</addressOffset>
          <size>0x20</size>
          <fields>
            <field>
              <name>IDR</name>
              <bitOffset>0</bitOffset>
              <bitWidth>32</bitWidth>
            </field>
          </fields>
        </register>
        <register>
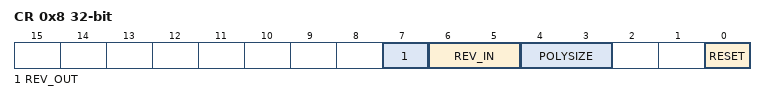
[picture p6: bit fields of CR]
          <name>CR</name>
          <addressOffset>0x8</addressOffset>
          <size>0x20</size>
          <fields>
            <field>
              <name>RESET</name>
              <bitOffset>0</bitOffset>
              <bitWidth>1</bitWidth>
            </field>
            <field>
              <name>POLYSIZE</name>
              <bitOffset>3</bitOffset>
              <bitWidth>2</bitWidth>
            </field>
            <field>
              <name>REV_IN</name>
              <bitOffset>5</bitOffset>
              <bitWidth>2</bitWidth>
            </field>
            <field>
              <name>REV_OUT</name>
              <bitOffset>7</bitOffset>
              <bitWidth>1</bitWidth>
            </field>
          </fields>
        </register>
        <register>
          <name>INIT</name>
          <addressOffset>0x10</addressOffset>
          <size>0x20</size>
          <fields>
            <field>
              <name>INIT</name>
              <bitOffset>0</bitOffset>
              <bitWidth>32</bitWidth>
            </field>
          </fields>
        </register>
        <register>
          <name>POL</name>
          <addressOffset>0x14</addressOffset>
          <size>0x20</size>
          <fields>
            <field>
              <name>POL</name>
              <bitOffset>0</bitOffset>
              <bitWidth>32</bitWidth>
            </field>
          </fields>
        </register>
      </registers>
    </peripheral>
    <peripheral>
      <name>GPIOA</name>
      <baseAddress>0x48000000</baseAddress>
      <registers>
        <register>
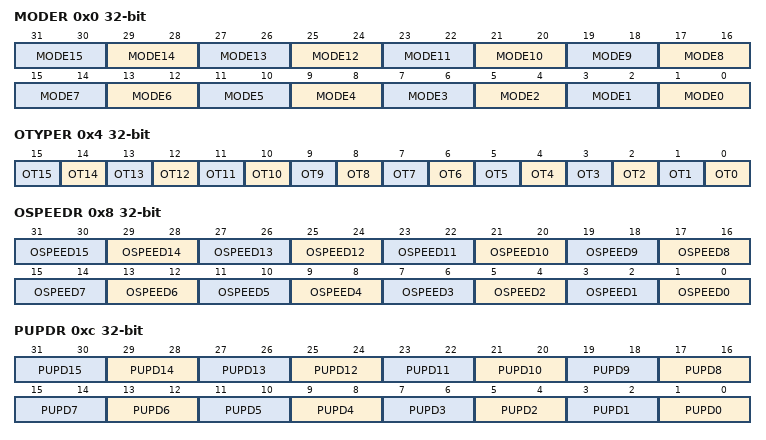
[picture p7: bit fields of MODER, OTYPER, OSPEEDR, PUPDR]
          <name>MODER</name>
          <addressOffset>0x0</addressOffset>
          <size>0x20</size>
          <fields>
            <field>
              <name>MODE0</name>
              <bitOffset>0</bitOffset>
              <bitWidth>2</bitWidth>
            </field>
            <field>
              <name>MODE1</name>
              <bitOffset>2</bitOffset>
              <bitWidth>2</bitWidth>
            </field>
            <field>
              <name>MODE2</name>
              <bitOffset>4</bitOffset>
              <bitWidth>2</bitWidth>
            </field>
            <field>
              <name>MODE3</name>
              <bitOffset>6</bitOffset>
              <bitWidth>2</bitWidth>
            </field>
            <field>
              <name>MODE4</name>
              <bitOffset>8</bitOffset>
              <bitWidth>2</bitWidth>
            </field>
            <field>
              <name>MODE5</name>
              <bitOffset>10</bitOffset>
              <bitWidth>2</bitWidth>
            </field>
            <field>
              <name>MODE6</name>
              <bitOffset>12</bitOffset>
              <bitWidth>2</bitWidth>
            </field>
            <field>
              <name>MODE7</name>
              <bitOffset>14</bitOffset>
              <bitWidth>2</bitWidth>
            </field>
            <field>
              <name>MODE8</name>
              <bitOffset>16</bitOffset>
              <bitWidth>2</bitWidth>
            </field>
            <field>
              <name>MODE9</name>
              <bitOffset>18</bitOffset>
              <bitWidth>2</bitWidth>
            </field>
            <field>
              <name>MODE10</name>
              <bitOffset>20</bitOffset>
              <bitWidth>2</bitWidth>
            </field>
            <field>
              <name>MODE11</name>
              <bitOffset>22</bitOffset>
              <bitWidth>2</bitWidth>
            </field>
            <field>
              <name>MODE12</name>
              <bitOffset>24</bitOffset>
              <bitWidth>2</bitWidth>
            </field>
            <field>
              <name>MODE13</name>
              <bitOffset>26</bitOffset>
              <bitWidth>2</bitWidth>
            </field>
            <field>
              <name>MODE14</name>
              <bitOffset>28</bitOffset>
              <bitWidth>2</bitWidth>
            </field>
            <field>
              <name>MODE15</name>
              <bitOffset>30</bitOffset>
              <bitWidth>2</bitWidth>
            </field>
          </fields>
        </register>
        <register>
          <name>OTYPER</name>
          <addressOffset>0x4</addressOffset>
          <size>0x20</size>
          <fields>
            <field>
              <name>OT0</name>
              <bitOffset>0</bitOffset>
              <bitWidth>1</bitWidth>
            </field>
            <field>
              <name>OT1</name>
              <bitOffset>1</bitOffset>
              <bitWidth>1</bitWidth>
            </field>
            <field>
              <name>OT2</name>
              <bitOffset>2</bitOffset>
              <bitWidth>1</bitWidth>
            </field>
            <field>
              <name>OT3</name>
              <bitOffset>3</bitOffset>
              <bitWidth>1</bitWidth>
            </field>
            <field>
              <name>OT4</name>
              <bitOffset>4</bitOffset>
              <bitWidth>1</bitWidth>
            </field>
            <field>
              <name>OT5</name>
              <bitOffset>5</bitOffset>
              <bitWidth>1</bitWidth>
            </field>
            <field>
              <name>OT6</name>
              <bitOffset>6</bitOffset>
              <bitWidth>1</bitWidth>
            </field>
            <field>
              <name>OT7</name>
              <bitOffset>7</bitOffset>
              <bitWidth>1</bitWidth>
            </field>
            <field>
              <name>OT8</name>
              <bitOffset>8</bitOffset>
              <bitWidth>1</bitWidth>
            </field>
            <field>
              <name>OT9</name>
              <bitOffset>9</bitOffset>
              <bitWidth>1</bitWidth>
            </field>
            <field>
              <name>OT10</name>
              <bitOffset>10</bitOffset>
              <bitWidth>1</bitWidth>
            </field>
            <field>
              <name>OT11</name>
              <bitOffset>11</bitOffset>
              <bitWidth>1</bitWidth>
            </field>
            <field>
              <name>OT12</name>
              <bitOffset>12</bitOffset>
              <bitWidth>1</bitWidth>
            </field>
            <field>
              <name>OT13</name>
              <bitOffset>13</bitOffset>
              <bitWidth>1</bitWidth>
            </field>
            <field>
              <name>OT14</name>
              <bitOffset>14</bitOffset>
              <bitWidth>1</bitWidth>
            </field>
            <field>
              <name>OT15</name>
              <bitOffset>15</bitOffset>
              <bitWidth>1</bitWidth>
            </field>
          </fields>
        </register>
        <register>
          <name>OSPEEDR</name>
          <addressOffset>0x8</addressOffset>
          <size>0x20</size>
          <fields>
            <field>
              <name>OSPEED0</name>
              <bitOffset>0</bitOffset>
              <bitWidth>2</bitWidth>
            </field>
            <field>
              <name>OSPEED1</name>
              <bitOffset>2</bitOffset>
              <bitWidth>2</bitWidth>
            </field>
            <field>
              <name>OSPEED2</name>
              <bitOffset>4</bitOffset>
              <bitWidth>2</bitWidth>
            </field>
            <field>
              <name>OSPEED3</name>
              <bitOffset>6</bitOffset>
              <bitWidth>2</bitWidth>
            </field>
            <field>
              <name>OSPEED4</name>
              <bitOffset>8</bitOffset>
              <bitWidth>2</bitWidth>
            </field>
            <field>
              <name>OSPEED5</name>
              <bitOffset>10</bitOffset>
              <bitWidth>2</bitWidth>
            </field>
            <field>
              <name>OSPEED6</name>
              <bitOffset>12</bitOffset>
              <bitWidth>2</bitWidth>
            </field>
            <field>
              <name>OSPEED7</name>
              <bitOffset>14</bitOffset>
              <bitWidth>2</bitWidth>
            </field>
            <field>
              <name>OSPEED8</name>
              <bitOffset>16</bitOffset>
              <bitWidth>2</bitWidth>
            </field>
            <field>
              <name>OSPEED9</name>
              <bitOffset>18</bitOffset>
              <bitWidth>2</bitWidth>
            </field>
            <field>
              <name>OSPEED10</name>
              <bitOffset>20</bitOffset>
              <bitWidth>2</bitWidth>
            </field>
            <field>
              <name>OSPEED11</name>
              <bitOffset>22</bitOffset>
              <bitWidth>2</bitWidth>
            </field>
            <field>
              <name>OSPEED12</name>
              <bitOffset>24</bitOffset>
              <bitWidth>2</bitWidth>
            </field>
            <field>
              <name>OSPEED13</name>
              <bitOffset>26</bitOffset>
              <bitWidth>2</bitWidth>
            </field>
            <field>
              <name>OSPEED14</name>
              <bitOffset>28</bitOffset>
              <bitWidth>2</bitWidth>
            </field>
            <field>
              <name>OSPEED15</name>
              <bitOffset>30</bitOffset>
              <bitWidth>2</bitWidth>
            </field>
          </fields>
        </register>
        <register>
          <name>PUPDR</name>
          <addressOffset>0xc</addressOffset>
          <size>0x20</size>
          <fields>
            <field>
              <name>PUPD0</name>
              <bitOffset>0</bitOffset>
              <bitWidth>2</bitWidth>
            </field>
            <field>
              <name>PUPD1</name>
              <bitOffset>2</bitOffset>
              <bitWidth>2</bitWidth>
            </field>
            <field>
              <name>PUPD2</name>
              <bitOffset>4</bitOffset>
              <bitWidth>2</bitWidth>
            </field>
            <field>
              <name>PUPD3</name>
              <bitOffset>6</bitOffset>
              <bitWidth>2</bitWidth>
            </field>
            <field>
              <name>PUPD4</name>
              <bitOffset>8</bitOffset>
              <bitWidth>2</bitWidth>
            </field>
            <field>
              <name>PUPD5</name>
              <bitOffset>10</bitOffset>
              <bitWidth>2</bitWidth>
            </field>
            <field>
              <name>PUPD6</name>
              <bitOffset>12</bitOffset>
              <bitWidth>2</bitWidth>
            </field>
            <field>
              <name>PUPD7</name>
              <bitOffset>14</bitOffset>
              <bitWidth>2</bitWidth>
            </field>
            <field>
              <name>PUPD8</name>
              <bitOffset>16</bitOffset>
              <bitWidth>2</bitWidth>
            </field>
            <field>
              <name>PUPD9</name>
              <bitOffset>18</bitOffset>
              <bitWidth>2</bitWidth>
            </field>
            <field>
              <name>PUPD10</name>
              <bitOffset>20</bitOffset>
              <bitWidth>2</bitWidth>
            </field>
            <field>
              <name>PUPD11</name>
              <bitOffset>22</bitOffset>
              <bitWidth>2</bitWidth>
            </field>
            <field>
              <name>PUPD12</name>
              <bitOffset>24</bitOffset>
              <bitWidth>2</bitWidth>
            </field>
            <field>
              <name>PUPD13</name>
              <bitOffset>26</bitOffset>
              <bitWidth>2</bitWidth>
            </field>
            <field>
              <name>PUPD14</name>
              <bitOffset>28</bitOffset>
              <bitWidth>2</bitWidth>
            </field>
            <field>
              <name>PUPD15</name>
              <bitOffset>30</bitOffset>
              <bitWidth>2</bitWidth>
            </field>
          </fields>
        </register>
        <register>
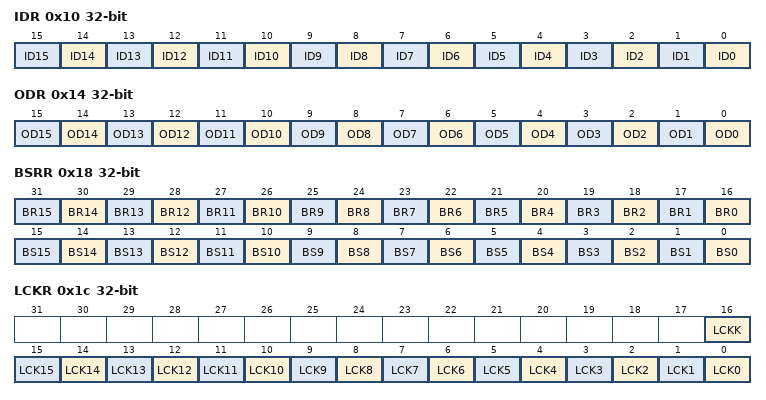
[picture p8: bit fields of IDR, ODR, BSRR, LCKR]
          <name>IDR</name>
          <addressOffset>0x10</addressOffset>
          <size>0x20</size>
          <fields>
            <field>
              <name>ID0</name>
              <bitOffset>0</bitOffset>
              <bitWidth>1</bitWidth>
            </field>
            <field>
              <name>ID1</name>
              <bitOffset>1</bitOffset>
              <bitWidth>1</bitWidth>
            </field>
            <field>
              <name>ID2</name>
              <bitOffset>2</bitOffset>
              <bitWidth>1</bitWidth>
            </field>
            <field>
              <name>ID3</name>
              <bitOffset>3</bitOffset>
              <bitWidth>1</bitWidth>
            </field>
            <field>
              <name>ID4</name>
              <bitOffset>4</bitOffset>
              <bitWidth>1</bitWidth>
            </field>
            <field>
              <name>ID5</name>
              <bitOffset>5</bitOffset>
              <bitWidth>1</bitWidth>
            </field>
            <field>
              <name>ID6</name>
              <bitOffset>6</bitOffset>
              <bitWidth>1</bitWidth>
            </field>
            <field>
              <name>ID7</name>
              <bitOffset>7</bitOffset>
              <bitWidth>1</bitWidth>
            </field>
            <field>
              <name>ID8</name>
              <bitOffset>8</bitOffset>
              <bitWidth>1</bitWidth>
            </field>
            <field>
              <name>ID9</name>
              <bitOffset>9</bitOffset>
              <bitWidth>1</bitWidth>
            </field>
            <field>
              <name>ID10</name>
              <bitOffset>10</bitOffset>
              <bitWidth>1</bitWidth>
            </field>
            <field>
              <name>ID11</name>
              <bitOffset>11</bitOffset>
              <bitWidth>1</bitWidth>
            </field>
            <field>
              <name>ID12</name>
              <bitOffset>12</bitOffset>
              <bitWidth>1</bitWidth>
            </field>
            <field>
              <name>ID13</name>
              <bitOffset>13</bitOffset>
              <bitWidth>1</bitWidth>
            </field>
            <field>
              <name>ID14</name>
              <bitOffset>14</bitOffset>
              <bitWidth>1</bitWidth>
            </field>
            <field>
              <name>ID15</name>
              <bitOffset>15</bitOffset>
              <bitWidth>1</bitWidth>
            </field>
          </fields>
        </register>
        <register>
          <name>ODR</name>
          <addressOffset>0x14</addressOffset>
          <size>0x20</size>
          <fields>
            <field>
              <name>OD0</name>
              <bitOffset>0</bitOffset>
              <bitWidth>1</bitWidth>
            </field>
            <field>
              <name>OD1</name>
              <bitOffset>1</bitOffset>
              <bitWidth>1</bitWidth>
            </field>
            <field>
              <name>OD2</name>
              <bitOffset>2</bitOffset>
              <bitWidth>1</bitWidth>
            </field>
            <field>
              <name>OD3</name>
              <bitOffset>3</bitOffset>
              <bitWidth>1</bitWidth>
            </field>
            <field>
              <name>OD4</name>
              <bitOffset>4</bitOffset>
              <bitWidth>1</bitWidth>
            </field>
            <field>
              <name>OD5</name>
              <bitOffset>5</bitOffset>
              <bitWidth>1</bitWidth>
            </field>
            <field>
              <name>OD6</name>
              <bitOffset>6</bitOffset>
              <bitWidth>1</bitWidth>
            </field>
            <field>
              <name>OD7</name>
              <bitOffset>7</bitOffset>
              <bitWidth>1</bitWidth>
            </field>
            <field>
              <name>OD8</name>
              <bitOffset>8</bitOffset>
              <bitWidth>1</bitWidth>
            </field>
            <field>
              <name>OD9</name>
              <bitOffset>9</bitOffset>
              <bitWidth>1</bitWidth>
            </field>
            <field>
              <name>OD10</name>
              <bitOffset>10</bitOffset>
              <bitWidth>1</bitWidth>
            </field>
            <field>
              <name>OD11</name>
              <bitOffset>11</bitOffset>
              <bitWidth>1</bitWidth>
            </field>
            <field>
              <name>OD12</name>
              <bitOffset>12</bitOffset>
              <bitWidth>1</bitWidth>
            </field>
            <field>
              <name>OD13</name>
              <bitOffset>13</bitOffset>
              <bitWidth>1</bitWidth>
            </field>
            <field>
              <name>OD14</name>
              <bitOffset>14</bitOffset>
              <bitWidth>1</bitWidth>
            </field>
            <field>
              <name>OD15</name>
              <bitOffset>15</bitOffset>
              <bitWidth>1</bitWidth>
            </field>
          </fields>
        </register>
        <register>
          <name>BSRR</name>
          <addressOffset>0x18</addressOffset>
          <size>0x20</size>
          <fields>
            <field>
              <name>BS0</name>
              <bitOffset>0</bitOffset>
              <bitWidth>1</bitWidth>
            </field>
            <field>
              <name>BS1</name>
              <bitOffset>1</bitOffset>
              <bitWidth>1</bitWidth>
            </field>
            <field>
              <name>BS2</name>
              <bitOffset>2</bitOffset>
              <bitWidth>1</bitWidth>
            </field>
            <field>
              <name>BS3</name>
              <bitOffset>3</bitOffset>
              <bitWidth>1</bitWidth>
            </field>
            <field>
              <name>BS4</name>
              <bitOffset>4</bitOffset>
              <bitWidth>1</bitWidth>
            </field>
            <field>
              <name>BS5</name>
              <bitOffset>5</bitOffset>
              <bitWidth>1</bitWidth>
            </field>
            <field>
              <name>BS6</name>
              <bitOffset>6</bitOffset>
              <bitWidth>1</bitWidth>
            </field>
            <field>
              <name>BS7</name>
              <bitOffset>7</bitOffset>
              <bitWidth>1</bitWidth>
            </field>
            <field>
              <name>BS8</name>
              <bitOffset>8</bitOffset>
              <bitWidth>1</bitWidth>
            </field>
            <field>
              <name>BS9</name>
              <bitOffset>9</bitOffset>
              <bitWidth>1</bitWidth>
            </field>
            <field>
              <name>BS10</name>
              <bitOffset>10</bitOffset>
              <bitWidth>1</bitWidth>
            </field>
            <field>
              <name>BS11</name>
              <bitOffset>11</bitOffset>
              <bitWidth>1</bitWidth>
            </field>
            <field>
              <name>BS12</name>
              <bitOffset>12</bitOffset>
              <bitWidth>1</bitWidth>
            </field>
            <field>
              <name>BS13</name>
              <bitOffset>13</bitOffset>
              <bitWidth>1</bitWidth>
            </field>
            <field>
              <name>BS14</name>
              <bitOffset>14</bitOffset>
              <bitWidth>1</bitWidth>
            </field>
            <field>
              <name>BS15</name>
              <bitOffset>15</bitOffset>
              <bitWidth>1</bitWidth>
            </field>
            <field>
              <name>BR0</name>
              <bitOffset>16</bitOffset>
              <bitWidth>1</bitWidth>
            </field>
            <field>
              <name>BR1</name>
              <bitOffset>17</bitOffset>
              <bitWidth>1</bitWidth>
            </field>
            <field>
              <name>BR2</name>
              <bitOffset>18</bitOffset>
              <bitWidth>1</bitWidth>
            </field>
            <field>
              <name>BR3</name>
              <bitOffset>19</bitOffset>
              <bitWidth>1</bitWidth>
            </field>
            <field>
              <name>BR4</name>
              <bitOffset>20</bitOffset>
              <bitWidth>1</bitWidth>
            </field>
            <field>
              <name>BR5</name>
              <bitOffset>21</bitOffset>
              <bitWidth>1</bitWidth>
            </field>
            <field>
              <name>BR6</name>
              <bitOffset>22</bitOffset>
              <bitWidth>1</bitWidth>
            </field>
            <field>
              <name>BR7</name>
              <bitOffset>23</bitOffset>
              <bitWidth>1</bitWidth>
            </field>
            <field>
              <name>BR8</name>
              <bitOffset>24</bitOffset>
              <bitWidth>1</bitWidth>
            </field>
            <field>
              <name>BR9</name>
              <bitOffset>25</bitOffset>
              <bitWidth>1</bitWidth>
            </field>
            <field>
              <name>BR10</name>
              <bitOffset>26</bitOffset>
              <bitWidth>1</bitWidth>
            </field>
            <field>
              <name>BR11</name>
              <bitOffset>27</bitOffset>
              <bitWidth>1</bitWidth>
            </field>
            <field>
              <name>BR12</name>
              <bitOffset>28</bitOffset>
              <bitWidth>1</bitWidth>
            </field>
            <field>
              <name>BR13</name>
              <bitOffset>29</bitOffset>
              <bitWidth>1</bitWidth>
            </field>
            <field>
              <name>BR14</name>
              <bitOffset>30</bitOffset>
              <bitWidth>1</bitWidth>
            </field>
            <field>
              <name>BR15</name>
              <bitOffset>31</bitOffset>
              <bitWidth>1</bitWidth>
            </field>
          </fields>
        </register>
        <register>
          <name>LCKR</name>
          <addressOffset>0x1c</addressOffset>
          <size>0x20</size>
          <fields>
            <field>
              <name>LCK0</name>
              <bitOffset>0</bitOffset>
              <bitWidth>1</bitWidth>
            </field>
            <field>
              <name>LCK1</name>
              <bitOffset>1</bitOffset>
              <bitWidth>1</bitWidth>
            </field>
            <field>
              <name>LCK2</name>
              <bitOffset>2</bitOffset>
              <bitWidth>1</bitWidth>
            </field>
            <field>
              <name>LCK3</name>
              <bitOffset>3</bitOffset>
              <bitWidth>1</bitWidth>
            </field>
            <field>
              <name>LCK4</name>
              <bitOffset>4</bitOffset>
              <bitWidth>1</bitWidth>
            </field>
            <field>
              <name>LCK5</name>
              <bitOffset>5</bitOffset>
              <bitWidth>1</bitWidth>
            </field>
            <field>
              <name>LCK6</name>
              <bitOffset>6</bitOffset>
              <bitWidth>1</bitWidth>
            </field>
            <field>
              <name>LCK7</name>
              <bitOffset>7</bitOffset>
              <bitWidth>1</bitWidth>
            </field>
            <field>
              <name>LCK8</name>
              <bitOffset>8</bitOffset>
              <bitWidth>1</bitWidth>
            </field>
            <field>
              <name>LCK9</name>
              <bitOffset>9</bitOffset>
              <bitWidth>1</bitWidth>
            </field>
            <field>
              <name>LCK10</name>
              <bitOffset>10</bitOffset>
              <bitWidth>1</bitWidth>
            </field>
            <field>
              <name>LCK11</name>
              <bitOffset>11</bitOffset>
              <bitWidth>1</bitWidth>
            </field>
            <field>
              <name>LCK12</name>
              <bitOffset>12</bitOffset>
              <bitWidth>1</bitWidth>
            </field>
            <field>
              <name>LCK13</name>
              <bitOffset>13</bitOffset>
              <bitWidth>1</bitWidth>
            </field>
            <field>
              <name>LCK14</name>
              <bitOffset>14</bitOffset>
              <bitWidth>1</bitWidth>
            </field>
            <field>
              <name>LCK15</name>
              <bitOffset>15</bitOffset>
              <bitWidth>1</bitWidth>
            </field>
            <field>
              <name>LCKK</name>
              <bitOffset>16</bitOffset>
              <bitWidth>1</bitWidth>
            </field>
          </fields>
        </register>
        <register>
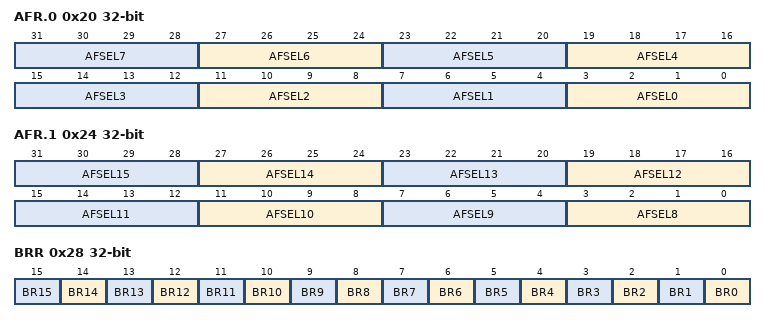
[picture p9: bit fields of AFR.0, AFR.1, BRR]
          <name>AFR.0</name>
          <addressOffset>0x20</addressOffset>
          <size>0x20</size>
          <fields>
            <field>
              <name>AFSEL0</name>
              <bitOffset>0</bitOffset>
              <bitWidth>4</bitWidth>
            </field>
            <field>
              <name>AFSEL1</name>
              <bitOffset>4</bitOffset>
              <bitWidth>4</bitWidth>
            </field>
            <field>
              <name>AFSEL2</name>
              <bitOffset>8</bitOffset>
              <bitWidth>4</bitWidth>
            </field>
            <field>
              <name>AFSEL3</name>
              <bitOffset>12</bitOffset>
              <bitWidth>4</bitWidth>
            </field>
            <field>
              <name>AFSEL4</name>
              <bitOffset>16</bitOffset>
              <bitWidth>4</bitWidth>
            </field>
            <field>
              <name>AFSEL5</name>
              <bitOffset>20</bitOffset>
              <bitWidth>4</bitWidth>
            </field>
            <field>
              <name>AFSEL6</name>
              <bitOffset>24</bitOffset>
              <bitWidth>4</bitWidth>
            </field>
            <field>
              <name>AFSEL7</name>
              <bitOffset>28</bitOffset>
              <bitWidth>4</bitWidth>
            </field>
          </fields>
        </register>
        <register>
          <name>AFR.1</name>
          <addressOffset>0x24</addressOffset>
          <size>0x20</size>
          <fields>
            <field>
              <name>AFSEL8</name>
              <bitOffset>0</bitOffset>
              <bitWidth>4</bitWidth>
            </field>
            <field>
              <name>AFSEL9</name>
              <bitOffset>4</bitOffset>
              <bitWidth>4</bitWidth>
            </field>
            <field>
              <name>AFSEL10</name>
              <bitOffset>8</bitOffset>
              <bitWidth>4</bitWidth>
            </field>
            <field>
              <name>AFSEL11</name>
              <bitOffset>12</bitOffset>
              <bitWidth>4</bitWidth>
            </field>
            <field>
              <name>AFSEL12</name>
              <bitOffset>16</bitOffset>
              <bitWidth>4</bitWidth>
            </field>
            <field>
              <name>AFSEL13</name>
              <bitOffset>20</bitOffset>
              <bitWidth>4</bitWidth>
            </field>
            <field>
              <name>AFSEL14</name>
              <bitOffset>24</bitOffset>
              <bitWidth>4</bitWidth>
            </field>
            <field>
              <name>AFSEL15</name>
              <bitOffset>28</bitOffset>
              <bitWidth>4</bitWidth>
            </field>
          </fields>
        </register>
        <register>
          <name>BRR</name>
          <addressOffset>0x28</addressOffset>
          <size>0x20</size>
          <fields>
            <field>
              <name>BR0</name>
              <bitOffset>0</bitOffset>
              <bitWidth>1</bitWidth>
            </field>
            <field>
              <name>BR1</name>
              <bitOffset>1</bitOffset>
              <bitWidth>1</bitWidth>
            </field>
            <field>
              <name>BR2</name>
              <bitOffset>2</bitOffset>
              <bitWidth>1</bitWidth>
            </field>
            <field>
              <name>BR3</name>
              <bitOffset>3</bitOffset>
              <bitWidth>1</bitWidth>
            </field>
            <field>
              <name>BR4</name>
              <bitOffset>4</bitOffset>
              <bitWidth>1</bitWidth>
            </field>
            <field>
              <name>BR5</name>
              <bitOffset>5</bitOffset>
              <bitWidth>1</bitWidth>
            </field>
            <field>
              <name>BR6</name>
              <bitOffset>6</bitOffset>
              <bitWidth>1</bitWidth>
            </field>
            <field>
              <name>BR7</name>
              <bitOffset>7</bitOffset>
              <bitWidth>1</bitWidth>
            </field>
            <field>
              <name>BR8</name>
              <bitOffset>8</bitOffset>
              <bitWidth>1</bitWidth>
            </field>
            <field>
              <name>BR9</name>
              <bitOffset>9</bitOffset>
              <bitWidth>1</bitWidth>
            </field>
            <field>
              <name>BR10</name>
              <bitOffset>10</bitOffset>
              <bitWidth>1</bitWidth>
            </field>
            <field>
              <name>BR11</name>
              <bitOffset>11</bitOffset>
              <bitWidth>1</bitWidth>
            </field>
            <field>
              <name>BR12</name>
              <bitOffset>12</bitOffset>
              <bitWidth>1</bitWidth>
            </field>
            <field>
              <name>BR13</name>
              <bitOffset>13</bitOffset>
              <bitWidth>1</bitWidth>
            </field>
            <field>
              <name>BR14</name>
              <bitOffset>14</bitOffset>
              <bitWidth>1</bitWidth>
            </field>
            <field>
              <name>BR15</name>
              <bitOffset>15</bitOffset>
              <bitWidth>1</bitWidth>
            </field>
          </fields>
        </register>
      </registers>
    </peripheral>
    <peripheral>
      <name>GPIOB</name>
      <baseAddress>0x48000400</baseAddress>
      <registers>
        <register>
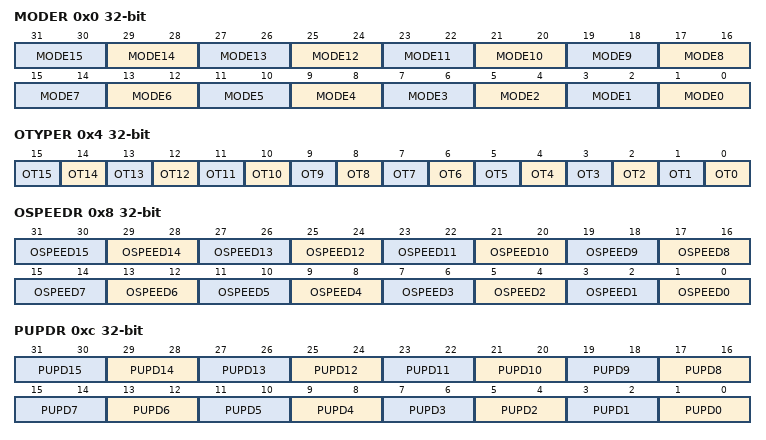
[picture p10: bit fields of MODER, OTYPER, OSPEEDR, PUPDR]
          <name>MODER</name>
          <addressOffset>0x0</addressOffset>
          <size>0x20</size>
          <fields>
            <field>
              <name>MODE0</name>
              <bitOffset>0</bitOffset>
              <bitWidth>2</bitWidth>
            </field>
            <field>
              <name>MODE1</name>
              <bitOffset>2</bitOffset>
              <bitWidth>2</bitWidth>
            </field>
            <field>
              <name>MODE2</name>
              <bitOffset>4</bitOffset>
              <bitWidth>2</bitWidth>
            </field>
            <field>
              <name>MODE3</name>
              <bitOffset>6</bitOffset>
              <bitWidth>2</bitWidth>
            </field>
            <field>
              <name>MODE4</name>
              <bitOffset>8</bitOffset>
              <bitWidth>2</bitWidth>
            </field>
            <field>
              <name>MODE5</name>
              <bitOffset>10</bitOffset>
              <bitWidth>2</bitWidth>
            </field>
            <field>
              <name>MODE6</name>
              <bitOffset>12</bitOffset>
              <bitWidth>2</bitWidth>
            </field>
            <field>
              <name>MODE7</name>
              <bitOffset>14</bitOffset>
              <bitWidth>2</bitWidth>
            </field>
            <field>
              <name>MODE8</name>
              <bitOffset>16</bitOffset>
              <bitWidth>2</bitWidth>
            </field>
            <field>
              <name>MODE9</name>
              <bitOffset>18</bitOffset>
              <bitWidth>2</bitWidth>
            </field>
            <field>
              <name>MODE10</name>
              <bitOffset>20</bitOffset>
              <bitWidth>2</bitWidth>
            </field>
            <field>
              <name>MODE11</name>
              <bitOffset>22</bitOffset>
              <bitWidth>2</bitWidth>
            </field>
            <field>
              <name>MODE12</name>
              <bitOffset>24</bitOffset>
              <bitWidth>2</bitWidth>
            </field>
            <field>
              <name>MODE13</name>
              <bitOffset>26</bitOffset>
              <bitWidth>2</bitWidth>
            </field>
            <field>
              <name>MODE14</name>
              <bitOffset>28</bitOffset>
              <bitWidth>2</bitWidth>
            </field>
            <field>
              <name>MODE15</name>
              <bitOffset>30</bitOffset>
              <bitWidth>2</bitWidth>
            </field>
          </fields>
        </register>
        <register>
          <name>OTYPER</name>
          <addressOffset>0x4</addressOffset>
          <size>0x20</size>
          <fields>
            <field>
              <name>OT0</name>
              <bitOffset>0</bitOffset>
              <bitWidth>1</bitWidth>
            </field>
            <field>
              <name>OT1</name>
              <bitOffset>1</bitOffset>
              <bitWidth>1</bitWidth>
            </field>
            <field>
              <name>OT2</name>
              <bitOffset>2</bitOffset>
              <bitWidth>1</bitWidth>
            </field>
            <field>
              <name>OT3</name>
              <bitOffset>3</bitOffset>
              <bitWidth>1</bitWidth>
            </field>
            <field>
              <name>OT4</name>
              <bitOffset>4</bitOffset>
              <bitWidth>1</bitWidth>
            </field>
            <field>
              <name>OT5</name>
              <bitOffset>5</bitOffset>
              <bitWidth>1</bitWidth>
            </field>
            <field>
              <name>OT6</name>
              <bitOffset>6</bitOffset>
              <bitWidth>1</bitWidth>
            </field>
            <field>
              <name>OT7</name>
              <bitOffset>7</bitOffset>
              <bitWidth>1</bitWidth>
            </field>
            <field>
              <name>OT8</name>
              <bitOffset>8</bitOffset>
              <bitWidth>1</bitWidth>
            </field>
            <field>
              <name>OT9</name>
              <bitOffset>9</bitOffset>
              <bitWidth>1</bitWidth>
            </field>
            <field>
              <name>OT10</name>
              <bitOffset>10</bitOffset>
              <bitWidth>1</bitWidth>
            </field>
            <field>
              <name>OT11</name>
              <bitOffset>11</bitOffset>
              <bitWidth>1</bitWidth>
            </field>
            <field>
              <name>OT12</name>
              <bitOffset>12</bitOffset>
              <bitWidth>1</bitWidth>
            </field>
            <field>
              <name>OT13</name>
              <bitOffset>13</bitOffset>
              <bitWidth>1</bitWidth>
            </field>
            <field>
              <name>OT14</name>
              <bitOffset>14</bitOffset>
              <bitWidth>1</bitWidth>
            </field>
            <field>
              <name>OT15</name>
              <bitOffset>15</bitOffset>
              <bitWidth>1</bitWidth>
            </field>
          </fields>
        </register>
        <register>
          <name>OSPEEDR</name>
          <addressOffset>0x8</addressOffset>
          <size>0x20</size>
          <fields>
            <field>
              <name>OSPEED0</name>
              <bitOffset>0</bitOffset>
              <bitWidth>2</bitWidth>
            </field>
            <field>
              <name>OSPEED1</name>
              <bitOffset>2</bitOffset>
              <bitWidth>2</bitWidth>
            </field>
            <field>
              <name>OSPEED2</name>
              <bitOffset>4</bitOffset>
              <bitWidth>2</bitWidth>
            </field>
            <field>
              <name>OSPEED3</name>
              <bitOffset>6</bitOffset>
              <bitWidth>2</bitWidth>
            </field>
            <field>
              <name>OSPEED4</name>
              <bitOffset>8</bitOffset>
              <bitWidth>2</bitWidth>
            </field>
            <field>
              <name>OSPEED5</name>
              <bitOffset>10</bitOffset>
              <bitWidth>2</bitWidth>
            </field>
            <field>
              <name>OSPEED6</name>
              <bitOffset>12</bitOffset>
              <bitWidth>2</bitWidth>
            </field>
            <field>
              <name>OSPEED7</name>
              <bitOffset>14</bitOffset>
              <bitWidth>2</bitWidth>
            </field>
            <field>
              <name>OSPEED8</name>
              <bitOffset>16</bitOffset>
              <bitWidth>2</bitWidth>
            </field>
            <field>
              <name>OSPEED9</name>
              <bitOffset>18</bitOffset>
              <bitWidth>2</bitWidth>
            </field>
            <field>
              <name>OSPEED10</name>
              <bitOffset>20</bitOffset>
              <bitWidth>2</bitWidth>
            </field>
            <field>
              <name>OSPEED11</name>
              <bitOffset>22</bitOffset>
              <bitWidth>2</bitWidth>
            </field>
            <field>
              <name>OSPEED12</name>
              <bitOffset>24</bitOffset>
              <bitWidth>2</bitWidth>
            </field>
            <field>
              <name>OSPEED13</name>
              <bitOffset>26</bitOffset>
              <bitWidth>2</bitWidth>
            </field>
            <field>
              <name>OSPEED14</name>
              <bitOffset>28</bitOffset>
              <bitWidth>2</bitWidth>
            </field>
            <field>
              <name>OSPEED15</name>
              <bitOffset>30</bitOffset>
              <bitWidth>2</bitWidth>
            </field>
          </fields>
        </register>
        <register>
          <name>PUPDR</name>
          <addressOffset>0xc</addressOffset>
          <size>0x20</size>
          <fields>
            <field>
              <name>PUPD0</name>
              <bitOffset>0</bitOffset>
              <bitWidth>2</bitWidth>
            </field>
            <field>
              <name>PUPD1</name>
              <bitOffset>2</bitOffset>
              <bitWidth>2</bitWidth>
            </field>
            <field>
              <name>PUPD2</name>
              <bitOffset>4</bitOffset>
              <bitWidth>2</bitWidth>
            </field>
            <field>
              <name>PUPD3</name>
              <bitOffset>6</bitOffset>
              <bitWidth>2</bitWidth>
            </field>
            <field>
              <name>PUPD4</name>
              <bitOffset>8</bitOffset>
              <bitWidth>2</bitWidth>
            </field>
            <field>
              <name>PUPD5</name>
              <bitOffset>10</bitOffset>
              <bitWidth>2</bitWidth>
            </field>
            <field>
              <name>PUPD6</name>
              <bitOffset>12</bitOffset>
              <bitWidth>2</bitWidth>
            </field>
            <field>
              <name>PUPD7</name>
              <bitOffset>14</bitOffset>
              <bitWidth>2</bitWidth>
            </field>
            <field>
              <name>PUPD8</name>
              <bitOffset>16</bitOffset>
              <bitWidth>2</bitWidth>
            </field>
            <field>
              <name>PUPD9</name>
              <bitOffset>18</bitOffset>
              <bitWidth>2</bitWidth>
            </field>
            <field>
              <name>PUPD10</name>
              <bitOffset>20</bitOffset>
              <bitWidth>2</bitWidth>
            </field>
            <field>
              <name>PUPD11</name>
              <bitOffset>22</bitOffset>
              <bitWidth>2</bitWidth>
            </field>
            <field>
              <name>PUPD12</name>
              <bitOffset>24</bitOffset>
              <bitWidth>2</bitWidth>
            </field>
            <field>
              <name>PUPD13</name>
              <bitOffset>26</bitOffset>
              <bitWidth>2</bitWidth>
            </field>
            <field>
              <name>PUPD14</name>
              <bitOffset>28</bitOffset>
              <bitWidth>2</bitWidth>
            </field>
            <field>
              <name>PUPD15</name>
              <bitOffset>30</bitOffset>
              <bitWidth>2</bitWidth>
            </field>
          </fields>
        </register>
        <register>
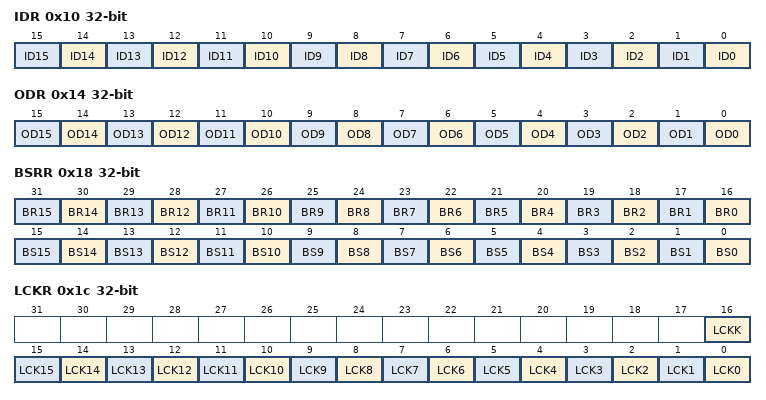
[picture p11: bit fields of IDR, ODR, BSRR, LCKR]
          <name>IDR</name>
          <addressOffset>0x10</addressOffset>
          <size>0x20</size>
          <fields>
            <field>
              <name>ID0</name>
              <bitOffset>0</bitOffset>
              <bitWidth>1</bitWidth>
            </field>
            <field>
              <name>ID1</name>
              <bitOffset>1</bitOffset>
              <bitWidth>1</bitWidth>
            </field>
            <field>
              <name>ID2</name>
              <bitOffset>2</bitOffset>
              <bitWidth>1</bitWidth>
            </field>
            <field>
              <name>ID3</name>
              <bitOffset>3</bitOffset>
              <bitWidth>1</bitWidth>
            </field>
            <field>
              <name>ID4</name>
              <bitOffset>4</bitOffset>
              <bitWidth>1</bitWidth>
            </field>
            <field>
              <name>ID5</name>
              <bitOffset>5</bitOffset>
              <bitWidth>1</bitWidth>
            </field>
            <field>
              <name>ID6</name>
              <bitOffset>6</bitOffset>
              <bitWidth>1</bitWidth>
            </field>
            <field>
              <name>ID7</name>
              <bitOffset>7</bitOffset>
              <bitWidth>1</bitWidth>
            </field>
            <field>
              <name>ID8</name>
              <bitOffset>8</bitOffset>
              <bitWidth>1</bitWidth>
            </field>
            <field>
              <name>ID9</name>
              <bitOffset>9</bitOffset>
              <bitWidth>1</bitWidth>
            </field>
            <field>
              <name>ID10</name>
              <bitOffset>10</bitOffset>
              <bitWidth>1</bitWidth>
            </field>
            <field>
              <name>ID11</name>
              <bitOffset>11</bitOffset>
              <bitWidth>1</bitWidth>
            </field>
            <field>
              <name>ID12</name>
              <bitOffset>12</bitOffset>
              <bitWidth>1</bitWidth>
            </field>
            <field>
              <name>ID13</name>
              <bitOffset>13</bitOffset>
              <bitWidth>1</bitWidth>
            </field>
            <field>
              <name>ID14</name>
              <bitOffset>14</bitOffset>
              <bitWidth>1</bitWidth>
            </field>
            <field>
              <name>ID15</name>
              <bitOffset>15</bitOffset>
              <bitWidth>1</bitWidth>
            </field>
          </fields>
        </register>
        <register>
          <name>ODR</name>
          <addressOffset>0x14</addressOffset>
          <size>0x20</size>
          <fields>
            <field>
              <name>OD0</name>
              <bitOffset>0</bitOffset>
              <bitWidth>1</bitWidth>
            </field>
            <field>
              <name>OD1</name>
              <bitOffset>1</bitOffset>
              <bitWidth>1</bitWidth>
            </field>
            <field>
              <name>OD2</name>
              <bitOffset>2</bitOffset>
              <bitWidth>1</bitWidth>
            </field>
            <field>
              <name>OD3</name>
              <bitOffset>3</bitOffset>
              <bitWidth>1</bitWidth>
            </field>
            <field>
              <name>OD4</name>
              <bitOffset>4</bitOffset>
              <bitWidth>1</bitWidth>
            </field>
            <field>
              <name>OD5</name>
              <bitOffset>5</bitOffset>
              <bitWidth>1</bitWidth>
            </field>
            <field>
              <name>OD6</name>
              <bitOffset>6</bitOffset>
              <bitWidth>1</bitWidth>
            </field>
            <field>
              <name>OD7</name>
              <bitOffset>7</bitOffset>
              <bitWidth>1</bitWidth>
            </field>
            <field>
              <name>OD8</name>
              <bitOffset>8</bitOffset>
              <bitWidth>1</bitWidth>
            </field>
            <field>
              <name>OD9</name>
              <bitOffset>9</bitOffset>
              <bitWidth>1</bitWidth>
            </field>
            <field>
              <name>OD10</name>
              <bitOffset>10</bitOffset>
              <bitWidth>1</bitWidth>
            </field>
            <field>
              <name>OD11</name>
              <bitOffset>11</bitOffset>
              <bitWidth>1</bitWidth>
            </field>
            <field>
              <name>OD12</name>
              <bitOffset>12</bitOffset>
              <bitWidth>1</bitWidth>
            </field>
            <field>
              <name>OD13</name>
              <bitOffset>13</bitOffset>
              <bitWidth>1</bitWidth>
            </field>
            <field>
              <name>OD14</name>
              <bitOffset>14</bitOffset>
              <bitWidth>1</bitWidth>
            </field>
            <field>
              <name>OD15</name>
              <bitOffset>15</bitOffset>
              <bitWidth>1</bitWidth>
            </field>
          </fields>
        </register>
        <register>
          <name>BSRR</name>
          <addressOffset>0x18</addressOffset>
          <size>0x20</size>
          <fields>
            <field>
              <name>BS0</name>
              <bitOffset>0</bitOffset>
              <bitWidth>1</bitWidth>
            </field>
            <field>
              <name>BS1</name>
              <bitOffset>1</bitOffset>
              <bitWidth>1</bitWidth>
            </field>
            <field>
              <name>BS2</name>
              <bitOffset>2</bitOffset>
              <bitWidth>1</bitWidth>
            </field>
            <field>
              <name>BS3</name>
              <bitOffset>3</bitOffset>
              <bitWidth>1</bitWidth>
            </field>
            <field>
              <name>BS4</name>
              <bitOffset>4</bitOffset>
              <bitWidth>1</bitWidth>
            </field>
            <field>
              <name>BS5</name>
              <bitOffset>5</bitOffset>
              <bitWidth>1</bitWidth>
            </field>
            <field>
              <name>BS6</name>
              <bitOffset>6</bitOffset>
              <bitWidth>1</bitWidth>
            </field>
            <field>
              <name>BS7</name>
              <bitOffset>7</bitOffset>
              <bitWidth>1</bitWidth>
            </field>
            <field>
              <name>BS8</name>
              <bitOffset>8</bitOffset>
              <bitWidth>1</bitWidth>
            </field>
            <field>
              <name>BS9</name>
              <bitOffset>9</bitOffset>
              <bitWidth>1</bitWidth>
            </field>
            <field>
              <name>BS10</name>
              <bitOffset>10</bitOffset>
              <bitWidth>1</bitWidth>
            </field>
            <field>
              <name>BS11</name>
              <bitOffset>11</bitOffset>
              <bitWidth>1</bitWidth>
            </field>
            <field>
              <name>BS12</name>
              <bitOffset>12</bitOffset>
              <bitWidth>1</bitWidth>
            </field>
            <field>
              <name>BS13</name>
              <bitOffset>13</bitOffset>
              <bitWidth>1</bitWidth>
            </field>
            <field>
              <name>BS14</name>
              <bitOffset>14</bitOffset>
              <bitWidth>1</bitWidth>
            </field>
            <field>
              <name>BS15</name>
              <bitOffset>15</bitOffset>
              <bitWidth>1</bitWidth>
            </field>
            <field>
              <name>BR0</name>
              <bitOffset>16</bitOffset>
              <bitWidth>1</bitWidth>
            </field>
            <field>
              <name>BR1</name>
              <bitOffset>17</bitOffset>
              <bitWidth>1</bitWidth>
            </field>
            <field>
              <name>BR2</name>
              <bitOffset>18</bitOffset>
              <bitWidth>1</bitWidth>
            </field>
            <field>
              <name>BR3</name>
              <bitOffset>19</bitOffset>
              <bitWidth>1</bitWidth>
            </field>
            <field>
              <name>BR4</name>
              <bitOffset>20</bitOffset>
              <bitWidth>1</bitWidth>
            </field>
            <field>
              <name>BR5</name>
              <bitOffset>21</bitOffset>
              <bitWidth>1</bitWidth>
            </field>
            <field>
              <name>BR6</name>
              <bitOffset>22</bitOffset>
              <bitWidth>1</bitWidth>
            </field>
            <field>
              <name>BR7</name>
              <bitOffset>23</bitOffset>
              <bitWidth>1</bitWidth>
            </field>
            <field>
              <name>BR8</name>
              <bitOffset>24</bitOffset>
              <bitWidth>1</bitWidth>
            </field>
            <field>
              <name>BR9</name>
              <bitOffset>25</bitOffset>
              <bitWidth>1</bitWidth>
            </field>
            <field>
              <name>BR10</name>
              <bitOffset>26</bitOffset>
              <bitWidth>1</bitWidth>
            </field>
            <field>
              <name>BR11</name>
              <bitOffset>27</bitOffset>
              <bitWidth>1</bitWidth>
            </field>
            <field>
              <name>BR12</name>
              <bitOffset>28</bitOffset>
              <bitWidth>1</bitWidth>
            </field>
            <field>
              <name>BR13</name>
              <bitOffset>29</bitOffset>
              <bitWidth>1</bitWidth>
            </field>
            <field>
              <name>BR14</name>
              <bitOffset>30</bitOffset>
              <bitWidth>1</bitWidth>
            </field>
            <field>
              <name>BR15</name>
              <bitOffset>31</bitOffset>
              <bitWidth>1</bitWidth>
            </field>
          </fields>
        </register>
        <register>
          <name>LCKR</name>
          <addressOffset>0x1c</addressOffset>
          <size>0x20</size>
          <fields>
            <field>
              <name>LCK0</name>
              <bitOffset>0</bitOffset>
              <bitWidth>1</bitWidth>
            </field>
            <field>
              <name>LCK1</name>
              <bitOffset>1</bitOffset>
              <bitWidth>1</bitWidth>
            </field>
            <field>
              <name>LCK2</name>
              <bitOffset>2</bitOffset>
              <bitWidth>1</bitWidth>
            </field>
            <field>
              <name>LCK3</name>
              <bitOffset>3</bitOffset>
              <bitWidth>1</bitWidth>
            </field>
            <field>
              <name>LCK4</name>
              <bitOffset>4</bitOffset>
              <bitWidth>1</bitWidth>
            </field>
            <field>
              <name>LCK5</name>
              <bitOffset>5</bitOffset>
              <bitWidth>1</bitWidth>
            </field>
            <field>
              <name>LCK6</name>
              <bitOffset>6</bitOffset>
              <bitWidth>1</bitWidth>
            </field>
            <field>
              <name>LCK7</name>
              <bitOffset>7</bitOffset>
              <bitWidth>1</bitWidth>
            </field>
            <field>
              <name>LCK8</name>
              <bitOffset>8</bitOffset>
              <bitWidth>1</bitWidth>
            </field>
            <field>
              <name>LCK9</name>
              <bitOffset>9</bitOffset>
              <bitWidth>1</bitWidth>
            </field>
            <field>
              <name>LCK10</name>
              <bitOffset>10</bitOffset>
              <bitWidth>1</bitWidth>
            </field>
            <field>
              <name>LCK11</name>
              <bitOffset>11</bitOffset>
              <bitWidth>1</bitWidth>
            </field>
            <field>
              <name>LCK12</name>
              <bitOffset>12</bitOffset>
              <bitWidth>1</bitWidth>
            </field>
            <field>
              <name>LCK13</name>
              <bitOffset>13</bitOffset>
              <bitWidth>1</bitWidth>
            </field>
            <field>
              <name>LCK14</name>
              <bitOffset>14</bitOffset>
              <bitWidth>1</bitWidth>
            </field>
            <field>
              <name>LCK15</name>
              <bitOffset>15</bitOffset>
              <bitWidth>1</bitWidth>
            </field>
            <field>
              <name>LCKK</name>
              <bitOffset>16</bitOffset>
              <bitWidth>1</bitWidth>
            </field>
          </fields>
        </register>
        <register>
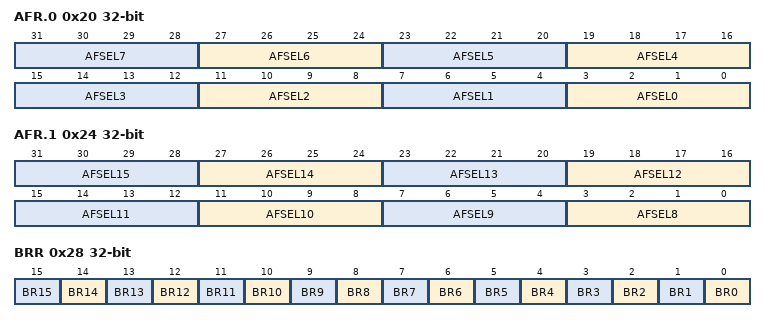
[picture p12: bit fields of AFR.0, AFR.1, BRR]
          <name>AFR.0</name>
          <addressOffset>0x20</addressOffset>
          <size>0x20</size>
          <fields>
            <field>
              <name>AFSEL0</name>
              <bitOffset>0</bitOffset>
              <bitWidth>4</bitWidth>
            </field>
            <field>
              <name>AFSEL1</name>
              <bitOffset>4</bitOffset>
              <bitWidth>4</bitWidth>
            </field>
            <field>
              <name>AFSEL2</name>
              <bitOffset>8</bitOffset>
              <bitWidth>4</bitWidth>
            </field>
            <field>
              <name>AFSEL3</name>
              <bitOffset>12</bitOffset>
              <bitWidth>4</bitWidth>
            </field>
            <field>
              <name>AFSEL4</name>
              <bitOffset>16</bitOffset>
              <bitWidth>4</bitWidth>
            </field>
            <field>
              <name>AFSEL5</name>
              <bitOffset>20</bitOffset>
              <bitWidth>4</bitWidth>
            </field>
            <field>
              <name>AFSEL6</name>
              <bitOffset>24</bitOffset>
              <bitWidth>4</bitWidth>
            </field>
            <field>
              <name>AFSEL7</name>
              <bitOffset>28</bitOffset>
              <bitWidth>4</bitWidth>
            </field>
          </fields>
        </register>
        <register>
          <name>AFR.1</name>
          <addressOffset>0x24</addressOffset>
          <size>0x20</size>
          <fields>
            <field>
              <name>AFSEL8</name>
              <bitOffset>0</bitOffset>
              <bitWidth>4</bitWidth>
            </field>
            <field>
              <name>AFSEL9</name>
              <bitOffset>4</bitOffset>
              <bitWidth>4</bitWidth>
            </field>
            <field>
              <name>AFSEL10</name>
              <bitOffset>8</bitOffset>
              <bitWidth>4</bitWidth>
            </field>
            <field>
              <name>AFSEL11</name>
              <bitOffset>12</bitOffset>
              <bitWidth>4</bitWidth>
            </field>
            <field>
              <name>AFSEL12</name>
              <bitOffset>16</bitOffset>
              <bitWidth>4</bitWidth>
            </field>
            <field>
              <name>AFSEL13</name>
              <bitOffset>20</bitOffset>
              <bitWidth>4</bitWidth>
            </field>
            <field>
              <name>AFSEL14</name>
              <bitOffset>24</bitOffset>
              <bitWidth>4</bitWidth>
            </field>
            <field>
              <name>AFSEL15</name>
              <bitOffset>28</bitOffset>
              <bitWidth>4</bitWidth>
            </field>
          </fields>
        </register>
        <register>
          <name>BRR</name>
          <addressOffset>0x28</addressOffset>
          <size>0x20</size>
          <fields>
            <field>
              <name>BR0</name>
              <bitOffset>0</bitOffset>
              <bitWidth>1</bitWidth>
            </field>
            <field>
              <name>BR1</name>
              <bitOffset>1</bitOffset>
              <bitWidth>1</bitWidth>
            </field>
            <field>
              <name>BR2</name>
              <bitOffset>2</bitOffset>
              <bitWidth>1</bitWidth>
            </field>
            <field>
              <name>BR3</name>
              <bitOffset>3</bitOffset>
              <bitWidth>1</bitWidth>
            </field>
            <field>
              <name>BR4</name>
              <bitOffset>4</bitOffset>
              <bitWidth>1</bitWidth>
            </field>
            <field>
              <name>BR5</name>
              <bitOffset>5</bitOffset>
              <bitWidth>1</bitWidth>
            </field>
            <field>
              <name>BR6</name>
              <bitOffset>6</bitOffset>
              <bitWidth>1</bitWidth>
            </field>
            <field>
              <name>BR7</name>
              <bitOffset>7</bitOffset>
              <bitWidth>1</bitWidth>
            </field>
            <field>
              <name>BR8</name>
              <bitOffset>8</bitOffset>
              <bitWidth>1</bitWidth>
            </field>
            <field>
              <name>BR9</name>
              <bitOffset>9</bitOffset>
              <bitWidth>1</bitWidth>
            </field>
            <field>
              <name>BR10</name>
              <bitOffset>10</bitOffset>
              <bitWidth>1</bitWidth>
            </field>
            <field>
              <name>BR11</name>
              <bitOffset>11</bitOffset>
              <bitWidth>1</bitWidth>
            </field>
            <field>
              <name>BR12</name>
              <bitOffset>12</bitOffset>
              <bitWidth>1</bitWidth>
            </field>
            <field>
              <name>BR13</name>
              <bitOffset>13</bitOffset>
              <bitWidth>1</bitWidth>
            </field>
            <field>
              <name>BR14</name>
              <bitOffset>14</bitOffset>
              <bitWidth>1</bitWidth>
            </field>
            <field>
              <name>BR15</name>
              <bitOffset>15</bitOffset>
              <bitWidth>1</bitWidth>
            </field>
          </fields>
        </register>
      </registers>
    </peripheral>
    <peripheral>
      <name>GPIOC</name>
      <baseAddress>0x48000800</baseAddress>
      <registers>
        <register>
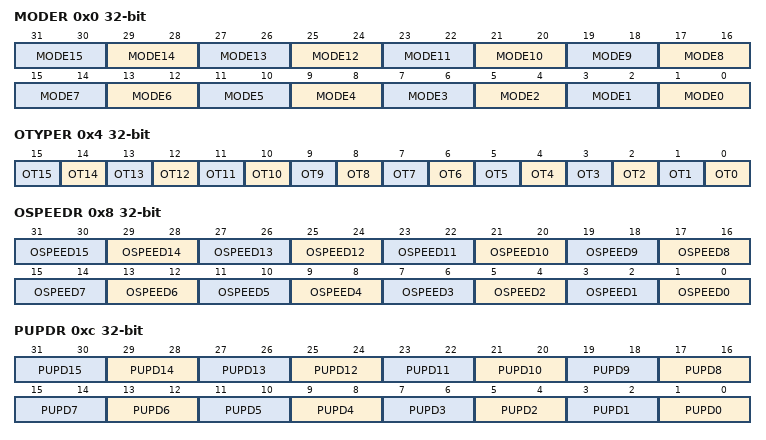
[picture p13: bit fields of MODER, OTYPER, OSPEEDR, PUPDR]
          <name>MODER</name>
          <addressOffset>0x0</addressOffset>
          <size>0x20</size>
          <fields>
            <field>
              <name>MODE0</name>
              <bitOffset>0</bitOffset>
              <bitWidth>2</bitWidth>
            </field>
            <field>
              <name>MODE1</name>
              <bitOffset>2</bitOffset>
              <bitWidth>2</bitWidth>
            </field>
            <field>
              <name>MODE2</name>
              <bitOffset>4</bitOffset>
              <bitWidth>2</bitWidth>
            </field>
            <field>
              <name>MODE3</name>
              <bitOffset>6</bitOffset>
              <bitWidth>2</bitWidth>
            </field>
            <field>
              <name>MODE4</name>
              <bitOffset>8</bitOffset>
              <bitWidth>2</bitWidth>
            </field>
            <field>
              <name>MODE5</name>
              <bitOffset>10</bitOffset>
              <bitWidth>2</bitWidth>
            </field>
            <field>
              <name>MODE6</name>
              <bitOffset>12</bitOffset>
              <bitWidth>2</bitWidth>
            </field>
            <field>
              <name>MODE7</name>
              <bitOffset>14</bitOffset>
              <bitWidth>2</bitWidth>
            </field>
            <field>
              <name>MODE8</name>
              <bitOffset>16</bitOffset>
              <bitWidth>2</bitWidth>
            </field>
            <field>
              <name>MODE9</name>
              <bitOffset>18</bitOffset>
              <bitWidth>2</bitWidth>
            </field>
            <field>
              <name>MODE10</name>
              <bitOffset>20</bitOffset>
              <bitWidth>2</bitWidth>
            </field>
            <field>
              <name>MODE11</name>
              <bitOffset>22</bitOffset>
              <bitWidth>2</bitWidth>
            </field>
            <field>
              <name>MODE12</name>
              <bitOffset>24</bitOffset>
              <bitWidth>2</bitWidth>
            </field>
            <field>
              <name>MODE13</name>
              <bitOffset>26</bitOffset>
              <bitWidth>2</bitWidth>
            </field>
            <field>
              <name>MODE14</name>
              <bitOffset>28</bitOffset>
              <bitWidth>2</bitWidth>
            </field>
            <field>
              <name>MODE15</name>
              <bitOffset>30</bitOffset>
              <bitWidth>2</bitWidth>
            </field>
          </fields>
        </register>
        <register>
          <name>OTYPER</name>
          <addressOffset>0x4</addressOffset>
          <size>0x20</size>
          <fields>
            <field>
              <name>OT0</name>
              <bitOffset>0</bitOffset>
              <bitWidth>1</bitWidth>
            </field>
            <field>
              <name>OT1</name>
              <bitOffset>1</bitOffset>
              <bitWidth>1</bitWidth>
            </field>
            <field>
              <name>OT2</name>
              <bitOffset>2</bitOffset>
              <bitWidth>1</bitWidth>
            </field>
            <field>
              <name>OT3</name>
              <bitOffset>3</bitOffset>
              <bitWidth>1</bitWidth>
            </field>
            <field>
              <name>OT4</name>
              <bitOffset>4</bitOffset>
              <bitWidth>1</bitWidth>
            </field>
            <field>
              <name>OT5</name>
              <bitOffset>5</bitOffset>
              <bitWidth>1</bitWidth>
            </field>
            <field>
              <name>OT6</name>
              <bitOffset>6</bitOffset>
              <bitWidth>1</bitWidth>
            </field>
            <field>
              <name>OT7</name>
              <bitOffset>7</bitOffset>
              <bitWidth>1</bitWidth>
            </field>
            <field>
              <name>OT8</name>
              <bitOffset>8</bitOffset>
              <bitWidth>1</bitWidth>
            </field>
            <field>
              <name>OT9</name>
              <bitOffset>9</bitOffset>
              <bitWidth>1</bitWidth>
            </field>
            <field>
              <name>OT10</name>
              <bitOffset>10</bitOffset>
              <bitWidth>1</bitWidth>
            </field>
            <field>
              <name>OT11</name>
              <bitOffset>11</bitOffset>
              <bitWidth>1</bitWidth>
            </field>
            <field>
              <name>OT12</name>
              <bitOffset>12</bitOffset>
              <bitWidth>1</bitWidth>
            </field>
            <field>
              <name>OT13</name>
              <bitOffset>13</bitOffset>
              <bitWidth>1</bitWidth>
            </field>
            <field>
              <name>OT14</name>
              <bitOffset>14</bitOffset>
              <bitWidth>1</bitWidth>
            </field>
            <field>
              <name>OT15</name>
              <bitOffset>15</bitOffset>
              <bitWidth>1</bitWidth>
            </field>
          </fields>
        </register>
        <register>
          <name>OSPEEDR</name>
          <addressOffset>0x8</addressOffset>
          <size>0x20</size>
          <fields>
            <field>
              <name>OSPEED0</name>
              <bitOffset>0</bitOffset>
              <bitWidth>2</bitWidth>
            </field>
            <field>
              <name>OSPEED1</name>
              <bitOffset>2</bitOffset>
              <bitWidth>2</bitWidth>
            </field>
            <field>
              <name>OSPEED2</name>
              <bitOffset>4</bitOffset>
              <bitWidth>2</bitWidth>
            </field>
            <field>
              <name>OSPEED3</name>
              <bitOffset>6</bitOffset>
              <bitWidth>2</bitWidth>
            </field>
            <field>
              <name>OSPEED4</name>
              <bitOffset>8</bitOffset>
              <bitWidth>2</bitWidth>
            </field>
            <field>
              <name>OSPEED5</name>
              <bitOffset>10</bitOffset>
              <bitWidth>2</bitWidth>
            </field>
            <field>
              <name>OSPEED6</name>
              <bitOffset>12</bitOffset>
              <bitWidth>2</bitWidth>
            </field>
            <field>
              <name>OSPEED7</name>
              <bitOffset>14</bitOffset>
              <bitWidth>2</bitWidth>
            </field>
            <field>
              <name>OSPEED8</name>
              <bitOffset>16</bitOffset>
              <bitWidth>2</bitWidth>
            </field>
            <field>
              <name>OSPEED9</name>
              <bitOffset>18</bitOffset>
              <bitWidth>2</bitWidth>
            </field>
            <field>
              <name>OSPEED10</name>
              <bitOffset>20</bitOffset>
              <bitWidth>2</bitWidth>
            </field>
            <field>
              <name>OSPEED11</name>
              <bitOffset>22</bitOffset>
              <bitWidth>2</bitWidth>
            </field>
            <field>
              <name>OSPEED12</name>
              <bitOffset>24</bitOffset>
              <bitWidth>2</bitWidth>
            </field>
            <field>
              <name>OSPEED13</name>
              <bitOffset>26</bitOffset>
              <bitWidth>2</bitWidth>
            </field>
            <field>
              <name>OSPEED14</name>
              <bitOffset>28</bitOffset>
              <bitWidth>2</bitWidth>
            </field>
            <field>
              <name>OSPEED15</name>
              <bitOffset>30</bitOffset>
              <bitWidth>2</bitWidth>
            </field>
          </fields>
        </register>
        <register>
          <name>PUPDR</name>
          <addressOffset>0xc</addressOffset>
          <size>0x20</size>
          <fields>
            <field>
              <name>PUPD0</name>
              <bitOffset>0</bitOffset>
              <bitWidth>2</bitWidth>
            </field>
            <field>
              <name>PUPD1</name>
              <bitOffset>2</bitOffset>
              <bitWidth>2</bitWidth>
            </field>
            <field>
              <name>PUPD2</name>
              <bitOffset>4</bitOffset>
              <bitWidth>2</bitWidth>
            </field>
            <field>
              <name>PUPD3</name>
              <bitOffset>6</bitOffset>
              <bitWidth>2</bitWidth>
            </field>
            <field>
              <name>PUPD4</name>
              <bitOffset>8</bitOffset>
              <bitWidth>2</bitWidth>
            </field>
            <field>
              <name>PUPD5</name>
              <bitOffset>10</bitOffset>
              <bitWidth>2</bitWidth>
            </field>
            <field>
              <name>PUPD6</name>
              <bitOffset>12</bitOffset>
              <bitWidth>2</bitWidth>
            </field>
            <field>
              <name>PUPD7</name>
              <bitOffset>14</bitOffset>
              <bitWidth>2</bitWidth>
            </field>
            <field>
              <name>PUPD8</name>
              <bitOffset>16</bitOffset>
              <bitWidth>2</bitWidth>
            </field>
            <field>
              <name>PUPD9</name>
              <bitOffset>18</bitOffset>
              <bitWidth>2</bitWidth>
            </field>
            <field>
              <name>PUPD10</name>
              <bitOffset>20</bitOffset>
              <bitWidth>2</bitWidth>
            </field>
            <field>
              <name>PUPD11</name>
              <bitOffset>22</bitOffset>
              <bitWidth>2</bitWidth>
            </field>
            <field>
              <name>PUPD12</name>
              <bitOffset>24</bitOffset>
              <bitWidth>2</bitWidth>
            </field>
            <field>
              <name>PUPD13</name>
              <bitOffset>26</bitOffset>
              <bitWidth>2</bitWidth>
            </field>
            <field>
              <name>PUPD14</name>
              <bitOffset>28</bitOffset>
              <bitWidth>2</bitWidth>
            </field>
            <field>
              <name>PUPD15</name>
              <bitOffset>30</bitOffset>
              <bitWidth>2</bitWidth>
            </field>
          </fields>
        </register>
        <register>
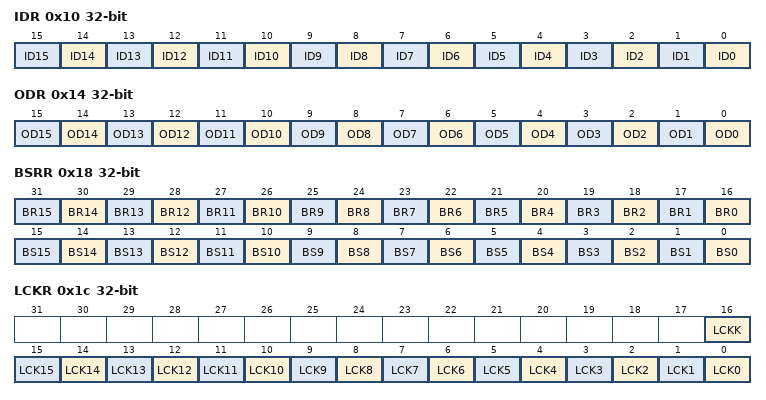
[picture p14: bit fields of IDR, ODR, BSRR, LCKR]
          <name>IDR</name>
          <addressOffset>0x10</addressOffset>
          <size>0x20</size>
          <fields>
            <field>
              <name>ID0</name>
              <bitOffset>0</bitOffset>
              <bitWidth>1</bitWidth>
            </field>
            <field>
              <name>ID1</name>
              <bitOffset>1</bitOffset>
              <bitWidth>1</bitWidth>
            </field>
            <field>
              <name>ID2</name>
              <bitOffset>2</bitOffset>
              <bitWidth>1</bitWidth>
            </field>
            <field>
              <name>ID3</name>
              <bitOffset>3</bitOffset>
              <bitWidth>1</bitWidth>
            </field>
            <field>
              <name>ID4</name>
              <bitOffset>4</bitOffset>
              <bitWidth>1</bitWidth>
            </field>
            <field>
              <name>ID5</name>
              <bitOffset>5</bitOffset>
              <bitWidth>1</bitWidth>
            </field>
            <field>
              <name>ID6</name>
              <bitOffset>6</bitOffset>
              <bitWidth>1</bitWidth>
            </field>
            <field>
              <name>ID7</name>
              <bitOffset>7</bitOffset>
              <bitWidth>1</bitWidth>
            </field>
            <field>
              <name>ID8</name>
              <bitOffset>8</bitOffset>
              <bitWidth>1</bitWidth>
            </field>
            <field>
              <name>ID9</name>
              <bitOffset>9</bitOffset>
              <bitWidth>1</bitWidth>
            </field>
            <field>
              <name>ID10</name>
              <bitOffset>10</bitOffset>
              <bitWidth>1</bitWidth>
            </field>
            <field>
              <name>ID11</name>
              <bitOffset>11</bitOffset>
              <bitWidth>1</bitWidth>
            </field>
            <field>
              <name>ID12</name>
              <bitOffset>12</bitOffset>
              <bitWidth>1</bitWidth>
            </field>
            <field>
              <name>ID13</name>
              <bitOffset>13</bitOffset>
              <bitWidth>1</bitWidth>
            </field>
            <field>
              <name>ID14</name>
              <bitOffset>14</bitOffset>
              <bitWidth>1</bitWidth>
            </field>
            <field>
              <name>ID15</name>
              <bitOffset>15</bitOffset>
              <bitWidth>1</bitWidth>
            </field>
          </fields>
        </register>
        <register>
          <name>ODR</name>
          <addressOffset>0x14</addressOffset>
          <size>0x20</size>
          <fields>
            <field>
              <name>OD0</name>
              <bitOffset>0</bitOffset>
              <bitWidth>1</bitWidth>
            </field>
            <field>
              <name>OD1</name>
              <bitOffset>1</bitOffset>
              <bitWidth>1</bitWidth>
            </field>
            <field>
              <name>OD2</name>
              <bitOffset>2</bitOffset>
              <bitWidth>1</bitWidth>
            </field>
            <field>
              <name>OD3</name>
              <bitOffset>3</bitOffset>
              <bitWidth>1</bitWidth>
            </field>
            <field>
              <name>OD4</name>
              <bitOffset>4</bitOffset>
              <bitWidth>1</bitWidth>
            </field>
            <field>
              <name>OD5</name>
              <bitOffset>5</bitOffset>
              <bitWidth>1</bitWidth>
            </field>
            <field>
              <name>OD6</name>
              <bitOffset>6</bitOffset>
              <bitWidth>1</bitWidth>
            </field>
            <field>
              <name>OD7</name>
              <bitOffset>7</bitOffset>
              <bitWidth>1</bitWidth>
            </field>
            <field>
              <name>OD8</name>
              <bitOffset>8</bitOffset>
              <bitWidth>1</bitWidth>
            </field>
            <field>
              <name>OD9</name>
              <bitOffset>9</bitOffset>
              <bitWidth>1</bitWidth>
            </field>
            <field>
              <name>OD10</name>
              <bitOffset>10</bitOffset>
              <bitWidth>1</bitWidth>
            </field>
            <field>
              <name>OD11</name>
              <bitOffset>11</bitOffset>
              <bitWidth>1</bitWidth>
            </field>
            <field>
              <name>OD12</name>
              <bitOffset>12</bitOffset>
              <bitWidth>1</bitWidth>
            </field>
            <field>
              <name>OD13</name>
              <bitOffset>13</bitOffset>
              <bitWidth>1</bitWidth>
            </field>
            <field>
              <name>OD14</name>
              <bitOffset>14</bitOffset>
              <bitWidth>1</bitWidth>
            </field>
            <field>
              <name>OD15</name>
              <bitOffset>15</bitOffset>
              <bitWidth>1</bitWidth>
            </field>
          </fields>
        </register>
        <register>
          <name>BSRR</name>
          <addressOffset>0x18</addressOffset>
          <size>0x20</size>
          <fields>
            <field>
              <name>BS0</name>
              <bitOffset>0</bitOffset>
              <bitWidth>1</bitWidth>
            </field>
            <field>
              <name>BS1</name>
              <bitOffset>1</bitOffset>
              <bitWidth>1</bitWidth>
            </field>
            <field>
              <name>BS2</name>
              <bitOffset>2</bitOffset>
              <bitWidth>1</bitWidth>
            </field>
            <field>
              <name>BS3</name>
              <bitOffset>3</bitOffset>
              <bitWidth>1</bitWidth>
            </field>
            <field>
              <name>BS4</name>
              <bitOffset>4</bitOffset>
              <bitWidth>1</bitWidth>
            </field>
            <field>
              <name>BS5</name>
              <bitOffset>5</bitOffset>
              <bitWidth>1</bitWidth>
            </field>
            <field>
              <name>BS6</name>
              <bitOffset>6</bitOffset>
              <bitWidth>1</bitWidth>
            </field>
            <field>
              <name>BS7</name>
              <bitOffset>7</bitOffset>
              <bitWidth>1</bitWidth>
            </field>
            <field>
              <name>BS8</name>
              <bitOffset>8</bitOffset>
              <bitWidth>1</bitWidth>
            </field>
            <field>
              <name>BS9</name>
              <bitOffset>9</bitOffset>
              <bitWidth>1</bitWidth>
            </field>
            <field>
              <name>BS10</name>
              <bitOffset>10</bitOffset>
              <bitWidth>1</bitWidth>
            </field>
            <field>
              <name>BS11</name>
              <bitOffset>11</bitOffset>
              <bitWidth>1</bitWidth>
            </field>
            <field>
              <name>BS12</name>
              <bitOffset>12</bitOffset>
              <bitWidth>1</bitWidth>
            </field>
            <field>
              <name>BS13</name>
              <bitOffset>13</bitOffset>
              <bitWidth>1</bitWidth>
            </field>
            <field>
              <name>BS14</name>
              <bitOffset>14</bitOffset>
              <bitWidth>1</bitWidth>
            </field>
            <field>
              <name>BS15</name>
              <bitOffset>15</bitOffset>
              <bitWidth>1</bitWidth>
            </field>
            <field>
              <name>BR0</name>
              <bitOffset>16</bitOffset>
              <bitWidth>1</bitWidth>
            </field>
            <field>
              <name>BR1</name>
              <bitOffset>17</bitOffset>
              <bitWidth>1</bitWidth>
            </field>
            <field>
              <name>BR2</name>
              <bitOffset>18</bitOffset>
              <bitWidth>1</bitWidth>
            </field>
            <field>
              <name>BR3</name>
              <bitOffset>19</bitOffset>
              <bitWidth>1</bitWidth>
            </field>
            <field>
              <name>BR4</name>
              <bitOffset>20</bitOffset>
              <bitWidth>1</bitWidth>
            </field>
            <field>
              <name>BR5</name>
              <bitOffset>21</bitOffset>
              <bitWidth>1</bitWidth>
            </field>
            <field>
              <name>BR6</name>
              <bitOffset>22</bitOffset>
              <bitWidth>1</bitWidth>
            </field>
            <field>
              <name>BR7</name>
              <bitOffset>23</bitOffset>
              <bitWidth>1</bitWidth>
            </field>
            <field>
              <name>BR8</name>
              <bitOffset>24</bitOffset>
              <bitWidth>1</bitWidth>
            </field>
            <field>
              <name>BR9</name>
              <bitOffset>25</bitOffset>
              <bitWidth>1</bitWidth>
            </field>
            <field>
              <name>BR10</name>
              <bitOffset>26</bitOffset>
              <bitWidth>1</bitWidth>
            </field>
            <field>
              <name>BR11</name>
              <bitOffset>27</bitOffset>
              <bitWidth>1</bitWidth>
            </field>
            <field>
              <name>BR12</name>
              <bitOffset>28</bitOffset>
              <bitWidth>1</bitWidth>
            </field>
            <field>
              <name>BR13</name>
              <bitOffset>29</bitOffset>
              <bitWidth>1</bitWidth>
            </field>
            <field>
              <name>BR14</name>
              <bitOffset>30</bitOffset>
              <bitWidth>1</bitWidth>
            </field>
            <field>
              <name>BR15</name>
              <bitOffset>31</bitOffset>
              <bitWidth>1</bitWidth>
            </field>
          </fields>
        </register>
        <register>
          <name>LCKR</name>
          <addressOffset>0x1c</addressOffset>
          <size>0x20</size>
          <fields>
            <field>
              <name>LCK0</name>
              <bitOffset>0</bitOffset>
              <bitWidth>1</bitWidth>
            </field>
            <field>
              <name>LCK1</name>
              <bitOffset>1</bitOffset>
              <bitWidth>1</bitWidth>
            </field>
            <field>
              <name>LCK2</name>
              <bitOffset>2</bitOffset>
              <bitWidth>1</bitWidth>
            </field>
            <field>
              <name>LCK3</name>
              <bitOffset>3</bitOffset>
              <bitWidth>1</bitWidth>
            </field>
            <field>
              <name>LCK4</name>
              <bitOffset>4</bitOffset>
              <bitWidth>1</bitWidth>
            </field>
            <field>
              <name>LCK5</name>
              <bitOffset>5</bitOffset>
              <bitWidth>1</bitWidth>
            </field>
            <field>
              <name>LCK6</name>
              <bitOffset>6</bitOffset>
              <bitWidth>1</bitWidth>
            </field>
            <field>
              <name>LCK7</name>
              <bitOffset>7</bitOffset>
              <bitWidth>1</bitWidth>
            </field>
            <field>
              <name>LCK8</name>
              <bitOffset>8</bitOffset>
              <bitWidth>1</bitWidth>
            </field>
            <field>
              <name>LCK9</name>
              <bitOffset>9</bitOffset>
              <bitWidth>1</bitWidth>
            </field>
            <field>
              <name>LCK10</name>
              <bitOffset>10</bitOffset>
              <bitWidth>1</bitWidth>
            </field>
            <field>
              <name>LCK11</name>
              <bitOffset>11</bitOffset>
              <bitWidth>1</bitWidth>
            </field>
            <field>
              <name>LCK12</name>
              <bitOffset>12</bitOffset>
              <bitWidth>1</bitWidth>
            </field>
            <field>
              <name>LCK13</name>
              <bitOffset>13</bitOffset>
              <bitWidth>1</bitWidth>
            </field>
            <field>
              <name>LCK14</name>
              <bitOffset>14</bitOffset>
              <bitWidth>1</bitWidth>
            </field>
            <field>
              <name>LCK15</name>
              <bitOffset>15</bitOffset>
              <bitWidth>1</bitWidth>
            </field>
            <field>
              <name>LCKK</name>
              <bitOffset>16</bitOffset>
              <bitWidth>1</bitWidth>
            </field>
          </fields>
        </register>
        <register>
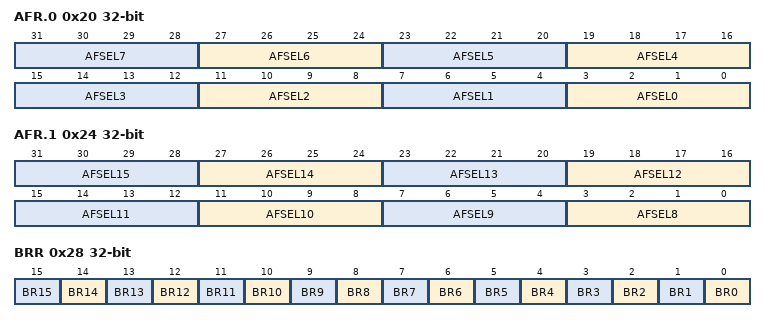
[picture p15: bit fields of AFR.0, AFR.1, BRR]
          <name>AFR.0</name>
          <addressOffset>0x20</addressOffset>
          <size>0x20</size>
          <fields>
            <field>
              <name>AFSEL0</name>
              <bitOffset>0</bitOffset>
              <bitWidth>4</bitWidth>
            </field>
            <field>
              <name>AFSEL1</name>
              <bitOffset>4</bitOffset>
              <bitWidth>4</bitWidth>
            </field>
            <field>
              <name>AFSEL2</name>
              <bitOffset>8</bitOffset>
              <bitWidth>4</bitWidth>
            </field>
            <field>
              <name>AFSEL3</name>
              <bitOffset>12</bitOffset>
              <bitWidth>4</bitWidth>
            </field>
            <field>
              <name>AFSEL4</name>
              <bitOffset>16</bitOffset>
              <bitWidth>4</bitWidth>
            </field>
            <field>
              <name>AFSEL5</name>
              <bitOffset>20</bitOffset>
              <bitWidth>4</bitWidth>
            </field>
            <field>
              <name>AFSEL6</name>
              <bitOffset>24</bitOffset>
              <bitWidth>4</bitWidth>
            </field>
            <field>
              <name>AFSEL7</name>
              <bitOffset>28</bitOffset>
              <bitWidth>4</bitWidth>
            </field>
          </fields>
        </register>
        <register>
          <name>AFR.1</name>
          <addressOffset>0x24</addressOffset>
          <size>0x20</size>
          <fields>
            <field>
              <name>AFSEL8</name>
              <bitOffset>0</bitOffset>
              <bitWidth>4</bitWidth>
            </field>
            <field>
              <name>AFSEL9</name>
              <bitOffset>4</bitOffset>
              <bitWidth>4</bitWidth>
            </field>
            <field>
              <name>AFSEL10</name>
              <bitOffset>8</bitOffset>
              <bitWidth>4</bitWidth>
            </field>
            <field>
              <name>AFSEL11</name>
              <bitOffset>12</bitOffset>
              <bitWidth>4</bitWidth>
            </field>
            <field>
              <name>AFSEL12</name>
              <bitOffset>16</bitOffset>
              <bitWidth>4</bitWidth>
            </field>
            <field>
              <name>AFSEL13</name>
              <bitOffset>20</bitOffset>
              <bitWidth>4</bitWidth>
            </field>
            <field>
              <name>AFSEL14</name>
              <bitOffset>24</bitOffset>
              <bitWidth>4</bitWidth>
            </field>
            <field>
              <name>AFSEL15</name>
              <bitOffset>28</bitOffset>
              <bitWidth>4</bitWidth>
            </field>
          </fields>
        </register>
        <register>
          <name>BRR</name>
          <addressOffset>0x28</addressOffset>
          <size>0x20</size>
          <fields>
            <field>
              <name>BR0</name>
              <bitOffset>0</bitOffset>
              <bitWidth>1</bitWidth>
            </field>
            <field>
              <name>BR1</name>
              <bitOffset>1</bitOffset>
              <bitWidth>1</bitWidth>
            </field>
            <field>
              <name>BR2</name>
              <bitOffset>2</bitOffset>
              <bitWidth>1</bitWidth>
            </field>
            <field>
              <name>BR3</name>
              <bitOffset>3</bitOffset>
              <bitWidth>1</bitWidth>
            </field>
            <field>
              <name>BR4</name>
              <bitOffset>4</bitOffset>
              <bitWidth>1</bitWidth>
            </field>
            <field>
              <name>BR5</name>
              <bitOffset>5</bitOffset>
              <bitWidth>1</bitWidth>
            </field>
            <field>
              <name>BR6</name>
              <bitOffset>6</bitOffset>
              <bitWidth>1</bitWidth>
            </field>
            <field>
              <name>BR7</name>
              <bitOffset>7</bitOffset>
              <bitWidth>1</bitWidth>
            </field>
            <field>
              <name>BR8</name>
              <bitOffset>8</bitOffset>
              <bitWidth>1</bitWidth>
            </field>
            <field>
              <name>BR9</name>
              <bitOffset>9</bitOffset>
              <bitWidth>1</bitWidth>
            </field>
            <field>
              <name>BR10</name>
              <bitOffset>10</bitOffset>
              <bitWidth>1</bitWidth>
            </field>
            <field>
              <name>BR11</name>
              <bitOffset>11</bitOffset>
              <bitWidth>1</bitWidth>
            </field>
            <field>
              <name>BR12</name>
              <bitOffset>12</bitOffset>
              <bitWidth>1</bitWidth>
            </field>
            <field>
              <name>BR13</name>
              <bitOffset>13</bitOffset>
              <bitWidth>1</bitWidth>
            </field>
            <field>
              <name>BR14</name>
              <bitOffset>14</bitOffset>
              <bitWidth>1</bitWidth>
            </field>
            <field>
              <name>BR15</name>
              <bitOffset>15</bitOffset>
              <bitWidth>1</bitWidth>
            </field>
          </fields>
        </register>
      </registers>
    </peripheral>
    <peripheral>
      <name>GPIOD</name>
      <baseAddress>0x48000c00</baseAddress>
      <registers>
        <register>
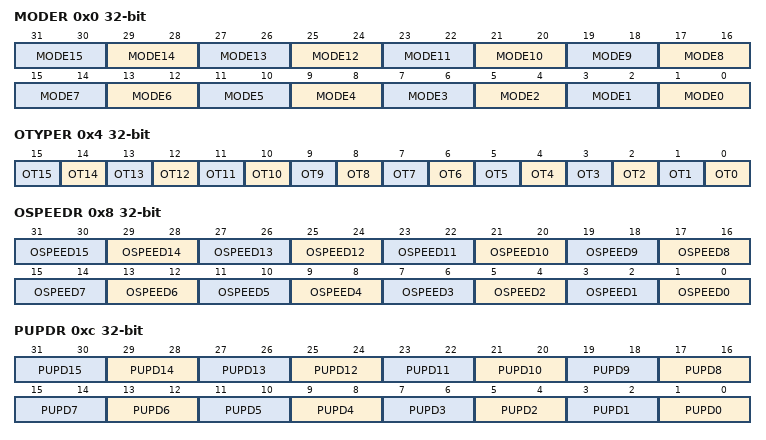
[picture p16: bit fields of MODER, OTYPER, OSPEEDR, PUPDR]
          <name>MODER</name>
          <addressOffset>0x0</addressOffset>
          <size>0x20</size>
          <fields>
            <field>
              <name>MODE0</name>
              <bitOffset>0</bitOffset>
              <bitWidth>2</bitWidth>
            </field>
            <field>
              <name>MODE1</name>
              <bitOffset>2</bitOffset>
              <bitWidth>2</bitWidth>
            </field>
            <field>
              <name>MODE2</name>
              <bitOffset>4</bitOffset>
              <bitWidth>2</bitWidth>
            </field>
            <field>
              <name>MODE3</name>
              <bitOffset>6</bitOffset>
              <bitWidth>2</bitWidth>
            </field>
            <field>
              <name>MODE4</name>
              <bitOffset>8</bitOffset>
              <bitWidth>2</bitWidth>
            </field>
            <field>
              <name>MODE5</name>
              <bitOffset>10</bitOffset>
              <bitWidth>2</bitWidth>
            </field>
            <field>
              <name>MODE6</name>
              <bitOffset>12</bitOffset>
              <bitWidth>2</bitWidth>
            </field>
            <field>
              <name>MODE7</name>
              <bitOffset>14</bitOffset>
              <bitWidth>2</bitWidth>
            </field>
            <field>
              <name>MODE8</name>
              <bitOffset>16</bitOffset>
              <bitWidth>2</bitWidth>
            </field>
            <field>
              <name>MODE9</name>
              <bitOffset>18</bitOffset>
              <bitWidth>2</bitWidth>
            </field>
            <field>
              <name>MODE10</name>
              <bitOffset>20</bitOffset>
              <bitWidth>2</bitWidth>
            </field>
            <field>
              <name>MODE11</name>
              <bitOffset>22</bitOffset>
              <bitWidth>2</bitWidth>
            </field>
            <field>
              <name>MODE12</name>
              <bitOffset>24</bitOffset>
              <bitWidth>2</bitWidth>
            </field>
            <field>
              <name>MODE13</name>
              <bitOffset>26</bitOffset>
              <bitWidth>2</bitWidth>
            </field>
            <field>
              <name>MODE14</name>
              <bitOffset>28</bitOffset>
              <bitWidth>2</bitWidth>
            </field>
            <field>
              <name>MODE15</name>
              <bitOffset>30</bitOffset>
              <bitWidth>2</bitWidth>
            </field>
          </fields>
        </register>
        <register>
          <name>OTYPER</name>
          <addressOffset>0x4</addressOffset>
          <size>0x20</size>
          <fields>
            <field>
              <name>OT0</name>
              <bitOffset>0</bitOffset>
              <bitWidth>1</bitWidth>
            </field>
            <field>
              <name>OT1</name>
              <bitOffset>1</bitOffset>
              <bitWidth>1</bitWidth>
            </field>
            <field>
              <name>OT2</name>
              <bitOffset>2</bitOffset>
              <bitWidth>1</bitWidth>
            </field>
            <field>
              <name>OT3</name>
              <bitOffset>3</bitOffset>
              <bitWidth>1</bitWidth>
            </field>
            <field>
              <name>OT4</name>
              <bitOffset>4</bitOffset>
              <bitWidth>1</bitWidth>
            </field>
            <field>
              <name>OT5</name>
              <bitOffset>5</bitOffset>
              <bitWidth>1</bitWidth>
            </field>
            <field>
              <name>OT6</name>
              <bitOffset>6</bitOffset>
              <bitWidth>1</bitWidth>
            </field>
            <field>
              <name>OT7</name>
              <bitOffset>7</bitOffset>
              <bitWidth>1</bitWidth>
            </field>
            <field>
              <name>OT8</name>
              <bitOffset>8</bitOffset>
              <bitWidth>1</bitWidth>
            </field>
            <field>
              <name>OT9</name>
              <bitOffset>9</bitOffset>
              <bitWidth>1</bitWidth>
            </field>
            <field>
              <name>OT10</name>
              <bitOffset>10</bitOffset>
              <bitWidth>1</bitWidth>
            </field>
            <field>
              <name>OT11</name>
              <bitOffset>11</bitOffset>
              <bitWidth>1</bitWidth>
            </field>
            <field>
              <name>OT12</name>
              <bitOffset>12</bitOffset>
              <bitWidth>1</bitWidth>
            </field>
            <field>
              <name>OT13</name>
              <bitOffset>13</bitOffset>
              <bitWidth>1</bitWidth>
            </field>
            <field>
              <name>OT14</name>
              <bitOffset>14</bitOffset>
              <bitWidth>1</bitWidth>
            </field>
            <field>
              <name>OT15</name>
              <bitOffset>15</bitOffset>
              <bitWidth>1</bitWidth>
            </field>
          </fields>
        </register>
        <register>
          <name>OSPEEDR</name>
          <addressOffset>0x8</addressOffset>
          <size>0x20</size>
          <fields>
            <field>
              <name>OSPEED0</name>
              <bitOffset>0</bitOffset>
              <bitWidth>2</bitWidth>
            </field>
            <field>
              <name>OSPEED1</name>
              <bitOffset>2</bitOffset>
              <bitWidth>2</bitWidth>
            </field>
            <field>
              <name>OSPEED2</name>
              <bitOffset>4</bitOffset>
              <bitWidth>2</bitWidth>
            </field>
            <field>
              <name>OSPEED3</name>
              <bitOffset>6</bitOffset>
              <bitWidth>2</bitWidth>
            </field>
            <field>
              <name>OSPEED4</name>
              <bitOffset>8</bitOffset>
              <bitWidth>2</bitWidth>
            </field>
            <field>
              <name>OSPEED5</name>
              <bitOffset>10</bitOffset>
              <bitWidth>2</bitWidth>
            </field>
            <field>
              <name>OSPEED6</name>
              <bitOffset>12</bitOffset>
              <bitWidth>2</bitWidth>
            </field>
            <field>
              <name>OSPEED7</name>
              <bitOffset>14</bitOffset>
              <bitWidth>2</bitWidth>
            </field>
            <field>
              <name>OSPEED8</name>
              <bitOffset>16</bitOffset>
              <bitWidth>2</bitWidth>
            </field>
            <field>
              <name>OSPEED9</name>
              <bitOffset>18</bitOffset>
              <bitWidth>2</bitWidth>
            </field>
            <field>
              <name>OSPEED10</name>
              <bitOffset>20</bitOffset>
              <bitWidth>2</bitWidth>
            </field>
            <field>
              <name>OSPEED11</name>
              <bitOffset>22</bitOffset>
              <bitWidth>2</bitWidth>
            </field>
            <field>
              <name>OSPEED12</name>
              <bitOffset>24</bitOffset>
              <bitWidth>2</bitWidth>
            </field>
            <field>
              <name>OSPEED13</name>
              <bitOffset>26</bitOffset>
              <bitWidth>2</bitWidth>
            </field>
            <field>
              <name>OSPEED14</name>
              <bitOffset>28</bitOffset>
              <bitWidth>2</bitWidth>
            </field>
            <field>
              <name>OSPEED15</name>
              <bitOffset>30</bitOffset>
              <bitWidth>2</bitWidth>
            </field>
          </fields>
        </register>
        <register>
          <name>PUPDR</name>
          <addressOffset>0xc</addressOffset>
          <size>0x20</size>
          <fields>
            <field>
              <name>PUPD0</name>
              <bitOffset>0</bitOffset>
              <bitWidth>2</bitWidth>
            </field>
            <field>
              <name>PUPD1</name>
              <bitOffset>2</bitOffset>
              <bitWidth>2</bitWidth>
            </field>
            <field>
              <name>PUPD2</name>
              <bitOffset>4</bitOffset>
              <bitWidth>2</bitWidth>
            </field>
            <field>
              <name>PUPD3</name>
              <bitOffset>6</bitOffset>
              <bitWidth>2</bitWidth>
            </field>
            <field>
              <name>PUPD4</name>
              <bitOffset>8</bitOffset>
              <bitWidth>2</bitWidth>
            </field>
            <field>
              <name>PUPD5</name>
              <bitOffset>10</bitOffset>
              <bitWidth>2</bitWidth>
            </field>
            <field>
              <name>PUPD6</name>
              <bitOffset>12</bitOffset>
              <bitWidth>2</bitWidth>
            </field>
            <field>
              <name>PUPD7</name>
              <bitOffset>14</bitOffset>
              <bitWidth>2</bitWidth>
            </field>
            <field>
              <name>PUPD8</name>
              <bitOffset>16</bitOffset>
              <bitWidth>2</bitWidth>
            </field>
            <field>
              <name>PUPD9</name>
              <bitOffset>18</bitOffset>
              <bitWidth>2</bitWidth>
            </field>
            <field>
              <name>PUPD10</name>
              <bitOffset>20</bitOffset>
              <bitWidth>2</bitWidth>
            </field>
            <field>
              <name>PUPD11</name>
              <bitOffset>22</bitOffset>
              <bitWidth>2</bitWidth>
            </field>
            <field>
              <name>PUPD12</name>
              <bitOffset>24</bitOffset>
              <bitWidth>2</bitWidth>
            </field>
            <field>
              <name>PUPD13</name>
              <bitOffset>26</bitOffset>
              <bitWidth>2</bitWidth>
            </field>
            <field>
              <name>PUPD14</name>
              <bitOffset>28</bitOffset>
              <bitWidth>2</bitWidth>
            </field>
            <field>
              <name>PUPD15</name>
              <bitOffset>30</bitOffset>
              <bitWidth>2</bitWidth>
            </field>
          </fields>
        </register>
        <register>
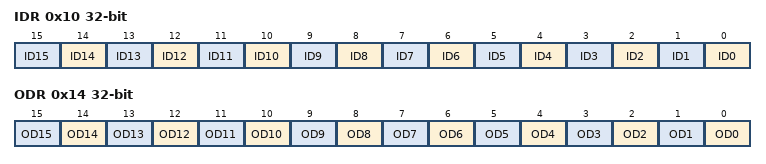
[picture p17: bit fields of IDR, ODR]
          <name>IDR</name>
          <addressOffset>0x10</addressOffset>
          <size>0x20</size>
          <fields>
            <field>
              <name>ID0</name>
              <bitOffset>0</bitOffset>
              <bitWidth>1</bitWidth>
            </field>
            <field>
              <name>ID1</name>
              <bitOffset>1</bitOffset>
              <bitWidth>1</bitWidth>
            </field>
            <field>
              <name>ID2</name>
              <bitOffset>2</bitOffset>
              <bitWidth>1</bitWidth>
            </field>
            <field>
              <name>ID3</name>
              <bitOffset>3</bitOffset>
              <bitWidth>1</bitWidth>
            </field>
            <field>
              <name>ID4</name>
              <bitOffset>4</bitOffset>
              <bitWidth>1</bitWidth>
            </field>
            <field>
              <name>ID5</name>
              <bitOffset>5</bitOffset>
              <bitWidth>1</bitWidth>
            </field>
            <field>
              <name>ID6</name>
              <bitOffset>6</bitOffset>
              <bitWidth>1</bitWidth>
            </field>
            <field>
              <name>ID7</name>
              <bitOffset>7</bitOffset>
              <bitWidth>1</bitWidth>
            </field>
            <field>
              <name>ID8</name>
              <bitOffset>8</bitOffset>
              <bitWidth>1</bitWidth>
            </field>
            <field>
              <name>ID9</name>
              <bitOffset>9</bitOffset>
              <bitWidth>1</bitWidth>
            </field>
            <field>
              <name>ID10</name>
              <bitOffset>10</bitOffset>
              <bitWidth>1</bitWidth>
            </field>
            <field>
              <name>ID11</name>
              <bitOffset>11</bitOffset>
              <bitWidth>1</bitWidth>
            </field>
            <field>
              <name>ID12</name>
              <bitOffset>12</bitOffset>
              <bitWidth>1</bitWidth>
            </field>
            <field>
              <name>ID13</name>
              <bitOffset>13</bitOffset>
              <bitWidth>1</bitWidth>
            </field>
            <field>
              <name>ID14</name>
              <bitOffset>14</bitOffset>
              <bitWidth>1</bitWidth>
            </field>
            <field>
              <name>ID15</name>
              <bitOffset>15</bitOffset>
              <bitWidth>1</bitWidth>
            </field>
          </fields>
        </register>
        <register>
          <name>ODR</name>
          <addressOffset>0x14</addressOffset>
          <size>0x20</size>
          <fields>
            <field>
              <name>OD0</name>
              <bitOffset>0</bitOffset>
              <bitWidth>1</bitWidth>
            </field>
            <field>
              <name>OD1</name>
              <bitOffset>1</bitOffset>
              <bitWidth>1</bitWidth>
            </field>
            <field>
              <name>OD2</name>
              <bitOffset>2</bitOffset>
              <bitWidth>1</bitWidth>
            </field>
            <field>
              <name>OD3</name>
              <bitOffset>3</bitOffset>
              <bitWidth>1</bitWidth>
            </field>
            <field>
              <name>OD4</name>
              <bitOffset>4</bitOffset>
              <bitWidth>1</bitWidth>
            </field>
            <field>
              <name>OD5</name>
              <bitOffset>5</bitOffset>
              <bitWidth>1</bitWidth>
            </field>
            <field>
              <name>OD6</name>
              <bitOffset>6</bitOffset>
              <bitWidth>1</bitWidth>
            </field>
            <field>
              <name>OD7</name>
              <bitOffset>7</bitOffset>
              <bitWidth>1</bitWidth>
            </field>
            <field>
              <name>OD8</name>
              <bitOffset>8</bitOffset>
              <bitWidth>1</bitWidth>
            </field>
            <field>
              <name>OD9</name>
              <bitOffset>9</bitOffset>
              <bitWidth>1</bitWidth>
            </field>
            <field>
              <name>OD10</name>
              <bitOffset>10</bitOffset>
              <bitWidth>1</bitWidth>
            </field>
            <field>
              <name>OD11</name>
              <bitOffset>11</bitOffset>
              <bitWidth>1</bitWidth>
            </field>
            <field>
              <name>OD12</name>
              <bitOffset>12</bitOffset>
              <bitWidth>1</bitWidth>
            </field>
            <field>
              <name>OD13</name>
              <bitOffset>13</bitOffset>
              <bitWidth>1</bitWidth>
            </field>
            <field>
              <name>OD14</name>
              <bitOffset>14</bitOffset>
              <bitWidth>1</bitWidth>
            </field>
            <field>
              <name>OD15</name>
              <bitOffset>15</bitOffset>
              <bitWidth>1</bitWidth>
            </field>
          </fields>
        </register>
        <register>
          <name>BSRR</name>
          <addressOffset>0x18</addressOffset>
          <size>0x20</size>
          <fields>
            <field>
              <name>BS0</name>
              <bitOffset>0</bitOffset>
              <bitWidth>1</bitWidth>
            </field>
            <field>
              <name>BS1</name>
              <bitOffset>1</bitOffset>
              <bitWidth>1</bitWidth>
            </field>
            <field>
              <name>BS2</name>
              <bitOffset>2</bitOffset>
              <bitWidth>1</bitWidth>
            </field>
            <field>
              <name>BS3</name>
              <bitOffset>3</bitOffset>
              <bitWidth>1</bitWidth>
            </field>
            <field>
              <name>BS4</name>
              <bitOffset>4</bitOffset>
              <bitWidth>1</bitWidth>
            </field>
            <field>
              <name>BS5</name>
              <bitOffset>5</bitOffset>
              <bitWidth>1</bitWidth>
            </field>
            <field>
              <name>BS6</name>
              <bitOffset>6</bitOffset>
              <bitWidth>1</bitWidth>
            </field>
            <field>
              <name>BS7</name>
              <bitOffset>7</bitOffset>
              <bitWidth>1</bitWidth>
            </field>
            <field>
              <name>BS8</name>
              <bitOffset>8</bitOffset>
              <bitWidth>1</bitWidth>
            </field>
            <field>
              <name>BS9</name>
              <bitOffset>9</bitOffset>
              <bitWidth>1</bitWidth>
            </field>
            <field>
              <name>BS10</name>
              <bitOffset>10</bitOffset>
              <bitWidth>1</bitWidth>
            </field>
            <field>
              <name>BS11</name>
              <bitOffset>11</bitOffset>
              <bitWidth>1</bitWidth>
            </field>
            <field>
              <name>BS12</name>
              <bitOffset>12</bitOffset>
              <bitWidth>1</bitWidth>
            </field>
            <field>
              <name>BS13</name>
              <bitOffset>13</bitOffset>
              <bitWidth>1</bitWidth>
            </field>
            <field>
              <name>BS14</name>
              <bitOffset>14</bitOffset>
              <bitWidth>1</bitWidth>
            </field>
            <field>
              <name>BS15</name>
              <bitOffset>15</bitOffset>
              <bitWidth>1</bitWidth>
            </field>
            <field>
              <name>BR0</name>
              <bitOffset>16</bitOffset>
              <bitWidth>1</bitWidth>
            </field>
            <field>
              <name>BR1</name>
              <bitOffset>17</bitOffset>
              <bitWidth>1</bitWidth>
            </field>
            <field>
              <name>BR2</name>
              <bitOffset>18</bitOffset>
              <bitWidth>1</bitWidth>
            </field>
            <field>
              <name>BR3</name>
              <bitOffset>19</bitOffset>
              <bitWidth>1</bitWidth>
            </field>
            <field>
              <name>BR4</name>
              <bitOffset>20</bitOffset>
              <bitWidth>1</bitWidth>
            </field>
            <field>
              <name>BR5</name>
              <bitOffset>21</bitOffset>
              <bitWidth>1</bitWidth>
            </field>
            <field>
              <name>BR6</name>
              <bitOffset>22</bitOffset>
              <bitWidth>1</bitWidth>
            </field>
            <field>
              <name>BR7</name>
              <bitOffset>23</bitOffset>
              <bitWidth>1</bitWidth>
            </field>
            <field>
              <name>BR8</name>
              <bitOffset>24</bitOffset>
              <bitWidth>1</bitWidth>
            </field>
            <field>
              <name>BR9</name>
              <bitOffset>25</bitOffset>
              <bitWidth>1</bitWidth>
            </field>
            <field>
              <name>BR10</name>
              <bitOffset>26</bitOffset>
              <bitWidth>1</bitWidth>
            </field>
            <field>
              <name>BR11</name>
              <bitOffset>27</bitOffset>
              <bitWidth>1</bitWidth>
            </field>
            <field>
              <name>BR12</name>
              <bitOffset>28</bitOffset>
              <bitWidth>1</bitWidth>
            </field>
            <field>
              <name>BR13</name>
              <bitOffset>29</bitOffset>
              <bitWidth>1</bitWidth>
            </field>
            <field>
              <name>BR14</name>
              <bitOffset>30</bitOffset>
              <bitWidth>1</bitWidth>
            </field>
            <field>
              <name>BR15</name>
              <bitOffset>31</bitOffset>
              <bitWidth>1</bitWidth>
            </field>
          </fields>
        </register>
        <register>
          <name>LCKR</name>
          <addressOffset>0x1c</addressOffset>
          <size>0x20</size>
          <fields>
            <field>
              <name>LCK0</name>
              <bitOffset>0</bitOffset>
              <bitWidth>1</bitWidth>
            </field>
            <field>
              <name>LCK1</name>
              <bitOffset>1</bitOffset>
              <bitWidth>1</bitWidth>
            </field>
            <field>
              <name>LCK2</name>
              <bitOffset>2</bitOffset>
              <bitWidth>1</bitWidth>
            </field>
            <field>
              <name>LCK3</name>
              <bitOffset>3</bitOffset>
              <bitWidth>1</bitWidth>
            </field>
            <field>
              <name>LCK4</name>
              <bitOffset>4</bitOffset>
              <bitWidth>1</bitWidth>
            </field>
            <field>
              <name>LCK5</name>
              <bitOffset>5</bitOffset>
              <bitWidth>1</bitWidth>
            </field>
            <field>
              <name>LCK6</name>
              <bitOffset>6</bitOffset>
              <bitWidth>1</bitWidth>
            </field>
            <field>
              <name>LCK7</name>
              <bitOffset>7</bitOffset>
              <bitWidth>1</bitWidth>
            </field>
            <field>
              <name>LCK8</name>
              <bitOffset>8</bitOffset>
              <bitWidth>1</bitWidth>
            </field>
            <field>
              <name>LCK9</name>
              <bitOffset>9</bitOffset>
              <bitWidth>1</bitWidth>
            </field>
            <field>
              <name>LCK10</name>
              <bitOffset>10</bitOffset>
              <bitWidth>1</bitWidth>
            </field>
            <field>
              <name>LCK11</name>
              <bitOffset>11</bitOffset>
              <bitWidth>1</bitWidth>
            </field>
            <field>
              <name>LCK12</name>
              <bitOffset>12</bitOffset>
              <bitWidth>1</bitWidth>
            </field>
            <field>
              <name>LCK13</name>
              <bitOffset>13</bitOffset>
              <bitWidth>1</bitWidth>
            </field>
            <field>
              <name>LCK14</name>
              <bitOffset>14</bitOffset>
              <bitWidth>1</bitWidth>
            </field>
            <field>
              <name>LCK15</name>
              <bitOffset>15</bitOffset>
              <bitWidth>1</bitWidth>
            </field>
            <field>
              <name>LCKK</name>
              <bitOffset>16</bitOffset>
              <bitWidth>1</bitWidth>
            </field>
          </fields>
        </register>
        <register>
          <name>AFR.0</name>
          <addressOffset>0x20</addressOffset>
          <size>0x20</size>
          <fields>
            <field>
              <name>AFSEL0</name>
              <bitOffset>0</bitOffset>
              <bitWidth>4</bitWidth>
            </field>
            <field>
              <name>AFSEL1</name>
              <bitOffset>4</bitOffset>
              <bitWidth>4</bitWidth>
            </field>
            <field>
              <name>AFSEL2</name>
              <bitOffset>8</bitOffset>
              <bitWidth>4</bitWidth>
            </field>
            <field>
              <name>AFSEL3</name>
              <bitOffset>12</bitOffset>
              <bitWidth>4</bitWidth>
            </field>
            <field>
              <name>AFSEL4</name>
              <bitOffset>16</bitOffset>
              <bitWidth>4</bitWidth>
            </field>
            <field>
              <name>AFSEL5</name>
              <bitOffset>20</bitOffset>
              <bitWidth>4</bitWidth>
            </field>
            <field>
              <name>AFSEL6</name>
              <bitOffset>24</bitOffset>
              <bitWidth>4</bitWidth>
            </field>
            <field>
              <name>AFSEL7</name>
              <bitOffset>28</bitOffset>
              <bitWidth>4</bitWidth>
            </field>
          </fields>
        </register>
        <register>
          <name>AFR.1</name>
          <addressOffset>0x24</addressOffset>
          <size>0x20</size>
          <fields>
            <field>
              <name>AFSEL8</name>
              <bitOffset>0</bitOffset>
              <bitWidth>4</bitWidth>
            </field>
            <field>
              <name>AFSEL9</name>
              <bitOffset>4</bitOffset>
              <bitWidth>4</bitWidth>
            </field>
            <field>
              <name>AFSEL10</name>
              <bitOffset>8</bitOffset>
              <bitWidth>4</bitWidth>
            </field>
            <field>
              <name>AFSEL11</name>
              <bitOffset>12</bitOffset>
              <bitWidth>4</bitWidth>
            </field>
            <field>
              <name>AFSEL12</name>
              <bitOffset>16</bitOffset>
              <bitWidth>4</bitWidth>
            </field>
            <field>
              <name>AFSEL13</name>
              <bitOffset>20</bitOffset>
              <bitWidth>4</bitWidth>
            </field>
            <field>
              <name>AFSEL14</name>
              <bitOffset>24</bitOffset>
              <bitWidth>4</bitWidth>
            </field>
            <field>
              <name>AFSEL15</name>
              <bitOffset>28</bitOffset>
              <bitWidth>4</bitWidth>
            </field>
          </fields>
        </register>
        <register>
          <name>BRR</name>
          <addressOffset>0x28</addressOffset>
          <size>0x20</size>
          <fields>
            <field>
              <name>BR0</name>
              <bitOffset>0</bitOffset>
              <bitWidth>1</bitWidth>
            </field>
            <field>
              <name>BR1</name>
              <bitOffset>1</bitOffset>
              <bitWidth>1</bitWidth>
            </field>
            <field>
              <name>BR2</name>
              <bitOffset>2</bitOffset>
              <bitWidth>1</bitWidth>
            </field>
            <field>
              <name>BR3</name>
              <bitOffset>3</bitOffset>
              <bitWidth>1</bitWidth>
            </field>
            <field>
              <name>BR4</name>
              <bitOffset>4</bitOffset>
              <bitWidth>1</bitWidth>
            </field>
            <field>
              <name>BR5</name>
              <bitOffset>5</bitOffset>
              <bitWidth>1</bitWidth>
            </field>
            <field>
              <name>BR6</name>
              <bitOffset>6</bitOffset>
              <bitWidth>1</bitWidth>
            </field>
            <field>
              <name>BR7</name>
              <bitOffset>7</bitOffset>
              <bitWidth>1</bitWidth>
            </field>
            <field>
              <name>BR8</name>
              <bitOffset>8</bitOffset>
              <bitWidth>1</bitWidth>
            </field>
            <field>
              <name>BR9</name>
              <bitOffset>9</bitOffset>
              <bitWidth>1</bitWidth>
            </field>
            <field>
              <name>BR10</name>
              <bitOffset>10</bitOffset>
              <bitWidth>1</bitWidth>
            </field>
            <field>
              <name>BR11</name>
              <bitOffset>11</bitOffset>
              <bitWidth>1</bitWidth>
            </field>
            <field>
              <name>BR12</name>
              <bitOffset>12</bitOffset>
              <bitWidth>1</bitWidth>
            </field>
            <field>
              <name>BR13</name>
              <bitOffset>13</bitOffset>
              <bitWidth>1</bitWidth>
            </field>
            <field>
              <name>BR14</name>
              <bitOffset>14</bitOffset>
              <bitWidth>1</bitWidth>
            </field>
            <field>
              <name>BR15</name>
              <bitOffset>15</bitOffset>
              <bitWidth>1</bitWidth>
            </field>
          </fields>
        </register>
      </registers>
    </peripheral>
    <peripheral>
      <name>GPIOE</name>
      <baseAddress>0x48001000</baseAddress>
      <registers>
        <register>
          <name>MODER</name>
          <addressOffset>0x0</addressOffset>
          <size>0x20</size>
          <fields>
            <field>
              <name>MODE0</name>
              <bitOffset>0</bitOffset>
              <bitWidth>2</bitWidth>
            </field>
            <field>
              <name>MODE1</name>
              <bitOffset>2</bitOffset>
              <bitWidth>2</bitWidth>
            </field>
            <field>
              <name>MODE2</name>
              <bitOffset>4</bitOffset>
              <bitWidth>2</bitWidth>
            </field>
            <field>
              <name>MODE3</name>
              <bitOffset>6</bitOffset>
              <bitWidth>2</bitWidth>
            </field>
            <field>
              <name>MODE4</name>
              <bitOffset>8</bitOffset>
              <bitWidth>2</bitWidth>
            </field>
            <field>
              <name>MODE5</name>
              <bitOffset>10</bitOffset>
              <bitWidth>2</bitWidth>
            </field>
            <field>
              <name>MODE6</name>
              <bitOffset>12</bitOffset>
              <bitWidth>2</bitWidth>
            </field>
            <field>
              <name>MODE7</name>
              <bitOffset>14</bitOffset>
              <bitWidth>2</bitWidth>
            </field>
            <field>
              <name>MODE8</name>
              <bitOffset>16</bitOffset>
              <bitWidth>2</bitWidth>
            </field>
            <field>
              <name>MODE9</name>
              <bitOffset>18</bitOffset>
              <bitWidth>2</bitWidth>
            </field>
            <field>
              <name>MODE10</name>
              <bitOffset>20</bitOffset>
              <bitWidth>2</bitWidth>
            </field>
            <field>
              <name>MODE11</name>
              <bitOffset>22</bitOffset>
              <bitWidth>2</bitWidth>
            </field>
            <field>
              <name>MODE12</name>
              <bitOffset>24</bitOffset>
              <bitWidth>2</bitWidth>
            </field>
            <field>
              <name>MODE13</name>
              <bitOffset>26</bitOffset>
              <bitWidth>2</bitWidth>
            </field>
            <field>
              <name>MODE14</name>
              <bitOffset>28</bitOffset>
              <bitWidth>2</bitWidth>
            </field>
            <field>
              <name>MODE15</name>
              <bitOffset>30</bitOffset>
              <bitWidth>2</bitWidth>
            </field>
          </fields>
        </register>
        <register>
          <name>OTYPER</name>
          <addressOffset>0x4</addressOffset>
          <size>0x20</size>
          <fields>
            <field>
              <name>OT0</name>
              <bitOffset>0</bitOffset>
              <bitWidth>1</bitWidth>
            </field>
            <field>
              <name>OT1</name>
              <bitOffset>1</bitOffset>
              <bitWidth>1</bitWidth>
            </field>
            <field>
              <name>OT2</name>
              <bitOffset>2</bitOffset>
              <bitWidth>1</bitWidth>
            </field>
            <field>
              <name>OT3</name>
              <bitOffset>3</bitOffset>
              <bitWidth>1</bitWidth>
            </field>
            <field>
              <name>OT4</name>
              <bitOffset>4</bitOffset>
              <bitWidth>1</bitWidth>
            </field>
            <field>
              <name>OT5</name>
              <bitOffset>5</bitOffset>
              <bitWidth>1</bitWidth>
            </field>
            <field>
              <name>OT6</name>
              <bitOffset>6</bitOffset>
              <bitWidth>1</bitWidth>
            </field>
            <field>
              <name>OT7</name>
              <bitOffset>7</bitOffset>
              <bitWidth>1</bitWidth>
            </field>
            <field>
              <name>OT8</name>
              <bitOffset>8</bitOffset>
              <bitWidth>1</bitWidth>
            </field>
            <field>
              <name>OT9</name>
              <bitOffset>9</bitOffset>
              <bitWidth>1</bitWidth>
            </field>
            <field>
              <name>OT10</name>
              <bitOffset>10</bitOffset>
              <bitWidth>1</bitWidth>
            </field>
            <field>
              <name>OT11</name>
              <bitOffset>11</bitOffset>
              <bitWidth>1</bitWidth>
            </field>
            <field>
              <name>OT12</name>
              <bitOffset>12</bitOffset>
              <bitWidth>1</bitWidth>
            </field>
            <field>
              <name>OT13</name>
              <bitOffset>13</bitOffset>
              <bitWidth>1</bitWidth>
            </field>
            <field>
              <name>OT14</name>
              <bitOffset>14</bitOffset>
              <bitWidth>1</bitWidth>
            </field>
            <field>
              <name>OT15</name>
              <bitOffset>15</bitOffset>
              <bitWidth>1</bitWidth>
            </field>
          </fields>
        </register>
        <register>
          <name>OSPEEDR</name>
          <addressOffset>0x8</addressOffset>
          <size>0x20</size>
          <fields>
            <field>
              <name>OSPEED0</name>
              <bitOffset>0</bitOffset>
              <bitWidth>2</bitWidth>
            </field>
            <field>
              <name>OSPEED1</name>
              <bitOffset>2</bitOffset>
              <bitWidth>2</bitWidth>
            </field>
            <field>
              <name>OSPEED2</name>
              <bitOffset>4</bitOffset>
              <bitWidth>2</bitWidth>
            </field>
            <field>
              <name>OSPEED3</name>
              <bitOffset>6</bitOffset>
              <bitWidth>2</bitWidth>
            </field>
            <field>
              <name>OSPEED4</name>
              <bitOffset>8</bitOffset>
              <bitWidth>2</bitWidth>
            </field>
            <field>
              <name>OSPEED5</name>
              <bitOffset>10</bitOffset>
              <bitWidth>2</bitWidth>
            </field>
            <field>
              <name>OSPEED6</name>
              <bitOffset>12</bitOffset>
              <bitWidth>2</bitWidth>
            </field>
            <field>
              <name>OSPEED7</name>
              <bitOffset>14</bitOffset>
              <bitWidth>2</bitWidth>
            </field>
            <field>
              <name>OSPEED8</name>
              <bitOffset>16</bitOffset>
              <bitWidth>2</bitWidth>
            </field>
            <field>
              <name>OSPEED9</name>
              <bitOffset>18</bitOffset>
              <bitWidth>2</bitWidth>
            </field>
            <field>
              <name>OSPEED10</name>
              <bitOffset>20</bitOffset>
              <bitWidth>2</bitWidth>
            </field>
            <field>
              <name>OSPEED11</name>
              <bitOffset>22</bitOffset>
              <bitWidth>2</bitWidth>
            </field>
            <field>
              <name>OSPEED12</name>
              <bitOffset>24</bitOffset>
              <bitWidth>2</bitWidth>
            </field>
            <field>
              <name>OSPEED13</name>
              <bitOffset>26</bitOffset>
              <bitWidth>2</bitWidth>
            </field>
            <field>
              <name>OSPEED14</name>
              <bitOffset>28</bitOffset>
              <bitWidth>2</bitWidth>
            </field>
            <field>
              <name>OSPEED15</name>
              <bitOffset>30</bitOffset>
              <bitWidth>2</bitWidth>
            </field>
          </fields>
        </register>
        <register>
          <name>PUPDR</name>
          <addressOffset>0xc</addressOffset>
          <size>0x20</size>
          <fields>
            <field>
              <name>PUPD0</name>
              <bitOffset>0</bitOffset>
              <bitWidth>2</bitWidth>
            </field>
            <field>
              <name>PUPD1</name>
              <bitOffset>2</bitOffset>
              <bitWidth>2</bitWidth>
            </field>
            <field>
              <name>PUPD2</name>
              <bitOffset>4</bitOffset>
              <bitWidth>2</bitWidth>
            </field>
            <field>
              <name>PUPD3</name>
              <bitOffset>6</bitOffset>
              <bitWidth>2</bitWidth>
            </field>
            <field>
              <name>PUPD4</name>
              <bitOffset>8</bitOffset>
              <bitWidth>2</bitWidth>
            </field>
            <field>
              <name>PUPD5</name>
              <bitOffset>10</bitOffset>
              <bitWidth>2</bitWidth>
            </field>
            <field>
              <name>PUPD6</name>
              <bitOffset>12</bitOffset>
              <bitWidth>2</bitWidth>
            </field>
            <field>
              <name>PUPD7</name>
              <bitOffset>14</bitOffset>
              <bitWidth>2</bitWidth>
            </field>
            <field>
              <name>PUPD8</name>
              <bitOffset>16</bitOffset>
              <bitWidth>2</bitWidth>
            </field>
            <field>
              <name>PUPD9</name>
              <bitOffset>18</bitOffset>
              <bitWidth>2</bitWidth>
            </field>
            <field>
              <name>PUPD10</name>
              <bitOffset>20</bitOffset>
              <bitWidth>2</bitWidth>
            </field>
            <field>
              <name>PUPD11</name>
              <bitOffset>22</bitOffset>
              <bitWidth>2</bitWidth>
            </field>
            <field>
              <name>PUPD12</name>
              <bitOffset>24</bitOffset>
              <bitWidth>2</bitWidth>
            </field>
            <field>
              <name>PUPD13</name>
              <bitOffset>26</bitOffset>
              <bitWidth>2</bitWidth>
            </field>
            <field>
              <name>PUPD14</name>
              <bitOffset>28</bitOffset>
              <bitWidth>2</bitWidth>
            </field>
            <field>
              <name>PUPD15</name>
              <bitOffset>30</bitOffset>
              <bitWidth>2</bitWidth>
            </field>
          </fields>
        </register>
        <register>
          <name>IDR</name>
          <addressOffset>0x10</addressOffset>
          <size>0x20</size>
          <fields>
            <field>
              <name>ID0</name>
              <bitOffset>0</bitOffset>
              <bitWidth>1</bitWidth>
            </field>
            <field>
              <name>ID1</name>
              <bitOffset>1</bitOffset>
              <bitWidth>1</bitWidth>
            </field>
            <field>
              <name>ID2</name>
              <bitOffset>2</bitOffset>
              <bitWidth>1</bitWidth>
            </field>
            <field>
              <name>ID3</name>
              <bitOffset>3</bitOffset>
              <bitWidth>1</bitWidth>
            </field>
            <field>
              <name>ID4</name>
              <bitOffset>4</bitOffset>
              <bitWidth>1</bitWidth>
            </field>
            <field>
              <name>ID5</name>
              <bitOffset>5</bitOffset>
              <bitWidth>1</bitWidth>
            </field>
            <field>
              <name>ID6</name>
              <bitOffset>6</bitOffset>
              <bitWidth>1</bitWidth>
            </field>
            <field>
              <name>ID7</name>
              <bitOffset>7</bitOffset>
              <bitWidth>1</bitWidth>
            </field>
            <field>
              <name>ID8</name>
              <bitOffset>8</bitOffset>
              <bitWidth>1</bitWidth>
            </field>
            <field>
              <name>ID9</name>
              <bitOffset>9</bitOffset>
              <bitWidth>1</bitWidth>
            </field>
            <field>
              <name>ID10</name>
              <bitOffset>10</bitOffset>
              <bitWidth>1</bitWidth>
            </field>
            <field>
              <name>ID11</name>
              <bitOffset>11</bitOffset>
              <bitWidth>1</bitWidth>
            </field>
            <field>
              <name>ID12</name>
              <bitOffset>12</bitOffset>
              <bitWidth>1</bitWidth>
            </field>
            <field>
              <name>ID13</name>
              <bitOffset>13</bitOffset>
              <bitWidth>1</bitWidth>
            </field>
            <field>
              <name>ID14</name>
              <bitOffset>14</bitOffset>
              <bitWidth>1</bitWidth>
            </field>
            <field>
              <name>ID15</name>
              <bitOffset>15</bitOffset>
              <bitWidth>1</bitWidth>
            </field>
          </fields>
        </register>
        <register>
          <name>ODR</name>
          <addressOffset>0x14</addressOffset>
          <size>0x20</size>
          <fields>
            <field>
              <name>OD0</name>
              <bitOffset>0</bitOffset>
              <bitWidth>1</bitWidth>
            </field>
            <field>
              <name>OD1</name>
              <bitOffset>1</bitOffset>
              <bitWidth>1</bitWidth>
            </field>
            <field>
              <name>OD2</name>
              <bitOffset>2</bitOffset>
              <bitWidth>1</bitWidth>
            </field>
            <field>
              <name>OD3</name>
              <bitOffset>3</bitOffset>
              <bitWidth>1</bitWidth>
            </field>
            <field>
              <name>OD4</name>
              <bitOffset>4</bitOffset>
              <bitWidth>1</bitWidth>
            </field>
            <field>
              <name>OD5</name>
              <bitOffset>5</bitOffset>
              <bitWidth>1</bitWidth>
            </field>
            <field>
              <name>OD6</name>
              <bitOffset>6</bitOffset>
              <bitWidth>1</bitWidth>
            </field>
            <field>
              <name>OD7</name>
              <bitOffset>7</bitOffset>
              <bitWidth>1</bitWidth>
            </field>
            <field>
              <name>OD8</name>
              <bitOffset>8</bitOffset>
              <bitWidth>1</bitWidth>
            </field>
            <field>
              <name>OD9</name>
              <bitOffset>9</bitOffset>
              <bitWidth>1</bitWidth>
            </field>
            <field>
              <name>OD10</name>
              <bitOffset>10</bitOffset>
              <bitWidth>1</bitWidth>
            </field>
            <field>
              <name>OD11</name>
              <bitOffset>11</bitOffset>
              <bitWidth>1</bitWidth>
            </field>
            <field>
              <name>OD12</name>
              <bitOffset>12</bitOffset>
              <bitWidth>1</bitWidth>
            </field>
            <field>
              <name>OD13</name>
              <bitOffset>13</bitOffset>
              <bitWidth>1</bitWidth>
            </field>
            <field>
              <name>OD14</name>
              <bitOffset>14</bitOffset>
              <bitWidth>1</bitWidth>
            </field>
            <field>
              <name>OD15</name>
              <bitOffset>15</bitOffset>
              <bitWidth>1</bitWidth>
            </field>
          </fields>
        </register>
        <register>
          <name>BSRR</name>
          <addressOffset>0x18</addressOffset>
          <size>0x20</size>
          <fields>
            <field>
              <name>BS0</name>
              <bitOffset>0</bitOffset>
              <bitWidth>1</bitWidth>
            </field>
            <field>
              <name>BS1</name>
              <bitOffset>1</bitOffset>
              <bitWidth>1</bitWidth>
            </field>
            <field>
              <name>BS2</name>
              <bitOffset>2</bitOffset>
              <bitWidth>1</bitWidth>
            </field>
            <field>
              <name>BS3</name>
              <bitOffset>3</bitOffset>
              <bitWidth>1</bitWidth>
            </field>
            <field>
              <name>BS4</name>
              <bitOffset>4</bitOffset>
              <bitWidth>1</bitWidth>
            </field>
            <field>
              <name>BS5</name>
              <bitOffset>5</bitOffset>
              <bitWidth>1</bitWidth>
            </field>
            <field>
              <name>BS6</name>
              <bitOffset>6</bitOffset>
              <bitWidth>1</bitWidth>
            </field>
            <field>
              <name>BS7</name>
              <bitOffset>7</bitOffset>
              <bitWidth>1</bitWidth>
            </field>
            <field>
              <name>BS8</name>
              <bitOffset>8</bitOffset>
              <bitWidth>1</bitWidth>
            </field>
            <field>
              <name>BS9</name>
              <bitOffset>9</bitOffset>
              <bitWidth>1</bitWidth>
            </field>
            <field>
              <name>BS10</name>
              <bitOffset>10</bitOffset>
              <bitWidth>1</bitWidth>
            </field>
            <field>
              <name>BS11</name>
              <bitOffset>11</bitOffset>
              <bitWidth>1</bitWidth>
            </field>
            <field>
              <name>BS12</name>
              <bitOffset>12</bitOffset>
              <bitWidth>1</bitWidth>
            </field>
            <field>
              <name>BS13</name>
              <bitOffset>13</bitOffset>
              <bitWidth>1</bitWidth>
            </field>
            <field>
              <name>BS14</name>
              <bitOffset>14</bitOffset>
              <bitWidth>1</bitWidth>
            </field>
            <field>
              <name>BS15</name>
              <bitOffset>15</bitOffset>
              <bitWidth>1</bitWidth>
            </field>
            <field>
              <name>BR0</name>
              <bitOffset>16</bitOffset>
              <bitWidth>1</bitWidth>
            </field>
            <field>
              <name>BR1</name>
              <bitOffset>17</bitOffset>
              <bitWidth>1</bitWidth>
            </field>
            <field>
              <name>BR2</name>
              <bitOffset>18</bitOffset>
              <bitWidth>1</bitWidth>
            </field>
            <field>
              <name>BR3</name>
              <bitOffset>19</bitOffset>
              <bitWidth>1</bitWidth>
            </field>
            <field>
              <name>BR4</name>
              <bitOffset>20</bitOffset>
              <bitWidth>1</bitWidth>
            </field>
            <field>
              <name>BR5</name>
              <bitOffset>21</bitOffset>
              <bitWidth>1</bitWidth>
            </field>
            <field>
              <name>BR6</name>
              <bitOffset>22</bitOffset>
              <bitWidth>1</bitWidth>
            </field>
            <field>
              <name>BR7</name>
              <bitOffset>23</bitOffset>
              <bitWidth>1</bitWidth>
            </field>
            <field>
              <name>BR8</name>
              <bitOffset>24</bitOffset>
              <bitWidth>1</bitWidth>
            </field>
            <field>
              <name>BR9</name>
              <bitOffset>25</bitOffset>
              <bitWidth>1</bitWidth>
            </field>
            <field>
              <name>BR10</name>
              <bitOffset>26</bitOffset>
              <bitWidth>1</bitWidth>
            </field>
            <field>
              <name>BR11</name>
              <bitOffset>27</bitOffset>
              <bitWidth>1</bitWidth>
            </field>
            <field>
              <name>BR12</name>
              <bitOffset>28</bitOffset>
              <bitWidth>1</bitWidth>
            </field>
            <field>
              <name>BR13</name>
              <bitOffset>29</bitOffset>
              <bitWidth>1</bitWidth>
            </field>
            <field>
              <name>BR14</name>
              <bitOffset>30</bitOffset>
              <bitWidth>1</bitWidth>
            </field>
            <field>
              <name>BR15</name>
              <bitOffset>31</bitOffset>
              <bitWidth>1</bitWidth>
            </field>
          </fields>
        </register>
        <register>
          <name>LCKR</name>
          <addressOffset>0x1c</addressOffset>
          <size>0x20</size>
          <fields>
            <field>
              <name>LCK0</name>
              <bitOffset>0</bitOffset>
              <bitWidth>1</bitWidth>
            </field>
            <field>
              <name>LCK1</name>
              <bitOffset>1</bitOffset>
              <bitWidth>1</bitWidth>
            </field>
            <field>
              <name>LCK2</name>
              <bitOffset>2</bitOffset>
              <bitWidth>1</bitWidth>
            </field>
            <field>
              <name>LCK3</name>
              <bitOffset>3</bitOffset>
              <bitWidth>1</bitWidth>
            </field>
            <field>
              <name>LCK4</name>
              <bitOffset>4</bitOffset>
              <bitWidth>1</bitWidth>
            </field>
            <field>
              <name>LCK5</name>
              <bitOffset>5</bitOffset>
              <bitWidth>1</bitWidth>
            </field>
            <field>
              <name>LCK6</name>
              <bitOffset>6</bitOffset>
              <bitWidth>1</bitWidth>
            </field>
            <field>
              <name>LCK7</name>
              <bitOffset>7</bitOffset>
              <bitWidth>1</bitWidth>
            </field>
            <field>
              <name>LCK8</name>
              <bitOffset>8</bitOffset>
              <bitWidth>1</bitWidth>
            </field>
            <field>
              <name>LCK9</name>
              <bitOffset>9</bitOffset>
              <bitWidth>1</bitWidth>
            </field>
            <field>
              <name>LCK10</name>
              <bitOffset>10</bitOffset>
              <bitWidth>1</bitWidth>
            </field>
            <field>
              <name>LCK11</name>
              <bitOffset>11</bitOffset>
              <bitWidth>1</bitWidth>
            </field>
            <field>
              <name>LCK12</name>
              <bitOffset>12</bitOffset>
              <bitWidth>1</bitWidth>
            </field>
            <field>
              <name>LCK13</name>
              <bitOffset>13</bitOffset>
              <bitWidth>1</bitWidth>
            </field>
            <field>
              <name>LCK14</name>
              <bitOffset>14</bitOffset>
              <bitWidth>1</bitWidth>
            </field>
            <field>
              <name>LCK15</name>
              <bitOffset>15</bitOffset>
              <bitWidth>1</bitWidth>
            </field>
            <field>
              <name>LCKK</name>
              <bitOffset>16</bitOffset>
              <bitWidth>1</bitWidth>
            </field>
          </fields>
        </register>
        <register>
          <name>AFR.0</name>
          <addressOffset>0x20</addressOffset>
          <size>0x20</size>
          <fields>
            <field>
              <name>AFSEL0</name>
              <bitOffset>0</bitOffset>
              <bitWidth>4</bitWidth>
            </field>
            <field>
              <name>AFSEL1</name>
              <bitOffset>4</bitOffset>
              <bitWidth>4</bitWidth>
            </field>
            <field>
              <name>AFSEL2</name>
              <bitOffset>8</bitOffset>
              <bitWidth>4</bitWidth>
            </field>
            <field>
              <name>AFSEL3</name>
              <bitOffset>12</bitOffset>
              <bitWidth>4</bitWidth>
            </field>
            <field>
              <name>AFSEL4</name>
              <bitOffset>16</bitOffset>
              <bitWidth>4</bitWidth>
            </field>
            <field>
              <name>AFSEL5</name>
              <bitOffset>20</bitOffset>
              <bitWidth>4</bitWidth>
            </field>
            <field>
              <name>AFSEL6</name>
              <bitOffset>24</bitOffset>
              <bitWidth>4</bitWidth>
            </field>
            <field>
              <name>AFSEL7</name>
              <bitOffset>28</bitOffset>
              <bitWidth>4</bitWidth>
            </field>
          </fields>
        </register>
        <register>
          <name>AFR.1</name>
          <addressOffset>0x24</addressOffset>
          <size>0x20</size>
          <fields>
            <field>
              <name>AFSEL8</name>
              <bitOffset>0</bitOffset>
              <bitWidth>4</bitWidth>
            </field>
            <field>
              <name>AFSEL9</name>
              <bitOffset>4</bitOffset>
              <bitWidth>4</bitWidth>
            </field>
            <field>
              <name>AFSEL10</name>
              <bitOffset>8</bitOffset>
              <bitWidth>4</bitWidth>
            </field>
            <field>
              <name>AFSEL11</name>
              <bitOffset>12</bitOffset>
              <bitWidth>4</bitWidth>
            </field>
            <field>
              <name>AFSEL12</name>
              <bitOffset>16</bitOffset>
              <bitWidth>4</bitWidth>
            </field>
            <field>
              <name>AFSEL13</name>
              <bitOffset>20</bitOffset>
              <bitWidth>4</bitWidth>
            </field>
            <field>
              <name>AFSEL14</name>
              <bitOffset>24</bitOffset>
              <bitWidth>4</bitWidth>
            </field>
            <field>
              <name>AFSEL15</name>
              <bitOffset>28</bitOffset>
              <bitWidth>4</bitWidth>
            </field>
          </fields>
        </register>
        <register>
          <name>BRR</name>
          <addressOffset>0x28</addressOffset>
          <size>0x20</size>
          <fields>
            <field>
              <name>BR0</name>
              <bitOffset>0</bitOffset>
              <bitWidth>1</bitWidth>
            </field>
            <field>
              <name>BR1</name>
              <bitOffset>1</bitOffset>
              <bitWidth>1</bitWidth>
            </field>
            <field>
              <name>BR2</name>
              <bitOffset>2</bitOffset>
              <bitWidth>1</bitWidth>
            </field>
            <field>
              <name>BR3</name>
              <bitOffset>3</bitOffset>
              <bitWidth>1</bitWidth>
            </field>
            <field>
              <name>BR4</name>
              <bitOffset>4</bitOffset>
              <bitWidth>1</bitWidth>
            </field>
            <field>
              <name>BR5</name>
              <bitOffset>5</bitOffset>
              <bitWidth>1</bitWidth>
            </field>
            <field>
              <name>BR6</name>
              <bitOffset>6</bitOffset>
              <bitWidth>1</bitWidth>
            </field>
            <field>
              <name>BR7</name>
              <bitOffset>7</bitOffset>
              <bitWidth>1</bitWidth>
            </field>
            <field>
              <name>BR8</name>
              <bitOffset>8</bitOffset>
              <bitWidth>1</bitWidth>
            </field>
            <field>
              <name>BR9</name>
              <bitOffset>9</bitOffset>
              <bitWidth>1</bitWidth>
            </field>
            <field>
              <name>BR10</name>
              <bitOffset>10</bitOffset>
              <bitWidth>1</bitWidth>
            </field>
            <field>
              <name>BR11</name>
              <bitOffset>11</bitOffset>
              <bitWidth>1</bitWidth>
            </field>
            <field>
              <name>BR12</name>
              <bitOffset>12</bitOffset>
              <bitWidth>1</bitWidth>
            </field>
            <field>
              <name>BR13</name>
              <bitOffset>13</bitOffset>
              <bitWidth>1</bitWidth>
            </field>
            <field>
              <name>BR14</name>
              <bitOffset>14</bitOffset>
              <bitWidth>1</bitWidth>
            </field>
            <field>
              <name>BR15</name>
              <bitOffset>15</bitOffset>
              <bitWidth>1</bitWidth>
            </field>
          </fields>
        </register>
      </registers>
    </peripheral>
    <peripheral>
      <name>GPIOF</name>
      <baseAddress>0x48001400</baseAddress>
      <registers>
        <register>
          <name>MODER</name>
          <addressOffset>0x0</addressOffset>
          <size>0x20</size>
          <fields>
            <field>
              <name>MODE0</name>
              <bitOffset>0</bitOffset>
              <bitWidth>2</bitWidth>
            </field>
            <field>
              <name>MODE1</name>
              <bitOffset>2</bitOffset>
              <bitWidth>2</bitWidth>
            </field>
            <field>
              <name>MODE2</name>
              <bitOffset>4</bitOffset>
              <bitWidth>2</bitWidth>
            </field>
            <field>
              <name>MODE3</name>
              <bitOffset>6</bitOffset>
              <bitWidth>2</bitWidth>
            </field>
            <field>
              <name>MODE4</name>
              <bitOffset>8</bitOffset>
              <bitWidth>2</bitWidth>
            </field>
            <field>
              <name>MODE5</name>
              <bitOffset>10</bitOffset>
              <bitWidth>2</bitWidth>
            </field>
            <field>
              <name>MODE6</name>
              <bitOffset>12</bitOffset>
              <bitWidth>2</bitWidth>
            </field>
            <field>
              <name>MODE7</name>
              <bitOffset>14</bitOffset>
              <bitWidth>2</bitWidth>
            </field>
            <field>
              <name>MODE8</name>
              <bitOffset>16</bitOffset>
              <bitWidth>2</bitWidth>
            </field>
            <field>
              <name>MODE9</name>
              <bitOffset>18</bitOffset>
              <bitWidth>2</bitWidth>
            </field>
            <field>
              <name>MODE10</name>
              <bitOffset>20</bitOffset>
              <bitWidth>2</bitWidth>
            </field>
            <field>
              <name>MODE11</name>
              <bitOffset>22</bitOffset>
              <bitWidth>2</bitWidth>
            </field>
            <field>
              <name>MODE12</name>
              <bitOffset>24</bitOffset>
              <bitWidth>2</bitWidth>
            </field>
            <field>
              <name>MODE13</name>
              <bitOffset>26</bitOffset>
              <bitWidth>2</bitWidth>
            </field>
            <field>
              <name>MODE14</name>
              <bitOffset>28</bitOffset>
              <bitWidth>2</bitWidth>
            </field>
            <field>
              <name>MODE15</name>
              <bitOffset>30</bitOffset>
              <bitWidth>2</bitWidth>
            </field>
          </fields>
        </register>
        <register>
          <name>OTYPER</name>
          <addressOffset>0x4</addressOffset>
          <size>0x20</size>
          <fields>
            <field>
              <name>OT0</name>
              <bitOffset>0</bitOffset>
              <bitWidth>1</bitWidth>
            </field>
            <field>
              <name>OT1</name>
              <bitOffset>1</bitOffset>
              <bitWidth>1</bitWidth>
            </field>
            <field>
              <name>OT2</name>
              <bitOffset>2</bitOffset>
              <bitWidth>1</bitWidth>
            </field>
            <field>
              <name>OT3</name>
              <bitOffset>3</bitOffset>
              <bitWidth>1</bitWidth>
            </field>
            <field>
              <name>OT4</name>
              <bitOffset>4</bitOffset>
              <bitWidth>1</bitWidth>
            </field>
            <field>
              <name>OT5</name>
              <bitOffset>5</bitOffset>
              <bitWidth>1</bitWidth>
            </field>
            <field>
              <name>OT6</name>
              <bitOffset>6</bitOffset>
              <bitWidth>1</bitWidth>
            </field>
            <field>
              <name>OT7</name>
              <bitOffset>7</bitOffset>
              <bitWidth>1</bitWidth>
            </field>
            <field>
              <name>OT8</name>
              <bitOffset>8</bitOffset>
              <bitWidth>1</bitWidth>
            </field>
            <field>
              <name>OT9</name>
              <bitOffset>9</bitOffset>
              <bitWidth>1</bitWidth>
            </field>
            <field>
              <name>OT10</name>
              <bitOffset>10</bitOffset>
              <bitWidth>1</bitWidth>
            </field>
            <field>
              <name>OT11</name>
              <bitOffset>11</bitOffset>
              <bitWidth>1</bitWidth>
            </field>
            <field>
              <name>OT12</name>
              <bitOffset>12</bitOffset>
              <bitWidth>1</bitWidth>
            </field>
            <field>
              <name>OT13</name>
              <bitOffset>13</bitOffset>
              <bitWidth>1</bitWidth>
            </field>
            <field>
              <name>OT14</name>
              <bitOffset>14</bitOffset>
              <bitWidth>1</bitWidth>
            </field>
            <field>
              <name>OT15</name>
              <bitOffset>15</bitOffset>
              <bitWidth>1</bitWidth>
            </field>
          </fields>
        </register>
        <register>
          <name>OSPEEDR</name>
          <addressOffset>0x8</addressOffset>
          <size>0x20</size>
          <fields>
            <field>
              <name>OSPEED0</name>
              <bitOffset>0</bitOffset>
              <bitWidth>2</bitWidth>
            </field>
            <field>
              <name>OSPEED1</name>
              <bitOffset>2</bitOffset>
              <bitWidth>2</bitWidth>
            </field>
            <field>
              <name>OSPEED2</name>
              <bitOffset>4</bitOffset>
              <bitWidth>2</bitWidth>
            </field>
            <field>
              <name>OSPEED3</name>
              <bitOffset>6</bitOffset>
              <bitWidth>2</bitWidth>
            </field>
            <field>
              <name>OSPEED4</name>
              <bitOffset>8</bitOffset>
              <bitWidth>2</bitWidth>
            </field>
            <field>
              <name>OSPEED5</name>
              <bitOffset>10</bitOffset>
              <bitWidth>2</bitWidth>
            </field>
            <field>
              <name>OSPEED6</name>
              <bitOffset>12</bitOffset>
              <bitWidth>2</bitWidth>
            </field>
            <field>
              <name>OSPEED7</name>
              <bitOffset>14</bitOffset>
              <bitWidth>2</bitWidth>
            </field>
            <field>
              <name>OSPEED8</name>
              <bitOffset>16</bitOffset>
              <bitWidth>2</bitWidth>
            </field>
            <field>
              <name>OSPEED9</name>
              <bitOffset>18</bitOffset>
              <bitWidth>2</bitWidth>
            </field>
            <field>
              <name>OSPEED10</name>
              <bitOffset>20</bitOffset>
              <bitWidth>2</bitWidth>
            </field>
            <field>
              <name>OSPEED11</name>
              <bitOffset>22</bitOffset>
              <bitWidth>2</bitWidth>
            </field>
            <field>
              <name>OSPEED12</name>
              <bitOffset>24</bitOffset>
              <bitWidth>2</bitWidth>
            </field>
            <field>
              <name>OSPEED13</name>
              <bitOffset>26</bitOffset>
              <bitWidth>2</bitWidth>
            </field>
            <field>
              <name>OSPEED14</name>
              <bitOffset>28</bitOffset>
              <bitWidth>2</bitWidth>
            </field>
            <field>
              <name>OSPEED15</name>
              <bitOffset>30</bitOffset>
              <bitWidth>2</bitWidth>
            </field>
          </fields>
        </register>
        <register>
          <name>PUPDR</name>
          <addressOffset>0xc</addressOffset>
          <size>0x20</size>
          <fields>
            <field>
              <name>PUPD0</name>
              <bitOffset>0</bitOffset>
              <bitWidth>2</bitWidth>
            </field>
            <field>
              <name>PUPD1</name>
              <bitOffset>2</bitOffset>
              <bitWidth>2</bitWidth>
            </field>
            <field>
              <name>PUPD2</name>
              <bitOffset>4</bitOffset>
              <bitWidth>2</bitWidth>
            </field>
            <field>
              <name>PUPD3</name>
              <bitOffset>6</bitOffset>
              <bitWidth>2</bitWidth>
            </field>
            <field>
              <name>PUPD4</name>
              <bitOffset>8</bitOffset>
              <bitWidth>2</bitWidth>
            </field>
            <field>
              <name>PUPD5</name>
              <bitOffset>10</bitOffset>
              <bitWidth>2</bitWidth>
            </field>
            <field>
              <name>PUPD6</name>
              <bitOffset>12</bitOffset>
              <bitWidth>2</bitWidth>
            </field>
            <field>
              <name>PUPD7</name>
              <bitOffset>14</bitOffset>
              <bitWidth>2</bitWidth>
            </field>
            <field>
              <name>PUPD8</name>
              <bitOffset>16</bitOffset>
              <bitWidth>2</bitWidth>
            </field>
            <field>
              <name>PUPD9</name>
              <bitOffset>18</bitOffset>
              <bitWidth>2</bitWidth>
            </field>
            <field>
              <name>PUPD10</name>
              <bitOffset>20</bitOffset>
              <bitWidth>2</bitWidth>
            </field>
            <field>
              <name>PUPD11</name>
              <bitOffset>22</bitOffset>
              <bitWidth>2</bitWidth>
            </field>
            <field>
              <name>PUPD12</name>
              <bitOffset>24</bitOffset>
              <bitWidth>2</bitWidth>
            </field>
            <field>
              <name>PUPD13</name>
              <bitOffset>26</bitOffset>
              <bitWidth>2</bitWidth>
            </field>
            <field>
              <name>PUPD14</name>
              <bitOffset>28</bitOffset>
              <bitWidth>2</bitWidth>
            </field>
            <field>
              <name>PUPD15</name>
              <bitOffset>30</bitOffset>
              <bitWidth>2</bitWidth>
            </field>
          </fields>
        </register>
        <register>
          <name>IDR</name>
          <addressOffset>0x10</addressOffset>
          <size>0x20</size>
          <fields>
            <field>
              <name>ID0</name>
              <bitOffset>0</bitOffset>
              <bitWidth>1</bitWidth>
            </field>
            <field>
              <name>ID1</name>
              <bitOffset>1</bitOffset>
              <bitWidth>1</bitWidth>
            </field>
            <field>
              <name>ID2</name>
              <bitOffset>2</bitOffset>
              <bitWidth>1</bitWidth>
            </field>
            <field>
              <name>ID3</name>
              <bitOffset>3</bitOffset>
              <bitWidth>1</bitWidth>
            </field>
            <field>
              <name>ID4</name>
              <bitOffset>4</bitOffset>
              <bitWidth>1</bitWidth>
            </field>
            <field>
              <name>ID5</name>
              <bitOffset>5</bitOffset>
              <bitWidth>1</bitWidth>
            </field>
            <field>
              <name>ID6</name>
              <bitOffset>6</bitOffset>
              <bitWidth>1</bitWidth>
            </field>
            <field>
              <name>ID7</name>
              <bitOffset>7</bitOffset>
              <bitWidth>1</bitWidth>
            </field>
            <field>
              <name>ID8</name>
              <bitOffset>8</bitOffset>
              <bitWidth>1</bitWidth>
            </field>
            <field>
              <name>ID9</name>
              <bitOffset>9</bitOffset>
              <bitWidth>1</bitWidth>
            </field>
            <field>
              <name>ID10</name>
              <bitOffset>10</bitOffset>
              <bitWidth>1</bitWidth>
            </field>
            <field>
              <name>ID11</name>
              <bitOffset>11</bitOffset>
              <bitWidth>1</bitWidth>
            </field>
            <field>
              <name>ID12</name>
              <bitOffset>12</bitOffset>
              <bitWidth>1</bitWidth>
            </field>
            <field>
              <name>ID13</name>
              <bitOffset>13</bitOffset>
              <bitWidth>1</bitWidth>
            </field>
            <field>
              <name>ID14</name>
              <bitOffset>14</bitOffset>
              <bitWidth>1</bitWidth>
            </field>
            <field>
              <name>ID15</name>
              <bitOffset>15</bitOffset>
              <bitWidth>1</bitWidth>
            </field>
          </fields>
        </register>
        <register>
          <name>ODR</name>
          <addressOffset>0x14</addressOffset>
          <size>0x20</size>
          <fields>
            <field>
              <name>OD0</name>
              <bitOffset>0</bitOffset>
              <bitWidth>1</bitWidth>
            </field>
            <field>
              <name>OD1</name>
              <bitOffset>1</bitOffset>
              <bitWidth>1</bitWidth>
            </field>
            <field>
              <name>OD2</name>
              <bitOffset>2</bitOffset>
              <bitWidth>1</bitWidth>
            </field>
            <field>
              <name>OD3</name>
              <bitOffset>3</bitOffset>
              <bitWidth>1</bitWidth>
            </field>
            <field>
              <name>OD4</name>
              <bitOffset>4</bitOffset>
              <bitWidth>1</bitWidth>
            </field>
            <field>
              <name>OD5</name>
              <bitOffset>5</bitOffset>
              <bitWidth>1</bitWidth>
            </field>
            <field>
              <name>OD6</name>
              <bitOffset>6</bitOffset>
              <bitWidth>1</bitWidth>
            </field>
            <field>
              <name>OD7</name>
              <bitOffset>7</bitOffset>
              <bitWidth>1</bitWidth>
            </field>
            <field>
              <name>OD8</name>
              <bitOffset>8</bitOffset>
              <bitWidth>1</bitWidth>
            </field>
            <field>
              <name>OD9</name>
              <bitOffset>9</bitOffset>
              <bitWidth>1</bitWidth>
            </field>
            <field>
              <name>OD10</name>
              <bitOffset>10</bitOffset>
              <bitWidth>1</bitWidth>
            </field>
            <field>
              <name>OD11</name>
              <bitOffset>11</bitOffset>
              <bitWidth>1</bitWidth>
            </field>
            <field>
              <name>OD12</name>
              <bitOffset>12</bitOffset>
              <bitWidth>1</bitWidth>
            </field>
            <field>
              <name>OD13</name>
              <bitOffset>13</bitOffset>
              <bitWidth>1</bitWidth>
            </field>
            <field>
              <name>OD14</name>
              <bitOffset>14</bitOffset>
              <bitWidth>1</bitWidth>
            </field>
            <field>
              <name>OD15</name>
              <bitOffset>15</bitOffset>
              <bitWidth>1</bitWidth>
            </field>
          </fields>
        </register>
        <register>
          <name>BSRR</name>
          <addressOffset>0x18</addressOffset>
          <size>0x20</size>
          <fields>
            <field>
              <name>BS0</name>
              <bitOffset>0</bitOffset>
              <bitWidth>1</bitWidth>
            </field>
            <field>
              <name>BS1</name>
              <bitOffset>1</bitOffset>
              <bitWidth>1</bitWidth>
            </field>
            <field>
              <name>BS2</name>
              <bitOffset>2</bitOffset>
              <bitWidth>1</bitWidth>
            </field>
            <field>
              <name>BS3</name>
              <bitOffset>3</bitOffset>
              <bitWidth>1</bitWidth>
            </field>
            <field>
              <name>BS4</name>
              <bitOffset>4</bitOffset>
              <bitWidth>1</bitWidth>
            </field>
            <field>
              <name>BS5</name>
              <bitOffset>5</bitOffset>
              <bitWidth>1</bitWidth>
            </field>
            <field>
              <name>BS6</name>
              <bitOffset>6</bitOffset>
              <bitWidth>1</bitWidth>
            </field>
            <field>
              <name>BS7</name>
              <bitOffset>7</bitOffset>
              <bitWidth>1</bitWidth>
            </field>
            <field>
              <name>BS8</name>
              <bitOffset>8</bitOffset>
              <bitWidth>1</bitWidth>
            </field>
            <field>
              <name>BS9</name>
              <bitOffset>9</bitOffset>
              <bitWidth>1</bitWidth>
            </field>
            <field>
              <name>BS10</name>
              <bitOffset>10</bitOffset>
              <bitWidth>1</bitWidth>
            </field>
            <field>
              <name>BS11</name>
              <bitOffset>11</bitOffset>
              <bitWidth>1</bitWidth>
            </field>
            <field>
              <name>BS12</name>
              <bitOffset>12</bitOffset>
              <bitWidth>1</bitWidth>
            </field>
            <field>
              <name>BS13</name>
              <bitOffset>13</bitOffset>
              <bitWidth>1</bitWidth>
            </field>
            <field>
              <name>BS14</name>
              <bitOffset>14</bitOffset>
              <bitWidth>1</bitWidth>
            </field>
            <field>
              <name>BS15</name>
              <bitOffset>15</bitOffset>
              <bitWidth>1</bitWidth>
            </field>
            <field>
              <name>BR0</name>
              <bitOffset>16</bitOffset>
              <bitWidth>1</bitWidth>
            </field>
            <field>
              <name>BR1</name>
              <bitOffset>17</bitOffset>
              <bitWidth>1</bitWidth>
            </field>
            <field>
              <name>BR2</name>
              <bitOffset>18</bitOffset>
              <bitWidth>1</bitWidth>
            </field>
            <field>
              <name>BR3</name>
              <bitOffset>19</bitOffset>
              <bitWidth>1</bitWidth>
            </field>
            <field>
              <name>BR4</name>
              <bitOffset>20</bitOffset>
              <bitWidth>1</bitWidth>
            </field>
            <field>
              <name>BR5</name>
              <bitOffset>21</bitOffset>
              <bitWidth>1</bitWidth>
            </field>
            <field>
              <name>BR6</name>
              <bitOffset>22</bitOffset>
              <bitWidth>1</bitWidth>
            </field>
            <field>
              <name>BR7</name>
              <bitOffset>23</bitOffset>
              <bitWidth>1</bitWidth>
            </field>
            <field>
              <name>BR8</name>
              <bitOffset>24</bitOffset>
              <bitWidth>1</bitWidth>
            </field>
            <field>
              <name>BR9</name>
              <bitOffset>25</bitOffset>
              <bitWidth>1</bitWidth>
            </field>
            <field>
              <name>BR10</name>
              <bitOffset>26</bitOffset>
              <bitWidth>1</bitWidth>
            </field>
            <field>
              <name>BR11</name>
              <bitOffset>27</bitOffset>
              <bitWidth>1</bitWidth>
            </field>
            <field>
              <name>BR12</name>
              <bitOffset>28</bitOffset>
              <bitWidth>1</bitWidth>
            </field>
            <field>
              <name>BR13</name>
              <bitOffset>29</bitOffset>
              <bitWidth>1</bitWidth>
            </field>
            <field>
              <name>BR14</name>
              <bitOffset>30</bitOffset>
              <bitWidth>1</bitWidth>
            </field>
            <field>
              <name>BR15</name>
              <bitOffset>31</bitOffset>
              <bitWidth>1</bitWidth>
            </field>
          </fields>
        </register>
        <register>
          <name>LCKR</name>
          <addressOffset>0x1c</addressOffset>
          <size>0x20</size>
          <fields>
            <field>
              <name>LCK0</name>
              <bitOffset>0</bitOffset>
              <bitWidth>1</bitWidth>
            </field>
            <field>
              <name>LCK1</name>
              <bitOffset>1</bitOffset>
              <bitWidth>1</bitWidth>
            </field>
            <field>
              <name>LCK2</name>
              <bitOffset>2</bitOffset>
              <bitWidth>1</bitWidth>
            </field>
            <field>
              <name>LCK3</name>
              <bitOffset>3</bitOffset>
              <bitWidth>1</bitWidth>
            </field>
            <field>
              <name>LCK4</name>
              <bitOffset>4</bitOffset>
              <bitWidth>1</bitWidth>
            </field>
            <field>
              <name>LCK5</name>
              <bitOffset>5</bitOffset>
              <bitWidth>1</bitWidth>
            </field>
            <field>
              <name>LCK6</name>
              <bitOffset>6</bitOffset>
              <bitWidth>1</bitWidth>
            </field>
            <field>
              <name>LCK7</name>
              <bitOffset>7</bitOffset>
              <bitWidth>1</bitWidth>
            </field>
            <field>
              <name>LCK8</name>
              <bitOffset>8</bitOffset>
              <bitWidth>1</bitWidth>
            </field>
            <field>
              <name>LCK9</name>
              <bitOffset>9</bitOffset>
              <bitWidth>1</bitWidth>
            </field>
            <field>
              <name>LCK10</name>
              <bitOffset>10</bitOffset>
              <bitWidth>1</bitWidth>
            </field>
            <field>
              <name>LCK11</name>
              <bitOffset>11</bitOffset>
              <bitWidth>1</bitWidth>
            </field>
            <field>
              <name>LCK12</name>
              <bitOffset>12</bitOffset>
              <bitWidth>1</bitWidth>
            </field>
            <field>
              <name>LCK13</name>
              <bitOffset>13</bitOffset>
              <bitWidth>1</bitWidth>
            </field>
            <field>
              <name>LCK14</name>
              <bitOffset>14</bitOffset>
              <bitWidth>1</bitWidth>
            </field>
            <field>
              <name>LCK15</name>
              <bitOffset>15</bitOffset>
              <bitWidth>1</bitWidth>
            </field>
            <field>
              <name>LCKK</name>
              <bitOffset>16</bitOffset>
              <bitWidth>1</bitWidth>
            </field>
          </fields>
        </register>
        <register>
          <name>AFR.0</name>
          <addressOffset>0x20</addressOffset>
          <size>0x20</size>
          <fields>
            <field>
              <name>AFSEL0</name>
              <bitOffset>0</bitOffset>
              <bitWidth>4</bitWidth>
            </field>
            <field>
              <name>AFSEL1</name>
              <bitOffset>4</bitOffset>
              <bitWidth>4</bitWidth>
            </field>
            <field>
              <name>AFSEL2</name>
              <bitOffset>8</bitOffset>
              <bitWidth>4</bitWidth>
            </field>
            <field>
              <name>AFSEL3</name>
              <bitOffset>12</bitOffset>
              <bitWidth>4</bitWidth>
            </field>
            <field>
              <name>AFSEL4</name>
              <bitOffset>16</bitOffset>
              <bitWidth>4</bitWidth>
            </field>
            <field>
              <name>AFSEL5</name>
              <bitOffset>20</bitOffset>
              <bitWidth>4</bitWidth>
            </field>
            <field>
              <name>AFSEL6</name>
              <bitOffset>24</bitOffset>
              <bitWidth>4</bitWidth>
            </field>
            <field>
              <name>AFSEL7</name>
              <bitOffset>28</bitOffset>
              <bitWidth>4</bitWidth>
            </field>
          </fields>
        </register>
        <register>
          <name>AFR.1</name>
          <addressOffset>0x24</addressOffset>
          <size>0x20</size>
          <fields>
            <field>
              <name>AFSEL8</name>
              <bitOffset>0</bitOffset>
              <bitWidth>4</bitWidth>
            </field>
            <field>
              <name>AFSEL9</name>
              <bitOffset>4</bitOffset>
              <bitWidth>4</bitWidth>
            </field>
            <field>
              <name>AFSEL10</name>
              <bitOffset>8</bitOffset>
              <bitWidth>4</bitWidth>
            </field>
            <field>
              <name>AFSEL11</name>
              <bitOffset>12</bitOffset>
              <bitWidth>4</bitWidth>
            </field>
            <field>
              <name>AFSEL12</name>
              <bitOffset>16</bitOffset>
              <bitWidth>4</bitWidth>
            </field>
            <field>
              <name>AFSEL13</name>
              <bitOffset>20</bitOffset>
              <bitWidth>4</bitWidth>
            </field>
            <field>
              <name>AFSEL14</name>
              <bitOffset>24</bitOffset>
              <bitWidth>4</bitWidth>
            </field>
            <field>
              <name>AFSEL15</name>
              <bitOffset>28</bitOffset>
              <bitWidth>4</bitWidth>
            </field>
          </fields>
        </register>
        <register>
          <name>BRR</name>
          <addressOffset>0x28</addressOffset>
          <size>0x20</size>
          <fields>
            <field>
              <name>BR0</name>
              <bitOffset>0</bitOffset>
              <bitWidth>1</bitWidth>
            </field>
            <field>
              <name>BR1</name>
              <bitOffset>1</bitOffset>
              <bitWidth>1</bitWidth>
            </field>
            <field>
              <name>BR2</name>
              <bitOffset>2</bitOffset>
              <bitWidth>1</bitWidth>
            </field>
            <field>
              <name>BR3</name>
              <bitOffset>3</bitOffset>
              <bitWidth>1</bitWidth>
            </field>
            <field>
              <name>BR4</name>
              <bitOffset>4</bitOffset>
              <bitWidth>1</bitWidth>
            </field>
            <field>
              <name>BR5</name>
              <bitOffset>5</bitOffset>
              <bitWidth>1</bitWidth>
            </field>
            <field>
              <name>BR6</name>
              <bitOffset>6</bitOffset>
              <bitWidth>1</bitWidth>
            </field>
            <field>
              <name>BR7</name>
              <bitOffset>7</bitOffset>
              <bitWidth>1</bitWidth>
            </field>
            <field>
              <name>BR8</name>
              <bitOffset>8</bitOffset>
              <bitWidth>1</bitWidth>
            </field>
            <field>
              <name>BR9</name>
              <bitOffset>9</bitOffset>
              <bitWidth>1</bitWidth>
            </field>
            <field>
              <name>BR10</name>
              <bitOffset>10</bitOffset>
              <bitWidth>1</bitWidth>
            </field>
            <field>
              <name>BR11</name>
              <bitOffset>11</bitOffset>
              <bitWidth>1</bitWidth>
            </field>
            <field>
              <name>BR12</name>
              <bitOffset>12</bitOffset>
              <bitWidth>1</bitWidth>
            </field>
            <field>
              <name>BR13</name>
              <bitOffset>13</bitOffset>
              <bitWidth>1</bitWidth>
            </field>
            <field>
              <name>BR14</name>
              <bitOffset>14</bitOffset>
              <bitWidth>1</bitWidth>
            </field>
            <field>
              <name>BR15</name>
              <bitOffset>15</bitOffset>
              <bitWidth>1</bitWidth>
            </field>
          </fields>
        </register>
      </registers>
    </peripheral>
    <peripheral>
      <name>GPIOG</name>
      <baseAddress>0x48001800</baseAddress>
      <registers>
        <register>
          <name>MODER</name>
          <addressOffset>0x0</addressOffset>
          <size>0x20</size>
          <fields>
            <field>
              <name>MODE0</name>
              <bitOffset>0</bitOffset>
              <bitWidth>2</bitWidth>
            </field>
            <field>
              <name>MODE1</name>
              <bitOffset>2</bitOffset>
              <bitWidth>2</bitWidth>
            </field>
            <field>
              <name>MODE2</name>
              <bitOffset>4</bitOffset>
              <bitWidth>2</bitWidth>
            </field>
            <field>
              <name>MODE3</name>
              <bitOffset>6</bitOffset>
              <bitWidth>2</bitWidth>
            </field>
            <field>
              <name>MODE4</name>
              <bitOffset>8</bitOffset>
              <bitWidth>2</bitWidth>
            </field>
            <field>
              <name>MODE5</name>
              <bitOffset>10</bitOffset>
              <bitWidth>2</bitWidth>
            </field>
            <field>
              <name>MODE6</name>
              <bitOffset>12</bitOffset>
              <bitWidth>2</bitWidth>
            </field>
            <field>
              <name>MODE7</name>
              <bitOffset>14</bitOffset>
              <bitWidth>2</bitWidth>
            </field>
            <field>
              <name>MODE8</name>
              <bitOffset>16</bitOffset>
              <bitWidth>2</bitWidth>
            </field>
            <field>
              <name>MODE9</name>
              <bitOffset>18</bitOffset>
              <bitWidth>2</bitWidth>
            </field>
            <field>
              <name>MODE10</name>
              <bitOffset>20</bitOffset>
              <bitWidth>2</bitWidth>
            </field>
            <field>
              <name>MODE11</name>
              <bitOffset>22</bitOffset>
              <bitWidth>2</bitWidth>
            </field>
            <field>
              <name>MODE12</name>
              <bitOffset>24</bitOffset>
              <bitWidth>2</bitWidth>
            </field>
            <field>
              <name>MODE13</name>
              <bitOffset>26</bitOffset>
              <bitWidth>2</bitWidth>
            </field>
            <field>
              <name>MODE14</name>
              <bitOffset>28</bitOffset>
              <bitWidth>2</bitWidth>
            </field>
            <field>
              <name>MODE15</name>
              <bitOffset>30</bitOffset>
              <bitWidth>2</bitWidth>
            </field>
          </fields>
        </register>
        <register>
          <name>OTYPER</name>
          <addressOffset>0x4</addressOffset>
          <size>0x20</size>
          <fields>
            <field>
              <name>OT0</name>
              <bitOffset>0</bitOffset>
              <bitWidth>1</bitWidth>
            </field>
            <field>
              <name>OT1</name>
              <bitOffset>1</bitOffset>
              <bitWidth>1</bitWidth>
            </field>
            <field>
              <name>OT2</name>
              <bitOffset>2</bitOffset>
              <bitWidth>1</bitWidth>
            </field>
            <field>
              <name>OT3</name>
              <bitOffset>3</bitOffset>
              <bitWidth>1</bitWidth>
            </field>
            <field>
              <name>OT4</name>
              <bitOffset>4</bitOffset>
              <bitWidth>1</bitWidth>
            </field>
            <field>
              <name>OT5</name>
              <bitOffset>5</bitOffset>
              <bitWidth>1</bitWidth>
            </field>
            <field>
              <name>OT6</name>
              <bitOffset>6</bitOffset>
              <bitWidth>1</bitWidth>
            </field>
            <field>
              <name>OT7</name>
              <bitOffset>7</bitOffset>
              <bitWidth>1</bitWidth>
            </field>
            <field>
              <name>OT8</name>
              <bitOffset>8</bitOffset>
              <bitWidth>1</bitWidth>
            </field>
            <field>
              <name>OT9</name>
              <bitOffset>9</bitOffset>
              <bitWidth>1</bitWidth>
            </field>
            <field>
              <name>OT10</name>
              <bitOffset>10</bitOffset>
              <bitWidth>1</bitWidth>
            </field>
            <field>
              <name>OT11</name>
              <bitOffset>11</bitOffset>
              <bitWidth>1</bitWidth>
            </field>
            <field>
              <name>OT12</name>
              <bitOffset>12</bitOffset>
              <bitWidth>1</bitWidth>
            </field>
            <field>
              <name>OT13</name>
              <bitOffset>13</bitOffset>
              <bitWidth>1</bitWidth>
            </field>
            <field>
              <name>OT14</name>
              <bitOffset>14</bitOffset>
              <bitWidth>1</bitWidth>
            </field>
            <field>
              <name>OT15</name>
              <bitOffset>15</bitOffset>
              <bitWidth>1</bitWidth>
            </field>
          </fields>
        </register>
        <register>
          <name>OSPEEDR</name>
          <addressOffset>0x8</addressOffset>
          <size>0x20</size>
          <fields>
            <field>
              <name>OSPEED0</name>
              <bitOffset>0</bitOffset>
              <bitWidth>2</bitWidth>
            </field>
            <field>
              <name>OSPEED1</name>
              <bitOffset>2</bitOffset>
              <bitWidth>2</bitWidth>
            </field>
            <field>
              <name>OSPEED2</name>
              <bitOffset>4</bitOffset>
              <bitWidth>2</bitWidth>
            </field>
            <field>
              <name>OSPEED3</name>
              <bitOffset>6</bitOffset>
              <bitWidth>2</bitWidth>
            </field>
            <field>
              <name>OSPEED4</name>
              <bitOffset>8</bitOffset>
              <bitWidth>2</bitWidth>
            </field>
            <field>
              <name>OSPEED5</name>
              <bitOffset>10</bitOffset>
              <bitWidth>2</bitWidth>
            </field>
            <field>
              <name>OSPEED6</name>
              <bitOffset>12</bitOffset>
              <bitWidth>2</bitWidth>
            </field>
            <field>
              <name>OSPEED7</name>
              <bitOffset>14</bitOffset>
              <bitWidth>2</bitWidth>
            </field>
            <field>
              <name>OSPEED8</name>
              <bitOffset>16</bitOffset>
              <bitWidth>2</bitWidth>
            </field>
            <field>
              <name>OSPEED9</name>
              <bitOffset>18</bitOffset>
              <bitWidth>2</bitWidth>
            </field>
            <field>
              <name>OSPEED10</name>
              <bitOffset>20</bitOffset>
              <bitWidth>2</bitWidth>
            </field>
            <field>
              <name>OSPEED11</name>
              <bitOffset>22</bitOffset>
              <bitWidth>2</bitWidth>
            </field>
            <field>
              <name>OSPEED12</name>
              <bitOffset>24</bitOffset>
              <bitWidth>2</bitWidth>
            </field>
            <field>
              <name>OSPEED13</name>
              <bitOffset>26</bitOffset>
              <bitWidth>2</bitWidth>
            </field>
            <field>
              <name>OSPEED14</name>
              <bitOffset>28</bitOffset>
              <bitWidth>2</bitWidth>
            </field>
            <field>
              <name>OSPEED15</name>
              <bitOffset>30</bitOffset>
              <bitWidth>2</bitWidth>
            </field>
          </fields>
        </register>
        <register>
          <name>PUPDR</name>
          <addressOffset>0xc</addressOffset>
          <size>0x20</size>
          <fields>
            <field>
              <name>PUPD0</name>
              <bitOffset>0</bitOffset>
              <bitWidth>2</bitWidth>
            </field>
            <field>
              <name>PUPD1</name>
              <bitOffset>2</bitOffset>
              <bitWidth>2</bitWidth>
            </field>
            <field>
              <name>PUPD2</name>
              <bitOffset>4</bitOffset>
              <bitWidth>2</bitWidth>
            </field>
            <field>
              <name>PUPD3</name>
              <bitOffset>6</bitOffset>
              <bitWidth>2</bitWidth>
            </field>
            <field>
              <name>PUPD4</name>
              <bitOffset>8</bitOffset>
              <bitWidth>2</bitWidth>
            </field>
            <field>
              <name>PUPD5</name>
              <bitOffset>10</bitOffset>
              <bitWidth>2</bitWidth>
            </field>
            <field>
              <name>PUPD6</name>
              <bitOffset>12</bitOffset>
              <bitWidth>2</bitWidth>
            </field>
            <field>
              <name>PUPD7</name>
              <bitOffset>14</bitOffset>
              <bitWidth>2</bitWidth>
            </field>
            <field>
              <name>PUPD8</name>
              <bitOffset>16</bitOffset>
              <bitWidth>2</bitWidth>
            </field>
            <field>
              <name>PUPD9</name>
              <bitOffset>18</bitOffset>
              <bitWidth>2</bitWidth>
            </field>
            <field>
              <name>PUPD10</name>
              <bitOffset>20</bitOffset>
              <bitWidth>2</bitWidth>
            </field>
            <field>
              <name>PUPD11</name>
              <bitOffset>22</bitOffset>
              <bitWidth>2</bitWidth>
            </field>
            <field>
              <name>PUPD12</name>
              <bitOffset>24</bitOffset>
              <bitWidth>2</bitWidth>
            </field>
            <field>
              <name>PUPD13</name>
              <bitOffset>26</bitOffset>
              <bitWidth>2</bitWidth>
            </field>
            <field>
              <name>PUPD14</name>
              <bitOffset>28</bitOffset>
              <bitWidth>2</bitWidth>
            </field>
            <field>
              <name>PUPD15</name>
              <bitOffset>30</bitOffset>
              <bitWidth>2</bitWidth>
            </field>
          </fields>
        </register>
        <register>
          <name>IDR</name>
          <addressOffset>0x10</addressOffset>
          <size>0x20</size>
          <fields>
            <field>
              <name>ID0</name>
              <bitOffset>0</bitOffset>
              <bitWidth>1</bitWidth>
            </field>
            <field>
              <name>ID1</name>
              <bitOffset>1</bitOffset>
              <bitWidth>1</bitWidth>
            </field>
            <field>
              <name>ID2</name>
              <bitOffset>2</bitOffset>
              <bitWidth>1</bitWidth>
            </field>
            <field>
              <name>ID3</name>
              <bitOffset>3</bitOffset>
              <bitWidth>1</bitWidth>
            </field>
            <field>
              <name>ID4</name>
              <bitOffset>4</bitOffset>
              <bitWidth>1</bitWidth>
            </field>
            <field>
              <name>ID5</name>
              <bitOffset>5</bitOffset>
              <bitWidth>1</bitWidth>
            </field>
            <field>
              <name>ID6</name>
              <bitOffset>6</bitOffset>
              <bitWidth>1</bitWidth>
            </field>
            <field>
              <name>ID7</name>
              <bitOffset>7</bitOffset>
              <bitWidth>1</bitWidth>
            </field>
            <field>
              <name>ID8</name>
              <bitOffset>8</bitOffset>
              <bitWidth>1</bitWidth>
            </field>
            <field>
              <name>ID9</name>
              <bitOffset>9</bitOffset>
              <bitWidth>1</bitWidth>
            </field>
            <field>
              <name>ID10</name>
              <bitOffset>10</bitOffset>
              <bitWidth>1</bitWidth>
            </field>
            <field>
              <name>ID11</name>
              <bitOffset>11</bitOffset>
              <bitWidth>1</bitWidth>
            </field>
            <field>
              <name>ID12</name>
              <bitOffset>12</bitOffset>
              <bitWidth>1</bitWidth>
            </field>
            <field>
              <name>ID13</name>
              <bitOffset>13</bitOffset>
              <bitWidth>1</bitWidth>
            </field>
            <field>
              <name>ID14</name>
              <bitOffset>14</bitOffset>
              <bitWidth>1</bitWidth>
            </field>
            <field>
              <name>ID15</name>
              <bitOffset>15</bitOffset>
              <bitWidth>1</bitWidth>
            </field>
          </fields>
        </register>
        <register>
          <name>ODR</name>
          <addressOffset>0x14</addressOffset>
          <size>0x20</size>
          <fields>
            <field>
              <name>OD0</name>
              <bitOffset>0</bitOffset>
              <bitWidth>1</bitWidth>
            </field>
            <field>
              <name>OD1</name>
              <bitOffset>1</bitOffset>
              <bitWidth>1</bitWidth>
            </field>
            <field>
              <name>OD2</name>
              <bitOffset>2</bitOffset>
              <bitWidth>1</bitWidth>
            </field>
            <field>
              <name>OD3</name>
              <bitOffset>3</bitOffset>
              <bitWidth>1</bitWidth>
            </field>
            <field>
              <name>OD4</name>
              <bitOffset>4</bitOffset>
              <bitWidth>1</bitWidth>
            </field>
            <field>
              <name>OD5</name>
              <bitOffset>5</bitOffset>
              <bitWidth>1</bitWidth>
            </field>
            <field>
              <name>OD6</name>
              <bitOffset>6</bitOffset>
              <bitWidth>1</bitWidth>
            </field>
            <field>
              <name>OD7</name>
              <bitOffset>7</bitOffset>
              <bitWidth>1</bitWidth>
            </field>
            <field>
              <name>OD8</name>
              <bitOffset>8</bitOffset>
              <bitWidth>1</bitWidth>
            </field>
            <field>
              <name>OD9</name>
              <bitOffset>9</bitOffset>
              <bitWidth>1</bitWidth>
            </field>
            <field>
              <name>OD10</name>
              <bitOffset>10</bitOffset>
              <bitWidth>1</bitWidth>
            </field>
            <field>
              <name>OD11</name>
              <bitOffset>11</bitOffset>
              <bitWidth>1</bitWidth>
            </field>
            <field>
              <name>OD12</name>
              <bitOffset>12</bitOffset>
              <bitWidth>1</bitWidth>
            </field>
            <field>
              <name>OD13</name>
              <bitOffset>13</bitOffset>
              <bitWidth>1</bitWidth>
            </field>
            <field>
              <name>OD14</name>
              <bitOffset>14</bitOffset>
              <bitWidth>1</bitWidth>
            </field>
            <field>
              <name>OD15</name>
              <bitOffset>15</bitOffset>
              <bitWidth>1</bitWidth>
            </field>
          </fields>
        </register>
        <register>
          <name>BSRR</name>
          <addressOffset>0x18</addressOffset>
          <size>0x20</size>
          <fields>
            <field>
              <name>BS0</name>
              <bitOffset>0</bitOffset>
              <bitWidth>1</bitWidth>
            </field>
            <field>
              <name>BS1</name>
              <bitOffset>1</bitOffset>
              <bitWidth>1</bitWidth>
            </field>
            <field>
              <name>BS2</name>
              <bitOffset>2</bitOffset>
              <bitWidth>1</bitWidth>
            </field>
            <field>
              <name>BS3</name>
              <bitOffset>3</bitOffset>
              <bitWidth>1</bitWidth>
            </field>
            <field>
              <name>BS4</name>
              <bitOffset>4</bitOffset>
              <bitWidth>1</bitWidth>
            </field>
            <field>
              <name>BS5</name>
              <bitOffset>5</bitOffset>
              <bitWidth>1</bitWidth>
            </field>
            <field>
              <name>BS6</name>
              <bitOffset>6</bitOffset>
              <bitWidth>1</bitWidth>
            </field>
            <field>
              <name>BS7</name>
              <bitOffset>7</bitOffset>
              <bitWidth>1</bitWidth>
            </field>
            <field>
              <name>BS8</name>
              <bitOffset>8</bitOffset>
              <bitWidth>1</bitWidth>
            </field>
            <field>
              <name>BS9</name>
              <bitOffset>9</bitOffset>
              <bitWidth>1</bitWidth>
            </field>
            <field>
              <name>BS10</name>
              <bitOffset>10</bitOffset>
              <bitWidth>1</bitWidth>
            </field>
            <field>
              <name>BS11</name>
              <bitOffset>11</bitOffset>
              <bitWidth>1</bitWidth>
            </field>
            <field>
              <name>BS12</name>
              <bitOffset>12</bitOffset>
              <bitWidth>1</bitWidth>
            </field>
            <field>
              <name>BS13</name>
              <bitOffset>13</bitOffset>
              <bitWidth>1</bitWidth>
            </field>
            <field>
              <name>BS14</name>
              <bitOffset>14</bitOffset>
              <bitWidth>1</bitWidth>
            </field>
            <field>
              <name>BS15</name>
              <bitOffset>15</bitOffset>
              <bitWidth>1</bitWidth>
            </field>
            <field>
              <name>BR0</name>
              <bitOffset>16</bitOffset>
              <bitWidth>1</bitWidth>
            </field>
            <field>
              <name>BR1</name>
              <bitOffset>17</bitOffset>
              <bitWidth>1</bitWidth>
            </field>
            <field>
              <name>BR2</name>
              <bitOffset>18</bitOffset>
              <bitWidth>1</bitWidth>
            </field>
            <field>
              <name>BR3</name>
              <bitOffset>19</bitOffset>
              <bitWidth>1</bitWidth>
            </field>
            <field>
              <name>BR4</name>
              <bitOffset>20</bitOffset>
              <bitWidth>1</bitWidth>
            </field>
            <field>
              <name>BR5</name>
              <bitOffset>21</bitOffset>
              <bitWidth>1</bitWidth>
            </field>
            <field>
              <name>BR6</name>
              <bitOffset>22</bitOffset>
              <bitWidth>1</bitWidth>
            </field>
            <field>
              <name>BR7</name>
              <bitOffset>23</bitOffset>
              <bitWidth>1</bitWidth>
            </field>
            <field>
              <name>BR8</name>
              <bitOffset>24</bitOffset>
              <bitWidth>1</bitWidth>
            </field>
            <field>
              <name>BR9</name>
              <bitOffset>25</bitOffset>
              <bitWidth>1</bitWidth>
            </field>
            <field>
              <name>BR10</name>
              <bitOffset>26</bitOffset>
              <bitWidth>1</bitWidth>
            </field>
            <field>
              <name>BR11</name>
              <bitOffset>27</bitOffset>
              <bitWidth>1</bitWidth>
            </field>
            <field>
              <name>BR12</name>
              <bitOffset>28</bitOffset>
              <bitWidth>1</bitWidth>
            </field>
            <field>
              <name>BR13</name>
              <bitOffset>29</bitOffset>
              <bitWidth>1</bitWidth>
            </field>
            <field>
              <name>BR14</name>
              <bitOffset>30</bitOffset>
              <bitWidth>1</bitWidth>
            </field>
            <field>
              <name>BR15</name>
              <bitOffset>31</bitOffset>
              <bitWidth>1</bitWidth>
            </field>
          </fields>
        </register>
        <register>
          <name>LCKR</name>
          <addressOffset>0x1c</addressOffset>
          <size>0x20</size>
          <fields>
            <field>
              <name>LCK0</name>
              <bitOffset>0</bitOffset>
              <bitWidth>1</bitWidth>
            </field>
            <field>
              <name>LCK1</name>
              <bitOffset>1</bitOffset>
              <bitWidth>1</bitWidth>
            </field>
            <field>
              <name>LCK2</name>
              <bitOffset>2</bitOffset>
              <bitWidth>1</bitWidth>
            </field>
            <field>
              <name>LCK3</name>
              <bitOffset>3</bitOffset>
              <bitWidth>1</bitWidth>
            </field>
            <field>
              <name>LCK4</name>
              <bitOffset>4</bitOffset>
              <bitWidth>1</bitWidth>
            </field>
            <field>
              <name>LCK5</name>
              <bitOffset>5</bitOffset>
              <bitWidth>1</bitWidth>
            </field>
            <field>
              <name>LCK6</name>
              <bitOffset>6</bitOffset>
              <bitWidth>1</bitWidth>
            </field>
            <field>
              <name>LCK7</name>
              <bitOffset>7</bitOffset>
              <bitWidth>1</bitWidth>
            </field>
            <field>
              <name>LCK8</name>
              <bitOffset>8</bitOffset>
              <bitWidth>1</bitWidth>
            </field>
            <field>
              <name>LCK9</name>
              <bitOffset>9</bitOffset>
              <bitWidth>1</bitWidth>
            </field>
            <field>
              <name>LCK10</name>
              <bitOffset>10</bitOffset>
              <bitWidth>1</bitWidth>
            </field>
            <field>
              <name>LCK11</name>
              <bitOffset>11</bitOffset>
              <bitWidth>1</bitWidth>
            </field>
            <field>
              <name>LCK12</name>
              <bitOffset>12</bitOffset>
              <bitWidth>1</bitWidth>
            </field>
            <field>
              <name>LCK13</name>
              <bitOffset>13</bitOffset>
              <bitWidth>1</bitWidth>
            </field>
            <field>
              <name>LCK14</name>
              <bitOffset>14</bitOffset>
              <bitWidth>1</bitWidth>
            </field>
            <field>
              <name>LCK15</name>
              <bitOffset>15</bitOffset>
              <bitWidth>1</bitWidth>
            </field>
            <field>
              <name>LCKK</name>
              <bitOffset>16</bitOffset>
              <bitWidth>1</bitWidth>
            </field>
          </fields>
        </register>
        <register>
          <name>AFR.0</name>
          <addressOffset>0x20</addressOffset>
          <size>0x20</size>
          <fields>
            <field>
              <name>AFSEL0</name>
              <bitOffset>0</bitOffset>
              <bitWidth>4</bitWidth>
            </field>
            <field>
              <name>AFSEL1</name>
              <bitOffset>4</bitOffset>
              <bitWidth>4</bitWidth>
            </field>
            <field>
              <name>AFSEL2</name>
              <bitOffset>8</bitOffset>
              <bitWidth>4</bitWidth>
            </field>
            <field>
              <name>AFSEL3</name>
              <bitOffset>12</bitOffset>
              <bitWidth>4</bitWidth>
            </field>
            <field>
              <name>AFSEL4</name>
              <bitOffset>16</bitOffset>
              <bitWidth>4</bitWidth>
            </field>
            <field>
              <name>AFSEL5</name>
              <bitOffset>20</bitOffset>
              <bitWidth>4</bitWidth>
            </field>
            <field>
              <name>AFSEL6</name>
              <bitOffset>24</bitOffset>
              <bitWidth>4</bitWidth>
            </field>
            <field>
              <name>AFSEL7</name>
              <bitOffset>28</bitOffset>
              <bitWidth>4</bitWidth>
            </field>
          </fields>
        </register>
        <register>
          <name>AFR.1</name>
          <addressOffset>0x24</addressOffset>
          <size>0x20</size>
          <fields>
            <field>
              <name>AFSEL8</name>
              <bitOffset>0</bitOffset>
              <bitWidth>4</bitWidth>
            </field>
            <field>
              <name>AFSEL9</name>
              <bitOffset>4</bitOffset>
              <bitWidth>4</bitWidth>
            </field>
            <field>
              <name>AFSEL10</name>
              <bitOffset>8</bitOffset>
              <bitWidth>4</bitWidth>
            </field>
            <field>
              <name>AFSEL11</name>
              <bitOffset>12</bitOffset>
              <bitWidth>4</bitWidth>
            </field>
            <field>
              <name>AFSEL12</name>
              <bitOffset>16</bitOffset>
              <bitWidth>4</bitWidth>
            </field>
            <field>
              <name>AFSEL13</name>
              <bitOffset>20</bitOffset>
              <bitWidth>4</bitWidth>
            </field>
            <field>
              <name>AFSEL14</name>
              <bitOffset>24</bitOffset>
              <bitWidth>4</bitWidth>
            </field>
            <field>
              <name>AFSEL15</name>
              <bitOffset>28</bitOffset>
              <bitWidth>4</bitWidth>
            </field>
          </fields>
        </register>
        <register>
          <name>BRR</name>
          <addressOffset>0x28</addressOffset>
          <size>0x20</size>
          <fields>
            <field>
              <name>BR0</name>
              <bitOffset>0</bitOffset>
              <bitWidth>1</bitWidth>
            </field>
            <field>
              <name>BR1</name>
              <bitOffset>1</bitOffset>
              <bitWidth>1</bitWidth>
            </field>
            <field>
              <name>BR2</name>
              <bitOffset>2</bitOffset>
              <bitWidth>1</bitWidth>
            </field>
            <field>
              <name>BR3</name>
              <bitOffset>3</bitOffset>
              <bitWidth>1</bitWidth>
            </field>
            <field>
              <name>BR4</name>
              <bitOffset>4</bitOffset>
              <bitWidth>1</bitWidth>
            </field>
            <field>
              <name>BR5</name>
              <bitOffset>5</bitOffset>
              <bitWidth>1</bitWidth>
            </field>
            <field>
              <name>BR6</name>
              <bitOffset>6</bitOffset>
              <bitWidth>1</bitWidth>
            </field>
            <field>
              <name>BR7</name>
              <bitOffset>7</bitOffset>
              <bitWidth>1</bitWidth>
            </field>
            <field>
              <name>BR8</name>
              <bitOffset>8</bitOffset>
              <bitWidth>1</bitWidth>
            </field>
            <field>
              <name>BR9</name>
              <bitOffset>9</bitOffset>
              <bitWidth>1</bitWidth>
            </field>
            <field>
              <name>BR10</name>
              <bitOffset>10</bitOffset>
              <bitWidth>1</bitWidth>
            </field>
            <field>
              <name>BR11</name>
              <bitOffset>11</bitOffset>
              <bitWidth>1</bitWidth>
            </field>
            <field>
              <name>BR12</name>
              <bitOffset>12</bitOffset>
              <bitWidth>1</bitWidth>
            </field>
            <field>
              <name>BR13</name>
              <bitOffset>13</bitOffset>
              <bitWidth>1</bitWidth>
            </field>
            <field>
              <name>BR14</name>
              <bitOffset>14</bitOffset>
              <bitWidth>1</bitWidth>
            </field>
            <field>
              <name>BR15</name>
              <bitOffset>15</bitOffset>
              <bitWidth>1</bitWidth>
            </field>
          </fields>
        </register>
      </registers>
    </peripheral>
    <peripheral>
      <name>ADC1</name>
      <baseAddress>0x50000000</baseAddress>
      <registers>
        <register>
          <name>ISR</name>
          <addressOffset>0x0</addressOffset>
          <size>0x20</size>
          <fields>
            <field>
              <name>ADRDY</name>
              <bitOffset>0</bitOffset>
              <bitWidth>1</bitWidth>
            </field>
            <field>
              <name>EOSMP</name>
              <bitOffset>1</bitOffset>
              <bitWidth>1</bitWidth>
            </field>
            <field>
              <name>EOC</name>
              <bitOffset>2</bitOffset>
              <bitWidth>1</bitWidth>
            </field>
            <field>
              <name>EOS</name>
              <bitOffset>3</bitOffset>
              <bitWidth>1</bitWidth>
            </field>
            <field>
              <name>OVR</name>
              <bitOffset>4</bitOffset>
              <bitWidth>1</bitWidth>
            </field>
            <field>
              <name>JEOC</name>
              <bitOffset>5</bitOffset>
              <bitWidth>1</bitWidth>
            </field>
            <field>
              <name>JEOS</name>
              <bitOffset>6</bitOffset>
              <bitWidth>1</bitWidth>
            </field>
            <field>
              <name>AWD1</name>
              <bitOffset>7</bitOffset>
              <bitWidth>1</bitWidth>
            </field>
            <field>
              <name>AWD2</name>
              <bitOffset>8</bitOffset>
              <bitWidth>1</bitWidth>
            </field>
            <field>
              <name>AWD3</name>
              <bitOffset>9</bitOffset>
              <bitWidth>1</bitWidth>
            </field>
            <field>
              <name>JQOVF</name>
              <bitOffset>10</bitOffset>
              <bitWidth>1</bitWidth>
            </field>
          </fields>
        </register>
        <register>
          <name>IER</name>
          <addressOffset>0x4</addressOffset>
          <size>0x20</size>
          <fields>
            <field>
              <name>ADRDYIE</name>
              <bitOffset>0</bitOffset>
              <bitWidth>1</bitWidth>
            </field>
            <field>
              <name>EOSMPIE</name>
              <bitOffset>1</bitOffset>
              <bitWidth>1</bitWidth>
            </field>
            <field>
              <name>EOCIE</name>
              <bitOffset>2</bitOffset>
              <bitWidth>1</bitWidth>
            </field>
            <field>
              <name>EOSIE</name>
              <bitOffset>3</bitOffset>
              <bitWidth>1</bitWidth>
            </field>
            <field>
              <name>OVRIE</name>
              <bitOffset>4</bitOffset>
              <bitWidth>1</bitWidth>
            </field>
            <field>
              <name>JEOCIE</name>
              <bitOffset>5</bitOffset>
              <bitWidth>1</bitWidth>
            </field>
            <field>
              <name>JEOSIE</name>
              <bitOffset>6</bitOffset>
              <bitWidth>1</bitWidth>
            </field>
            <field>
              <name>AWD1IE</name>
              <bitOffset>7</bitOffset>
              <bitWidth>1</bitWidth>
            </field>
            <field>
              <name>AWD2IE</name>
              <bitOffset>8</bitOffset>
              <bitWidth>1</bitWidth>
            </field>
            <field>
              <name>AWD3IE</name>
              <bitOffset>9</bitOffset>
              <bitWidth>1</bitWidth>
            </field>
            <field>
              <name>JQOVFIE</name>
              <bitOffset>10</bitOffset>
              <bitWidth>1</bitWidth>
            </field>
          </fields>
        </register>
        <register>
          <name>CR</name>
          <addressOffset>0x8</addressOffset>
          <size>0x20</size>
          <fields>
            <field>
              <name>ADEN</name>
              <bitOffset>0</bitOffset>
              <bitWidth>1</bitWidth>
            </field>
            <field>
              <name>ADDIS</name>
              <bitOffset>1</bitOffset>
              <bitWidth>1</bitWidth>
            </field>
            <field>
              <name>ADSTART</name>
              <bitOffset>2</bitOffset>
              <bitWidth>1</bitWidth>
            </field>
            <field>
              <name>JADSTART</name>
              <bitOffset>3</bitOffset>
              <bitWidth>1</bitWidth>
            </field>
            <field>
              <name>ADSTP</name>
              <bitOffset>4</bitOffset>
              <bitWidth>1</bitWidth>
            </field>
            <field>
              <name>JADSTP</name>
              <bitOffset>5</bitOffset>
              <bitWidth>1</bitWidth>
            </field>
            <field>
              <name>ADVREGEN</name>
              <bitOffset>28</bitOffset>
              <bitWidth>1</bitWidth>
            </field>
            <field>
              <name>DEEPPWD</name>
              <bitOffset>29</bitOffset>
              <bitWidth>1</bitWidth>
            </field>
            <field>
              <name>ADCALDIF</name>
              <bitOffset>30</bitOffset>
              <bitWidth>1</bitWidth>
            </field>
            <field>
              <name>ADCAL</name>
              <bitOffset>31</bitOffset>
              <bitWidth>1</bitWidth>
            </field>
          </fields>
        </register>
        <register>
          <name>CFGR</name>
          <addressOffset>0xc</addressOffset>
          <size>0x20</size>
          <fields>
            <field>
              <name>DMAEN</name>
              <bitOffset>0</bitOffset>
              <bitWidth>1</bitWidth>
            </field>
            <field>
              <name>DMACFG</name>
              <bitOffset>1</bitOffset>
              <bitWidth>1</bitWidth>
            </field>
            <field>
              <name>RES</name>
              <bitOffset>3</bitOffset>
              <bitWidth>2</bitWidth>
            </field>
            <field>
              <name>EXTSEL</name>
              <bitOffset>5</bitOffset>
              <bitWidth>5</bitWidth>
            </field>
            <field>
              <name>EXTEN</name>
              <bitOffset>10</bitOffset>
              <bitWidth>2</bitWidth>
            </field>
            <field>
              <name>OVRMOD</name>
              <bitOffset>12</bitOffset>
              <bitWidth>1</bitWidth>
            </field>
            <field>
              <name>CONT</name>
              <bitOffset>13</bitOffset>
              <bitWidth>1</bitWidth>
            </field>
            <field>
              <name>AUTDLY</name>
              <bitOffset>14</bitOffset>
              <bitWidth>1</bitWidth>
            </field>
            <field>
              <name>ALIGN</name>
              <bitOffset>15</bitOffset>
              <bitWidth>1</bitWidth>
            </field>
            <field>
              <name>DISCEN</name>
              <bitOffset>16</bitOffset>
              <bitWidth>1</bitWidth>
            </field>
            <field>
              <name>DISCNUM</name>
              <bitOffset>17</bitOffset>
              <bitWidth>3</bitWidth>
            </field>
            <field>
              <name>JDISCEN</name>
              <bitOffset>20</bitOffset>
              <bitWidth>1</bitWidth>
            </field>
            <field>
              <name>JQM</name>
              <bitOffset>21</bitOffset>
              <bitWidth>1</bitWidth>
            </field>
            <field>
              <name>AWD1SGL</name>
              <bitOffset>22</bitOffset>
              <bitWidth>1</bitWidth>
            </field>
            <field>
              <name>AWD1EN</name>
              <bitOffset>23</bitOffset>
              <bitWidth>1</bitWidth>
            </field>
            <field>
              <name>JAWD1EN</name>
              <bitOffset>24</bitOffset>
              <bitWidth>1</bitWidth>
            </field>
            <field>
              <name>JAUTO</name>
              <bitOffset>25</bitOffset>
              <bitWidth>1</bitWidth>
            </field>
            <field>
              <name>AWD1CH</name>
              <bitOffset>26</bitOffset>
              <bitWidth>5</bitWidth>
            </field>
            <field>
              <name>JQDIS</name>
              <bitOffset>31</bitOffset>
              <bitWidth>1</bitWidth>
            </field>
          </fields>
        </register>
        <register>
          <name>CFGR2</name>
          <addressOffset>0x10</addressOffset>
          <size>0x20</size>
          <fields>
            <field>
              <name>ROVSE</name>
              <bitOffset>0</bitOffset>
              <bitWidth>1</bitWidth>
            </field>
            <field>
              <name>JOVSE</name>
              <bitOffset>1</bitOffset>
              <bitWidth>1</bitWidth>
            </field>
            <field>
              <name>OVSR</name>
              <bitOffset>2</bitOffset>
              <bitWidth>3</bitWidth>
            </field>
            <field>
              <name>OVSS</name>
              <bitOffset>5</bitOffset>
              <bitWidth>4</bitWidth>
            </field>
            <field>
              <name>TROVS</name>
              <bitOffset>9</bitOffset>
              <bitWidth>1</bitWidth>
            </field>
            <field>
              <name>ROVSM</name>
              <bitOffset>10</bitOffset>
              <bitWidth>1</bitWidth>
            </field>
            <field>
              <name>GCOMP</name>
              <bitOffset>16</bitOffset>
              <bitWidth>1</bitWidth>
            </field>
            <field>
              <name>SWTRIG</name>
              <bitOffset>25</bitOffset>
              <bitWidth>1</bitWidth>
            </field>
            <field>
              <name>BULB</name>
              <bitOffset>26</bitOffset>
              <bitWidth>1</bitWidth>
            </field>
            <field>
              <name>SMPTRIG</name>
              <bitOffset>27</bitOffset>
              <bitWidth>1</bitWidth>
            </field>
          </fields>
        </register>
        <register>
          <name>SMPR1</name>
          <addressOffset>0x14</addressOffset>
          <size>0x20</size>
          <fields>
            <field>
              <name>SMP0</name>
              <bitOffset>0</bitOffset>
              <bitWidth>3</bitWidth>
            </field>
            <field>
              <name>SMP1</name>
              <bitOffset>3</bitOffset>
              <bitWidth>3</bitWidth>
            </field>
            <field>
              <name>SMP2</name>
              <bitOffset>6</bitOffset>
              <bitWidth>3</bitWidth>
            </field>
            <field>
              <name>SMP3</name>
              <bitOffset>9</bitOffset>
              <bitWidth>3</bitWidth>
            </field>
            <field>
              <name>SMP4</name>
              <bitOffset>12</bitOffset>
              <bitWidth>3</bitWidth>
            </field>
            <field>
              <name>SMP5</name>
              <bitOffset>15</bitOffset>
              <bitWidth>3</bitWidth>
            </field>
            <field>
              <name>SMP6</name>
              <bitOffset>18</bitOffset>
              <bitWidth>3</bitWidth>
            </field>
            <field>
              <name>SMP7</name>
              <bitOffset>21</bitOffset>
              <bitWidth>3</bitWidth>
            </field>
            <field>
              <name>SMP8</name>
              <bitOffset>24</bitOffset>
              <bitWidth>3</bitWidth>
            </field>
            <field>
              <name>SMP9</name>
              <bitOffset>27</bitOffset>
              <bitWidth>3</bitWidth>
            </field>
            <field>
              <name>SMPPLUS</name>
              <bitOffset>31</bitOffset>
              <bitWidth>1</bitWidth>
            </field>
          </fields>
        </register>
        <register>
          <name>SMPR2</name>
          <addressOffset>0x18</addressOffset>
          <size>0x20</size>
          <fields>
            <field>
              <name>SMP10</name>
              <bitOffset>0</bitOffset>
              <bitWidth>3</bitWidth>
            </field>
            <field>
              <name>SMP11</name>
              <bitOffset>3</bitOffset>
              <bitWidth>3</bitWidth>
            </field>
            <field>
              <name>SMP12</name>
              <bitOffset>6</bitOffset>
              <bitWidth>3</bitWidth>
            </field>
            <field>
              <name>SMP13</name>
              <bitOffset>9</bitOffset>
              <bitWidth>3</bitWidth>
            </field>
            <field>
              <name>SMP14</name>
              <bitOffset>12</bitOffset>
              <bitWidth>3</bitWidth>
            </field>
            <field>
              <name>SMP15</name>
              <bitOffset>15</bitOffset>
              <bitWidth>3</bitWidth>
            </field>
            <field>
              <name>SMP16</name>
              <bitOffset>18</bitOffset>
              <bitWidth>3</bitWidth>
            </field>
            <field>
              <name>SMP17</name>
              <bitOffset>21</bitOffset>
              <bitWidth>3</bitWidth>
            </field>
            <field>
              <name>SMP18</name>
              <bitOffset>24</bitOffset>
              <bitWidth>3</bitWidth>
            </field>
          </fields>
        </register>
        <register>
          <name>TR1</name>
          <addressOffset>0x20</addressOffset>
          <size>0x20</size>
          <fields>
            <field>
              <name>LT1</name>
              <bitOffset>0</bitOffset>
              <bitWidth>12</bitWidth>
            </field>
            <field>
              <name>AWDFILT</name>
              <bitOffset>12</bitOffset>
              <bitWidth>3</bitWidth>
            </field>
            <field>
              <name>HT1</name>
              <bitOffset>16</bitOffset>
              <bitWidth>12</bitWidth>
            </field>
          </fields>
        </register>
        <register>
          <name>TR2</name>
          <addressOffset>0x24</addressOffset>
          <size>0x20</size>
          <fields>
            <field>
              <name>LT2</name>
              <bitOffset>0</bitOffset>
              <bitWidth>8</bitWidth>
            </field>
            <field>
              <name>HT2</name>
              <bitOffset>16</bitOffset>
              <bitWidth>8</bitWidth>
            </field>
          </fields>
        </register>
        <register>
          <name>TR3</name>
          <addressOffset>0x28</addressOffset>
          <size>0x20</size>
          <fields>
            <field>
              <name>LT3</name>
              <bitOffset>0</bitOffset>
              <bitWidth>8</bitWidth>
            </field>
            <field>
              <name>HT3</name>
              <bitOffset>16</bitOffset>
              <bitWidth>8</bitWidth>
            </field>
          </fields>
        </register>
        <register>
          <name>SQR1</name>
          <addressOffset>0x30</addressOffset>
          <size>0x20</size>
          <fields>
            <field>
              <name>L</name>
              <bitOffset>0</bitOffset>
              <bitWidth>4</bitWidth>
            </field>
            <field>
              <name>SQ1</name>
              <bitOffset>6</bitOffset>
              <bitWidth>5</bitWidth>
            </field>
            <field>
              <name>SQ2</name>
              <bitOffset>12</bitOffset>
              <bitWidth>5</bitWidth>
            </field>
            <field>
              <name>SQ3</name>
              <bitOffset>18</bitOffset>
              <bitWidth>5</bitWidth>
            </field>
            <field>
              <name>SQ4</name>
              <bitOffset>24</bitOffset>
              <bitWidth>5</bitWidth>
            </field>
          </fields>
        </register>
        <register>
          <name>SQR2</name>
          <addressOffset>0x34</addressOffset>
          <size>0x20</size>
          <fields>
            <field>
              <name>SQ5</name>
              <bitOffset>0</bitOffset>
              <bitWidth>5</bitWidth>
            </field>
            <field>
              <name>SQ6</name>
              <bitOffset>6</bitOffset>
              <bitWidth>5</bitWidth>
            </field>
            <field>
              <name>SQ7</name>
              <bitOffset>12</bitOffset>
              <bitWidth>5</bitWidth>
            </field>
            <field>
              <name>SQ8</name>
              <bitOffset>18</bitOffset>
              <bitWidth>5</bitWidth>
            </field>
            <field>
              <name>SQ9</name>
              <bitOffset>24</bitOffset>
              <bitWidth>5</bitWidth>
            </field>
          </fields>
        </register>
        <register>
          <name>SQR3</name>
          <addressOffset>0x38</addressOffset>
          <size>0x20</size>
          <fields>
            <field>
              <name>SQ10</name>
              <bitOffset>0</bitOffset>
              <bitWidth>5</bitWidth>
            </field>
            <field>
              <name>SQ11</name>
              <bitOffset>6</bitOffset>
              <bitWidth>5</bitWidth>
            </field>
            <field>
              <name>SQ12</name>
              <bitOffset>12</bitOffset>
              <bitWidth>5</bitWidth>
            </field>
            <field>
              <name>SQ13</name>
              <bitOffset>18</bitOffset>
              <bitWidth>5</bitWidth>
            </field>
            <field>
              <name>SQ14</name>
              <bitOffset>24</bitOffset>
              <bitWidth>5</bitWidth>
            </field>
          </fields>
        </register>
        <register>
          <name>SQR4</name>
          <addressOffset>0x3c</addressOffset>
          <size>0x20</size>
          <fields>
            <field>
              <name>SQ15</name>
              <bitOffset>0</bitOffset>
              <bitWidth>5</bitWidth>
            </field>
            <field>
              <name>SQ16</name>
              <bitOffset>6</bitOffset>
              <bitWidth>5</bitWidth>
            </field>
          </fields>
        </register>
        <register>
          <name>DR</name>
          <addressOffset>0x40</addressOffset>
          <size>0x20</size>
          <fields>
            <field>
              <name>RDATA</name>
              <bitOffset>0</bitOffset>
              <bitWidth>16</bitWidth>
            </field>
          </fields>
        </register>
        <register>
          <name>JSQR</name>
          <addressOffset>0x4c</addressOffset>
          <size>0x20</size>
          <fields>
            <field>
              <name>JL</name>
              <bitOffset>0</bitOffset>
              <bitWidth>2</bitWidth>
            </field>
            <field>
              <name>JEXTSEL</name>
              <bitOffset>2</bitOffset>
              <bitWidth>5</bitWidth>
            </field>
            <field>
              <name>JEXTEN</name>
              <bitOffset>7</bitOffset>
              <bitWidth>2</bitWidth>
            </field>
            <field>
              <name>JSQ1</name>
              <bitOffset>9</bitOffset>
              <bitWidth>5</bitWidth>
            </field>
            <field>
              <name>JSQ2</name>
              <bitOffset>15</bitOffset>
              <bitWidth>5</bitWidth>
            </field>
            <field>
              <name>JSQ3</name>
              <bitOffset>21</bitOffset>
              <bitWidth>5</bitWidth>
            </field>
            <field>
              <name>JSQ4</name>
              <bitOffset>27</bitOffset>
              <bitWidth>5</bitWidth>
            </field>
          </fields>
        </register>
        <register>
          <name>OFR1</name>
          <addressOffset>0x60</addressOffset>
          <size>0x20</size>
          <fields>
            <field>
              <name>OFFSET1</name>
              <bitOffset>0</bitOffset>
              <bitWidth>12</bitWidth>
            </field>
            <field>
              <name>OFFSETPOS</name>
              <bitOffset>24</bitOffset>
              <bitWidth>1</bitWidth>
            </field>
            <field>
              <name>SATEN</name>
              <bitOffset>25</bitOffset>
              <bitWidth>1</bitWidth>
            </field>
            <field>
              <name>OFFSET1_CH</name>
              <bitOffset>26</bitOffset>
              <bitWidth>5</bitWidth>
            </field>
            <field>
              <name>OFFSET1_EN</name>
              <bitOffset>31</bitOffset>
              <bitWidth>1</bitWidth>
            </field>
          </fields>
        </register>
        <register>
          <name>OFR2</name>
          <addressOffset>0x64</addressOffset>
          <size>0x20</size>
          <fields>
            <field>
              <name>OFFSET2</name>
              <bitOffset>0</bitOffset>
              <bitWidth>12</bitWidth>
            </field>
            <field>
              <name>OFFSETPOS</name>
              <bitOffset>24</bitOffset>
              <bitWidth>1</bitWidth>
            </field>
            <field>
              <name>SATEN</name>
              <bitOffset>25</bitOffset>
              <bitWidth>1</bitWidth>
            </field>
            <field>
              <name>OFFSET2_CH</name>
              <bitOffset>26</bitOffset>
              <bitWidth>5</bitWidth>
            </field>
            <field>
              <name>OFFSET2_EN</name>
              <bitOffset>31</bitOffset>
              <bitWidth>1</bitWidth>
            </field>
          </fields>
        </register>
        <register>
          <name>OFR3</name>
          <addressOffset>0x68</addressOffset>
          <size>0x20</size>
          <fields>
            <field>
              <name>OFFSET3</name>
              <bitOffset>0</bitOffset>
              <bitWidth>12</bitWidth>
            </field>
            <field>
              <name>OFFSETPOS</name>
              <bitOffset>24</bitOffset>
              <bitWidth>1</bitWidth>
            </field>
            <field>
              <name>SATEN</name>
              <bitOffset>25</bitOffset>
              <bitWidth>1</bitWidth>
            </field>
            <field>
              <name>OFFSET3_CH</name>
              <bitOffset>26</bitOffset>
              <bitWidth>5</bitWidth>
            </field>
            <field>
              <name>OFFSET3_EN</name>
              <bitOffset>31</bitOffset>
              <bitWidth>1</bitWidth>
            </field>
          </fields>
        </register>
        <register>
          <name>OFR4</name>
          <addressOffset>0x6c</addressOffset>
          <size>0x20</size>
          <fields>
            <field>
              <name>OFFSET4</name>
              <bitOffset>0</bitOffset>
              <bitWidth>12</bitWidth>
            </field>
            <field>
              <name>OFFSETPOS</name>
              <bitOffset>24</bitOffset>
              <bitWidth>1</bitWidth>
            </field>
            <field>
              <name>SATEN</name>
              <bitOffset>25</bitOffset>
              <bitWidth>1</bitWidth>
            </field>
            <field>
              <name>OFFSET4_CH</name>
              <bitOffset>26</bitOffset>
              <bitWidth>5</bitWidth>
            </field>
            <field>
              <name>OFFSET4_EN</name>
              <bitOffset>31</bitOffset>
              <bitWidth>1</bitWidth>
            </field>
          </fields>
        </register>
        <register>
          <name>JDR1</name>
          <addressOffset>0x80</addressOffset>
          <size>0x20</size>
          <fields>
            <field>
              <name>JDATA</name>
              <bitOffset>0</bitOffset>
              <bitWidth>16</bitWidth>
            </field>
          </fields>
        </register>
        <register>
          <name>JDR2</name>
          <addressOffset>0x84</addressOffset>
          <size>0x20</size>
          <fields>
            <field>
              <name>JDATA</name>
              <bitOffset>0</bitOffset>
              <bitWidth>16</bitWidth>
            </field>
          </fields>
        </register>
        <register>
          <name>JDR3</name>
          <addressOffset>0x88</addressOffset>
          <size>0x20</size>
          <fields>
            <field>
              <name>JDATA</name>
              <bitOffset>0</bitOffset>
              <bitWidth>16</bitWidth>
            </field>
          </fields>
        </register>
        <register>
          <name>JDR4</name>
          <addressOffset>0x8c</addressOffset>
          <size>0x20</size>
          <fields>
            <field>
              <name>JDATA</name>
              <bitOffset>0</bitOffset>
              <bitWidth>16</bitWidth>
            </field>
          </fields>
        </register>
        <register>
          <name>AWD2CR</name>
          <addressOffset>0xa0</addressOffset>
          <size>0x20</size>
          <fields>
            <field>
              <name>AWD2CH</name>
              <bitOffset>0</bitOffset>
              <bitWidth>19</bitWidth>
            </field>
          </fields>
        </register>
        <register>
          <name>AWD3CR</name>
          <addressOffset>0xa4</addressOffset>
          <size>0x20</size>
          <fields>
            <field>
              <name>AWD3CH</name>
              <bitOffset>0</bitOffset>
              <bitWidth>19</bitWidth>
            </field>
          </fields>
        </register>
        <register>
          <name>DIFSEL</name>
          <addressOffset>0xb0</addressOffset>
          <size>0x20</size>
          <fields>
            <field>
              <name>DIFSEL</name>
              <bitOffset>0</bitOffset>
              <bitWidth>19</bitWidth>
            </field>
          </fields>
        </register>
        <register>
          <name>CALFACT</name>
          <addressOffset>0xb4</addressOffset>
          <size>0x20</size>
          <fields>
            <field>
              <name>CALFACT_S</name>
              <bitOffset>0</bitOffset>
              <bitWidth>7</bitWidth>
            </field>
            <field>
              <name>CALFACT_D</name>
              <bitOffset>16</bitOffset>
              <bitWidth>7</bitWidth>
            </field>
          </fields>
        </register>
        <register>
          <name>GCOMP</name>
          <addressOffset>0xc0</addressOffset>
          <size>0x20</size>
          <fields>
            <field>
              <name>GCOMPCOEFF</name>
              <bitOffset>0</bitOffset>
              <bitWidth>14</bitWidth>
            </field>
          </fields>
        </register>
      </registers>
    </peripheral>
    <peripheral>
      <name>ADC2</name>
      <baseAddress>0x50000100</baseAddress>
      <registers>
        <register>
          <name>ISR</name>
          <addressOffset>0x0</addressOffset>
          <size>0x20</size>
          <fields>
            <field>
              <name>ADRDY</name>
              <bitOffset>0</bitOffset>
              <bitWidth>1</bitWidth>
            </field>
            <field>
              <name>EOSMP</name>
              <bitOffset>1</bitOffset>
              <bitWidth>1</bitWidth>
            </field>
            <field>
              <name>EOC</name>
              <bitOffset>2</bitOffset>
              <bitWidth>1</bitWidth>
            </field>
            <field>
              <name>EOS</name>
              <bitOffset>3</bitOffset>
              <bitWidth>1</bitWidth>
            </field>
            <field>
              <name>OVR</name>
              <bitOffset>4</bitOffset>
              <bitWidth>1</bitWidth>
            </field>
            <field>
              <name>JEOC</name>
              <bitOffset>5</bitOffset>
              <bitWidth>1</bitWidth>
            </field>
            <field>
              <name>JEOS</name>
              <bitOffset>6</bitOffset>
              <bitWidth>1</bitWidth>
            </field>
            <field>
              <name>AWD1</name>
              <bitOffset>7</bitOffset>
              <bitWidth>1</bitWidth>
            </field>
            <field>
              <name>AWD2</name>
              <bitOffset>8</bitOffset>
              <bitWidth>1</bitWidth>
            </field>
            <field>
              <name>AWD3</name>
              <bitOffset>9</bitOffset>
              <bitWidth>1</bitWidth>
            </field>
            <field>
              <name>JQOVF</name>
              <bitOffset>10</bitOffset>
              <bitWidth>1</bitWidth>
            </field>
          </fields>
        </register>
        <register>
          <name>IER</name>
          <addressOffset>0x4</addressOffset>
          <size>0x20</size>
          <fields>
            <field>
              <name>ADRDYIE</name>
              <bitOffset>0</bitOffset>
              <bitWidth>1</bitWidth>
            </field>
            <field>
              <name>EOSMPIE</name>
              <bitOffset>1</bitOffset>
              <bitWidth>1</bitWidth>
            </field>
            <field>
              <name>EOCIE</name>
              <bitOffset>2</bitOffset>
              <bitWidth>1</bitWidth>
            </field>
            <field>
              <name>EOSIE</name>
              <bitOffset>3</bitOffset>
              <bitWidth>1</bitWidth>
            </field>
            <field>
              <name>OVRIE</name>
              <bitOffset>4</bitOffset>
              <bitWidth>1</bitWidth>
            </field>
            <field>
              <name>JEOCIE</name>
              <bitOffset>5</bitOffset>
              <bitWidth>1</bitWidth>
            </field>
            <field>
              <name>JEOSIE</name>
              <bitOffset>6</bitOffset>
              <bitWidth>1</bitWidth>
            </field>
            <field>
              <name>AWD1IE</name>
              <bitOffset>7</bitOffset>
              <bitWidth>1</bitWidth>
            </field>
            <field>
              <name>AWD2IE</name>
              <bitOffset>8</bitOffset>
              <bitWidth>1</bitWidth>
            </field>
            <field>
              <name>AWD3IE</name>
              <bitOffset>9</bitOffset>
              <bitWidth>1</bitWidth>
            </field>
            <field>
              <name>JQOVFIE</name>
              <bitOffset>10</bitOffset>
              <bitWidth>1</bitWidth>
            </field>
          </fields>
        </register>
        <register>
          <name>CR</name>
          <addressOffset>0x8</addressOffset>
          <size>0x20</size>
          <fields>
            <field>
              <name>ADEN</name>
              <bitOffset>0</bitOffset>
              <bitWidth>1</bitWidth>
            </field>
            <field>
              <name>ADDIS</name>
              <bitOffset>1</bitOffset>
              <bitWidth>1</bitWidth>
            </field>
            <field>
              <name>ADSTART</name>
              <bitOffset>2</bitOffset>
              <bitWidth>1</bitWidth>
            </field>
            <field>
              <name>JADSTART</name>
              <bitOffset>3</bitOffset>
              <bitWidth>1</bitWidth>
            </field>
            <field>
              <name>ADSTP</name>
              <bitOffset>4</bitOffset>
              <bitWidth>1</bitWidth>
            </field>
            <field>
              <name>JADSTP</name>
              <bitOffset>5</bitOffset>
              <bitWidth>1</bitWidth>
            </field>
            <field>
              <name>ADVREGEN</name>
              <bitOffset>28</bitOffset>
              <bitWidth>1</bitWidth>
            </field>
            <field>
              <name>DEEPPWD</name>
              <bitOffset>29</bitOffset>
              <bitWidth>1</bitWidth>
            </field>
            <field>
              <name>ADCALDIF</name>
              <bitOffset>30</bitOffset>
              <bitWidth>1</bitWidth>
            </field>
            <field>
              <name>ADCAL</name>
              <bitOffset>31</bitOffset>
              <bitWidth>1</bitWidth>
            </field>
          </fields>
        </register>
        <register>
          <name>CFGR</name>
          <addressOffset>0xc</addressOffset>
          <size>0x20</size>
          <fields>
            <field>
              <name>DMAEN</name>
              <bitOffset>0</bitOffset>
              <bitWidth>1</bitWidth>
            </field>
            <field>
              <name>DMACFG</name>
              <bitOffset>1</bitOffset>
              <bitWidth>1</bitWidth>
            </field>
            <field>
              <name>RES</name>
              <bitOffset>3</bitOffset>
              <bitWidth>2</bitWidth>
            </field>
            <field>
              <name>EXTSEL</name>
              <bitOffset>5</bitOffset>
              <bitWidth>5</bitWidth>
            </field>
            <field>
              <name>EXTEN</name>
              <bitOffset>10</bitOffset>
              <bitWidth>2</bitWidth>
            </field>
            <field>
              <name>OVRMOD</name>
              <bitOffset>12</bitOffset>
              <bitWidth>1</bitWidth>
            </field>
            <field>
              <name>CONT</name>
              <bitOffset>13</bitOffset>
              <bitWidth>1</bitWidth>
            </field>
            <field>
              <name>AUTDLY</name>
              <bitOffset>14</bitOffset>
              <bitWidth>1</bitWidth>
            </field>
            <field>
              <name>ALIGN</name>
              <bitOffset>15</bitOffset>
              <bitWidth>1</bitWidth>
            </field>
            <field>
              <name>DISCEN</name>
              <bitOffset>16</bitOffset>
              <bitWidth>1</bitWidth>
            </field>
            <field>
              <name>DISCNUM</name>
              <bitOffset>17</bitOffset>
              <bitWidth>3</bitWidth>
            </field>
            <field>
              <name>JDISCEN</name>
              <bitOffset>20</bitOffset>
              <bitWidth>1</bitWidth>
            </field>
            <field>
              <name>JQM</name>
              <bitOffset>21</bitOffset>
              <bitWidth>1</bitWidth>
            </field>
            <field>
              <name>AWD1SGL</name>
              <bitOffset>22</bitOffset>
              <bitWidth>1</bitWidth>
            </field>
            <field>
              <name>AWD1EN</name>
              <bitOffset>23</bitOffset>
              <bitWidth>1</bitWidth>
            </field>
            <field>
              <name>JAWD1EN</name>
              <bitOffset>24</bitOffset>
              <bitWidth>1</bitWidth>
            </field>
            <field>
              <name>JAUTO</name>
              <bitOffset>25</bitOffset>
              <bitWidth>1</bitWidth>
            </field>
            <field>
              <name>AWD1CH</name>
              <bitOffset>26</bitOffset>
              <bitWidth>5</bitWidth>
            </field>
            <field>
              <name>JQDIS</name>
              <bitOffset>31</bitOffset>
              <bitWidth>1</bitWidth>
            </field>
          </fields>
        </register>
        <register>
          <name>CFGR2</name>
          <addressOffset>0x10</addressOffset>
          <size>0x20</size>
          <fields>
            <field>
              <name>ROVSE</name>
              <bitOffset>0</bitOffset>
              <bitWidth>1</bitWidth>
            </field>
            <field>
              <name>JOVSE</name>
              <bitOffset>1</bitOffset>
              <bitWidth>1</bitWidth>
            </field>
            <field>
              <name>OVSR</name>
              <bitOffset>2</bitOffset>
              <bitWidth>3</bitWidth>
            </field>
            <field>
              <name>OVSS</name>
              <bitOffset>5</bitOffset>
              <bitWidth>4</bitWidth>
            </field>
            <field>
              <name>TROVS</name>
              <bitOffset>9</bitOffset>
              <bitWidth>1</bitWidth>
            </field>
            <field>
              <name>ROVSM</name>
              <bitOffset>10</bitOffset>
              <bitWidth>1</bitWidth>
            </field>
            <field>
              <name>GCOMP</name>
              <bitOffset>16</bitOffset>
              <bitWidth>1</bitWidth>
            </field>
            <field>
              <name>SWTRIG</name>
              <bitOffset>25</bitOffset>
              <bitWidth>1</bitWidth>
            </field>
            <field>
              <name>BULB</name>
              <bitOffset>26</bitOffset>
              <bitWidth>1</bitWidth>
            </field>
            <field>
              <name>SMPTRIG</name>
              <bitOffset>27</bitOffset>
              <bitWidth>1</bitWidth>
            </field>
          </fields>
        </register>
        <register>
          <name>SMPR1</name>
          <addressOffset>0x14</addressOffset>
          <size>0x20</size>
          <fields>
            <field>
              <name>SMP0</name>
              <bitOffset>0</bitOffset>
              <bitWidth>3</bitWidth>
            </field>
            <field>
              <name>SMP1</name>
              <bitOffset>3</bitOffset>
              <bitWidth>3</bitWidth>
            </field>
            <field>
              <name>SMP2</name>
              <bitOffset>6</bitOffset>
              <bitWidth>3</bitWidth>
            </field>
            <field>
              <name>SMP3</name>
              <bitOffset>9</bitOffset>
              <bitWidth>3</bitWidth>
            </field>
            <field>
              <name>SMP4</name>
              <bitOffset>12</bitOffset>
              <bitWidth>3</bitWidth>
            </field>
            <field>
              <name>SMP5</name>
              <bitOffset>15</bitOffset>
              <bitWidth>3</bitWidth>
            </field>
            <field>
              <name>SMP6</name>
              <bitOffset>18</bitOffset>
              <bitWidth>3</bitWidth>
            </field>
            <field>
              <name>SMP7</name>
              <bitOffset>21</bitOffset>
              <bitWidth>3</bitWidth>
            </field>
            <field>
              <name>SMP8</name>
              <bitOffset>24</bitOffset>
              <bitWidth>3</bitWidth>
            </field>
            <field>
              <name>SMP9</name>
              <bitOffset>27</bitOffset>
              <bitWidth>3</bitWidth>
            </field>
            <field>
              <name>SMPPLUS</name>
              <bitOffset>31</bitOffset>
              <bitWidth>1</bitWidth>
            </field>
          </fields>
        </register>
        <register>
          <name>SMPR2</name>
          <addressOffset>0x18</addressOffset>
          <size>0x20</size>
          <fields>
            <field>
              <name>SMP10</name>
              <bitOffset>0</bitOffset>
              <bitWidth>3</bitWidth>
            </field>
            <field>
              <name>SMP11</name>
              <bitOffset>3</bitOffset>
              <bitWidth>3</bitWidth>
            </field>
            <field>
              <name>SMP12</name>
              <bitOffset>6</bitOffset>
              <bitWidth>3</bitWidth>
            </field>
            <field>
              <name>SMP13</name>
              <bitOffset>9</bitOffset>
              <bitWidth>3</bitWidth>
            </field>
            <field>
              <name>SMP14</name>
              <bitOffset>12</bitOffset>
              <bitWidth>3</bitWidth>
            </field>
            <field>
              <name>SMP15</name>
              <bitOffset>15</bitOffset>
              <bitWidth>3</bitWidth>
            </field>
            <field>
              <name>SMP16</name>
              <bitOffset>18</bitOffset>
              <bitWidth>3</bitWidth>
            </field>
            <field>
              <name>SMP17</name>
              <bitOffset>21</bitOffset>
              <bitWidth>3</bitWidth>
            </field>
            <field>
              <name>SMP18</name>
              <bitOffset>24</bitOffset>
              <bitWidth>3</bitWidth>
            </field>
          </fields>
        </register>
        <register>
          <name>TR1</name>
          <addressOffset>0x20</addressOffset>
          <size>0x20</size>
          <fields>
            <field>
              <name>LT1</name>
              <bitOffset>0</bitOffset>
              <bitWidth>12</bitWidth>
            </field>
            <field>
              <name>AWDFILT</name>
              <bitOffset>12</bitOffset>
              <bitWidth>3</bitWidth>
            </field>
            <field>
              <name>HT1</name>
              <bitOffset>16</bitOffset>
              <bitWidth>12</bitWidth>
            </field>
          </fields>
        </register>
        <register>
          <name>TR2</name>
          <addressOffset>0x24</addressOffset>
          <size>0x20</size>
          <fields>
            <field>
              <name>LT2</name>
              <bitOffset>0</bitOffset>
              <bitWidth>8</bitWidth>
            </field>
            <field>
              <name>HT2</name>
              <bitOffset>16</bitOffset>
              <bitWidth>8</bitWidth>
            </field>
          </fields>
        </register>
        <register>
          <name>TR3</name>
          <addressOffset>0x28</addressOffset>
          <size>0x20</size>
          <fields>
            <field>
              <name>LT3</name>
              <bitOffset>0</bitOffset>
              <bitWidth>8</bitWidth>
            </field>
            <field>
              <name>HT3</name>
              <bitOffset>16</bitOffset>
              <bitWidth>8</bitWidth>
            </field>
          </fields>
        </register>
        <register>
          <name>SQR1</name>
          <addressOffset>0x30</addressOffset>
          <size>0x20</size>
          <fields>
            <field>
              <name>L</name>
              <bitOffset>0</bitOffset>
              <bitWidth>4</bitWidth>
            </field>
            <field>
              <name>SQ1</name>
              <bitOffset>6</bitOffset>
              <bitWidth>5</bitWidth>
            </field>
            <field>
              <name>SQ2</name>
              <bitOffset>12</bitOffset>
              <bitWidth>5</bitWidth>
            </field>
            <field>
              <name>SQ3</name>
              <bitOffset>18</bitOffset>
              <bitWidth>5</bitWidth>
            </field>
            <field>
              <name>SQ4</name>
              <bitOffset>24</bitOffset>
              <bitWidth>5</bitWidth>
            </field>
          </fields>
        </register>
        <register>
          <name>SQR2</name>
          <addressOffset>0x34</addressOffset>
          <size>0x20</size>
          <fields>
            <field>
              <name>SQ5</name>
              <bitOffset>0</bitOffset>
              <bitWidth>5</bitWidth>
            </field>
            <field>
              <name>SQ6</name>
              <bitOffset>6</bitOffset>
              <bitWidth>5</bitWidth>
            </field>
            <field>
              <name>SQ7</name>
              <bitOffset>12</bitOffset>
              <bitWidth>5</bitWidth>
            </field>
            <field>
              <name>SQ8</name>
              <bitOffset>18</bitOffset>
              <bitWidth>5</bitWidth>
            </field>
            <field>
              <name>SQ9</name>
              <bitOffset>24</bitOffset>
              <bitWidth>5</bitWidth>
            </field>
          </fields>
        </register>
        <register>
          <name>SQR3</name>
          <addressOffset>0x38</addressOffset>
          <size>0x20</size>
          <fields>
            <field>
              <name>SQ10</name>
              <bitOffset>0</bitOffset>
              <bitWidth>5</bitWidth>
            </field>
            <field>
              <name>SQ11</name>
              <bitOffset>6</bitOffset>
              <bitWidth>5</bitWidth>
            </field>
            <field>
              <name>SQ12</name>
              <bitOffset>12</bitOffset>
              <bitWidth>5</bitWidth>
            </field>
            <field>
              <name>SQ13</name>
              <bitOffset>18</bitOffset>
              <bitWidth>5</bitWidth>
            </field>
            <field>
              <name>SQ14</name>
              <bitOffset>24</bitOffset>
              <bitWidth>5</bitWidth>
            </field>
          </fields>
        </register>
        <register>
          <name>SQR4</name>
          <addressOffset>0x3c</addressOffset>
          <size>0x20</size>
          <fields>
            <field>
              <name>SQ15</name>
              <bitOffset>0</bitOffset>
              <bitWidth>5</bitWidth>
            </field>
            <field>
              <name>SQ16</name>
              <bitOffset>6</bitOffset>
              <bitWidth>5</bitWidth>
            </field>
          </fields>
        </register>
        <register>
          <name>DR</name>
          <addressOffset>0x40</addressOffset>
          <size>0x20</size>
          <fields>
            <field>
              <name>RDATA</name>
              <bitOffset>0</bitOffset>
              <bitWidth>16</bitWidth>
            </field>
          </fields>
        </register>
        <register>
          <name>JSQR</name>
          <addressOffset>0x4c</addressOffset>
          <size>0x20</size>
          <fields>
            <field>
              <name>JL</name>
              <bitOffset>0</bitOffset>
              <bitWidth>2</bitWidth>
            </field>
            <field>
              <name>JEXTSEL</name>
              <bitOffset>2</bitOffset>
              <bitWidth>5</bitWidth>
            </field>
            <field>
              <name>JEXTEN</name>
              <bitOffset>7</bitOffset>
              <bitWidth>2</bitWidth>
            </field>
            <field>
              <name>JSQ1</name>
              <bitOffset>9</bitOffset>
              <bitWidth>5</bitWidth>
            </field>
            <field>
              <name>JSQ2</name>
              <bitOffset>15</bitOffset>
              <bitWidth>5</bitWidth>
            </field>
            <field>
              <name>JSQ3</name>
              <bitOffset>21</bitOffset>
              <bitWidth>5</bitWidth>
            </field>
            <field>
              <name>JSQ4</name>
              <bitOffset>27</bitOffset>
              <bitWidth>5</bitWidth>
            </field>
          </fields>
        </register>
        <register>
          <name>OFR1</name>
          <addressOffset>0x60</addressOffset>
          <size>0x20</size>
          <fields>
            <field>
              <name>OFFSET1</name>
              <bitOffset>0</bitOffset>
              <bitWidth>12</bitWidth>
            </field>
            <field>
              <name>OFFSETPOS</name>
              <bitOffset>24</bitOffset>
              <bitWidth>1</bitWidth>
            </field>
            <field>
              <name>SATEN</name>
              <bitOffset>25</bitOffset>
              <bitWidth>1</bitWidth>
            </field>
            <field>
              <name>OFFSET1_CH</name>
              <bitOffset>26</bitOffset>
              <bitWidth>5</bitWidth>
            </field>
            <field>
              <name>OFFSET1_EN</name>
              <bitOffset>31</bitOffset>
              <bitWidth>1</bitWidth>
            </field>
          </fields>
        </register>
        <register>
          <name>OFR2</name>
          <addressOffset>0x64</addressOffset>
          <size>0x20</size>
          <fields>
            <field>
              <name>OFFSET2</name>
              <bitOffset>0</bitOffset>
              <bitWidth>12</bitWidth>
            </field>
            <field>
              <name>OFFSETPOS</name>
              <bitOffset>24</bitOffset>
              <bitWidth>1</bitWidth>
            </field>
            <field>
              <name>SATEN</name>
              <bitOffset>25</bitOffset>
              <bitWidth>1</bitWidth>
            </field>
            <field>
              <name>OFFSET2_CH</name>
              <bitOffset>26</bitOffset>
              <bitWidth>5</bitWidth>
            </field>
            <field>
              <name>OFFSET2_EN</name>
              <bitOffset>31</bitOffset>
              <bitWidth>1</bitWidth>
            </field>
          </fields>
        </register>
        <register>
          <name>OFR3</name>
          <addressOffset>0x68</addressOffset>
          <size>0x20</size>
          <fields>
            <field>
              <name>OFFSET3</name>
              <bitOffset>0</bitOffset>
              <bitWidth>12</bitWidth>
            </field>
            <field>
              <name>OFFSETPOS</name>
              <bitOffset>24</bitOffset>
              <bitWidth>1</bitWidth>
            </field>
            <field>
              <name>SATEN</name>
              <bitOffset>25</bitOffset>
              <bitWidth>1</bitWidth>
            </field>
            <field>
              <name>OFFSET3_CH</name>
              <bitOffset>26</bitOffset>
              <bitWidth>5</bitWidth>
            </field>
            <field>
              <name>OFFSET3_EN</name>
              <bitOffset>31</bitOffset>
              <bitWidth>1</bitWidth>
            </field>
          </fields>
        </register>
        <register>
          <name>OFR4</name>
          <addressOffset>0x6c</addressOffset>
          <size>0x20</size>
          <fields>
            <field>
              <name>OFFSET4</name>
              <bitOffset>0</bitOffset>
              <bitWidth>12</bitWidth>
            </field>
            <field>
              <name>OFFSETPOS</name>
              <bitOffset>24</bitOffset>
              <bitWidth>1</bitWidth>
            </field>
            <field>
              <name>SATEN</name>
              <bitOffset>25</bitOffset>
              <bitWidth>1</bitWidth>
            </field>
            <field>
              <name>OFFSET4_CH</name>
              <bitOffset>26</bitOffset>
              <bitWidth>5</bitWidth>
            </field>
            <field>
              <name>OFFSET4_EN</name>
              <bitOffset>31</bitOffset>
              <bitWidth>1</bitWidth>
            </field>
          </fields>
        </register>
        <register>
          <name>JDR1</name>
          <addressOffset>0x80</addressOffset>
          <size>0x20</size>
          <fields>
            <field>
              <name>JDATA</name>
              <bitOffset>0</bitOffset>
              <bitWidth>16</bitWidth>
            </field>
          </fields>
        </register>
        <register>
          <name>JDR2</name>
          <addressOffset>0x84</addressOffset>
          <size>0x20</size>
          <fields>
            <field>
              <name>JDATA</name>
              <bitOffset>0</bitOffset>
              <bitWidth>16</bitWidth>
            </field>
          </fields>
        </register>
        <register>
          <name>JDR3</name>
          <addressOffset>0x88</addressOffset>
          <size>0x20</size>
          <fields>
            <field>
              <name>JDATA</name>
              <bitOffset>0</bitOffset>
              <bitWidth>16</bitWidth>
            </field>
          </fields>
        </register>
        <register>
          <name>JDR4</name>
          <addressOffset>0x8c</addressOffset>
          <size>0x20</size>
          <fields>
            <field>
              <name>JDATA</name>
              <bitOffset>0</bitOffset>
              <bitWidth>16</bitWidth>
            </field>
          </fields>
        </register>
        <register>
          <name>AWD2CR</name>
          <addressOffset>0xa0</addressOffset>
          <size>0x20</size>
          <fields>
            <field>
              <name>AWD2CH</name>
              <bitOffset>0</bitOffset>
              <bitWidth>19</bitWidth>
            </field>
          </fields>
        </register>
        <register>
          <name>AWD3CR</name>
          <addressOffset>0xa4</addressOffset>
          <size>0x20</size>
          <fields>
            <field>
              <name>AWD3CH</name>
              <bitOffset>0</bitOffset>
              <bitWidth>19</bitWidth>
            </field>
          </fields>
        </register>
        <register>
          <name>DIFSEL</name>
          <addressOffset>0xb0</addressOffset>
          <size>0x20</size>
          <fields>
            <field>
              <name>DIFSEL</name>
              <bitOffset>0</bitOffset>
              <bitWidth>19</bitWidth>
            </field>
          </fields>
        </register>
        <register>
          <name>CALFACT</name>
          <addressOffset>0xb4</addressOffset>
          <size>0x20</size>
          <fields>
            <field>
              <name>CALFACT_S</name>
              <bitOffset>0</bitOffset>
              <bitWidth>7</bitWidth>
            </field>
            <field>
              <name>CALFACT_D</name>
              <bitOffset>16</bitOffset>
              <bitWidth>7</bitWidth>
            </field>
          </fields>
        </register>
        <register>
          <name>GCOMP</name>
          <addressOffset>0xc0</addressOffset>
          <size>0x20</size>
          <fields>
            <field>
              <name>GCOMPCOEFF</name>
              <bitOffset>0</bitOffset>
              <bitWidth>14</bitWidth>
            </field>
          </fields>
        </register>
      </registers>
    </peripheral>
    <peripheral>
      <name>ADC12_COMMON</name>
      <baseAddress>0x50000300</baseAddress>
      <registers>
        <register>
          <name>CSR</name>
          <addressOffset>0x0</addressOffset>
          <size>0x20</size>
          <fields>
            <field>
              <name>ADRDY_MST</name>
              <bitOffset>0</bitOffset>
              <bitWidth>1</bitWidth>
            </field>
            <field>
              <name>EOSMP_MST</name>
              <bitOffset>1</bitOffset>
              <bitWidth>1</bitWidth>
            </field>
            <field>
              <name>EOC_MST</name>
              <bitOffset>2</bitOffset>
              <bitWidth>1</bitWidth>
            </field>
            <field>
              <name>EOS_MST</name>
              <bitOffset>3</bitOffset>
              <bitWidth>1</bitWidth>
            </field>
            <field>
              <name>OVR_MST</name>
              <bitOffset>4</bitOffset>
              <bitWidth>1</bitWidth>
            </field>
            <field>
              <name>JEOC_MST</name>
              <bitOffset>5</bitOffset>
              <bitWidth>1</bitWidth>
            </field>
            <field>
              <name>JEOS_MST</name>
              <bitOffset>6</bitOffset>
              <bitWidth>1</bitWidth>
            </field>
            <field>
              <name>AWD1_MST</name>
              <bitOffset>7</bitOffset>
              <bitWidth>1</bitWidth>
            </field>
            <field>
              <name>AWD2_MST</name>
              <bitOffset>8</bitOffset>
              <bitWidth>1</bitWidth>
            </field>
            <field>
              <name>AWD3_MST</name>
              <bitOffset>9</bitOffset>
              <bitWidth>1</bitWidth>
            </field>
            <field>
              <name>JQOVF_MST</name>
              <bitOffset>10</bitOffset>
              <bitWidth>1</bitWidth>
            </field>
            <field>
              <name>ADRDY_SLV</name>
              <bitOffset>16</bitOffset>
              <bitWidth>1</bitWidth>
            </field>
            <field>
              <name>EOSMP_SLV</name>
              <bitOffset>17</bitOffset>
              <bitWidth>1</bitWidth>
            </field>
            <field>
              <name>EOC_SLV</name>
              <bitOffset>18</bitOffset>
              <bitWidth>1</bitWidth>
            </field>
            <field>
              <name>EOS_SLV</name>
              <bitOffset>19</bitOffset>
              <bitWidth>1</bitWidth>
            </field>
            <field>
              <name>OVR_SLV</name>
              <bitOffset>20</bitOffset>
              <bitWidth>1</bitWidth>
            </field>
            <field>
              <name>JEOC_SLV</name>
              <bitOffset>21</bitOffset>
              <bitWidth>1</bitWidth>
            </field>
            <field>
              <name>JEOS_SLV</name>
              <bitOffset>22</bitOffset>
              <bitWidth>1</bitWidth>
            </field>
            <field>
              <name>AWD1_SLV</name>
              <bitOffset>23</bitOffset>
              <bitWidth>1</bitWidth>
            </field>
            <field>
              <name>AWD2_SLV</name>
              <bitOffset>24</bitOffset>
              <bitWidth>1</bitWidth>
            </field>
            <field>
              <name>AWD3_SLV</name>
              <bitOffset>25</bitOffset>
              <bitWidth>1</bitWidth>
            </field>
            <field>
              <name>JQOVF_SLV</name>
              <bitOffset>26</bitOffset>
              <bitWidth>1</bitWidth>
            </field>
          </fields>
        </register>
        <register>
          <name>CCR</name>
          <addressOffset>0x8</addressOffset>
          <size>0x20</size>
          <fields>
            <field>
              <name>DUAL</name>
              <bitOffset>0</bitOffset>
              <bitWidth>5</bitWidth>
            </field>
            <field>
              <name>DELAY</name>
              <bitOffset>8</bitOffset>
              <bitWidth>4</bitWidth>
            </field>
            <field>
              <name>DMACFG</name>
              <bitOffset>13</bitOffset>
              <bitWidth>1</bitWidth>
            </field>
            <field>
              <name>MDMA</name>
              <bitOffset>14</bitOffset>
              <bitWidth>2</bitWidth>
            </field>
            <field>
              <name>CKMODE</name>
              <bitOffset>16</bitOffset>
              <bitWidth>2</bitWidth>
            </field>
            <field>
              <name>PRESC</name>
              <bitOffset>18</bitOffset>
              <bitWidth>4</bitWidth>
            </field>
            <field>
              <name>VREFEN</name>
              <bitOffset>22</bitOffset>
              <bitWidth>1</bitWidth>
            </field>
            <field>
              <name>VSENSESEL</name>
              <bitOffset>23</bitOffset>
              <bitWidth>1</bitWidth>
            </field>
            <field>
              <name>VBATSEL</name>
              <bitOffset>24</bitOffset>
              <bitWidth>1</bitWidth>
            </field>
          </fields>
        </register>
        <register>
          <name>CDR</name>
          <addressOffset>0xc</addressOffset>
          <size>0x20</size>
          <fields>
            <field>
              <name>RDATA_MST</name>
              <bitOffset>0</bitOffset>
              <bitWidth>16</bitWidth>
            </field>
            <field>
              <name>RDATA_SLV</name>
              <bitOffset>16</bitOffset>
              <bitWidth>16</bitWidth>
            </field>
          </fields>
        </register>
      </registers>
    </peripheral>
    <peripheral>
      <name>ADC3</name>
      <baseAddress>0x50000400</baseAddress>
      <registers>
        <register>
          <name>ISR</name>
          <addressOffset>0x0</addressOffset>
          <size>0x20</size>
          <fields>
            <field>
              <name>ADRDY</name>
              <bitOffset>0</bitOffset>
              <bitWidth>1</bitWidth>
            </field>
            <field>
              <name>EOSMP</name>
              <bitOffset>1</bitOffset>
              <bitWidth>1</bitWidth>
            </field>
            <field>
              <name>EOC</name>
              <bitOffset>2</bitOffset>
              <bitWidth>1</bitWidth>
            </field>
            <field>
              <name>EOS</name>
              <bitOffset>3</bitOffset>
              <bitWidth>1</bitWidth>
            </field>
            <field>
              <name>OVR</name>
              <bitOffset>4</bitOffset>
              <bitWidth>1</bitWidth>
            </field>
            <field>
              <name>JEOC</name>
              <bitOffset>5</bitOffset>
              <bitWidth>1</bitWidth>
            </field>
            <field>
              <name>JEOS</name>
              <bitOffset>6</bitOffset>
              <bitWidth>1</bitWidth>
            </field>
            <field>
              <name>AWD1</name>
              <bitOffset>7</bitOffset>
              <bitWidth>1</bitWidth>
            </field>
            <field>
              <name>AWD2</name>
              <bitOffset>8</bitOffset>
              <bitWidth>1</bitWidth>
            </field>
            <field>
              <name>AWD3</name>
              <bitOffset>9</bitOffset>
              <bitWidth>1</bitWidth>
            </field>
            <field>
              <name>JQOVF</name>
              <bitOffset>10</bitOffset>
              <bitWidth>1</bitWidth>
            </field>
          </fields>
        </register>
        <register>
          <name>IER</name>
          <addressOffset>0x4</addressOffset>
          <size>0x20</size>
          <fields>
            <field>
              <name>ADRDYIE</name>
              <bitOffset>0</bitOffset>
              <bitWidth>1</bitWidth>
            </field>
            <field>
              <name>EOSMPIE</name>
              <bitOffset>1</bitOffset>
              <bitWidth>1</bitWidth>
            </field>
            <field>
              <name>EOCIE</name>
              <bitOffset>2</bitOffset>
              <bitWidth>1</bitWidth>
            </field>
            <field>
              <name>EOSIE</name>
              <bitOffset>3</bitOffset>
              <bitWidth>1</bitWidth>
            </field>
            <field>
              <name>OVRIE</name>
              <bitOffset>4</bitOffset>
              <bitWidth>1</bitWidth>
            </field>
            <field>
              <name>JEOCIE</name>
              <bitOffset>5</bitOffset>
              <bitWidth>1</bitWidth>
            </field>
            <field>
              <name>JEOSIE</name>
              <bitOffset>6</bitOffset>
              <bitWidth>1</bitWidth>
            </field>
            <field>
              <name>AWD1IE</name>
              <bitOffset>7</bitOffset>
              <bitWidth>1</bitWidth>
            </field>
            <field>
              <name>AWD2IE</name>
              <bitOffset>8</bitOffset>
              <bitWidth>1</bitWidth>
            </field>
            <field>
              <name>AWD3IE</name>
              <bitOffset>9</bitOffset>
              <bitWidth>1</bitWidth>
            </field>
            <field>
              <name>JQOVFIE</name>
              <bitOffset>10</bitOffset>
              <bitWidth>1</bitWidth>
            </field>
          </fields>
        </register>
        <register>
          <name>CR</name>
          <addressOffset>0x8</addressOffset>
          <size>0x20</size>
          <fields>
            <field>
              <name>ADEN</name>
              <bitOffset>0</bitOffset>
              <bitWidth>1</bitWidth>
            </field>
            <field>
              <name>ADDIS</name>
              <bitOffset>1</bitOffset>
              <bitWidth>1</bitWidth>
            </field>
            <field>
              <name>ADSTART</name>
              <bitOffset>2</bitOffset>
              <bitWidth>1</bitWidth>
            </field>
            <field>
              <name>JADSTART</name>
              <bitOffset>3</bitOffset>
              <bitWidth>1</bitWidth>
            </field>
            <field>
              <name>ADSTP</name>
              <bitOffset>4</bitOffset>
              <bitWidth>1</bitWidth>
            </field>
            <field>
              <name>JADSTP</name>
              <bitOffset>5</bitOffset>
              <bitWidth>1</bitWidth>
            </field>
            <field>
              <name>ADVREGEN</name>
              <bitOffset>28</bitOffset>
              <bitWidth>1</bitWidth>
            </field>
            <field>
              <name>DEEPPWD</name>
              <bitOffset>29</bitOffset>
              <bitWidth>1</bitWidth>
            </field>
            <field>
              <name>ADCALDIF</name>
              <bitOffset>30</bitOffset>
              <bitWidth>1</bitWidth>
            </field>
            <field>
              <name>ADCAL</name>
              <bitOffset>31</bitOffset>
              <bitWidth>1</bitWidth>
            </field>
          </fields>
        </register>
        <register>
          <name>CFGR</name>
          <addressOffset>0xc</addressOffset>
          <size>0x20</size>
          <fields>
            <field>
              <name>DMAEN</name>
              <bitOffset>0</bitOffset>
              <bitWidth>1</bitWidth>
            </field>
            <field>
              <name>DMACFG</name>
              <bitOffset>1</bitOffset>
              <bitWidth>1</bitWidth>
            </field>
            <field>
              <name>RES</name>
              <bitOffset>3</bitOffset>
              <bitWidth>2</bitWidth>
            </field>
            <field>
              <name>EXTSEL</name>
              <bitOffset>5</bitOffset>
              <bitWidth>5</bitWidth>
            </field>
            <field>
              <name>EXTEN</name>
              <bitOffset>10</bitOffset>
              <bitWidth>2</bitWidth>
            </field>
            <field>
              <name>OVRMOD</name>
              <bitOffset>12</bitOffset>
              <bitWidth>1</bitWidth>
            </field>
            <field>
              <name>CONT</name>
              <bitOffset>13</bitOffset>
              <bitWidth>1</bitWidth>
            </field>
            <field>
              <name>AUTDLY</name>
              <bitOffset>14</bitOffset>
              <bitWidth>1</bitWidth>
            </field>
            <field>
              <name>ALIGN</name>
              <bitOffset>15</bitOffset>
              <bitWidth>1</bitWidth>
            </field>
            <field>
              <name>DISCEN</name>
              <bitOffset>16</bitOffset>
              <bitWidth>1</bitWidth>
            </field>
            <field>
              <name>DISCNUM</name>
              <bitOffset>17</bitOffset>
              <bitWidth>3</bitWidth>
            </field>
            <field>
              <name>JDISCEN</name>
              <bitOffset>20</bitOffset>
              <bitWidth>1</bitWidth>
            </field>
            <field>
              <name>JQM</name>
              <bitOffset>21</bitOffset>
              <bitWidth>1</bitWidth>
            </field>
            <field>
              <name>AWD1SGL</name>
              <bitOffset>22</bitOffset>
              <bitWidth>1</bitWidth>
            </field>
            <field>
              <name>AWD1EN</name>
              <bitOffset>23</bitOffset>
              <bitWidth>1</bitWidth>
            </field>
            <field>
              <name>JAWD1EN</name>
              <bitOffset>24</bitOffset>
              <bitWidth>1</bitWidth>
            </field>
            <field>
              <name>JAUTO</name>
              <bitOffset>25</bitOffset>
              <bitWidth>1</bitWidth>
            </field>
            <field>
              <name>AWD1CH</name>
              <bitOffset>26</bitOffset>
              <bitWidth>5</bitWidth>
            </field>
            <field>
              <name>JQDIS</name>
              <bitOffset>31</bitOffset>
              <bitWidth>1</bitWidth>
            </field>
          </fields>
        </register>
        <register>
          <name>CFGR2</name>
          <addressOffset>0x10</addressOffset>
          <size>0x20</size>
          <fields>
            <field>
              <name>ROVSE</name>
              <bitOffset>0</bitOffset>
              <bitWidth>1</bitWidth>
            </field>
            <field>
              <name>JOVSE</name>
              <bitOffset>1</bitOffset>
              <bitWidth>1</bitWidth>
            </field>
            <field>
              <name>OVSR</name>
              <bitOffset>2</bitOffset>
              <bitWidth>3</bitWidth>
            </field>
            <field>
              <name>OVSS</name>
              <bitOffset>5</bitOffset>
              <bitWidth>4</bitWidth>
            </field>
            <field>
              <name>TROVS</name>
              <bitOffset>9</bitOffset>
              <bitWidth>1</bitWidth>
            </field>
            <field>
              <name>ROVSM</name>
              <bitOffset>10</bitOffset>
              <bitWidth>1</bitWidth>
            </field>
            <field>
              <name>GCOMP</name>
              <bitOffset>16</bitOffset>
              <bitWidth>1</bitWidth>
            </field>
            <field>
              <name>SWTRIG</name>
              <bitOffset>25</bitOffset>
              <bitWidth>1</bitWidth>
            </field>
            <field>
              <name>BULB</name>
              <bitOffset>26</bitOffset>
              <bitWidth>1</bitWidth>
            </field>
            <field>
              <name>SMPTRIG</name>
              <bitOffset>27</bitOffset>
              <bitWidth>1</bitWidth>
            </field>
          </fields>
        </register>
        <register>
          <name>SMPR1</name>
          <addressOffset>0x14</addressOffset>
          <size>0x20</size>
          <fields>
            <field>
              <name>SMP0</name>
              <bitOffset>0</bitOffset>
              <bitWidth>3</bitWidth>
            </field>
            <field>
              <name>SMP1</name>
              <bitOffset>3</bitOffset>
              <bitWidth>3</bitWidth>
            </field>
            <field>
              <name>SMP2</name>
              <bitOffset>6</bitOffset>
              <bitWidth>3</bitWidth>
            </field>
            <field>
              <name>SMP3</name>
              <bitOffset>9</bitOffset>
              <bitWidth>3</bitWidth>
            </field>
            <field>
              <name>SMP4</name>
              <bitOffset>12</bitOffset>
              <bitWidth>3</bitWidth>
            </field>
            <field>
              <name>SMP5</name>
              <bitOffset>15</bitOffset>
              <bitWidth>3</bitWidth>
            </field>
            <field>
              <name>SMP6</name>
              <bitOffset>18</bitOffset>
              <bitWidth>3</bitWidth>
            </field>
            <field>
              <name>SMP7</name>
              <bitOffset>21</bitOffset>
              <bitWidth>3</bitWidth>
            </field>
            <field>
              <name>SMP8</name>
              <bitOffset>24</bitOffset>
              <bitWidth>3</bitWidth>
            </field>
            <field>
              <name>SMP9</name>
              <bitOffset>27</bitOffset>
              <bitWidth>3</bitWidth>
            </field>
            <field>
              <name>SMPPLUS</name>
              <bitOffset>31</bitOffset>
              <bitWidth>1</bitWidth>
            </field>
          </fields>
        </register>
        <register>
          <name>SMPR2</name>
          <addressOffset>0x18</addressOffset>
          <size>0x20</size>
          <fields>
            <field>
              <name>SMP10</name>
              <bitOffset>0</bitOffset>
              <bitWidth>3</bitWidth>
            </field>
            <field>
              <name>SMP11</name>
              <bitOffset>3</bitOffset>
              <bitWidth>3</bitWidth>
            </field>
            <field>
              <name>SMP12</name>
              <bitOffset>6</bitOffset>
              <bitWidth>3</bitWidth>
            </field>
            <field>
              <name>SMP13</name>
              <bitOffset>9</bitOffset>
              <bitWidth>3</bitWidth>
            </field>
            <field>
              <name>SMP14</name>
              <bitOffset>12</bitOffset>
              <bitWidth>3</bitWidth>
            </field>
            <field>
              <name>SMP15</name>
              <bitOffset>15</bitOffset>
              <bitWidth>3</bitWidth>
            </field>
            <field>
              <name>SMP16</name>
              <bitOffset>18</bitOffset>
              <bitWidth>3</bitWidth>
            </field>
            <field>
              <name>SMP17</name>
              <bitOffset>21</bitOffset>
              <bitWidth>3</bitWidth>
            </field>
            <field>
              <name>SMP18</name>
              <bitOffset>24</bitOffset>
              <bitWidth>3</bitWidth>
            </field>
          </fields>
        </register>
        <register>
          <name>TR1</name>
          <addressOffset>0x20</addressOffset>
          <size>0x20</size>
          <fields>
            <field>
              <name>LT1</name>
              <bitOffset>0</bitOffset>
              <bitWidth>12</bitWidth>
            </field>
            <field>
              <name>AWDFILT</name>
              <bitOffset>12</bitOffset>
              <bitWidth>3</bitWidth>
            </field>
            <field>
              <name>HT1</name>
              <bitOffset>16</bitOffset>
              <bitWidth>12</bitWidth>
            </field>
          </fields>
        </register>
        <register>
          <name>TR2</name>
          <addressOffset>0x24</addressOffset>
          <size>0x20</size>
          <fields>
            <field>
              <name>LT2</name>
              <bitOffset>0</bitOffset>
              <bitWidth>8</bitWidth>
            </field>
            <field>
              <name>HT2</name>
              <bitOffset>16</bitOffset>
              <bitWidth>8</bitWidth>
            </field>
          </fields>
        </register>
        <register>
          <name>TR3</name>
          <addressOffset>0x28</addressOffset>
          <size>0x20</size>
          <fields>
            <field>
              <name>LT3</name>
              <bitOffset>0</bitOffset>
              <bitWidth>8</bitWidth>
            </field>
            <field>
              <name>HT3</name>
              <bitOffset>16</bitOffset>
              <bitWidth>8</bitWidth>
            </field>
          </fields>
        </register>
        <register>
          <name>SQR1</name>
          <addressOffset>0x30</addressOffset>
          <size>0x20</size>
          <fields>
            <field>
              <name>L</name>
              <bitOffset>0</bitOffset>
              <bitWidth>4</bitWidth>
            </field>
            <field>
              <name>SQ1</name>
              <bitOffset>6</bitOffset>
              <bitWidth>5</bitWidth>
            </field>
            <field>
              <name>SQ2</name>
              <bitOffset>12</bitOffset>
              <bitWidth>5</bitWidth>
            </field>
            <field>
              <name>SQ3</name>
              <bitOffset>18</bitOffset>
              <bitWidth>5</bitWidth>
            </field>
            <field>
              <name>SQ4</name>
              <bitOffset>24</bitOffset>
              <bitWidth>5</bitWidth>
            </field>
          </fields>
        </register>
        <register>
          <name>SQR2</name>
          <addressOffset>0x34</addressOffset>
          <size>0x20</size>
          <fields>
            <field>
              <name>SQ5</name>
              <bitOffset>0</bitOffset>
              <bitWidth>5</bitWidth>
            </field>
            <field>
              <name>SQ6</name>
              <bitOffset>6</bitOffset>
              <bitWidth>5</bitWidth>
            </field>
            <field>
              <name>SQ7</name>
              <bitOffset>12</bitOffset>
              <bitWidth>5</bitWidth>
            </field>
            <field>
              <name>SQ8</name>
              <bitOffset>18</bitOffset>
              <bitWidth>5</bitWidth>
            </field>
            <field>
              <name>SQ9</name>
              <bitOffset>24</bitOffset>
              <bitWidth>5</bitWidth>
            </field>
          </fields>
        </register>
        <register>
          <name>SQR3</name>
          <addressOffset>0x38</addressOffset>
          <size>0x20</size>
          <fields>
            <field>
              <name>SQ10</name>
              <bitOffset>0</bitOffset>
              <bitWidth>5</bitWidth>
            </field>
            <field>
              <name>SQ11</name>
              <bitOffset>6</bitOffset>
              <bitWidth>5</bitWidth>
            </field>
            <field>
              <name>SQ12</name>
              <bitOffset>12</bitOffset>
              <bitWidth>5</bitWidth>
            </field>
            <field>
              <name>SQ13</name>
              <bitOffset>18</bitOffset>
              <bitWidth>5</bitWidth>
            </field>
            <field>
              <name>SQ14</name>
              <bitOffset>24</bitOffset>
              <bitWidth>5</bitWidth>
            </field>
          </fields>
        </register>
        <register>
          <name>SQR4</name>
          <addressOffset>0x3c</addressOffset>
          <size>0x20</size>
          <fields>
            <field>
              <name>SQ15</name>
              <bitOffset>0</bitOffset>
              <bitWidth>5</bitWidth>
            </field>
            <field>
              <name>SQ16</name>
              <bitOffset>6</bitOffset>
              <bitWidth>5</bitWidth>
            </field>
          </fields>
        </register>
        <register>
          <name>DR</name>
          <addressOffset>0x40</addressOffset>
          <size>0x20</size>
          <fields>
            <field>
              <name>RDATA</name>
              <bitOffset>0</bitOffset>
              <bitWidth>16</bitWidth>
            </field>
          </fields>
        </register>
        <register>
          <name>JSQR</name>
          <addressOffset>0x4c</addressOffset>
          <size>0x20</size>
          <fields>
            <field>
              <name>JL</name>
              <bitOffset>0</bitOffset>
              <bitWidth>2</bitWidth>
            </field>
            <field>
              <name>JEXTSEL</name>
              <bitOffset>2</bitOffset>
              <bitWidth>5</bitWidth>
            </field>
            <field>
              <name>JEXTEN</name>
              <bitOffset>7</bitOffset>
              <bitWidth>2</bitWidth>
            </field>
            <field>
              <name>JSQ1</name>
              <bitOffset>9</bitOffset>
              <bitWidth>5</bitWidth>
            </field>
            <field>
              <name>JSQ2</name>
              <bitOffset>15</bitOffset>
              <bitWidth>5</bitWidth>
            </field>
            <field>
              <name>JSQ3</name>
              <bitOffset>21</bitOffset>
              <bitWidth>5</bitWidth>
            </field>
            <field>
              <name>JSQ4</name>
              <bitOffset>27</bitOffset>
              <bitWidth>5</bitWidth>
            </field>
          </fields>
        </register>
        <register>
          <name>OFR1</name>
          <addressOffset>0x60</addressOffset>
          <size>0x20</size>
          <fields>
            <field>
              <name>OFFSET1</name>
              <bitOffset>0</bitOffset>
              <bitWidth>12</bitWidth>
            </field>
            <field>
              <name>OFFSETPOS</name>
              <bitOffset>24</bitOffset>
              <bitWidth>1</bitWidth>
            </field>
            <field>
              <name>SATEN</name>
              <bitOffset>25</bitOffset>
              <bitWidth>1</bitWidth>
            </field>
            <field>
              <name>OFFSET1_CH</name>
              <bitOffset>26</bitOffset>
              <bitWidth>5</bitWidth>
            </field>
            <field>
              <name>OFFSET1_EN</name>
              <bitOffset>31</bitOffset>
              <bitWidth>1</bitWidth>
            </field>
          </fields>
        </register>
        <register>
          <name>OFR2</name>
          <addressOffset>0x64</addressOffset>
          <size>0x20</size>
          <fields>
            <field>
              <name>OFFSET2</name>
              <bitOffset>0</bitOffset>
              <bitWidth>12</bitWidth>
            </field>
            <field>
              <name>OFFSETPOS</name>
              <bitOffset>24</bitOffset>
              <bitWidth>1</bitWidth>
            </field>
            <field>
              <name>SATEN</name>
              <bitOffset>25</bitOffset>
              <bitWidth>1</bitWidth>
            </field>
            <field>
              <name>OFFSET2_CH</name>
              <bitOffset>26</bitOffset>
              <bitWidth>5</bitWidth>
            </field>
            <field>
              <name>OFFSET2_EN</name>
              <bitOffset>31</bitOffset>
              <bitWidth>1</bitWidth>
            </field>
          </fields>
        </register>
        <register>
          <name>OFR3</name>
          <addressOffset>0x68</addressOffset>
          <size>0x20</size>
          <fields>
            <field>
              <name>OFFSET3</name>
              <bitOffset>0</bitOffset>
              <bitWidth>12</bitWidth>
            </field>
            <field>
              <name>OFFSETPOS</name>
              <bitOffset>24</bitOffset>
              <bitWidth>1</bitWidth>
            </field>
            <field>
              <name>SATEN</name>
              <bitOffset>25</bitOffset>
              <bitWidth>1</bitWidth>
            </field>
            <field>
              <name>OFFSET3_CH</name>
              <bitOffset>26</bitOffset>
              <bitWidth>5</bitWidth>
            </field>
            <field>
              <name>OFFSET3_EN</name>
              <bitOffset>31</bitOffset>
              <bitWidth>1</bitWidth>
            </field>
          </fields>
        </register>
        <register>
          <name>OFR4</name>
          <addressOffset>0x6c</addressOffset>
          <size>0x20</size>
          <fields>
            <field>
              <name>OFFSET4</name>
              <bitOffset>0</bitOffset>
              <bitWidth>12</bitWidth>
            </field>
            <field>
              <name>OFFSETPOS</name>
              <bitOffset>24</bitOffset>
              <bitWidth>1</bitWidth>
            </field>
            <field>
              <name>SATEN</name>
              <bitOffset>25</bitOffset>
              <bitWidth>1</bitWidth>
            </field>
            <field>
              <name>OFFSET4_CH</name>
              <bitOffset>26</bitOffset>
              <bitWidth>5</bitWidth>
            </field>
            <field>
              <name>OFFSET4_EN</name>
              <bitOffset>31</bitOffset>
              <bitWidth>1</bitWidth>
            </field>
          </fields>
        </register>
        <register>
          <name>JDR1</name>
          <addressOffset>0x80</addressOffset>
          <size>0x20</size>
          <fields>
            <field>
              <name>JDATA</name>
              <bitOffset>0</bitOffset>
              <bitWidth>16</bitWidth>
            </field>
          </fields>
        </register>
        <register>
          <name>JDR2</name>
          <addressOffset>0x84</addressOffset>
          <size>0x20</size>
          <fields>
            <field>
              <name>JDATA</name>
              <bitOffset>0</bitOffset>
              <bitWidth>16</bitWidth>
            </field>
          </fields>
        </register>
        <register>
          <name>JDR3</name>
          <addressOffset>0x88</addressOffset>
          <size>0x20</size>
          <fields>
            <field>
              <name>JDATA</name>
              <bitOffset>0</bitOffset>
              <bitWidth>16</bitWidth>
            </field>
          </fields>
        </register>
        <register>
          <name>JDR4</name>
          <addressOffset>0x8c</addressOffset>
          <size>0x20</size>
          <fields>
            <field>
              <name>JDATA</name>
              <bitOffset>0</bitOffset>
              <bitWidth>16</bitWidth>
            </field>
          </fields>
        </register>
        <register>
          <name>AWD2CR</name>
          <addressOffset>0xa0</addressOffset>
          <size>0x20</size>
          <fields>
            <field>
              <name>AWD2CH</name>
              <bitOffset>0</bitOffset>
              <bitWidth>19</bitWidth>
            </field>
          </fields>
        </register>
        <register>
          <name>AWD3CR</name>
          <addressOffset>0xa4</addressOffset>
          <size>0x20</size>
          <fields>
            <field>
              <name>AWD3CH</name>
              <bitOffset>0</bitOffset>
              <bitWidth>19</bitWidth>
            </field>
          </fields>
        </register>
        <register>
          <name>DIFSEL</name>
          <addressOffset>0xb0</addressOffset>
          <size>0x20</size>
          <fields>
            <field>
              <name>DIFSEL</name>
              <bitOffset>0</bitOffset>
              <bitWidth>19</bitWidth>
            </field>
          </fields>
        </register>
        <register>
          <name>CALFACT</name>
          <addressOffset>0xb4</addressOffset>
          <size>0x20</size>
          <fields>
            <field>
              <name>CALFACT_S</name>
              <bitOffset>0</bitOffset>
              <bitWidth>7</bitWidth>
            </field>
            <field>
              <name>CALFACT_D</name>
              <bitOffset>16</bitOffset>
              <bitWidth>7</bitWidth>
            </field>
          </fields>
        </register>
        <register>
          <name>GCOMP</name>
          <addressOffset>0xc0</addressOffset>
          <size>0x20</size>
          <fields>
            <field>
              <name>GCOMPCOEFF</name>
              <bitOffset>0</bitOffset>
              <bitWidth>14</bitWidth>
            </field>
          </fields>
        </register>
      </registers>
    </peripheral>
    <peripheral>
      <name>ADC345_COMMON</name>
      <baseAddress>0x50000700</baseAddress>
      <registers>
        <register>
          <name>CSR</name>
          <addressOffset>0x0</addressOffset>
          <size>0x20</size>
          <fields>
            <field>
              <name>ADRDY_MST</name>
              <bitOffset>0</bitOffset>
              <bitWidth>1</bitWidth>
            </field>
            <field>
              <name>EOSMP_MST</name>
              <bitOffset>1</bitOffset>
              <bitWidth>1</bitWidth>
            </field>
            <field>
              <name>EOC_MST</name>
              <bitOffset>2</bitOffset>
              <bitWidth>1</bitWidth>
            </field>
            <field>
              <name>EOS_MST</name>
              <bitOffset>3</bitOffset>
              <bitWidth>1</bitWidth>
            </field>
            <field>
              <name>OVR_MST</name>
              <bitOffset>4</bitOffset>
              <bitWidth>1</bitWidth>
            </field>
            <field>
              <name>JEOC_MST</name>
              <bitOffset>5</bitOffset>
              <bitWidth>1</bitWidth>
            </field>
            <field>
              <name>JEOS_MST</name>
              <bitOffset>6</bitOffset>
              <bitWidth>1</bitWidth>
            </field>
            <field>
              <name>AWD1_MST</name>
              <bitOffset>7</bitOffset>
              <bitWidth>1</bitWidth>
            </field>
            <field>
              <name>AWD2_MST</name>
              <bitOffset>8</bitOffset>
              <bitWidth>1</bitWidth>
            </field>
            <field>
              <name>AWD3_MST</name>
              <bitOffset>9</bitOffset>
              <bitWidth>1</bitWidth>
            </field>
            <field>
              <name>JQOVF_MST</name>
              <bitOffset>10</bitOffset>
              <bitWidth>1</bitWidth>
            </field>
            <field>
              <name>ADRDY_SLV</name>
              <bitOffset>16</bitOffset>
              <bitWidth>1</bitWidth>
            </field>
            <field>
              <name>EOSMP_SLV</name>
              <bitOffset>17</bitOffset>
              <bitWidth>1</bitWidth>
            </field>
            <field>
              <name>EOC_SLV</name>
              <bitOffset>18</bitOffset>
              <bitWidth>1</bitWidth>
            </field>
            <field>
              <name>EOS_SLV</name>
              <bitOffset>19</bitOffset>
              <bitWidth>1</bitWidth>
            </field>
            <field>
              <name>OVR_SLV</name>
              <bitOffset>20</bitOffset>
              <bitWidth>1</bitWidth>
            </field>
            <field>
              <name>JEOC_SLV</name>
              <bitOffset>21</bitOffset>
              <bitWidth>1</bitWidth>
            </field>
            <field>
              <name>JEOS_SLV</name>
              <bitOffset>22</bitOffset>
              <bitWidth>1</bitWidth>
            </field>
            <field>
              <name>AWD1_SLV</name>
              <bitOffset>23</bitOffset>
              <bitWidth>1</bitWidth>
            </field>
            <field>
              <name>AWD2_SLV</name>
              <bitOffset>24</bitOffset>
              <bitWidth>1</bitWidth>
            </field>
            <field>
              <name>AWD3_SLV</name>
              <bitOffset>25</bitOffset>
              <bitWidth>1</bitWidth>
            </field>
            <field>
              <name>JQOVF_SLV</name>
              <bitOffset>26</bitOffset>
              <bitWidth>1</bitWidth>
            </field>
          </fields>
        </register>
        <register>
          <name>CCR</name>
          <addressOffset>0x8</addressOffset>
          <size>0x20</size>
          <fields>
            <field>
              <name>DUAL</name>
              <bitOffset>0</bitOffset>
              <bitWidth>5</bitWidth>
            </field>
            <field>
              <name>DELAY</name>
              <bitOffset>8</bitOffset>
              <bitWidth>4</bitWidth>
            </field>
            <field>
              <name>DMACFG</name>
              <bitOffset>13</bitOffset>
              <bitWidth>1</bitWidth>
            </field>
            <field>
              <name>MDMA</name>
              <bitOffset>14</bitOffset>
              <bitWidth>2</bitWidth>
            </field>
            <field>
              <name>CKMODE</name>
              <bitOffset>16</bitOffset>
              <bitWidth>2</bitWidth>
            </field>
            <field>
              <name>PRESC</name>
              <bitOffset>18</bitOffset>
              <bitWidth>4</bitWidth>
            </field>
            <field>
              <name>VREFEN</name>
              <bitOffset>22</bitOffset>
              <bitWidth>1</bitWidth>
            </field>
            <field>
              <name>VSENSESEL</name>
              <bitOffset>23</bitOffset>
              <bitWidth>1</bitWidth>
            </field>
            <field>
              <name>VBATSEL</name>
              <bitOffset>24</bitOffset>
              <bitWidth>1</bitWidth>
            </field>
          </fields>
        </register>
        <register>
          <name>CDR</name>
          <addressOffset>0xc</addressOffset>
          <size>0x20</size>
          <fields>
            <field>
              <name>RDATA_MST</name>
              <bitOffset>0</bitOffset>
              <bitWidth>16</bitWidth>
            </field>
            <field>
              <name>RDATA_SLV</name>
              <bitOffset>16</bitOffset>
              <bitWidth>16</bitWidth>
            </field>
          </fields>
        </register>
      </registers>
    </peripheral>
    <peripheral>
      <name>DAC</name>
      <baseAddress>0x50000800</baseAddress>
      <registers>
        <register>
          <name>CR</name>
          <addressOffset>0x0</addressOffset>
          <size>0x20</size>
          <fields>
            <field>
              <name>EN1</name>
              <bitOffset>0</bitOffset>
              <bitWidth>1</bitWidth>
            </field>
            <field>
              <name>TEN1</name>
              <bitOffset>1</bitOffset>
              <bitWidth>1</bitWidth>
            </field>
            <field>
              <name>TSEL1</name>
              <bitOffset>2</bitOffset>
              <bitWidth>4</bitWidth>
            </field>
            <field>
              <name>WAVE1</name>
              <bitOffset>6</bitOffset>
              <bitWidth>2</bitWidth>
            </field>
            <field>
              <name>MAMP1</name>
              <bitOffset>8</bitOffset>
              <bitWidth>4</bitWidth>
            </field>
            <field>
              <name>DMAEN1</name>
              <bitOffset>12</bitOffset>
              <bitWidth>1</bitWidth>
            </field>
            <field>
              <name>DMAUDRIE1</name>
              <bitOffset>13</bitOffset>
              <bitWidth>1</bitWidth>
            </field>
            <field>
              <name>CEN1</name>
              <bitOffset>14</bitOffset>
              <bitWidth>1</bitWidth>
            </field>
            <field>
              <name>HFSEL</name>
              <bitOffset>15</bitOffset>
              <bitWidth>1</bitWidth>
            </field>
            <field>
              <name>EN2</name>
              <bitOffset>16</bitOffset>
              <bitWidth>1</bitWidth>
            </field>
            <field>
              <name>TEN2</name>
              <bitOffset>17</bitOffset>
              <bitWidth>1</bitWidth>
            </field>
            <field>
              <name>TSEL2</name>
              <bitOffset>18</bitOffset>
              <bitWidth>4</bitWidth>
            </field>
            <field>
              <name>WAVE2</name>
              <bitOffset>22</bitOffset>
              <bitWidth>2</bitWidth>
            </field>
            <field>
              <name>MAMP2</name>
              <bitOffset>24</bitOffset>
              <bitWidth>4</bitWidth>
            </field>
            <field>
              <name>DMAEN2</name>
              <bitOffset>28</bitOffset>
              <bitWidth>1</bitWidth>
            </field>
            <field>
              <name>DMAUDRIE2</name>
              <bitOffset>29</bitOffset>
              <bitWidth>1</bitWidth>
            </field>
            <field>
              <name>CEN2</name>
              <bitOffset>30</bitOffset>
              <bitWidth>1</bitWidth>
            </field>
          </fields>
        </register>
        <register>
          <name>SWTRIGR</name>
          <addressOffset>0x4</addressOffset>
          <size>0x20</size>
          <fields>
            <field>
              <name>SWTRIG1</name>
              <bitOffset>0</bitOffset>
              <bitWidth>1</bitWidth>
            </field>
            <field>
              <name>SWTRIG2</name>
              <bitOffset>1</bitOffset>
              <bitWidth>1</bitWidth>
            </field>
            <field>
              <name>SWTRIGB1</name>
              <bitOffset>16</bitOffset>
              <bitWidth>1</bitWidth>
            </field>
            <field>
              <name>SWTRIGB2</name>
              <bitOffset>17</bitOffset>
              <bitWidth>1</bitWidth>
            </field>
          </fields>
        </register>
        <register>
          <name>DHR12R1</name>
          <addressOffset>0x8</addressOffset>
          <size>0x20</size>
          <fields>
            <field>
              <name>DACC1DHR</name>
              <bitOffset>0</bitOffset>
              <bitWidth>12</bitWidth>
            </field>
            <field>
              <name>DACC1DHRB</name>
              <bitOffset>16</bitOffset>
              <bitWidth>12</bitWidth>
            </field>
          </fields>
        </register>
        <register>
          <name>DHR12L1</name>
          <addressOffset>0xc</addressOffset>
          <size>0x20</size>
          <fields>
            <field>
              <name>DACC1DHR</name>
              <bitOffset>4</bitOffset>
              <bitWidth>12</bitWidth>
            </field>
            <field>
              <name>DACC1DHRB</name>
              <bitOffset>20</bitOffset>
              <bitWidth>12</bitWidth>
            </field>
          </fields>
        </register>
        <register>
          <name>DHR8R1</name>
          <addressOffset>0x10</addressOffset>
          <size>0x20</size>
          <fields>
            <field>
              <name>DACC1DHR</name>
              <bitOffset>0</bitOffset>
              <bitWidth>8</bitWidth>
            </field>
            <field>
              <name>DACC1DHRB</name>
              <bitOffset>8</bitOffset>
              <bitWidth>8</bitWidth>
            </field>
          </fields>
        </register>
        <register>
          <name>DHR12R2</name>
          <addressOffset>0x14</addressOffset>
          <size>0x20</size>
          <fields>
            <field>
              <name>DACC2DHR</name>
              <bitOffset>0</bitOffset>
              <bitWidth>12</bitWidth>
            </field>
            <field>
              <name>DACC2DHRB</name>
              <bitOffset>16</bitOffset>
              <bitWidth>12</bitWidth>
            </field>
          </fields>
        </register>
        <register>
          <name>DHR12L2</name>
          <addressOffset>0x18</addressOffset>
          <size>0x20</size>
          <fields>
            <field>
              <name>DACC2DHR</name>
              <bitOffset>4</bitOffset>
              <bitWidth>12</bitWidth>
            </field>
            <field>
              <name>DACC2DHRB</name>
              <bitOffset>20</bitOffset>
              <bitWidth>12</bitWidth>
            </field>
          </fields>
        </register>
        <register>
          <name>DHR8R2</name>
          <addressOffset>0x1c</addressOffset>
          <size>0x20</size>
          <fields>
            <field>
              <name>DACC2DHR</name>
              <bitOffset>0</bitOffset>
              <bitWidth>8</bitWidth>
            </field>
            <field>
              <name>DACC2DHRB</name>
              <bitOffset>8</bitOffset>
              <bitWidth>8</bitWidth>
            </field>
          </fields>
        </register>
        <register>
          <name>DHR12RD</name>
          <addressOffset>0x20</addressOffset>
          <size>0x20</size>
          <fields>
            <field>
              <name>DACC1DHR</name>
              <bitOffset>0</bitOffset>
              <bitWidth>12</bitWidth>
            </field>
            <field>
              <name>DACC2DHR</name>
              <bitOffset>16</bitOffset>
              <bitWidth>12</bitWidth>
            </field>
          </fields>
        </register>
        <register>
          <name>DHR12LD</name>
          <addressOffset>0x24</addressOffset>
          <size>0x20</size>
          <fields>
            <field>
              <name>DACC1DHR</name>
              <bitOffset>4</bitOffset>
              <bitWidth>12</bitWidth>
            </field>
            <field>
              <name>DACC2DHR</name>
              <bitOffset>20</bitOffset>
              <bitWidth>12</bitWidth>
            </field>
          </fields>
        </register>
        <register>
          <name>DHR8RD</name>
          <addressOffset>0x28</addressOffset>
          <size>0x20</size>
          <fields>
            <field>
              <name>DACC1DHR</name>
              <bitOffset>0</bitOffset>
              <bitWidth>8</bitWidth>
            </field>
            <field>
              <name>DACC2DHR</name>
              <bitOffset>8</bitOffset>
              <bitWidth>8</bitWidth>
            </field>
          </fields>
        </register>
        <register>
          <name>DOR1</name>
          <addressOffset>0x2c</addressOffset>
          <size>0x20</size>
          <fields>
            <field>
              <name>DACC1DOR</name>
              <bitOffset>0</bitOffset>
              <bitWidth>12</bitWidth>
            </field>
            <field>
              <name>DACC1DORB</name>
              <bitOffset>16</bitOffset>
              <bitWidth>12</bitWidth>
            </field>
          </fields>
        </register>
        <register>
          <name>DOR2</name>
          <addressOffset>0x30</addressOffset>
          <size>0x20</size>
          <fields>
            <field>
              <name>DACC2DOR</name>
              <bitOffset>0</bitOffset>
              <bitWidth>12</bitWidth>
            </field>
            <field>
              <name>DACC2DORB</name>
              <bitOffset>16</bitOffset>
              <bitWidth>12</bitWidth>
            </field>
          </fields>
        </register>
        <register>
          <name>SR</name>
          <addressOffset>0x34</addressOffset>
          <size>0x20</size>
          <fields>
            <field>
              <name>DAC1RDY</name>
              <bitOffset>11</bitOffset>
              <bitWidth>1</bitWidth>
            </field>
            <field>
              <name>DORSTAT1</name>
              <bitOffset>12</bitOffset>
              <bitWidth>1</bitWidth>
            </field>
            <field>
              <name>DMAUDR1</name>
              <bitOffset>13</bitOffset>
              <bitWidth>1</bitWidth>
            </field>
            <field>
              <name>CAL_FLAG1</name>
              <bitOffset>14</bitOffset>
              <bitWidth>1</bitWidth>
            </field>
            <field>
              <name>BWST1</name>
              <bitOffset>15</bitOffset>
              <bitWidth>1</bitWidth>
            </field>
            <field>
              <name>DAC2RDY</name>
              <bitOffset>27</bitOffset>
              <bitWidth>1</bitWidth>
            </field>
            <field>
              <name>DORSTAT2</name>
              <bitOffset>28</bitOffset>
              <bitWidth>1</bitWidth>
            </field>
            <field>
              <name>DMAUDR2</name>
              <bitOffset>29</bitOffset>
              <bitWidth>1</bitWidth>
            </field>
            <field>
              <name>CAL_FLAG2</name>
              <bitOffset>30</bitOffset>
              <bitWidth>1</bitWidth>
            </field>
            <field>
              <name>BWST2</name>
              <bitOffset>31</bitOffset>
              <bitWidth>1</bitWidth>
            </field>
          </fields>
        </register>
        <register>
          <name>CCR</name>
          <addressOffset>0x38</addressOffset>
          <size>0x20</size>
          <fields>
            <field>
              <name>OTRIM1</name>
              <bitOffset>0</bitOffset>
              <bitWidth>5</bitWidth>
            </field>
            <field>
              <name>OTRIM2</name>
              <bitOffset>16</bitOffset>
              <bitWidth>5</bitWidth>
            </field>
          </fields>
        </register>
        <register>
          <name>MCR</name>
          <addressOffset>0x3c</addressOffset>
          <size>0x20</size>
          <fields>
            <field>
              <name>MODE1</name>
              <bitOffset>0</bitOffset>
              <bitWidth>3</bitWidth>
            </field>
            <field>
              <name>DMADOUBLE1</name>
              <bitOffset>8</bitOffset>
              <bitWidth>1</bitWidth>
            </field>
            <field>
              <name>SINFORMAT1</name>
              <bitOffset>9</bitOffset>
              <bitWidth>1</bitWidth>
            </field>
            <field>
              <name>HFSEL</name>
              <bitOffset>14</bitOffset>
              <bitWidth>2</bitWidth>
            </field>
            <field>
              <name>MODE2</name>
              <bitOffset>16</bitOffset>
              <bitWidth>3</bitWidth>
            </field>
            <field>
              <name>DMADOUBLE2</name>
              <bitOffset>24</bitOffset>
              <bitWidth>1</bitWidth>
            </field>
            <field>
              <name>SINFORMAT2</name>
              <bitOffset>25</bitOffset>
              <bitWidth>1</bitWidth>
            </field>
          </fields>
        </register>
        <register>
          <name>SHSR1</name>
          <addressOffset>0x40</addressOffset>
          <size>0x20</size>
          <fields>
            <field>
              <name>TSAMPLE1</name>
              <bitOffset>0</bitOffset>
              <bitWidth>10</bitWidth>
            </field>
          </fields>
        </register>
        <register>
          <name>SHSR2</name>
          <addressOffset>0x44</addressOffset>
          <size>0x20</size>
          <fields>
            <field>
              <name>TSAMPLE2</name>
              <bitOffset>0</bitOffset>
              <bitWidth>10</bitWidth>
            </field>
          </fields>
        </register>
        <register>
          <name>SHHR</name>
          <addressOffset>0x48</addressOffset>
          <size>0x20</size>
          <fields>
            <field>
              <name>THOLD1</name>
              <bitOffset>0</bitOffset>
              <bitWidth>10</bitWidth>
            </field>
            <field>
              <name>THOLD2</name>
              <bitOffset>16</bitOffset>
              <bitWidth>10</bitWidth>
            </field>
          </fields>
        </register>
        <register>
          <name>SHRR</name>
          <addressOffset>0x4c</addressOffset>
          <size>0x20</size>
          <fields>
            <field>
              <name>TREFRESH1</name>
              <bitOffset>0</bitOffset>
              <bitWidth>8</bitWidth>
            </field>
            <field>
              <name>TREFRESH2</name>
              <bitOffset>16</bitOffset>
              <bitWidth>8</bitWidth>
            </field>
          </fields>
        </register>
        <register>
          <name>STR1</name>
          <addressOffset>0x58</addressOffset>
          <size>0x20</size>
          <fields>
            <field>
              <name>STRSTDATA1</name>
              <bitOffset>0</bitOffset>
              <bitWidth>12</bitWidth>
            </field>
            <field>
              <name>STDIR1</name>
              <bitOffset>12</bitOffset>
              <bitWidth>1</bitWidth>
            </field>
            <field>
              <name>STINCDATA1</name>
              <bitOffset>16</bitOffset>
              <bitWidth>16</bitWidth>
            </field>
          </fields>
        </register>
        <register>
          <name>STR2</name>
          <addressOffset>0x5c</addressOffset>
          <size>0x20</size>
          <fields>
            <field>
              <name>STRSTDATA2</name>
              <bitOffset>0</bitOffset>
              <bitWidth>12</bitWidth>
            </field>
            <field>
              <name>STDIR2</name>
              <bitOffset>12</bitOffset>
              <bitWidth>1</bitWidth>
            </field>
            <field>
              <name>STINCDATA2</name>
              <bitOffset>16</bitOffset>
              <bitWidth>16</bitWidth>
            </field>
          </fields>
        </register>
        <register>
          <name>STMODR</name>
          <addressOffset>0x60</addressOffset>
          <size>0x20</size>
          <fields>
            <field>
              <name>STRSTTRIGSEL1</name>
              <bitOffset>0</bitOffset>
              <bitWidth>4</bitWidth>
            </field>
            <field>
              <name>STINCTRIGSEL1</name>
              <bitOffset>8</bitOffset>
              <bitWidth>4</bitWidth>
            </field>
            <field>
              <name>STRSTTRIGSEL2</name>
              <bitOffset>16</bitOffset>
              <bitWidth>4</bitWidth>
            </field>
            <field>
              <name>STINCTRIGSEL2</name>
              <bitOffset>24</bitOffset>
              <bitWidth>4</bitWidth>
            </field>
          </fields>
        </register>
      </registers>
    </peripheral>
    <peripheral>
      <name>DAC1</name>
      <baseAddress>0x50000800</baseAddress>
      <registers>
        <register>
          <name>CR</name>
          <addressOffset>0x0</addressOffset>
          <size>0x20</size>
          <fields>
            <field>
              <name>EN1</name>
              <bitOffset>0</bitOffset>
              <bitWidth>1</bitWidth>
            </field>
            <field>
              <name>TEN1</name>
              <bitOffset>1</bitOffset>
              <bitWidth>1</bitWidth>
            </field>
            <field>
              <name>TSEL1</name>
              <bitOffset>2</bitOffset>
              <bitWidth>4</bitWidth>
            </field>
            <field>
              <name>WAVE1</name>
              <bitOffset>6</bitOffset>
              <bitWidth>2</bitWidth>
            </field>
            <field>
              <name>MAMP1</name>
              <bitOffset>8</bitOffset>
              <bitWidth>4</bitWidth>
            </field>
            <field>
              <name>DMAEN1</name>
              <bitOffset>12</bitOffset>
              <bitWidth>1</bitWidth>
            </field>
            <field>
              <name>DMAUDRIE1</name>
              <bitOffset>13</bitOffset>
              <bitWidth>1</bitWidth>
            </field>
            <field>
              <name>CEN1</name>
              <bitOffset>14</bitOffset>
              <bitWidth>1</bitWidth>
            </field>
            <field>
              <name>HFSEL</name>
              <bitOffset>15</bitOffset>
              <bitWidth>1</bitWidth>
            </field>
            <field>
              <name>EN2</name>
              <bitOffset>16</bitOffset>
              <bitWidth>1</bitWidth>
            </field>
            <field>
              <name>TEN2</name>
              <bitOffset>17</bitOffset>
              <bitWidth>1</bitWidth>
            </field>
            <field>
              <name>TSEL2</name>
              <bitOffset>18</bitOffset>
              <bitWidth>4</bitWidth>
            </field>
            <field>
              <name>WAVE2</name>
              <bitOffset>22</bitOffset>
              <bitWidth>2</bitWidth>
            </field>
            <field>
              <name>MAMP2</name>
              <bitOffset>24</bitOffset>
              <bitWidth>4</bitWidth>
            </field>
            <field>
              <name>DMAEN2</name>
              <bitOffset>28</bitOffset>
              <bitWidth>1</bitWidth>
            </field>
            <field>
              <name>DMAUDRIE2</name>
              <bitOffset>29</bitOffset>
              <bitWidth>1</bitWidth>
            </field>
            <field>
              <name>CEN2</name>
              <bitOffset>30</bitOffset>
              <bitWidth>1</bitWidth>
            </field>
          </fields>
        </register>
        <register>
          <name>SWTRIGR</name>
          <addressOffset>0x4</addressOffset>
          <size>0x20</size>
          <fields>
            <field>
              <name>SWTRIG1</name>
              <bitOffset>0</bitOffset>
              <bitWidth>1</bitWidth>
            </field>
            <field>
              <name>SWTRIG2</name>
              <bitOffset>1</bitOffset>
              <bitWidth>1</bitWidth>
            </field>
            <field>
              <name>SWTRIGB1</name>
              <bitOffset>16</bitOffset>
              <bitWidth>1</bitWidth>
            </field>
            <field>
              <name>SWTRIGB2</name>
              <bitOffset>17</bitOffset>
              <bitWidth>1</bitWidth>
            </field>
          </fields>
        </register>
        <register>
          <name>DHR12R1</name>
          <addressOffset>0x8</addressOffset>
          <size>0x20</size>
          <fields>
            <field>
              <name>DACC1DHR</name>
              <bitOffset>0</bitOffset>
              <bitWidth>12</bitWidth>
            </field>
            <field>
              <name>DACC1DHRB</name>
              <bitOffset>16</bitOffset>
              <bitWidth>12</bitWidth>
            </field>
          </fields>
        </register>
        <register>
          <name>DHR12L1</name>
          <addressOffset>0xc</addressOffset>
          <size>0x20</size>
          <fields>
            <field>
              <name>DACC1DHR</name>
              <bitOffset>4</bitOffset>
              <bitWidth>12</bitWidth>
            </field>
            <field>
              <name>DACC1DHRB</name>
              <bitOffset>20</bitOffset>
              <bitWidth>12</bitWidth>
            </field>
          </fields>
        </register>
        <register>
          <name>DHR8R1</name>
          <addressOffset>0x10</addressOffset>
          <size>0x20</size>
          <fields>
            <field>
              <name>DACC1DHR</name>
              <bitOffset>0</bitOffset>
              <bitWidth>8</bitWidth>
            </field>
            <field>
              <name>DACC1DHRB</name>
              <bitOffset>8</bitOffset>
              <bitWidth>8</bitWidth>
            </field>
          </fields>
        </register>
        <register>
          <name>DHR12R2</name>
          <addressOffset>0x14</addressOffset>
          <size>0x20</size>
          <fields>
            <field>
              <name>DACC2DHR</name>
              <bitOffset>0</bitOffset>
              <bitWidth>12</bitWidth>
            </field>
            <field>
              <name>DACC2DHRB</name>
              <bitOffset>16</bitOffset>
              <bitWidth>12</bitWidth>
            </field>
          </fields>
        </register>
        <register>
          <name>DHR12L2</name>
          <addressOffset>0x18</addressOffset>
          <size>0x20</size>
          <fields>
            <field>
              <name>DACC2DHR</name>
              <bitOffset>4</bitOffset>
              <bitWidth>12</bitWidth>
            </field>
            <field>
              <name>DACC2DHRB</name>
              <bitOffset>20</bitOffset>
              <bitWidth>12</bitWidth>
            </field>
          </fields>
        </register>
        <register>
          <name>DHR8R2</name>
          <addressOffset>0x1c</addressOffset>
          <size>0x20</size>
          <fields>
            <field>
              <name>DACC2DHR</name>
              <bitOffset>0</bitOffset>
              <bitWidth>8</bitWidth>
            </field>
            <field>
              <name>DACC2DHRB</name>
              <bitOffset>8</bitOffset>
              <bitWidth>8</bitWidth>
            </field>
          </fields>
        </register>
        <register>
          <name>DHR12RD</name>
          <addressOffset>0x20</addressOffset>
          <size>0x20</size>
          <fields>
            <field>
              <name>DACC1DHR</name>
              <bitOffset>0</bitOffset>
              <bitWidth>12</bitWidth>
            </field>
            <field>
              <name>DACC2DHR</name>
              <bitOffset>16</bitOffset>
              <bitWidth>12</bitWidth>
            </field>
          </fields>
        </register>
        <register>
          <name>DHR12LD</name>
          <addressOffset>0x24</addressOffset>
          <size>0x20</size>
          <fields>
            <field>
              <name>DACC1DHR</name>
              <bitOffset>4</bitOffset>
              <bitWidth>12</bitWidth>
            </field>
            <field>
              <name>DACC2DHR</name>
              <bitOffset>20</bitOffset>
              <bitWidth>12</bitWidth>
            </field>
          </fields>
        </register>
        <register>
          <name>DHR8RD</name>
          <addressOffset>0x28</addressOffset>
          <size>0x20</size>
          <fields>
            <field>
              <name>DACC1DHR</name>
              <bitOffset>0</bitOffset>
              <bitWidth>8</bitWidth>
            </field>
            <field>
              <name>DACC2DHR</name>
              <bitOffset>8</bitOffset>
              <bitWidth>8</bitWidth>
            </field>
          </fields>
        </register>
        <register>
          <name>DOR1</name>
          <addressOffset>0x2c</addressOffset>
          <size>0x20</size>
          <fields>
            <field>
              <name>DACC1DOR</name>
              <bitOffset>0</bitOffset>
              <bitWidth>12</bitWidth>
            </field>
            <field>
              <name>DACC1DORB</name>
              <bitOffset>16</bitOffset>
              <bitWidth>12</bitWidth>
            </field>
          </fields>
        </register>
        <register>
          <name>DOR2</name>
          <addressOffset>0x30</addressOffset>
          <size>0x20</size>
          <fields>
            <field>
              <name>DACC2DOR</name>
              <bitOffset>0</bitOffset>
              <bitWidth>12</bitWidth>
            </field>
            <field>
              <name>DACC2DORB</name>
              <bitOffset>16</bitOffset>
              <bitWidth>12</bitWidth>
            </field>
          </fields>
        </register>
        <register>
          <name>SR</name>
          <addressOffset>0x34</addressOffset>
          <size>0x20</size>
          <fields>
            <field>
              <name>DAC1RDY</name>
              <bitOffset>11</bitOffset>
              <bitWidth>1</bitWidth>
            </field>
            <field>
              <name>DORSTAT1</name>
              <bitOffset>12</bitOffset>
              <bitWidth>1</bitWidth>
            </field>
            <field>
              <name>DMAUDR1</name>
              <bitOffset>13</bitOffset>
              <bitWidth>1</bitWidth>
            </field>
            <field>
              <name>CAL_FLAG1</name>
              <bitOffset>14</bitOffset>
              <bitWidth>1</bitWidth>
            </field>
            <field>
              <name>BWST1</name>
              <bitOffset>15</bitOffset>
              <bitWidth>1</bitWidth>
            </field>
            <field>
              <name>DAC2RDY</name>
              <bitOffset>27</bitOffset>
              <bitWidth>1</bitWidth>
            </field>
            <field>
              <name>DORSTAT2</name>
              <bitOffset>28</bitOffset>
              <bitWidth>1</bitWidth>
            </field>
            <field>
              <name>DMAUDR2</name>
              <bitOffset>29</bitOffset>
              <bitWidth>1</bitWidth>
            </field>
            <field>
              <name>CAL_FLAG2</name>
              <bitOffset>30</bitOffset>
              <bitWidth>1</bitWidth>
            </field>
            <field>
              <name>BWST2</name>
              <bitOffset>31</bitOffset>
              <bitWidth>1</bitWidth>
            </field>
          </fields>
        </register>
        <register>
          <name>CCR</name>
          <addressOffset>0x38</addressOffset>
          <size>0x20</size>
          <fields>
            <field>
              <name>OTRIM1</name>
              <bitOffset>0</bitOffset>
              <bitWidth>5</bitWidth>
            </field>
            <field>
              <name>OTRIM2</name>
              <bitOffset>16</bitOffset>
              <bitWidth>5</bitWidth>
            </field>
          </fields>
        </register>
        <register>
          <name>MCR</name>
          <addressOffset>0x3c</addressOffset>
          <size>0x20</size>
          <fields>
            <field>
              <name>MODE1</name>
              <bitOffset>0</bitOffset>
              <bitWidth>3</bitWidth>
            </field>
            <field>
              <name>DMADOUBLE1</name>
              <bitOffset>8</bitOffset>
              <bitWidth>1</bitWidth>
            </field>
            <field>
              <name>SINFORMAT1</name>
              <bitOffset>9</bitOffset>
              <bitWidth>1</bitWidth>
            </field>
            <field>
              <name>HFSEL</name>
              <bitOffset>14</bitOffset>
              <bitWidth>2</bitWidth>
            </field>
            <field>
              <name>MODE2</name>
              <bitOffset>16</bitOffset>
              <bitWidth>3</bitWidth>
            </field>
            <field>
              <name>DMADOUBLE2</name>
              <bitOffset>24</bitOffset>
              <bitWidth>1</bitWidth>
            </field>
            <field>
              <name>SINFORMAT2</name>
              <bitOffset>25</bitOffset>
              <bitWidth>1</bitWidth>
            </field>
          </fields>
        </register>
        <register>
          <name>SHSR1</name>
          <addressOffset>0x40</addressOffset>
          <size>0x20</size>
          <fields>
            <field>
              <name>TSAMPLE1</name>
              <bitOffset>0</bitOffset>
              <bitWidth>10</bitWidth>
            </field>
          </fields>
        </register>
        <register>
          <name>SHSR2</name>
          <addressOffset>0x44</addressOffset>
          <size>0x20</size>
          <fields>
            <field>
              <name>TSAMPLE2</name>
              <bitOffset>0</bitOffset>
              <bitWidth>10</bitWidth>
            </field>
          </fields>
        </register>
        <register>
          <name>SHHR</name>
          <addressOffset>0x48</addressOffset>
          <size>0x20</size>
          <fields>
            <field>
              <name>THOLD1</name>
              <bitOffset>0</bitOffset>
              <bitWidth>10</bitWidth>
            </field>
            <field>
              <name>THOLD2</name>
              <bitOffset>16</bitOffset>
              <bitWidth>10</bitWidth>
            </field>
          </fields>
        </register>
        <register>
          <name>SHRR</name>
          <addressOffset>0x4c</addressOffset>
          <size>0x20</size>
          <fields>
            <field>
              <name>TREFRESH1</name>
              <bitOffset>0</bitOffset>
              <bitWidth>8</bitWidth>
            </field>
            <field>
              <name>TREFRESH2</name>
              <bitOffset>16</bitOffset>
              <bitWidth>8</bitWidth>
            </field>
          </fields>
        </register>
        <register>
          <name>STR1</name>
          <addressOffset>0x58</addressOffset>
          <size>0x20</size>
          <fields>
            <field>
              <name>STRSTDATA1</name>
              <bitOffset>0</bitOffset>
              <bitWidth>12</bitWidth>
            </field>
            <field>
              <name>STDIR1</name>
              <bitOffset>12</bitOffset>
              <bitWidth>1</bitWidth>
            </field>
            <field>
              <name>STINCDATA1</name>
              <bitOffset>16</bitOffset>
              <bitWidth>16</bitWidth>
            </field>
          </fields>
        </register>
        <register>
          <name>STR2</name>
          <addressOffset>0x5c</addressOffset>
          <size>0x20</size>
          <fields>
            <field>
              <name>STRSTDATA2</name>
              <bitOffset>0</bitOffset>
              <bitWidth>12</bitWidth>
            </field>
            <field>
              <name>STDIR2</name>
              <bitOffset>12</bitOffset>
              <bitWidth>1</bitWidth>
            </field>
            <field>
              <name>STINCDATA2</name>
              <bitOffset>16</bitOffset>
              <bitWidth>16</bitWidth>
            </field>
          </fields>
        </register>
        <register>
          <name>STMODR</name>
          <addressOffset>0x60</addressOffset>
          <size>0x20</size>
          <fields>
            <field>
              <name>STRSTTRIGSEL1</name>
              <bitOffset>0</bitOffset>
              <bitWidth>4</bitWidth>
            </field>
            <field>
              <name>STINCTRIGSEL1</name>
              <bitOffset>8</bitOffset>
              <bitWidth>4</bitWidth>
            </field>
            <field>
              <name>STRSTTRIGSEL2</name>
              <bitOffset>16</bitOffset>
              <bitWidth>4</bitWidth>
            </field>
            <field>
              <name>STINCTRIGSEL2</name>
              <bitOffset>24</bitOffset>
              <bitWidth>4</bitWidth>
            </field>
          </fields>
        </register>
      </registers>
    </peripheral>
    <peripheral>
      <name>DAC3</name>
      <baseAddress>0x50001000</baseAddress>
      <registers>
        <register>
          <name>CR</name>
          <addressOffset>0x0</addressOffset>
          <size>0x20</size>
          <fields>
            <field>
              <name>EN1</name>
              <bitOffset>0</bitOffset>
              <bitWidth>1</bitWidth>
            </field>
            <field>
              <name>TEN1</name>
              <bitOffset>1</bitOffset>
              <bitWidth>1</bitWidth>
            </field>
            <field>
              <name>TSEL1</name>
              <bitOffset>2</bitOffset>
              <bitWidth>4</bitWidth>
            </field>
            <field>
              <name>WAVE1</name>
              <bitOffset>6</bitOffset>
              <bitWidth>2</bitWidth>
            </field>
            <field>
              <name>MAMP1</name>
              <bitOffset>8</bitOffset>
              <bitWidth>4</bitWidth>
            </field>
            <field>
              <name>DMAEN1</name>
              <bitOffset>12</bitOffset>
              <bitWidth>1</bitWidth>
            </field>
            <field>
              <name>DMAUDRIE1</name>
              <bitOffset>13</bitOffset>
              <bitWidth>1</bitWidth>
            </field>
            <field>
              <name>CEN1</name>
              <bitOffset>14</bitOffset>
              <bitWidth>1</bitWidth>
            </field>
            <field>
              <name>HFSEL</name>
              <bitOffset>15</bitOffset>
              <bitWidth>1</bitWidth>
            </field>
            <field>
              <name>EN2</name>
              <bitOffset>16</bitOffset>
              <bitWidth>1</bitWidth>
            </field>
            <field>
              <name>TEN2</name>
              <bitOffset>17</bitOffset>
              <bitWidth>1</bitWidth>
            </field>
            <field>
              <name>TSEL2</name>
              <bitOffset>18</bitOffset>
              <bitWidth>4</bitWidth>
            </field>
            <field>
              <name>WAVE2</name>
              <bitOffset>22</bitOffset>
              <bitWidth>2</bitWidth>
            </field>
            <field>
              <name>MAMP2</name>
              <bitOffset>24</bitOffset>
              <bitWidth>4</bitWidth>
            </field>
            <field>
              <name>DMAEN2</name>
              <bitOffset>28</bitOffset>
              <bitWidth>1</bitWidth>
            </field>
            <field>
              <name>DMAUDRIE2</name>
              <bitOffset>29</bitOffset>
              <bitWidth>1</bitWidth>
            </field>
            <field>
              <name>CEN2</name>
              <bitOffset>30</bitOffset>
              <bitWidth>1</bitWidth>
            </field>
          </fields>
        </register>
        <register>
          <name>SWTRIGR</name>
          <addressOffset>0x4</addressOffset>
          <size>0x20</size>
          <fields>
            <field>
              <name>SWTRIG1</name>
              <bitOffset>0</bitOffset>
              <bitWidth>1</bitWidth>
            </field>
            <field>
              <name>SWTRIG2</name>
              <bitOffset>1</bitOffset>
              <bitWidth>1</bitWidth>
            </field>
            <field>
              <name>SWTRIGB1</name>
              <bitOffset>16</bitOffset>
              <bitWidth>1</bitWidth>
            </field>
            <field>
              <name>SWTRIGB2</name>
              <bitOffset>17</bitOffset>
              <bitWidth>1</bitWidth>
            </field>
          </fields>
        </register>
        <register>
          <name>DHR12R1</name>
          <addressOffset>0x8</addressOffset>
          <size>0x20</size>
          <fields>
            <field>
              <name>DACC1DHR</name>
              <bitOffset>0</bitOffset>
              <bitWidth>12</bitWidth>
            </field>
            <field>
              <name>DACC1DHRB</name>
              <bitOffset>16</bitOffset>
              <bitWidth>12</bitWidth>
            </field>
          </fields>
        </register>
        <register>
          <name>DHR12L1</name>
          <addressOffset>0xc</addressOffset>
          <size>0x20</size>
          <fields>
            <field>
              <name>DACC1DHR</name>
              <bitOffset>4</bitOffset>
              <bitWidth>12</bitWidth>
            </field>
            <field>
              <name>DACC1DHRB</name>
              <bitOffset>20</bitOffset>
              <bitWidth>12</bitWidth>
            </field>
          </fields>
        </register>
        <register>
          <name>DHR8R1</name>
          <addressOffset>0x10</addressOffset>
          <size>0x20</size>
          <fields>
            <field>
              <name>DACC1DHR</name>
              <bitOffset>0</bitOffset>
              <bitWidth>8</bitWidth>
            </field>
            <field>
              <name>DACC1DHRB</name>
              <bitOffset>8</bitOffset>
              <bitWidth>8</bitWidth>
            </field>
          </fields>
        </register>
        <register>
          <name>DHR12R2</name>
          <addressOffset>0x14</addressOffset>
          <size>0x20</size>
          <fields>
            <field>
              <name>DACC2DHR</name>
              <bitOffset>0</bitOffset>
              <bitWidth>12</bitWidth>
            </field>
            <field>
              <name>DACC2DHRB</name>
              <bitOffset>16</bitOffset>
              <bitWidth>12</bitWidth>
            </field>
          </fields>
        </register>
        <register>
          <name>DHR12L2</name>
          <addressOffset>0x18</addressOffset>
          <size>0x20</size>
          <fields>
            <field>
              <name>DACC2DHR</name>
              <bitOffset>4</bitOffset>
              <bitWidth>12</bitWidth>
            </field>
            <field>
              <name>DACC2DHRB</name>
              <bitOffset>20</bitOffset>
              <bitWidth>12</bitWidth>
            </field>
          </fields>
        </register>
        <register>
          <name>DHR8R2</name>
          <addressOffset>0x1c</addressOffset>
          <size>0x20</size>
          <fields>
            <field>
              <name>DACC2DHR</name>
              <bitOffset>0</bitOffset>
              <bitWidth>8</bitWidth>
            </field>
            <field>
              <name>DACC2DHRB</name>
              <bitOffset>8</bitOffset>
              <bitWidth>8</bitWidth>
            </field>
          </fields>
        </register>
        <register>
          <name>DHR12RD</name>
          <addressOffset>0x20</addressOffset>
          <size>0x20</size>
          <fields>
            <field>
              <name>DACC1DHR</name>
              <bitOffset>0</bitOffset>
              <bitWidth>12</bitWidth>
            </field>
            <field>
              <name>DACC2DHR</name>
              <bitOffset>16</bitOffset>
              <bitWidth>12</bitWidth>
            </field>
          </fields>
        </register>
        <register>
          <name>DHR12LD</name>
          <addressOffset>0x24</addressOffset>
          <size>0x20</size>
          <fields>
            <field>
              <name>DACC1DHR</name>
              <bitOffset>4</bitOffset>
              <bitWidth>12</bitWidth>
            </field>
            <field>
              <name>DACC2DHR</name>
              <bitOffset>20</bitOffset>
              <bitWidth>12</bitWidth>
            </field>
          </fields>
        </register>
        <register>
          <name>DHR8RD</name>
          <addressOffset>0x28</addressOffset>
          <size>0x20</size>
          <fields>
            <field>
              <name>DACC1DHR</name>
              <bitOffset>0</bitOffset>
              <bitWidth>8</bitWidth>
            </field>
            <field>
              <name>DACC2DHR</name>
              <bitOffset>8</bitOffset>
              <bitWidth>8</bitWidth>
            </field>
          </fields>
        </register>
        <register>
          <name>DOR1</name>
          <addressOffset>0x2c</addressOffset>
          <size>0x20</size>
          <fields>
            <field>
              <name>DACC1DOR</name>
              <bitOffset>0</bitOffset>
              <bitWidth>12</bitWidth>
            </field>
            <field>
              <name>DACC1DORB</name>
              <bitOffset>16</bitOffset>
              <bitWidth>12</bitWidth>
            </field>
          </fields>
        </register>
        <register>
          <name>DOR2</name>
          <addressOffset>0x30</addressOffset>
          <size>0x20</size>
          <fields>
            <field>
              <name>DACC2DOR</name>
              <bitOffset>0</bitOffset>
              <bitWidth>12</bitWidth>
            </field>
            <field>
              <name>DACC2DORB</name>
              <bitOffset>16</bitOffset>
              <bitWidth>12</bitWidth>
            </field>
          </fields>
        </register>
        <register>
          <name>SR</name>
          <addressOffset>0x34</addressOffset>
          <size>0x20</size>
          <fields>
            <field>
              <name>DAC1RDY</name>
              <bitOffset>11</bitOffset>
              <bitWidth>1</bitWidth>
            </field>
            <field>
              <name>DORSTAT1</name>
              <bitOffset>12</bitOffset>
              <bitWidth>1</bitWidth>
            </field>
            <field>
              <name>DMAUDR1</name>
              <bitOffset>13</bitOffset>
              <bitWidth>1</bitWidth>
            </field>
            <field>
              <name>CAL_FLAG1</name>
              <bitOffset>14</bitOffset>
              <bitWidth>1</bitWidth>
            </field>
            <field>
              <name>BWST1</name>
              <bitOffset>15</bitOffset>
              <bitWidth>1</bitWidth>
            </field>
            <field>
              <name>DAC2RDY</name>
              <bitOffset>27</bitOffset>
              <bitWidth>1</bitWidth>
            </field>
            <field>
              <name>DORSTAT2</name>
              <bitOffset>28</bitOffset>
              <bitWidth>1</bitWidth>
            </field>
            <field>
              <name>DMAUDR2</name>
              <bitOffset>29</bitOffset>
              <bitWidth>1</bitWidth>
            </field>
            <field>
              <name>CAL_FLAG2</name>
              <bitOffset>30</bitOffset>
              <bitWidth>1</bitWidth>
            </field>
            <field>
              <name>BWST2</name>
              <bitOffset>31</bitOffset>
              <bitWidth>1</bitWidth>
            </field>
          </fields>
        </register>
        <register>
          <name>CCR</name>
          <addressOffset>0x38</addressOffset>
          <size>0x20</size>
          <fields>
            <field>
              <name>OTRIM1</name>
              <bitOffset>0</bitOffset>
              <bitWidth>5</bitWidth>
            </field>
            <field>
              <name>OTRIM2</name>
              <bitOffset>16</bitOffset>
              <bitWidth>5</bitWidth>
            </field>
          </fields>
        </register>
        <register>
          <name>MCR</name>
          <addressOffset>0x3c</addressOffset>
          <size>0x20</size>
          <fields>
            <field>
              <name>MODE1</name>
              <bitOffset>0</bitOffset>
              <bitWidth>3</bitWidth>
            </field>
            <field>
              <name>DMADOUBLE1</name>
              <bitOffset>8</bitOffset>
              <bitWidth>1</bitWidth>
            </field>
            <field>
              <name>SINFORMAT1</name>
              <bitOffset>9</bitOffset>
              <bitWidth>1</bitWidth>
            </field>
            <field>
              <name>HFSEL</name>
              <bitOffset>14</bitOffset>
              <bitWidth>2</bitWidth>
            </field>
            <field>
              <name>MODE2</name>
              <bitOffset>16</bitOffset>
              <bitWidth>3</bitWidth>
            </field>
            <field>
              <name>DMADOUBLE2</name>
              <bitOffset>24</bitOffset>
              <bitWidth>1</bitWidth>
            </field>
            <field>
              <name>SINFORMAT2</name>
              <bitOffset>25</bitOffset>
              <bitWidth>1</bitWidth>
            </field>
          </fields>
        </register>
        <register>
          <name>SHSR1</name>
          <addressOffset>0x40</addressOffset>
          <size>0x20</size>
          <fields>
            <field>
              <name>TSAMPLE1</name>
              <bitOffset>0</bitOffset>
              <bitWidth>10</bitWidth>
            </field>
          </fields>
        </register>
        <register>
          <name>SHSR2</name>
          <addressOffset>0x44</addressOffset>
          <size>0x20</size>
          <fields>
            <field>
              <name>TSAMPLE2</name>
              <bitOffset>0</bitOffset>
              <bitWidth>10</bitWidth>
            </field>
          </fields>
        </register>
        <register>
          <name>SHHR</name>
          <addressOffset>0x48</addressOffset>
          <size>0x20</size>
          <fields>
            <field>
              <name>THOLD1</name>
              <bitOffset>0</bitOffset>
              <bitWidth>10</bitWidth>
            </field>
            <field>
              <name>THOLD2</name>
              <bitOffset>16</bitOffset>
              <bitWidth>10</bitWidth>
            </field>
          </fields>
        </register>
        <register>
          <name>SHRR</name>
          <addressOffset>0x4c</addressOffset>
          <size>0x20</size>
          <fields>
            <field>
              <name>TREFRESH1</name>
              <bitOffset>0</bitOffset>
              <bitWidth>8</bitWidth>
            </field>
            <field>
              <name>TREFRESH2</name>
              <bitOffset>16</bitOffset>
              <bitWidth>8</bitWidth>
            </field>
          </fields>
        </register>
        <register>
          <name>STR1</name>
          <addressOffset>0x58</addressOffset>
          <size>0x20</size>
          <fields>
            <field>
              <name>STRSTDATA1</name>
              <bitOffset>0</bitOffset>
              <bitWidth>12</bitWidth>
            </field>
            <field>
              <name>STDIR1</name>
              <bitOffset>12</bitOffset>
              <bitWidth>1</bitWidth>
            </field>
            <field>
              <name>STINCDATA1</name>
              <bitOffset>16</bitOffset>
              <bitWidth>16</bitWidth>
            </field>
          </fields>
        </register>
        <register>
          <name>STR2</name>
          <addressOffset>0x5c</addressOffset>
          <size>0x20</size>
          <fields>
            <field>
              <name>STRSTDATA2</name>
              <bitOffset>0</bitOffset>
              <bitWidth>12</bitWidth>
            </field>
            <field>
              <name>STDIR2</name>
              <bitOffset>12</bitOffset>
              <bitWidth>1</bitWidth>
            </field>
            <field>
              <name>STINCDATA2</name>
              <bitOffset>16</bitOffset>
              <bitWidth>16</bitWidth>
            </field>
          </fields>
        </register>
        <register>
          <name>STMODR</name>
          <addressOffset>0x60</addressOffset>
          <size>0x20</size>
          <fields>
            <field>
              <name>STRSTTRIGSEL1</name>
              <bitOffset>0</bitOffset>
              <bitWidth>4</bitWidth>
            </field>
            <field>
              <name>STINCTRIGSEL1</name>
              <bitOffset>8</bitOffset>
              <bitWidth>4</bitWidth>
            </field>
            <field>
              <name>STRSTTRIGSEL2</name>
              <bitOffset>16</bitOffset>
              <bitWidth>4</bitWidth>
            </field>
            <field>
              <name>STINCTRIGSEL2</name>
              <bitOffset>24</bitOffset>
              <bitWidth>4</bitWidth>
            </field>
          </fields>
        </register>
      </registers>
    </peripheral>
    <peripheral>
      <name>RNG</name>
      <baseAddress>0x50060800</baseAddress>
      <registers>
        <register>
          <name>CR</name>
          <addressOffset>0x0</addressOffset>
          <size>0x20</size>
          <fields>
            <field>
              <name>RNGEN</name>
              <bitOffset>2</bitOffset>
              <bitWidth>1</bitWidth>
            </field>
            <field>
              <name>IE</name>
              <bitOffset>3</bitOffset>
              <bitWidth>1</bitWidth>
            </field>
            <field>
              <name>CED</name>
              <bitOffset>5</bitOffset>
              <bitWidth>1</bitWidth>
            </field>
          </fields>
        </register>
        <register>
          <name>SR</name>
          <addressOffset>0x4</addressOffset>
          <size>0x20</size>
          <fields>
            <field>
              <name>DRDY</name>
              <bitOffset>0</bitOffset>
              <bitWidth>1</bitWidth>
            </field>
            <field>
              <name>CECS</name>
              <bitOffset>1</bitOffset>
              <bitWidth>1</bitWidth>
            </field>
            <field>
              <name>SECS</name>
              <bitOffset>2</bitOffset>
              <bitWidth>1</bitWidth>
            </field>
            <field>
              <name>CEIS</name>
              <bitOffset>5</bitOffset>
              <bitWidth>1</bitWidth>
            </field>
            <field>
              <name>SEIS</name>
              <bitOffset>6</bitOffset>
              <bitWidth>1</bitWidth>
            </field>
          </fields>
        </register>
        <register>
          <name>DR</name>
          <addressOffset>0x8</addressOffset>
          <size>0x20</size>
        </register>
      </registers>
    </peripheral>
    <peripheral>
      <name>QUADSPI</name>
      <baseAddress>0xa0001000</baseAddress>
      <registers>
        <register>
          <name>CR</name>
          <addressOffset>0x0</addressOffset>
          <size>0x20</size>
          <fields>
            <field>
              <name>EN</name>
              <bitOffset>0</bitOffset>
              <bitWidth>1</bitWidth>
            </field>
            <field>
              <name>ABORT</name>
              <bitOffset>1</bitOffset>
              <bitWidth>1</bitWidth>
            </field>
            <field>
              <name>DMAEN</name>
              <bitOffset>2</bitOffset>
              <bitWidth>1</bitWidth>
            </field>
            <field>
              <name>TCEN</name>
              <bitOffset>3</bitOffset>
              <bitWidth>1</bitWidth>
            </field>
            <field>
              <name>SSHIFT</name>
              <bitOffset>4</bitOffset>
              <bitWidth>1</bitWidth>
            </field>
            <field>
              <name>DFM</name>
              <bitOffset>6</bitOffset>
              <bitWidth>1</bitWidth>
            </field>
            <field>
              <name>FSEL</name>
              <bitOffset>7</bitOffset>
              <bitWidth>1</bitWidth>
            </field>
            <field>
              <name>FTHRES</name>
              <bitOffset>8</bitOffset>
              <bitWidth>4</bitWidth>
            </field>
            <field>
              <name>TEIE</name>
              <bitOffset>16</bitOffset>
              <bitWidth>1</bitWidth>
            </field>
            <field>
              <name>TCIE</name>
              <bitOffset>17</bitOffset>
              <bitWidth>1</bitWidth>
            </field>
            <field>
              <name>FTIE</name>
              <bitOffset>18</bitOffset>
              <bitWidth>1</bitWidth>
            </field>
            <field>
              <name>SMIE</name>
              <bitOffset>19</bitOffset>
              <bitWidth>1</bitWidth>
            </field>
            <field>
              <name>TOIE</name>
              <bitOffset>20</bitOffset>
              <bitWidth>1</bitWidth>
            </field>
            <field>
              <name>APMS</name>
              <bitOffset>22</bitOffset>
              <bitWidth>1</bitWidth>
            </field>
            <field>
              <name>PMM</name>
              <bitOffset>23</bitOffset>
              <bitWidth>1</bitWidth>
            </field>
            <field>
              <name>PRESCALER</name>
              <bitOffset>24</bitOffset>
              <bitWidth>8</bitWidth>
            </field>
          </fields>
        </register>
        <register>
          <name>DCR</name>
          <addressOffset>0x4</addressOffset>
          <size>0x20</size>
          <fields>
            <field>
              <name>CKMODE</name>
              <bitOffset>0</bitOffset>
              <bitWidth>1</bitWidth>
            </field>
            <field>
              <name>CSHT</name>
              <bitOffset>8</bitOffset>
              <bitWidth>3</bitWidth>
            </field>
            <field>
              <name>FSIZE</name>
              <bitOffset>16</bitOffset>
              <bitWidth>5</bitWidth>
            </field>
          </fields>
        </register>
        <register>
          <name>SR</name>
          <addressOffset>0x8</addressOffset>
          <size>0x20</size>
          <fields>
            <field>
              <name>TEF</name>
              <bitOffset>0</bitOffset>
              <bitWidth>1</bitWidth>
            </field>
            <field>
              <name>TCF</name>
              <bitOffset>1</bitOffset>
              <bitWidth>1</bitWidth>
            </field>
            <field>
              <name>FTF</name>
              <bitOffset>2</bitOffset>
              <bitWidth>1</bitWidth>
            </field>
            <field>
              <name>SMF</name>
              <bitOffset>3</bitOffset>
              <bitWidth>1</bitWidth>
            </field>
            <field>
              <name>TOF</name>
              <bitOffset>4</bitOffset>
              <bitWidth>1</bitWidth>
            </field>
            <field>
              <name>BUSY</name>
              <bitOffset>5</bitOffset>
              <bitWidth>1</bitWidth>
            </field>
            <field>
              <name>FLEVEL</name>
              <bitOffset>8</bitOffset>
              <bitWidth>5</bitWidth>
            </field>
          </fields>
        </register>
        <register>
          <name>FCR</name>
          <addressOffset>0xc</addressOffset>
          <size>0x20</size>
          <fields>
            <field>
              <name>CTEF</name>
              <bitOffset>0</bitOffset>
              <bitWidth>1</bitWidth>
            </field>
            <field>
              <name>CTCF</name>
              <bitOffset>1</bitOffset>
              <bitWidth>1</bitWidth>
            </field>
            <field>
              <name>CSMF</name>
              <bitOffset>3</bitOffset>
              <bitWidth>1</bitWidth>
            </field>
            <field>
              <name>CTOF</name>
              <bitOffset>4</bitOffset>
              <bitWidth>1</bitWidth>
            </field>
          </fields>
        </register>
        <register>
          <name>DLR</name>
          <addressOffset>0x10</addressOffset>
          <size>0x20</size>
          <fields>
            <field>
              <name>DL</name>
              <bitOffset>0</bitOffset>
              <bitWidth>32</bitWidth>
            </field>
          </fields>
        </register>
        <register>
          <name>CCR</name>
          <addressOffset>0x14</addressOffset>
          <size>0x20</size>
          <fields>
            <field>
              <name>INSTRUCTION</name>
              <bitOffset>0</bitOffset>
              <bitWidth>8</bitWidth>
            </field>
            <field>
              <name>IMODE</name>
              <bitOffset>8</bitOffset>
              <bitWidth>2</bitWidth>
            </field>
            <field>
              <name>ADMODE</name>
              <bitOffset>10</bitOffset>
              <bitWidth>2</bitWidth>
            </field>
            <field>
              <name>ADSIZE</name>
              <bitOffset>12</bitOffset>
              <bitWidth>2</bitWidth>
            </field>
            <field>
              <name>ABMODE</name>
              <bitOffset>14</bitOffset>
              <bitWidth>2</bitWidth>
            </field>
            <field>
              <name>ABSIZE</name>
              <bitOffset>16</bitOffset>
              <bitWidth>2</bitWidth>
            </field>
            <field>
              <name>DCYC</name>
              <bitOffset>18</bitOffset>
              <bitWidth>5</bitWidth>
            </field>
            <field>
              <name>DMODE</name>
              <bitOffset>24</bitOffset>
              <bitWidth>2</bitWidth>
            </field>
            <field>
              <name>FMODE</name>
              <bitOffset>26</bitOffset>
              <bitWidth>2</bitWidth>
            </field>
            <field>
              <name>SIOO</name>
              <bitOffset>28</bitOffset>
              <bitWidth>1</bitWidth>
            </field>
            <field>
              <name>DHHC</name>
              <bitOffset>30</bitOffset>
              <bitWidth>1</bitWidth>
            </field>
            <field>
              <name>DDRM</name>
              <bitOffset>31</bitOffset>
              <bitWidth>1</bitWidth>
            </field>
          </fields>
        </register>
        <register>
          <name>AR</name>
          <addressOffset>0x18</addressOffset>
          <size>0x20</size>
          <fields>
            <field>
              <name>ADDRESS</name>
              <bitOffset>0</bitOffset>
              <bitWidth>32</bitWidth>
            </field>
          </fields>
        </register>
        <register>
          <name>ABR</name>
          <addressOffset>0x1c</addressOffset>
          <size>0x20</size>
          <fields>
            <field>
              <name>ALTERNATE</name>
              <bitOffset>0</bitOffset>
              <bitWidth>32</bitWidth>
            </field>
          </fields>
        </register>
        <register>
          <name>DR</name>
          <addressOffset>0x20</addressOffset>
          <size>0x20</size>
          <fields>
            <field>
              <name>DATA</name>
              <bitOffset>0</bitOffset>
              <bitWidth>32</bitWidth>
            </field>
          </fields>
        </register>
        <register>
          <name>PSMKR</name>
          <addressOffset>0x24</addressOffset>
          <size>0x20</size>
          <fields>
            <field>
              <name>MASK</name>
              <bitOffset>0</bitOffset>
              <bitWidth>32</bitWidth>
            </field>
          </fields>
        </register>
        <register>
          <name>PSMAR</name>
          <addressOffset>0x28</addressOffset>
          <size>0x20</size>
          <fields>
            <field>
              <name>MATCH</name>
              <bitOffset>0</bitOffset>
              <bitWidth>32</bitWidth>
            </field>
          </fields>
        </register>
        <register>
          <name>PIR</name>
          <addressOffset>0x2c</addressOffset>
          <size>0x20</size>
          <fields>
            <field>
              <name>INTERVAL</name>
              <bitOffset>0</bitOffset>
              <bitWidth>16</bitWidth>
            </field>
          </fields>
        </register>
        <register>
          <name>LPTR</name>
          <addressOffset>0x30</addressOffset>
          <size>0x20</size>
          <fields>
            <field>
              <name>TIMEOUT</name>
              <bitOffset>0</bitOffset>
              <bitWidth>16</bitWidth>
            </field>
          </fields>
        </register>
      </registers>
    </peripheral>
    <peripheral>
      <name>DBGMCU</name>
      <baseAddress>0xe0042000</baseAddress>
      <registers>
        <register>
          <name>IDCODE</name>
          <addressOffset>0x0</addressOffset>
          <size>0x20</size>
          <fields>
            <field>
              <name>DEV_ID</name>
              <bitOffset>0</bitOffset>
              <bitWidth>12</bitWidth>
            </field>
            <field>
              <name>REV_ID</name>
              <bitOffset>16</bitOffset>
              <bitWidth>16</bitWidth>
            </field>
          </fields>
        </register>
        <register>
          <name>CR</name>
          <addressOffset>0x4</addressOffset>
          <size>0x20</size>
          <fields>
            <field>
              <name>DBG_SLEEP</name>
              <bitOffset>0</bitOffset>
              <bitWidth>1</bitWidth>
            </field>
            <field>
              <name>DBG_STOP</name>
              <bitOffset>1</bitOffset>
              <bitWidth>1</bitWidth>
            </field>
            <field>
              <name>DBG_STANDBY</name>
              <bitOffset>2</bitOffset>
              <bitWidth>1</bitWidth>
            </field>
            <field>
              <name>TRACE_IOEN</name>
              <bitOffset>5</bitOffset>
              <bitWidth>1</bitWidth>
            </field>
            <field>
              <name>TRACE_MODE</name>
              <bitOffset>6</bitOffset>
              <bitWidth>2</bitWidth>
            </field>
          </fields>
        </register>
        <register>
          <name>APB1FZR1</name>
          <addressOffset>0x8</addressOffset>
          <size>0x20</size>
          <fields>
            <field>
              <name>DBG_TIM2_STOP</name>
              <bitOffset>0</bitOffset>
              <bitWidth>1</bitWidth>
            </field>
            <field>
              <name>DBG_TIM3_STOP</name>
              <bitOffset>1</bitOffset>
              <bitWidth>1</bitWidth>
            </field>
            <field>
              <name>DBG_TIM4_STOP</name>
              <bitOffset>2</bitOffset>
              <bitWidth>1</bitWidth>
            </field>
            <field>
              <name>DBG_TIM6_STOP</name>
              <bitOffset>4</bitOffset>
              <bitWidth>1</bitWidth>
            </field>
            <field>
              <name>DBG_TIM7_STOP</name>
              <bitOffset>5</bitOffset>
              <bitWidth>1</bitWidth>
            </field>
            <field>
              <name>DBG_RTC_STOP</name>
              <bitOffset>10</bitOffset>
              <bitWidth>1</bitWidth>
            </field>
            <field>
              <name>DBG_WWDG_STOP</name>
              <bitOffset>11</bitOffset>
              <bitWidth>1</bitWidth>
            </field>
            <field>
              <name>DBG_IWDG_STOP</name>
              <bitOffset>12</bitOffset>
              <bitWidth>1</bitWidth>
            </field>
            <field>
              <name>DBG_I2C1_STOP</name>
              <bitOffset>21</bitOffset>
              <bitWidth>1</bitWidth>
            </field>
            <field>
              <name>DBG_I2C2_STOP</name>
              <bitOffset>22</bitOffset>
              <bitWidth>1</bitWidth>
            </field>
            <field>
              <name>DBG_I2C3_STOP</name>
              <bitOffset>30</bitOffset>
              <bitWidth>1</bitWidth>
            </field>
            <field>
              <name>DBG_LPTIM1_STOP</name>
              <bitOffset>31</bitOffset>
              <bitWidth>1</bitWidth>
            </field>
          </fields>
        </register>
        <register>
          <name>APB1FZR2</name>
          <addressOffset>0xc</addressOffset>
          <size>0x20</size>
          <fields>
            <field>
              <name>DBG_I2C4_STOP</name>
              <bitOffset>1</bitOffset>
              <bitWidth>1</bitWidth>
            </field>
          </fields>
        </register>
        <register>
          <name>APB2FZ</name>
          <addressOffset>0x10</addressOffset>
          <size>0x20</size>
          <fields>
            <field>
              <name>DBG_TIM1_STOP</name>
              <bitOffset>11</bitOffset>
              <bitWidth>1</bitWidth>
            </field>
            <field>
              <name>DBG_TIM8_STOP</name>
              <bitOffset>13</bitOffset>
              <bitWidth>1</bitWidth>
            </field>
            <field>
              <name>DBG_TIM15_STOP</name>
              <bitOffset>16</bitOffset>
              <bitWidth>1</bitWidth>
            </field>
            <field>
              <name>DBG_TIM16_STOP</name>
              <bitOffset>17</bitOffset>
              <bitWidth>1</bitWidth>
            </field>
            <field>
              <name>DBG_TIM17_STOP</name>
              <bitOffset>18</bitOffset>
              <bitWidth>1</bitWidth>
            </field>
            <field>
              <name>DBG_TIM20_STOP</name>
              <bitOffset>20</bitOffset>
              <bitWidth>1</bitWidth>
            </field>
          </fields>
        </register>
      </registers>
    </peripheral>
  </peripherals>
</device>
